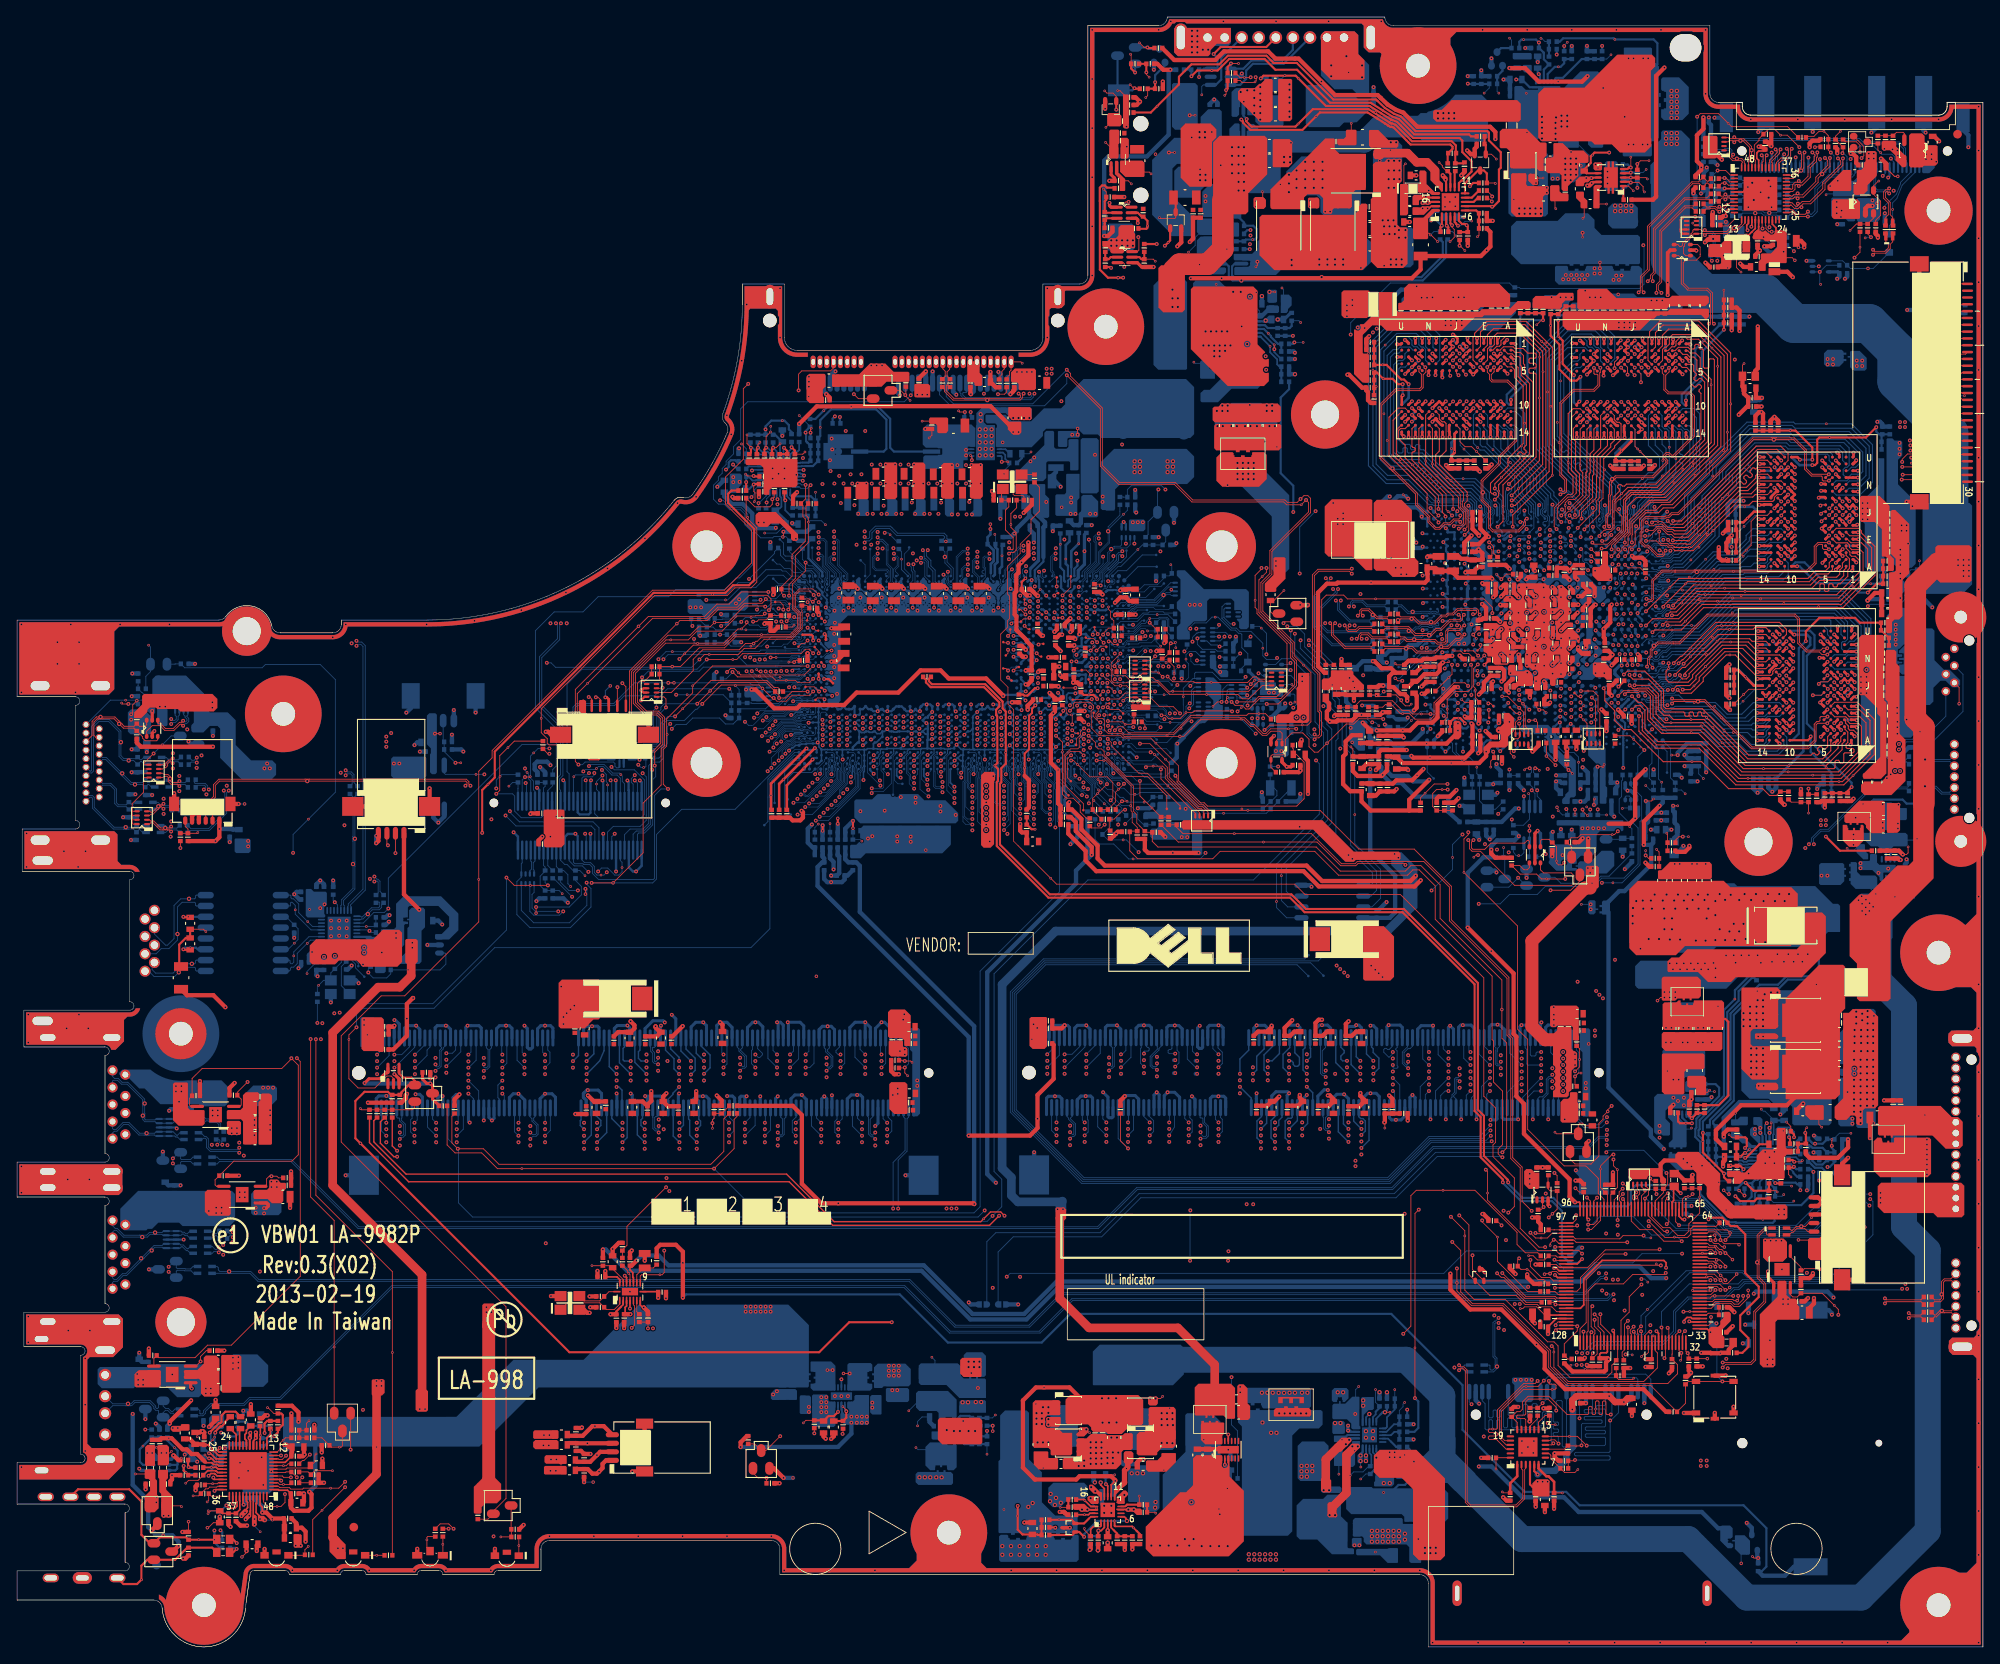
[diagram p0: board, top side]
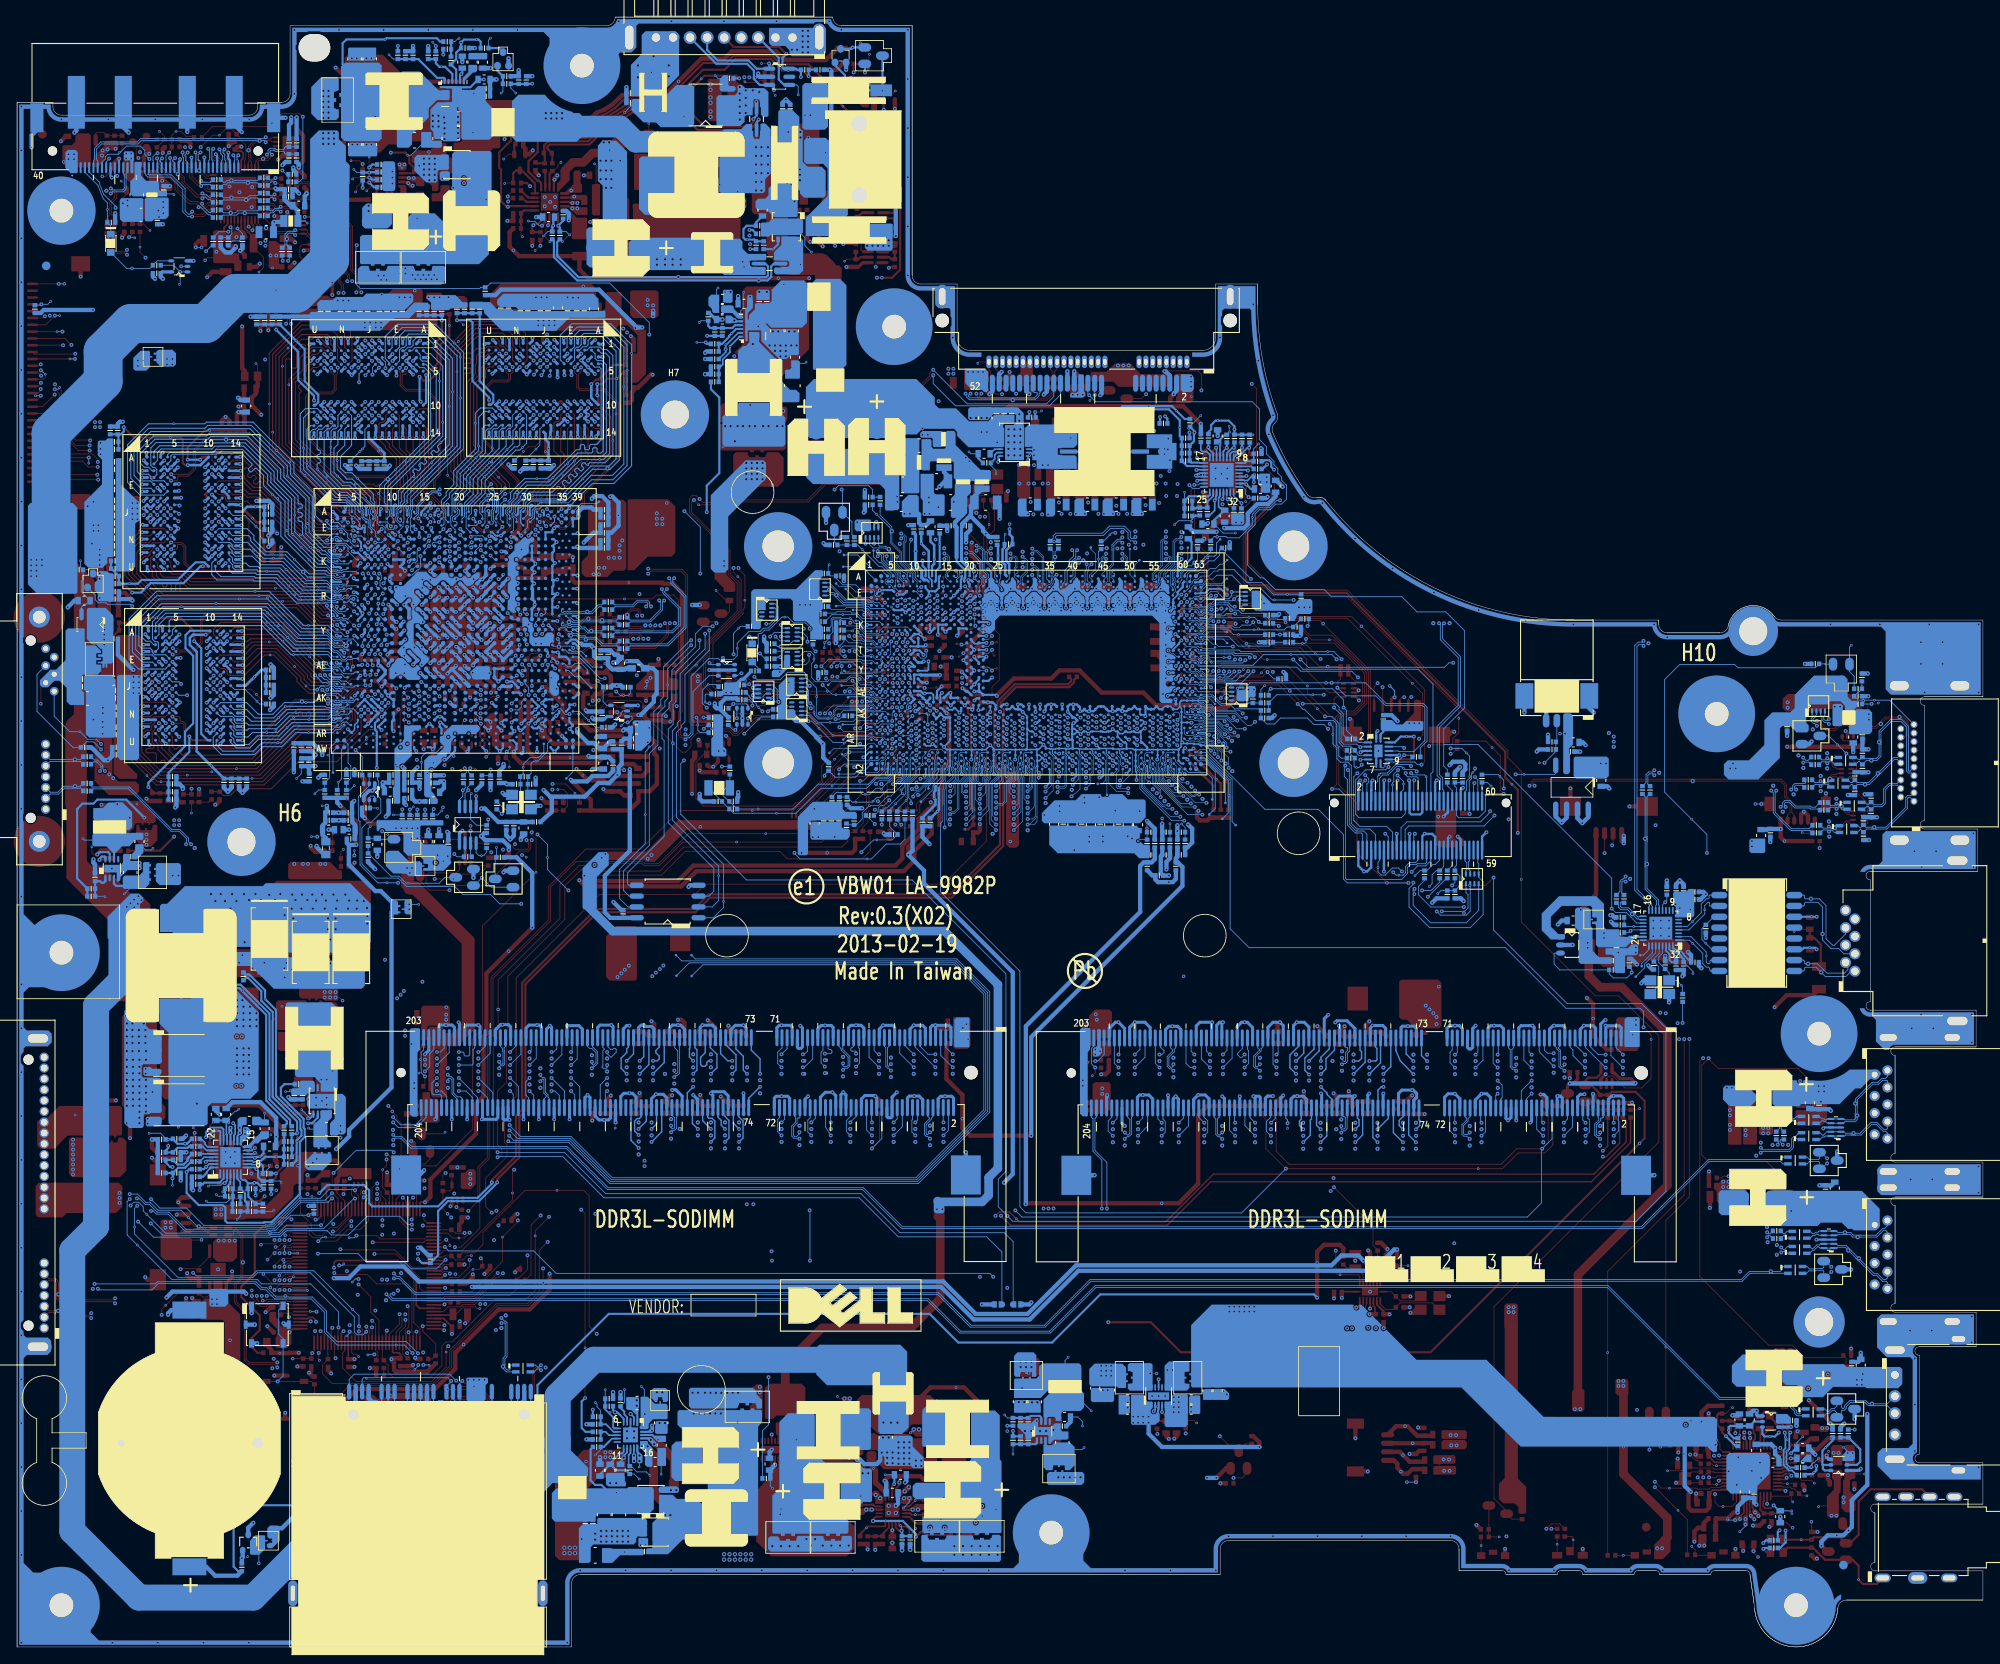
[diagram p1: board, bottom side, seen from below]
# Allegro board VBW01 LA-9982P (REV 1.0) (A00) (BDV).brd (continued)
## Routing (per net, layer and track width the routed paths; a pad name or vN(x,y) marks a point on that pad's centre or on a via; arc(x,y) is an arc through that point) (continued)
CASB0#: length 37.9
  TOP w0.102: UV7.G3 213.14,131.93 v1(213.14,131.93)
  IN3 w0.102: v1(213.14,131.93) 213.38,131.93 214.66,130.65 214.66,127.33 214.09,126.75 214.09,125.95 ; v1(188.31,121.12) 188.78,121.59 190.09,121.59 190.31,121.37 190.31,121.19 190.54,120.96 191.17,120.96 191.45,121.24 192.76,121.24 193.17,121.65 194.21,121.65 194.39,121.83
  IN3 w0.157: 214.09,125.95 211.17,123.04 202.11,123.04 200.98,121.91 194.47,121.91 194.39,121.83
  BOTTOM w0.102: UV1.W10 187.49,120.49 188.12,121.12 v1(188.31,121.12) ; v1(213.14,131.93) 213.56,131.51 UV7.G3
CASB1#: length 35
  TOP w0.102: v1(212.95,111.53) 213.37,111.11 UV9.G3
  IN3 w0.102: v1(187.7,117.47) 187.7,118.34 188.5,119.14 190.24,119.14 190.45,118.93 191.05,118.93 191.93,118.05 193.13,118.05 193.33,118.25 194.39,118.25 ; v1(212.95,111.53) 212.58,111.9 211.97,111.9 211.8,112.06 211.8,112.9 210,114.7 210,116.98 209.22,117.76 209.22,118.37 208.09,119.49 203.47,119.49
  IN3 w0.157: 194.39,118.25 202.23,118.25 203.47,119.49
  BOTTOM w0.102: v1(187.7,117.47) 187.66,117.52 187.66,117.7 UV1.AA10 ; v1(212.95,111.53) 213.37,111.11 UV9.G3
CE_EN: length 178.4
  TOP w0.102: UE1.17 189.59,36.85 v1(189.47,36.97) ; RX18.1 210.75,175.88 v1(210.71,175.84)
  IN2 w0.127: v1(216.31,51.74) 216.77,52.2 216.77,53.56 222.15,58.94 222.15,71.62 228.05,77.51 228.05,85.64 225.06,88.63 225.06,96.24 225.6,96.78 225.6,109.42 224.18,110.84 224.18,121.01 225.08,121.91 225.08,145.93 216.03,154.98 216.03,164.75 214.41,166.37 214.41,175.33 213.9,175.84 v1(210.71,175.84)
  BOTTOM w0.102: v1(216.31,51.74) 216.63,51.42 v3(216.63,49.22) 216.63,48.42 211.5,43.29 202.78,43.29 202.2,43.88 196.04,43.88 190.88,38.72 190.88,36.93 190.54,36.6 189.84,36.6 v1(189.47,36.97)
CE_EN_R: length 7.2
  TOP w0.102: v1(212.58,175.21) 212.27,175.51 RX18.2 RX20.1 212.27,177.2 v3(211.76,177.71) 211.19,177.71 210.59,177.11 209.78,177.11 RX53.2
  BOTTOM w0.102: v1(212.58,175.21) 212.95,174.83 JLVDS.18
CFD_PWRBTN#_XDP: length 5.2
  BOTTOM w0.102: v3(64.88,89.16) 64.55,89.49 64.55,90.54 64.06,91.03 RC49.2 63.2,91.5 JXDP1.41
CFG0: length 38.1
  IN3 w0.127: v1(76.55,108.23) 77.37,108.23 78.52,109.38 81.15,109.38 82.3,110.54 89.16,110.54 90.48,111.86 v1(90.48,112.52)
  BOTTOM w0.076: UC1.AC60 93.31,112.81 92.83,112.81 92.79,112.84 92,112.84 91.84,112.68 91.46,112.68 91.22,112.91 90.87,112.91 v1(90.48,112.52)
  BOTTOM w0.102: JXDP1.9 71.2,95.25 71.85,95.9 73.36,95.9 74.03,96.57 74.03,103.35 74.43,103.74 75.3,103.74 75.72,104.17 75.72,105.42 76.19,105.89 v3(76.19,106.99) 76.19,107.87 v1(76.55,108.23)
CFG1: length 48.4
  IN3 w0.127: v1(85.5,114.4) 85.37,114.27 84.41,114.27 82.7,112.56 79.12,112.56 77.78,111.22 75.41,111.22 73.15,108.96 73.15,108.16 71.86,106.87 71.86,102.9 71.11,102.14 71.11,99.78 68.17,96.85 68.17,91 v1(68.1,90.93)
  BOTTOM w0.076: UC1.AC62 92.06,113.14 91.77,112.84 91.53,112.84 91.29,113.08 90.46,113.08 90.41,113.03 88.91,113.03
  BOTTOM w0.102: JXDP1.11 70.7,92.21 70.9,92 v3(70.9,91.38) 70.9,90.89 70.51,90.5 70.06,90.5 69.23,91.32 68.5,91.32 v1(68.1,90.93) ; v1(85.5,114.4) 85.53,114.4 86.9,113.03 88.91,113.03
CFG2: length 38.3
  IN3 w0.127: v1(86.11,114.41) 85.66,113.97 84.48,113.97 82.82,112.3 79.23,112.3 77.88,110.95 75.75,110.95 75.37,110.56 75.37,109.89 74.71,109.23 74.01,109.23 73.41,108.63 73.41,108.05 72.13,106.76 72.13,102.79 71.97,102.63 71.97,100.28 70.05,98.35 v1(70.05,95.34)
  BOTTOM w0.076: UC1.AC63 91.54,113.25 90.05,113.25 90.04,113.24 89.11,113.24 89.1,113.25 88.93,113.25 88.91,113.26
  BOTTOM w0.102: v1(86.11,114.41) 86.12,114.41 86.71,113.83 v3(86.99,113.83) 87.56,113.26 88.91,113.26 ; JXDP1.15 69.7,95 v1(70.05,95.34)
CFG3: length 61.6
  IN1 w0.127: v1(56.16,100.66) 56.35,100.85 59.85,100.85 60.78,101.78 63.43,101.78 63.9,102.25 65.37,102.25 66.83,103.71 71.32,103.71 72.21,102.82 72.94,102.82 v1(73.32,102.44)
  IN3 w0.127: v1(73.32,102.44) 73.49,102.62 73.49,103.6 74.11,104.22 74.11,107.19 77.09,110.17 78.21,110.17 79.39,111.35 83.9,111.35 85.44,112.89 86.94,112.89 88.32,114.27 v1(88.32,114.37)
  BOTTOM w0.076: UC1.AA63 91.52,113.76 91.39,113.76 91.37,113.74 89.87,113.74 89.62,113.99 89.04,113.99
  BOTTOM w0.102: 89.04,113.99 89.02,113.99 88.94,113.99 88.91,113.97 88.91,113.97 88.72,113.97 v1(88.32,114.37) ; JXDP1.17 69.2,95.54 69.88,96.21 73.03,96.21 73.74,96.92 73.74,97.53 73.75,97.54 73.75,102.01 v1(73.32,102.44) ; RC56.2 56.8,102.27 v3(56.61,102.08) 56.16,101.64 v1(56.16,100.66)
CFG3_R: length 3.5
  BOTTOM w0.102: JXDP1.60 58.7,100.65 58.71,100.66 RC56.1 58.07,101.36 v3(57.65,100.93)
CFG4: length 44
  TOP w0.089: v1(93.3,113.51) 92.85,113.06 91.5,113.06 91.22,113.33 v3(90.15,113.33) 88.91,113.33
  TOP w0.102: v1(83.85,114.31) 83.87,114.31 84.45,113.73 88.51,113.73 88.91,113.33
  IN3 w0.127: v1(66.57,95.34) 66.57,95.99 70.58,100 70.58,102.35 71.34,103.11 71.34,107.09 71.49,107.24 71.49,108.17 73.24,109.92 73.39,109.92 75.26,111.78 76.41,111.78 77.45,112.83 82.36,112.83 v1(83.85,114.31)
  BOTTOM w0.089: UC1.AA60 93.6,113.81 v1(93.3,113.51)
  BOTTOM w0.102: RC138.1 83.1,113.5 83.85,114.25 v1(83.85,114.31) ; v1(66.57,95.34) 66.7,95.22 JXDP1.27
CFG5: length 44.9
  IN3 w0.127: v1(69.12,90.84) 69.76,91.48 69.76,93.21 70.96,94.41 70.96,98.53 74.01,101.58 74.01,103.41 74.64,104.03 74.64,106.92 76.38,108.66 77.43,108.66 78.41,109.65 81.04,109.65 82.18,110.79 86.57,110.79 v1(90.21,114.43)
  BOTTOM w0.076: UC1.Y62 92.06,114.63 91.77,114.34 91.46,114.34 91.19,114.07 90.5,114.07 90.21,114.37 v1(90.21,114.43)
  BOTTOM w0.102: v1(69.12,90.84) 68.78,90.5 v3(68.44,90.5) 67.95,90.5 67.66,90.8 67.66,91.51 67.21,91.96 66.51,91.96 66.2,92.27 JXDP1.29
CFG6: length 52.6
  TOP w0.089: v1(92.65,115.01) 88.91,115.01
  TOP w0.102: v1(76.29,100.59) 75.73,101.15 75.73,105.23 76.13,105.63 76.13,108.82 79.18,111.86 v3(79.18,112.69) 81.5,115.01 88.91,115.01
  BOTTOM w0.076: UC1.Y61 92.95,114.71 v1(92.65,115.01)
  BOTTOM w0.102: JXDP1.33 65.2,92.01 65.38,91.83 66.32,91.83 66.42,91.73 67.12,91.73 67.43,91.42 67.43,90.7 68.14,89.99 74.58,89.99 74.72,90.13 74.72,99.85 75.47,100.59 v1(76.29,100.59)
CFG7: length 47.7
  IN3 w0.127: v1(89.56,114.43) 89.56,114.37 86.26,111.07 79.48,111.07 78.32,109.91 77.21,109.91 74.37,107.07 74.37,104.13 73.75,103.5 73.75,101.69 70.64,98.58 70.64,94.46 68.55,92.36 68.55,90.75 68.23,90.43 67.21,90.43 66.96,90.69 v1(66.96,90.88)
  BOTTOM w0.076: UC1.Y60 93.31,114.3 92.83,114.3 92.79,114.34 92,114.34 91.84,114.18 91.53,114.18 91.26,113.91 90.02,113.91 89.56,114.37 v1(89.56,114.43)
  BOTTOM w0.102: JXDP1.35 64.7,92.18 65.31,91.58 66.25,91.58 66.95,90.88 v1(66.96,90.88)
CFG8: length 40.4
  IN3 w0.127: v1(67.03,103.29) 67.41,103.67 67.41,106.13 68.19,106.9 68.19,108.82 73.04,113.68 v1(73.24,113.68)
  BOTTOM w0.076: 89.1,114.88 89.6,114.88 89.65,114.93 91.84,114.93 UC1.V62
  BOTTOM w0.102: JXDP1.10 71.2,101.21 70.93,101.48 70.93,102.11 v3(70.76,102.28) 70.58,102.46 69.81,102.46 68.81,103.46 67.2,103.46 v1(67.03,103.29) ; v1(73.24,113.68) 73.97,114.4 79.94,114.4 80.42,114.88 89.1,114.88
CFG9: length 43.9
  IN3 w0.127: v1(66.37,102.65) 66.61,102.89 66.61,103.62 67.15,104.17 67.15,106.24 67.92,107.01 67.92,109.02 74.29,115.39 75.34,115.39 75.75,115.8 v1(75.75,115.8)
  BOTTOM w0.076: 89.3,115.11 89.31,115.09 91.77,115.09 91.94,115.26 91.94,115.44 92.18,115.68 92.7,115.68 UC1.V61
  BOTTOM w0.102: 89.3,115.11 85.55,115.11 84.31,116.34 76.29,116.34 v1(75.75,115.8) ; JXDP1.12 70.7,101.86 70.33,102.23 69.71,102.23 68.71,103.23 68.14,103.23 v3(67.9,102.99) 67.79,102.88 66.59,102.88 v1(66.37,102.65)
CFG10: length 35.9
  TOP w0.089: 88.91,113.96 92.25,113.96 v1(93.3,115.01)
  TOP w0.102: 88.91,113.96 84.82,113.96 v3(84.57,114.22) 84.06,114.72 83.62,114.72 v1(83.21,114.31)
  IN3 w0.127: v1(83.21,114.31) 81.99,113.09 77.34,113.09 76.3,112.04 75.16,112.04 73.29,110.17 73.13,110.17 70.16,107.2 70.16,103.08 69.57,102.48 v1(69.57,101.61)
  BOTTOM w0.076: v1(93.3,115.01) 93.6,115.31 UC1.V60
  BOTTOM w0.102: v1(69.57,101.61) 69.7,101.48 JXDP1.16
CFG11: length 38.1
  IN3 w0.127: v1(68.55,102.82) 68.55,103.03 69.38,103.86 69.38,107.88 70.18,108.68 70.18,109.7 72.18,111.71 73.35,111.71 76.19,114.55 81.19,114.55 81.92,115.29 84.87,115.29 84.95,115.36 86.09,115.36 v1(86.44,115.71)
  BOTTOM w0.076: UC1.U60 93.31,115.8 92.83,115.8 92.79,115.84 92,115.84 91.84,115.68 91.46,115.68 91.25,115.89 90.93,115.89 90.4,115.36 89.3,115.36
  BOTTOM w0.102: v1(68.55,102.82) 68.55,102.82 69.05,102.31 69.05,101.45 69.2,101.3 v3(69.2,101.07) JXDP1.18 ; 89.3,115.36 86.79,115.36 v1(86.44,115.71)
CFG12: length 38.2
  IN3 w0.127: v1(66.64,101.61) 66.64,101.78 65.94,102.48 65.94,103.01 66.23,103.29 66.23,103.61 66.89,104.28 66.89,106.34 67.66,107.12 67.66,109.13 74.35,115.81 v1(75.17,115.81)
  BOTTOM w0.076: UC1.T63 90.09,116.88
  BOTTOM w0.089: 90.09,116.88 88.91,116.88
  BOTTOM w0.102: JXDP1.28 66.7,101.55 v1(66.64,101.61) ; v1(75.17,115.81) 76.06,116.7 v3(76.8,116.7) 86.98,116.7 87.17,116.88 88.91,116.88
CFG13: length 38.1
  IN3 w0.127: v1(85.92,116.01) 85.53,115.62 84.84,115.62 84.76,115.55 81.81,115.55 81.08,114.81 75.34,114.81 73.41,112.88 72.99,112.88 69.75,109.65 69.75,108.62 69.11,107.99 69.11,103.99 67.65,102.53 v1(67.65,102.47)
  BOTTOM w0.076: 89.22,116.42 91.84,116.42 91.85,116.44 91.85,116.44 UC1.T62
  BOTTOM w0.089: 88.91,116.43 89.22,116.43
  BOTTOM w0.102: v1(85.92,116.01) 86.13,116.22 87.76,116.22 87.96,116.43 88.91,116.43 ; JXDP1.30 66.2,101.86 66.36,102.02 67.42,102.02 67.65,102.25 v1(67.65,102.47)
CFG14: length 40
  IN3 w0.127: v1(67.03,102.47) 67.03,102.53 68.85,104.35 68.85,108.09 69.49,108.73 69.49,109.76 72.88,113.14 73.31,113.14 75.24,115.07 80.97,115.07 81.71,115.81 84.65,115.81 84.89,116.05 v1(85.32,116.05)
  BOTTOM w0.076: UC1.T61 92.7,117.17 92.18,117.17 91.94,116.94 91.94,116.76 91.77,116.59 90.75,116.59 90.69,116.65 90.07,116.65
  BOTTOM w0.089: 88.91,116.65 90.07,116.65
  BOTTOM w0.102: JXDP1.34 65.2,101.99 65.25,102.04 ; v1(67.03,102.47) 66.81,102.25 65.46,102.25 65.25,102.04 ; 65.25,102.04 v3(65.25,102.04) ; v1(85.32,116.05) 85.74,116.46 87.62,116.46 87.81,116.65 88.91,116.65
CFG15: length 45.1
  TOP w0.089: v1(93.3,116.51) 92.83,116.98 92.39,116.98 91.87,116.46 88.91,116.46
  TOP w0.102: 88.91,116.46 85.03,116.46 84.35,115.78 84.16,115.78 84.16,115.78 83.89,115.78 v3(83.88,115.78) v1(80.83,115.78)
  BOTTOM w0.076: UC1.T60 93.6,116.81 v1(93.3,116.51)
  BOTTOM w0.102: v1(80.83,115.78) 79.68,114.63 66.2,114.63 64.46,112.89 64.46,102.62 64.7,102.37 JXDP1.36
CFG16: length 32.4
  TOP w0.102: v1(87.15,114.37) 86.9,114.37 v3(86.68,114.59)
  IN3 w0.127: v1(72.4,102.22) 72.4,102.52 72.39,102.53 72.39,106.29 75.63,109.53 75.63,110.47 75.85,110.69 77.99,110.69 79.21,111.91 83.7,111.91 85.2,113.41 86.25,113.41 87.15,114.31 v1(87.15,114.37)
  BOTTOM w0.076: 88.91,113.5 89.11,113.5 89.19,113.41 89.27,113.41 89.28,113.4 89.95,113.4 89.96,113.41 91.51,113.41 91.53,113.43 91.84,113.43 92.24,113.83 92.24,113.83 UC1.AA62
  BOTTOM w0.102: v1(87.15,114.37) 87.15,114.31 87.96,113.5 88.02,113.5 88.03,113.5 88.91,113.5 ; JXDP1.6 72.2,101.17 71.99,101.38 71.99,101.81 v1(72.4,102.22)
CFG17: length 31.7
  IN3 w0.127: v1(72.4,101.6) 72.82,102.02 72.82,102.66 73.23,103.07 73.23,103.7 73.69,104.16 73.69,107.16 76.96,110.43 78.1,110.43 79.28,111.61 83.77,111.61 85.31,113.15 86.56,113.15 87.74,114.32 v1(87.74,114.37)
  BOTTOM w0.076: UC1.AA61 92.7,114.18 92.18,114.18 92.01,114.01 92.01,113.83 91.77,113.59 91.46,113.59 91.44,113.58 89.74,113.58 89.62,113.69 v3(89.42,113.69) 88.95,113.69 88.91,113.73
  BOTTOM w0.102: 88.91,113.73 88.36,113.73 87.74,114.36 87.74,114.37 v1(87.74,114.37) ; v1(72.4,101.6) 72.7,101.29 JXDP1.4
CFG18: length 46.8
  TOP w0.089: v3(88.95,116.01) 88.91,116.01
  TOP w0.102: 88.91,116.01 v1(88.32,116.01)
  IN3 w0.127: v1(69.66,103.18) 69.9,103.41 69.9,107.3 73.03,110.42 73.18,110.42 74.73,111.98 74.73,112.35 75.89,113.51 81.78,113.51 83.03,114.76 85.09,114.76 85.16,114.84 86.51,114.84 86.76,115.09 87.56,115.09 88.32,115.85 v1(88.32,116.01)
  BOTTOM w0.076: 88.91,116.01 90.59,116.01 90.79,116.22 91.56,116.22 UC1.U63
  BOTTOM w0.102: v1(69.66,103.18) 70,102.84 72.34,102.84 73.52,101.67 73.52,97.63 73.12,97.23 68.16,97.23 67.7,97.69 JXDP1.24 ; v1(88.32,116.01) 88.91,116.01
CFG19: length 36.5
  IN3 w0.127: v1(68.61,102.18) 68.61,102.18 68.97,102.54 68.97,103.08 69.64,103.75 69.64,107.77 70.44,108.57 70.44,109.6 72.29,111.45 73.47,111.45 76.31,114.29 81.3,114.29 82.03,115.02 84.98,115.02 85.05,115.1 86.42,115.1 86.66,115.34 87.2,115.34 v1(87.65,115.78)
  BOTTOM w0.076: 89.62,115.59 90.4,115.59 90.86,116.05 91.32,116.05 91.53,115.84 91.77,115.84 92.06,116.13 UC1.U62
  BOTTOM w0.102: v1(87.65,115.78) 87.84,115.59 89.62,115.59 ; v1(68.61,102.18) 67.91,101.47 v3(67.91,101.17) 67.91,100.54 68.2,100.25 JXDP1.22
CFG_RCOMP: length 2
  TOP w0.089: v3(90.45,115.47) v1(91.07,115.47) 91.27,115.66 RC132.1
  BOTTOM w0.089: UC1.V63 91.16,115.38 v1(91.07,115.47)
CHG_B+:
  vias: v2(149.38,162.63) v2(149.38,162) v2(152.62,162.7) v2(152.62,162.06) v2(153.57,162.7) v2(153.57,162.06) v2(154.46,162.7) v2(154.46,162.06) v2(155.41,162.7) v2(155.41,162.06) v4(157.49,161.69)
CKEA0: length 35.6
  TOP w0.102: UV5.J3 v1(168.28,150.85)
  IN3 w0.102: v1(177.26,127.58) 177.8,128.13 177.8,130.47 177.52,130.75 177.52,131.72 177.73,131.92 177.73,134.85 178.06,135.18 178.06,135.39 ; 172.73,152.06 171.89,151.22 170.91,151.22 170.13,150.45 169.7,150.45 169.68,150.47 168.67,150.47 v1(168.28,150.85)
  IN3 w0.157: 178.06,135.39 178.06,148.86 175.46,151.46 174.66,151.46 174.06,152.06 172.73,152.06
  BOTTOM w0.102: UV5.J3 v1(168.28,150.85) ; UV1.K21 177.35,127.49 v1(177.26,127.58)
CKEA1: length 32.3
  TOP w0.102: UV3.J3 189.19,151.18 v1(188.79,150.79)
  IN3 w0.102: 179.75,135.39 179.75,135.25 179.74,135.24 179.74,135.18 179.45,134.9 179.39,134.9 178.98,134.48 178.98,133.59 178.84,133.45 178.84,130.07 178.72,129.95 178.51,129.95 178.21,129.65 178.21,129.13 v1(178.59,128.74) ; v1(188.79,150.79) 188.38,151.2 183.29,151.2 182.13,150.04
  IN3 w0.157: 182.13,150.04 179.75,147.66 179.75,135.39
  BOTTOM w0.102: UV1.J20 179.05,128.29 v1(178.59,128.74) ; v1(188.79,150.79) 189.19,151.18 UV3.J3
CKEB0: length 37.9
  TOP w0.102: UV7.J3 v1(213.16,133.51)
  IN3 w0.102: 213.58,126.14 213.58,127.75 213.58,127.75 213.58,128.07 213.58,128.07 213.58,128.55 213.58,128.55 213.58,130.9 212.69,131.79 212.69,132.17 212.78,132.26 212.78,133.13 v1(213.16,133.51) ; 191.23,121.8 190.75,121.8 190.74,121.8 188.17,121.8 v1(187.48,121.11)
  IN3 w0.157: 213.58,126.14 211.17,123.73 202.11,123.73 200.9,122.52 191.95,122.52 191.23,121.8
  BOTTOM w0.102: v1(187.48,121.11) 187.26,121.32 UV1.U10 ; UV7.J3 v1(213.16,133.51)
CKEB1: length 35.2
  TOP w0.102: UV9.J3 213.37,112.71 v1(212.97,113.11)
  IN3 w0.102: v1(212.97,113.11) 212.45,113.11 210.66,114.9 210.66,119.57 210.45,119.78 ; 194.39,119.72 194.06,119.72 193.61,120.17 193.08,120.17 193.06,120.19 193.06,120.19 192.89,120.36 191.72,120.36 191.5,120.15 190.48,120.15 190.48,120.15 188.97,120.15 188.75,119.93 188.75,119.71 187.73,118.69 v1(187.08,118.69)
  IN3 w0.157: 194.39,119.72 201.59,119.72 202.86,120.98 209.25,120.98 210.45,119.78
  BOTTOM w0.102: UV9.J3 213.37,112.71 v1(212.97,113.11) ; UV1.AA11 v1(187.08,118.69)
CLK_BIASREF: length 5.7
  BOTTOM w0.089: UC1.C26 115,124.18 115.11,124.29 115.12,124.29 115.3,124.46 115.3,124.47 115.33,124.51 115.33,124.68 115.27,124.74 115.27,125.13 115.16,125.24 115.16,125.89 115.18,125.9
  BOTTOM w0.305: 115.18,125.9 115.18,126.42 115.43,126.68 v3(115.43,127.94) 115.43,129.12 RC13.1
CLK_CPU_ITP: length 3.7
  BOTTOM w0.089: UC1.A35 109.47,125.61 109.47,126.37 108.74,127.1 v2(108.74,127.8) 108.74,128.39 RC139.2
CLK_CPU_ITP#: length 4.4
  BOTTOM w0.089: RC140.2 108.99,128.46 108.99,127.2 109.72,126.48 109.72,125.21 UC1.B35
CLK_PCI_LPC: length 110.1
  TOP w0.089: v1(127.46,96.42) 127.07,96.02 125.94,96.02 R2336.1
  TOP w0.102: UE1.12 187.59,33.78 R2354.2 187.42,33.54 186.91,33.03 186.91,32.21 186.31,31.61 182,31.61 180.61,32.99 180.61,35.29 180.13,35.77 179.38,35.77 174.43,40.73 170.78,40.73 169.68,41.83 v3(169.68,48.19) 169.68,48.8 v1(168.05,50.43)
  IN1 w0.084: 130.78,95.3 130.6,95.48 130.19,95.48 129.45,96.21 129.45,96.6 129.26,96.79 127.83,96.79 v1(127.46,96.42)
  IN1 w0.127: v1(168.05,50.43) 168.05,51 168.42,51.37 168.42,69.8 167.91,70.31 157.51,70.31 153.71,74.1 151.97,74.1 130.78,95.3
CLK_PCIE_LAN: length 112.3
  IN1 w0.127: v1(39.78,117.38) 39.98,117.57 41.53,117.57 42.63,118.68 59.87,118.68 60.32,119.14 66.36,119.14 79.48,132.26 91.23,132.26 91.71,132.74 95.6,132.74 97.5,130.84 97.5,128.47 99.32,126.65 103.46,126.65 104.27,127.46 104.51,127.46 104.64,127.33 104.64,127.12 v1(104.47,126.95)
  BOTTOM w0.089: UC1.B42 104.99,124.56 104.99,124.3 104.93,124.23 104.86,124.23 104.58,124.51 104.58,124.62 104.98,125.03 104.98,126.02 104.8,126.19 104.8,126.61 v1(104.47,126.95)
  BOTTOM w0.102: v1(39.78,117.38) 39.95,117.55 40.29,117.55 40.54,117.3 40.54,88.84 38.81,87.12 38.81,86.88 38.75,86.82 UL1.15
CLK_PCIE_LAN#: length 112.4
  IN1 w0.127: v1(39.78,117.96) 39.84,117.9 41.39,117.9 42.5,119.01 59.73,119.01 60.19,119.47 66.22,119.47 79.34,132.59 91.09,132.59 91.57,133.07 95.74,133.07 97.83,130.97 97.83,128.61 99.45,126.99 103.33,126.99 104.14,127.79 104.65,127.79 104.99,127.45 104.99,127 v1(105.05,126.95)
  BOTTOM w0.089: v1(105.05,126.95) 105.06,126.94 105.06,126.3 105.24,126.12 105.24,124.74 105.27,124.71 105.27,124.53 UC1.C41
  BOTTOM w0.102: UL1.16 39.15,86.82 39.08,86.88 39.08,87.01 40.81,88.73 40.81,117.41 40.4,117.82 39.93,117.82 v1(39.78,117.96)
CLK_PCIE_WLAN: length 55.2
  IN3 w0.114: JMINI.13 98.1,149.64 97.81,149.35 97.81,148.63 98.36,148.08 113.32,148.08 114.31,147.08 114.31,146.73 116.22,144.82 119.13,144.82 119.88,144.07 119.88,139.15 113.98,133.24 113.98,131.73 111.46,129.21 106.79,129.21 106.51,128.93 106.51,128.84 106.74,128.61 v1(106.74,128.6)
  BOTTOM w0.102: v1(106.74,128.6) 106.58,128.44 106.58,127.98 106.59,127.97 106.59,127.89 107.1,127.39 107.1,126.75 107.6,126.25 107.6,124.92 107.85,124.66 107.85,124.45 UC1.C37
CLK_PCIE_WLAN#: length 54.8
  IN3 w0.114: JMINI.11 97.3,149.78 97.56,149.52 97.56,148.52 98.25,147.82 113.21,147.82 114.06,146.98 114.06,146.62 116.11,144.57 119.03,144.57 119.63,143.97 119.63,139.25 113.73,133.35 113.73,131.84 111.35,129.46 106.68,129.46 106.25,129.03 106.25,128.7 v1(106.16,128.6)
  BOTTOM w0.102: UC1.B38 107.33,124.73 107.33,126.14 106.83,126.64 106.83,127.28 106.47,127.64 106.32,127.64 106.32,127.86 106.32,127.87 106.32,128.44 v1(106.16,128.6)
CLK_PEG_VGA: length 74
  IN1 w0.127: v1(167.03,118.18) 166.99,118.14 161.49,118.14 156.46,123.17 153.97,123.17 144.36,132.78 138.94,132.78 136.98,130.82 129.17,130.82 127.93,132.05 118.54,132.05 118.1,131.61 115.74,131.61 114.28,130.15 110.64,130.15 109.34,128.84 108.18,128.84 106.5,127.16 105.99,127.16 v1(105.94,127.12)
  BOTTOM w0.089: UC1.B39 106.91,124.98 106.39,125.51 106.39,127.1 106.29,127.2 106.02,127.2 v1(105.94,127.12)
  BOTTOM w0.102: UV1.AB35 166.86,118.01 v1(167.03,118.18)
CLK_PEG_VGA#: length 73.9
  IN1 w0.127: v1(105.94,127.7) 106.15,127.49 106.37,127.49 108.04,129.17 109.2,129.17 110.51,130.48 114.14,130.48 115.6,131.94 117.96,131.94 118.41,132.38 128.07,132.38 129.3,131.15 136.85,131.15 138.8,133.11 144.5,133.11 154.11,123.5 156.6,123.5 161.63,118.47 166.63,118.47 v1(166.9,118.75)
  BOTTOM w0.089: v1(105.94,127.7) 106.19,127.46 106.39,127.46 106.65,127.2 106.65,125.61 106.7,125.56 UC1.A39
  BOTTOM w0.102: v1(166.9,118.75) 166.65,118.49 UV1.AA36
CLK_SMB: length 15
  TOP w0.102: v1(141.7,182.54) 141.7,182.07 v3(141.54,181.92)
  TOP w0.254: v1(141.7,182.54) 141.88,182.72 PR18.1
  BOTTOM w0.254: PBATT.7 151.52,188.7 148.44,185.62 144.84,185.62 144.05,184.83 144.05,183.84 143.35,183.15 PD1.3 141.95,183.15 141.7,182.89 v1(141.7,182.54)
CLK_X1: length 8.3
  TOP w0.102: UG1.1 70.63,40.2 70.01,39.57 69.07,39.57 CG8.1 68.29,40.35 64.51,40.35 YG1.1
CLK_X2: length 5.1
  TOP w0.102: UG1.16 69.37,41.65 CG9.1 68.29,40.57 66.46,40.57 YG1.3
CLK_XDP: length 78.6
  IN1 w0.127: v1(63.74,120.03) 63.59,120.18 63.59,120.44 63.82,120.66 66.51,120.66 78.96,133.11 90.89,133.11 91.47,133.68 95.85,133.68 98.38,131.15 98.38,130.01 98.68,129.7 99.13,129.7 v1(99.34,129.49)
  BOTTOM w0.102: JXDP1.40 63.7,100.43 63.58,100.55 63.58,101.78 63.97,102.16 63.97,107.94 61.5,110.41 61.5,116 63.59,118.1 63.59,119.87 v1(63.74,120.03) ; RC139.1 108.71,130.04 108.71,130.16 108.55,130.31 103.09,130.31 102.26,131.14 100.7,131.14 100.19,130.64 100.19,129.98 99.89,129.68 99.52,129.68 v1(99.34,129.49)
CLK_XDP#: length 79.6
  IN1 w0.127: v1(99.34,130.14) 99.23,130.03 98.82,130.03 98.71,130.14 98.71,131.29 95.99,134.01 91.33,134.01 90.76,133.44 78.82,133.44 66.37,120.99 63.68,120.99 63.26,120.57 63.26,120.13 v1(63.16,120.03)
  BOTTOM w0.102: v1(63.16,120.03) 63.33,119.86 63.33,118.21 61.23,116.11 61.23,110.3 63.7,107.83 63.7,102.27 63.32,101.89 63.32,100.55 63.2,100.43 JXDP1.42 ; RC140.1 109.25,129.69 108.98,129.96 108.98,130.27 108.66,130.58 103.2,130.58 102.53,131.25 102.37,131.4 100.59,131.4 99.93,130.75 99.93,130.09 99.78,129.94 99.53,129.94 v1(99.34,130.14)
CLKA0: length 33.8
  TOP w0.102: UV5.J12 168.68,144.05 v1(168.28,144.45) ; v1(172.54,128.94) 172.85,128.62 172.85,128.01 RV42.2
  IN3 w0.14: v1(168.28,144.45) 168.44,144.29 168.44,144.12 168.9,143.67 168.9,142.63 168.68,142.42 168.68,142.1 168.01,141.43 165.15,141.43 164.77,141.05 164.77,140.54 164.68,140.44 163.26,140.44 162.98,140.17 162.98,139.51 163.26,139.24 164.7,139.24 164.83,139.11 164.83,138.66 164.7,138.54 163.25,138.54 162.97,138.26 162.97,137.61 163.25,137.33 164.55,137.33 164.77,137.11 164.77,134.88 165.66,134 168.9,134 171.8,131.1 171.8,129.45 172.07,129.17 172.3,129.17 172.54,128.94 v1(172.54,128.94)
  BOTTOM w0.102: UV1.H27 172.91,128.94 172.55,128.94 172.55,128.94 v1(172.54,128.94) ; UV5.J12 168.68,144.05 v1(168.28,144.45)
CLKA0#: length 34.8
  TOP w0.102: v1(169.14,144.45) 169.08,144.45 UV5.J11 ; v1(172.52,129.52) 173.05,128.99 173.05,128.24 RV43.2
  IN3 w0.14: v1(172.52,129.52) 172.42,129.42 172.18,129.42 172.05,129.55 172.05,131.2 169,134.25 165.76,134.25 165.02,134.99 165.02,137.21 164.65,137.59 163.35,137.59 163.22,137.71 163.22,138.16 163.35,138.28 164.81,138.28 165.08,138.56 165.08,139.21 164.81,139.49 163.36,139.49 163.24,139.62 163.24,140.06 163.36,140.19 164.78,140.19 165.02,140.43 165.02,140.94 165.25,141.17 168.12,141.17 168.94,141.99 168.94,142.31 169.15,142.52 169.15,143.78 168.7,144.23 168.7,144.44 168.83,144.58 168.95,144.58 169.08,144.45 v1(169.14,144.45)
  BOTTOM w0.102: v1(172.52,129.52) 172.69,129.52 UV1.G27 ; UV5.J11 169.08,144.45 v1(169.14,144.45)
CLKA1: length 31.3
  TOP w0.102: v1(189.65,144.39) 189.6,144.39 UV3.J12 ; RV44.2 185.13,127.26 v1(184.5,127.9)
  IN3 w0.14: v1(184.5,127.9) 184.67,128.08 186.04,128.08 186.48,128.52 186.48,128.86 186.77,129.16 186.77,129.16 186.92,129.3 187.52,129.3 188.04,129.83 188.04,130.08 188.43,130.46 188.43,132.75 188.74,133.07 188.74,133.64 192.81,137.71 192.81,139.54 192.98,139.71 194.57,139.71 194.85,139.99 194.85,141.02 194.57,141.3 190.27,141.3 190.02,141.54 190.02,143.35 189.21,144.17 189.21,144.38 189.34,144.51 189.46,144.51 189.59,144.39 v1(189.65,144.39)
  BOTTOM w0.102: v1(189.65,144.39) 189.6,144.39 UV3.J12 ; UV1.J14 184.11,128.29 v1(184.5,127.9)
CLKA1#: length 30.4
  TOP w0.102: v1(184.48,128.72) 185.05,128.15 RV45.2 ; v1(188.79,144.38) 188.8,144.38 UV3.J11
  IN3 w0.14: v1(188.79,144.38) 188.95,144.22 188.95,144.06 189.77,143.25 189.77,141.44 190.16,141.04 194.47,141.04 194.59,140.92 194.59,140.09 194.47,139.96 192.88,139.96 192.56,139.65 192.56,137.82 188.49,133.75 188.49,133.17 188.17,132.86 188.17,130.57 187.79,130.19 187.79,129.93 187.41,129.56 186.81,129.56 186.52,129.26 186.52,129.26 186.22,128.96 186.22,128.62 185.93,128.33 184.76,128.33 184.48,128.61 v1(184.48,128.72)
  BOTTOM w0.102: UV3.J11 v1(188.79,144.38) ; UV1.H14 184.23,128.72 v1(184.48,128.72)
CLKB0: length 35.5
  TOP w0.102: RV46.2 187.3,126.51 v1(187.7,126.91) ; UV7.J12 206.36,133.11 v1(206.76,133.51)
  IN3 w0.102: 193.99,130.84 193.1,130.84 191.38,129.12 190.88,129.12 190.46,128.7 190.46,128.26 190.31,128.12 190.03,128.12 189.44,127.52 189.01,127.52 189,127.51 188.15,127.51 187.98,127.33 187.98,127.14 187.75,126.91 v1(187.7,126.91)
  IN3 w0.14: 193.99,130.84 194,130.84 194.67,131.51 194.67,135.18 194.94,135.46 195.91,135.46 196.19,135.18 196.19,134.28 196.33,134.14 196.75,134.14 196.89,134.28 196.89,135.18 197.16,135.46 197.82,135.46 198.1,135.18 198.1,134.28 198.23,134.14 198.65,134.14 198.79,134.28 198.79,135.16 199.07,135.43 200.05,135.43 200.32,135.16 200.32,134.34 200.45,134.22 200.89,134.22 201.02,134.34 201.02,134.99 201.3,135.27 203.27,135.27 203.55,134.99 203.55,133.94 204.13,133.36 204.54,133.36 205.01,132.9 205.98,132.9 206.43,133.34 206.6,133.34 v1(206.76,133.51)
  BOTTOM w0.102: v1(206.76,133.51) 206.36,133.11 UV7.J12 ; v1(187.7,126.91) 188.06,126.55 UV1.L9
CLKB0#: length 37.7
  TOP w0.102: UV7.J11 206.76,132.71 v1(206.76,132.65) ; RV47.2 190.24,126.52 188.81,126.52 v1(188.45,126.88)
  IN3 w0.102: v1(188.45,126.88) 188.37,126.88 188.19,127.06 188.19,127.24 188.24,127.29 189.09,127.29 189.1,127.31 189.53,127.31 190.12,127.9 190.4,127.9 190.67,128.17 190.67,128.61 190.97,128.9 191.47,128.9 193.2,130.63 193.88,130.63 193.92,130.59 193.96,130.59
  IN3 w0.14: v1(206.76,132.65) 206.76,132.71 206.84,132.79 206.84,132.97 206.71,133.09 206.54,133.09 206.09,132.64 204.9,132.64 204.44,133.11 204.02,133.11 203.29,133.84 203.29,134.88 203.17,135.01 201.4,135.01 201.27,134.88 201.27,134.24 201,133.96 200.34,133.96 200.07,134.24 200.07,135.05 199.94,135.18 199.17,135.18 199.05,135.05 199.05,134.18 198.76,133.89 198.13,133.89 197.84,134.18 197.84,135.08 197.71,135.2 197.27,135.2 197.14,135.08 197.14,134.18 196.85,133.89 196.22,133.89 195.94,134.18 195.94,135.08 195.81,135.2 195.05,135.2 194.92,135.08 194.92,131.4 194.11,130.59 193.96,130.59
  BOTTOM w0.102: v1(206.76,132.65) 206.76,132.71 UV7.J11 ; UV1.L8 188.84,126.49 v1(188.45,126.88)
CLKB1: length 33.1
  TOP w0.102: v1(188.71,115.1) 188.71,115.44 RV48.2 ; UV9.J12 206.57,112.31 v1(206.57,112.26)
  IN3 w0.102: v1(188.71,115.1) 188.87,114.95 188.87,114.7 189.13,114.44 190.3,114.44 192.31,112.43 192.31,110.21 192.99,109.52 194.34,109.52 194.36,109.5 194.39,109.5
  IN3 w0.14: v1(206.57,112.26) 206.57,112.31 206.67,112.41 206.67,112.58 206.54,112.71 206.36,112.71 205.68,112.02 204.12,112.02 203.42,111.33 203.42,110.06 203.17,109.81 202.53,109.81 202.4,109.68 202.4,109.24 202.53,109.11 203.16,109.11 203.42,108.85 203.42,106.86 203.14,106.59 202.17,106.59 201.9,106.86 201.9,107.41 201.73,107.58 196.7,107.58 194.77,109.5 194.39,109.5
  BOTTOM w0.102: v1(206.57,112.26) 206.57,112.31 UV9.J12 ; v1(188.71,115.1) 188.86,115.25 UV1.AD8
CLKB1#: length 32.2
  TOP w0.102: v1(189.33,115.12) 189.25,115.2 RV49.2 ; UV9.J11 v1(206.57,113.11)
  IN3 w0.102: 194.39,109.76 194.37,109.76 194.36,109.74 193.08,109.74 192.52,110.3 192.52,112.52 190.39,114.65 189.22,114.65 189.08,114.79 189.08,114.89 189.3,115.12 v1(189.33,115.12)
  IN3 w0.14: v1(206.57,113.11) 206.43,112.98 206.27,112.98 205.57,112.28 204.01,112.28 203.17,111.43 203.17,110.16 203.07,110.06 202.43,110.06 202.15,109.79 202.15,109.13 202.43,108.85 203.05,108.85 203.17,108.74 203.17,106.97 203.04,106.84 202.28,106.84 202.15,106.97 202.15,107.52 201.83,107.83 196.8,107.83 194.88,109.76 194.39,109.76
  BOTTOM w0.102: UV9.J11 v1(206.57,113.11) ; v1(189.33,115.12) 189.33,115.32 189.66,115.65 UV1.AD7
CLKOUT_LPC0: length 12.5
  TOP w0.102: R2336.2 125.34,97.15 124.6,97.89 124.6,98.7 123.79,99.52 122.98,99.52 122.52,99.97 v3(122.52,104.96) 122.52,106.08 v1(121.76,106.83)
  BOTTOM w0.076: UC1.AN15 122.09,107.16 v1(121.76,106.83)
CLKRUN#: length 2.7
  TOP w0.089: RC36.2 128.86,114.75 v1(128.62,114.99) 128.62,115.19 v3(129.07,115.64)
  BOTTOM w0.089: UC1.V5 127.87,115.41 128.29,114.99 v1(128.62,114.99)
CMSRC: length 29.5
  TOP w0.102: v3(167.95,164.77) 168.44,165.27 168.44,166.2 168.18,166.46 v1(168.18,166.7)
  TOP w0.254: v1(168.18,166.7) 167.99,166.89 PU701.3
  IN3 w0.254: v1(168.18,166.7) 168.18,166.47 166.3,164.6 146.27,164.6 144.75,166.13 v1(144.55,166.13)
  BOTTOM w0.254: PR721.1 143.81,165.75 144.19,166.13 v1(144.55,166.13)
CODEC_IRQ: length 5.8
  BOTTOM w0.076: UC1.L4 128.62,118.76 129.06,118.76 129.18,118.63 130.92,118.63 131.68,119.39 132.22,119.39 v3(132.49,119.12) 133.42,119.12 RC88.1
COMP_CPU: length 4.8
  BOTTOM w0.203: PR531.2 90.9,134.25 90.24,134.91 90.24,135.03 90.22,135.05 PU501.26
  BOTTOM w0.254: PR531.2 PC514.2 92.17,133.58 92.26,133.49 PR532.2 PC513.1
CPPE#: length 5.9
  BOTTOM w0.089: UC1.J1 131.33,120.59 131.96,121.22 132.57,121.22 132.72,121.37 134.32,121.37 134.47,121.22 135.63,121.22 RC108.2
CPU_DETECT#: length 241.2
  TOP w0.102: UE1.127 182.75,37.71 v1(182.86,37.6) 182.86,37.06 181.33,35.53 181.33,34.17 RE11.1 181.74,33.77 CE33.1
  IN1 w0.127: v1(174.5,47.7) 174.49,47.69 174.49,40.33 176.22,38.59 181.87,38.59 v1(182.86,37.6)
  IN3 w0.127: v1(174.5,47.7) 174.3,47.9 141.42,47.9 140.96,47.45 115.56,47.45 114.67,48.33 69.33,48.33 60.9,56.77 60.9,72.4 58.77,74.53 58.77,92.27 54.34,96.7 54.34,105.7 63.27,114.63 63.27,115.77 68.27,120.76 74.72,120.76 76.71,122.76 v1(80.78,122.76)
  BOTTOM w0.076: UC1.D61 92.73,123.98 92.73,124.22 92.44,124.51 91.85,124.51 91.79,124.58 91.49,124.58 90.86,125.2 90.24,125.2 89.92,125.53
  BOTTOM w0.102: 89.92,125.53 89.79,125.66 88.02,125.66 86.59,124.23 84.75,124.23 83.28,122.76 v3(83.03,122.76) v1(80.78,122.76)
CPU_DPB_AUX: length 7.3
  IN3 w0.127: v1(129.53,128.48) 129.68,128.33 130.02,128.33 130.33,128.64 130.33,128.98 v1(129.95,129.36)
  BOTTOM w0.076: 127.87,126.5 127.86,126.5 127.84,126.49 127.79,126.49 127.23,125.93 127.23,125.01 UC1.B5
  BOTTOM w0.089: RP51.3 v1(129.95,129.36)
  BOTTOM w0.102: v1(129.53,128.48) 129.36,128.31 129.1,128.31 128.87,128.08 128.87,127.46 127.91,126.5 127.87,126.5
CPU_DPB_AUX#: length 8
  IN3 w0.127: v1(130.95,129.36) 130.58,128.99 130.58,128.53 130.13,128.08 129.72,128.08 v1(129.53,127.89)
  BOTTOM w0.076: UC1.C5 127.43,124.44 127.43,125.04 127.39,125.08 127.39,125.82 127.86,126.28 127.87,126.28
  BOTTOM w0.102: 127.87,126.28 128,126.28 129.09,127.37 129.09,127.99 129.19,128.09 129.34,128.09 v1(129.53,127.89) ; RP51.1 v1(130.95,129.36)
CPU_DPB_CTRLCLK: length 141.5
  TOP w0.102: v1(19.46,108) 19.28,108.19 19.12,108.19 18.39,107.46 17.3,107.46 16.74,108.02 15.84,108.02 15.19,107.37 QX4.1
  IN1 w0.127: v1(19.46,108) 19.61,108.15 23.15,108.15 30.05,115.05 40.22,115.05 43.06,117.89 60.26,117.89 60.68,118.31 67.4,118.31 74.68,125.59 82.25,125.59 86.64,129.98 90.06,129.98 92.04,131.96 95.27,131.96 96.66,130.57 96.66,126.71 97.53,125.84 106.11,125.84 108.09,127.82 109.64,127.82 111.1,129.28 114.61,129.28 116.13,130.8 119.65,130.8 120.06,131.21 124.62,131.21 125.11,130.73 126.09,130.73 126.41,131.04 127.27,131.04 127.57,130.74 127.57,130.52 127.41,130.36 126.97,130.36 v1(126.77,130.55)
  BOTTOM w0.076: v1(126.77,130.55) 126.6,130.38 126.39,130.38 126.2,130.19 126.2,129.61 126.35,129.46 126.35,127.26 125.66,126.56 125.49,126.39 125.48,126.39 125.12,126.03 125.12,125.35 124.68,124.92 UC1.B9
  BOTTOM w0.102: v1(19.46,108) 19.71,108.25 19.87,108.25 20.12,108.51 20.12,108.88 19.9,109.09 19.9,109.17 20.02,109.28 RP52.1
CPU_DPB_CTRLCLK_R: length 10.6
  TOP w0.102: JHDMI.15 8.79,106.86 8.79,108.53 9.3,109.04 v2(9.78,109.04) 11.46,109.04 11.91,108.59 11.94,108.59 12.33,108.2 12.33,108.17 12.56,107.94 13.7,107.94 RX16.1 14.35,107.94 15.01,107.94 15.19,108.12 QX4.6
CPU_DPB_CTRLDAT: length 140.3
  TOP w0.102: QX4.4 16.49,108.34 16.59,108.24 16.83,108.24 17.39,107.68 18.3,107.68 19.03,108.41 19.28,108.41 v1(19.46,108.59)
  IN1 w0.127: v1(19.46,108.59) 19.63,108.42 23.03,108.42 29.94,115.33 40.11,115.33 42.95,118.16 60.14,118.16 60.56,118.58 67.29,118.58 74.57,125.86 82.14,125.86 86.53,130.25 89.95,130.25 91.92,132.23 95.38,132.23 96.93,130.68 96.93,126.82 97.64,126.11 106,126.11 107.98,128.09 109.53,128.09 110.99,129.55 114.5,129.55 116.02,131.07 119.53,131.07 119.94,131.49 124.74,131.49 125.22,131 125.98,131 126.29,131.32 127.38,131.32 127.84,130.86 127.84,130.41 127.52,130.09 126.9,130.09 v1(126.77,129.97)
  BOTTOM w0.076: v1(126.77,129.97) 126.58,130.17 126.46,130.17 126.39,130.11 126.39,129.69 126.54,129.54 126.54,127.18 125.79,126.43 125.56,126.2 125.56,126.2 125.28,125.92 125.28,125.25 124.93,124.89 UC1.C9
  BOTTOM w0.102: RP52.2 19.52,109.3 19.69,109.13 19.69,109 19.9,108.79 19.9,108.6 19.78,108.47 19.58,108.47 v1(19.46,108.59)
CPU_DPB_CTRLDAT_R: length 11.5
  TOP w0.102: JHDMI.16 9.24,106.65 9.01,106.88 9.01,108.44 9.39,108.82 9.5,108.82 9.51,108.81 10.05,108.81 10.06,108.82 11.37,108.82 v2(11.97,108.23) 12.47,107.73 13.7,107.73 RX17.1 14.67,106.75 14.71,106.75 14.71,106.56 15.02,106.25 16.36,106.25 16.49,106.37 QX4.3
CPU_DPC_AUX: length 7.3
  BOTTOM w0.076: 128.62,129.04 128.55,129.04 v2(128.24,128.73) 127.79,128.28 127.79,127.25 126.67,126.12 126.67,126.09 126.54,125.96 126.38,125.96 126.2,125.78 126.2,125.31 126.29,125.21 126.43,125.21 126.53,125.31 UC1.A6
  BOTTOM w0.089: 128.62,129.04 128.63,129.06 129.3,129.06 129.45,129.21 RP51.4
CPU_DPC_AUX#: length 7.9
  BOTTOM w0.076: UC1.B6 126.25,125.01 126.5,125.01 126.79,125.3 126.86,125.37 126.86,126.05 127.98,127.17 127.98,128.2 128.37,128.59 128.62,128.84
  BOTTOM w0.089: RP51.2 130.45,129.23 130.08,128.85 129.38,128.85 128.63,128.85 128.62,128.84
CPU_DPC_CTRLCLK: length 120.6
  IN1 w0.084: v1(124.42,123.27) 124.01,123.68 123.95,123.68 123.91,123.72 117.16,123.72 115.74,122.3 96.76,122.3 96.49,122.03 96.49,118.63 95.84,117.99 95.11,117.99 94.09,116.97 92.31,116.97 91.87,116.53 89.03,116.53 89.01,116.5 88.95,116.5 88.93,116.48 88.91,116.48
  IN1 w0.127: v1(43.27,106.15) 43.45,106.32 46.27,106.32 51.39,111.44 64.75,111.44 65.14,111.83 70.76,111.83 73.43,114.5 81.25,114.5 83.23,116.48 88.91,116.48
  IN3 w0.127: v1(43.27,106.15) 43.11,106.31 27.59,106.31 24.89,109.01 19.16,109.01 18.55,108.41 18.25,108.41 v1(18.06,108.21)
  BOTTOM w0.089: v1(124.42,123.27) 124.54,123.27 125.05,123.78 UC1.D9
  BOTTOM w0.102: v1(18.06,108.21) 18.25,108.4 18.56,108.4 18.88,108.71 18.88,109.11 19.02,109.26 RP52.3
CPU_DPC_CTRLDAT: length 120.1
  IN1 w0.084: 88.91,116.75 91.77,116.75 92.22,117.2 94,117.2 95.01,118.21 95.75,118.21 96.26,118.72 96.26,122.13 96.66,122.53 115.65,122.53 117.07,123.95 124.01,123.95 124.05,123.91 v1(124.43,124.28)
  IN1 w0.127: v1(43.27,106.73) 43.41,106.59 46.16,106.59 51.28,111.71 64.64,111.71 65.03,112.1 70.65,112.1 73.32,114.77 81.14,114.77 83.12,116.75 88.91,116.75
  IN3 w0.127: v1(43.27,106.73) 43.1,106.56 27.69,106.56 24.99,109.27 19.05,109.27 18.44,108.66 18.2,108.66 v1(18.06,108.8)
  BOTTOM w0.089: UC1.D11 124.76,123.78 124.82,123.84 124.82,124.05 124.59,124.28 v1(124.43,124.28)
  BOTTOM w0.102: RP52.4 18.52,109.26 18.66,109.11 18.66,108.8 18.47,108.61 18.25,108.61 v1(18.06,108.8)
CPU_EDP_AUX#_C: length 3.2
  TOP w0.102: CX44.2 199.51,172.24 v1(200.1,172.24) 200.3,172.24 200.75,171.78 UX4.3
  BOTTOM w0.102: v1(200.1,172.24) 200.33,172.01 200.78,172.01 RX37.1
CPU_EDP_AUX_C: length 3.2
  TOP w0.102: UX4.4 200.58,171.38 200.32,171.64 v1(200.13,171.64) 199.8,171.64 CX43.2
  BOTTOM w0.102: v1(200.13,171.64) 200.28,171.79 200.59,171.79 RX39.1
CPU_EDP_HPD#: length 13.1
  BOTTOM w0.076: UC1.D6 127.08,123.78 127.38,124.07 127.63,124.07 127.8,124.24 127.8,124.34 128.08,124.62 128.53,124.62 128.67,124.76 128.67,125.08 128.54,125.2 128.22,125.2 128.05,125.37 128.05,125.7 129.02,126.66 129.35,126.66
  BOTTOM w0.102: QC3.1 134.62,129.58 RC78.2 RC89.1 RC105.2 131.89,129.21 v3(131.36,128.67) 129.35,126.66
CPU_EDP_N0_C: length 3.2
  TOP w0.102: CX46.2 199.83,169.89 200.05,169.89 v1(200.22,169.72) 200.38,169.89 200.71,169.89 200.82,169.78 UX4.8
  BOTTOM w0.102: v1(200.22,169.72) 200.47,169.97 200.63,169.97 RX43.1
CPU_EDP_N1_C: length 6.1
  TOP w0.102: CX39.2 197.95,168.6 198.4,168.6 198.48,168.68 198.96,168.68 199.16,168.48 199.3,168.48 v1(199.51,168.27) 199.76,168.53 199.98,168.53 200.49,169.03 200.7,169.03 200.76,168.98 UX4.10
  BOTTOM w0.102: RX47.1 200.66,168.16 200.37,168.16 200.09,168.44 199.67,168.44 v1(199.51,168.27)
CPU_EDP_P0_C: length 3.1
  TOP w0.102: CX42.2 199.71,170.1 200.02,170.1 200.21,170.3 v1(200.22,170.31) 200.42,170.1 200.7,170.1 200.78,170.18 UX4.7
  BOTTOM w0.102: RX41.1 200.74,170.19 200.33,170.19 v1(200.22,170.31)
CPU_EDP_P1_C: length 6.1
  TOP w0.102: CX38.2 198.03,168.82 198.31,168.82 198.39,168.9 199.05,168.9 199.25,168.69 199.34,168.69 v1(199.51,168.86) 199.62,168.74 199.89,168.74 200.4,169.25 200.68,169.25 200.81,169.38 UX4.9
  BOTTOM w0.102: RX45.1 200.7,168.37 200.46,168.37 200.18,168.65 199.71,168.65 v1(199.51,168.86)
CPU_PWR_DEBUG#: length 71.9
  TOP w0.102: v1(88.12,121.56) 88.36,121.8 88.36,122.86 87.91,123.3 85.8,123.3 84.41,121.91 82.11,121.91 80.8,120.6 74.48,120.6 v3(66.87,112.99) 65.66,111.78 65.66,106.91 v1(66.09,106.48)
  IN3 w0.127: v1(66.09,106.48) 66.09,106.16 64.51,104.58 64.51,102.84 65.22,102.12 65.22,100.45 65.9,99.77 65.9,96.41 65.01,95.52 65.01,91.35 64.68,91.02 64.68,88.32 v1(65.05,87.95)
  BOTTOM w0.076: UC1.H59 93.96,121.71 92.9,121.71 92.78,121.84 92,121.84 91.84,121.67 90.88,121.67 90.53,122.02 90.18,122.02 90.01,122.19 88.91,122.19
  BOTTOM w0.102: v1(88.12,121.56) 87.25,121.56 86.87,121.18 84.32,121.18 R255.2 83.66,120.52 82.69,120.52 82.63,120.46 81.91,120.46 R253.1 ; v1(65.05,87.95) 62.88,90.12 RC50.1
  BOTTOM w0.109: 88.91,122.19 88.57,122.19 88.17,121.79 88.17,121.61 v1(88.12,121.56)
CPU_PWR_DEBUG#_R: length 2.6
  BOTTOM w0.102: RC50.2 62.2,91.61 JXDP1.45
CPUSB#: length 7.6
  BOTTOM w0.089: UC1.K3 129.32,120.22 131.26,120.22 132.09,121.04 v3(133.62,121.04) 134.89,121.04 RC111.2
CS1: length 3.7
  TOP w0.102: PR105.1 125.09,13.71 v3(125.09,13.89)
  TOP w0.203: PR105.1 125.82,13.79 126.14,14.11 126.93,14.11 127.03,14.21 PU100.1
CS2: length 3.9
  TOP w0.203: 131.22,13.6 v3(130.86,13.96) 130.68,14.14 128.71,14.14 128.63,14.21 PU100.5
  TOP w0.254: 131.22,13.6 131.6,13.22 PR108.1
CS_1.35V: length 5
  BOTTOM w0.102: v3(156.24,20.11) 156.66,20.53 157.75,20.53 158.41,21.19 PR205.2
  BOTTOM w0.203: PR205.2 158.72,21.32 158.72,22.51 158.51,22.72 PU200.13
CSA0#_0: length 32.3
  TOP w0.102: UV5.L12 v1(167.48,144.45)
  IN3 w0.102: v1(167.48,144.45) 167.89,144.86 168.49,144.86 168.62,144.98 168.62,145.25 168.75,145.38 169.04,145.38 169.17,145.25 169.17,144.96 169.27,144.86 170.08,144.86 170.68,144.26 170.68,141.58 170.45,141.35 ; v1(175.83,127.87) 175.3,128.41 174.75,128.41 174.13,129.03 173.31,129.03 173.11,129.23 173.11,130.37 172.63,130.84 172.63,131.82 171.03,133.42 171.03,134.19 170.46,134.76 169.83,134.76 169.42,135.17 169.42,135.39
  IN3 w0.157: 170.45,141.35 170.27,141.17 170.05,141.17 168.74,139.86 166.53,139.86 166.36,139.69 166.36,136.92 166.59,136.69 169.29,136.69 169.42,136.56 169.42,135.39
  BOTTOM w0.102: UV5.L12 v1(167.48,144.45) ; UV1.K24 175.46,127.5 v1(175.83,127.87)
CSA1#_0: length 29.9
  TOP w0.102: UV3.L12 v1(187.99,144.38)
  IN3 w0.102: 188.62,141.29 188.62,141.49 188.78,141.64 188.78,142.65 187.99,143.43 v1(187.99,144.38) ; 186.66,135.21 185.45,133.99 185.45,133.22 185.13,132.91 185.13,131.11 184.91,130.88 184.66,130.88 183.94,130.16 183.94,129.15 183.72,128.94 183.72,128.47 183.15,127.9 v1(183.13,127.9)
  IN3 w0.157: 188.62,141.29 188.62,140.54 189.4,139.77 190.4,139.77 190.53,139.65 190.53,139.09 190.4,138.96 190.08,138.96 189.96,138.84 189.96,137.13 189.6,136.77 189.38,136.77 189.02,137.13 188.84,137.13 188.58,136.86 188.58,136.68 188.93,136.33 188.93,136.11 188.71,135.88 188.49,135.88 187.89,136.48 187.71,136.48 187.44,136.22 187.44,135.89 187.88,135.45 187.88,135.23 187.61,134.96 187.29,134.96 186.97,135.28 186.73,135.28 186.66,135.21
  BOTTOM w0.102: v1(183.13,127.9) 183.11,127.88 183.11,126.54 183.37,126.28 183.48,126.28 184.07,125.69 UV1.M13 ; UV3.L12 v1(187.99,144.38)
CSB0#_0: length 34.8
  TOP w0.102: UV7.L12 v1(206.76,134.31)
  IN3 w0.102: 194.39,128.8 194.24,128.95 192.33,128.95 191.88,128.5 191.88,128.13 191.24,127.5 191.12,127.5 190.07,126.44 189.65,126.44 189.51,126.3 188.39,126.3 v1(187.94,125.85) ; v1(206.76,134.31) 207.17,133.9 207.17,131.71 206.57,131.11 203.66,131.11
  IN3 w0.157: 203.66,131.11 203.64,131.14 201.64,131.14 201.28,131.5 200.67,131.5 200.52,131.66 200.52,132.47 200.39,132.6 200.01,132.6 199.89,132.47 199.89,131.66 199.73,131.5 199.41,131.5 199.26,131.66 199.26,132.47 199.13,132.6 198.75,132.6 198.63,132.47 198.63,131.66 198.47,131.5 197.92,131.5 197.8,131.63 197.8,132.45 197.67,132.58 196.32,132.58 196.19,132.45 196.19,130.46 194.53,128.8 194.39,128.8
  BOTTOM w0.102: UV7.L12 v1(206.76,134.31) ; v1(187.94,125.85) 187.71,125.62 187.71,125.14 187.86,124.99 187.86,124.47 187.48,124.09 UV1.P10
CSB1#_0: length 31.4
  TOP w0.102: UV9.L12 v1(206.57,113.91)
  IN3 w0.102: v1(206.57,113.91) 205.62,113.91 204.83,113.13 203.83,113.13 203.62,113.34 203.47,113.34 ; v1(187.83,116.41) 188.5,115.74 191.38,115.74 192.14,114.98 192.14,114.31 193.44,113.01 194.39,113.01
  IN3 w0.157: 194.39,113.01 195.79,113.01 196.34,112.46 196.34,110.24 197.41,109.17 198.48,109.17 198.58,109.27 198.58,109.65 198.68,109.75 199.11,109.75 199.21,109.65 199.21,109.28 199.31,109.18 199.76,109.18 199.86,109.28 199.86,110.1 199.97,110.2 200.46,110.2 200.56,110.3 200.56,110.73 200.46,110.83 199.97,110.83 199.86,110.93 199.86,112.04 199.99,112.17 202.01,112.17 203.17,113.34 203.47,113.34
  BOTTOM w0.102: UV1.AD10 187.83,116.26 v1(187.83,116.41) ; UV9.L12 v1(206.57,113.91)
CSCL: length 13.3
  TOP w0.102: QX6.4 194.64,164.43 194.88,164.19 195.03,164.19 195.19,164.35 195.19,164.58 196.18,165.57 196.18,165.69 196.41,165.92 196.41,166.1 196.5,166.19 RP57.2 197.3,166.19 197.55,165.94 197.63,165.94 v1(197.81,166.12) 197.97,165.96 200.37,165.96 200.78,166.37 v2(201.22,166.37) 201.62,166.37 202.12,166.87 UX4.13
  BOTTOM w0.102: RX6.2 199.32,164.06 199.01,164.37 199.01,165.62 198.64,165.99 197.94,165.99 v1(197.81,166.12)
CSDA: length 13.6
  TOP w0.102: QX6.1 195.55,163.13 195.31,163.37 195.31,164.14 195.42,164.25 195.42,164.49 196.41,165.47 196.41,165.59 196.51,165.69 RP57.1 197.3,165.69 197.32,165.72 197.63,165.72 v1(197.81,165.54) 198,165.73 200.47,165.73 200.87,166.14 201.71,166.14 202.52,166.95 UX4.14
  BOTTOM w0.102: RX31.2 198.78,164.38 v2(198.78,165.09) 198.78,165.52 198.54,165.76 198.03,165.76 v1(197.81,165.54)
CSIN: length 30.2
  BOTTOM w0.254: 152.89,160.6 v2(152.9,160.61) ; 152.89,160.6 164.59,160.6 167.1,163.11 167.1,164.72 PR704.2 ; 152.89,160.6 142.61,160.6 142.4,160.81 142.4,161.87 142.71,162.19 PR702.3
CSIP: length 31.4
  BOTTOM w0.254: 143.49,160.22 142.45,160.22 142.01,160.66 142.01,161.87 141.7,162.19 PR702.2 ; 143.49,160.22 164.75,160.22 167.48,162.95 167.48,164.84 PR717.2 ; 143.49,160.22 v2(143.49,160.21)
CSN1_CPU: length 23.2
  BOTTOM w0.203: PU501.18 91.92,138.42 91.95,138.46 92.4,138.46
  BOTTOM w0.254: PL502.3 101.57,140.16 101.88,140.47 101.88,143.9 100.68,145.11 95.41,145.11 94.13,143.83 v3(94.13,142.98) 94.13,141.98 PR515.2 PR517.2 PC511.1 PC510.1 93.28,138.46 92.4,138.46
CSP1_CPU: length 13.6
  IN1 w0.254: v1(95.85,144.28) 95.72,144.16 93.69,144.16 92.51,142.98 92.51,142.48 v1(92.41,142.38)
  BOTTOM w0.102: PR518.1 92.93,143.12 v3(91.67,144.38)
  BOTTOM w0.203: 92.06,138.86 91.81,138.86 91.76,138.82 PU501.17
  BOTTOM w0.254: PH501.1 95.58,144.02 v1(95.85,144.28) ; PR518.1 92.41,142.55 v1(92.41,142.38) 92.47,142.31 92.47,141.36 92.62,141.21 92.62,141.21 PR517.1 PC511.2 PC510.2 92.77,138.86 92.06,138.86
DAT_SMB: length 12.4
  TOP w0.102: v1(142.27,185.66) v3(143.15,185.66)
  TOP w0.254: v1(142.27,185.66) 142.27,185.65 141.88,185.25 PR20.1
  BOTTOM w0.254: PBATT.6 149.52,187.24 148.28,186 144.68,186 143.73,185.05 PD1.1 142.24,185.61 142.27,185.65 v1(142.27,185.66)
DBC_EN: length 173.9
  TOP w0.102: v1(192.73,37.46) 192.79,37.4 UE1.25 ; v1(215.99,175.27) 215.99,176.05 215.57,176.48 214.28,176.48 RX19.1
  IN2 w0.127: v1(217.19,52.51) 217.2,52.51 217.61,52.92 217.61,53.44 222.66,58.49 222.66,71.4 228.56,77.3 228.56,85.85 225.56,88.84 225.56,96.03 226.11,96.57 226.11,109.63 224.69,111.05 224.69,120.8 225.59,121.7 225.59,146.14 216.54,155.2 216.54,166.4 215.36,167.58 215.36,174.34 215.99,174.98 v1(215.99,175.27)
  BOTTOM w0.102: v1(217.19,52.51) 217.21,52.51 217.5,52.22 217.5,48.32 v3(216.31,47.12) 212.25,43.06 202.21,43.06 201.71,42.56 195.99,42.56 192.73,39.3 v1(192.73,37.46)
DBC_EN_R: length 5.2
  TOP w0.102: v1(213.94,175.14) 214.01,175.22 RX19.2 213.12,176.72 RX23.1 213.12,177.13 v3(213.71,177.71)
  BOTTOM w0.102: JLVDS.21 214.45,174.31 214.48,174.33 214.48,174.73 214.19,175.01 214.13,175.01 214,175.14 v1(213.94,175.14)
DC_TEST_A3_B3: length 0.7
  BOTTOM w0.089: UC1.A3 129.14,125.03 UC1.B3
DC_TEST_A4: length 6.1
  BOTTOM w0.102: UC1.A4 129.01,126.19 130.02,126.19 131.87,128.03 T168.1
DC_TEST_A60: length 6.8
  BOTTOM w0.102: 90.71,127.9 90.04,127.9 89.82,128.12 89.82,129.44 T169.1
  BOTTOM w0.109: 90.71,127.9 92.37,126.24 93.09,126.24 93.55,125.77 UC1.A60
DC_TEST_A61_B61: length 0.7
  BOTTOM w0.076: UC1.A61 92.89,124.97 UC1.B61
DC_TEST_A62: length 4.4
  BOTTOM w0.089: UC1.A62 91.84,125.97 91.05,125.97 90.58,126.44 89.92,126.44 89.4,126.96 89.06,126.96
  BOTTOM w0.102: T170.1 89.06,126.96
DC_TEST_AV1: length 3.9
  BOTTOM w0.076: UC1.AV1 130.34,104.24 130.69,103.9 132.93,103.9 T171.1
DC_TEST_AW1: length 4.3
  BOTTOM w0.089: UC1.AW1 131.02,102.77 131.85,102.77 132.27,102.35 T172.1
DC_TEST_AW63: length 7.4
  BOTTOM w0.102: UC1.AW63 90.87,103.5 89.97,102.6 89.97,98.31 T173.1
DC_TEST_AY2_AW2: length 0.7
  BOTTOM w0.076: UC1.AW2 129.62,103.05 UC1.AY2
DC_TEST_AY3_AW3: length 0.7
  BOTTOM w0.076: UC1.AW3 129.01,103.54 UC1.AY3
DC_TEST_AY60: length 6.1
  BOTTOM w0.102: T166.1 90.33,101.86 90.99,102.53 93.12,102.53 UC1.AY60
DC_TEST_AY61_AW61: length 0.7
  BOTTOM w0.076: UC1.AW61 92.87,103.5 UC1.AY61
DC_TEST_AY62_AW62: length 0.7
  BOTTOM w0.076: UC1.AY62 92.22,103.5 UC1.AW62
DC_TEST_B62_B63: length 0.7
  BOTTOM w0.254: UC1.B62 91.78,124.84 UC1.B63
DC_TEST_C1_C2: length 0.7
  BOTTOM w0.076: UC1.C2 130.16,124.3 UC1.C1
DDBIA0_0: length 12.2
  TOP w0.102: 167.81,135.39 168.3,134.89 v3(168.3,134.59) v1(168.3,133.42)
  TOP w0.127: 167.81,135.39 164.29,138.9 164.29,142.85 UV5.P13
  BOTTOM w0.102: UV1.A34 167.97,133.09 v1(168.3,133.42)
DDBIA0_1: length 34.8
  BOTTOM w0.127: UV4.D2 164.47,152.05 164.08,152.45 163.69,152.45 163.48,152.66 163.48,153.17 163.02,153.63 161.88,153.63 160.62,152.37 160.62,152.36 160.2,151.94 v3(160.2,144.58) 160.2,139.31 161.04,138.46 163.13,138.46 166.55,135.04 170.3,135.04 171.07,134.28 171.07,133.54 171.38,133.22 171.38,131.81 UV1.E30
DDBIA0_2: length 29.8
  TOP w0.127: UV5.D2 172.96,152.05 173.41,152.5 173.73,152.5 173.91,152.68 173.91,153.12 174.45,153.66 176.48,153.66 178.42,151.72 v3(178.42,146.44) 178.42,139.09 175.1,135.77 v1(174.72,135.77)
  BOTTOM w0.102: UV1.E26 174.26,131.86 174.57,132.16 174.57,132.47 174.55,132.48 174.55,132.98 174.58,133.01 174.58,133.21 174.46,133.32 174.46,133.7 174.45,133.71 174.45,133.74
  BOTTOM w0.127: v1(174.72,135.77) 174.45,135.5 174.45,133.74
DDBIA0_3: length 14.1
  BOTTOM w0.102: 177.58,135.23 178.78,134.04 178.78,133.52 178.55,133.3 178.55,132.82 179.06,132.32 UV1.C20
  BOTTOM w0.127: 177.58,135.23 177.32,135.49 v3(177.32,136.44) 177.32,137.11 173.9,140.53 173.9,142.53 173.54,142.89 173.26,142.89 172.9,143.25 UV4.P13
DDBIA1_0: length 12.1
  TOP w0.102: 184.26,135.39 184.26,134.96 182.58,133.29 v1(182.58,132.72)
  TOP w0.127: 184.26,135.39 v3(184.26,135.68) 184.26,137.55 184.37,137.66 184.37,139.9 184.8,140.33 184.8,142.79 UV3.P13
  BOTTOM w0.102: UV1.C16 182.58,132.61 v1(182.58,132.72)
DDBIA1_1: length 29.7
  BOTTOM w0.102: UV1.C12 185.35,132.17 185.35,131.99 185.45,131.89 185.55,131.89 185.81,132.15 185.81,132.4 185.75,132.45 185.75,132.92 185.77,132.94 185.77,133.31 185.51,133.58 185.51,134.13 185.32,134.31 185.32,135.39
  BOTTOM w0.127: UV6.D2 184.99,151.99 184.59,152.38 184.21,152.38 183.99,152.6 183.99,153.11 183.53,153.57 182.39,153.57 181.13,152.3 181.13,152.3 179.75,150.92 v3(179.75,145.47) 179.75,140.96 185.32,135.39 185.32,135.39
DDBIA1_2: length 39.2
  TOP w0.102: v1(186.86,127.88) 187.28,128.3 187.28,129.27 188.24,130.24
  TOP w0.127: UV3.D2 193.47,151.99 193.93,152.44 194.24,152.44 194.42,152.62 194.42,153.06 194.96,153.59 195.5,153.59 195.77,153.33 197.07,153.33 199.31,151.09 v3(199.31,150.16) 199.31,140.88 193.21,134.78 189.79,134.78 188.73,133.72 188.73,130.72 188.24,130.24
  BOTTOM w0.102: v1(186.86,127.88) 186.45,128.29 UV1.J11
DDBIA1_3: length 16.2
  BOTTOM w0.102: 189.92,133.77 189.92,133.74 189.94,133.73 189.94,133.48 189.75,133.3 189.75,132.81 189.77,132.8 189.77,132.46 189.53,132.23 189.32,132.23 189.16,132.07 189.16,131.78 189.17,131.76 189.17,131.28 188.86,130.97 UV1.F8
  BOTTOM w0.127: 189.92,133.77 189.92,134.12 191.57,135.77 192.38,135.77 194.41,137.8 v3(194.41,139.3) 194.41,142.46 194.05,142.82 193.77,142.82 193.41,143.18 UV6.P13
DDBIB0_0: length 20.3
  TOP w0.102: 194.39,130.11 194.23,130.11 193.89,130.44 193.43,130.44 192.7,131.17 192.3,131.17 192.26,131.14 192.26,131.14 191.38,130.26 v1(190.8,130.26)
  TOP w0.127: 194.39,130.11 v3(195.14,130.11) 195.84,130.11 201.69,135.96 202.69,135.96 203.77,137.04 203.77,137.33 203.94,137.5 205.17,137.5 UV7.P13
  BOTTOM w0.102: UV1.G7 190.03,130.26 v1(190.8,130.26)
DDBIB0_1: length 35.2
  BOTTOM w0.102: 194.39,127.72 194.13,127.72 193.74,127.33 193.22,127.33 193.17,127.29 UV1.K1
  BOTTOM w0.127: 194.39,127.72 194.83,127.72 197.86,130.75 v3(197.86,132.71) 197.86,134.8 199.89,136.83 199.89,137.93 203.51,141.55 207.55,141.55 207.88,141.22 214.09,141.22 214.72,140.58 214.72,138.55 214.48,138.3 214.27,138.3 214.02,138.06 214.02,137.44 UV8.D2
DDBIB0_2: length 15.1
  BOTTOM w0.102: UV1.P1 192.94,124.17 193.96,124.17 194.08,124.29 194.39,124.29
  BOTTOM w0.127: 194.39,124.29 196.83,124.29 v3(198.87,126.33) 199.42,126.88 201.83,126.88 202.84,127.89 204.84,127.89 205.2,128.25 205.2,128.53 205.56,128.9 UV8.P13
DDBIB0_3: length 30.8
  TOP w0.127: v1(193.96,120.96) 194.6,120.96 197.02,123.38 v3(197.87,123.38) 213.26,123.38 215.97,126.09 215.97,127.35 215.44,127.88 214.99,127.88 214.81,128.06 214.81,128.38 214.36,128.83 UV7.D2
  BOTTOM w0.102: v1(193.96,120.96) 193.31,120.31 192.68,120.31 192.58,120.41 192.32,120.41 192.23,120.32 191.89,120.32 UV1.W4
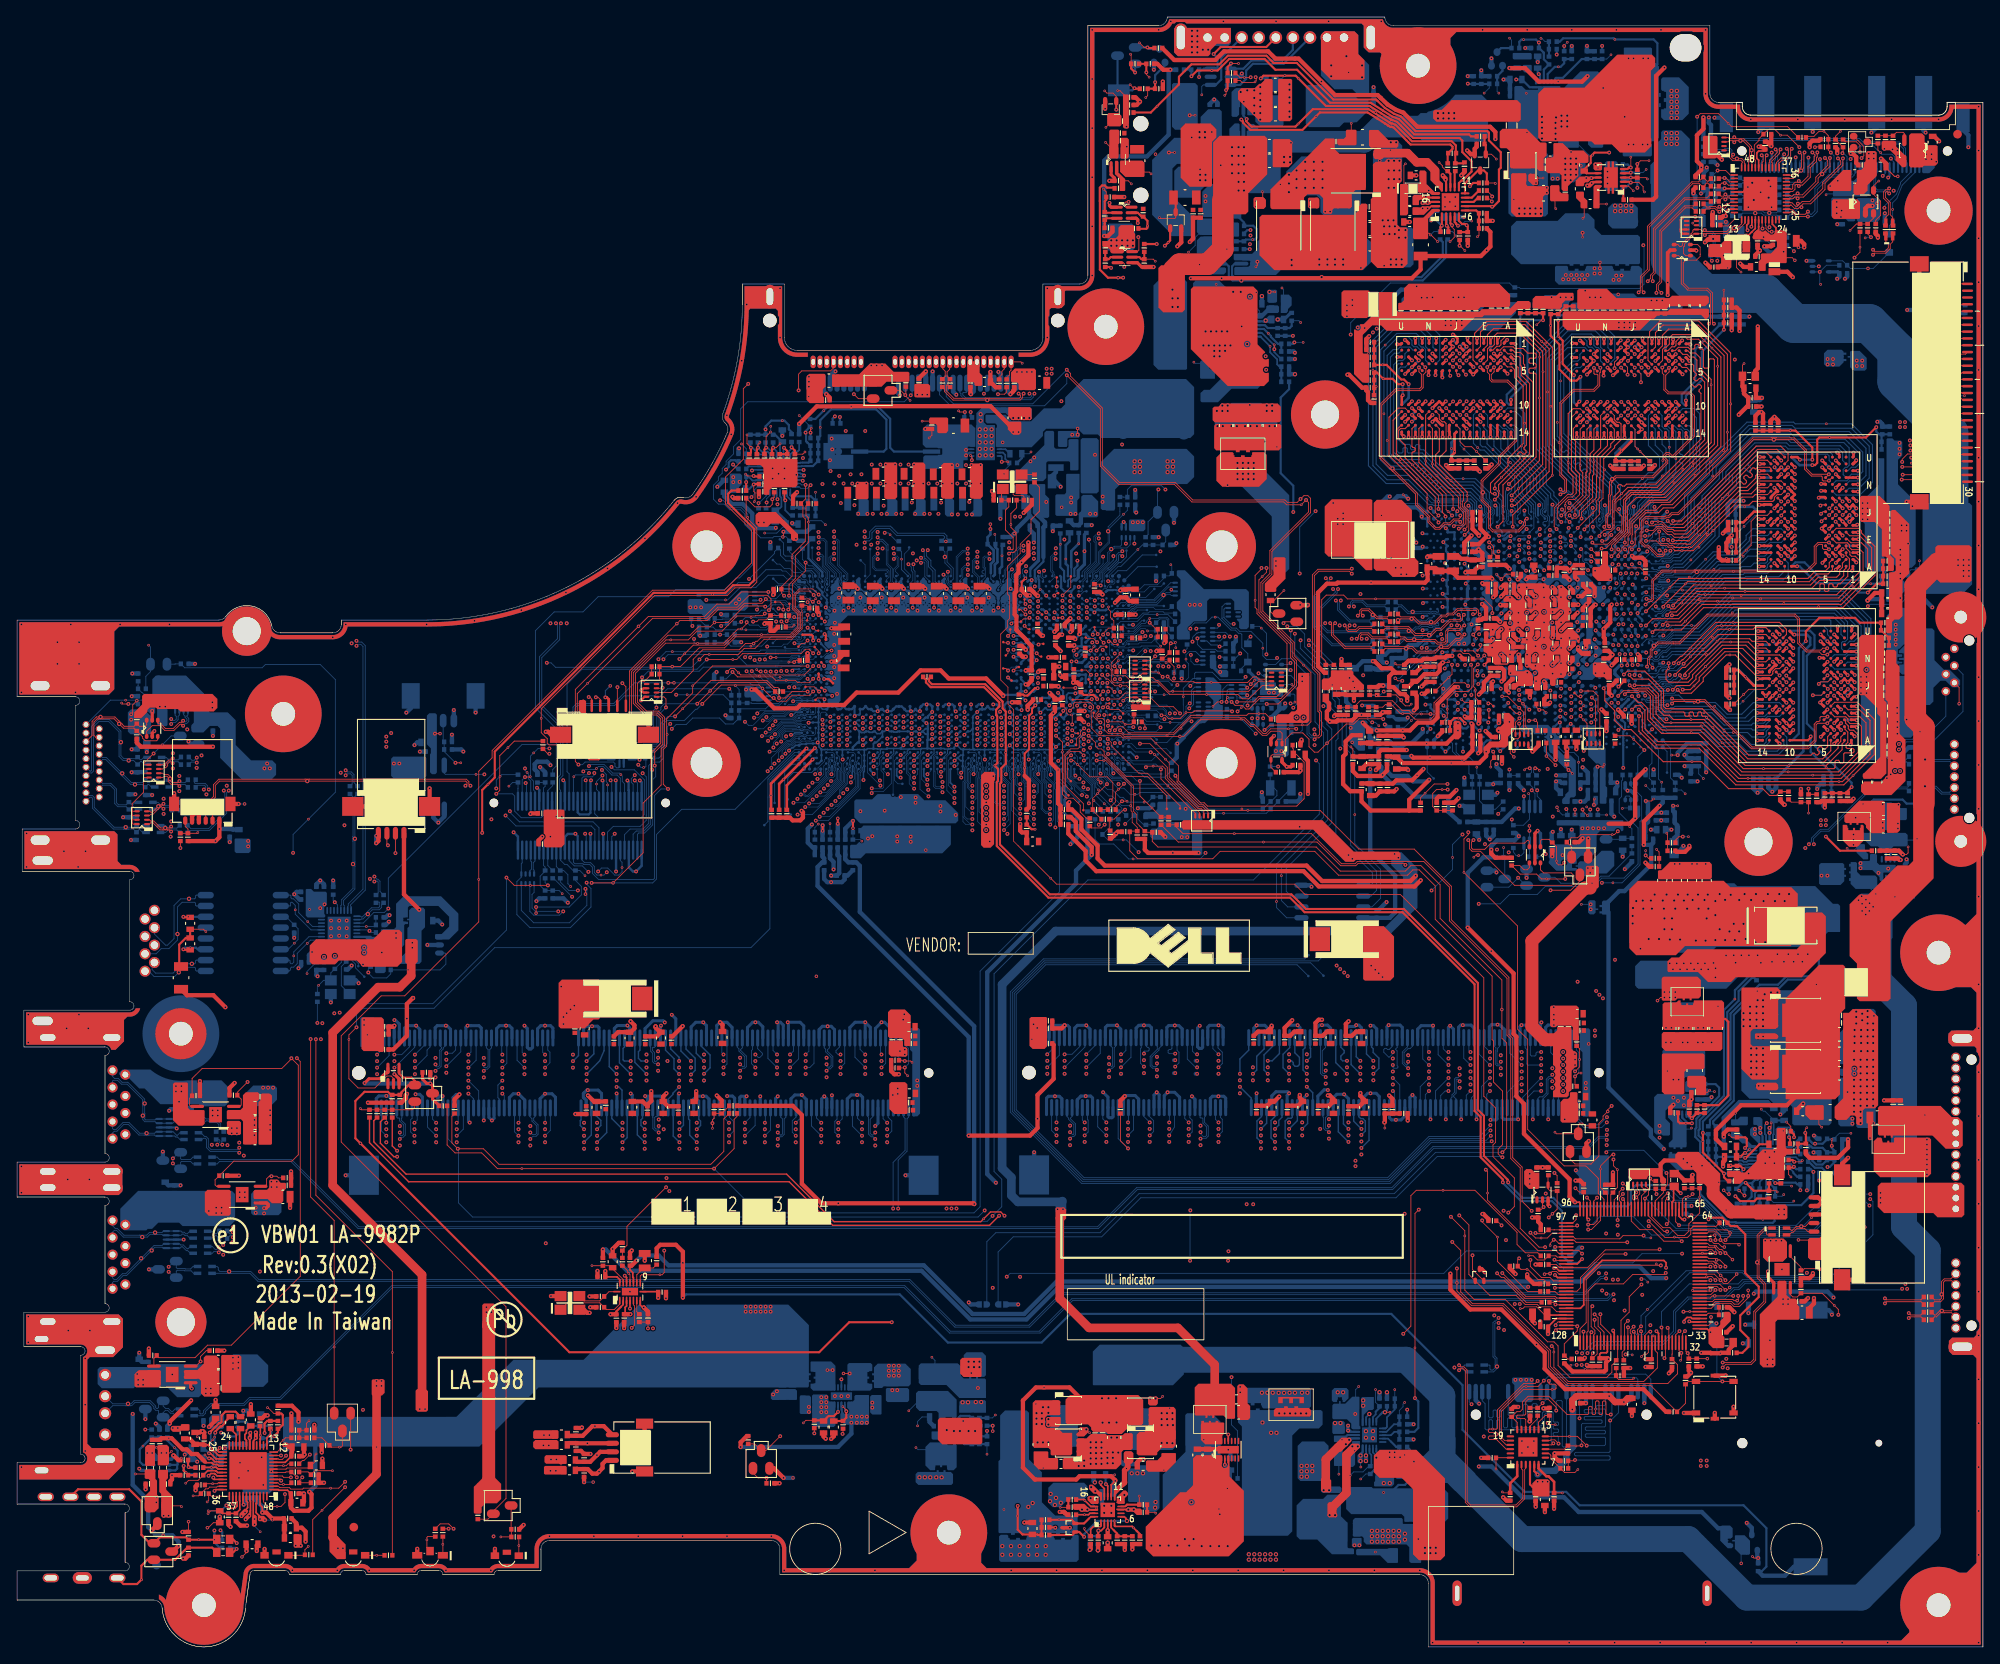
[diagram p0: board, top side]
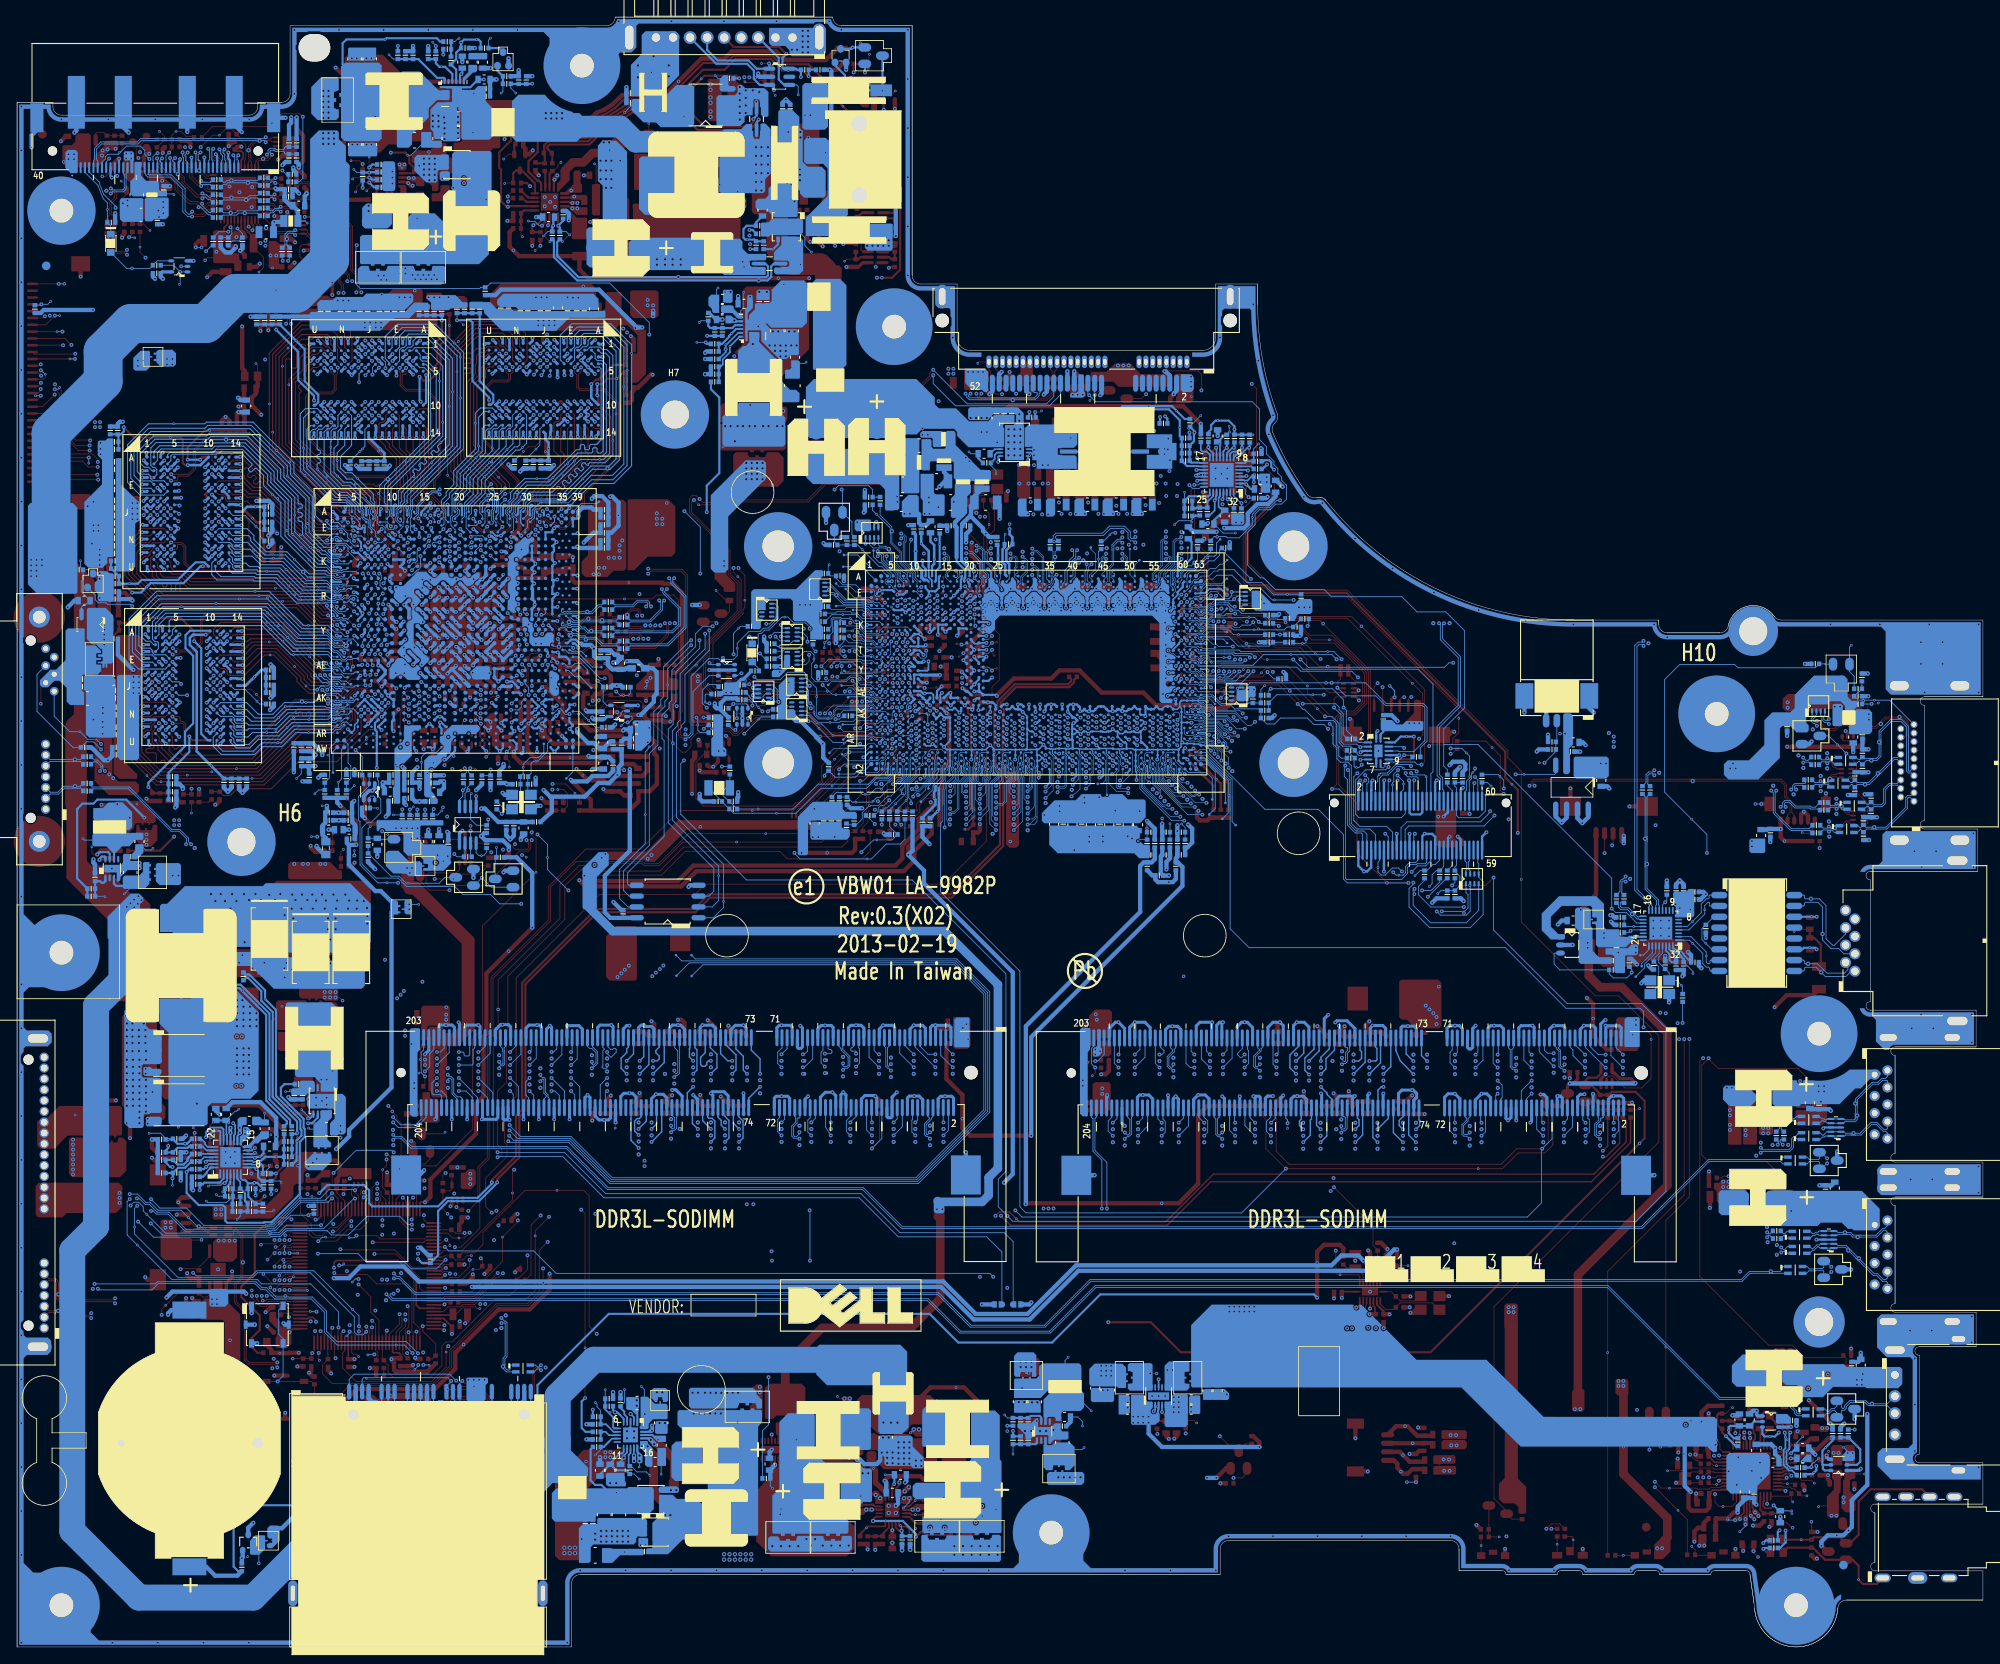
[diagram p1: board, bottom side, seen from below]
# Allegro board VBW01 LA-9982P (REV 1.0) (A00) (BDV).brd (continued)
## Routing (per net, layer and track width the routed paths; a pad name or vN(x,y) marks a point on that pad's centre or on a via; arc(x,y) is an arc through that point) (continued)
DDBIB1_0: length 29.5
  BOTTOM w0.102: UV1.AC4 191.76,116.99 192.09,116.99 192.34,117.23 192.59,117.23 192.66,117.17 193.21,117.17 193.9,117.87 194.39,117.87
  BOTTOM w0.127: 194.39,117.87 197.64,117.87 v3(201.02,121.25) 201.36,121.58 213.14,121.58 214.53,120.19 214.53,118.15 214.25,117.87 213.96,117.87 213.83,117.74 213.83,117.05 UV10.D2
DDBIB1_1: length 16.5
  TOP w0.127: UV9.P13 204.97,117.11 203.62,117.11 202.89,117.83 v3(200.84,117.83) 199.68,117.83 195.96,114.12 195.96,113.82 195.65,113.5 195.16,113.5 194.89,113.78 v1(194.89,113.94)
  BOTTOM w0.102: 194.39,113.45 194.15,113.45 193.91,113.21 192.73,113.21 192.41,112.89 UV1.AH3
  BOTTOM w0.127: 194.39,113.45 v1(194.89,113.94)
DDBIB1_2: length 39.2
  TOP w0.102: v1(188.43,111.71) 188.64,111.91 190.03,111.91 190.12,112 190.9,112 191.42,111.48
  TOP w0.127: 191.42,111.48 191.42,108.9 192.82,107.5 197.25,107.5 202.15,102.6 v3(207.57,102.6) 213.46,102.6 215.78,104.91 215.78,106.95 215.25,107.48 214.8,107.48 214.62,107.66 214.62,107.99 214.3,108.3 214.3,108.58 UV9.D2
  BOTTOM w0.102: v1(188.43,111.71) 188.51,111.71 188.86,112.05 UV1.AJ8
DDBIB1_3: length 15
  BOTTOM w0.102: UV1.AM3 192.43,109.69 192.74,109.39 193.6,109.39 193.84,109.14 194.39,109.14
  BOTTOM w0.127: UV10.P13 205.37,108.57 204.97,108.16 204.97,107.73 204.74,107.5 203.42,107.5 203.27,107.66 199.97,107.66 198.48,109.14 v3(196.1,109.14) 194.39,109.14
DDI1_LANE_N0: length 96.9
  IN1 w0.127: v1(95.76,127.54) 95.58,127.71 95.26,127.71 93.57,126.02 87.57,126.02 85.6,124.05 85.25,124.05 83.61,122.41 81.7,122.41 80.32,121.04 74.83,121.04 68.91,115.12 63.3,115.12 62.88,114.7 44.28,114.7 41.52,111.94 40.2,111.94 27.84,99.57 24.67,99.57 24.38,99.86 24.38,100.25 v1(24.23,100.4)
  BOTTOM w0.076: v1(95.76,127.54) 95.59,127.71 95.41,127.71 95.34,127.64 95.34,127.18 95.47,127.04 96.23,126.29 96.59,125.92 96.59,125.49 96.65,125.37 96.65,125.15 96.63,125.07 96.62,125.05 96.59,125 96.59,124.86 96.62,124.76 96.83,124.55 97.01,124.55 97.18,124.38 UC1.C54
  BOTTOM w0.102: CX18.2 20.38,95.94 22.44,95.94 24.35,97.85 24.35,100.28 v1(24.23,100.4)
DDI1_LANE_N1: length 94.2
  IN1 w0.127: v1(23.71,98.5) 23.47,98.74 23.47,100.6 27.7,104.83 31.13,104.83 39.01,112.72 41.19,112.72 44.01,115.53 61.34,115.53 61.71,115.9 68.55,115.9 75.86,123.21 83.18,123.21 86.78,126.81 91.49,126.81 92.54,127.85 93.73,127.85 93.93,127.65 v1(93.93,127.54)
  BOTTOM w0.076: UC1.B58 94.88,124.64 94.88,124.73 95,124.85 95,124.97 94.97,125 94.87,125 94.83,125.04 94.83,125.19 94.87,125.23 94.96,125.23 95,125.27 95,126.03 94.36,126.66 94.36,127.79 94.28,127.87 94.16,127.87 94.11,127.82
  BOTTOM w0.089: 94.11,127.82 93.93,127.64 v1(93.93,127.54)
  BOTTOM w0.102: CX16.2 19.64,98.46 20.13,98.46 20.26,98.59 21.96,98.59 22.61,99.24 23.23,99.24 23.49,98.98 23.49,98.72 v1(23.71,98.5)
DDI1_LANE_N2: length 96.9
  IN1 w0.127: v1(95.76,130.14) 95.58,129.97 95.1,129.97 94.88,130.19 94.88,130.95 94.4,131.42 93.3,131.42 92.58,130.7 92.58,130.15 92.07,129.63 91.67,129.63 91.03,128.98 86.36,128.98 82.44,125.05 74.97,125.05 67.67,117.76 60.94,117.76 60.56,117.38 43.26,117.38 40.43,114.55 30.26,114.55 24.22,108.5 24.22,105.48 22.84,104.1 21.23,104.1 v1(21.06,104.27)
  BOTTOM w0.076: UC1.B55 97.15,124.91 97.37,125.13 97.37,125.83 96.34,126.85 96.34,129.54 96.34,129.7 96.16,129.89 96.01,129.89 v1(95.76,130.14)
  BOTTOM w0.102: CX14.2 20.5,103.96 20.75,103.96 v1(21.06,104.27)
DDI1_LANE_N3: length 95.4
  IN1 w0.127: v1(93.96,129.49) 93.78,129.66 93.42,129.66 93.29,129.53 93.29,128.99 92.92,128.61 92.15,128.61 91.29,127.75 86.62,127.75 82.87,124 75.5,124 68.18,116.68 61.35,116.68 60.99,116.32 43.69,116.32 40.87,113.5 30.7,113.5 25.55,108.35 25.55,104.36 22.27,101.07 22.27,100.74 v1(22.48,100.53)
  BOTTOM w0.076: UC1.A57 95.5,125.56 95.62,125.44 95.72,125.44 95.81,125.53 95.81,125.81 94.73,126.89 94.73,129.53 94.48,129.78 94.05,129.78 93.96,129.69 v1(93.96,129.49)
  BOTTOM w0.102: v1(22.48,100.53) 22.29,100.72 22.29,101 22.05,101.24 20.87,101.24 20.79,101.32 20.79,101.53 CX12.2
DDI1_LANE_P0: length 96.7
  IN1 w0.127: v1(95.76,128.19) 95.55,127.99 95.15,127.99 93.46,126.29 87.46,126.29 85.49,124.32 85.13,124.32 83.49,122.69 81.58,122.69 80.21,121.31 74.72,121.31 68.8,115.39 63.19,115.39 62.76,114.97 44.16,114.97 41.4,112.21 40.09,112.21 27.72,99.85 24.78,99.85 24.65,99.97 24.65,100.25 v1(24.81,100.4)
  BOTTOM w0.076: v1(95.76,128.19) 95.47,127.9 95.33,127.9 95.15,127.72 95.15,127.1 95.24,127 95.34,126.91 96.43,125.82 96.43,125.45 96.49,125.29 96.49,125.18 96.44,125.06 96.43,125.03 96.43,124.84 96.47,124.69 96.57,124.54 UC1.C55
  BOTTOM w0.102: CX19.2 20.25,95.72 22.53,95.72 24.57,97.76 24.57,100.16 v1(24.81,100.4)
DDI1_LANE_P1: length 94.5
  IN1 w0.127: v1(93.93,128.19) 93.86,128.12 92.42,128.12 91.38,127.08 86.67,127.08 83.07,123.48 75.74,123.48 68.43,116.17 61.6,116.17 61.23,115.8 43.89,115.8 41.08,112.99 38.9,112.99 31.02,105.1 27.58,105.1 23.19,100.71 23.19,98.57 v1(23.12,98.5)
  BOTTOM w0.076: UC1.C58 94.94,124.17 95.24,124.47 95.24,124.72 95.19,124.77 95.19,126.11 94.55,126.74 94.55,127.87 94.36,128.06 94.06,128.06
  BOTTOM w0.089: 94.06,128.06 v1(93.93,128.19)
  BOTTOM w0.102: CX17.2 19.22,98.25 20.22,98.25 20.35,98.37 22.05,98.37 22.7,99.02 23.14,99.02 23.27,98.89 23.27,98.65 v1(23.12,98.5)
DDI1_LANE_P2: length 96.4
  IN1 w0.127: v1(21.06,103.69) 21.21,103.83 22.95,103.83 24.49,105.37 24.49,108.39 30.37,114.27 40.55,114.27 43.38,117.1 60.67,117.1 61.05,117.49 67.78,117.49 75.08,124.78 82.55,124.78 86.48,128.71 91.14,128.71 91.79,129.36 92.18,129.36 92.85,130.03 92.85,130.59 93.41,131.15 94.29,131.15 94.6,130.84 94.6,130.08 94.98,129.7 95.55,129.7 v1(95.76,129.49)
  BOTTOM w0.076: v1(95.76,129.49) 95.96,129.7 96.08,129.7 96.15,129.62 96.15,126.78 97.18,125.75 97.18,125.2 97.1,125.13 97.08,125.13 96.88,125.32 UC1.A55
  BOTTOM w0.102: CX15.2 20.41,103.74 21,103.74 v1(21.06,103.69)
DDI1_LANE_P3: length 95.6
  IN1 w0.127: v1(21.89,100.53) 21.99,100.63 21.99,101.18 25.28,104.47 25.28,108.46 30.58,113.77 40.76,113.77 43.58,116.59 60.88,116.59 61.24,116.95 68.07,116.95 75.39,124.27 82.75,124.27 86.5,128.02 91.18,128.02 92.04,128.88 92.8,128.88 93.02,129.1 93.02,129.64 93.31,129.93 93.75,129.93 v1(93.96,130.13)
  BOTTOM w0.076: v1(93.96,130.13) 94.12,129.97 94.56,129.97 94.92,129.61 94.92,126.97 96,125.89 96,125.46 95.5,124.96 UC1.B57
  BOTTOM w0.102: v1(21.89,100.53) 22.08,100.72 22.08,100.91 21.96,101.03 21.17,101.03 CX13.2
DDR3_DRAMRST#: length 146.3
  TOP w0.102: CD34.1 129.31,59.34 v1(130.2,58.45) ; RD5.1 83.46,62.55 82.83,61.92 82.83,58.11 81.31,56.59 56.47,56.59 54.65,58.41 v1(51.65,58.41) 50.96,59.11 50.96,62.23 CD3.1
  IN1 w0.127: v1(113.4,51.18) 114.38,52.16 124.84,52.16 130.2,57.52 v1(130.2,58.45)
  BOTTOM w0.102: v1(130.2,58.45) 129.05,59.61 JDIMM2.30 ; v1(113.4,51.18) 112.63,50.41 53.39,50.41 51.74,52.06 51.74,58.41 v1(51.65,58.41) 50.5,59.57 JDIMM1.30
DDR3_DRAMRST#_CPU: length 135.2
  TOP w0.102: RD3.2 50.4,58.86 51.34,57.92 54.46,57.92 56.3,56.08 v3(59.16,56.08) v1(81.69,56.08) 84.04,58.43 84.04,61.86 84.37,62.19 RD5.2
  BOTTOM w0.076: 121.96,96.77 121.9,96.83 121.9,100.54 121.77,100.67 121.77,101.25 121.55,101.47 121.55,102.62 121.37,102.81 121.37,103.05 121.44,103.13 121.44,103.39 121.36,103.46 121.36,103.98 UC1.AV15
  BOTTOM w0.102: 121.96,96.77 122.16,96.57 122.16,88.53 112.87,79.23 112.87,51.61 112.15,50.89 86.88,50.89 v1(81.69,56.08)
DDR_A_BS0: length 76.9
  IN1 w0.084: 109.12,96.53 108.87,96.53 108.04,95.7 108.03,95.7
  IN1 w0.089: v1(109.86,99.54) 109.48,99.16 109.48,97.99 109.38,97.89 109.38,96.79 109.12,96.53
  IN1 w0.183: v1(77.59,68.7) 77.59,69.22 78.39,70.02 79.2,70.02 80.15,70.98 94.72,70.98 94.81,71.07 94.81,72.19 94.94,72.32 95.41,72.32 95.54,72.19 95.54,71.1 95.67,70.98 96.14,70.98 96.27,71.1 96.27,73.69 96.4,73.82 96.88,73.82 97,73.69 97,71.1 97.13,70.98 97.61,70.98 97.73,71.1 97.73,74.53 97.86,74.66 98.34,74.66 98.47,74.53 98.47,72.92 98.59,72.79 99.96,72.79 100.09,72.92 100.09,74.51 100.23,74.66 100.72,74.66 107.42,81.36 107.42,95.09 108.03,95.7
  BOTTOM w0.076: UC1.AU35 109.24,104.74 109.24,104.67 108.97,104.41 108.97,100.42 v1(109.86,99.54)
  BOTTOM w0.165: JDIMM1.109 76.6,70.12 77.59,69.13 v1(77.59,68.7)
DDR_A_BS1: length 76.3
  IN1 w0.084: v1(109.87,100.29) 110.26,100.29 110.41,100.13 110.41,97 108.75,95.34
  IN1 w0.183: v1(77.59,65.65) 78.51,66.58 78.51,68.87 78.79,69.15 79.56,69.15 80.4,69.99 93.27,69.99 93.45,69.81 93.45,66.91 93.58,66.78 94.06,66.78 94.18,66.91 94.18,69.97 94.31,70.1 96.88,70.1 97,69.97 97,68.73 97.13,68.6 98.83,68.6 98.96,68.73 98.96,69.93 102.28,73.25 102.28,74.7 108.34,80.77 108.34,95.07 108.61,95.34 108.75,95.34
  BOTTOM w0.076: UC1.AV35 109.14,103.94 109.14,101.02 v1(109.87,100.29)
  BOTTOM w0.165: JDIMM1.108 76.3,64.22 76.86,64.78 76.86,64.93 v1(77.59,65.65)
DDR_A_BS2: length 73
  IN1 w0.084: v1(105.13,101.93) 104.64,101.44 104.64,99.25 101.89,96.5 101.89,96.5 101.29,95.9 100.3,95.9 98.84,94.44 98.84,93.66
  IN1 w0.183: v1(66.75,68.68) 66.7,68.65 66.4,68.65 66.28,68.78 66.28,69.96 66.4,70.08 67.25,70.08 67.37,70.21 67.37,70.69 67.25,70.82 66.4,70.82 66.28,70.94 66.28,71.42 66.4,71.55 67.65,71.55 67.78,71.67 67.78,72.15 67.65,72.28 66.4,72.28 66.28,72.41 66.28,73.14 66.4,73.26 67.57,73.26 67.78,73.48 67.78,74.4 71.12,77.74 71.12,77.99 70.58,78.53 70.58,78.71 70.92,79.05 71.1,79.05 71.64,78.51 71.9,78.51 72.15,78.77 72.15,79.03 71.61,79.57 71.61,79.75 71.95,80.09 72.13,80.09 72.67,79.55 72.93,79.55 73.56,80.17 89.86,80.17 98.84,89.15 98.84,93.66
  BOTTOM w0.076: v1(105.13,101.93) 105.53,102.33 105.53,102.41 105.53,102.76 105.53,102.76 UC1.AY41
  BOTTOM w0.165: JDIMM1.79 67.6,69.53 v1(66.75,68.68)
DDR_A_CAS#: length 75.4
  IN1 w0.084: v1(109.86,104.58) 110.26,104.18 110.26,101.8 111.19,100.87 111.19,95.8 110.65,95.25 110.65,94.57
  IN1 w0.183: v1(78.98,67.11) 79.35,66.73 79.35,66.67 79.42,66.6 79.42,65.92 79.15,65.64 79.15,64.47 80.13,63.48 98.93,63.48 102.24,66.79 102.24,69.87 104.98,72.61 104.98,74.21 110.65,79.89 110.65,94.57
  BOTTOM w0.076: v1(109.86,104.58) 110,104.58 UC1.AU34
  BOTTOM w0.165: JDIMM1.115 78.4,70.1 79.47,69.04 79.47,67.6 v1(78.98,67.11)
DDR_A_D0: length 73.5
  IN3 w0.127: v1(82.79,69.46) 82.15,69.46 82.02,69.59 82.02,70.32 81.9,70.44 78.06,70.44 77.93,70.57 77.93,70.86 78.06,70.98 80.82,70.98 80.94,71.11 80.94,71.4 80.82,71.52 78.06,71.52 77.93,71.65 77.93,71.94 78.06,72.07 79.73,72.07 79.86,72.19 79.86,72.48 79.73,72.61 78.56,72.61 78.43,72.73 78.43,73.02 78.56,73.15 79.18,73.15 79.31,73.27 79.31,73.56 79.18,73.69 78.56,73.69 78.43,73.82 78.43,74.44 73.72,79.15 73.72,93.11 74.45,93.85 74.45,99.35 76.52,101.42 76.52,105.45 79.09,108.02 84.86,108.02 v1(85.31,108.47)
  BOTTOM w0.076: UC1.AH63 91.39,110.28 91.26,110.15 90.57,110.15 89.87,109.46 87.64,109.46 86.24,108.05 86.08,108.05
  BOTTOM w0.102: JDIMM1.129 82.6,69.65 v1(82.79,69.46) ; 86.08,108.05 85.72,108.05 v1(85.31,108.47)
DDR_A_D1: length 73.8
  IN3 w0.127: v1(82.79,67.94) 81.51,67.94 81.38,67.81 81.38,67.48 81.51,67.35 82.24,67.35 82.37,67.22 82.37,66.94 82.24,66.81 81.51,66.81 81.38,66.68 81.38,65.61 81.25,65.48 80.17,65.48 79.91,65.73 79.91,69.82 79.66,70.08 77.7,70.08 77.57,70.21 77.57,74.79 73.35,79 73.35,93.26 74.09,94 74.09,99.5 76.16,101.57 76.16,105.6 78.94,108.38 83.59,108.38 84.19,108.98 86.35,108.98 v1(86.37,108.95)
  BOTTOM w0.076: UC1.AH62 92.1,110.48 91.9,110.48 91.72,110.58 91.45,110.58 91.19,110.32 90.5,110.32 89.83,109.65 87.6,109.65 86.9,108.95 v1(86.37,108.95)
  BOTTOM w0.102: JDIMM1.131 83.2,68.34 v1(82.79,67.94)
DDR_A_D2: length 71.9
  IN3 w0.084: v1(88.58,108.06) 89.2,107.44 89.2,106.86 87.34,104.99 87.34,104.93 87.12,104.72
  IN3 w0.127: 87.12,104.72 87.01,104.61 86.82,104.61 86.08,105.35 85.91,105.35 85.7,105.14 85.7,104.97 86.44,104.23 86.44,104.04 86.25,103.84 86.06,103.84 85.32,104.59 85.14,104.59 84.93,104.38 84.93,104.2 85.68,103.46 85.68,103.27 85.48,103.08 85.29,103.08 84.9,103.47 84.72,103.47 84.51,103.27 84.51,103.09 84.91,102.7 84.91,102.51 81.95,99.55 80.04,99.55 79.02,98.52 79.02,98.34 79.4,97.96 80.56,96.8 80.56,96.62 80.36,96.41 80.18,96.41 78.63,97.96 78.45,97.96 78.25,97.76 78.25,97.58 79.27,96.56 79.27,96.38 79.07,96.17 78.89,96.17 77.87,97.2 77.69,97.2 77.44,96.95 77.44,96.77 77.99,96.21 77.99,95.97 77.05,95.03 77.05,79.69 83.17,73.57 83.17,72.88 86.11,69.95 86.11,68.05 86.22,67.94 v1(86.53,67.94)
  BOTTOM w0.076: UC1.AK63 91.52,108.8 91.25,108.8 91.01,108.56 89.56,108.56 89.07,108.06 v1(88.58,108.06)
  BOTTOM w0.102: v1(86.53,67.94) 86.08,68.39 86.08,69.93 86.2,70.05 JDIMM1.141
DDR_A_D3: length 72.6
  IN3 w0.127: v1(85.3,61.46) 86.31,61.46 86.43,61.59 86.43,63.76 86.31,63.89 85.16,63.89 85.04,64.02 85.04,64.87 85.16,64.99 86.64,64.99 86.77,65.12 86.77,65.41 86.64,65.54 85.16,65.54 85.04,65.66 85.04,65.95 85.16,66.08 86.64,66.08 86.77,66.2 86.77,66.49 86.64,66.62 85.88,66.62 85.74,66.75 85.74,69.8 82.81,72.73 82.81,73.42 76.69,79.54 76.69,96.71 79.89,99.91 81.8,99.91 84.15,102.26 84.15,104.12 84.72,104.68 84.72,104.87 84.26,105.34 84.26,105.52 84.46,105.72 84.64,105.72 85.1,105.26 85.29,105.26 85.75,105.71 86.97,105.71 87.53,106.27 87.53,106.44 87.74,106.64 v1(87.74,107.22)
  BOTTOM w0.076: UC1.AK62 92.06,108.93 91.77,108.64 91.32,108.64 91.08,108.39 89.63,108.39 88.89,107.65 88.71,107.65 88.28,107.22 v1(87.74,107.22)
  BOTTOM w0.102: JDIMM1.140 85.9,62.06 v1(85.3,61.46)
DDR_A_D4: length 74.4
  IN3 w0.127: v1(83.44,59.94) 83.44,60.1 78.36,65.18 78.36,68.81 77.21,69.96 77.21,74.64 72.99,78.85 72.99,93.41 73.73,94.15 73.73,99.66 75.79,101.72 75.79,105.75 78.79,108.74 83.44,108.74 84.05,109.35 86.64,109.35 v1(86.76,109.46)
  BOTTOM w0.076: v1(86.76,109.46) 87.11,109.81 89.76,109.81 90.44,110.49 91.13,110.49 91.38,110.74 91.76,110.74 91.8,110.72 91.9,110.67 92.57,110.67 UC1.AH61
  BOTTOM w0.102: JDIMM1.132 83.5,62.08 83.98,61.61 83.98,60.47 v1(83.44,59.94)
DDR_A_D5: length 74.8
  IN3 w0.127: v1(86.5,107.65) 79.24,107.65 76.88,105.3 76.88,100.32 76.35,99.79 75.54,99.79 74.82,99.06 74.82,93.7 74.08,92.96 74.08,79.31 79.95,73.43 79.95,72.94 83.4,69.49 83.4,67.2 83.58,67.02 84.02,67.02 84.15,66.89 84.15,66.62 84.02,66.48 83.58,66.48 83.45,66.35 83.45,66.07 83.58,65.94 84.02,65.94 84.15,65.81 84.15,65.53 84.02,65.4 83.58,65.4 83.45,65.26 83.45,64.99 83.58,64.86 84.02,64.86 84.15,64.72 84.15,64.45 84.02,64.32 83.58,64.32 83.45,64.18 83.45,63.91 83.58,63.78 83.9,63.78 84.03,63.65 84.03,63.36 83.9,63.24 83.58,63.24 83.45,63.1 83.45,61.46 v1(83.44,61.46)
  BOTTOM w0.076: UC1.AH60 93.6,109.52 93.4,109.32 93.15,109.32 93.14,109.33 92.76,109.33 92.75,109.32 92.56,109.32 92.54,109.32 92.4,109.39 92.2,109.39 92.04,109.32 91.91,109.32 91.8,109.36 91.75,109.39 91.46,109.39 91.21,109.14 91.12,109.14 90.89,108.91 88.72,108.91 87.47,107.65 87.12,107.65
  BOTTOM w0.102: 87.12,107.65 v1(86.5,107.65) ; v1(83.44,61.46) 82.9,62 JDIMM1.130
DDR_A_D6: length 73.2
  IN3 w0.084: v1(88.88,108.54) 88.88,108.82 89,108.95 89.8,108.95 89.93,108.82 89.93,107.34 87.71,105.12 87.71,104.79 87.12,104.2
  IN3 w0.127: 87.12,104.2 85.36,102.44 85.36,102.11 85.84,101.63 85.84,101.38 85.57,101.11 85.38,101.11 84.8,101.69 84.61,101.69 84.42,101.5 84.42,101.31 85,100.72 85,100.54 84.8,100.34 84.62,100.34 84.03,100.92 83.84,100.92 83.65,100.73 83.65,100.54 84.24,99.95 84.24,99.78 84.03,99.57 83.85,99.57 83.27,100.16 83.08,100.16 82.88,99.97 82.88,99.78 83.47,99.19 83.47,99.01 83.27,98.81 83.09,98.81 82.5,99.39 82.31,99.39 82.12,99.2 82.12,99.01 82.7,98.43 82.7,98.24 82.51,98.05 82.32,98.05 81.18,99.19 81,99.19 80.79,98.98 80.79,98.8 81.93,97.66 81.93,97.47 81.74,97.28 81.55,97.28 80.5,98.33 80.32,98.33 80.11,98.13 80.11,97.95 81.17,96.9 81.17,96.71 80.27,95.81 78.35,95.81 77.42,94.87 77.42,79.84 83.54,73.72 83.54,73.03 86.53,70.04 v1(86.53,69.46)
  BOTTOM w0.076: UC1.AK61 92.61,109.04 92.47,109.17 92.37,109.22 92.23,109.22 92.21,109.22 92.13,109.18 92.08,109.15 91.87,109.15 91.71,109.22 91.53,109.22 91.27,108.97 91.19,108.97 90.94,108.72 89.06,108.72 v1(88.88,108.54)
  BOTTOM w0.102: v1(86.53,69.46) 86.87,69.12 87.05,69.12 87.35,69.42 87.35,69.6 86.8,70.15 JDIMM1.143
DDR_A_D7: length 74.2
  IN3 w0.084: 86.58,106.08 v1(87.3,106.8)
  IN3 w0.127: v1(85.3,59.94) 85.01,59.94 84.88,60.06 84.88,61.76 85.01,61.89 85.94,61.89 86.07,62.02 86.07,62.33 85.97,62.43 84.86,62.43 84.74,62.56 84.74,62.87 84.83,62.97 85.94,62.97 86.07,63.1 86.07,63.41 85.97,63.51 84.8,63.51 84.67,63.64 84.67,66.13 85.38,66.84 85.38,69.65 81.82,73.21 81.82,73.71 76.33,79.2 76.33,96.86 79.74,100.28 81.65,100.28 83.79,102.41 83.79,105.92 83.95,106.08 86.58,106.08
  BOTTOM w0.076: UC1.AK60 93.36,109.04 93.07,108.75 92.83,108.75 92.81,108.77 92.55,108.77 92.42,108.64 92,108.64 91.84,108.47 91.39,108.47 91.15,108.23 89.71,108.23 88.91,107.42 88.72,107.42 88.1,106.8 v1(87.3,106.8)
  BOTTOM w0.102: v1(85.3,59.94) 86.5,61.13 JDIMM1.142
DDR_A_D8: length 89
  IN1 w0.084: 87.57,105.46 87.72,105.61 88.51,105.61 88.64,105.48 v1(88.64,105.46)
  IN1 w0.127: v1(42.19,67.92) 41.78,68.34 41.78,74.88 41.9,75.01 42.34,75.01 42.47,75.13 42.47,75.39 42.34,75.52 41.94,75.52 41.81,75.64 41.81,75.9 41.94,76.02 42.34,76.02 42.47,76.15 42.47,76.4 42.34,76.53 42,76.53 41.88,76.66 41.88,76.91 42,77.04 42.34,77.04 42.47,77.17 42.47,77.42 42.34,77.55 42.01,77.55 41.89,77.67 41.89,77.93 42.01,78.06 42.57,78.06 42.7,78.18 42.7,82.58 44.51,84.39 44.69,84.39 45.15,83.93 45.33,83.93 45.51,84.11 45.51,84.29 45.05,84.75 45.05,84.93 45.23,85.11 45.41,85.11 45.87,84.65 46.05,84.65 46.23,84.83 46.23,85.01 45.77,85.47 45.77,85.65 45.95,85.83 46.13,85.83 46.59,85.36 46.77,85.36 61.04,99.63 61.4,99.63 61.95,100.19 74.22,100.19 75.67,101.64 76.41,101.64 76.53,101.76 76.53,102.08 76.41,102.21 76.09,102.21 75.96,102.33 75.96,103.32 79.48,106.84 82.47,106.84 83.86,105.46 87.57,105.46
  BOTTOM w0.076: v1(88.64,105.46) 88.64,106.05 89.37,106.77 89.37,107.08 90,107.72 91.34,107.72 91.47,107.85 UC1.AM63
  BOTTOM w0.102: v1(42.19,67.92) 43.6,69.33 JDIMM1.7
DDR_A_D9: length 90
  IN1 w0.084: 86.96,106.43 87.68,106.43 87.87,106.62 v1(88.43,106.62)
  IN1 w0.127: 86.96,106.43 84.14,106.43 83.05,107.52 79.19,107.52 75.28,103.6 75.28,103.07 73.1,100.9 61.69,100.9 61.11,100.32 60.75,100.32 48.17,87.73 46.88,87.73 42.02,82.87 42.02,79.03 41.09,78.1 41.09,67.94 41.34,67.69 41.34,67.22 41.34,64.78 42.68,63.45 42.68,60.53 v1(43.27,59.94)
  BOTTOM w0.076: UC1.AM62 92.06,107.85 91.77,108.14 91.53,108.14 91.27,107.89 89.93,107.89 89.2,107.15 89.2,106.84 88.98,106.62 v1(88.43,106.62)
  BOTTOM w0.102: v1(43.27,59.94) 42.7,60.51 JDIMM1.4
DDR_A_D10: length 88.2
  IN1 w0.084: v1(89.26,103.94) 89.25,103.94 87.99,103.94 87.12,103.07
  IN1 w0.127: 87.12,103.07 81.73,97.68 80.93,97.68 80.8,97.81 80.8,98.37 80.67,98.5 80.42,98.5 80.29,98.37 80.29,97.81 80.16,97.68 79.91,97.68 79.78,97.81 79.78,98.31 79.66,98.44 79.4,98.44 79.27,98.31 79.27,97.81 79.15,97.68 78.89,97.68 78.77,97.81 78.77,98.31 78.64,98.44 78.39,98.44 78.26,98.31 78.26,97.81 78.13,97.68 77.88,97.68 77.75,97.81 77.75,98.37 77.62,98.5 77.37,98.5 77.24,98.37 77.24,97.81 77.12,97.68 76.86,97.68 76.73,97.81 76.73,98.01 76.61,98.13 76.35,98.13 76.23,98.01 76.23,97.81 76.1,97.68 75.85,97.68 75.72,97.81 75.72,98.01 75.59,98.13 75.34,98.13 75.21,98.01 75.21,97.81 75.08,97.68 74.83,97.68 74.7,97.81 74.7,98.06 74.58,98.18 62.7,98.18 52.53,88 52.05,88 48.38,84.33 48.38,84.15 48.88,83.65 48.88,83.47 48.7,83.29 48.52,83.29 48.02,83.79 47.84,83.79 47.65,83.61 47.65,83.39 47.78,83.26 47.78,83.08 47.33,82.62 47.33,81.92 45.85,80.45 45.85,78.47 44.33,76.95 44.33,74.05 44.21,73.92 43.89,73.92 43.77,73.8 43.77,72.55 43.89,72.42 44.24,72.42 44.34,72.32 44.34,72.04 44.21,71.92 43.89,71.92 43.77,71.79 43.77,71.53 43.89,71.41 44.21,71.41 44.34,71.28 44.34,71.03 44.21,70.9 43.89,70.9 43.77,70.77 43.77,70.52 43.89,70.39 44.21,70.39 44.34,70.26 44.34,70.01 44.21,69.88 43.89,69.88 43.77,69.76 43.77,67.69 43.89,67.56 44.09,67.56 44.22,67.69 v1(44.22,67.92)
  BOTTOM w0.076: v1(89.26,103.94) 89.26,104.87 90.37,105.97 90.73,105.97 91.26,106.5 UC1.AP63
  BOTTOM w0.102: JDIMM1.17 46.6,70.3 v1(44.22,67.92)
DDR_A_D11: length 89.4
  IN1 w0.084: v1(89.66,104.33) 90.01,103.98 90.01,103.41 88.6,102 87.12,102
  IN1 w0.127: v1(46.57,61.46) 46.57,62.06 46.45,62.19 46.19,62.19 46.07,62.06 46.07,61.16 45.94,61.03 45.69,61.03 45.56,61.16 45.56,62.06 45.43,62.19 44.99,62.19 44.86,62.32 44.86,62.57 44.99,62.7 46.52,62.7 46.65,62.83 46.65,63.08 46.52,63.21 44.99,63.21 44.86,63.33 44.86,63.59 44.99,63.71 46.13,63.71 46.26,63.84 46.26,64.1 46.13,64.22 45.15,64.22 45.03,64.35 45.03,75.01 45.02,75.02 45.02,76.66 46.54,78.18 46.54,80.16 54.31,87.94 56.59,90.22 56.59,90.97 61.05,95.43 61.84,95.43 62.59,96.17 63.32,96.17 64.61,97.46 73.35,97.46 73.84,96.98 82.04,96.98 87.06,102 87.12,102
  BOTTOM w0.076: v1(89.66,104.33) 89.66,105.03 90.44,105.81 90.8,105.81 91.2,106.21 91.77,106.21 92.06,106.5 UC1.AP62
  BOTTOM w0.102: JDIMM1.18 46.9,61.79 v1(46.57,61.46)
DDR_A_D12: length 90.2
  IN1 w0.084: 86.96,105.87 88.45,105.87 89.18,106.6 89.18,106.82 88.99,107.02 v1(88.83,107.02)
  IN1 w0.127: v1(43.27,61.46) 43.27,63.79 42.85,64.21 42.85,64.93 42.73,65.05 42.27,65.05 42.14,65.18 42.14,65.43 42.27,65.56 43.02,65.56 43.15,65.69 43.15,65.94 43.02,66.07 41.81,66.07 41.68,66.2 41.68,67.83 41.43,68.08 41.43,77.96 42.36,78.88 42.36,82.72 47.02,87.39 48.31,87.39 60.89,99.97 61.25,99.97 61.82,100.54 73.47,100.54 75.62,102.69 75.62,103.46 79.34,107.18 82.62,107.18 83.93,105.87 86.96,105.87
  BOTTOM w0.076: v1(88.83,107.02) 88.83,107.02 89.87,108.05 91.2,108.05 91.46,108.31 91.84,108.31 92,108.14 92.42,108.14 92.82,107.75 UC1.AM61
  BOTTOM w0.102: JDIMM1.6 43.3,61.49 v1(43.27,61.46)
DDR_A_D13: length 91.3
  IN1 w0.084: v1(88.2,104.97) 87.53,104.97
  IN1 w0.127: v1(42.19,69.44) 42.25,69.5 42.25,74.43 42.81,74.99 42.81,77.58 43.04,77.81 43.04,78.46 43.22,78.64 43.87,78.64 44,78.76 44,79.02 43.87,79.14 43.17,79.14 43.04,79.27 43.04,79.53 43.17,79.65 44.2,79.65 44.33,79.78 44.33,80.03 44.2,80.16 43.21,80.16 43.08,80.29 43.08,80.54 43.21,80.67 44.2,80.67 44.33,80.8 44.33,81.05 44.2,81.18 43.21,81.18 43.08,81.3 43.08,81.56 43.21,81.68 44.75,81.68 44.88,81.81 44.88,82.07 44.75,82.19 43.31,82.19 43.19,82.32 43.19,82.57 43.31,82.7 44.59,82.7 51.82,89.93 52,89.93 52.07,89.87 52.25,89.87 52.43,90.05 52.43,90.23 52.36,90.29 52.36,90.47 52.54,90.65 52.72,90.65 52.78,90.59 52.96,90.59 53.14,90.77 53.14,90.95 53.08,91.01 53.08,91.19 53.26,91.37 53.44,91.37 53.5,91.31 53.68,91.31 53.86,91.49 53.86,91.67 53.8,91.73 53.8,91.91 53.98,92.09 54.16,92.09 54.22,92.03 54.4,92.03 54.58,92.21 54.58,92.39 54.52,92.45 54.52,92.63 54.7,92.81 54.88,92.81 54.94,92.75 55.12,92.75 55.3,92.93 55.3,93.11 55.24,93.17 55.24,93.35 55.42,93.53 55.6,93.53 55.66,93.47 55.84,93.47 56.02,93.64 56.02,93.82 55.96,93.89 55.96,94.07 56.14,94.25 56.32,94.25 56.38,94.18 56.56,94.18 56.74,94.36 56.74,94.54 56.68,94.6 56.68,94.78 56.86,94.96 57.04,94.96 57.1,94.9 57.28,94.9 57.46,95.08 57.46,95.26 57.4,95.32 57.4,95.5 58.16,96.27 58.34,96.27 58.4,96.21 58.58,96.21 58.76,96.39 58.76,96.57 58.7,96.63 58.7,96.81 58.88,96.99 59.06,96.99 59.12,96.93 59.3,96.93 59.48,97.11 59.48,97.29 59.42,97.35 59.42,97.53 60.26,98.36 60.44,98.36 60.5,98.3 60.68,98.3 60.86,98.48 60.86,98.66 60.8,98.72 60.8,98.9 61.18,99.29 61.66,99.29 62.21,99.83 74.4,99.83 75.58,101.01 76.5,101.01 77.43,100.09 81.98,100.09 84.33,102.43 86.86,104.97 87.53,104.97
  BOTTOM w0.076: v1(88.2,104.97) 88.89,104.97 90.23,106.3 90.59,106.3 91.25,106.96 91.75,106.96 91.91,106.88 92.04,106.88 92.2,106.96 92.4,106.96 92.45,106.93 92.54,106.89 92.56,106.88 93.4,106.88 93.6,107.09 UC1.AM60
  BOTTOM w0.102: JDIMM1.5 43,70.26 v1(42.19,69.44)
DDR_A_D14: length 89.5
  IN1 w0.084: 87.12,102.57 87.62,103.07 v1(88.4,103.07)
  IN1 w0.127: v1(44.22,69.44) 44.22,69.35 44.35,69.23 44.56,69.23 44.68,69.35 44.68,74.87 44.68,74.88 44.68,76.8 46.2,78.32 46.2,80.31 47.67,81.78 47.67,82.48 48.07,82.88 48.77,82.88 49.45,83.56 49.45,83.74 48.95,84.24 48.95,84.42 49.14,84.62 49.32,84.62 49.82,84.11 50,84.11 50.42,84.53 50.42,84.71 49.94,85.19 49.94,85.41 50.11,85.58 50.29,85.58 50.81,85.05 50.94,85.05 51.15,85.26 51.15,85.44 50.65,85.94 50.65,86.12 50.83,86.3 51.01,86.3 51.51,85.8 51.69,85.8 51.87,85.98 51.87,86.16 51.37,86.66 51.37,86.84 51.55,87.02 51.73,87.02 52.23,86.52 52.41,86.52 52.59,86.7 52.59,86.88 52.17,87.3 52.17,87.48 52.35,87.66 52.53,87.66 52.95,87.24 53.13,87.24 53.31,87.42 53.31,87.6 53.05,87.86 53.05,88.04 53.23,88.22 53.41,88.22 53.67,87.96 53.85,87.96 54.03,88.14 54.03,88.32 53.77,88.58 53.77,88.76 53.95,88.94 54.13,88.94 54.39,88.68 54.57,88.68 54.75,88.86 54.75,89.04 54.49,89.3 54.49,89.48 54.67,89.66 54.85,89.66 55.11,89.4 55.29,89.4 55.47,89.58 55.47,89.76 55.21,90.02 55.21,90.2 55.39,90.38 55.57,90.38 55.83,90.12 56.01,90.12 56.24,90.35 56.24,90.5 55.97,90.76 55.97,90.96 61.21,96.2 61.39,96.2 61.64,95.96 61.82,95.96 62,96.14 62,96.32 61.75,96.56 61.75,96.74 61.93,96.92 62.11,96.92 62.52,96.52 62.7,96.52 62.88,96.7 62.88,96.88 62.47,97.28 62.47,97.46 62.83,97.82 73.48,97.82 73.97,97.34 81.89,97.34 87.12,102.57
  BOTTOM w0.076: UC1.AP61 92.71,106.5 92.47,106.74 92.37,106.79 92.23,106.79 92.21,106.78 92.13,106.74 92.08,106.72 91.87,106.72 91.71,106.79 91.31,106.79 90.66,106.14 90.3,106.14 88.4,104.24 v1(88.4,103.07)
  BOTTOM w0.102: JDIMM1.15 46,70.37 45.08,69.44 v1(44.22,69.44)
DDR_A_D15: length 89.9
  IN1 w0.084: 87.12,101.57 87.22,101.66 88.5,101.66 90.29,103.45 90.29,104.5 v1(90.05,104.73)
  IN1 w0.127: 87.12,101.57 82.18,96.63 73.71,96.63 73.23,97.11 64.74,97.11 63.46,95.83 62.74,95.83 61.98,95.08 61.98,94.83 61.68,94.54 60.65,94.54 56.94,90.83 56.94,90.07 46.88,80.01 46.88,78.04 45.36,76.52 45.36,75.76 45.37,75.75 45.37,68.48 45.49,68.35 45.81,68.35 45.94,68.22 45.94,67.97 45.81,67.84 45.49,67.84 45.37,67.71 45.37,67.46 45.49,67.33 46.08,67.33 46.21,67.21 46.21,66.95 46.08,66.83 45.49,66.83 45.37,66.7 45.37,66.44 45.49,66.32 46.51,66.32 46.64,66.19 46.64,65.94 46.51,65.81 45.49,65.81 45.37,65.68 45.37,65.43 45.49,65.3 46.07,65.3 46.19,65.17 46.19,64.64 46.99,63.84 46.99,60.36 v1(46.57,59.94)
  BOTTOM w0.076: UC1.AP60 93.38,106.28 93.14,106.28 93.07,106.21 92.83,106.21 92.82,106.22 92.43,106.22 92.42,106.21 92,106.21 91.84,106.04 91.27,106.04 90.87,105.64 90.5,105.64 90.05,105.19 v1(90.05,104.73)
  BOTTOM w0.102: v1(46.57,59.94) 46.13,60.38 46.13,61.82 46.3,61.99 JDIMM1.16
DDR_A_D16: length 63.5
  IN3 w0.084: 89.04,99.65 89.04,99.81 90.15,100.93 90.31,100.93 92.86,103.49 92.86,104.28 93.17,104.58 94.14,104.58 94.81,105.26 94.81,106.28 94.72,106.37 v1(94.42,106.37)
  IN3 w0.127: 89.04,99.65 89.04,99.45 82.92,93.33 82.92,87.57 82.78,87.44 82.13,87.44 82.01,87.31 82.01,87.03 82.13,86.9 82.83,86.9 82.93,86.8 82.93,86.45 82.83,86.36 82.14,86.36 82.01,86.23 82.01,85.94 82.14,85.82 82.83,85.82 82.93,85.72 82.93,85.37 82.83,85.28 82.14,85.28 82.01,85.15 82.01,84.86 82.14,84.73 82.83,84.73 82.93,84.64 82.93,84.29 82.83,84.19 82.14,84.19 82.01,84.07 82.01,83.78 82.14,83.65 82.83,83.65 82.93,83.56 82.93,83.21 82.83,83.11 82.13,83.11 82.01,82.98 82.01,82.7 82.13,82.57 82.83,82.57 82.93,82.48 82.93,82.12 82.83,82.03 82.13,82.03 82,81.9 82,81.62 82.13,81.49 82.8,81.49 82.93,81.36 82.93,81.07 82.8,80.95 82.13,80.95 82,80.82 82,80.53 82.13,80.41 82.78,80.41 82.92,80.27 82.92,79.47 88.49,73.91 88.49,73.22 91.02,70.7 91.02,68.08 90.87,67.94 v1(90.59,67.94)
  BOTTOM w0.076: v1(94.42,106.37) 94.74,106.69 UC1.AP58
  BOTTOM w0.102: JDIMM1.159 91.6,68.94 v1(90.59,67.94)
DDR_A_D17: length 63.1
  IN3 w0.084: 88.67,99.65 88.67,99.72 89.02,100.07 89.02,100.16 88.67,100.52 88.67,100.69 88.84,100.86 89.02,100.86 89.26,100.62 89.44,100.62 89.59,100.78 89.59,100.96 88.99,101.56 88.99,101.74 90.24,102.98 90.42,102.98 91.08,102.32 91.26,102.32 91.43,102.49 91.43,102.67 90.75,103.34 90.75,103.52 90.92,103.69 91.1,103.69 91.8,102.99 91.98,102.99 92.15,103.15 92.15,103.33 91.46,104.02 91.46,104.2 91.63,104.36 91.81,104.36 92.35,103.83 92.52,103.83 92.69,104 92.69,104.18 92.42,104.45 92.42,104.66 92.71,104.95 93.09,104.95 93.25,104.79 93.58,104.79 94.06,105.26 94.44,105.26 94.57,105.39 94.57,105.59 94.44,105.72 v1(94.42,105.72)
  IN3 w0.127: v1(90.59,69.46) 90.59,70.57 88.12,73.04 88.12,73.75 82.56,79.32 82.56,79.89 82.45,80.01 81.87,80.01 81.65,80.23 81.65,87.68 81.78,87.8 82.43,87.8 82.56,87.93 82.56,88.22 82.43,88.34 81.78,88.34 81.65,88.47 81.65,88.76 81.78,88.88 82.43,88.88 82.56,89.01 82.56,89.3 82.43,89.43 81.78,89.43 81.65,89.55 81.65,89.84 81.78,89.97 82.43,89.97 82.56,90.09 82.56,90.38 82.43,90.51 81.78,90.51 81.65,90.63 81.65,90.92 81.78,91.05 82.43,91.05 82.56,91.18 82.56,91.46 82.43,91.59 81.78,91.59 81.65,91.72 81.65,92.12 81.78,92.24 82.43,92.24 82.56,92.37 82.56,93.48 88.67,99.6 88.67,99.65
  BOTTOM w0.076: v1(94.42,105.72) 94.74,106.04 UC1.AR58
  BOTTOM w0.102: v1(90.59,69.46) 91,69.87 JDIMM1.157
DDR_A_D18: length 65.4
  IN3 w0.084: v1(95.31,107.8) 94.94,108.16 94.94,108.73 94.58,109.09 94.25,109.09 93.66,108.5 93.66,108.48 91.3,106.12 90.56,106.12 87.12,102.69
  IN3 w0.127: v1(87.64,61.46) 88.07,61.88 88.07,66.1 88.2,66.24 88.74,66.24 88.87,66.37 88.87,66.65 88.74,66.78 88.2,66.78 88.07,66.91 88.07,69.93 84.54,73.45 84.54,74.13 78.42,80.25 78.42,94.46 78.77,94.8 80.69,94.8 82.98,97.1 86.94,101.06 86.94,102.5 87.12,102.69
  BOTTOM w0.076: v1(95.31,107.8) 95.51,107.99 UC1.AM57
  BOTTOM w0.102: JDIMM1.146 87.7,61.52 v1(87.64,61.46)
DDR_A_D19: length 67.4
  IN3 w0.084: v1(95.31,109.07) 95.12,109.26 94.18,109.26 93.49,108.57 93.49,108.55 91.23,106.3 90.22,106.3 87.12,103.2
  IN3 w0.127: 87.12,103.2 86.58,102.65 86.58,101.21 83.12,97.75 80.54,95.17 78.62,95.17 78.06,94.61 78.06,80.1 84.18,73.98 84.18,73.3 87.52,69.96 87.52,62.44 87.07,61.99 87.07,60.51 v1(87.64,59.94)
  BOTTOM w0.076: v1(95.31,109.07) 95.53,109.3 UC1.AK57
  BOTTOM w0.102: JDIMM1.148 88.3,60.59 v1(87.64,59.94)
DDR_A_D20: length 65.6
  IN3 w0.084: v1(94.41,108.15) 94.19,108.15 94.05,108 94.05,107.56 93.92,107.43 93.21,107.43 91.73,105.95 91.73,105.58 87.55,101.4 87.55,100.64
  IN3 w0.127: 87.55,100.64 80.14,93.23 80.14,89.64 80.01,89.51 79.72,89.51 79.59,89.38 79.59,89.1 79.72,88.97 80.01,88.97 80.14,88.84 80.14,88.5 80,88.36 79.28,88.36 79.15,88.23 79.15,87.96 79.28,87.82 80.01,87.82 80.14,87.69 80.14,87.41 80.01,87.28 79.28,87.28 79.15,87.14 79.15,86.87 79.28,86.74 80,86.74 80.14,86.6 80.14,86.33 80,86.2 79.28,86.2 79.15,86.06 79.15,85.79 79.28,85.66 80,85.66 80.14,85.52 80.14,85.25 80,85.12 79.28,85.12 79.15,84.98 79.15,84.71 79.28,84.57 80,84.57 80.14,84.44 80.14,84.17 80,84.03 79.28,84.03 79.15,83.9 79.15,83.63 79.28,83.49 80,83.49 80.14,83.36 80.14,83.09 80,82.95 79.28,82.95 79.15,82.82 79.15,82.55 79.28,82.41 80,82.41 80.14,82.28 80.14,82 80,81.87 79.28,81.87 79.15,81.73 79.15,81.46 79.28,81.33 80.01,81.33 80.14,81.2 80.14,80.91 80.01,80.79 79.34,80.79 79.21,80.66 79.21,80.48 79.45,80.25 80,80.25 80.14,80.11 80.14,79.57 86.11,73.6 86.11,72.92 89.07,69.95 v1(89.07,69.46)
  BOTTOM w0.089: v1(94.41,108.15) 94.87,108.6 UC1.AL58
  BOTTOM w0.102: JDIMM1.149 88.6,69.93 v1(89.07,69.46)
DDR_A_D21: length 66.7
  IN3 w0.084: v1(94.39,108.7) 94.23,108.7 91.55,106.03 91.55,105.65 87.34,101.43 87.34,100.94
  IN3 w0.127: 87.34,100.94 83.13,96.74 80.84,94.44 78.92,94.44 78.79,94.31 78.79,94.03 78.92,93.9 79.64,93.9 79.77,93.77 79.77,93.49 79.64,93.36 78.92,93.36 78.79,93.22 78.79,92.95 78.92,92.82 79.64,92.82 79.77,92.68 79.77,92.17 79.65,92.04 78.91,92.04 78.79,91.91 78.79,91.62 78.91,91.49 79.65,91.49 79.77,91.36 79.77,91.07 79.65,90.95 78.91,90.95 78.79,90.82 78.79,90.53 78.91,90.41 79.65,90.41 79.77,90.28 79.77,89.99 79.65,89.87 78.91,89.87 78.79,89.74 78.79,89.45 78.91,89.32 79.1,89.32 79.23,89.19 79.23,88.92 79.1,88.78 78.91,88.78 78.79,88.66 78.79,80.41 85.74,73.45 85.74,72.77 88.43,70.08 88.43,67.71 88.56,67.58 88.94,67.58 89.07,67.71 v1(89.07,67.94)
  BOTTOM w0.076: UC1.AK58 94.87,109.47 94.74,109.6 94.31,109.6 94.18,109.47 94.18,108.91 94.39,108.7 v1(94.39,108.7)
  BOTTOM w0.102: JDIMM1.147 88,69.01 v1(89.07,67.94)
DDR_A_D22: length 63.8
  IN3 w0.084: 89.91,99.65 91.23,100.97 95.37,105.11 v1(95.37,105.72)
  IN3 w0.127: 89.91,99.65 89.76,99.5 89.76,99.15 84.23,93.62 84.23,93 84.1,92.87 83.77,92.87 83.65,92.75 83.65,92.41 83.78,92.28 84.14,92.28 84.26,92.15 84.26,91.86 84.14,91.74 83.78,91.74 83.65,91.6 83.65,91.33 83.78,91.19 84.13,91.19 84.26,91.07 84.26,90.78 84.13,90.65 83.78,90.65 83.65,90.52 83.65,79.78 89.85,73.57 89.85,72.88 91.78,70.96 91.78,66.78 91.91,66.64 92.45,66.64 92.58,66.52 92.58,66.23 92.45,66.1 92.29,66.1 92.17,65.97 92.17,65.69 92.29,65.56 92.45,65.56 92.58,65.43 92.58,64.57 93.61,63.53 93.61,60.55 92.99,59.94 v1(91.26,59.94)
  BOTTOM w0.076: v1(95.37,105.72) 95.7,106.04 UC1.AR57
  BOTTOM w0.102: v1(91.26,59.94) 90.86,60.34 90.86,61.69 91.3,62.14 JDIMM1.158
DDR_A_D23: length 65.5
  IN3 w0.084: 89.4,99.66 89.9,100.15 89.97,100.15 90.46,100.65 93.42,103.6 93.44,103.6 94.99,105.14 94.99,106.63 v1(95.37,107.02)
  IN3 w0.127: 89.4,99.66 89.4,99.3 83.28,93.18 83.28,79.62 89.49,73.42 89.49,72.73 91.42,70.81 91.42,64.1 91.55,63.96 92.67,63.96 92.79,63.83 92.79,63.55 92.67,63.42 91.22,63.42 91.1,63.29 91.1,63.01 91.22,62.88 93.12,62.88 93.24,62.75 93.24,61.03 93.12,60.91 92.79,60.91 92.66,61.03 92.66,62.05 92.54,62.18 91.39,62.18 91.26,62.05 v1(91.26,61.46)
  BOTTOM w0.076: UC1.AN57 95.7,107.34 v1(95.37,107.02)
  BOTTOM w0.102: v1(91.26,61.46) 91.9,62.1 JDIMM1.160
DDR_A_D24: length 83.7
  IN1 w0.084: 87.12,99.66 88.1,100.63 88.51,100.63 92.51,104.64 95.08,104.64 95.93,105.49 95.93,105.98 v1(96.32,106.37)
  IN1 w0.127: 87.12,99.66 82.74,95.28 70.7,95.28 70.22,95.76 65.26,95.76 61.87,92.37 61.11,92.37 49.7,80.96 49.7,79.8 48.2,78.3 48.2,77.16 47.39,76.35 47.39,65.54 47.52,65.41 47.91,65.41 48.03,65.29 48.03,65.03 47.91,64.91 47.34,64.91 47.21,64.78 47.21,64.53 47.34,64.4 49,64.4 49.13,64.27 49.13,61.47 v1(49.11,61.46)
  BOTTOM w0.076: UC1.AP55 96.65,106.69 v1(96.32,106.37)
  BOTTOM w0.102: v1(49.11,61.46) 48.7,61.87 JDIMM1.24
DDR_A_D25: length 83.6
  IN1 w0.084: 87.62,99.65 88.24,100.28 88.25,100.28 88.26,100.29 88.43,100.29 92.58,104.44 95.13,104.44 96.32,105.64 v1(96.32,105.72)
  IN1 w0.127: 87.62,99.65 82.89,94.92 65.4,94.92 62.5,92.03 61.25,92.03 50.04,80.82 50.04,79.66 48.55,78.16 48.55,77.02 47.73,76.21 47.73,66.15 49.53,64.35 49.53,60.36 v1(49.11,59.94)
  BOTTOM w0.076: UC1.AR55 96.65,106.04 v1(96.32,105.72)
  BOTTOM w0.102: v1(49.11,59.94) 48.1,60.95 JDIMM1.22
DDR_A_D26: length 86.7
  IN1 w0.084: v1(97.28,107.67) 97.3,107.67 97.84,107.14 97.84,104.6 96.64,103.4 94.77,103.4 94.22,102.85 93.53,102.85 93.17,102.49 93.17,101.97 90.17,98.98
  IN1 w0.127: v1(51.53,59.94) 51.07,60.39 51.07,63.66 50.94,63.78 50.42,63.78 50.3,63.91 50.3,64.17 50.42,64.29 50.94,64.29 51.07,64.42 51.07,64.67 50.94,64.8 50.42,64.8 50.3,64.93 50.3,65.18 50.42,65.31 50.94,65.31 51.07,65.44 51.07,73.14 52.25,74.31 52.25,78.65 60.06,86.47 60.06,87.72 60.55,88.21 61.8,88.21 66.29,92.69 83.89,92.69 90.17,98.98
  BOTTOM w0.076: UC1.AM54 97.6,107.99 v1(97.28,107.67)
  BOTTOM w0.102: v1(51.53,59.94) 52.3,60.71 JDIMM1.36
DDR_A_D27: length 87.4
  IN1 w0.084: 90.17,98.45 91.04,98.45 91.82,99.23 91.82,99.38 93.85,101.4 93.96,101.4 94.88,102.32 94.88,102.65 95.46,103.22 96.71,103.22 98.01,104.52 98.01,107.21 97.76,107.46 97.76,108.44 v1(97.23,108.97)
  IN1 w0.127: 90.17,98.45 90.15,98.45 84.03,92.34 66.42,92.34 61.95,87.86 60.69,87.86 60.41,87.58 60.41,86.33 52.59,78.51 52.59,74.17 51.41,72.99 51.41,66.17 51.54,66.04 52.29,66.04 52.42,65.92 52.42,65.66 52.29,65.53 51.54,65.53 51.41,65.41 51.41,64.29 51.54,64.17 52.35,64.17 52.48,64.04 52.48,63.79 52.35,63.66 51.54,63.66 51.41,63.53 51.41,63.28 51.54,63.15 52.35,63.15 52.48,63.02 52.48,62.77 52.35,62.64 51.54,62.64 51.41,62.52 51.41,61.57 v1(51.53,61.46)
  BOTTOM w0.076: UC1.AK54 97.55,109.3 v1(97.23,108.97)
  BOTTOM w0.102: JDIMM1.34 51.7,61.59 51.57,61.46 v1(51.53,61.46)
DDR_A_D28: length 86.6
  IN1 w0.084: v1(96.32,108.32) 95.95,108.32 95.76,108.13 95.76,105.56 95.01,104.81 92.18,104.81 88.32,100.95 87.91,100.95 87.12,100.16
  IN1 w0.127: 87.12,100.16 82.59,95.64 70.83,95.64 70.35,96.12 65.13,96.12 61.72,92.71 60.96,92.71 49.05,80.8 49.05,80.47 49.35,80.16 49.35,79.98 49.19,79.82 49.01,79.82 48.8,80.03 48.62,80.03 48.44,79.85 48.44,79.67 48.63,79.48 48.63,79.22 47.86,78.45 47.86,77.31 47.05,76.49 47.05,75.42 46.92,75.29 46.47,75.29 46.35,75.17 46.35,74.91 46.47,74.79 46.92,74.79 47.05,74.66 47.05,74.4 46.92,74.28 46.47,74.28 46.35,74.15 46.35,73.9 46.47,73.77 46.92,73.77 47.05,73.64 47.05,73.39 46.92,73.26 46.47,73.26 46.35,73.13 46.35,72.55 46.47,72.42 46.92,72.42 47.05,72.3 47.05,72.04 46.92,71.92 46.47,71.92 46.35,71.79 46.35,71.53 46.47,71.41 46.92,71.41 47.05,71.28 47.05,71.03 46.92,70.9 46.47,70.9 46.35,70.77 46.35,70.52 46.47,70.39 46.92,70.39 47.05,70.26 47.05,67.69 46.92,67.56 46.75,67.56 46.63,67.69 v1(46.63,67.92)
  BOTTOM w0.076: UC1.AL55 96.65,108.64 v1(96.32,108.32)
  BOTTOM w0.102: v1(46.63,67.92) 48.05,69.34 48.05,69.99 48.4,70.34 JDIMM1.23
DDR_A_D29: length 86.8
  IN1 w0.084: v1(96.27,108.97) 96.74,108.97 96.87,109.1 96.87,109.39 96.74,109.52 95.03,109.52 94.91,109.39 94.91,105.3 94.59,104.98 92.11,104.98 88.42,101.29 87.75,101.29 87.12,100.67
  IN1 w0.127: 87.12,100.67 82.45,95.99 73.25,95.99 73.09,96.15 73.09,96.35 72.96,96.47 72.71,96.47 72.58,96.35 72.58,96.15 72.45,96.02 72.2,96.02 72.07,96.15 72.07,96.35 71.95,96.47 71.69,96.47 71.57,96.35 71.57,96.15 71.44,96.02 71.18,96.02 71.06,96.15 71.06,96.35 70.93,96.47 65,96.47 62.41,93.89 62.23,93.89 62.15,93.97 61.97,93.97 61.79,93.79 61.79,93.61 61.88,93.53 61.88,93.35 61.69,93.17 61.46,93.17 60.87,93.76 60.77,93.76 60.51,93.51 60.51,93.4 60.75,93.16 60.75,92.98 60.57,92.8 60.39,92.8 60.15,93.04 60.05,93.04 59.79,92.79 59.79,92.68 60.03,92.44 60.03,92.26 59.85,92.08 59.67,92.08 59.43,92.32 59.33,92.32 59.08,92.07 59.08,91.96 59.34,91.7 59.34,91.57 59.1,91.34 58.98,91.34 58.75,91.56 58.57,91.56 58.39,91.39 58.39,91.21 58.62,90.98 58.62,90.85 58.39,90.62 58.26,90.62 58.03,90.85 57.86,90.85 57.69,90.68 57.69,90.49 57.88,90.29 57.88,90.11 47.52,79.75 47.52,77.78 46,76.26 46,75.83 46,75.83 46,69.21 46.13,69.08 46.5,69.08 46.63,69.21 v1(46.63,69.44)
  BOTTOM w0.076: UC1.AK55 96.6,109.3 v1(96.27,108.97)
  BOTTOM w0.102: JDIMM1.21 47.8,70.62 v1(46.63,69.44)
DDR_A_D30: length 84.7
  IN1 w0.084: v1(97.28,105.72) 97.28,105.51 95.54,103.77 94.47,103.77 93.94,103.25 92.6,103.25 92.42,103.07 92.42,102.82 91.72,102.12 91.72,101.55 89.95,99.77
  IN1 w0.127: 89.95,99.77 83.58,93.4 66.03,93.4 62.94,90.32 61.69,90.32 54.07,82.69 54.07,82.52 54.51,82.08 54.51,81.89 54.28,81.65 54.1,81.65 53.65,82.1 53.47,82.1 53.29,81.92 53.29,81.74 53.74,81.29 53.74,81.11 53.56,80.93 53.38,80.93 52.93,81.38 52.75,81.38 52.58,81.2 52.58,81.02 53.02,80.57 53.02,80.39 52.84,80.21 52.66,80.21 52.22,80.66 52.04,80.66 51.86,80.48 51.86,80.3 52.3,79.86 52.3,79.68 51.56,78.93 51.56,75.64 51.43,75.51 49.38,75.51 49.25,75.39 49.25,75.13 49.38,75.01 51.43,75.01 51.56,74.88 51.56,74.61 51.43,74.49 49.38,74.49 49.25,74.36 49.25,74.09 49.38,73.96 50.37,73.96 50.49,73.84 50.49,73.53 50.37,73.4 49.38,73.4 49.25,73.28 49.25,72.98 49.38,72.86 49.61,72.86 50.31,72.16 v1(50.31,69.61)
  BOTTOM w0.076: UC1.AR54 97.6,106.04 v1(97.28,105.72)
  BOTTOM w0.102: v1(50.31,69.61) 51.02,69.61 51.4,69.99 JDIMM1.33
DDR_A_D31: length 86
  IN1 w0.084: 90.17,99.48 92.87,102.18 92.87,102.43 93.51,103.07 94.01,103.07 94.54,103.6 95.7,103.6 97.66,105.57 97.66,106.91 97.55,107.02 v1(97.28,107.02)
  IN1 w0.127: 90.17,99.48 83.74,93.05 66.16,93.05 63.08,89.97 61.83,89.97 61.34,89.48 61.34,89.3 61.56,89.09 61.56,88.91 61.38,88.73 61.2,88.73 60.98,88.95 60.8,88.95 59.16,87.3 59.16,87.15 59.62,86.69 59.62,86.51 59.43,86.32 59.25,86.32 58.79,86.78 58.64,86.78 58.61,86.75 58.43,86.56 58.43,86.41 58.89,85.95 58.89,85.77 58.7,85.59 58.52,85.59 58.06,86.04 57.91,86.04 57.69,85.83 57.69,85.68 58.15,85.22 58.15,85.04 57.96,84.85 57.78,84.85 57.32,85.31 57.17,85.31 56.97,85.11 56.95,85.09 56.95,84.94 57.41,84.48 57.41,84.3 57.22,84.11 57.04,84.11 56.58,84.57 56.44,84.57 56.34,84.48 56.22,84.35 56.22,84.2 56.68,83.74 56.68,83.56 56.49,83.38 56.31,83.38 55.86,83.83 55.69,83.83 55.44,83.57 55.44,83.41 55.89,82.96 55.89,82.78 55.69,82.58 55.51,82.58 55.06,83.03 54.9,83.03 54.68,82.81 54.68,82.65 55.12,82.2 55.12,82.01 52.42,79.31 51.9,78.79 51.9,74.46 50.73,73.28 50.73,68.01 50.6,67.89 50.43,67.89 50.31,68.01 v1(50.31,68.09)
  BOTTOM w0.076: v1(97.28,107.02) 97.6,107.34 UC1.AN54
  BOTTOM w0.102: v1(50.31,68.09) 52,69.78 JDIMM1.35
DDR_A_D32: length 54.8
  IN3 w0.084: v1(93.22,101.33) 93.16,101.27 92.63,101.27 90.62,99.26 90.62,98.31 90.43,98.11 90.43,97.87 90.17,97.62
  IN3 w0.127: 90.17,97.62 86.31,93.76 86.31,93.08 86.17,92.95 85.94,92.95 85.82,92.82 85.82,92.53 85.94,92.41 86.17,92.41 86.31,92.27 86.31,92 86.17,91.86 85.77,91.86 85.63,91.73 85.63,91.46 85.77,91.32 86.17,91.32 86.31,91.19 86.31,90.92 86.17,90.78 85.77,90.78 85.63,90.65 85.63,90.38 85.77,90.24 86.17,90.24 86.31,90.11 86.31,79.15 91.51,73.95 91.51,73.16 93.22,71.46 93.22,66.84 93.35,66.71 93.69,66.71 93.82,66.58 93.82,66.29 93.69,66.17 93.35,66.17 93.22,66.03 93.22,65.76 93.35,65.62 93.69,65.62 93.82,65.5 93.82,64.23 94.25,63.8 v1(94.25,61.46)
  BOTTOM w0.076: UC1.AY58 94.72,102.82 94.72,102.13 93.92,101.33 v1(93.22,101.33)
  BOTTOM w0.102: v1(94.25,61.46) 93.7,62.01 JDIMM1.166
DDR_A_D33: length 55.8
  IN3 w0.084: v1(93.81,101.77) 93.62,101.97 93.09,101.97 90.45,99.33 90.45,98.41 90.17,98.13
  IN3 w0.127: 90.17,98.13 85.27,93.23 85.27,89.88 85.4,89.74 85.82,89.74 85.94,89.62 85.94,89.33 85.82,89.2 85.4,89.2 85.27,89.07 85.27,88.8 85.4,88.66 85.82,88.66 85.94,88.53 85.94,88.25 85.82,88.12 85.4,88.12 85.27,87.99 85.27,87.71 85.4,87.58 85.82,87.58 85.94,87.45 85.94,87.17 85.82,87.04 85.4,87.04 85.27,86.9 85.27,86.63 85.4,86.5 85.82,86.5 85.94,86.37 85.94,86.08 85.82,85.96 85.4,85.96 85.27,85.82 85.27,85.55 85.4,85.42 85.82,85.42 85.94,85.29 85.94,85 85.82,84.87 85.4,84.87 85.27,84.74 85.27,84.47 85.4,84.33 85.82,84.33 85.94,84.21 85.94,83.92 85.82,83.79 85.4,83.79 85.27,83.66 85.27,83.3 85.4,83.17 85.82,83.17 85.94,83.05 85.94,82.76 85.82,82.63 85.4,82.63 85.27,82.5 85.27,82.22 85.4,82.09 85.82,82.09 85.94,81.96 85.94,79 91.15,73.79 91.15,73.01 92.85,71.31 92.85,67.96 92.73,67.83 92.53,67.83 v1(92.42,67.94)
  BOTTOM w0.076: v1(93.81,101.77) 93.84,101.74 93.99,101.74 94.55,102.3 94.55,103.29 UC1.AW58
  BOTTOM w0.102: JDIMM1.165 93.4,68.43 92.91,67.94 v1(92.42,67.94)
DDR_A_D34: length 55.7
  IN3 w0.084: 90.17,93.94 91.41,95.18 91.41,96.42 94.74,99.75 94.74,99.87 94.6,100.01 94.6,100.13 94.82,100.36 94.94,100.36 95,100.3 95.18,100.3 95.38,100.51 95.38,100.69 v1(95,101.07)
  IN3 w0.127: 90.17,93.94 88.91,92.68 88.91,81.42 92,78.32 92.19,78.32 92.97,79.1 93.16,79.1 93.36,78.91 93.36,78.72 92.58,77.94 92.58,77.75 92.77,77.56 92.96,77.56 93.74,78.34 93.93,78.34 94.12,78.14 94.12,77.95 93.34,77.17 93.34,76.98 93.54,76.79 93.73,76.79 94.5,77.57 94.69,77.57 94.89,77.38 94.89,77.19 94.11,76.41 94.11,76.22 94.3,76.03 94.49,76.03 95.27,76.8 95.46,76.8 95.65,76.61 95.65,76.42 94.87,75.64 94.87,75.45 95.16,75.17 95.35,75.17 96.04,75.85 96.22,75.85 96.42,75.64 96.42,75.47 95.72,74.77 95.72,74.6 96.42,73.91 96.42,70.27 96.55,70.14 96.74,70.14 96.87,70.01 96.87,69.59 96.74,69.46 v1(96.51,69.46)
  BOTTOM w0.076: UC1.AY56 96.19,102.75 96.17,102.73 96.17,101.75 95.34,100.91 95.16,100.91 v1(95,101.07)
  BOTTOM w0.102: JDIMM1.175 96.4,70.35 95.98,69.92 95.98,69.71 96.22,69.46 v1(96.51,69.46)
DDR_A_D35: length 56.5
  IN3 w0.084: 90.17,94.46 91.23,95.52 91.23,96.49 94.14,99.39 v1(94.14,100.2)
  IN3 w0.127: 90.17,94.46 88.54,92.83 88.54,81.05 95.89,73.7 95.89,69.46 96.08,69.26 96.08,66.88 96.21,66.75 96.75,66.75 96.88,66.63 96.88,66.34 96.75,66.22 96.28,66.22 96.16,66.09 96.16,65.8 96.28,65.68 96.75,65.68 96.88,65.55 96.88,60.06 96.75,59.94 v1(96.25,59.94)
  BOTTOM w0.076: UC1.AW56 96.19,103.35 96.48,103.05 96.48,102.81 96.34,102.66 96.34,101.68 94.86,100.2 v1(94.14,100.2)
  BOTTOM w0.102: JDIMM1.174 96.1,61.89 95.84,61.63 95.84,60.34 v1(96.25,59.94)
DDR_A_D36: length 56.2
  IN3 w0.127: v1(93.54,102.34) 93.38,102.5 93.2,102.5 90.17,99.47 90.17,98.65 84.91,93.38 84.91,90.21 84.77,90.08 84.42,90.08 84.29,89.94 84.29,89.67 84.42,89.54 84.77,89.54 84.91,89.4 84.91,89.13 84.77,89 84.42,89 84.29,88.86 84.29,88.59 84.42,88.46 84.77,88.46 84.91,88.32 84.91,88.05 84.77,87.91 84.42,87.91 84.29,87.78 84.29,87.51 84.42,87.37 84.77,87.37 84.91,87.24 84.91,86.97 84.77,86.83 84.42,86.83 84.29,86.7 84.29,86.43 84.42,86.29 84.77,86.29 84.91,86.16 84.91,85.89 84.77,85.75 84.42,85.75 84.29,85.62 84.29,85.34 84.42,85.21 84.77,85.21 84.91,85.08 84.91,84.8 84.77,84.67 84.42,84.67 84.29,84.53 84.29,84.26 84.42,84.13 84.77,84.13 84.91,83.99 84.91,83.72 84.77,83.59 84.42,83.59 84.29,83.45 84.29,83.18 84.42,83.05 84.77,83.05 84.91,82.91 84.91,82.4 84.8,82.29 84.42,82.29 84.29,82.17 84.29,81.85 84.42,81.73 85.45,81.73 85.58,81.6 85.58,81.31 85.45,81.19 84.42,81.19 84.29,81.06 84.29,80.78 84.42,80.66 85.45,80.66 85.58,80.53 85.58,80.24 85.45,80.11 84.78,80.11 84.65,79.98 84.65,79.68 84.78,79.55 85.49,79.55 85.58,79.46 85.58,78.85 90.79,73.64 90.79,72.86 92.42,71.23 v1(92.42,69.46)
  BOTTOM w0.076: v1(93.54,102.34) 93.86,102.66 93.86,103.07 94.62,103.83 94.62,104.01 UC1.AV58
  BOTTOM w0.102: v1(92.42,69.46) 92.8,69.84 JDIMM1.163
DDR_A_D37: length 58
  IN3 w0.084: v1(91,98.98) 91,98.37 90.62,98 90.62,97.56 90.17,97.11
  IN3 w0.127: 90.17,97.11 86.67,93.61 86.67,79.3 91.88,74.1 91.88,73.31 93.58,71.61 93.58,67.66 94.18,67.05 94.18,64.38 94.67,63.89 94.67,60.36 v1(94.25,59.94)
  BOTTOM w0.076: v1(91,98.98) 92.31,98.98 95.25,101.93 95.65,101.93 95.84,102.12 95.84,102.64 95.73,102.74 95.73,103.04 95.81,103.19 95.81,103.32 95.73,103.48 95.73,103.69 95.76,103.74 95.8,103.83 95.81,103.84 95.81,104.03 95.79,104.04 95.79,104.42 95.84,104.47 95.84,104.65 95.6,104.88 UC1.AU58
  BOTTOM w0.102: v1(94.25,59.94) 93.1,61.08 JDIMM1.164
DDR_A_D38: length 57.2
  IN3 w0.084: 90.4,93.66 91.68,94.94 91.68,96.45 95.71,100.47 95.71,101.22 v1(95.4,101.53)
  IN3 w0.127: v1(96.51,67.94) 96.68,67.77 97.12,67.77 97.23,67.87 97.23,70.74 96.78,71.19 96.78,76 93.05,79.73 92.86,79.73 92.08,78.94 91.9,78.94 91.7,79.15 91.7,79.33 92.48,80.11 92.48,80.3 92.29,80.49 92.1,80.49 91.41,79.8 91.23,79.8 91.03,80.01 91.03,80.19 91.71,80.87 91.71,81.06 91.52,81.26 91.33,81.26 90.61,80.54 90.42,80.54 90.23,80.73 90.23,80.92 90.95,81.64 90.95,81.83 90.76,82.02 90.57,82.02 89.84,81.3 89.65,81.3 89.46,81.49 89.46,81.68 90.18,82.41 90.18,82.6 89.93,82.85 89.78,82.85 89.64,82.71 89.4,82.71 89.27,82.84 89.27,83.13 89.36,83.22 89.36,83.45 89.27,83.54 89.27,92.53 90.4,93.66
  BOTTOM w0.076: UC1.AV56 96.08,103.89 95.95,103.75 95.92,103.7 95.9,103.65 95.9,103.52 95.91,103.5 95.95,103.41 95.97,103.36 95.97,103.13 95.95,103.1 95.9,103 95.9,102.81 96.01,102.71 96.01,101.81 95.72,101.53 v1(95.4,101.53)
  BOTTOM w0.102: JDIMM1.177 97,68.43 v1(96.51,67.94)
DDR_A_D39: length 58.2
  IN3 w0.084: 90.17,94.97 90.93,95.73 90.93,96.43 93.71,99.21 v1(93.71,99.77)
  IN3 w0.127: v1(96.25,61.46) 95.57,61.46 95.44,61.59 95.44,62.15 95.57,62.27 96.38,62.27 96.51,62.41 96.51,62.68 96.38,62.81 95.56,62.81 95.43,62.94 95.43,63.23 95.56,63.36 96.38,63.36 96.51,63.49 96.51,63.76 96.38,63.9 95.86,63.9 95.72,64.03 95.72,64.3 95.86,64.44 96.38,64.44 96.51,64.57 96.51,64.84 96.38,64.98 95.86,64.98 95.72,65.11 95.72,69.11 95.53,69.31 95.53,73.55 88.18,80.9 88.18,92.98 90.17,94.97
  BOTTOM w0.076: UC1.AU56 96.08,104.65 96.38,104.35 96.38,104.11 96.37,104.11 96.37,103.82 96.65,103.54 96.65,102.74 96.5,102.6 96.5,101.61 94.66,99.77 v1(93.71,99.77)
  BOTTOM w0.102: v1(96.25,61.46) 96.7,61.91 JDIMM1.176
DDR_A_D40: length 71.3
  IN1 w0.084: 90.17,97.58 90.18,97.59 v1(91.48,97.59)
  IN1 w0.127: v1(52.9,66.4) 52.13,67.16 52.13,72.82 53.23,73.91 53.23,78.25 61.05,86.07 66.68,91.7 84.3,91.7 84.67,92.07 90.17,97.58
  BOTTOM w0.076: UC1.AY54 97.14,102.81 97.14,102.54 97,102.39 97,101.39 96.72,101.12
  BOTTOM w0.089: 96.72,101.12 93.19,97.59 v1(91.48,97.59)
  BOTTOM w0.102: v1(52.9,66.4) 54.1,65.19 JDIMM1.42
DDR_A_D41: length 71.6
  IN1 w0.084: v1(92.37,98.48) 92.37,97.92 91.52,97.08 90.18,97.08 90.17,97.07
  IN1 w0.127: 90.17,97.07 83.91,90.82 78.13,90.82 78,90.94 78,91.22 77.88,91.35 77.62,91.35 77.5,91.22 77.5,90.94 77.37,90.82 77.11,90.82 76.99,90.94 76.99,91.22 76.86,91.35 66.81,91.35 61.39,85.93 53.57,78.1 53.57,72.92 52.48,71.83 52.48,68.34 v1(52.9,67.92)
  BOTTOM w0.076: UC1.AW54 97.27,103.35 96.98,103.05 96.98,102.61 96.83,102.46 96.83,101.47 93.84,98.48 v1(92.37,98.48)
  BOTTOM w0.102: v1(52.9,67.92) 52.93,67.92 53.8,68.79 JDIMM1.41
DDR_A_D42: length 71.3
  IN1 w0.084: 90.52,93.66 92.61,95.75 92.61,96.52 94.35,98.26 v1(94.99,98.26)
  IN1 w0.127: 90.52,93.66 85.04,88.18 68.47,88.18 64.26,83.96 63.04,83.96 62.73,83.66 57.13,78.06 57.13,77.89 57.59,77.44 57.59,77.31 57.34,77.07 57.22,77.07 56.77,77.52 56.59,77.52 56.38,77.31 56.38,77.13 56.8,76.72 56.8,76.52 56.12,75.84 56.12,69.77 56.11,69.76 56.11,69.13 56.12,69.12 56.12,69.01 56.11,69 56.11,68.37 56.12,68.36 56.12,66.81 56.53,66.4 v1(56.87,66.4)
  BOTTOM w0.076: v1(94.99,98.26) 95.66,98.26 95.96,98.56 96.19,98.56 98.47,100.84 98.47,102.31 98.49,102.33 98.49,102.81 UC1.AY52
  BOTTOM w0.102: JDIMM1.50 56.5,64.25 56.35,64.4 56.35,65.88 v1(56.87,66.4)
DDR_A_D43: length 72.4
  IN1 w0.084: v1(94.07,97.34) 94.07,96.78 94.01,96.72 94.01,96.14 91.53,93.66
  IN1 w0.127: v1(56.87,69.44) 57.15,69.44 57.27,69.57 57.27,70.05 57.15,70.18 56.93,70.18 56.8,70.31 56.8,70.64 56.93,70.77 57.15,70.77 57.27,70.9 57.27,71.15 57.15,71.28 56.93,71.28 56.8,71.41 56.8,71.66 56.93,71.79 57.15,71.79 57.27,71.91 57.27,72.17 57.15,72.3 56.93,72.3 56.8,72.42 56.8,73.27 56.93,73.4 57.15,73.4 57.27,73.53 57.27,73.78 57.15,73.91 56.93,73.91 56.8,74.03 56.8,74.29 56.93,74.42 57.15,74.42 57.27,74.54 57.27,76.03 61.23,79.98 61.23,80.16 60.81,80.58 60.81,80.76 60.99,80.94 61.17,80.94 61.59,80.52 61.77,80.52 61.95,80.7 61.95,80.88 61.53,81.3 61.53,81.48 61.71,81.66 61.89,81.66 62.31,81.24 62.49,81.24 62.67,81.42 62.67,81.6 62.24,82.02 62.24,82.2 62.42,82.38 62.6,82.38 63.03,81.96 63.2,81.96 63.38,82.14 63.38,82.32 62.96,82.74 62.96,82.92 63.14,83.1 63.32,83.1 63.74,82.68 63.92,82.68 64.51,83.26 64.52,83.26 68.73,87.47 85.33,87.47 91.53,93.66
  BOTTOM w0.076: v1(94.07,97.34) 95.21,97.34 98.64,100.77 98.64,102.24 98.66,102.26 98.66,102.55 98.91,102.81 98.91,103 98.87,103.1 98.86,103.1 98.84,103.16 98.84,103.36 UC1.AW52
  BOTTOM w0.102: v1(56.87,69.44) 56.8,69.52 JDIMM1.51
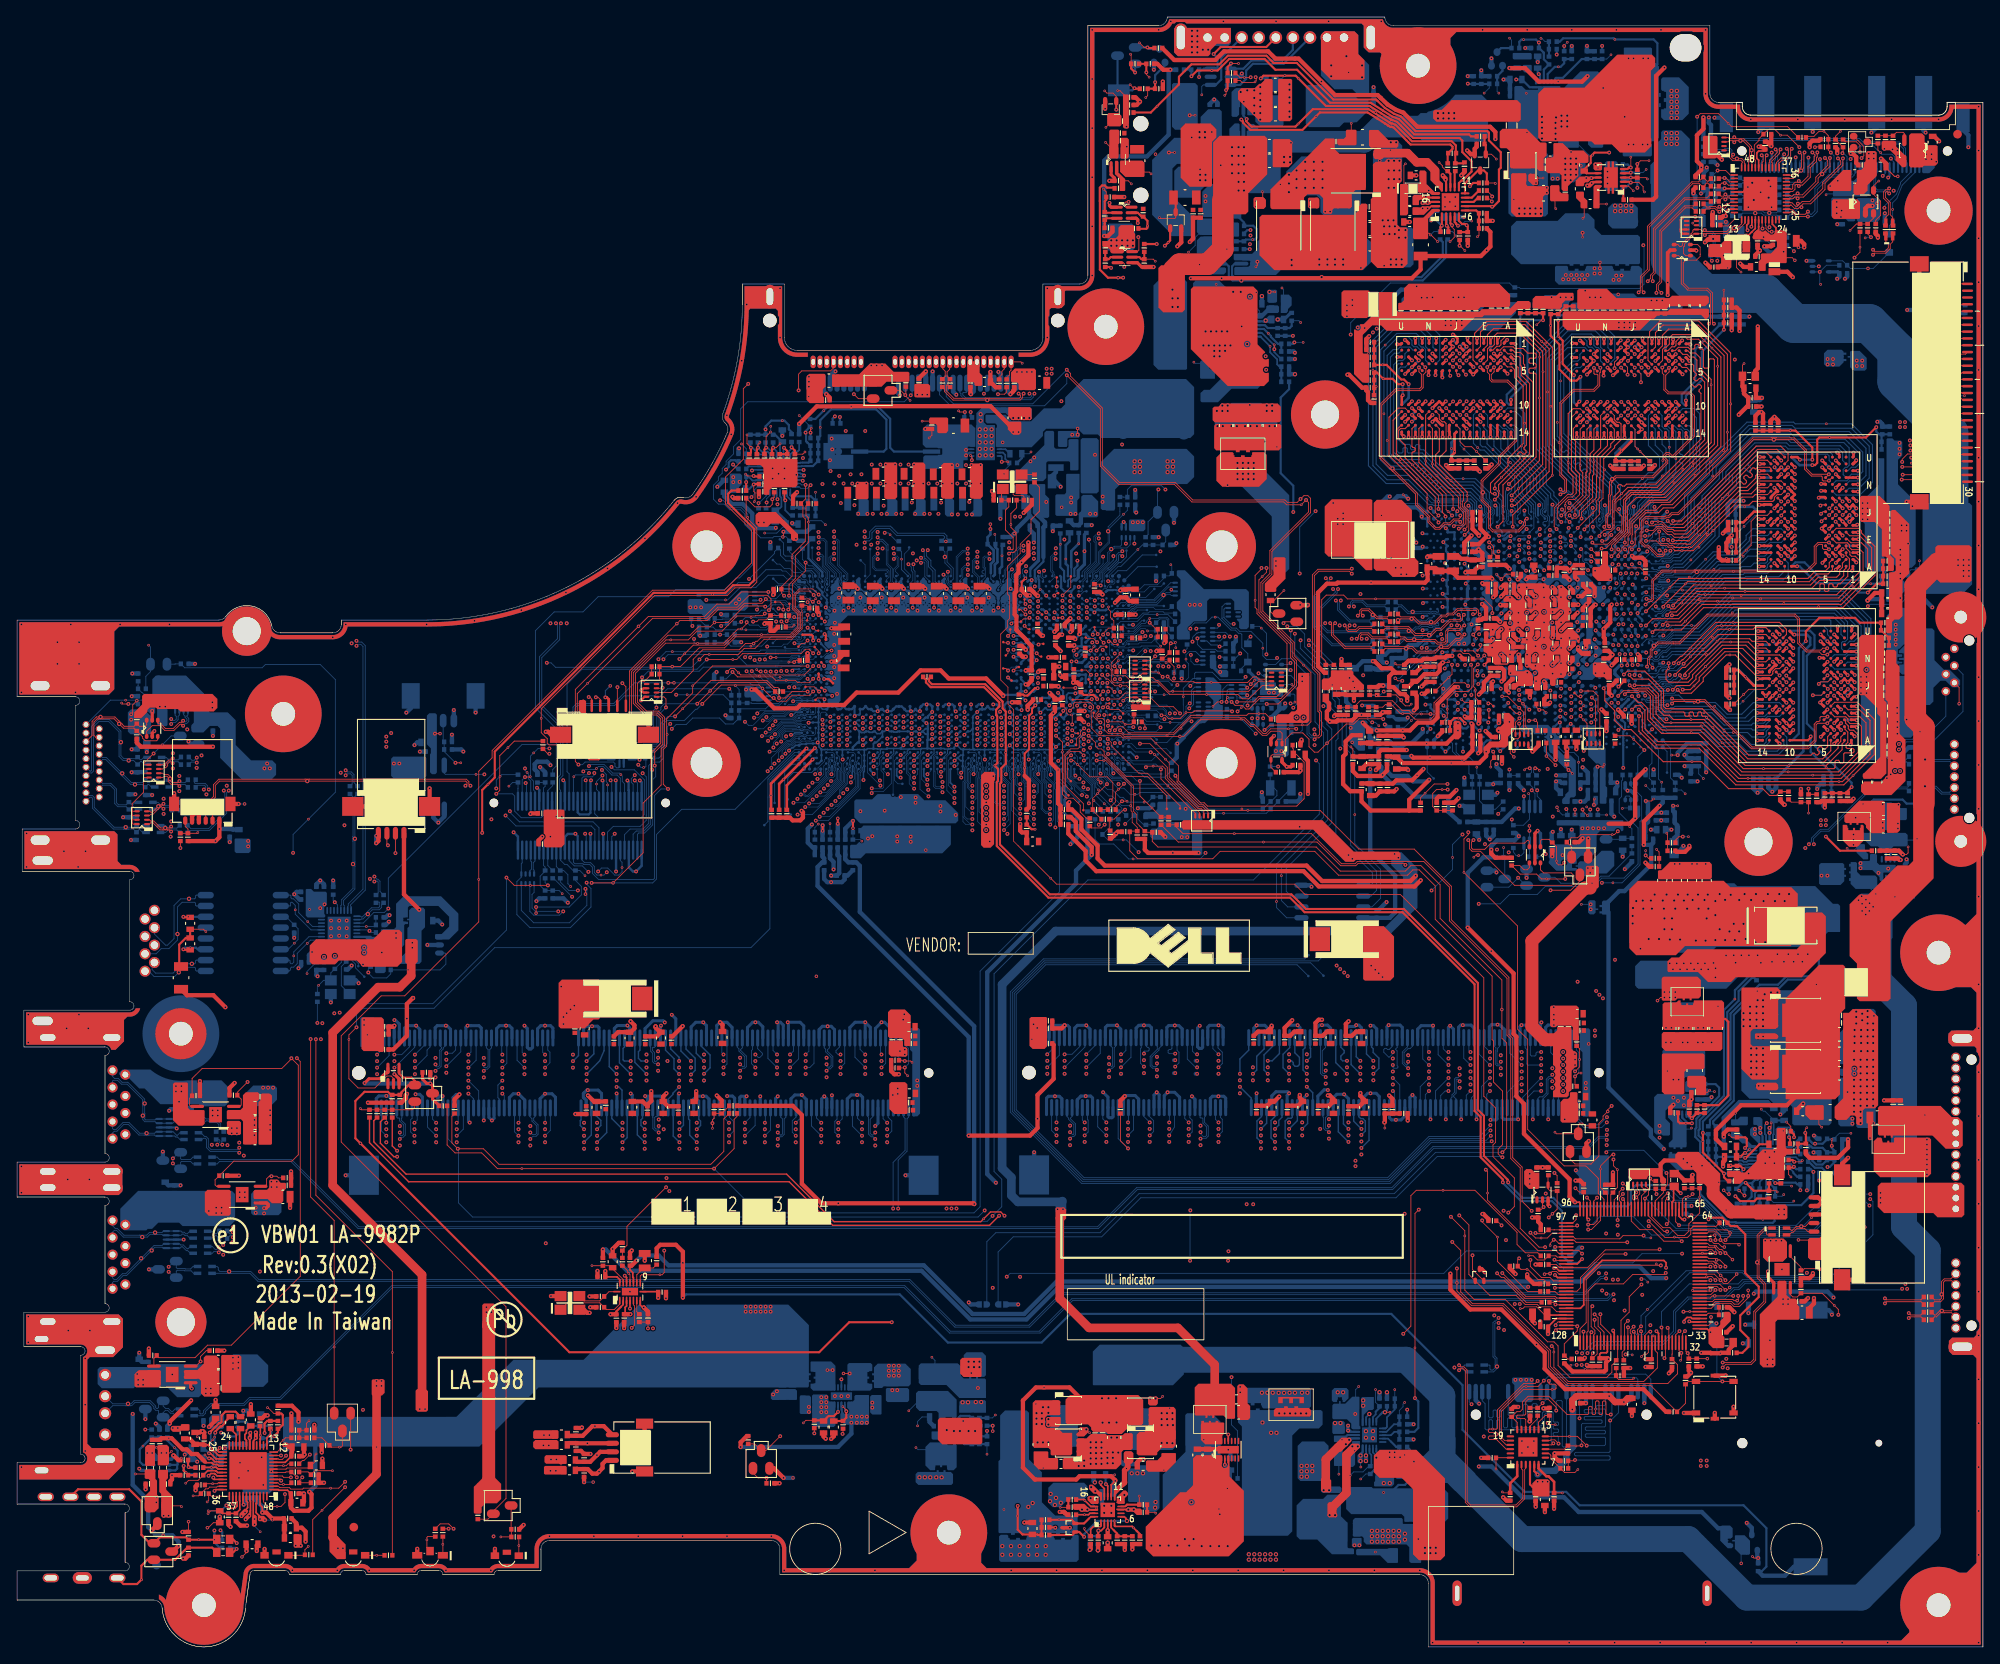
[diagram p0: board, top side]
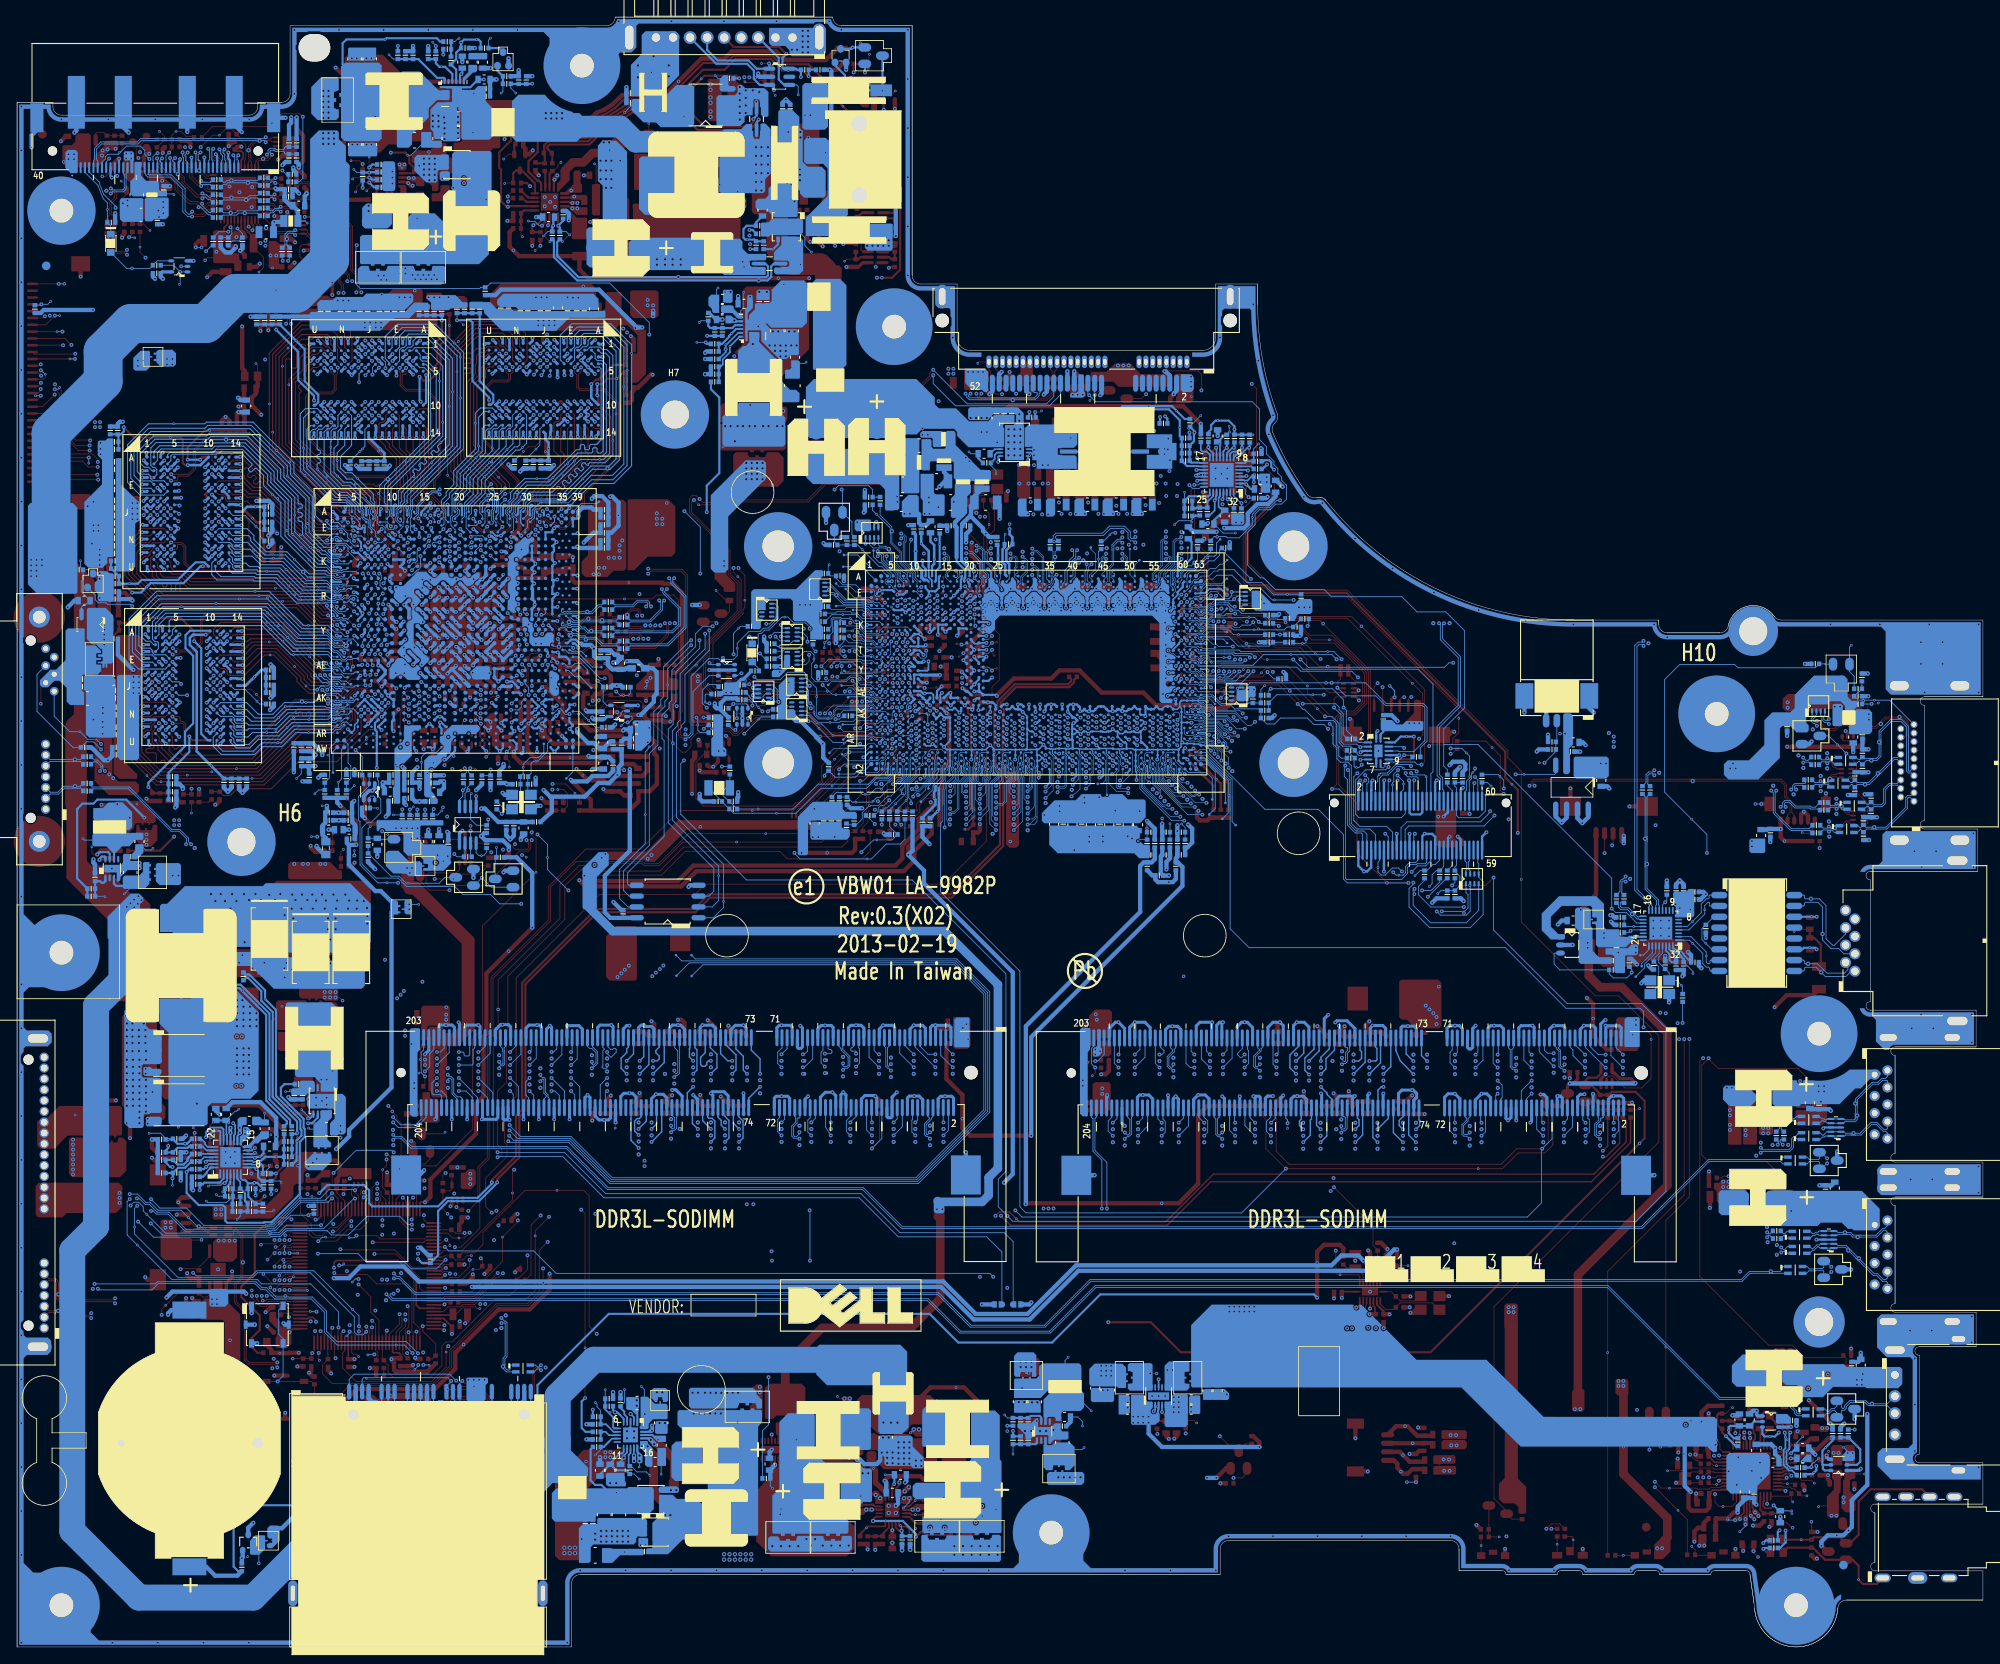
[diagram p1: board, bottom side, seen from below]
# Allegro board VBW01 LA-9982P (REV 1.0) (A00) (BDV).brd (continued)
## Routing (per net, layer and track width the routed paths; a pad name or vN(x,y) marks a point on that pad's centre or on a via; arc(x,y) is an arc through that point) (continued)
DDR_A_D44: length 72.8
  IN1 w0.084: v1(92.83,98.9) 92.83,98.14 91.47,96.78 90.39,96.78 90.17,96.57
  IN1 w0.127: 90.17,96.57 84.01,90.41 76.65,90.41 76.52,90.54 76.52,90.88 76.39,91 76.14,91 76.01,90.88 76.01,90.54 75.88,90.41 75.63,90.41 75.5,90.54 75.5,90.88 75.38,91 75.12,91 74.99,90.88 74.99,90.54 74.87,90.41 74.61,90.41 74.49,90.54 74.49,90.88 74.36,91 74.11,91 73.98,90.88 73.98,90.54 73.85,90.41 73.6,90.41 73.47,90.54 73.47,90.88 73.34,91 73.09,91 72.96,90.88 72.96,90.54 72.84,90.41 66.36,90.41 61.74,85.79 53.91,77.96 53.91,71.89 53.81,71.79 52.99,71.79 52.86,71.67 52.86,71.4 52.99,71.27 53.81,71.27 53.91,71.18 53.91,70.85 53.81,70.75 53.02,70.75 52.9,70.63 v1(52.9,69.44)
  BOTTOM w0.076: UC1.AV54 97.38,104.1 96.81,103.54 96.81,102.67 96.67,102.53 96.67,101.54 94.03,98.9 v1(92.83,98.9)
  BOTTOM w0.102: v1(52.9,69.44) 53.2,69.75 JDIMM1.39
DDR_A_D45: length 73.1
  IN1 w0.084: 90.17,96.07 90.58,96.47 91.46,96.47 96.35,101.36 v1(97.72,101.36)
  IN1 w0.127: v1(52.9,64.87) 53.37,65.35 53.37,69.63 54.25,70.51 54.25,70.53 54.25,70.54 54.25,77.82 62.08,85.64 66.49,90.06 67.71,90.06 67.71,90.06 68.97,90.06 84.16,90.06 90.17,96.07
  BOTTOM w0.076: UC1.AU54 98.03,104.88 98.24,104.68 98.24,103.84 98.23,103.83 98.19,103.74 98.16,103.69 98.16,103.48 98.24,103.32 98.24,103.19 98.19,103.09 98.16,103.04 98.16,102.52 98.14,102.5 98.14,101.78 v1(97.72,101.36)
  BOTTOM w0.102: v1(52.9,64.87) 53.5,64.27 JDIMM1.40
DDR_A_D46: length 72.7
  IN1 w0.084: v1(95.45,98.72) 94.55,98.72 92.43,96.61 92.43,96.08 90.17,93.81
  IN1 w0.127: 90.17,93.81 84.89,88.53 68.34,88.53 64.12,84.31 62.9,84.31 55.78,77.19 55.78,69.91 55.77,69.9 55.77,68.22 55.78,68.22 55.78,66.04 55.9,65.91 56.21,65.91 56.34,65.79 56.34,65.52 56.21,65.39 55.59,65.39 55.46,65.27 55.46,65 55.59,64.87 v1(56.87,64.87)
  BOTTOM w0.076: v1(95.45,98.72) 96.12,98.72 98.31,100.91 98.31,102.37 98.33,102.39 98.33,103 98.38,103.1 98.4,103.16 98.4,103.36 98.38,103.41 98.38,103.41 98.34,103.5 98.33,103.52 98.33,103.65 98.35,103.7 98.38,103.75 98.52,103.89 UC1.AV52
  BOTTOM w0.102: JDIMM1.52 57.1,64.65 v1(56.87,64.87)
DDR_A_D47: length 73.8
  IN1 w0.084: v1(93.61,96.88) 93.61,96.25 91.02,93.66
  IN1 w0.127: 91.02,93.66 85.19,87.82 68.6,87.82 64.4,83.62 63.18,83.62 60.1,80.54 60.1,80.34 60.26,80.17 60.26,79.99 60.02,79.75 59.84,79.75 59.67,79.93 59.49,79.93 59.31,79.75 59.31,79.57 59.73,79.15 59.73,78.97 59.55,78.79 59.37,78.79 58.95,79.21 58.77,79.21 58.59,79.03 58.59,78.85 59.01,78.43 59.01,78.25 58.83,78.07 58.65,78.07 58.23,78.49 58.05,78.49 57.87,78.31 57.87,78.13 58.29,77.71 58.29,77.53 56.46,75.7 56.46,69.62 56.46,69.62 56.46,69.27 56.46,69.26 56.46,68.86 56.46,68.86 56.46,68.51 56.46,68.5 56.46,68.33 v1(56.87,67.92)
  BOTTOM w0.076: UC1.AU52 99.01,104.5 99.01,103.19 99.05,103.09 99.08,103.03 99.08,102.74 98.83,102.49 98.83,102.19 98.8,102.17 98.8,100.63
  BOTTOM w0.089: 98.8,100.63 95.06,96.88 v1(93.61,96.88)
  BOTTOM w0.102: JDIMM1.53 57.4,68.45 v1(56.87,67.92)
DDR_A_D48: length 85.7
  IN1 w0.084: 96.3,93.66 96.3,93.89 102.77,100.37 102.77,104.37 103.37,104.97 106.14,104.97 106.47,105.3 106.47,107.75 105.76,108.47 v1(105.76,108.97)
  IN1 w0.127: 96.3,93.66 96.3,92.36 87.11,83.18 71.34,83.18 64.92,76.76 64.92,75.4 63.57,74.05 63.57,72.46 63.18,72.07 63.18,66.62 63.31,66.49 63.85,66.49 63.97,66.36 63.97,66.11 63.85,65.98 63.31,65.98 63.18,65.85 63.18,65.6 63.31,65.47 63.85,65.47 63.97,65.35 63.97,65.09 63.85,64.96 63.31,64.96 63.18,64.84 63.18,64.21 63.06,64.08 62.45,64.08 62.32,64.21 62.32,67.48 v1(61.88,67.92)
  BOTTOM w0.076: UC1.AK40 106.08,109.3 v1(105.76,108.97)
  BOTTOM w0.102: JDIMM1.69 62.2,69.98 62.45,69.73 62.45,68.49 v1(61.88,67.92)
DDR_A_D49: length 85.4
  IN1 w0.084: 95.94,93.66 95.94,93.83 96.1,93.99 96.15,93.99 102.6,100.44 102.6,104.44 103.3,105.14 106.07,105.14 106.3,105.37 106.3,107.68 105.83,108.15 105.71,108.15 v1(104.84,109.02)
  IN1 w0.127: v1(61.88,69.44) 62.3,69.03 62.3,68.53 62.42,68.4 62.7,68.4 62.83,68.53 62.83,69.77 62.7,69.9 62.39,69.9 62.26,70.02 62.26,70.28 62.39,70.4 62.7,70.4 62.83,70.53 62.83,70.78 62.7,70.91 61.93,70.91 61.8,71.04 61.8,71.29 61.93,71.42 62.7,71.42 62.83,71.55 62.83,71.8 62.7,71.93 61.97,71.93 61.84,72.05 61.84,72.31 61.97,72.44 63.06,72.44 63.19,72.56 63.19,72.82 63.06,72.94 62.36,72.94 62.23,73.07 62.23,73.32 62.36,73.45 63.1,73.45 63.22,73.58 63.22,73.83 63.1,73.96 62.2,73.96 62.07,74.09 62.07,74.43 62.2,74.56 62.45,74.56 62.58,74.69 62.58,74.87 62.74,75.04 62.92,75.04 63.44,74.52 63.55,74.52 63.78,74.75 63.78,74.92 63.29,75.41 63.29,75.59 63.47,75.77 63.65,75.77 64.14,75.28 64.32,75.28 64.55,75.52 64.55,75.7 64.04,76.21 64.04,76.38 71.18,83.52 86.95,83.52 95.94,92.51 95.94,93.66
  BOTTOM w0.076: UC1.AK42 105.12,109.3 v1(104.84,109.02)
  BOTTOM w0.102: JDIMM1.67 61.6,69.72 v1(61.88,69.44)
DDR_A_D50: length 82.9
  IN1 w0.084: v1(103.89,107.8) 103.64,107.55 103.39,107.55 103.14,107.3 102.7,107.3 102.3,106.9 101.64,106.9 101.5,106.76 101.07,106.76 100.64,106.33 100.64,105.37 99.93,104.65 99.93,101.43 99.22,100.72 99.22,100.14 95.72,96.64 95.72,95.82 93.65,93.74 93.65,93.66
  IN1 w0.127: 93.65,93.66 93.65,93.37 86.01,85.73 70.23,85.73 69.86,85.36 69.86,85.36 65.9,81.4 65.76,81.4 65.46,81.7 65.31,81.7 65.09,81.47 65.09,81.33 65.39,81.03 65.39,80.89 65.02,80.52 64.87,80.52 64.59,80.81 64.42,80.81 64.22,80.6 64.22,80.44 64.51,80.15 64.51,80.01 64.28,79.78 64.14,79.78 63.85,80.07 63.71,80.07 63.48,79.85 63.48,79.7 63.77,79.41 63.77,79.27 63.54,79.04 63.4,79.04 63.11,79.33 62.93,79.33 62.74,79.14 62.74,78.97 63.03,78.68 63.03,78.53 62.81,78.31 62.66,78.31 62.38,78.6 62.2,78.6 62.01,78.41 62.01,78.23 62.3,77.94 62.3,77.8 62.07,77.57 61.93,77.57 61.64,77.86 61.46,77.86 61.34,77.74 61.27,77.67 61.27,77.49 61.56,77.2 61.56,77.06 61.34,76.84 61.19,76.84 60.9,77.12 60.72,77.12 60.54,76.93 60.54,76.76 60.82,76.47 60.82,76.32 60.6,76.1 60.46,76.1 60.17,76.39 60,76.39 59.8,76.18 59.8,76.02 60.09,75.73 60.09,75.59 59.59,75.09 59.59,74.62 59.46,74.5 59.08,74.5 58.96,74.37 58.96,74.02 59.08,73.89 59.47,73.89 59.59,73.77 59.59,73.5 59.47,73.37 59.06,73.37 58.94,73.25 58.94,72.55 59.06,72.43 59.47,72.43 59.59,72.3 59.59,72.08 59.47,71.96 59.06,71.96 58.94,71.83 58.94,71.58 59.06,71.45 59.47,71.45 59.59,71.32 59.59,71.07 59.47,70.94 59.06,70.94 58.94,70.81 58.94,70.56 59.06,70.43 59.47,70.43 59.59,70.31 59.59,70.05 59.47,69.92 59.06,69.92 58.94,69.8 58.94,69.38 59.06,69.26 59.34,69.26 59.46,69.38 v1(59.46,69.44)
  BOTTOM w0.076: UC1.AM43 104.18,107.8 v1(103.89,107.8)
  BOTTOM w0.102: JDIMM1.59 59.2,69.71 v1(59.46,69.44)
DDR_A_D51: length 82.4
  IN1 w0.084: 93.3,93.66 93.3,93.86 95.47,96.02 95.47,96.63 98.96,100.13 98.96,100.85 99.65,101.53 99.65,104.62 100.46,105.44 100.46,106.77 100.63,106.94 101.43,106.94 101.57,107.07 102.23,107.07 102.53,107.37 102.53,107.64 102.62,107.73 v1(102.94,107.73)
  IN1 w0.127: 93.3,93.66 93.3,93.53 85.85,86.08 70.09,86.08 69.72,85.71 69.58,85.71 69.3,85.99 69.12,85.99 68.93,85.8 68.93,85.62 69.21,85.34 69.21,85.2 68.99,84.97 68.84,84.97 68.56,85.25 68.38,85.25 68.19,85.06 68.19,84.88 68.47,84.6 68.47,84.46 68.25,84.23 68.11,84.23 67.81,84.53 67.66,84.53 67.44,84.31 67.44,84.16 67.74,83.87 67.74,83.72 67.51,83.5 67.37,83.5 67.07,83.8 66.93,83.8 66.7,83.57 66.7,83.43 67,83.13 67,82.99 66.78,82.76 66.63,82.76 66.34,83.06 66.19,83.06 65.97,82.83 65.97,82.69 66.28,82.38 66.28,82.26 66.03,82.01 65.91,82.01 65.6,82.32 65.46,82.32 63.48,80.34 63.46,80.34 59.34,76.22 59.34,75.99 59.58,75.75 59.58,75.57 59.4,75.38 59.22,75.38 58.96,75.64 58.78,75.64 58.6,75.45 58.6,75.27 58.92,74.94 58.92,74.82 58.6,74.49 58.6,69.07 58.71,68.96 58.89,68.96 59.01,68.84 59.01,68.55 58.89,68.44 58.71,68.44 58.6,68.32 58.6,67.38 58.72,67.26 58.94,67.26 59.07,67.38 59.07,67.79 59.2,67.92 v1(59.46,67.92)
  BOTTOM w0.076: UC1.AM45 103.14,107.73 v1(102.94,107.73)
  BOTTOM w0.102: v1(59.46,67.92) 58.6,68.79 JDIMM1.57
DDR_A_D52: length 83.1
  IN1 w0.084: 92.93,93.66 92.93,93.86 95.15,96.09 95.15,96.59 98.66,100.11 98.66,104.06 99.69,105.09 99.69,106.53 100.27,107.11 101.36,107.11 101.49,107.25 102.14,107.25 102.36,107.46 102.36,108.44 v1(102.95,109.03)
  IN1 w0.127: v1(58.77,59.94) 59.4,60.57 59.4,65.29 58.25,66.44 58.25,75.62 59.23,76.6 59.23,76.6 63.28,80.65 63.3,80.65 64.05,81.4 69.07,86.42 85.69,86.42 92.93,93.66
  BOTTOM w0.076: UC1.AK45 103.22,109.3 v1(102.95,109.03)
  BOTTOM w0.102: v1(58.77,59.94) 58.3,60.4 JDIMM1.56
DDR_A_D53: length 84.3
  IN1 w0.084: v1(103.89,109.1) 103.59,109.4 102.56,109.4 102.5,109.34 101.88,109.34 101.56,109.03 101.56,107.68 101.17,107.28 100.19,107.28 99.52,106.61 99.52,105.2 98.39,104.07 98.39,100.07 94.83,96.52 94.83,96.07 92.42,93.66
  IN1 w0.127: v1(58.77,61.46) 58.77,62.09 58.64,62.22 58.07,62.22 57.94,62.35 57.94,62.6 58.07,62.73 58.64,62.73 58.77,62.86 58.77,63.11 58.64,63.24 58.07,63.24 57.94,63.36 57.94,63.62 58.07,63.75 58.64,63.75 58.77,63.87 58.77,64.27 58.64,64.4 58.04,64.4 57.91,64.53 57.91,75.76 58.89,76.75 63.14,80.99 63.16,80.99 63.78,81.61 68.92,86.76 85.53,86.76 85.6,86.83 92.42,93.66
  BOTTOM w0.076: UC1.AK43 104.18,109.1 v1(103.89,109.1)
  BOTTOM w0.102: v1(58.77,61.46) 58.9,61.59 JDIMM1.58
DDR_A_D54: length 84.3
  IN1 w0.084: 95.59,93.66 95.59,93.85 95.91,94.18 96.1,94.18 102.43,100.51 102.43,104.51 103.23,105.32 106,105.32 106.13,105.44 106.13,107.3 v1(105.76,107.67)
  IN1 w0.127: v1(61.88,61.46) 61.88,61.22 62,61.1 62.32,61.1 62.43,61.22 62.43,61.69 62.56,61.82 62.83,61.82 62.96,61.69 62.96,60.78 63.08,60.65 63.41,60.65 63.54,60.78 63.54,62.99 63.4,63.13 61.58,63.13 61.46,63.25 61.46,74.3 71.02,83.86 86.79,83.86 95.59,92.66 95.59,93.66
  BOTTOM w0.076: v1(105.76,107.67) 106.08,107.99 UC1.AM40
  BOTTOM w0.102: v1(61.88,61.46) 61.9,61.48 JDIMM1.68
DDR_A_D55: length 84
  IN1 w0.084: v1(104.84,107.72) 104.84,107.6 104.15,106.92 103.89,106.92 103.46,106.48 103.46,105.79 102.71,105.04 101.91,105.04 101.57,104.69 101.57,99.89 96.2,94.53 95.56,94.53 95.23,94.2 95.23,93.66
  IN1 w0.127: 95.23,93.66 95.23,92.81 87.04,84.62 86.63,84.21 70.86,84.21 61.12,74.46 61.12,63.11 61.45,62.77 63.07,62.77 63.2,62.65 63.2,62.38 63.07,62.25 61.62,62.25 61.46,62.09 61.46,60.05 61.57,59.94 v1(61.88,59.94)
  BOTTOM w0.076: UC1.AM42 105.12,107.99 v1(104.84,107.72)
  BOTTOM w0.102: v1(61.88,59.94) 62.5,60.56 JDIMM1.70
DDR_A_D56: length 66.8
  IN3 w0.084: 95.3,93.66 95.3,94.52 96.93,96.15 96.93,97.16 98.79,99.02 98.79,104.58 101.58,107.37 101.58,107.86 v1(101.98,108.27)
  IN3 w0.127: 95.3,93.66 95.3,92.73 94.62,92.05 94.62,91.2 94.45,91.02 94.45,89.64 93.82,89.01 93.82,86.26 104.44,75.64 104.44,70.98 104.31,70.85 102.22,70.85 102.1,70.72 102.1,69.35 102.22,69.23 103.33,69.23 103.46,69.1 103.46,68.73 103.33,68.6 102.22,68.6 102.1,68.48 102.1,68.17 102.22,68.04 103.03,68.04 103.15,67.92 103.15,67.55 103.03,67.43 102.07,67.43 101.94,67.3 101.94,66.71 101.81,66.59 101.04,66.59 100.93,66.47 100.93,66.16 101.04,66.04 101.83,66.04 101.96,65.92 101.96,65.63 101.83,65.5 101.26,65.5 101.13,65.38 101.13,65.09 101.26,64.96 101.85,64.96 101.98,64.84 v1(101.98,61.46)
  BOTTOM w0.076: UC1.AM46 102.26,107.99 v1(101.98,108.27)
  BOTTOM w0.102: v1(101.98,61.46) 101.5,61.94 JDIMM1.192
DDR_A_D57: length 66.8
  IN3 w0.084: v1(101.98,108.92) 102.36,108.55 102.36,107.46 102.08,107.19 101.65,107.19 98.97,104.51 98.97,102.4 99.57,101.8 99.57,101.39 99.14,100.96 99.14,99.13 97.24,97.23 97.24,96.15 95.66,94.56 95.66,93.66
  IN3 w0.127: v1(101.98,59.94) 102.52,59.94 102.64,60.06 102.64,63.51 102.77,63.64 104.11,63.64 104.23,63.76 104.23,66.04 104.11,66.17 102.61,66.17 102.48,66.29 102.48,66.58 102.61,66.71 103.98,66.71 104.8,67.53 104.8,75.79 94.98,85.61 94.98,90.61 95.15,90.78 95.15,92.07 95.66,92.58 95.66,93.66
  BOTTOM w0.076: v1(101.98,108.92) 102.36,109.3 UC1.AK46
  BOTTOM w0.102: v1(101.98,59.94) 102.52,60.48 102.52,61.67 102.1,62.09 JDIMM1.194
DDR_A_D58: length 64.3
  IN3 w0.084: v1(100.03,107.73) 99.72,107.73 99.28,107.3 98.43,107.3 97.84,106.71 97.84,103.98 97.12,103.26 97.12,101.36 97.66,100.82 97.66,100.18 93.06,95.58 93.06,93.86 92.85,93.66
  IN3 w0.127: v1(99.41,69.46) 98.98,69.88 98.98,73.42 99.19,73.62 99.19,77.73 97.42,79.49 97.23,79.49 96.8,79.06 96.62,79.06 96.42,79.26 96.42,79.44 96.85,79.87 96.85,80.06 96.66,80.26 96.47,80.26 95.81,79.6 95.62,79.6 95.43,79.8 95.43,79.99 96.08,80.64 96.08,80.83 95.72,81.2 95.53,81.2 94.87,80.54 94.69,80.54 94.49,80.74 94.49,80.92 95.15,81.58 95.15,81.77 94.95,81.96 94.76,81.96 94.14,81.34 93.96,81.34 93.76,81.54 93.76,81.72 94.38,82.34 94.38,82.53 94.19,82.73 94,82.73 93.34,82.07 93.16,82.07 92.96,82.27 92.96,82.45 93.62,83.11 93.62,83.3 93.42,83.49 93.23,83.49 92.57,82.83 92.4,82.83 92.19,83.04 92.19,83.22 92.85,83.87 92.85,84.06 92.66,84.26 92.47,84.26 91.81,83.6 91.63,83.6 91.43,83.8 91.43,83.98 92.09,84.65 92.09,84.82 91.83,85.08 91.65,85.08 91.42,84.85 91.24,84.85 91,85.09 91,85.27 91.28,85.55 91.28,85.63 91,85.91 91,91.81 92.85,93.66
  BOTTOM w0.076: UC1.AM49 100.29,107.99 v1(100.03,107.73)
  BOTTOM w0.102: JDIMM1.183 98.8,70.07 v1(99.41,69.46)
DDR_A_D59: length 63.2
  IN3 w0.084: v1(100.08,109) 99.4,109.68 96.42,109.68 95.88,109.13 95.88,100.4 91.97,96.49 91.97,94.32 91.31,93.66
  IN3 w0.127: 91.31,93.66 89.91,92.26 89.91,83.77 97.43,76.26 97.43,71.45 97.87,71.01 97.87,66.5 98.01,66.37 98.66,66.37 98.8,66.23 98.8,65.96 98.66,65.83 97.95,65.83 97.82,65.7 97.82,63.83 97.95,63.7 98.67,63.7 98.8,63.57 98.8,61.69 v1(99.03,61.46)
  BOTTOM w0.076: UC1.AK49 100.38,109.3 v1(100.08,109)
  BOTTOM w0.102: JDIMM1.182 98.5,61.99 v1(99.03,61.46)
DDR_A_D60: length 65.9
  IN3 w0.084: 94.57,93.66 94.57,94.74 95.72,95.9 95.72,96.76 98.45,99.49 98.45,106.58 98.64,106.78 99.66,106.78 99.84,106.96 100.32,106.96 v1(101.03,107.67)
  IN3 w0.127: 94.57,93.66 94.57,93.23 93.76,92.42 93.76,91.37 93.1,90.7 93.1,89.51 92.96,89.38 92.64,89.38 92.52,89.26 92.52,88.96 92.64,88.84 92.96,88.84 93.1,88.7 93.1,88.43 92.96,88.3 92.64,88.3 92.52,88.18 92.52,87.87 92.64,87.75 92.96,87.75 93.1,87.62 93.1,87.35 92.96,87.21 92.64,87.21 92.52,87.09 92.52,86.79 92.64,86.67 92.96,86.67 93.1,86.54 93.1,85.97 100.7,78.36 100.7,77.83 100.83,77.7 101.35,77.7 101.48,77.58 101.48,77.29 101.35,77.16 100.83,77.16 100.7,77.04 100.7,76.74 100.83,76.62 102.43,76.62 102.56,76.49 102.56,76.21 102.43,76.08 100.83,76.08 100.7,75.96 100.7,75.65 100.83,75.52 102.9,75.52 103.03,75.4 103.03,75.11 102.9,74.98 100.83,74.98 100.7,74.86 100.7,74.56 100.83,74.44 102.9,74.44 103.03,74.31 103.03,74.03 102.9,73.9 100.83,73.9 100.7,73.78 100.7,72.94 100.83,72.82 101.55,72.82 101.68,72.69 101.68,72.4 101.55,72.28 100.83,72.28 100.7,72.15 100.7,70.31 100.93,70.09 100.95,70.09 101.31,69.73 v1(101.31,69.46)
  BOTTOM w0.076: UC1.AM48 101.36,107.99 v1(101.03,107.67)
  BOTTOM w0.102: v1(101.31,69.46) 101.2,69.57 JDIMM1.191
DDR_A_D61: length 65.5
  IN3 w0.084: v1(101.03,108.97) 101.38,108.97 101.53,108.82 101.53,108.06 101.4,107.93 101.4,107.48 100.71,106.79 99.92,106.79 99.68,106.56 99.68,105.72 98.62,104.66 98.62,99.1 96.68,97.15 96.68,96.28 94.93,94.53 94.93,93.66
  IN3 w0.127: v1(101.31,67.94) 101.61,67.94 101.73,68.06 101.73,70.37 101.61,70.5 101.19,70.5 101.06,70.62 101.06,71.09 101.19,71.21 103.95,71.21 104.08,71.34 104.08,71.79 103.95,71.91 102.16,71.91 102.04,72.04 102.04,72.33 102.16,72.45 103.95,72.45 104.08,72.58 104.08,72.87 103.95,73 101.89,73 101.76,73.12 101.76,73.41 101.89,73.54 103.27,73.54 103.39,73.66 103.39,74.81 103.53,74.95 103.78,74.95 103.9,75.07 103.9,75.36 103.78,75.49 103.53,75.49 103.39,75.62 103.39,76.17 93.46,86.11 93.46,90.55 94.13,91.22 94.13,92.28 94.93,93.09 94.93,93.66
  BOTTOM w0.076: v1(101.03,108.97) 101.36,109.3 UC1.AK48
  BOTTOM w0.102: v1(101.31,67.94) 101.8,68.43 JDIMM1.193
DDR_A_D62: length 63.5
  IN3 w0.084: 92.34,93.66 92.7,94.02 92.7,96.53 96.55,100.38 96.55,103.31 97.67,104.43 97.67,108.66 97.77,108.76 98.48,108.76 98.58,108.66 98.58,107.77 98.68,107.67 v1(99.13,107.67)
  IN3 w0.127: v1(99.41,67.94) 99.41,67.71 99.28,67.58 98.75,67.58 98.62,67.71 98.62,71.49 98.49,71.62 98.29,71.62 98.15,71.75 98.15,72.03 98.29,72.16 98.49,72.16 98.62,72.3 98.62,72.57 98.49,72.7 98.29,72.7 98.15,72.84 98.15,73.11 98.29,73.24 98.49,73.24 98.62,73.37 98.62,73.66 98.49,73.78 98.29,73.78 98.15,73.92 98.15,74.19 98.29,74.32 98.7,74.32 98.82,74.45 98.82,74.74 98.7,74.87 98.29,74.87 98.15,75 98.15,75.27 98.29,75.41 98.7,75.41 98.82,75.53 98.82,75.89 98.7,76.02 98.35,76.02 98.23,76.15 98.23,76.49 98.35,76.62 98.55,76.62 98.68,76.74 98.68,76.92 98.82,77.07 98.82,77.24 98.62,77.45 98.44,77.45 97.95,76.96 97.76,76.96 97.57,77.15 97.57,77.34 98.22,78 98.22,78.18 98.02,78.38 97.84,78.38 97.18,77.72 96.99,77.72 96.8,77.91 96.8,78.1 97.01,78.31 97.01,78.49 96.8,78.7 96.62,78.7 96.42,78.49 96.23,78.49 90.64,84.08 90.64,91.96 92.34,93.66
  BOTTOM w0.076: v1(99.13,107.67) 99.46,107.67 99.52,107.73 UC1.AM51
  BOTTOM w0.102: JDIMM1.181 98.2,69.14 v1(99.41,67.94)
DDR_A_D63: length 62.8
  IN3 w0.084: v1(99.13,108.97) 98.59,109.5 97.23,109.5 96.85,109.12 96.85,104.7 96.37,104.21 96.37,100.65 92.33,96.61 92.33,94.17 91.83,93.66
  IN3 w0.127: 91.83,93.66 90.28,92.11 90.28,83.92 97.79,76.41 97.79,71.6 98.26,71.13 98.26,67.56 99.23,66.58 99.23,62.25 99.45,62.04 99.45,60.36 v1(99.03,59.94)
  BOTTOM w0.076: v1(99.13,108.97) 99.45,109.3 UC1.AK51
  BOTTOM w0.102: v1(99.03,59.94) 97.9,61.06 JDIMM1.180
DDR_A_DQS0: length 73.4
  IN3 w0.084: v1(87.4,108.62) 87.58,108.62 87.8,108.4 87.78,108.37 87.78,108.09 86.64,106.94 86.12,106.94 86.1,106.97 86.08,106.97
  IN3 w0.127: 86.08,106.97 79.53,106.97 77.52,104.95 77.52,99.29 75.45,97.23 75.45,93.1 75.32,92.98 75.12,92.98 74.85,92.71 74.85,92.12 75.12,91.85 75.32,91.85 75.45,91.73 75.45,91.37 75.32,91.24 74.99,91.24 74.72,90.97 74.72,90.39 74.99,90.12 75.32,90.12 75.45,89.99 75.45,89.63 75.32,89.5 74.99,89.5 74.72,89.23 74.72,88.65 74.99,88.38 75.32,88.38 75.45,88.25 75.45,87.89 75.32,87.77 74.99,87.77 74.72,87.49 74.72,86.92 74.99,86.64 75.32,86.64 75.45,86.52 75.45,86.15 75.32,86.03 74.99,86.03 74.72,85.75 74.72,85.18 74.99,84.9 75.32,84.9 75.45,84.78 75.45,84.42 75.32,84.29 74.99,84.29 74.72,84.02 74.72,83.44 74.99,83.17 75.32,83.17 75.45,83.04 75.45,82.68 75.32,82.55 74.99,82.55 74.72,82.28 74.72,81.7 74.99,81.43 75.32,81.43 75.45,81.3 75.45,80.94 75.32,80.82 74.99,80.82 74.72,80.54 74.72,79.97 74.99,79.69 75.32,79.69 75.45,79.57 75.45,78.83 80.92,73.36 80.92,72.87 84.07,69.72 84.07,68.03 84.35,67.75 84.54,67.75 v1(84.74,67.56)
  BOTTOM w0.076: v1(87.4,108.62) 87.7,108.62 87.79,108.53 88.11,108.53 88.66,109.07 89.99,109.07 90.61,109.69 91.06,109.69 91.19,109.82 91.75,109.82 91.8,109.85 91.91,109.9 92.04,109.9 92.06,109.89 92.14,109.85 92.2,109.83 92.4,109.83 92.56,109.9 92.69,109.9 92.8,109.85 92.8,109.68 92.73,109.61 UC1.AJ62
  BOTTOM w0.102: v1(84.74,67.56) 85.04,67.86 85.29,67.86 85.47,68.04 85.47,69.28 84.8,69.95 84.8,70.05 85,70.25 JDIMM1.137
DDR_A_DQS1: length 89.5
  IN1 w0.084: v1(89.55,106.15) 89.8,106.15 89.86,106.09 89.86,105.89 88.46,104.49 87.54,104.49 87.39,104.33 87.13,104.33
  IN1 w0.127: 87.13,104.33 82.25,99.45 77.16,99.45 76.53,100.09 75.56,100.09 75.04,99.57 74.66,99.19 62.47,99.19 52.31,89.03 51.83,89.03 45.51,82.72 45.51,81.36 44.97,80.82 44.97,78.83 43.45,77.31 43.45,74.73 42.88,74.16 42.88,67.32 43.97,66.23 43.97,60.21 44.47,59.71 44.71,59.71 v1(44.86,59.56)
  BOTTOM w0.076: UC1.AN61 93.05,107.4 92.86,107.4 92.7,107.56 92.23,107.56 92.08,107.63 91.87,107.63 91.73,107.57 91.71,107.56 91.44,107.56 91.44,107.56 90.92,107.56 90.86,107.51 90.02,107.51 89.53,107.02 89.53,106.17 v1(89.55,106.15)
  BOTTOM w0.102: JDIMM1.12 45.1,62.03 45.03,61.96 45.03,61.76 45.5,61.29 45.5,60.01 45.24,59.76 45.06,59.76 v1(44.86,59.56)
DDR_A_DQS2: length 64.7
  IN3 w0.084: 88.05,100.81 88.05,101.24 92.1,105.29 92.1,105.75 93.44,107.09 94.26,107.09 v1(94.42,106.93)
  IN3 w0.127: 88.05,100.81 88.09,100.76 88.09,99.92 81.01,92.84 81.01,79.94 87.19,73.76 87.19,73.07 89.95,70.31 89.95,66.83 90.02,66.76 90.29,66.76 90.55,66.49 90.55,65.83 90.29,65.57 89.86,65.57 89.74,65.45 89.74,65.04 89.86,64.92 90.19,64.92 90.46,64.65 90.46,60.13 89.88,59.56 v1(89.15,59.56)
  BOTTOM w0.089: UC1.AN58 94.84,107.34 v1(94.42,106.93)
  BOTTOM w0.102: v1(89.15,59.56) 89.42,59.82 89.65,59.82 89.9,60.08 89.9,61.91 90.1,62.11 JDIMM1.154
DDR_A_DQS3: length 84.8
  IN1 w0.084: 88.7,99.83 88.77,99.9 88.8,99.9 88.85,99.95 88.85,99.98 90.14,101.27 90.14,101.75 92.04,103.66 93.48,103.66 94.05,104.23 95.38,104.23 96.7,105.55 96.7,107.07 96.59,107.18 96.49,107.18 v1(96.32,107.02)
  IN1 w0.127: v1(49.04,67.54) 48.87,67.7 48.64,67.7 48.37,67.97 48.37,69.46 48.64,69.73 49.29,69.73 49.42,69.86 49.42,70.11 49.29,70.24 48.64,70.24 48.37,70.51 48.37,71.09 48.64,71.36 49.29,71.36 49.42,71.49 49.42,71.79 49.34,71.87 48.64,71.87 48.37,72.15 48.37,75.95 48.82,76.4 50.55,76.4 50.68,76.53 50.68,76.91 50.55,77.04 49.45,77.04 49.18,77.31 49.18,77.9 49.45,78.17 50.47,78.17 50.68,78.38 50.68,80.55 61.51,91.39 62.76,91.39 65.66,94.29 83.16,94.29 88.7,99.83
  BOTTOM w0.076: v1(96.32,107.02) 96.65,107.34 UC1.AN55
  BOTTOM w0.102: v1(49.04,67.54) 49.32,67.82 49.45,67.82 49.69,68.07 49.69,69.86 49.95,70.11 49.95,70.25 50.2,70.5 JDIMM1.29
DDR_A_DQS4: length 56.4
  IN3 w0.084: 90.17,96.21 90.22,96.21 90.8,96.79 90.8,97.68 91.61,98.49 91.61,98.61 91.53,98.69 91.53,98.95 91.81,99.23 92.07,99.23 92.15,99.15 92.27,99.15 92.53,99.41 92.53,99.51 92.09,99.95 v1(91.86,99.95)
  IN3 w0.127: v1(94.87,67.56) 94.73,67.7 94.43,67.7 94.21,67.92 94.21,69.81 94.5,70.1 94.5,71.69 94.02,72.17 94.02,72.72 94.49,73.19 94.49,73.29 94.04,73.75 93.92,73.75 93.33,73.15 92.96,73.15 92.51,73.6 92.51,74 93,74.49 93,74.82 92.63,75.2 92.45,75.2 92.25,75 91.87,75 91.43,75.44 91.43,75.82 91.64,76.02 91.64,76.19 91.35,76.47 91.18,76.47 90.98,76.27 90.6,76.27 90.16,76.71 90.16,77.09 90.36,77.29 90.36,77.46 90.08,77.74 89.91,77.74 89.71,77.54 89.33,77.54 88.89,77.98 88.89,78.36 89.09,78.56 89.09,78.74 88.81,79.01 88.64,79.01 88.43,78.81 88.06,78.81 87.61,79.26 87.61,79.63 87.82,79.83 87.82,80.01 87.3,80.52 87.3,93.34 90.17,96.21
  BOTTOM w0.076: v1(91.86,99.95) 92.12,99.95 92.38,99.68 92.74,99.68 94.95,101.89 95.05,101.99 95.05,102.5 95.3,102.74 95.3,103.03 95.27,103.09 95.22,103.19 95.22,103.32 95.23,103.34 95.27,103.43 95.3,103.48 95.3,103.69 95.22,103.84 95.22,103.97 95.27,104.08 95.49,104.08 95.52,104.05 UC1.AW57
  BOTTOM w0.102: JDIMM1.171 95.2,70.24 94.97,70.01 94.97,69.85 95.6,69.22 95.6,68.08 95.31,67.78 95.1,67.78 v1(94.87,67.56)
DDR_A_DQS5: length 71.9
  IN1 w0.084: v1(96.83,100.1) 96.83,100.12 96.34,100.61 95.84,100.61 95.37,100.14 95.37,99.67 94.9,99.2 94.43,99.2 90.85,95.62 90.7,95.62 90.21,95.12
  IN1 w0.127: 90.21,95.12 90.13,95.12 84.8,89.79 84.42,89.42 67.98,89.42 63.84,85.29 62.62,85.29 54.89,77.56 54.89,70.24 54.01,69.36 54.01,68.02 54.33,67.69 54.55,67.69 v1(54.7,67.54)
  BOTTOM w0.076: UC1.AW53 97.77,103.91 97.73,103.87 97.73,103.48 97.7,103.43 97.66,103.34 97.65,103.32 97.65,103.19 97.68,103.14 97.71,103.08 97.71,103.08 97.73,103.03 97.73,102.72 97.47,102.46 97.47,102.34 97.33,102.19 97.33,101.2 96.55,100.43 96.55,100.14 96.59,100.1 v1(96.83,100.1)
  BOTTOM w0.102: v1(54.7,67.54) 54.91,67.74 55.13,67.74 55.4,68.01 55.4,70.04 55.6,70.24 JDIMM1.47
DDR_A_DQS6: length 84.1
  IN1 w0.084: 94.6,93.66 94.6,93.87 97.56,96.83 97.56,97.72 99.03,99.19 100.01,99.19 100.72,99.89 100.72,101.85 101.17,102.3 101.17,104.81 101.63,105.26 102.31,105.26 102.53,105.48 102.53,106.62 102.77,106.86 103.48,106.86 103.78,107.16 104.08,107.16 104.45,107.54 104.45,108.18 104.64,108.37 v1(104.84,108.37)
  IN1 w0.127: v1(60.15,59.56) 60.34,59.74 60.34,59.74 60.59,59.74 60.82,59.98 60.82,62.13 60.55,62.4 60.36,62.4 60.29,62.47 60.29,63.79 60.48,63.98 60.48,74.73 70.6,84.85 86.37,84.85 94.53,93.01 94.53,93.02 94.6,93.08 94.6,93.66
  BOTTOM w0.076: UC1.AL42 105.12,108.64 v1(104.84,108.37)
  BOTTOM w0.102: v1(60.15,59.56) 60.48,59.88 60.84,59.88 61.06,60.1 61.06,61.22 60.54,61.73 60.54,62.01 60.7,62.17 JDIMM1.64
DDR_A_DQS7: length 64.4
  IN3 w0.084: 93.69,94.05 93.69,94.62 95.1,96.03 95.1,96.85 98.1,99.85 98.1,106.72 98.5,107.12 99.37,107.12 99.59,107.34 100.2,107.34 100.42,107.57 100.42,108.22 100.29,108.35 v1(100.08,108.35)
  IN3 w0.127: 93.69,94.05 93.69,93.59 91.65,91.54 91.65,86.18 99.83,78 99.83,69.95 100.05,69.73 100.05,64.32 100.3,64.07 100.94,64.07 101.07,63.94 101.07,63.5 100.94,63.38 100.14,63.38 99.88,63.11 99.88,62.52 100.14,62.25 100.89,62.25 101.02,62.12 101.02,60.15 100.84,59.97 100.67,59.97 100.58,60.06 v1(100.58,60.32)
  BOTTOM w0.076: v1(100.08,108.35) 100.38,108.64 UC1.AL49
  BOTTOM w0.102: v1(100.58,60.32) 100.28,60.02 100.18,60.02 99.99,60.22 99.99,61.87 100.3,62.18 JDIMM1.188
DDR_A_DQS#0: length 73.6
  IN3 w0.084: v1(87.82,109.03) 87.79,109 87.79,108.69 88.08,108.4 87.98,108.29 87.98,108 86.72,106.75 86.2,106.75 86.18,106.72 86.08,106.72
  IN3 w0.127: 86.08,106.72 79.63,106.72 77.76,104.85 77.76,99.19 75.69,97.13 75.69,93 75.43,92.74 75.22,92.74 75.09,92.61 75.09,92.22 75.22,92.09 75.43,92.09 75.69,91.83 75.69,91.27 75.43,91 75.09,91 74.96,90.87 74.96,90.49 75.09,90.36 75.43,90.36 75.69,90.09 75.69,89.53 75.43,89.26 75.09,89.26 74.96,89.13 74.96,88.75 75.09,88.62 75.43,88.62 75.69,88.35 75.69,87.79 75.43,87.52 75.09,87.52 74.96,87.39 74.96,87.02 75.09,86.88 75.43,86.88 75.69,86.62 75.69,86.05 75.43,85.79 75.09,85.79 74.96,85.65 74.96,85.28 75.09,85.14 75.43,85.14 75.69,84.88 75.69,84.32 75.43,84.05 75.09,84.05 74.96,83.92 74.96,83.54 75.09,83.41 75.43,83.41 75.69,83.14 75.69,82.58 75.43,82.31 75.09,82.31 74.96,82.18 74.96,81.8 75.09,81.67 75.43,81.67 75.69,81.4 75.69,80.84 75.43,80.58 75.09,80.58 74.96,80.44 74.96,80.07 75.09,79.93 75.43,79.93 75.69,79.67 75.69,78.93 81.16,73.46 81.16,73.26 81.16,72.97 84.31,69.82 84.31,68.13 84.45,67.99 84.69,67.99 84.74,68.04 v1(84.74,68.32)
  BOTTOM w0.076: v1(87.82,109.03) 87.72,108.94 87.72,108.83 87.86,108.69 88.04,108.69 88.59,109.24 89.93,109.24 90.54,109.85 90.99,109.85 91.13,109.99 91.71,109.99 91.8,110.03 91.87,110.06 92.08,110.06 92.23,109.99 92.37,109.99 92.47,110.04 92.52,110.06 92.75,110.06 92.78,110.04 92.89,109.99 92.97,109.91 92.97,109.56 93.02,109.51 93.17,109.51 UC1.AJ61
  BOTTOM w0.102: JDIMM1.135 84.4,70.33 84.61,70.12 84.61,69.87 85.27,69.2 85.27,68.12 85.2,68.06 85,68.06 v1(84.74,68.32)
DDR_A_DQS#1: length 89.7
  IN1 w0.084: 87.25,104.1 87.28,104.12 87.47,104.12 87.63,104.28 88.55,104.28 90.07,105.8 90.07,106.22 89.79,106.5 89.79,106.63 89.94,106.77 v1(90.13,106.77)
  IN1 w0.127: v1(44.86,60.32) 44.86,60.08 44.74,59.96 44.58,59.96 44.22,60.31 44.22,66.33 43.13,67.42 43.13,74.06 43.7,74.62 43.7,77.21 45.22,78.73 45.22,80.71 45.76,81.26 45.76,82.62 51.93,88.78 52.41,88.78 62.57,98.94 74.77,98.94 75.29,99.46 75.66,99.84 76.42,99.84 77.06,99.2 82.35,99.2 87.25,104.1
  BOTTOM w0.076: v1(90.13,106.77) 90.13,106.54 89.98,106.4 89.87,106.4 89.7,106.57 89.7,106.95 90.09,107.34 90.93,107.34 90.98,107.39 91.75,107.39 91.8,107.42 91.89,107.46 91.91,107.47 92.04,107.47 92.06,107.46 92.14,107.42 92.2,107.4 92.61,107.4 92.67,107.33 92.67,107.23 UC1.AN62
  BOTTOM w0.102: v1(44.86,60.32) 44.81,60.27 44.81,60.08 44.94,59.95 45.16,59.95 45.3,60.1 45.3,61.21 44.83,61.68 44.83,61.96 44.78,62.01 44.61,62.01 44.5,62.12 JDIMM1.10
DDR_A_DQS#2: length 64.9
  IN3 w0.084: 87.85,100.66 87.85,101.29 91.93,105.37 91.93,105.82 93.37,107.26 94.22,107.26 94.42,107.45 v1(94.42,107.58)
  IN3 w0.127: 87.85,100.66 87.85,100.02 80.77,92.94 80.77,79.84 86.95,73.66 86.95,72.97 89.71,70.21 89.71,66.73 89.92,66.52 90.19,66.52 90.31,66.39 90.31,65.93 90.19,65.81 89.76,65.81 89.5,65.55 89.5,64.94 89.76,64.68 90.09,64.68 90.22,64.55 90.22,60.23 89.78,59.8 89.51,59.8 89.15,60.15 v1(89.15,60.32)
  BOTTOM w0.076: UC1.AM58 94.87,107.76 94.69,107.58 v1(94.42,107.58)
  BOTTOM w0.102: JDIMM1.152 89.5,62.11 89.7,61.91 89.7,60.16 89.56,60.02 89.45,60.02 v1(89.15,60.32)
DDR_A_DQS#3: length 85
  IN1 w0.084: v1(96.32,107.67) 96.32,107.43 96.37,107.39 96.68,107.39 96.91,107.16 96.91,105.46 95.47,104.02 94.14,104.02 93.57,103.45 92.13,103.45 90.34,101.66 90.34,101.18 89.05,99.89 89.05,99.86 88.88,99.69 88.88,99.66 88.87,99.65
  IN1 w0.127: v1(49.04,68.3) 49.04,68.3 49.04,68.08 48.92,67.96 48.74,67.96 48.62,68.08 48.62,69.36 48.75,69.48 49.4,69.48 49.67,69.76 49.67,70.22 49.4,70.49 48.75,70.49 48.62,70.62 48.62,70.99 48.75,71.11 49.4,71.11 49.67,71.39 49.67,71.9 49.44,72.13 48.75,72.13 48.62,72.25 48.62,75.84 48.93,76.15 50.65,76.15 50.93,76.42 50.93,77.01 50.65,77.29 49.56,77.29 49.43,77.41 49.43,77.79 49.56,77.92 50.57,77.92 50.93,78.28 50.93,80.45 61.62,91.14 62.87,91.14 65.77,94.04 83.26,94.04 88.87,99.65
  BOTTOM w0.076: UC1.AM55 96.72,107.71 96.63,107.62 96.37,107.62 v1(96.32,107.67)
  BOTTOM w0.102: JDIMM1.27 49.6,70.45 49.75,70.31 49.75,70.19 49.5,69.94 49.5,68.15 49.37,68.02 49.18,68.02 49.04,68.16 v1(49.04,68.3)
DDR_A_DQS#4: length 56.5
  IN3 w0.084: 90.17,95.87 90.2,95.9 90.2,95.94 90.97,96.71 90.97,97.61 91.78,98.42 91.78,98.68 91.7,98.76 91.7,98.88 91.88,99.05 92,99.05 92.08,98.98 92.34,98.98 92.7,99.33 92.7,99.58 92.22,100.06 92.22,100.3 v1(92.32,100.41)
  IN3 w0.127: 90.17,95.87 87.55,93.24 87.55,80.62 88.06,80.11 88.06,79.73 87.86,79.53 87.86,79.36 88.16,79.05 88.33,79.05 88.54,79.25 88.91,79.25 89.33,78.84 89.33,78.46 89.13,78.26 89.13,78.08 89.43,77.78 89.61,77.78 89.81,77.98 90.18,77.98 90.6,77.56 90.6,77.19 90.4,76.99 90.4,76.81 90.7,76.51 90.88,76.51 91.08,76.72 91.45,76.72 91.88,76.29 91.88,75.92 91.68,75.72 91.68,75.54 91.97,75.24 92.15,75.24 92.35,75.44 92.73,75.44 93.24,74.92 93.24,74.39 92.75,73.9 92.75,73.7 93.06,73.39 93.23,73.39 93.82,73.99 94.14,73.99 94.73,73.39 94.73,73.09 94.26,72.62 94.26,72.27 94.74,71.79 94.74,70 94.45,69.71 94.45,68.02 94.53,67.94 94.69,67.94 94.87,68.12 v1(94.87,68.32)
  BOTTOM w0.076: v1(92.32,100.41) 92.2,100.29 92.2,100.1 92.45,99.85 92.67,99.85 94.89,102.06 94.89,102.57 95.13,102.81 95.13,103 95.08,103.1 95.08,103.1 95.06,103.16 95.06,103.36 95.13,103.52 95.13,103.65 95.08,103.75 95.06,103.81 95.06,104.01 95.14,104.18 95.2,104.24 95.58,104.24 95.63,104.29 95.63,104.45 UC1.AV57
  BOTTOM w0.102: JDIMM1.169 94.6,70.25 94.77,70.08 94.77,69.77 95.41,69.14 95.41,68.16 95.23,67.98 95.02,67.98 94.87,68.13 v1(94.87,68.32)
DDR_A_DQS#5: length 72.2
  IN1 w0.084: 90.23,94.87 90.31,94.87 90.46,95.02 90.46,95.08 90.79,95.41 90.94,95.41 94.52,98.99 94.98,98.99 95.58,99.58 95.58,100.05 95.93,100.4 96.25,100.4 96.46,100.2 96.46,99.73 v1(96.37,99.64)
  IN1 w0.127: 90.23,94.87 85.05,89.69 84.53,89.17 68.08,89.17 63.95,85.04 62.73,85.04 55.14,77.45 55.14,70.13 54.26,69.25 54.26,68.12 54.44,67.94 54.59,67.94 54.7,68.06 v1(54.7,68.3)
  BOTTOM w0.076: UC1.AV53 97.67,104.28 97.67,104.11 97.56,104.01 97.56,103.52 97.49,103.36 97.49,103.16 97.51,103.1 97.53,103.08 97.56,103 97.56,102.79 97.31,102.53 97.31,102.41 97.16,102.26 97.16,101.27 96.39,100.5 96.39,99.66 v1(96.37,99.64)
  BOTTOM w0.102: JDIMM1.45 55,70.25 55.21,70.04 55.21,68.1 55.05,67.94 54.77,67.94 54.7,68.01 v1(54.7,68.3)
DDR_A_DQS#6: length 84.2
  IN1 w0.084: 94.35,93.66 94.35,93.67 94.37,93.69 94.37,93.76 94.39,93.78 94.39,93.9 97.39,96.9 97.39,97.79 98.96,99.36 99.94,99.36 100.54,99.96 100.54,101.92 101,102.38 101,104.88 101.56,105.44 102.24,105.44 102.36,105.56 102.36,106.69 102.7,107.03 103.41,107.03 103.7,107.33 104.01,107.33 104.28,107.61 104.28,108.66 104.2,108.74 104,108.74 103.89,108.63 v1(103.89,108.45)
  IN1 w0.127: v1(60.15,60.32) 60.15,60.08 60.23,59.99 60.49,59.99 60.57,60.08 60.57,62.02 60.45,62.15 60.26,62.15 60.04,62.37 60.04,63.89 60.23,64.08 60.23,74.83 70.5,85.1 86.27,85.1 94.28,93.11 94.28,93.12 94.35,93.18 94.35,93.66
  BOTTOM w0.076: UC1.AL43 104.18,108.45 v1(103.89,108.45)
  BOTTOM w0.102: v1(60.15,60.32) 60.39,60.08 60.76,60.08 60.86,60.18 60.86,61.13 60.35,61.65 60.35,61.93 60.1,62.18 JDIMM1.62
DDR_A_DQS#7: length 64.9
  IN3 w0.084: 93.94,94.12 93.87,94.19 93.87,94.55 95.28,95.96 95.28,96.78 98.27,99.77 98.27,106.65 98.57,106.95 99.44,106.95 99.66,107.17 100.27,107.17 100.59,107.49 100.59,108.17 100.74,108.32 v1(101.03,108.32)
  IN3 w0.127: v1(100.58,59.56) 100.75,59.73 100.94,59.73 101.26,60.05 101.26,62.22 100.99,62.49 100.24,62.49 100.12,62.62 100.12,63.01 100.24,63.13 101.04,63.13 101.31,63.4 101.31,64.04 101.04,64.31 100.4,64.31 100.29,64.42 100.29,69.83 100.07,70.05 100.07,78.1 91.89,86.28 91.89,91.44 93.94,93.49 93.94,94.12
  BOTTOM w0.076: v1(101.03,108.32) 101.36,108.64 UC1.AL48
  BOTTOM w0.102: v1(100.58,59.56) 100.31,59.82 100.1,59.82 99.79,60.13 99.79,62.11 99.7,62.19 JDIMM1.186
DDR_A_MA0: length 72.6
  IN1 w0.084: 103.99,93.76 103.99,93.81 104.3,94.12
  IN1 w0.089: 104.3,94.12 104.3,95.12 107.39,98.22 107.39,98.82 107.73,99.16 107.73,102.27 107.66,102.33 107.66,104.21 108.19,104.74 v1(108.27,104.74)
  IN1 w0.183: v1(73.56,60.7) 73.1,61.16 73.1,62.92 73.28,63.1 73.95,63.1 74.13,63.29 74.13,63.65 73.95,63.84 73.28,63.84 73.1,64.02 73.1,65.69 72.84,65.95 72.84,69.79 73.92,70.87 74.23,70.87 77.92,74.56 92.21,74.56 103.99,86.34 103.99,93.76
  BOTTOM w0.076: UC1.AU36 108.59,104.74 v1(108.27,104.74)
  BOTTOM w0.165: JDIMM1.98 73.3,61.98 73.12,61.8 73.12,61.14 v1(73.56,60.7)
DDR_A_MA1: length 74.2
  IN1 w0.084: 104.91,93.66 104.91,93.72 105.29,94.09 105.29,95.56
  IN1 w0.089: 105.29,95.56 107.8,98.07 107.8,98.73 108.08,99.01 108.08,101.85 v1(108.29,102.05)
  IN1 w0.183: 104.91,93.66 104.91,84.84 104.3,84.22 104.3,83.93 104.91,83.31 104.91,82.4 104.35,81.84 104.09,81.84 102.5,83.43 102.32,83.43 101.98,83.09 101.98,82.91 103.61,81.28 103.61,81.1 103.27,80.76 103.09,80.76 101.46,82.4 101.28,82.4 100.95,82.06 100.95,81.88 102.58,80.25 102.58,80.07 102.24,79.73 102.06,79.73 100.43,81.36 100.25,81.36 92.57,73.69 78.28,73.69 74.68,70.09 74.68,69.61 v1(73.77,68.7)
  BOTTOM w0.076: UC1.AY37 107.85,102.44 108.25,102.05 v1(108.29,102.05)
  BOTTOM w0.165: v1(73.77,68.7) 73.14,68.7 72.82,69.01 72.82,69.8 73,69.97 JDIMM1.97
DDR_A_MA2: length 75.8
  IN1 w0.084: 103.53,93.66 103.53,93.83 104.07,94.37
  IN1 w0.089: 104.07,94.37 104.07,95.15 107.13,98.2 107.13,98.81 107.55,99.23 107.55,102.19 107.48,102.26 107.48,105.46 v1(107.25,105.69)
  IN1 w0.183: 103.53,93.66 103.53,86.49 92.03,75 77.62,75 77.24,74.63 76.04,74.63 74.28,72.86 74.28,71.84 72.38,69.94 72.38,65.75 72.61,65.52 72.61,60.12 v1(73.56,59.17)
  BOTTOM w0.076: v1(107.25,105.69) 107.6,106.04 UC1.AR38
  BOTTOM w0.165: JDIMM1.96 72.7,62.2 72.7,62.2 72.7,60.04 v1(73.56,59.17)
DDR_A_MA3: length 75.8
  IN1 w0.084: 104.45,93.66 104.45,93.93 104.51,93.99 104.87,93.99 105.11,94.24 105.11,95.64 107.6,98.12
  IN1 w0.089: v1(108.21,106.52) 108.3,106.52 108.42,106.65 108.42,106.86 108.53,106.97 108.66,106.97 108.78,106.84 108.78,106.32 108.59,106.12 108.59,105.5 108.75,105.33 108.75,104.54 108.55,104.34 108.11,104.34 107.89,104.13 107.89,102.45 107.91,102.44 107.91,99.09 107.6,98.78 107.6,98.12
  IN1 w0.183: 104.45,93.66 104.45,86.18 104.1,85.83 104.1,85.57 104.48,85.2 104.48,85.02 104.14,84.68 103.96,84.68 103.58,85.06 103.33,85.06 103.07,84.8 103.07,84.54 104.48,83.13 104.48,82.95 104.14,82.61 103.96,82.61 102.55,84.02 102.29,84.02 92.39,74.12 78.1,74.12 74.41,70.43 74.1,70.43 73.3,69.63 73.3,67.3 73.43,67.18 v1(73.77,67.18)
  BOTTOM w0.076: v1(108.21,106.52) 108.38,106.69 UC1.AP36
  BOTTOM w0.165: v1(73.77,67.18) 72.4,68.54 JDIMM1.95
DDR_A_MA4: length 76.9
  IN1 w0.084: v1(106.71,104.58) 106.06,103.94 106.06,98.68 103.95,96.57 103.11,96.57 100.74,94.19 100.74,93.66
  IN1 w0.183: v1(70.95,59.17) 69.36,60.77 69.36,63.56 68.76,64.16 68.76,69.02 69.6,69.86 69.6,73.64 74.29,78.32 90.63,78.32 100.74,88.43 100.74,93.66
  BOTTOM w0.076: v1(106.71,104.58) 106.85,104.58 UC1.AU39
  BOTTOM w0.165: JDIMM1.92 71.5,59.72 v1(70.95,59.17)
DDR_A_MA5: length 75.4
  IN1 w0.084: 107.31,104.83 106.88,105.26 106.88,105.93 107.02,106.07 107.6,106.07 107.72,105.94 107.72,105.24 107.85,105.11 108.27,105.11 108.36,105.21 108.36,105.74 108.23,105.87 v1(108.21,105.87)
  IN1 w0.089: 103.06,93.68 103.85,94.46 103.85,95.17 106.95,98.28 106.95,98.89 107.37,99.31 107.37,102.12 107.31,102.19 107.31,104.83
  IN1 w0.183: 103.06,93.68 103.06,86.65 92.43,76.01 90.94,76.01 90.76,75.83 90.76,75.62 90.58,75.43 90.21,75.43 90.03,75.62 90.03,75.83 89.84,76.01 89.48,76.01 89.3,75.83 89.3,75.62 89.11,75.43 88.75,75.43 88.56,75.62 88.56,75.83 88.38,76.01 88.02,76.01 87.83,75.83 87.83,75.62 87.65,75.43 87.28,75.43 87.1,75.62 87.1,75.83 86.92,76.01 86.55,76.01 86.37,75.83 86.37,75.62 86.19,75.43 85.82,75.43 85.64,75.62 85.64,75.83 85.46,76.01 85.09,76.01 84.91,75.83 84.91,75.62 84.72,75.43 84.36,75.43 84.18,75.62 84.18,75.83 83.99,76.01 83.63,76.01 83.44,75.83 83.44,75.62 83.26,75.43 82.89,75.43 82.71,75.62 82.71,75.83 82.53,76.01 82.16,76.01 81.98,75.83 81.98,75.62 81.8,75.43 81.43,75.43 81.25,75.62 81.25,75.83 81.07,76.01 80.7,76.01 80.52,75.83 80.52,75.62 80.33,75.43 79.97,75.43 79.79,75.62 79.79,75.83 79.6,76.01 79.24,76.01 79.05,75.83 79.05,75.62 78.87,75.43 78.51,75.43 78.32,75.62 78.32,75.83 78.14,76.01 77.45,76.01 77.27,75.83 77.27,75.27 77.07,75.07 75.87,75.07 73.84,73.04 73.84,72.03 71.92,70.1 v1(71.92,68.7)
  BOTTOM w0.076: UC1.AR36 108.38,106.04 v1(108.21,105.87)
  BOTTOM w0.165: JDIMM1.91 71.2,70.36 71.02,70.18 71.02,68.84 71.17,68.7 v1(71.92,68.7)
DDR_A_MA6: length 76.1
  IN1 w0.084: 101.84,94.79 101.66,94.62 101.66,93.66
  IN1 w0.089: 101.84,94.79 103.04,95.99 103.91,95.99 106.42,98.5 106.42,100.83 v1(106.67,101.08)
  IN1 w0.183: 101.66,93.66 101.66,88.09 101.39,87.81 101.39,87.55 101.62,87.32 101.62,87.06 101.36,86.8 101.1,86.8 100.87,87.03 100.61,87.03 100.35,86.77 100.35,86.52 100.58,86.28 100.58,86.02 100.33,85.77 100.07,85.77 99.84,86 99.58,86 99.32,85.74 99.32,85.48 99.55,85.25 99.55,84.99 99.29,84.73 99.03,84.73 98.8,84.96 98.54,84.96 98.28,84.7 98.28,84.45 98.52,84.21 98.52,83.96 98.26,83.7 98,83.7 97.77,83.93 97.51,83.93 97.25,83.67 97.25,83.41 97.48,83.18 97.48,82.92 97.22,82.66 96.96,82.66 96.73,82.89 96.47,82.89 96.21,82.63 96.21,82.38 96.45,82.14 96.45,81.89 96.19,81.63 95.93,81.63 95.7,81.86 95.44,81.86 95.18,81.6 95.18,81.34 95.41,81.11 95.41,80.85 95.15,80.59 94.89,80.59 94.66,80.82 94.4,80.82 94.14,80.57 94.14,80.31 94.38,80.07 94.38,79.82 94.12,79.56 93.86,79.56 93.63,79.79 93.37,79.79 93.11,79.53 93.11,79.27 93.34,79.04 93.34,78.78 93.08,78.52 92.82,78.52 92.59,78.75 92.33,78.75 90.98,77.4 74.67,77.4 70.53,73.26 70.53,69.48 69.69,68.64 69.69,66.23 v1(70.27,65.65)
  BOTTOM w0.076: UC1.AV40 105.99,103.94 105.99,101.76 v1(106.67,101.08)
  BOTTOM w0.165: JDIMM1.90 70.9,65.28 70.53,65.65 v1(70.27,65.65)
DDR_A_MA7: length 74.6
  IN1 w0.084: 101.59,94.79 101.2,94.4 101.2,93.66
  IN1 w0.089: 101.59,94.79 103.04,96.25 103.92,96.25 106.24,98.57 106.24,102.83 v1(106.69,103.28)
  IN1 w0.183: v1(70.95,60.7) 70.05,60.7 69.79,60.95 69.79,61.92 69.98,62.1 70.65,62.1 70.83,62.28 70.83,62.65 70.65,62.83 69.98,62.83 69.79,63.01 69.79,63.75 69.23,64.31 69.23,68.83 70.07,69.67 70.07,73.45 74.48,77.86 90.82,77.86 101.2,88.24 101.2,93.66
  BOTTOM w0.076: v1(106.69,103.28) 106.71,103.28 107.01,103.58 UC1.AW39
  BOTTOM w0.165: v1(70.95,60.7) 69.7,61.95 JDIMM1.86
DDR_A_MA8: length 75.2
  IN1 w0.084: 102.6,93.66 102.6,95.06 103.18,95.63 104.06,95.63
  IN1 w0.089: v1(106.7,102.33) 107.2,101.83 107.2,99.38 106.77,98.96 106.77,98.35 104.06,95.63
  IN1 w0.183: 102.6,93.66 102.6,86.81 92.27,76.47 76.96,76.47 76.83,76.35 76.83,75.63 76.7,75.5 76.17,75.5 76.04,75.63 76.04,76.37 75.91,76.5 75.34,76.5 75.21,76.37 75.21,75.39 75.08,75.26 74.85,75.26 74.41,75.69 74.23,75.69 73.9,75.35 73.9,75.17 74.54,74.53 74.54,74.36 74.2,74.02 74.02,74.02 73.38,74.66 73.2,74.66 72.86,74.32 72.86,74.14 73.5,73.5 73.5,73.32 73.17,72.98 72.99,72.98 72.67,73.3 72.49,73.3 72.15,72.96 72.15,72.78 72.98,71.96 72.98,71.78 72.64,71.44 72.46,71.44 71.79,72.1 71.55,72.1 71.43,71.98 71.43,71.43 71.91,70.95 71.91,70.71 71.45,70.25 71.45,67.73 71.92,67.26 v1(71.92,67.18)
  BOTTOM w0.076: v1(106.7,102.33) 107.1,102.73 UC1.AY39
  BOTTOM w0.165: JDIMM1.89 70.6,68.49 v1(71.92,67.18)
DDR_A_MA9: length 77.3
  IN1 w0.084: 103.35,95.81 103.11,95.81 102.14,94.84 102.14,93.66
  IN1 w0.089: 103.35,95.81 103.98,95.81 106.6,98.43 106.6,99.5 v1(106.82,99.73)
  IN1 w0.183: 102.14,93.66 102.14,86.96 92.11,76.94 74.86,76.94 70.99,73.07 70.99,67.53 71.47,67.06 71.47,63.35 71.34,63.22 70.84,63.22 70.71,63.35 70.71,66.73 v1(70.27,67.18)
  BOTTOM w0.076: v1(106.82,99.73) 105.82,100.55 105.82,104.41 106.09,104.67 106.09,104.74 UC1.AU40
  BOTTOM w0.165: v1(70.27,67.18) 69.4,68.04 JDIMM1.85
DDR_A_MA10: length 76.4
  IN1 w0.084: 108.18,95.34 108.47,95.63
  IN1 w0.089: 108.47,95.63 109.56,96.71 109.56,97.76 109.72,97.92 110.13,97.92 110.24,98.03 110.24,99.72 110.05,99.91 109.61,99.91 109.48,100.04 109.48,101.43 109.25,101.66 109.25,102.81 108.93,103.13 108.93,105.41 108.78,105.56 108.78,106.06 109.09,106.37 v1(109.16,106.37)
  IN1 w0.183: 108.18,95.34 107.88,95.04 107.88,81.2 100.52,73.85 100.52,72.48 100.4,72.36 99.85,72.36 99.72,72.23 99.72,71.31 99.6,71.18 99.09,71.18 98.96,71.31 98.96,72.23 98.83,72.36 98.3,72.36 98.17,72.23 98.17,69.16 98.04,69.04 97.57,69.04 97.44,69.16 97.44,70.41 97.31,70.54 80.33,70.54 79.38,69.58 78.61,69.58 78.05,69.03 78.05,67.64 v1(77.59,67.18)
  BOTTOM w0.076: v1(109.16,106.37) 109.48,106.69 UC1.AP35
  BOTTOM w0.165: JDIMM1.107 76,69.96 76.99,68.97 76.99,67.77 v1(77.59,67.18)
DDR_A_MA11: length 75.9
  IN1 w0.084: 100.28,93.66 100.28,93.97 103.17,96.87 103.98,96.87 105.88,98.77 105.88,102.82 105.42,103.28 v1(105.12,103.28)
  IN1 w0.183: 100.28,93.66 100.28,88.62 90.44,78.79 74.1,78.79 69.14,73.83 69.14,70.05 68.3,69.21 68.3,64 68.92,63.38 68.92,60.12 v1(67.97,59.17)
  BOTTOM w0.076: v1(105.12,103.28) 105.13,103.28 105.43,103.58 UC1.AW41
  BOTTOM w0.165: v1(67.97,59.17) 69.1,60.3 JDIMM1.84
DDR_A_MA12: length 74.6
  IN1 w0.084: v1(105.13,104.58) 104.32,104.58 104.21,104.47 104.21,99.21 101.13,96.13 100.02,96.13 98.38,94.49 98.38,93.66
  IN1 w0.183: v1(66.75,67.16) 66.08,66.49 65.9,66.49 65.58,66.82 65.58,67.45 65.71,67.57 66.18,67.57 66.3,67.7 66.3,68.15 66.18,68.28 65.97,68.28 65.84,68.41 65.84,73.38 66.16,73.7 67.12,73.7 67.34,73.92 67.34,74.58 70.41,77.64 70.41,77.82 69.87,78.37 69.87,78.62 71.88,80.64 89.67,80.64 98.38,89.34 98.38,93.66
  BOTTOM w0.076: UC1.AU41 105.28,104.58 v1(105.13,104.58)
  BOTTOM w0.165: v1(66.75,67.16) 68.29,68.72 68.8,69.92 JDIMM1.83
DDR_A_MA13: length 75.1
  IN1 w0.084: 109.89,95.9 110.65,96.66 110.65,100.65 109.44,101.85 109.44,102.88 109.16,103.16 v1(109.16,105.72)
  IN1 w0.183: v1(80.51,68.7) 82.2,68.7 82.32,68.57 82.32,66.62 82.6,66.35 90.8,66.35 91.14,66.69 91.14,69.43 91.27,69.55 91.74,69.55 91.87,69.43 91.87,66.54 92.06,66.35 99.22,66.35 100.17,67.3 100.17,70.53 102.71,73.07 102.71,74.52 108.8,80.61 108.8,94.82 109.89,95.9
  BOTTOM w0.089: v1(109.16,105.72) 109.48,106.04 UC1.AR35
  BOTTOM w0.165: JDIMM1.119 79.6,69.61 v1(80.51,68.7)
DDR_A_MA14: length 74.7
  IN1 w0.084: 99.81,93.66 99.81,93.76 103.13,97.08 103.94,97.08 105.71,98.85 105.71,100.71 v1(105.13,101.28)
  IN1 w0.183: v1(67.97,60.7) 68.35,60.7 68.48,60.83 68.48,61.78 68.35,61.91 67.97,61.91 67.84,62.03 67.84,62.53 67.97,62.65 68.3,62.65 68.48,62.84 68.48,63.2 68.3,63.39 67.97,63.39 67.84,63.51 67.84,69.4 68.68,70.25 68.68,74.02 73.9,79.25 90.25,79.25 99.81,88.82 99.81,93.66
  BOTTOM w0.076: UC1.AV42 104.41,103.94 104.41,102.58 104.73,102.27 104.73,101.69 v1(105.13,101.28)
  BOTTOM w0.165: JDIMM1.80 67.9,62.25 68.41,61.74 68.41,61.14 v1(67.97,60.7)
DDR_A_MA15: length 76.9
  IN1 w0.084: v1(105.13,100.63) 104.85,100.35 104.85,99.15 99.89,94.18 99.53,94.18 99.35,94 99.35,93.66
  IN1 w0.183: 99.35,93.66 99.35,89.01 90.06,79.71 73.71,79.71 68.22,74.22 68.22,70.44 67.38,69.6 67.38,59.26 67.29,59.17 v1(66.45,59.17)
  BOTTOM w0.076: UC1.AU42 104.51,104.74 104.51,104.67 104.25,104.41 104.25,102.44 104.56,102.13 104.56,101.2 v1(105.13,100.63)
  BOTTOM w0.165: v1(66.45,59.17) 67.3,60.02 JDIMM1.78
DDR_A_RAS#: length 75.3
  IN1 w0.084: 111.01,101.94 111.37,101.59 111.37,95.66 111.11,95.4 111.11,94.57
  IN1 w0.089: 111.01,101.94 v1(110.66,101.94)
  IN1 w0.183: 111.11,94.57 111.11,79.73 105.41,74.03 105.41,72.43 102.68,69.69 102.68,66.61 98.67,62.6 78.13,62.6 76.94,61.4 76.94,59.87 v1(77.63,59.17)
  BOTTOM w0.076: v1(110.66,101.94) 110.25,102.34 UC1.AY34
  BOTTOM w0.165: v1(77.63,59.17) 76.9,59.9 JDIMM1.110
DDR_A_WE#: length 75.1
  IN1 w0.084: v1(109.86,103.28) 109.79,103.21 109.79,102 111.02,100.77 111.02,95.94 110.19,95.11 110.19,94.57
  IN1 w0.183: v1(78.98,68.7) 79.59,68.08 79.59,67.13 79.86,66.86 79.86,66.37 80.93,65.31 80.93,64.15 81.13,63.94 83.76,63.94 83.94,64.12 83.94,64.72 84.12,64.91 84.49,64.91 84.67,64.72 84.67,64.12 84.86,63.94 87.49,63.94 87.67,64.12 87.67,64.72 87.85,64.91 88.22,64.91 88.4,64.72 88.4,64.12 88.58,63.94 98.77,63.94 101.8,66.97 101.8,70.06 104.54,72.79 104.54,74.39 110.19,80.04 110.19,94.57
  BOTTOM w0.089: v1(109.86,103.28) 110.15,103.28 110.25,103.38 UC1.AW34
  BOTTOM w0.165: JDIMM1.113 77.8,69.88 v1(78.98,68.7)
DDR_B_BS0: length 95.8
  IN3 w0.084: v1(109.16,108.32) 108.87,108.32 108.78,108.23 108.78,105.04 109.09,104.72 109.09,99.68 108.61,99.2 108.61,97.5 108.22,97.1 108.22,96.4
  IN3 w0.208: 108.22,96.4 108.22,90.11 119.52,78.8 128.36,78.8 128.56,78.59 128.56,76.98 128.76,76.78 129.22,76.78 129.42,76.98 129.42,78.59 129.63,78.8 130.08,78.8 130.29,78.59 130.29,76.98 130.49,76.78 130.95,76.78 131.15,76.98 131.15,78.59 131.35,78.8 131.81,78.8 132.01,78.59 132.01,76.98 132.22,76.78 132.68,76.78 132.88,76.98 132.88,78.59 133.08,78.8 133.54,78.8 133.74,78.59 133.74,76.98 133.95,76.78 151.16,76.78 151.29,76.66 151.29,76.18 151.44,76.03 151.84,76.03 152.05,76.24 152.05,76.58 152.25,76.78 152.65,76.78 152.86,76.58 152.86,76.12 153.06,75.92 153.52,75.92 154.4,75.04 154.4,74.75 154.22,74.57 154.22,74.26 155.04,73.44 155.3,73.44 155.87,72.88 v1(155.87,68.72)
  BOTTOM w0.076: v1(109.16,108.32) 109.48,108.64 UC1.AL35
  BOTTOM w0.165: JDIMM2.109 155.15,70.31 155.54,69.92 155.54,69.67 155.15,69.28 155.15,68.92 155.35,68.72 v1(155.87,68.72)
DDR_B_BS1: length 97.9
  IN3 w0.084: 107.28,94.57 107.28,96.59 107.28,96.59 107.28,98.97 107.83,99.52 107.83,107.45 v1(108.21,107.82)
  IN3 w0.208: v1(156.04,59.21) 155.65,59.21 155.45,59.42 155.45,61.91 155.65,62.11 156.48,62.11 156.68,62.32 156.68,62.77 156.48,62.98 154.57,62.98 154.44,63.11 154.44,63.71 154.57,63.84 154.96,63.84 155.16,64.04 155.16,64.5 154.96,64.71 154.29,64.71 154.08,64.91 154.08,65.53 154.29,65.73 154.72,65.73 154.94,65.95 154.94,71.37 153.4,72.91 153.4,73.75 153.05,74.1 152.06,74.1 150.31,75.85 124.41,75.85 124.17,76.08 124.17,77.65 123.96,77.87 119.14,77.87 107.28,89.72 107.28,94.57
  BOTTOM w0.076: v1(108.21,107.82) 108.38,107.99 UC1.AM36
  BOTTOM w0.165: v1(156.04,59.21) 154.85,60.4 JDIMM2.108
DDR_B_BS2: length 92.6
  IN3 w0.084: 98.95,93.66 98.95,95.23 100.72,97 100.72,101.79 100.94,102.01 100.94,104.03 v1(100.41,104.56)
  IN3 w0.208: v1(144.84,67.2) 145.38,66.66 145.38,65.67 144.81,65.1 144.81,63.64 144.55,63.37 119.23,63.37 110.26,72.34 110.26,72.67 111.37,73.77 111.37,74.06 110.95,74.48 110.66,74.48 109.54,73.36 109.25,73.36 108.93,73.68 108.93,73.97 110.05,75.09 110.05,75.38 109.73,75.7 109.44,75.7 108.7,74.96 108.41,74.96 108.09,75.28 108.09,75.57 108.82,76.3 108.82,76.61 98.95,86.48 98.95,93.66
  BOTTOM w0.076: v1(100.41,104.56) 100.53,104.56 UC1.AU49
  BOTTOM w0.165: v1(144.84,67.2) 145.28,67.64 145.28,69.25 146.15,70.11 JDIMM2.79
DDR_B_CAS#: length 96.2
  IN3 w0.084: v1(110.01,107.71) 110.01,107.62 110.48,107.15 110.48,103.96 110.25,103.73 110.25,102.23 109.88,101.86 109.88,101.55 110.01,101.42 110.39,101.42 110.52,101.29 110.52,98.69 110.39,98.56 109.76,98.56 109.63,98.43 109.63,96.34
  IN3 w0.208: v1(157.43,68.72) 158.01,68.15 158.27,68.15 158.49,68.36 158.49,68.92 158.62,69.05 158.62,72.2 158.15,72.66 158.15,73.28 153.24,78.19 142.26,78.19 142.06,78.39 142.06,80 141.86,80.21 141.4,80.21 141.2,80 141.2,78.39 140.99,78.19 140.54,78.19 140.33,78.39 140.33,80 140.13,80.21 139.67,80.21 139.47,80 139.47,78.39 139.27,78.19 138.81,78.19 138.61,78.39 138.61,80 138.4,80.21 137.95,80.21 137.74,80 137.74,78.39 137.54,78.19 137.08,78.19 136.88,78.39 136.88,80 136.68,80.21 120.11,80.21 109.63,90.69 109.63,96.34
  BOTTOM w0.076: v1(110.01,107.71) 110.08,107.71 110.37,107.99 UC1.AM33
  BOTTOM w0.165: v1(157.43,68.72) 156.95,69.2 JDIMM2.115
DDR_B_D0: length 80.9
  IN3 w0.084: 112.95,94.57 112.95,95.11 112.69,95.37 112.69,97.6 112.56,97.72 v1(111.96,97.72)
  IN3 w0.127: v1(161.24,66.71) 161.89,66.71 162.03,66.84 162.03,69.48 162.45,69.9 162.45,73.77 154.7,81.52 151.53,81.52 150.42,82.62 149.6,82.62 148.69,83.53 121.86,83.53 116.81,88.59 116.44,88.59 112.95,92.07 112.95,94.57
  BOTTOM w0.076: v1(111.96,97.72) 111.19,98.49 111.19,101.3 111.38,101.48 111.38,102.81 UC1.AY31
  BOTTOM w0.102: JDIMM2.132 162.05,65.9 v1(161.24,66.71)
DDR_B_D1: length 82
  IN3 w0.084: v1(111.96,97.07) 111.96,97.25 112.08,97.37 112.39,97.37 112.52,97.25 112.52,95.14 112.59,95.07 112.59,94.57
  IN3 w0.127: 112.59,94.57 112.59,91.92 116.28,88.22 116.66,88.22 121.71,83.17 148.54,83.17 149.45,82.26 150.27,82.26 151.38,81.16 154.56,81.16 161.61,74.11 161.61,73.48 161.73,73.35 161.96,73.35 162.09,73.23 162.09,72.92 161.96,72.79 161.73,72.79 161.61,72.66 161.61,72.4 161.73,72.28 161.96,72.28 162.09,72.15 162.09,70.05 161.66,69.63 161.66,68.34 161.56,68.23 v1(161.24,68.23)
  BOTTOM w0.076: v1(111.96,97.07) 111.37,97.07 111.02,97.42 111.02,101.37 111.21,101.55 111.21,103 111.3,103.18 111.5,103.38 UC1.AW31
  BOTTOM w0.102: JDIMM2.131 161.75,70.29 161.57,70.11 161.57,70.05 161.74,69.88 161.74,68.17 161.83,68.08 161.83,67.96 161.73,67.85 161.37,67.85 161.24,67.98 v1(161.24,68.23)
DDR_B_D2: length 81.4
  IN3 w0.084: 115.19,93.94 115.19,94.17 114,95.37 114,96.66 v1(113.58,97.07)
  IN3 w0.127: 115.19,93.94 115.19,93.03 117.4,90.83 117.74,90.83 122.79,85.77 149.62,85.77 150.53,84.86 151.35,84.86 152.45,83.76 155.93,83.76 164.69,75 164.69,67.77 164.26,67.34 164.26,66.83 164.39,66.71 v1(165.47,66.71)
  BOTTOM w0.076: v1(113.58,97.07) 112.74,97.92 112.74,101.81 112.85,101.92 UC1.AY29
  BOTTOM w0.102: v1(165.47,66.71) 164.45,65.68 JDIMM2.140
DDR_B_D3: length 82.1
  IN3 w0.084: v1(113.58,97.72) 113.88,98.02 114.21,98.02 114.33,97.9 114.33,97.46 114.22,97.36 114.04,97.36 113.95,97.26 113.95,97.13 114.08,97 114.21,97 114.33,96.88 114.33,95.28 115.55,94.05 115.55,93.94
  IN3 w0.127: v1(165.47,68.23) 165.18,68.23 165.05,68.36 165.05,70.04 165.19,70.17 165.31,70.17 165.43,70.3 165.43,70.56 165.31,70.69 165.19,70.69 165.05,70.82 165.05,71.07 165.19,71.2 165.31,71.2 165.43,71.33 165.43,71.59 165.31,71.72 165.19,71.72 165.05,71.85 165.05,73.43 165.19,73.56 165.31,73.56 165.43,73.69 165.43,73.95 165.31,74.08 165.19,74.08 165.05,74.21 165.05,75.15 156.08,84.12 152.6,84.12 151.5,85.22 150.68,85.22 149.77,86.14 122.94,86.14 117.89,91.19 117.55,91.19 115.55,93.18 115.55,93.94
  BOTTOM w0.076: UC1.AW29 112.85,103.35 113.15,103.05 113.15,102.81 113.02,102.68 113.02,101.83 112.91,101.72 112.91,98.4 v1(113.58,97.72)
  BOTTOM w0.102: v1(165.47,68.23) 165.45,68.23 164.75,68.93 JDIMM2.141
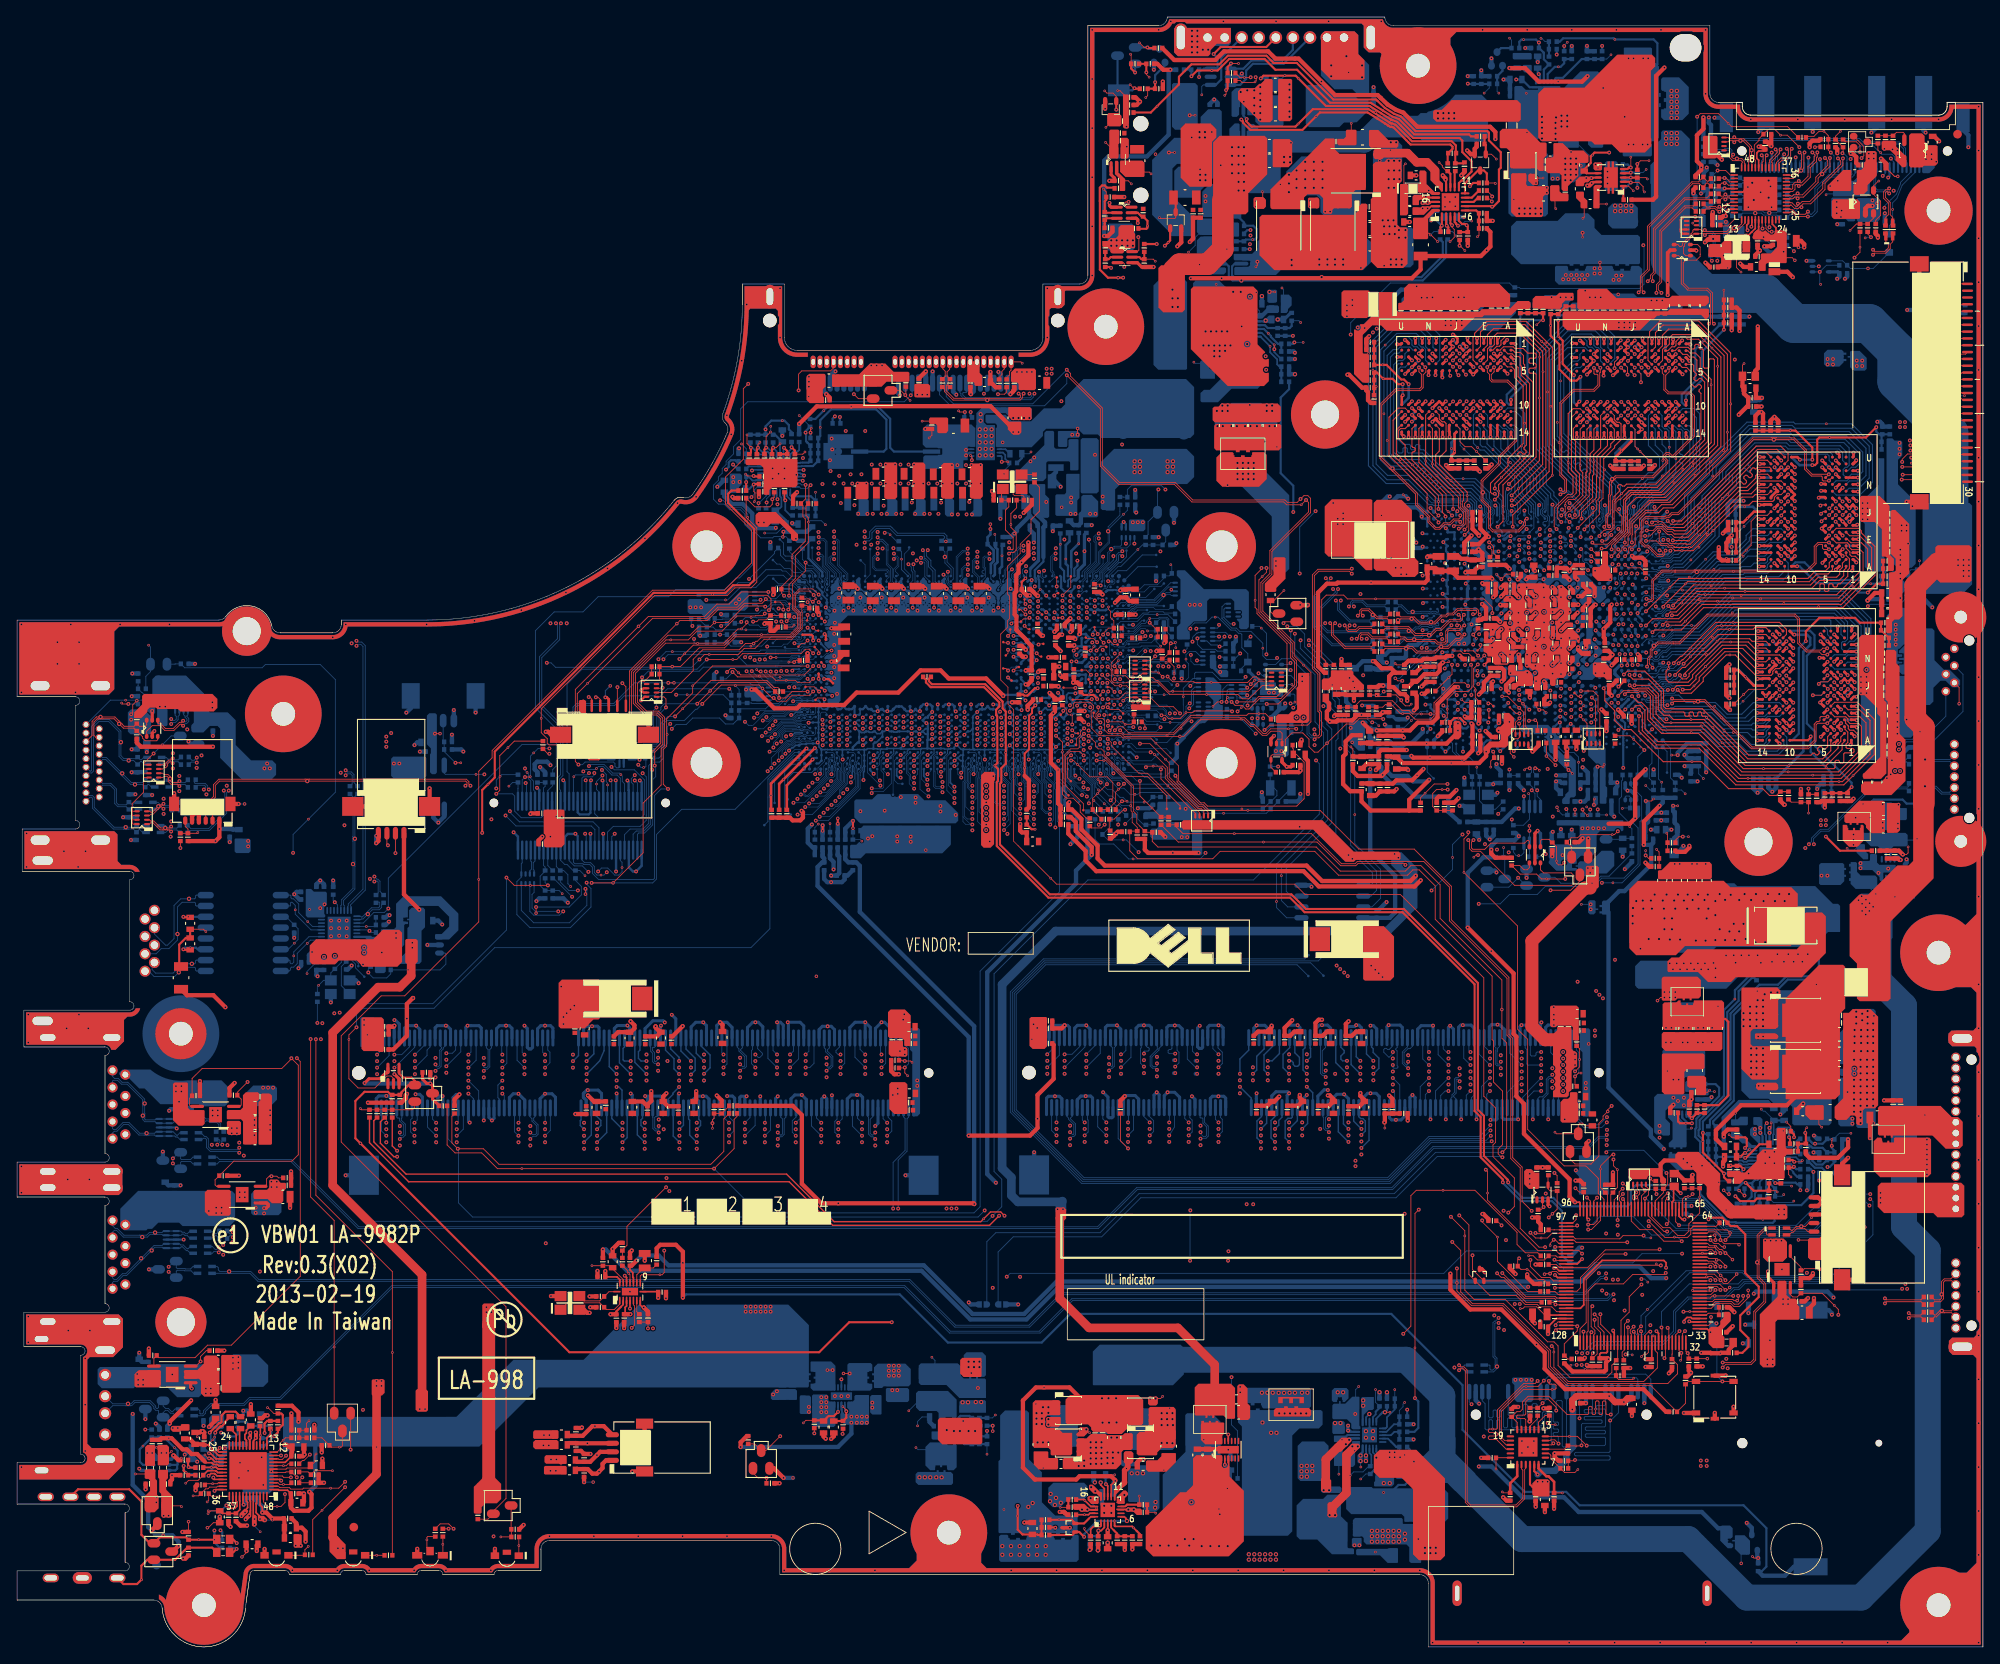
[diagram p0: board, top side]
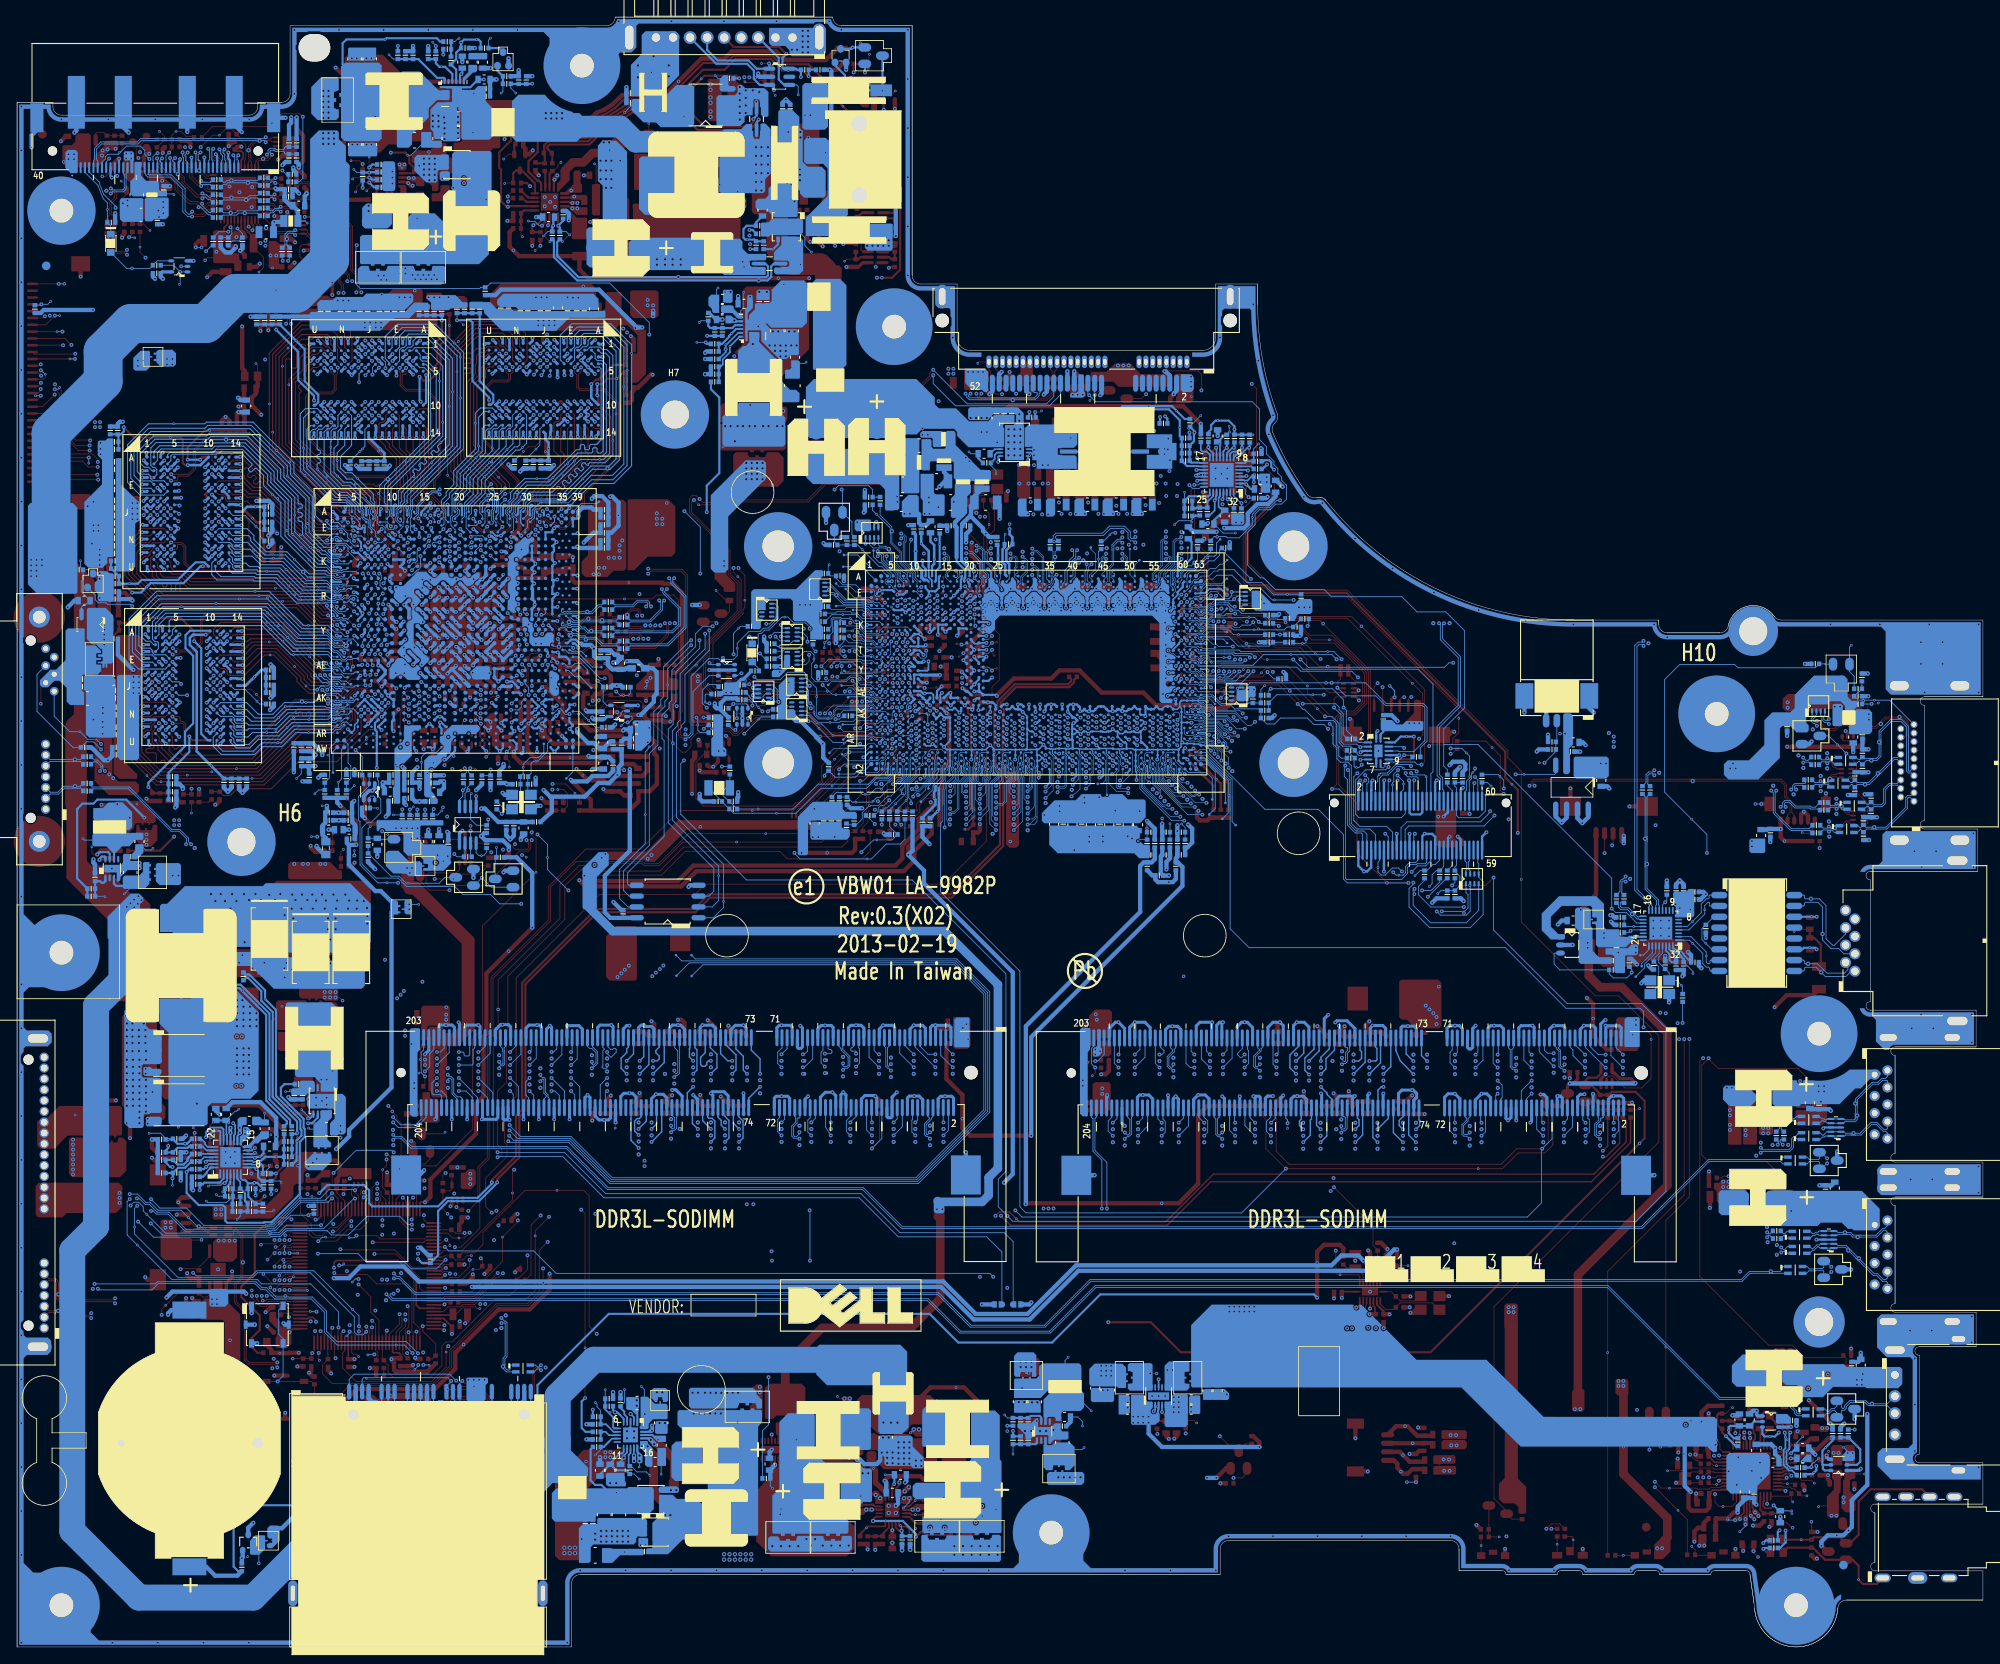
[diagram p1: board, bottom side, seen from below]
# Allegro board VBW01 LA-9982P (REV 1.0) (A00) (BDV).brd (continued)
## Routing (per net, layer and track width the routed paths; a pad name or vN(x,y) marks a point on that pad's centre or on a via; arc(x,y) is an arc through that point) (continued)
DDR_B_D4: length 84.4
  IN3 w0.084: 112.23,95.33 112.35,95.45 112.35,96.6 112.23,96.72 112.07,96.72 111.96,96.6 v1(111.96,96.42)
  IN3 w0.127: v1(161.24,69.75) 161.24,70.1 161.32,70.18 161.6,70.18 161.72,70.31 161.72,70.62 161.6,70.75 161.34,70.75 161.22,70.88 161.22,71.2 161.34,71.33 161.6,71.33 161.72,71.45 161.72,71.72 161.6,71.84 161.37,71.84 161.24,71.97 161.24,73.96 154.41,80.79 151.22,80.79 151.07,80.95 150.88,80.95 150.72,80.79 150.54,80.79 150.33,81 150.33,81.17 150.49,81.33 150.49,81.52 150.12,81.9 149.92,81.9 149.76,81.74 149.47,81.74 148.39,82.81 121.19,82.81 121.06,82.93 121.06,83.31 120.8,83.58 120.42,83.58 120.23,83.76 120.23,84.14 120.03,84.34 119.66,84.34 119.47,84.52 119.47,84.9 119.33,85.04 118.96,85.04 118.77,85.22 118.77,85.6 118.64,85.74 118.26,85.74 118.14,85.86 118.14,86.23 118,86.37 117.62,86.37 117.44,86.55 117.44,86.93 117.24,87.13 116.86,87.13 116.68,87.32 116.68,87.69 116.51,87.86 116.13,87.86 112.23,91.77 112.23,95.33
  BOTTOM w0.076: 111.77,96.42 110.86,97.33 ; 111.77,96.42 111.2,96.42 110.86,96.76 110.86,97.33 ; 111.77,96.42 v1(111.96,96.42) ; 110.86,97.33 110.86,101.43 111.04,101.62 111.04,103.04 111.07,103.08 111.12,103.19 111.12,103.85 UC1.AV31
  BOTTOM w0.102: v1(161.24,69.75) 161.24,69.57 160.84,69.17 160.74,69.17 160.18,69.73 160.18,70.05 160.3,70.18 160.49,70.18 160.62,70.05 160.81,70.05 161.15,70.39 JDIMM2.129
DDR_B_D5: length 83.4
  IN3 w0.084: 113.32,94.21 113.32,95.02 112.86,95.47 112.86,98.12 v1(111.96,99.02)
  IN3 w0.127: 113.32,94.21 113.32,92.22 116.59,88.95 116.96,88.95 122.02,83.9 148.84,83.9 149.75,82.99 150.57,82.99 151.68,81.88 154.84,81.88 162.81,73.91 162.81,69.75 162.39,69.33 162.39,65.48 162.09,65.18 v1(161.24,65.18)
  BOTTOM w0.076: UC1.AU31 112.27,104.88 112.47,104.68 112.47,104.44 112.45,104.42 112.45,104.04 112.47,104.03 112.47,103.84 112.46,103.83 112.42,103.74 112.42,103.74 112.4,103.69 112.4,103.48 112.47,103.32 112.47,103.19 112.42,103.09 112.4,103.03 112.4,102.6 112.5,102.49 112.5,102.09 112.38,101.97 112.38,99.45 v1(111.96,99.02)
  BOTTOM w0.102: JDIMM2.130 161.45,64.97 v1(161.24,65.18)
DDR_B_D6: length 82.9
  IN3 w0.084: v1(113.58,95.77) 113.58,95.54 114.84,94.28 114.84,93.94
  IN3 w0.127: 114.84,93.94 114.84,92.88 117.25,90.47 117.59,90.47 122.64,85.42 149.47,85.42 150.38,84.51 151.2,84.51 152.31,83.4 155.49,83.4 155.5,83.39 155.78,83.39 164.33,74.85 164.33,74.57 164.33,74.56 164.33,67.99 163.9,67.55 163.9,65.31 164.02,65.18 v1(165.47,65.18)
  BOTTOM w0.076: UC1.AV29 112.66,104.15 112.66,103.81 112.61,103.75 112.56,103.65 112.56,103.52 112.57,103.5 112.61,103.41 112.64,103.36 112.64,103.16 112.56,103 112.56,102.67 112.66,102.56 112.66,101.97 112.56,101.87 112.56,96.79 v1(113.58,95.77)
  BOTTOM w0.102: v1(165.47,65.18) 165.05,64.76 JDIMM2.142
DDR_B_D7: length 83.2
  IN3 w0.084: 115.92,93.94 115.92,94.09 115.76,94.24 115.61,94.24 115.58,94.28 114.5,95.35 114.5,100.46 114.38,100.59 114.2,100.59 114.07,100.46 114.07,98.5 113.95,98.37 v1(113.58,98.37)
  IN3 w0.127: 115.92,93.94 115.92,93.33 117.7,91.55 118.04,91.55 123.09,86.5 149.92,86.5 150.83,85.59 151.65,85.59 152.76,84.48 156.23,84.48 165.42,75.3 165.42,74.62 165.54,74.5 165.67,74.5 165.8,74.37 165.8,73.35 165.67,73.23 165.54,73.23 165.42,73.1 165.42,72.12 165.54,71.99 165.67,71.99 165.8,71.87 165.8,69.88 165.67,69.75 v1(165.47,69.75)
  BOTTOM w0.076: v1(113.58,98.37) 113.07,98.88 113.07,101.63 113.18,101.74 113.18,102.62 113.31,102.74 113.31,103.12 113.15,103.29 113.15,103.7 113.02,103.83 113.02,104.09 113.04,104.11 113.04,104.35 112.75,104.65 UC1.AU29
  BOTTOM w0.102: JDIMM2.143 165.35,69.86 165.47,69.73 v1(165.47,69.75)
DDR_B_D8: length 55.4
  IN1 w0.084: 113.43,94.1 113.43,95.37 113.19,95.61 113.19,99.28 v1(113.58,99.67)
  IN1 w0.127: v1(120.74,69.48) 120.31,69.06 120.13,69.06 119.74,69.45 119.74,69.63 120.88,70.78 120.88,70.96 120.7,71.15 120.52,71.15 119.37,70 119.19,70 119,70.19 119,70.37 119.88,71.24 119.88,71.42 119.69,71.61 119.51,71.61 118.63,70.74 118.45,70.74 118.26,70.93 118.26,71.11 118.91,71.75 118.91,71.93 118.72,72.12 118.54,72.12 117.89,71.47 117.71,71.47 117.53,71.66 117.53,71.84 118.16,72.48 118.16,72.66 117.97,72.85 117.79,72.85 117.16,72.21 116.98,72.21 116.79,72.4 116.79,72.58 117.98,73.77 117.98,73.95 117.79,74.14 117.61,74.14 116.42,72.95 116.24,72.95 116.05,73.14 116.05,73.31 116.56,73.82 116.56,74 116.37,74.19 116.19,74.19 115.94,73.94 115.75,73.94 113.43,76.26 113.43,94.1
  BOTTOM w0.076: UC1.AY27 113.81,102.81 113.81,102.54 113.69,102.42 113.69,101.8 114.14,101.35 114.14,100.23 v1(113.58,99.67)
  BOTTOM w0.102: v1(120.74,69.48) 121.55,70.3 JDIMM2.5
DDR_B_D9: length 56.3
  IN1 w0.084: v1(113.58,100.32) 112.99,99.73 112.99,95.18 113.07,95.1 113.07,94.46
  IN1 w0.127: 113.07,94.46 113.07,75.63 120.25,68.46 120.25,66.9 120.37,66.77 121.2,66.77 121.33,66.65 121.33,66.39 121.2,66.27 120.37,66.27 120.25,66.14 120.25,65.89 120.37,65.76 121.63,65.76 121.76,65.63 121.76,65.38 121.63,65.25 120.37,65.25 120.25,65.12 120.25,64.87 120.37,64.74 121.1,64.74 121.23,64.62 121.23,64.36 121.1,64.23 120.37,64.23 120.25,64.11 120.25,63.85 120.37,63.73 120.94,63.73 121.06,63.6 121.06,63.35 120.94,63.22 120.37,63.22 120.25,63.09 120.25,62.84 120.37,62.71 121.25,62.71 121.82,62.14 v1(121.82,61.5)
  BOTTOM w0.076: UC1.AW27 113.93,103.35 113.64,103.05 113.64,102.61 113.53,102.49 113.53,101.73 113.98,101.28 113.98,100.72 v1(113.58,100.32)
  BOTTOM w0.102: JDIMM2.6 121.85,61.53 v1(121.82,61.5)
DDR_B_D10: length 55.8
  IN1 w0.084: v1(115.67,97.07) 115.34,97.07 115.22,97.2 115.22,97.68 115.09,97.81 114.75,97.81 114.62,97.68 114.62,94.46 114.75,94.34 115.2,94.34 115.33,94.21 115.33,93.94
  IN1 w0.127: 115.33,93.94 115.33,79.35 118.38,76.29 118.61,76.29 119.36,77.04 119.52,77.04 119.73,76.83 119.73,76.67 118.9,75.84 118.9,75.66 119.09,75.48 119.27,75.48 120.1,76.3 120.26,76.3 120.46,76.1 120.46,75.94 119.64,75.11 119.64,74.93 119.82,74.74 120,74.74 120.83,75.57 120.99,75.57 121.2,75.36 121.2,75.2 120.37,74.37 120.37,74.19 120.56,74 120.74,74 121.57,74.83 121.73,74.83 121.94,74.62 121.94,74.46 121.11,73.63 121.11,73.45 121.3,73.27 121.48,73.27 122.31,74.09 122.47,74.09 122.67,73.89 122.67,73.73 121.84,72.89 121.84,72.73 122.77,71.8 v1(122.77,69.48)
  BOTTOM w0.076: v1(115.67,97.07) 116.06,97.47 116.06,101.14 115.6,101.6 115.58,101.6 115.16,102.03 115.16,102.81 UC1.AY25
  BOTTOM w0.102: JDIMM2.15 124.55,70.4 123.63,69.48 v1(122.77,69.48)
DDR_B_D11: length 56.4
  IN1 w0.084: 115.68,93.94 115.68,94.44 115.55,94.56 114.96,94.56 114.84,94.69 114.84,95.06 114.92,95.14 115.2,95.14 115.28,95.22 115.28,95.39 115.2,95.47 114.92,95.47 114.84,95.56 114.84,95.73 114.92,95.81 115.2,95.81 115.28,95.89 115.28,96.06 115.2,96.15 114.92,96.15 114.84,96.23 114.84,96.6 114.96,96.72 115.54,96.72 115.67,96.6 v1(115.67,96.42)
  IN1 w0.127: 115.68,93.94 115.68,81.43 116.06,81.05 116.06,80.84 115.68,80.47 115.68,79.51 116.04,79.15 116.33,79.15 117.03,79.85 117.19,79.85 117.4,79.65 117.4,79.49 116.69,78.78 116.69,78.6 116.88,78.41 117.06,78.41 117.77,79.12 117.93,79.12 118.14,78.91 118.14,78.75 117.41,78.02 117.41,77.84 117.6,77.65 117.78,77.65 118.51,78.38 118.67,78.38 118.87,78.17 118.87,78.01 118.15,77.29 118.15,77.11 118.34,76.92 118.52,76.92 119.24,77.64 119.45,77.64 123.39,73.7 123.39,68.58 v1(122.77,67.96)
  BOTTOM w0.076: v1(115.67,96.42) 116.23,96.98 116.23,101.21 115.67,101.77 115.65,101.77 115.32,102.09 115.32,102.55 115.58,102.81 115.58,103 115.53,103.1 115.53,103.1 115.5,103.16 115.5,103.36 UC1.AW25
  BOTTOM w0.102: JDIMM2.17 125.15,70.34 v1(122.77,67.96)
DDR_B_D12: length 56.6
  IN1 w0.084: 112.72,94.57 112.72,95.87 112.67,95.92 112.67,100.06 v1(113.58,100.97)
  IN1 w0.127: 112.72,94.57 112.72,75.48 119.89,68.31 119.89,62.42 120.02,62.3 121.12,62.3 121.25,62.17 121.25,61.91 121.12,61.79 120.02,61.79 119.89,61.66 119.89,61.41 120.02,61.28 121.12,61.28 121.25,61.15 121.25,60.9 121.12,60.77 120.74,60.77 120.62,60.64 120.62,60.39 120.74,60.26 121.53,60.26 v1(121.82,59.98)
  BOTTOM w0.076: v1(113.58,100.97) 113.58,101.4 113.35,101.64 113.35,102.55 113.48,102.67 113.48,103.13 113.64,103.3 113.64,103.7 114.04,104.1 UC1.AV27
  BOTTOM w0.102: JDIMM2.4 121.25,60.55 v1(121.82,59.98)
DDR_B_D13: length 57.2
  IN1 w0.084: v1(115.67,100.32) 116.04,99.95 116.04,95.89 116.54,95.39 116.54,94.03 116.45,93.94
  IN1 w0.127: v1(125.12,61.5) 125.12,63.07 125,63.2 123.88,63.2 123.76,63.33 123.76,63.83 123.88,63.96 124.74,63.96 124.87,64.09 124.87,64.37 124.74,64.49 123.88,64.49 123.76,64.62 123.76,64.9 123.88,65.03 124.93,65.03 125.06,65.15 125.06,65.43 124.93,65.56 123.88,65.56 123.76,65.69 123.76,65.97 123.88,66.09 124.62,66.09 124.74,66.22 124.74,66.5 124.62,66.63 123.88,66.63 123.76,66.75 123.76,67.55 124.1,67.89 124.1,74 116.45,81.65 116.45,93.94
  BOTTOM w0.076: v1(115.67,100.32) 115.24,100.75 115.24,101.08 114.83,101.49 114.83,103.03 114.9,103.19 114.9,103.32 114.83,103.48 114.83,103.69 114.85,103.74 114.85,103.74 114.89,103.83 114.9,103.84 114.9,104.68 114.7,104.88 UC1.AU27
  BOTTOM w0.102: JDIMM2.16 124.85,61.77 v1(125.12,61.5)
DDR_B_D14: length 56.7
  IN1 w0.084: 113.79,93.94 113.79,95.42 113.98,95.61 113.98,99.29 v1(115.67,100.97)
  IN1 w0.127: 113.79,93.94 113.79,78.62 114,78.41 114,78.23 113.79,78.02 113.79,77.72 114,77.51 114.18,77.51 114.4,77.73 114.58,77.73 114.76,77.54 114.76,77.36 113.9,76.5 113.9,76.32 114.09,76.13 114.27,76.13 115.15,77.01 115.33,77.01 115.51,76.82 115.51,76.64 114.62,75.74 114.62,75.56 114.8,75.37 114.98,75.37 115.9,76.29 116.08,76.29 116.27,76.1 116.27,75.92 115.35,75 115.35,74.82 115.54,74.63 115.72,74.63 116.66,75.57 116.84,75.57 117,75.41 117,75.23 116.54,74.77 116.54,74.59 116.74,74.4 116.92,74.4 117.38,74.85 117.56,74.85 118.6,73.81 118.6,73.61 118.43,73.44 118.43,72.91 119.38,71.96 119.66,71.96 119.96,72.26 120.15,72.26 121.23,71.18 121.23,68.08 121.1,67.96 v1(120.74,67.96)
  BOTTOM w0.076: v1(115.67,100.97) 114.99,101.65 114.99,103 115.04,103.1 115.07,103.16 115.07,103.36 115.04,103.41 115,103.5 114.99,103.52 114.99,103.65 115.04,103.75 115.28,104 UC1.AV25
  BOTTOM w0.102: v1(120.74,67.96) 122.15,69.37 JDIMM2.7
DDR_B_D15: length 58.2
  IN1 w0.084: v1(115.67,95.77) 115.61,95.71 115.61,94.93 116.1,94.44 116.1,93.94
  IN1 w0.127: v1(125.12,59.98) 124.7,60.4 124.23,60.4 124.11,60.53 124.11,60.91 124.23,61.03 124.58,61.03 124.71,61.16 124.71,61.56 124.58,61.69 123.92,61.69 123.79,61.81 123.79,62.09 123.92,62.22 124.58,62.22 124.71,62.35 124.71,62.73 124.58,62.86 123.53,62.86 123.4,62.98 123.4,67.7 123.74,68.04 123.74,73.85 117.13,80.47 116.91,80.47 116.44,80 116.26,80 116.07,80.19 116.07,80.37 116.54,80.84 116.54,81.06 116.1,81.5 116.1,93.94
  BOTTOM w0.076: v1(115.67,95.77) 116.39,96.5 116.39,101.27 115.73,101.93 115.72,101.93 115.49,102.16 115.49,102.49 115.6,102.6 115.74,102.74 115.74,103.03 115.69,103.14 115.67,103.19 115.67,104.5 UC1.AU25
  BOTTOM w0.102: JDIMM2.18 125.45,61.85 125.53,61.77 125.53,60.38 v1(125.12,59.98)
DDR_B_D16: length 89.4
  IN3 w0.084: 116.92,93.94 116.92,94 116.33,94.59 115.78,94.59 115.53,94.84 114.89,95.49 114.89,100.57 112.15,103.31 112.15,105.29 111.99,105.44 111.99,107.12 v1(112.54,107.67)
  IN3 w0.127: 116.92,93.94 116.92,93.75 117.55,93.12 118.11,92.56 118.46,92.56 123.51,87.5 150.34,87.5 151.25,86.59 152.07,86.59 153.17,85.49 156.75,85.49 166.8,75.44 166.8,66.18 166.93,66.05 167.21,66.05 167.34,66.18 167.34,66.58 167.46,66.71 v1(167.76,66.71)
  BOTTOM w0.076: UC1.AM29 112.86,107.99 v1(112.54,107.67)
  BOTTOM w0.102: v1(167.76,66.71) 166.25,65.2 JDIMM2.146
DDR_B_D17: length 90.9
  IN3 w0.084: 116.3,94.24 116.12,94.42 115.68,94.42 115.41,94.69 114.7,95.4 114.7,100.52 111.97,103.24 111.97,105.2 111.82,105.35 111.82,108.25 v1(112.54,108.97)
  IN3 w0.127: 116.3,94.24 116.56,93.98 116.56,93.6 117.96,92.19 118.31,92.19 123.36,87.14 150.19,87.14 151.1,86.23 151.92,86.23 153.02,85.13 156.6,85.13 166.44,75.29 166.44,64.72 166.57,64.59 167.63,64.59 167.76,64.72 v1(167.76,65.18)
  BOTTOM w0.076: v1(112.54,108.97) 112.86,109.3 UC1.AK29
  BOTTOM w0.102: v1(167.76,65.18) 167.37,65.18 166.85,64.66 JDIMM2.148
DDR_B_D18: length 89.6
  IN3 w0.084: v1(113.48,108.32) 113.95,107.85 113.95,107.23 114.04,107.14 114.04,105.34 116.79,102.6 116.79,96.2 117.91,95.08 118.09,95.08 118.43,94.75 119.79,94.75 120.55,93.98 121.29,93.98 121.66,93.61
  IN3 w0.127: v1(170.34,66.71) 170.78,67.14 170.78,75.95 157.17,89.56 155.48,89.56 154.57,90.47 126.45,90.47 125.93,90.98 124.29,90.98 121.66,93.61
  BOTTOM w0.076: v1(113.48,108.32) 113.8,108.64 UC1.AL28
  BOTTOM w0.102: JDIMM2.160 170.45,64.39 170.78,64.72 170.78,66.26 v1(170.34,66.71)
DDR_B_D19: length 90.3
  IN3 w0.084: 122.29,93.61 121.75,94.16 120.63,94.16 119.86,94.92 118.5,94.92 118.17,95.25 117.98,95.25 116.96,96.27 116.96,102.81 114.82,104.95 114.82,108.45 v1(114.31,108.96)
  IN3 w0.127: 122.29,93.61 124.56,91.35 126.08,91.35 126.6,90.83 154.72,90.83 155.63,89.92 157.32,89.92 171.14,76.1 171.14,66.99 170.87,66.72 170.87,65.71 v1(170.34,65.18)
  BOTTOM w0.076: v1(114.31,108.96) 113.98,109.3 UC1.AK28
  BOTTOM w0.102: v1(170.34,65.18) 169.85,64.69 JDIMM2.158
DDR_B_D20: length 87.1
  IN3 w0.084: v1(112.54,105.72) 112.54,103.41 115.27,100.68 115.27,95.61 115.8,95.07 115.94,94.94 116.69,94.94 117.52,94.1 117.67,94.1 117.83,93.94
  IN3 w0.127: v1(167.76,69.75) 167.76,69.75 168.03,69.48 168.27,69.48 168.4,69.61 168.4,70.14 168.27,70.27 167.65,70.27 167.52,70.4 167.52,70.66 167.65,70.79 168.27,70.79 168.4,70.91 168.4,71.17 168.27,71.3 167.65,71.3 167.52,71.43 167.52,71.69 167.65,71.82 168.19,71.82 168.32,71.94 168.32,72.21 168.19,72.33 167.65,72.33 167.52,72.46 167.52,75.74 157.05,86.21 156.28,86.21 156.14,86.34 156.14,87.12 156.01,87.25 155.75,87.25 155.63,87.12 155.63,86.34 155.5,86.22 155.24,86.22 155.11,86.34 155.11,87.19 154.99,87.31 151.55,87.31 150.64,88.22 123.81,88.22 118.75,93.28 118.49,93.28 117.83,93.94
  BOTTOM w0.089: v1(112.54,105.72) 112.79,105.72 112.92,105.85 UC1.AR29
  BOTTOM w0.102: JDIMM2.149 167.15,70.13 167.52,69.75 v1(167.76,69.75)
DDR_B_D21: length 88.8
  IN3 w0.084: 117,94.25 116.5,94.76 115.87,94.76 115.08,95.55 115.08,100.63 112.35,103.35 112.35,105.33 112.17,105.51 112.17,106.94 112.24,107.02 v1(112.54,107.02)
  IN3 w0.127: 117,94.25 118.34,92.92 118.61,92.92 123.66,87.87 150.49,87.87 151.4,86.96 152.55,86.96 152.68,86.82 152.68,86.49 152.81,86.36 153.07,86.36 153.2,86.49 153.2,86.82 153.33,86.96 153.58,86.96 153.72,86.82 153.72,85.98 153.84,85.85 154.1,85.85 154.23,85.98 154.23,86.83 154.36,86.96 154.62,86.96 154.75,86.83 154.75,85.98 154.87,85.85 156.9,85.85 167.17,75.59 167.17,68.36 167.29,68.23 v1(167.76,68.23)
  BOTTOM w0.076: UC1.AN29 112.86,107.34 v1(112.54,107.02)
  BOTTOM w0.102: JDIMM2.147 166.55,69.44 v1(167.76,68.23)
DDR_B_D22: length 87.3
  IN3 w0.084: v1(113.48,105.72) 113.48,105.26 116.39,102.34 116.39,96.11 117.77,94.73 117.95,94.73 118.28,94.4 119.65,94.4 120.44,93.61 120.64,93.61
  IN3 w0.127: v1(170.34,68.23) 170.19,68.08 169.77,68.08 169.65,68.21 169.65,68.6 169.92,68.87 169.92,73.22 169.79,73.35 169.32,73.35 169.19,73.47 169.19,73.73 169.32,73.86 169.79,73.86 169.92,73.99 169.92,74.25 169.79,74.38 169.17,74.38 169.04,74.5 169.04,76.66 156.86,88.83 152.25,88.83 152.13,88.95 152.13,89.61 151.99,89.74 124.51,89.74 121.69,92.56 120.64,93.61
  BOTTOM w0.089: v1(113.48,105.72) 113.48,105.86 113.66,106.04 UC1.AR28
  BOTTOM w0.102: v1(170.34,68.23) 169.55,69.02 JDIMM2.157
DDR_B_D23: length 88
  IN3 w0.084: v1(113.48,106.37) 113.76,106.37 113.87,106.26 113.87,105.2 116.56,102.51 116.56,96.18 117.84,94.91 118.02,94.91 118.35,94.57 119.72,94.57 120.48,93.81 120.95,93.81 121.15,93.61
  IN3 w0.127: 121.15,93.61 124.14,90.62 125.21,90.62 125.34,90.49 125.34,90.23 125.47,90.11 152.36,90.11 152.49,89.98 152.49,89.32 152.61,89.19 152.87,89.19 153,89.32 153,89.98 153.13,90.11 153.39,90.11 153.52,89.98 153.52,89.32 153.64,89.19 153.9,89.19 154.03,89.32 154.03,89.98 154.16,90.11 154.42,90.11 154.55,89.98 154.55,89.32 154.67,89.19 157.01,89.19 169.4,76.81 169.4,75.9 169.53,75.77 170.29,75.77 170.41,75.64 170.41,75.38 170.29,75.26 169.53,75.26 169.4,75.13 169.4,74.86 169.52,74.74 170.21,74.74 170.34,74.61 v1(170.34,69.75)
  BOTTOM w0.076: UC1.AP28 113.65,106.69 113.48,106.52 v1(113.48,106.37)
  BOTTOM w0.102: JDIMM2.159 170.15,69.94 v1(170.34,69.75)
DDR_B_D24: length 56.6
  IN1 w0.084: 117.8,93.94 117.8,94.86 116.56,96.1 116.56,101.1 115.92,101.74 115.66,101.74 115.34,102.06 115.34,102.58 114.04,103.88 114.04,106.92 114.15,107.02 v1(114.43,107.02)
  IN1 w0.127: 117.8,93.94 117.8,84.48 118.5,83.78 118.5,81.5 126.17,73.83 126.17,62.82 126.29,62.69 127.03,62.69 127.16,62.56 127.16,62.28 127.03,62.16 126.29,62.16 126.17,62.03 126.17,61.63 126.29,61.5 v1(127.66,61.5)
  BOTTOM w0.076: UC1.AN26 114.76,107.34 v1(114.43,107.02)
  BOTTOM w0.102: JDIMM2.24 127.25,61.91 v1(127.66,61.5)
DDR_B_D25: length 56.2
  IN1 w0.084: 118.15,93.94 118.15,94.76 116.73,96.19 116.73,101.17 116.26,101.64 116.26,102.48 115.92,102.82 115.47,102.82 114.27,104.02 114.27,105.55 v1(114.43,105.72)
  IN1 w0.127: v1(127.66,59.98) 128.16,60.47 128.16,63.46 126.52,65.1 126.52,73.98 118.85,81.65 118.85,83.91 118.15,84.61 118.15,93.94
  BOTTOM w0.089: UC1.AR26 114.76,106.04 v1(114.43,105.72)
  BOTTOM w0.102: JDIMM2.22 126.65,60.99 v1(127.66,59.98)
DDR_B_D26: length 55.1
  IN1 w0.084: v1(115.38,105.72) 115.38,105.66 117,104.04 117,103.92 116.69,103.61 116.69,103.44 116.81,103.32 116.98,103.32 117.28,103.62 117.4,103.62 117.62,103.39 117.62,103.28 117.36,103.01 117.36,102.9 117.94,102.31 117.94,96.04 119.68,94.3 119.68,93.61
  IN1 w0.127: v1(129.38,69.48) 129.38,69.25 129.25,69.12 128.68,69.12 128.55,69.25 128.55,69.48 128.43,69.61 128.17,69.61 128.04,69.73 128.04,70.04 128.17,70.17 129.37,70.17 129.51,70.31 129.51,70.58 129.39,70.7 128.17,70.7 128.04,70.82 128.04,71.1 128.17,71.23 129.37,71.23 129.51,71.37 129.51,71.65 129.39,71.76 128.17,71.76 128.04,71.89 128.04,72.17 128.17,72.3 129.37,72.3 129.51,72.44 129.51,73.17 129.38,73.3 128.23,73.3 128.1,73.43 128.1,74.58 120.38,82.31 120.38,90.27 119.68,90.97 119.68,93.61
  BOTTOM w0.076: UC1.AR25 115.71,106.04 v1(115.38,105.72)
  BOTTOM w0.102: JDIMM2.33 129.95,69.93 129.51,69.48 v1(129.38,69.48)
DDR_B_D27: length 55.8
  IN1 w0.084: 120.04,93.61 120.04,94.23 118.12,96.15 118.12,102.39 117.68,102.82 117.68,103.09 117.82,103.23 117.82,103.46 115.77,105.51 115.77,106.24 115.64,106.37 v1(115.38,106.37)
  IN1 w0.127: 120.04,93.61 120.04,91.1 120.74,90.4 120.74,83.39 120.95,83.18 120.95,83.09 120.72,82.86 120.72,82.68 121,82.4 121.18,82.4 121.46,82.68 121.64,82.68 121.84,82.48 121.84,82.3 121.45,81.92 121.45,81.77 121.68,81.54 121.83,81.54 122.21,81.92 122.39,81.92 122.59,81.73 122.59,81.55 122.21,81.16 122.21,81.01 122.44,80.79 122.58,80.79 122.99,81.19 123.17,81.19 123.37,81 123.37,80.82 122.96,80.41 122.96,80.23 123.16,80.03 123.34,80.03 123.68,80.37 123.86,80.37 124.06,80.18 124.06,80 123.72,79.65 123.72,79.47 128.67,74.52 128.67,74.34 128.45,74.11 128.45,73.94 128.64,73.74 128.82,73.74 129.05,73.96 129.23,73.96 129.86,73.33 129.86,67.89 129.73,67.77 129.51,67.77 129.38,67.89 v1(129.38,67.96)
  BOTTOM w0.076: v1(115.38,106.37) 115.71,106.69 UC1.AP25
  BOTTOM w0.102: v1(129.38,67.96) 130.55,69.13 JDIMM2.35
DDR_B_D28: length 58.1
  IN1 w0.084: 117.09,93.94 117.09,94.82 116.83,95.07 116.83,95.34 116.21,95.96 116.21,100.96 115.78,101.39 115.52,101.39 114.99,101.92 114.99,102.34 114.86,102.47 113.04,102.47 112.91,102.6 112.91,108.86 113.04,108.99 113.85,108.99 113.93,109.07 113.93,109.39 113.85,109.48 113.02,109.48 112.9,109.6 112.9,110.01 113.02,110.13 115.21,110.13 115.33,110.01 115.33,109.79 115.21,109.66 v1(115.2,109.66)
  IN1 w0.127: 117.09,93.94 117.09,81.91 124.73,74.26 124.73,74.06 124.86,73.93 125.04,73.93 125.16,73.8 125.16,73.53 125.04,73.4 124.87,73.4 124.74,73.27 124.74,72.59 124.87,72.46 125.34,72.46 125.47,72.34 125.47,72.06 125.34,71.93 124.87,71.93 124.74,71.8 124.74,71.56 124.87,71.44 125.34,71.44 125.47,71.31 125.47,71.03 125.34,70.9 124.87,70.9 124.74,70.77 124.74,69.35 124.87,69.23 125.18,69.23 125.31,69.35 v1(125.31,69.48)
  BOTTOM w0.076: UC1.AK26 114.84,109.3 v1(115.2,109.66)
  BOTTOM w0.102: v1(125.31,69.48) 126.35,70.52 JDIMM2.21
DDR_B_D29: length 58
  IN1 w0.084: 117.44,93.94 117.44,94.97 116.38,96.03 116.38,101.03 115.85,101.56 115.59,101.56 115.16,102 115.16,102.52 115.03,102.64 114.58,102.64 114.46,102.77 114.46,103.01 114.33,103.13 113.76,103.13 113.63,103.01 113.63,102.77 113.55,102.69 113.25,102.69 113.12,102.82 113.12,103.47 113.25,103.6 113.79,103.6 113.87,103.68 113.87,104.67 113.79,104.75 113.21,104.75 113.08,104.88 113.08,105.12 113.21,105.24 113.79,105.24 113.87,105.33 113.87,107.82 114,107.95 114.27,107.95 114.39,107.82 v1(114.39,107.63)
  IN1 w0.127: v1(125.31,67.96) 125.31,67.76 125.43,67.64 125.6,67.64 125.75,67.78 125.75,69.77 125.6,69.92 125.25,69.92 125.12,70.05 125.12,70.43 125.25,70.56 125.65,70.56 125.81,70.72 125.81,73.7 118.15,81.36 118.15,81.61 118.03,81.74 117.76,81.74 117.58,81.92 117.58,82.21 117.71,82.34 117.92,82.34 118.05,82.46 118.05,82.73 117.92,82.86 117.63,82.86 117.5,82.98 117.5,83.21 117.63,83.34 117.93,83.34 118.06,83.47 118.06,83.73 117.93,83.86 117.57,83.86 117.44,83.99 117.44,93.94
  BOTTOM w0.076: v1(114.39,107.63) 114.76,107.99 UC1.AM26
  BOTTOM w0.102: v1(125.31,67.96) 126.95,69.6 JDIMM2.23
DDR_B_D30: length 58.2
  IN1 w0.084: 120.75,93.61 120.75,94.08 118.47,96.37 118.47,103.37 118.02,103.82 118.02,104.36 116.73,105.64 116.73,107.37 115.94,108.16 115.94,108.36 v1(115.33,108.97)
  IN1 w0.127: v1(130.2,61.5) 131.41,61.5 131.54,61.63 131.54,61.88 131.41,62.01 130.74,62.01 130.62,62.13 130.62,73.58 124.76,79.44 124.76,80.58 121.45,83.89 121.45,90.66 120.75,91.36 120.75,93.61
  BOTTOM w0.076: UC1.AK25 115.66,109.3 v1(115.33,108.97)
  BOTTOM w0.102: JDIMM2.34 130.25,61.54 v1(130.2,61.5)
DDR_B_D31: length 58.9
  IN1 w0.084: v1(115.42,108.32) 115.94,107.79 115.94,105.59 118.29,103.24 118.29,96.27 120.39,94.16 120.39,93.61
  IN1 w0.127: 120.39,93.61 120.39,91.23 121.09,90.53 121.09,83.76 124.4,80.45 124.4,79.29 130.24,73.45 130.24,63.94 129.79,63.49 129.79,60.39 v1(130.2,59.98)
  BOTTOM w0.076: UC1.AL25 115.74,108.64 v1(115.42,108.32)
  BOTTOM w0.102: v1(130.2,59.98) 130.85,60.62 JDIMM2.36
DDR_B_D32: length 85.6
  IN3 w0.084: 126.16,94.64 125.95,94.85 120.91,94.85 120.08,95.67 118.82,95.67 118.33,96.17 118.33,99.05 117.95,99.43 v1(117.57,99.43)
  IN3 w0.127: 126.16,94.64 128.23,92.56 131.96,92.56 132.09,92.69 132.09,92.86 132.22,92.98 137.67,92.98 137.79,92.86 137.79,92.69 137.92,92.56 155.44,92.56 156.35,91.65 158.32,91.65 173.29,76.68 173.29,73.42 173.16,73.29 173,73.29 172.87,73.16 172.87,72.65 173,72.53 173.13,72.53 173.25,72.4 173.25,65.81 v1(172.63,65.18)
  BOTTOM w0.076: UC1.AY23 116.64,102.68 116.65,102.66 116.65,101.95 116.89,101.71 116.89,100.12 v1(117.57,99.43)
  BOTTOM w0.102: JDIMM2.166 172.25,64.81 v1(172.63,65.18)
DDR_B_D33: length 86.5
  IN3 w0.084: 125.84,94.45 125.61,94.68 120.84,94.68 120.08,95.44 118.71,95.44 118.16,95.99 118.16,97.36 117.82,97.7 v1(117.57,97.7)
  IN3 w0.127: 125.84,94.45 126.29,94 126.29,93.81 126.04,93.56 126.04,93.38 126.22,93.19 126.4,93.19 126.65,93.44 126.84,93.44 127.02,93.27 127.02,93.08 126.74,92.8 126.74,92.63 126.93,92.44 127.11,92.44 127.38,92.71 127.57,92.71 128.08,92.2 132.45,92.2 132.58,92.34 132.58,92.49 132.72,92.62 132.96,92.62 133.1,92.49 133.1,92.34 133.23,92.2 133.48,92.2 133.61,92.34 133.61,92.49 133.75,92.62 133.99,92.62 134.13,92.49 134.13,92.34 134.26,92.2 134.51,92.2 134.64,92.34 134.64,92.49 134.78,92.62 135.03,92.62 135.16,92.49 135.16,92.34 135.29,92.2 135.54,92.2 135.68,92.34 135.68,92.49 135.81,92.62 136.06,92.62 136.19,92.49 136.19,92.34 136.33,92.2 136.57,92.2 136.71,92.34 136.71,92.49 136.84,92.62 137.09,92.62 137.22,92.49 137.22,92.34 137.36,92.2 155.29,92.2 156.2,91.29 158.17,91.29 172.51,76.95 172.51,75.46 172.64,75.33 172.79,75.33 172.93,75.19 172.93,74.95 172.79,74.81 172.64,74.81 172.51,74.68 172.51,74.43 172.64,74.3 172.79,74.3 172.93,74.16 172.93,73.91 172.79,73.78 172.64,73.78 172.51,73.65 172.51,72.3 172.64,72.17 172.76,72.17 172.89,72.04 172.89,71.78 172.76,71.65 172.64,71.65 172.51,71.52 172.51,71.27 172.64,71.14 172.76,71.14 172.89,71.01 172.89,70.75 172.76,70.62 172.64,70.62 172.51,70.49 172.51,69.87 v1(172.63,69.75)
  BOTTOM w0.076: UC1.AW23 116.64,103.38 116.44,103.18 116.34,103 116.34,102.73 116.48,102.6 116.48,101.88 116.72,101.64 116.72,98.55 v1(117.57,97.7)
  BOTTOM w0.102: v1(172.63,69.75) 171.95,70.43 JDIMM2.165
DDR_B_D34: length 86.2
  IN3 w0.084: 130.88,95.4 130.22,95.4 129.82,95.01 127.85,95.01 127.32,95.54 121.2,95.54 119.67,97.07 v1(119.17,97.07)
  IN3 w0.127: 130.88,95.4 139.39,95.4 140.26,94.52 157.13,94.52 158.12,93.53 159.1,93.53 175.17,77.46 175.17,70.48 175.55,70.1 175.55,67.49 v1(176.34,66.71)
  BOTTOM w0.076: UC1.AY21 118.11,102.81 118.11,101.62 118.4,101.33 118.4,97.84 v1(119.17,97.07)
  BOTTOM w0.102: v1(176.34,66.71) 174.65,65.02 JDIMM2.174
DDR_B_D35: length 86.7
  IN3 w0.084: 131.24,95.76 130.46,95.76 130.41,95.81 127,95.81 126.96,95.76 122.12,95.76 122.08,95.71 121.27,95.71 120.49,96.5 120.49,97.61 120.38,97.72 v1(119.17,97.72)
  IN3 w0.127: v1(176.34,68.23) 176.04,68.23 175.91,68.36 175.91,70.25 175.53,70.63 175.53,73.57 175.66,73.7 175.77,73.7 175.89,73.83 175.89,74.09 175.77,74.22 175.66,74.22 175.53,74.35 175.53,74.6 175.66,74.73 175.77,74.73 175.89,74.86 175.89,75.12 175.77,75.25 175.66,75.25 175.53,75.38 175.53,75.63 175.66,75.76 175.77,75.76 175.89,75.89 175.89,76.15 175.77,76.28 175.66,76.28 175.53,76.41 175.53,77.68 158.32,94.89 140.41,94.89 139.54,95.76 131.24,95.76
  BOTTOM w0.076: v1(119.17,97.72) 118.57,98.32 118.57,101.39 118.28,101.69 118.28,103.05 117.99,103.35 UC1.AW21
  BOTTOM w0.102: JDIMM2.175 174.95,69.62 v1(176.34,68.23)
DDR_B_D36: length 87.5
  IN3 w0.084: 124.3,94.42 124.22,94.5 120.77,94.5 120.01,95.27 118.64,95.27 117.98,95.92 117.98,96.66 v1(117.57,97.07)
  IN3 w0.127: 124.3,94.42 124.43,94.29 124.43,92.9 124.56,92.77 124.82,92.77 124.95,92.9 124.95,93.99 125.07,94.12 125.33,94.12 125.46,93.99 125.46,92.48 125.59,92.35 126.5,92.35 127.02,91.84 155.14,91.84 156.05,90.93 158.02,90.93 172.15,76.8 172.15,68.34 172.25,68.23 v1(172.63,68.23)
  BOTTOM w0.076: UC1.AV23 116.25,103.85 116.25,103.19 116.2,103.08 116.18,103.04 116.18,102.66 116.32,102.53 116.32,101.81 116.56,101.57 116.56,98.09 v1(117.57,97.07)
  BOTTOM w0.102: v1(172.63,68.23) 171.35,69.5 JDIMM2.163
DDR_B_D37: length 88.4
  IN3 w0.084: v1(117.57,98.87) 117.14,98.44 117.14,96.34 118.03,95.45 118.21,95.45 118.57,95.09 119.93,95.09 120.7,94.33 122.48,94.33 122.88,93.94
  IN3 w0.127: v1(172.63,66.71) 172.63,66.56 172.37,66.31 171.91,66.31 171.78,66.43 171.78,76.65 157.87,90.56 155.9,90.56 154.99,91.47 126.87,91.47 126.35,91.99 124.82,91.99 123.96,92.85 123.96,93.37 123.79,93.55 123.27,93.55 122.88,93.94
  BOTTOM w0.076: UC1.AU23 117.4,104.88 117.6,104.68 117.6,104.44 117.59,104.42 117.59,104.04 117.6,104.03 117.6,103.84 117.6,103.83 117.55,103.74 117.55,103.74 117.53,103.69 117.53,103.48 117.6,103.32 117.6,103.19 117.55,103.09 117.53,103.03 117.53,102.74 117.76,102.51 117.76,101.5 118.07,101.2 118.07,99.37 v1(117.57,98.87)
  BOTTOM w0.102: v1(172.63,66.71) 171.65,65.73 JDIMM2.164
DDR_B_D38: length 87.4
  IN3 w0.084: 129.99,94.5 127.97,94.5 127.1,95.37 121.13,95.37 120.07,96.42 v1(119.17,96.42)
  IN3 w0.127: 129.99,94.5 139.78,94.5 140.11,94.17 156.98,94.17 157.98,93.17 158.95,93.17 174.81,77.31 174.81,70.34 175.19,69.95 175.19,66.32 v1(176.34,65.18)
  BOTTOM w0.076: v1(119.17,96.42) 118.72,96.87 118.72,96.89 118.24,97.37 118.24,100.9 118.23,100.91 118.23,101.26 117.94,101.56 117.94,102.57 117.69,102.81 117.69,103 117.74,103.1 117.77,103.16 117.77,103.36 117.74,103.41 117.7,103.5 117.69,103.52 117.69,103.65 117.72,103.7 117.74,103.75 117.88,103.89 UC1.AV21
  BOTTOM w0.102: JDIMM2.176 175.25,64.36 176.07,65.18 v1(176.34,65.18)
DDR_B_D39: length 87.9
  IN3 w0.084: v1(119.17,98.37) 119.47,98.67 121.31,98.67 121.69,98.29 121.69,97.17 121.88,96.98 130.1,96.98 130.95,96.13 131.57,96.13
  IN3 w0.127: v1(176.34,69.75) 176.34,70.5 175.89,70.94 175.89,73.08 176.26,73.45 176.26,77.47 158.47,95.25 143.59,95.25 143.46,95.38 143.46,95.77 143.34,95.9 143.07,95.9 142.95,95.77 142.95,95.38 142.82,95.25 142.56,95.25 142.43,95.38 142.43,95.99 142.3,96.13 142.05,96.13 141.92,95.99 141.92,95.38 141.79,95.25 141.53,95.25 141.4,95.38 141.4,95.99 141.27,96.13 141.02,96.13 140.88,95.99 140.88,95.44 140.76,95.32 140.5,95.32 140.37,95.44 140.37,95.99 140.23,96.13 131.57,96.13
  BOTTOM w0.076: v1(119.17,98.37) 118.74,98.81 118.74,101.46 118.44,101.76 118.44,103.12 118.28,103.29 118.28,103.7 118.15,103.83 118.15,104.09 118.17,104.11 118.17,104.35 117.88,104.65 UC1.AU21
  BOTTOM w0.102: v1(176.34,69.75) 176.21,69.75 175.55,70.41 JDIMM2.177
DDR_B_D40: length 53.7
  IN1 w0.084: 121.41,93.61 121.41,94.02 119.54,95.88 119.54,99.58 119.45,99.67 v1(119.17,99.67)
  IN1 w0.127: 121.41,93.61 121.41,91.6 122.08,90.93 122.08,84.15 125.39,80.84 125.39,80.36 125.59,80.16 125.77,80.16 125.98,80.38 126.18,80.38 126.34,80.21 126.34,80.01 125.8,79.47 125.8,79.29 126,79.09 126.18,79.09 126.72,79.63 126.9,79.63 127.1,79.43 127.1,79.25 126.56,78.72 126.56,78.54 126.76,78.34 126.94,78.34 127.47,78.88 127.65,78.88 127.85,78.68 127.85,78.5 127.31,77.96 127.31,77.78 127.51,77.58 127.69,77.58 128.23,78.12 128.41,78.12 128.6,77.92 128.6,77.74 128.07,77.21 128.07,77.03 128.26,76.83 128.44,76.83 128.98,77.37 129.16,77.37 129.36,77.17 129.36,76.99 128.82,76.45 128.82,76.27 131.3,73.8 131.3,67.8 131.42,67.68 131.94,67.68 132.07,67.8 v1(132.07,68.04)
  BOTTOM w0.076: v1(119.17,99.67) 119.73,100.23 119.73,101.17 118.94,101.96 118.94,102.81 UC1.AY19
  BOTTOM w0.102: JDIMM2.39 131.75,70.24 131.66,70.16 131.66,68.45 v1(132.07,68.04)
DDR_B_D41: length 54.5
  IN1 w0.084: v1(119.17,100.32) 119.17,100.5 119.3,100.62 119.78,100.62 119.91,100.5 119.91,99.87 119.72,99.68 119.72,95.95 120.92,94.75 121.03,94.75 121.18,94.9 121.3,94.9 121.52,94.67 121.52,94.55 121.38,94.41 121.38,94.29 121.76,93.91 121.76,93.61
  IN1 w0.127: v1(132.07,69.56) 132.07,69.33 131.95,69.2 131.77,69.2 131.65,69.33 131.65,70.78 131.78,70.9 132.03,70.9 132.16,71.03 132.16,71.28 132.03,71.41 131.78,71.41 131.65,71.54 131.65,71.79 131.78,71.92 132.03,71.92 132.16,72.05 132.16,72.3 132.03,72.43 131.77,72.43 131.64,72.55 131.64,73.17 131.77,73.3 132.02,73.3 132.15,73.42 132.15,73.67 132.02,73.8 131.79,73.8 131.66,73.92 131.66,74.23 131.79,74.36 131.99,74.36 132.12,74.48 132.12,74.94 131.97,75.08 131.8,75.08 131.24,74.52 131.06,74.52 130.86,74.72 130.86,74.9 131.43,75.47 131.43,75.65 131.23,75.84 131.05,75.84 130.48,75.28 130.3,75.28 130.11,75.47 130.11,75.65 130.67,76.22 130.67,76.4 130.47,76.6 130.3,76.6 129.73,76.03 129.55,76.03 129.35,76.23 129.35,76.41 129.91,76.97 129.91,77.15 126.11,80.94 125.77,80.94 125.54,81.18 125.54,81.51 125.33,81.72 125,81.72 124.79,81.93 124.79,82.29 124.6,82.47 124.24,82.47 124.03,82.69 124.03,83.04 123.84,83.23 123.49,83.23 123.28,83.44 123.28,83.79 123.09,83.98 122.74,83.98 122.44,84.28 122.44,91.07 121.76,91.75 121.76,93.61
  BOTTOM w0.076: v1(119.17,100.32) 119.17,100.3 119.3,100.17 119.44,100.17 119.57,100.3 119.57,101.1 118.77,101.89 118.77,103.05 119.07,103.35 UC1.AW19
  BOTTOM w0.102: v1(132.07,69.56) 132,69.64 132,69.73 132.12,69.86 132.55,69.86 132.68,69.99 132.68,70.19 132.56,70.31 132.48,70.31 132.35,70.43 JDIMM2.41
DDR_B_D42: length 53.2
  IN1 w0.084: v1(121.04,100.96) 121.32,100.96 121.62,100.67 121.62,97.69 125.06,94.24 125.06,93.61
  IN1 w0.127: 125.06,93.61 125.06,93.12 125.74,92.44 125.74,91.22 125.89,91.07 126.56,91.07 126.99,90.64 126.99,84.74 136.49,75.24 136.49,68.01 136.69,67.8 136.69,65.17 136.57,65.05 136.28,65.05 136.15,65.17 136.15,66.03 136.03,66.16 135.74,66.16 135.61,66.28 135.61,66.56 135.74,66.69 136.03,66.69 136.15,66.82 136.15,67.62 v1(135.73,68.04)
  BOTTOM w0.076: v1(121.04,100.96) 121.04,101.13 120.4,101.76 120.4,102.6 120.42,102.61 UC1.AY17
  BOTTOM w0.102: JDIMM2.53 135.95,69.96 136.17,69.73 136.17,68.48 v1(135.73,68.04)
DDR_B_D43: length 54.4
  IN1 w0.084: 124.35,93.61 124.35,94.01 121.9,96.46 121.12,96.46 v1(121.09,96.42)
  IN1 w0.127: v1(135.03,59.98) 135.58,60.52 135.58,63.9 135.53,63.95 135.53,65.15 135.27,65.42 135.27,73.72 134.74,74.25 134.74,75.99 126.28,84.45 126.28,86.93 125.72,87.49 125.72,88.72 125.03,89.41 125.03,92.15 124.35,92.82 124.35,93.61
  BOTTOM w0.076: UC1.AW17 120.68,103.07 120.71,103 120.71,102.81 120.58,102.68 120.58,101.97 121.44,101.11 121.44,96.97 121.11,96.42 v1(121.09,96.42)
  BOTTOM w0.102: JDIMM2.52 135.65,60.96 135.04,59.98 v1(135.03,59.98)
DDR_B_D44: length 55.1
  IN1 w0.084: v1(119.17,100.97) 119.79,100.97 120.08,100.68 120.08,99.8 119.89,99.6 119.89,96.03 120.81,95.11 121.34,95.11 122.12,94.33 122.12,93.61
  IN1 w0.127: 122.12,93.61 122.12,91.9 122.79,91.22 122.79,84.77 132.5,75.06 132.5,66.85 132.19,66.53 132.19,60.53 v1(132.74,59.98)
  BOTTOM w0.076: UC1.AV19 119.17,104.1 118.77,103.7 118.77,103.3 118.61,103.13 118.61,101.82 119.17,101.26 v1(119.17,100.97)
  BOTTOM w0.102: v1(132.74,59.98) 133.2,60.43 133.2,61.71 132.65,62.26 JDIMM2.42
DDR_B_D45: length 55.6
  IN1 w0.084: v1(121.05,99.72) 120.25,99.72 120.1,99.58 120.1,96.06 120.84,95.32 121.68,95.32 122.47,94.53 122.47,93.61
  IN1 w0.127: v1(132.74,61.5) 133.12,61.5 133.25,61.63 133.25,62.18 133.12,62.31 132.79,62.31 132.67,62.42 132.67,62.76 132.79,62.88 133.12,62.88 133.25,63.01 133.25,63.28 133.12,63.41 132.79,63.41 132.67,63.53 132.67,63.87 132.79,63.98 133.03,63.98 133.16,64.11 133.16,64.41 132.85,64.72 132.85,75.22 123.15,84.91 123.15,91.37 122.47,92.04 122.47,93.61
  BOTTOM w0.076: v1(121.05,99.72) 120.81,99.72 120.47,100.06 120.47,101.23 120.07,101.63 120.07,102.59 119.96,102.7 119.96,103.03 120.03,103.19 120.03,103.32 119.96,103.48 119.96,103.69 119.98,103.74 119.98,103.74 120.03,103.83 120.03,103.84 120.03,104.68 119.83,104.88 UC1.AU19
  BOTTOM w0.102: JDIMM2.40 132.05,62.21 132.74,61.52 v1(132.74,61.5)
DDR_B_D46: length 54.3
  IN1 w0.084: 124.7,93.61 124.7,94.22 122.78,96.14 122.66,96.14 122.62,96.1 122.5,96.1 122.28,96.33 122.28,96.45 122.3,96.48 122.3,96.66 122.14,96.83 121.96,96.83 121.83,96.7 121.65,96.7 121.48,96.86 121.48,97.04 121.62,97.18 121.62,97.3 121.43,97.5 121.43,100.4 121.3,100.53 121.16,100.53 121.03,100.4 v1(121.03,100.35)
  IN1 w0.127: v1(135.73,69.56) 136.03,69.56 136.15,69.68 136.15,70.67 136.02,70.8 135.74,70.8 135.61,70.93 135.61,71.2 135.74,71.33 136.02,71.33 136.15,71.46 136.15,71.74 136.02,71.86 135.74,71.86 135.61,71.99 135.61,72.27 135.74,72.4 136.01,72.4 136.13,72.53 136.13,73.2 136.01,73.33 135.79,73.33 135.66,73.46 135.66,73.71 135.79,73.84 136.01,73.84 136.13,73.97 136.13,74.22 136.01,74.35 135.21,74.35 135.08,74.47 135.08,74.73 135.21,74.85 135.73,74.85 135.86,74.98 135.86,75.24 135.73,75.36 135.21,75.36 135.08,75.49 135.08,76.15 126.63,84.59 126.63,87.4 126.51,87.53 126.2,87.53 126.08,87.66 126.08,87.91 126.2,88.04 126.51,88.04 126.63,88.17 126.63,88.42 126.51,88.55 126.2,88.55 126.08,88.67 126.08,88.93 126.2,89.06 126.51,89.06 126.63,89.18 126.63,89.44 126.51,89.56 125.5,89.56 125.37,89.69 125.37,89.94 125.5,90.07 126.51,90.07 126.63,90.2 126.63,90.45 126.51,90.58 125.51,90.58 125.38,90.71 125.38,92.29 124.7,92.97 124.7,93.61
  BOTTOM w0.076: UC1.AV17 120.42,104 120.18,103.75 120.13,103.65 120.13,103.52 120.13,103.5 120.17,103.41 120.17,103.41 120.2,103.36 120.2,103.16 120.13,103 120.13,102.77 120.24,102.65 120.24,101.7 120.63,101.3 120.63,100.75 v1(121.03,100.35)
  BOTTOM w0.102: v1(135.73,69.56) 135.03,69.56 134.9,69.69 134.9,69.92 135.03,70.05 135.22,70.05 135.35,70.18 JDIMM2.51
DDR_B_D47: length 55.3
  IN1 w0.084: v1(121.69,96.09) 122.03,96.09 123.99,94.12 123.99,93.61
  IN1 w0.127: 123.99,93.61 123.99,92.68 124.67,92 124.67,89.28 125.38,88.58 125.38,87.35 125.92,86.8 125.92,84.3 134.39,75.83 134.39,74.11 134.9,73.6 134.9,67.6 134.77,67.48 134.51,67.48 134.38,67.35 134.38,67.09 134.51,66.97 134.77,66.97 134.9,66.84 134.9,66.59 134.77,66.46 134.2,66.46 134.08,66.33 134.08,66.08 134.2,65.95 134.77,65.95 134.9,65.82 134.9,65.61 134.9,65.61 134.9,65.57 134.78,65.44 134.14,65.44 134.01,65.32 134.01,64.74 134.14,64.61 135.06,64.61 135.19,64.48 135.19,61.66 v1(135.03,61.5)
  BOTTOM w0.076: v1(121.69,96.09) 121.69,100.52 121.61,100.61 121.61,101.18 120.78,102.01 120.78,102.65 120.87,102.74 120.87,103.03 120.8,103.19 120.8,103.75 120.71,103.84 120.71,104.59 UC1.AU17
  BOTTOM w0.102: JDIMM2.50 135.05,61.52 v1(135.03,61.5)
DDR_B_D48: length 92.9
  IN3 w0.084: v1(118.13,105.72) 118.13,105.57 118.71,105 119.43,105 124.22,100.21 124.22,99.31 125.16,98.38 126.08,98.38 127.34,99.64 130.33,99.64 130.4,99.57 131.57,99.57
  IN3 w0.127: v1(181.2,68.23) 180.26,68.23 180.13,68.36 180.13,69.46 180.27,69.59 180.65,69.59 180.78,69.72 180.78,69.98 180.65,70.11 180.27,70.11 180.13,70.25 180.13,72.39 180.26,72.52 180.71,72.52 180.84,72.65 180.84,74.46 180.71,74.59 180.26,74.59 180.13,74.72 180.13,78.92 160.56,98.49 145.33,98.49 144.44,99.38 137.89,99.38 137.7,99.57 131.57,99.57
  BOTTOM w0.076: UC1.AR21 118.46,106.04 v1(118.13,105.72)
  BOTTOM w0.102: v1(181.2,68.23) 179.75,69.68 JDIMM2.191
DDR_B_D49: length 93.7
  IN3 w0.084: 131.57,97.85 131.45,97.85 131.35,97.75 123.45,97.75 122.43,98.77 122.43,101.11 121.69,101.85 119.55,101.85 118.78,102.63 118.78,102.74 119.2,103.16 119.2,103.28 118.99,103.49 118.87,103.49 118.45,103.07 118.33,103.07 117.18,104.22 v1(117.18,105.72)
  IN3 w0.127: v1(178.62,69.75) 178.61,69.76 178.61,71.62 178.49,71.75 178.19,71.75 178.06,71.88 178.06,72.14 178.19,72.26 178.49,72.26 178.61,72.39 178.61,72.65 178.49,72.78 178.19,72.78 178.06,72.91 178.06,73.49 178.19,73.62 178.49,73.62 178.61,73.75 178.61,74.01 178.49,74.13 178.19,74.13 178.06,74.26 178.06,74.52 178.19,74.65 178.49,74.65 178.61,74.78 178.61,75.04 178.49,75.17 178.19,75.17 178.06,75.29 178.06,75.55 178.19,75.68 178.49,75.68 178.61,75.81 178.61,76.07 178.49,76.2 178.19,76.2 178.06,76.32 178.06,76.58 178.19,76.71 178.49,76.71 178.61,76.84 178.61,77.1 178.49,77.23 178.19,77.23 178.06,77.35 178.06,77.62 178.19,77.74 178.34,77.74 178.47,77.87 178.47,78.13 178.34,78.26 178.19,78.26 178.06,78.39 178.06,78.54 159.63,96.98 144.7,96.98 143.82,97.85 131.57,97.85
  BOTTOM w0.076: UC1.AR22 117.51,106.04 v1(117.18,105.72)
  BOTTOM w0.102: v1(178.62,69.75) 178.15,69.75 178.02,69.63 178.02,69.42 177.89,69.29 177.48,69.29 177.35,69.42 JDIMM2.183
DDR_B_D50: length 95.8
  IN3 w0.084: v1(118.13,108.32) 118.35,108.53 118.58,108.53 118.69,108.42 118.69,105.5 118.85,105.35 119.58,105.35 122.99,101.93 123.28,101.93 123.9,102.55 124.31,102.55 126.56,100.3 131.57,100.3
  IN3 w0.127: v1(181.2,66.71) 181.52,66.71 181.62,66.81 181.62,78.31 181.5,78.43 180.99,78.43 180.86,78.56 180.86,79.22 160.86,99.22 145.63,99.22 144.76,100.09 138.19,100.09 137.98,100.3 131.57,100.3
  BOTTOM w0.076: v1(118.13,108.32) 118.46,108.64 UC1.AL21
  BOTTOM w0.102: v1(181.2,66.71) 181.77,66.14 181.77,64.91 181.63,64.78 180.81,64.78 180.65,64.61 JDIMM2.194
DDR_B_D51: length 96.1
  IN3 w0.084: v1(117.18,107.67) 116.46,107.67 115.95,107.16 115.95,104.97 119.41,101.51 121.54,101.51 122.08,100.97 122.08,98.63 123.39,97.32 130.24,97.32 130.43,97.13 131.57,97.13
  IN3 w0.127: v1(178.62,66.71) 178.15,66.71 178.02,66.58 178.02,66.27 177.88,66.13 177.48,66.13 177.34,66.27 177.34,78.24 159.33,96.26 144.4,96.26 143.52,97.13 131.57,97.13
  BOTTOM w0.076: v1(117.18,107.67) 117.51,107.99 UC1.AM22
  BOTTOM w0.102: JDIMM2.180 176.45,64.43 177.07,65.05 177.07,65.15 v1(178.62,66.71)
DDR_B_D52: length 95.3
  IN3 w0.084: 131.57,97.49 123.46,97.49 122.25,98.7 122.25,101.04 121.61,101.68 119.48,101.68 116.79,104.37 116.79,106.94 116.87,107.02 v1(117.18,107.02)
  IN3 w0.127: v1(178.62,68.23) 178.26,67.87 177.83,67.87 177.71,68 177.71,68.59 177.84,68.72 178.07,68.72 178.2,68.85 178.2,69.11 178.07,69.24 177.84,69.24 177.71,69.37 177.71,69.72 177.83,69.84 178.13,69.84 178.26,69.97 178.26,70.23 178.13,70.36 177.83,70.36 177.71,70.49 177.71,70.75 177.83,70.87 178.13,70.87 178.26,71 178.26,71.26 178.13,71.39 177.83,71.39 177.71,71.52 177.71,78.39 159.48,96.62 144.55,96.62 143.67,97.49 131.57,97.49
  BOTTOM w0.076: UC1.AN22 117.51,107.34 v1(117.18,107.02)
  BOTTOM w0.102: JDIMM2.181 176.75,70.24 176.95,70.05 176.95,68.36 177.07,68.23 v1(178.62,68.23)
DDR_B_D53: length 94
  IN3 w0.084: 131.57,99.94 127.27,99.94 125.89,98.55 125.23,98.55 124.4,99.38 124.4,100.28 119.51,105.17 118.78,105.17 118.51,105.44 118.51,106 v1(118.13,106.37)
  IN3 w0.127: v1(181.2,69.75) 181.2,70.48 181.07,70.61 180.62,70.61 180.5,70.74 180.5,71 180.62,71.12 181.07,71.12 181.2,71.25 181.2,71.51 181.07,71.64 180.62,71.64 180.5,71.77 180.5,72.03 180.62,72.16 181.13,72.16 181.26,72.28 181.26,74.83 181.13,74.95 180.62,74.95 180.5,75.08 180.5,75.34 180.62,75.47 181.13,75.47 181.26,75.6 181.26,75.86 181.13,75.98 180.62,75.98 180.5,76.11 180.5,76.37 180.62,76.5 181.13,76.5 181.26,76.63 181.26,76.89 181.13,77.02 180.62,77.02 180.5,77.14 180.5,77.4 180.62,77.53 180.94,77.53 181.07,77.66 181.07,77.92 180.94,78.05 180.62,78.05 180.5,78.17 180.5,79.07 160.71,98.86 145.48,98.86 144.6,99.73 138.04,99.73 137.84,99.94 131.57,99.94
  BOTTOM w0.076: v1(118.13,106.37) 118.46,106.69 UC1.AP21
  BOTTOM w0.102: v1(181.2,69.75) 180.79,69.75 180.35,70.2 JDIMM2.193
DDR_B_D54: length 96.6
  IN3 w0.084: 131.57,100.66 126.45,100.66 124.39,102.72 122.45,102.72 119.53,105.63 119.53,109.29 119.41,109.42 118.23,109.42 118.11,109.29 v1(118.11,108.97)
  IN3 w0.127: v1(181.2,65.18) 181.79,65.18 181.99,65.38 181.99,78.61 161.01,99.58 145.78,99.58 144.92,100.44 138.34,100.44 138.12,100.66 131.57,100.66
  BOTTOM w0.076: v1(118.11,108.97) 118.43,109.3 UC1.AK21
  BOTTOM w0.102: JDIMM2.192 180.05,64.59 180.64,65.18 v1(181.2,65.18)
DDR_B_D55: length 96.8
  IN3 w0.084: 131.57,96.77 130.55,96.77 130.17,97.15 123.31,97.15 121.91,98.55 121.91,100.9 121.47,101.34 119.34,101.34 118.92,101.75 115.78,104.9 115.78,107.23 116.79,108.24 116.79,108.85 116.91,108.97 v1(117.18,108.97)
  IN3 w0.127: v1(178.62,65.18) 178.47,65.03 177.11,65.03 176.98,65.16 176.98,78.09 159.18,95.89 144.25,95.89 143.37,96.77 131.57,96.77
  BOTTOM w0.076: v1(117.18,108.97) 117.51,109.3 UC1.AK22
  BOTTOM w0.102: v1(178.62,65.18) 177.79,65.18 177.05,64.45 JDIMM2.182
DDR_B_D56: length 64.2
  IN1 w0.084: v1(119.09,107.02) 118.68,106.61 118.68,104.75 120.41,103.01 120.41,101.95 120.68,101.68 121.33,101.68 122.14,100.88 122.14,98.32 125.99,94.46 126.58,94.46 127.08,93.96 127.08,93.94
  IN1 w0.127: 127.08,93.94 127.11,93.92 127.11,92.39 128.36,91.13 128.36,85.27 131.07,82.56 131.25,82.56 131.65,82.96 131.83,82.96 132.03,82.77 132.03,82.59 131.63,82.19 131.63,82.01 131.83,81.81 132,81.81 132.41,82.21 132.59,82.21 132.78,82.01 132.78,81.83 132.38,81.43 132.38,81.25 132.58,81.05 132.76,81.05 133.16,81.46 133.34,81.46 133.54,81.26 133.54,81.08 133.14,80.68 133.14,80.5 133.33,80.3 133.51,80.3 133.92,80.7 134.09,80.7 134.29,80.5 134.29,80.32 133.89,79.92 133.89,79.74 134.09,79.55 134.27,79.55 134.67,79.95 134.85,79.95 135.05,79.75 135.05,79.57 134.65,79.17 134.65,78.99 134.84,78.79 135.02,78.79 135.42,79.19 135.6,79.19 135.8,78.99 135.8,78.81 135.4,78.41 135.4,78.23 135.6,78.04 135.78,78.04 136.18,78.44 136.36,78.44 136.56,78.24 136.56,78.06 136.15,77.66 136.15,77.48 136.35,77.28 136.53,77.28 136.93,77.68 137.11,77.68 137.31,77.49 137.31,77.31 136.91,76.9 136.91,76.73 137.11,76.53 137.29,76.53 137.47,76.71 137.64,76.71 137.84,76.51 137.84,76.33 137.66,76.15 137.66,75.97 137.84,75.8 137.84,68.57 138.3,68.1 v1(138.3,67.96)
  BOTTOM w0.076: UC1.AN20 119.41,107.34 v1(119.09,107.02)
  BOTTOM w0.102: JDIMM2.57 137.15,68.93 138.12,67.96 v1(138.3,67.96)
DDR_B_D57: length 62.8
  IN1 w0.084: 127.45,93.94 127.45,94.13 126.91,94.68 126.26,94.68 122.31,98.63 122.31,100.95 121.41,101.85 120.92,101.85 120.59,102.18 120.59,103.08 119.09,104.58 v1(119.09,105.72)
  IN1 w0.127: v1(138.3,69.48) 138.19,69.59 138.19,70.45 138.32,70.58 138.4,70.58 138.46,70.64 138.46,70.99 138.33,71.11 138.31,71.11 138.18,71.24 138.18,71.52 138.31,71.65 138.33,71.65 138.46,71.77 138.46,72.05 138.33,72.18 138.32,72.18 138.19,72.31 138.19,77.09 131.78,83.5 131.6,83.5 131.2,83.1 131.02,83.1 130.82,83.3 130.82,83.48 131.22,83.88 131.22,84.06 131.03,84.26 130.85,84.26 130.44,83.85 130.27,83.85 130.07,84.05 130.07,84.23 130.47,84.63 130.47,84.81 130.27,85.01 130.09,85.01 129.69,84.61 129.51,84.61 129.31,84.81 128.71,85.41 128.71,85.9 128.83,86.03 130.08,86.03 130.2,86.15 130.2,86.43 130.08,86.56 128.83,86.56 128.71,86.69 128.71,86.97 128.83,87.09 130.14,87.09 130.27,87.22 130.27,87.5 130.14,87.63 128.83,87.63 128.71,87.75 128.71,88.03 128.83,88.16 130.14,88.16 130.27,88.29 130.27,88.57 130.14,88.69 128.83,88.69 128.71,88.82 128.71,89.1 128.83,89.23 130.01,89.23 130.14,89.35 130.14,89.63 130.01,89.76 128.83,89.76 128.71,89.89 128.71,91.28 127.45,92.53 127.45,93.94
  BOTTOM w0.076: v1(119.09,105.72) 119.41,106.04 UC1.AR20
  BOTTOM w0.102: JDIMM2.59 137.75,69.85 138.12,69.48 v1(138.3,69.48)
DDR_B_D58: length 65.3
  IN1 w0.084: v1(120,108.93) 120.76,108.18 120.76,104.42 124.43,100.75 124.43,98.19 126.82,95.8 127.85,95.8 128.63,95.02 129.4,95.02 129.95,94.47
  IN1 w0.127: 129.95,94.47 130.04,94.38 130.04,93.6 132.82,90.82 132.82,86.15 141.31,77.66 141.31,77.1 141.45,76.95 142.86,76.95 143.28,76.53 143.28,72.41 143.16,72.28 141.74,72.28 141.61,72.16 141.61,71.89 141.74,71.76 143.16,71.76 143.28,71.64 143.28,71.37 143.16,71.24 141.75,71.24 141.62,71.11 141.62,70.85 141.75,70.72 142.9,70.72 143.03,70.59 143.03,70.33 142.9,70.2 141.77,70.2 141.63,70.06 141.63,67.77 141.5,67.64 140.94,67.64 140.81,67.77 v1(140.81,67.96)
  BOTTOM w0.076: v1(120,108.93) 120.36,109.3 UC1.AK18
  BOTTOM w0.102: JDIMM2.69 140.75,70.24 141.25,69.73 141.25,68.4 v1(140.81,67.96)
DDR_B_D59: length 65
  IN1 w0.084: v1(120.01,108.32) 120.58,107.75 120.58,104.35 124.11,100.82 124.11,98.26 126.74,95.62 127.78,95.62 128.6,94.8 129.24,94.8 129.68,94.36 129.68,94.2
  IN1 w0.127: 129.68,94.2 129.68,93.46 132.48,90.66 132.48,86 140.79,77.69 140.79,76.74 140.91,76.61 142.59,76.61 142.71,76.48 142.71,76.2 142.59,76.08 140.91,76.08 140.79,75.95 140.79,75.67 140.91,75.54 142.59,75.54 142.71,75.41 142.71,75.14 142.59,75.01 140.91,75.01 140.79,74.88 140.79,74.6 140.91,74.47 142.59,74.47 142.71,74.35 142.71,74.07 142.59,73.94 141.19,73.94 141.07,73.81 141.07,73.34 141.19,73.21 142.4,73.21 142.52,73.09 142.52,72.77 142.4,72.64 141.35,72.64 141.22,72.51 141.22,71.91 141.09,71.78 140.81,71.78 140.69,71.65 140.69,71.37 140.81,71.25 141.09,71.25 141.22,71.12 141.22,69.9 v1(140.81,69.48)
  BOTTOM w0.076: v1(120.01,108.32) 120.34,108.64 UC1.AL18
  BOTTOM w0.102: JDIMM2.67 140.15,70.14 v1(140.81,69.48)
DDR_B_D60: length 65.6
  IN1 w0.084: 125.68,93.94 125.52,94.11 125.52,94.13 121.79,97.86 121.79,100.74 121.19,101.34 120.54,101.34 120.07,101.8 120.07,102.82 119.69,103.19 118.89,103.19 118.19,103.9 118.19,105.14 117.68,105.65 117.68,109.07 117.95,109.34 118.9,109.34 119.09,109.16 v1(119.09,108.97)
  IN1 w0.127: 125.68,93.94 126.42,93.2 126.42,92.1 127.62,90.9 127.62,85 137.13,75.5 137.13,68.27 137.33,68.07 137.33,64.76 137.28,64.71 137.28,64.59 137.15,64.46 136.81,64.46 136.68,64.33 136.68,59.74 136.81,59.61 137.19,59.61 137.32,59.74 v1(137.32,59.98)
  BOTTOM w0.076: UC1.AK20 119.41,109.3 v1(119.09,108.97)
  BOTTOM w0.102: JDIMM2.58 137.45,62.04 137.72,61.77 137.72,60.38 v1(137.32,59.98)
DDR_B_D61: length 64.6
  IN1 w0.084: v1(119.09,107.67) 118.63,107.67 118.51,107.54 118.51,104.67 119.12,104.06 119.12,103.95 118.88,103.71 118.88,103.53 119.05,103.37 119.23,103.37 119.46,103.6 119.58,103.6 120.24,102.94 120.24,101.87 120.61,101.51 121.26,101.51 121.96,100.81 121.96,98.15 126.17,93.94
  IN1 w0.127: 126.17,93.94 126.76,93.34 126.76,92.25 127.98,91.03 127.98,85.15 137.48,75.65 137.48,68.42 137.72,68.18 137.72,66.88 137.87,66.72 138.33,66.72 138.46,66.6 138.46,66.31 138.33,66.19 137.8,66.19 137.67,66.06 137.67,65.79 137.8,65.67 138.33,65.67 138.46,65.54 138.46,65.27 138.33,65.15 138.2,65.15 138.08,65.02 138.08,64.75 138.2,64.63 138.33,64.63 138.46,64.5 138.46,64.02 138.33,63.89 137.15,63.89 137.02,63.76 137.02,63.5 137.15,63.37 138.27,63.37 138.4,63.24 138.4,62.97 138.27,62.85 137.15,62.85 137.02,62.72 137.02,61.63 137.15,61.5 v1(137.32,61.5)
  BOTTOM w0.076: v1(119.09,107.67) 119.41,107.99 UC1.AM20
  BOTTOM w0.102: v1(137.32,61.5) 136.85,61.97 JDIMM2.56
DDR_B_D62: length 61.3
  IN1 w0.084: v1(120.04,105.72) 120.04,104.4 123.73,100.71 123.73,98.15 126.6,95.28 127.63,95.28 128.46,94.46 128.76,94.46 128.97,94.24 128.97,93.94
  IN1 w0.127: 128.97,93.94 128.97,93.16 131.79,90.34 131.79,85.72 139.99,77.52 139.99,61.7 139.86,61.57 139.54,61.57 139.41,61.45 139.41,61.17 139.54,61.04 139.9,61.04 140.03,60.91 140.03,60.63 139.9,60.51 139.67,60.51 139.54,60.38 139.54,60.1 139.67,59.97 140.43,59.97 140.43,59.98 v1(140.81,59.98)
  BOTTOM w0.076: UC1.AR18 120.36,106.04 v1(120.04,105.72)
  BOTTOM w0.102: v1(140.81,59.98) 141.25,60.42 141.25,61.86 141.05,62.06 JDIMM2.70
DDR_B_D63: length 62.7
  IN1 w0.084: v1(120.04,106.37) 120.41,106 120.41,104.27 123.9,100.79 123.9,98.22 126.67,95.45 127.71,95.45 128.53,94.63 128.93,94.63 129.33,94.23 129.33,93.94
  IN1 w0.127: 129.33,93.94 129.33,93.31 132.13,90.5 132.13,85.86 140.34,77.65 140.34,70.86 140.46,70.74 140.72,70.74 140.85,70.61 140.85,70.35 140.72,70.22 140.55,70.22 140.39,70.06 140.39,66.86 140.6,66.65 141.19,66.65 141.32,66.52 141.32,66.26 141.21,66.15 140.55,66.15 140.43,66.04 140.43,65.61 140.56,65.48 141.08,65.48 141.23,65.33 141.23,64.27 141.1,64.15 140.46,64.15 140.33,64.02 140.33,63.74 140.46,63.61 141.17,63.61 141.23,63.56 141.23,63.21 141.1,63.08 140.46,63.08 140.33,62.95 140.33,62.67 140.46,62.55 141.1,62.55 141.23,62.42 141.23,62.11 141.1,61.99 140.87,61.99 140.74,61.86 140.74,61.56 v1(140.81,61.5)
  BOTTOM w0.076: v1(120.04,106.37) 120.36,106.69 UC1.AP18
  BOTTOM w0.102: JDIMM2.68 140.45,61.86 v1(140.81,61.5)
DDR_B_DQS0: length 81.9
  IN3 w0.084: v1(111.96,100.32) 112.11,100.48 112.22,100.48 113.04,99.67 113.04,95.55 113.96,94.63 113.96,94.37
  IN3 w0.127: v1(163.03,68.61) 163.03,68.46 163.16,68.34 163.35,68.34 163.46,68.44 163.46,74.17 155.1,82.52 151.94,82.52 150.84,83.63 150.02,83.63 149.11,84.54 122.28,84.54 117.23,89.59 116.88,89.59 113.96,92.52 113.96,94.37
  BOTTOM w0.076: UC1.AV30 112.18,104.4 112.1,104.32 111.95,104.32 111.86,104.23 111.79,104.16 111.79,104.15 111.72,104.01 111.72,103.81 111.75,103.75 111.79,103.65 111.79,103.52 111.72,103.36 111.72,103.16 111.75,103.1 111.75,103.1 111.79,103 111.79,102.81 111.55,102.57 111.55,101.43 111.37,101.24 111.37,100.76 111.66,100.47 111.81,100.47 v1(111.96,100.32)
  BOTTOM w0.102: v1(163.03,68.61) 163.03,68.37 162.89,68.23 162.82,68.23 162.55,68.5 162.55,69.67 163.03,70.15 163.26,70.15 163.55,70.44 JDIMM2.137
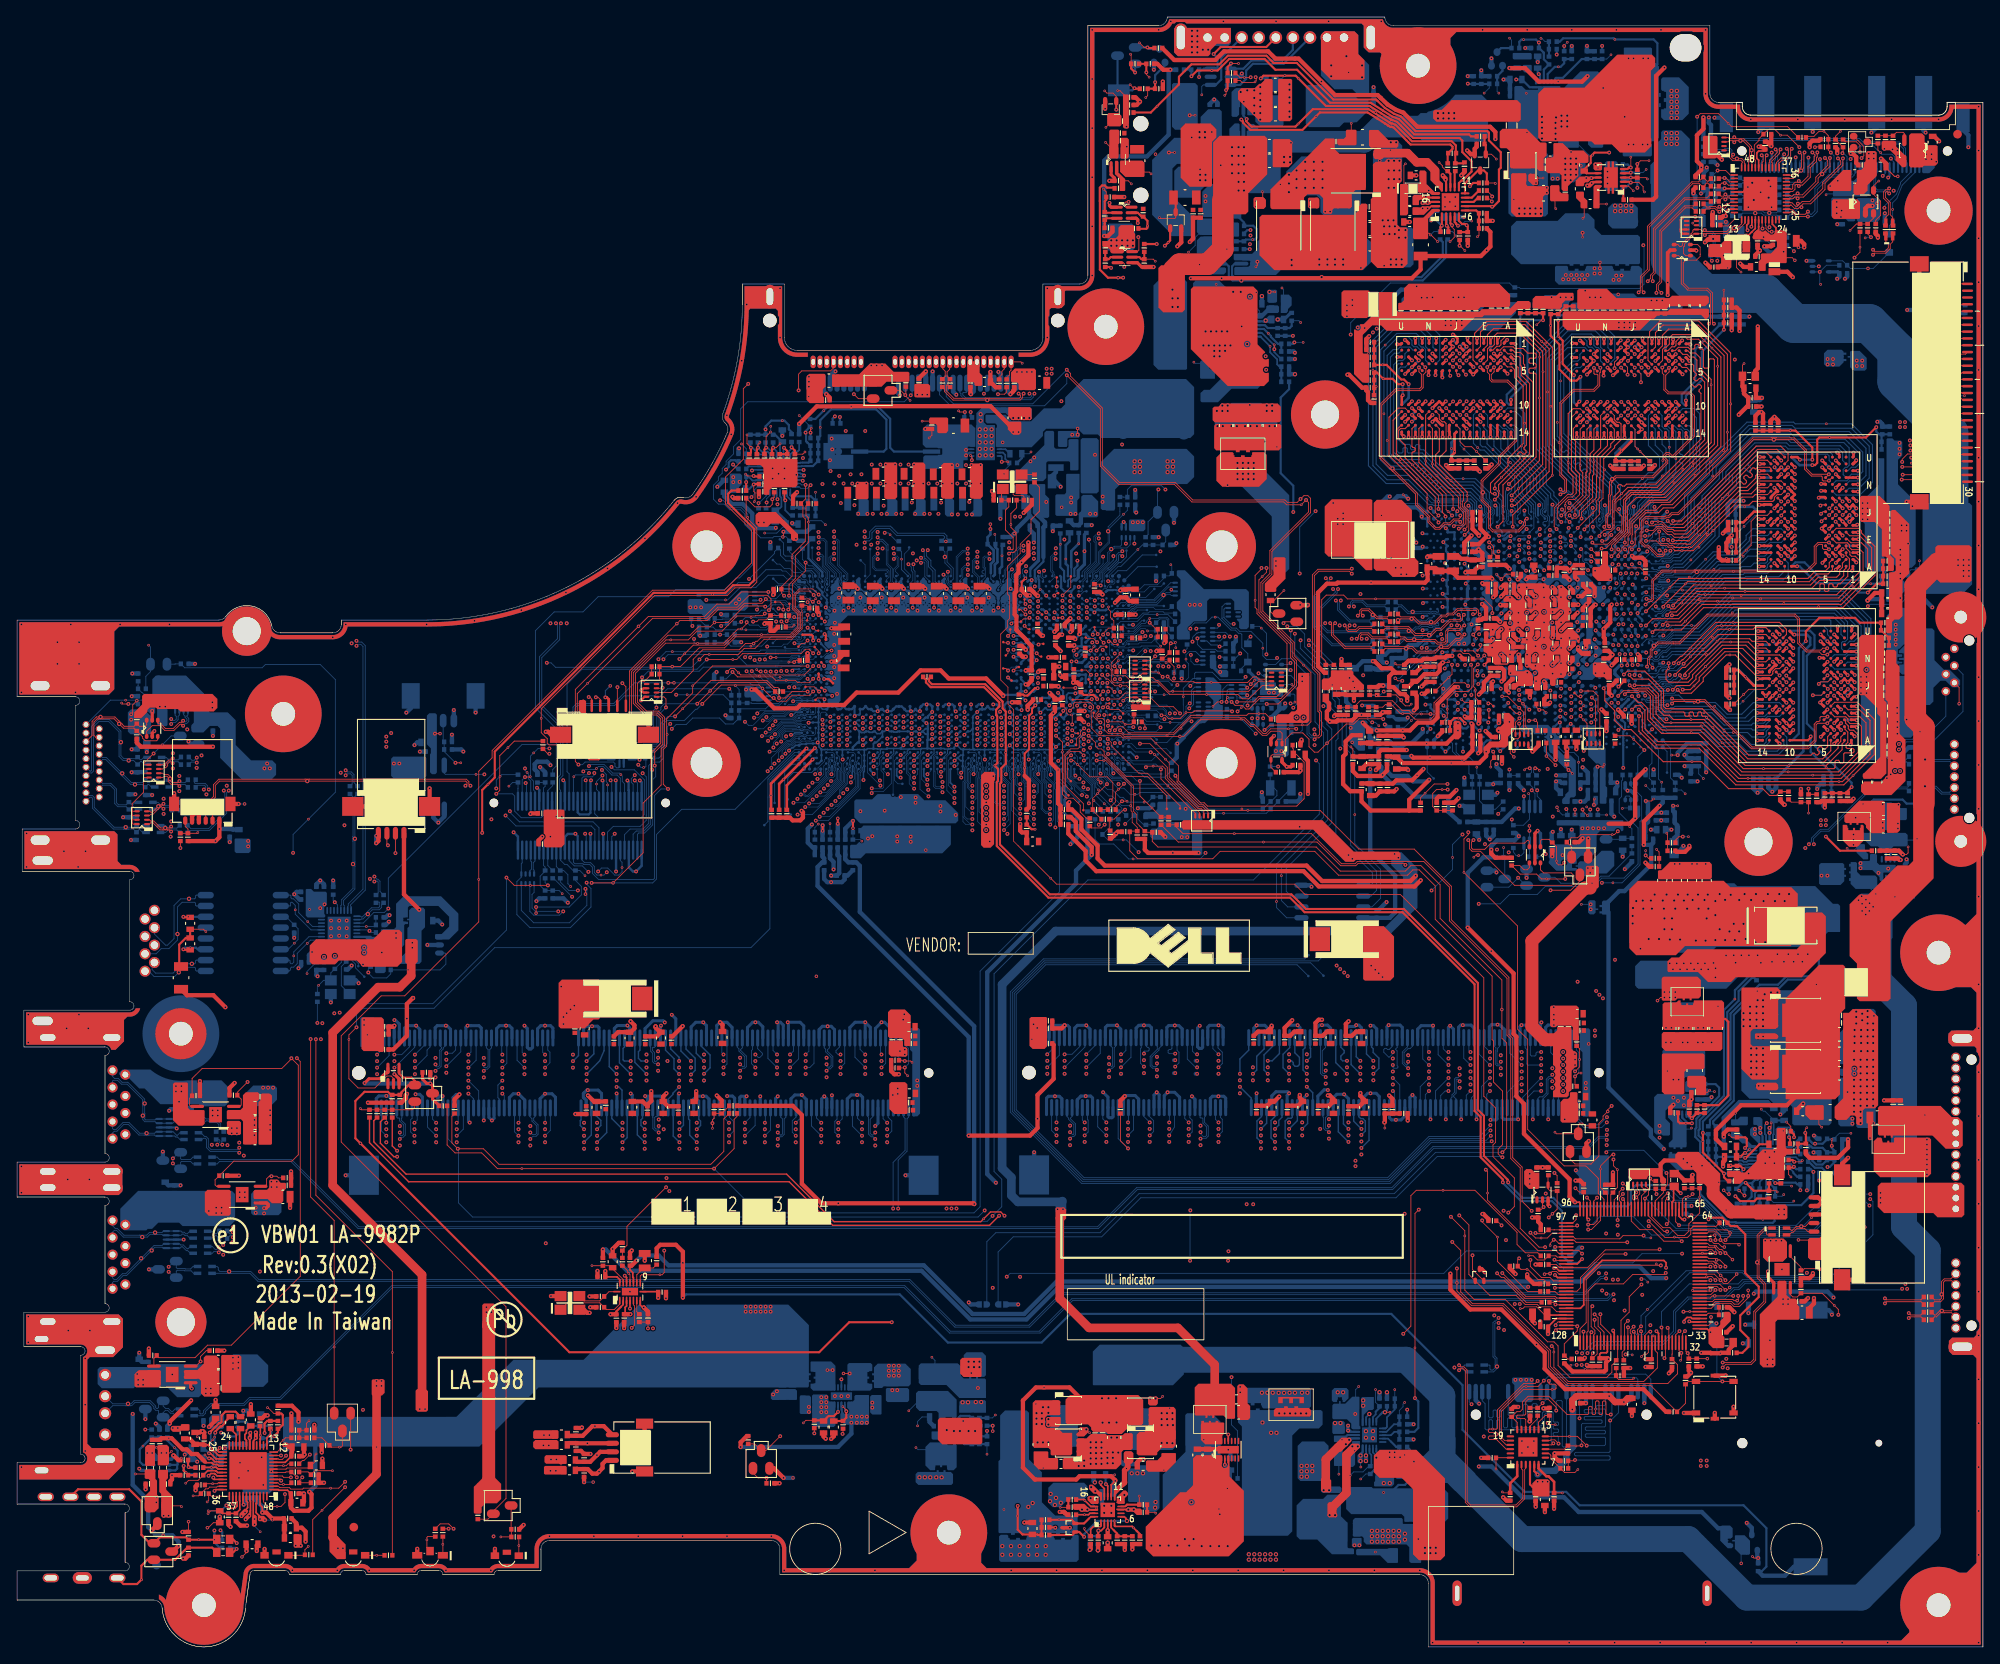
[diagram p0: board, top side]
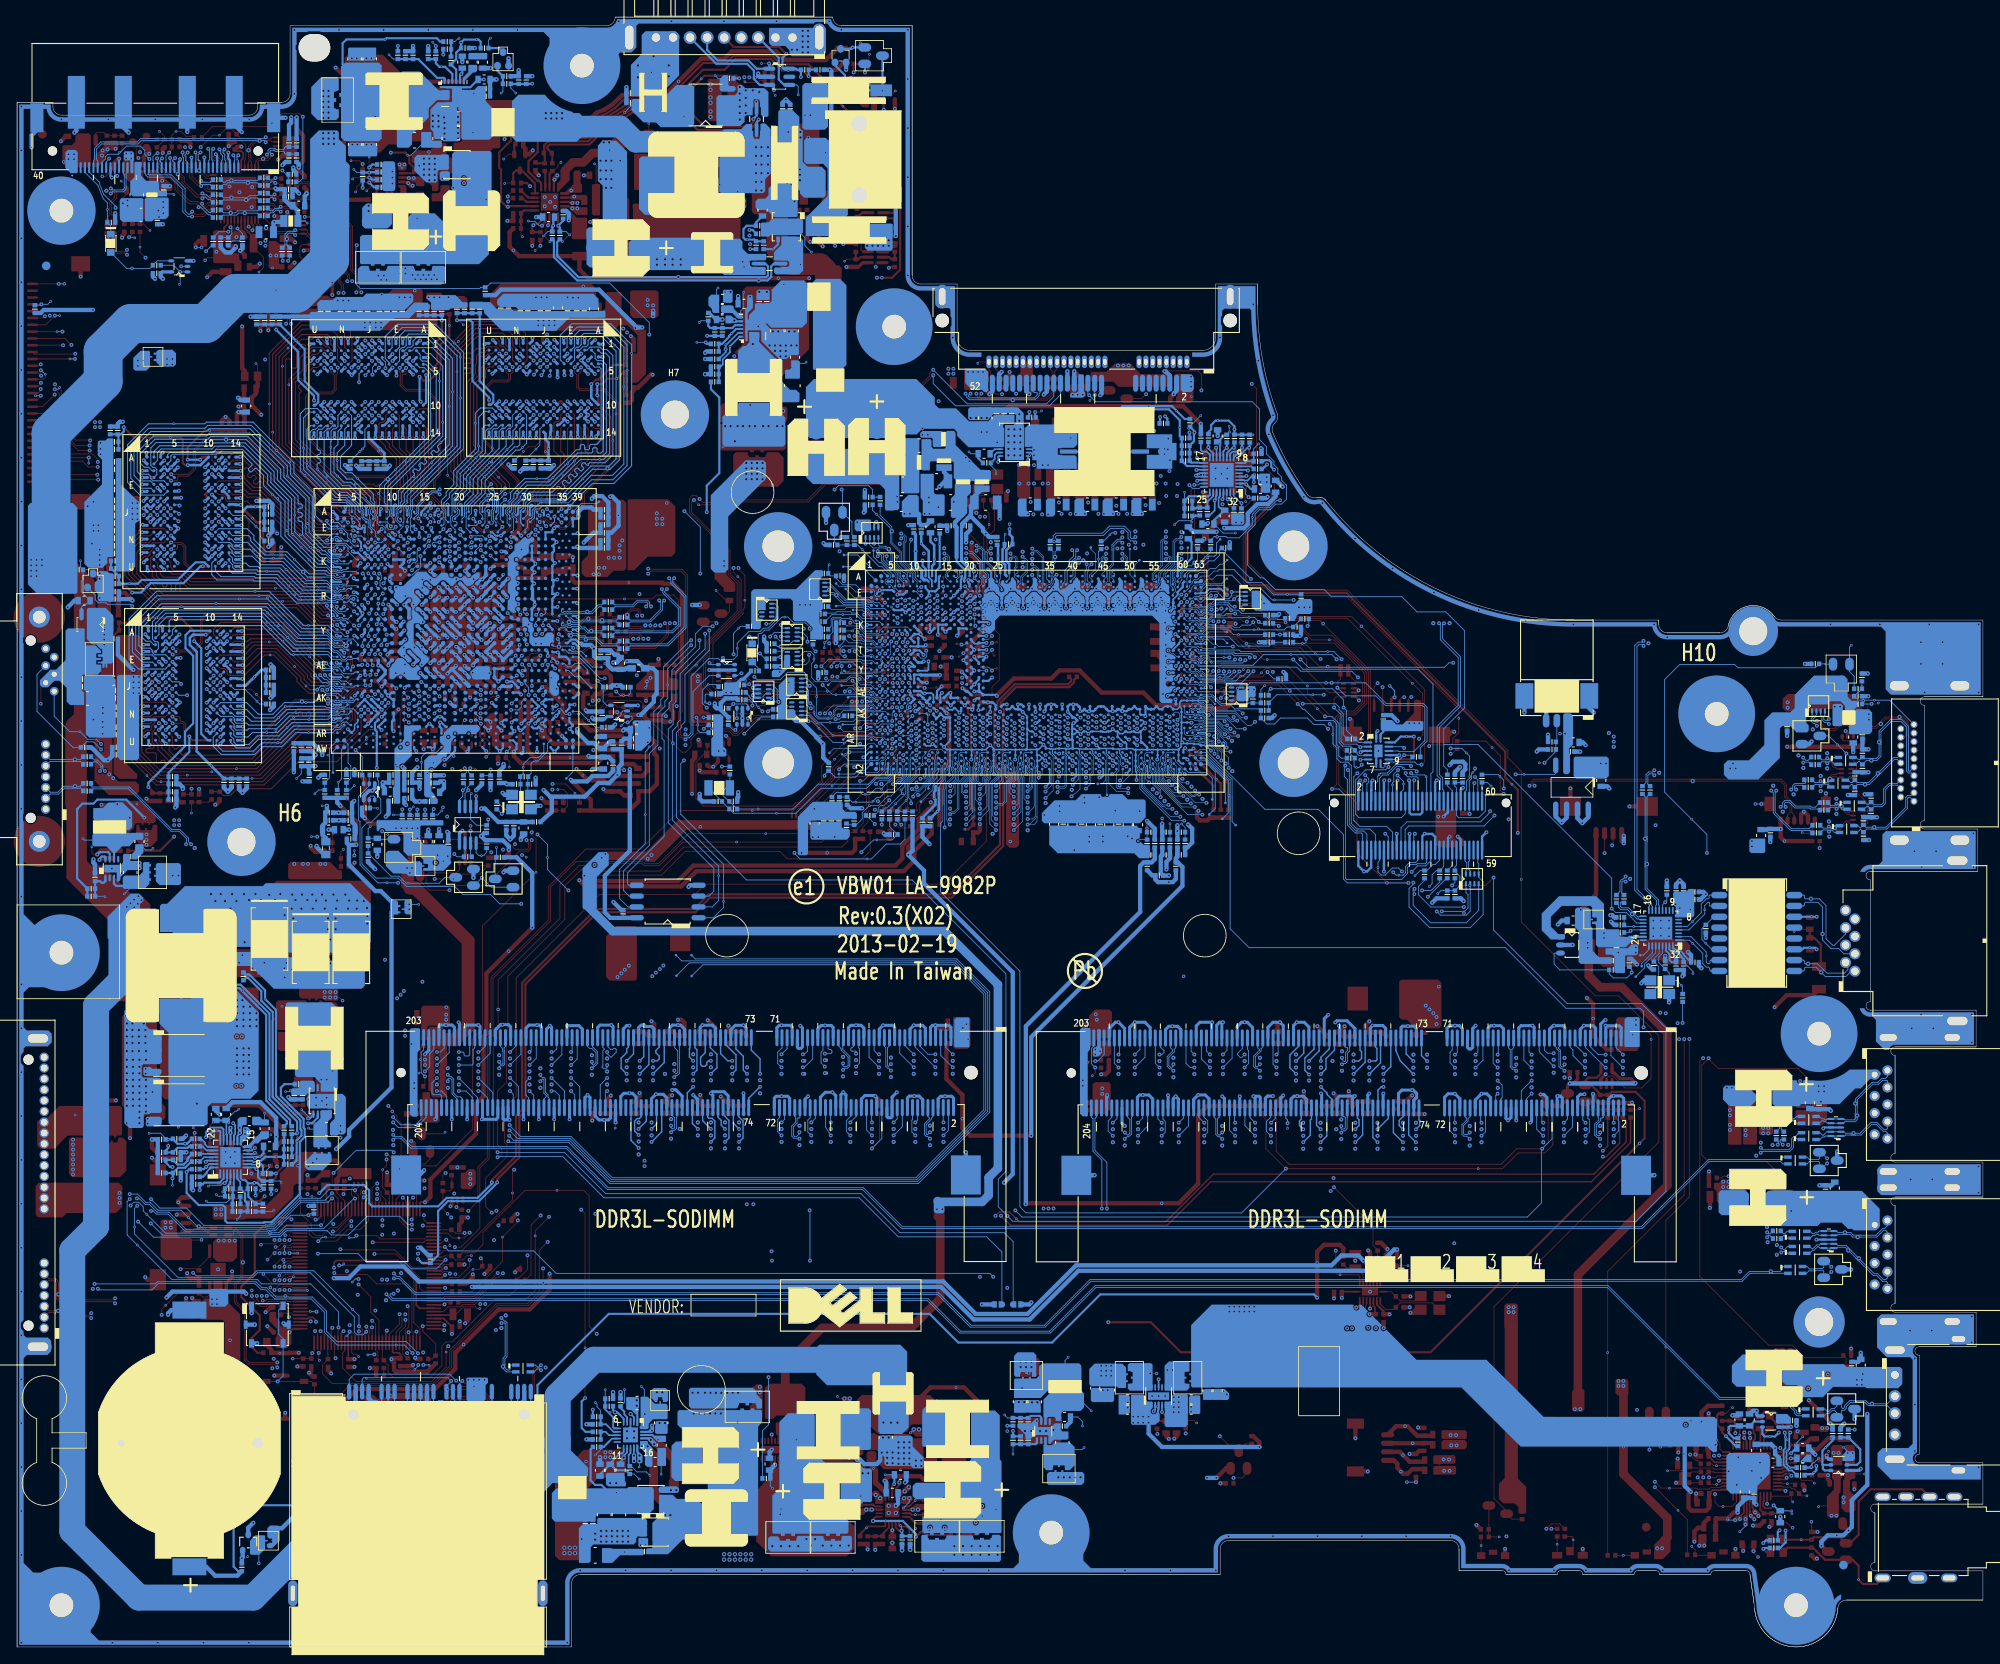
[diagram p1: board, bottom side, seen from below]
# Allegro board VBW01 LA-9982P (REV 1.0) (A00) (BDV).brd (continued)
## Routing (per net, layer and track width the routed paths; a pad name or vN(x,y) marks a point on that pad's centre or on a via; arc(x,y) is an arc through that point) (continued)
DDR_B_DQS1: length 56.2
  IN1 w0.084: v1(115.67,99.02) 115.52,98.88 115.28,98.88 114.23,97.82 114.23,94.32 114.36,94.18 114.36,94.02 114.42,93.96
  IN1 w0.127: v1(123.41,59.59) 123.3,59.7 122.9,59.7 122.51,60.09 122.51,62.72 122.29,62.94 121.97,62.94 121.7,63.22 121.7,63.81 121.97,64.08 122.33,64.08 122.46,64.21 122.46,66.39 121.86,66.99 121.86,71.45 114.44,78.87 114.44,93.94 114.42,93.96
  BOTTOM w0.076: UC1.AW26 114.43,103.91 114.39,103.87 114.39,103.48 114.37,103.43 114.33,103.34 114.32,103.32 114.32,103.19 114.34,103.14 114.39,103.03 114.39,102.63 114.1,102.34 114.02,102.26 114.02,101.93 114.64,101.32 114.64,99.18 114.95,98.86 115.51,98.86 v1(115.67,99.02)
  BOTTOM w0.102: JDIMM2.12 123.65,62.2 123.45,62.01 123.45,61.93 124.05,61.33 124.05,60.05 123.86,59.86 123.67,59.86 v1(123.41,59.59)
DDR_B_DQS2: length 89
  IN3 w0.084: v1(113.48,107.67) 113.28,107.47 113.09,107.47 112.93,107.31 112.93,105.13 115.18,102.87 115.18,101.99 116.04,101.13 116.04,95.97 117.22,94.79 117.62,94.39 117.81,94.39 118.14,94.06 118.87,94.06 119.32,93.61
  IN3 w0.127: 119.32,93.61 124.07,88.86 150.9,88.86 151.81,87.95 156.21,87.95 168.16,76 168.16,73.26 169.03,72.39 169.03,69.28 168.39,68.64 168.39,66.83 168.65,66.57 168.82,66.57 v1(169.07,66.33)
  BOTTOM w0.076: UC1.AM28 113.8,107.99 v1(113.48,107.67)
  BOTTOM w0.102: v1(169.07,66.33) 168.83,66.57 168.72,66.57 168.66,66.5 168.66,64.94 168.38,64.65 168.38,64.52 168.65,64.24 JDIMM2.154
DDR_B_DQS3: length 57.1
  IN1 w0.084: 118.8,93.94 118.8,94.44 116.91,96.32 116.91,101.23 116.43,101.72 116.43,102.23 116.79,102.59 116.79,102.79 116.69,102.89 116.56,102.89 116.49,102.82 116.16,102.82 115.77,103.21 115.77,103.56 116.24,104.03 116.24,104.21 116.07,104.38 115.89,104.38 115.22,103.71 114.92,103.71 114.52,104.11 114.52,104.47 115.07,105.02 115.07,105.14 114.81,105.41 114.81,107.37 115,107.57 115.21,107.57 v1(115.37,107.73)
  IN1 w0.127: 118.8,93.94 118.8,90.36 119.07,90.08 119.32,90.08 119.47,89.93 119.47,89.52 119.4,89.45 119.06,89.45 118.79,89.17 118.79,88.58 119.06,88.31 119.37,88.31 119.49,88.18 119.49,87.8 119.37,87.68 119.06,87.68 118.79,87.4 118.79,86.81 119.06,86.54 119.37,86.54 119.49,86.41 119.49,86.03 119.37,85.9 119.06,85.9 118.79,85.63 118.79,85.04 119.06,84.76 119.37,84.76 119.49,84.64 119.49,81.95 127.16,74.28 127.16,68.02 127.42,67.75 127.81,67.75 v1(127.98,67.58)
  BOTTOM w0.076: UC1.AM25 115.63,107.99 v1(115.37,107.73)
  BOTTOM w0.102: JDIMM2.29 128.75,70.42 128.59,70.25 128.59,68.05 128.39,67.86 128.26,67.86 v1(127.98,67.58)
DDR_B_DQS4: length 86.7
  IN3 w0.084: v1(117.57,100.58) 117.57,100.7 117.68,100.81 117.99,100.81 118.59,100.21 118.59,96.23 118.94,95.88 120.13,95.88 120.98,95.02 126.72,95.02 127.61,94.14 127.64,94.1 127.64,94.07 127.77,93.94
  IN3 w0.127: v1(173.9,68.61) 173.9,68.44 174.03,68.3 174.22,68.3 174.32,68.39 174.32,69.59 173.93,69.97 173.93,76.95 158.59,92.3 157.61,92.3 156.62,93.29 139.73,93.29 139.39,93.63 128.08,93.63 127.77,93.94
  BOTTOM w0.076: UC1.AV22 117.31,104.4 117.23,104.32 117.08,104.32 116.99,104.23 116.92,104.16 116.92,104.15 116.85,104.01 116.85,103.81 116.88,103.75 116.93,103.65 116.93,103.52 116.85,103.36 116.85,103.16 116.88,103.1 116.88,103.1 116.93,103 116.93,102.81 116.81,102.7 116.81,102.08 117.05,101.84 117.05,101.1 v1(117.57,100.58)
  BOTTOM w0.102: v1(173.9,68.61) 173.9,68.47 173.76,68.34 173.53,68.34 173.45,68.42 173.45,69.79 173.52,69.86 173.52,70.19 173.75,70.42 JDIMM2.171
DDR_B_DQS5: length 54.4
  IN1 w0.084: v1(121.05,98.3) 121.05,98.13 120.91,97.99 120.53,97.99 120.31,97.77 120.31,96.14 120.95,95.5 122.01,95.5 122.8,94.7 122.8,93.92 123.11,93.62 123.11,93.61
  IN1 w0.127: 123.11,93.61 123.11,92.31 123.78,91.63 123.78,88.61 124.06,88.34 124.36,88.34 124.49,88.21 124.49,87.83 124.36,87.7 124.06,87.7 123.78,87.43 123.78,86.82 124.04,86.56 124.91,86.56 125.04,86.44 125.04,86.06 124.91,85.93 124.19,85.93 123.92,85.65 123.92,85.06 124.19,84.79 124.89,84.79 125.04,84.64 125.04,83.93 133.51,75.46 133.51,73.63 133.78,73.36 133.89,73.36 134.01,73.23 134.01,72.85 133.89,72.72 133.76,72.72 133.48,72.45 133.48,71.86 133.76,71.59 133.89,71.59 134.01,71.46 134.01,71.08 133.89,70.95 133.76,70.95 133.48,70.68 133.48,70.09 133.76,69.81 133.89,69.81 134.01,69.69 134.01,68.24 133.9,68.12 133.72,68.12 133.6,68.25 v1(133.6,68.42)
  BOTTOM w0.076: v1(121.05,98.3) 121.05,98.17 120.78,97.89 120.62,97.89 120.18,98.33 120.18,101.26 119.28,102.16 119.28,102.48 119.52,102.72 119.52,103.03 119.5,103.08 119.5,103.08 119.45,103.19 119.45,103.32 119.46,103.34 119.5,103.43 119.52,103.48 119.52,103.88 119.6,103.96 119.69,103.96 UC1.AW18
  BOTTOM w0.102: v1(133.6,68.42) 133.63,68.38 133.63,68.17 133.52,68.06 133.15,68.06 133,68.21 133,69.16 133.83,69.99 133.83,70.18 134.15,70.5 JDIMM2.47
DDR_B_DQS6: length 94.7
  IN3 w0.084: v1(118.13,107.67) 117.95,107.48 117.82,107.48 117.58,107.25 117.58,105.5 118.43,104.65 119.29,104.65 122.72,101.22 122.72,98.85 123.54,98.03 129.16,98.03 129.86,98.73 131.47,98.73 131.51,98.69 131.57,98.69
  IN3 w0.127: v1(179.93,66.33) 179.78,66.48 179.54,66.48 179.25,66.77 179.25,78.25 159.89,97.61 144.96,97.61 144.08,98.49 137.54,98.49 137.34,98.69 131.57,98.69
  BOTTOM w0.076: UC1.AM21 118.52,107.77 118.42,107.67 v1(118.13,107.67)
  BOTTOM w0.102: JDIMM2.188 178.85,64.28 179.42,64.85 179.42,66.49 179.6,66.66 179.82,66.66 179.93,66.55 v1(179.93,66.33)
DDR_B_DQS7: length 63.4
  IN1 w0.084: v1(120.04,107.67) 119.85,107.49 119.69,107.49 119.48,107.27 119.48,104.47 121.57,102.38 121.57,102.11 122.65,101.04 122.65,98.63 126.39,94.88 127.34,94.88 128.11,94.12 128.11,93.97 128.09,93.95 128.09,93.94
  IN1 w0.127: 128.09,93.94 128.09,92.79 130.9,89.97 130.9,85.35 139.1,77.16 139.1,62.38 138.83,62.11 138.33,62.11 137.95,61.73 137.95,60.14 138.33,59.76 138.53,59.76 v1(138.7,59.59)
  BOTTOM w0.076: v1(120.04,107.67) 120.1,107.67 UC1.AM18
  BOTTOM w0.102: JDIMM2.64 139.25,62.19 139.18,62.12 139.18,61.5 139.61,61.07 139.61,59.9 139.35,59.64 138.74,59.64 v1(138.7,59.59)
DDR_B_DQS#0: length 82.1
  IN3 w0.084: 114.2,94.37 114.2,94.63 113.21,95.62 113.21,99.74 112.3,100.65 112.17,100.65 111.96,100.87 v1(111.96,100.97)
  IN3 w0.127: v1(163.03,67.85) 163.28,68.1 163.45,68.1 163.7,68.34 163.7,74.27 155.2,82.77 152.04,82.77 150.94,83.87 150.12,83.87 149.21,84.78 122.38,84.78 117.33,89.83 116.98,89.83 114.2,92.62 114.2,94.37
  BOTTOM w0.076: UC1.AW30 112.18,104.09 112.11,104.16 112.02,104.16 111.94,104.08 111.89,103.97 111.89,103.84 111.96,103.69 111.96,103.48 111.94,103.43 111.89,103.34 111.89,103.32 111.89,103.19 111.91,103.14 111.94,103.08 111.94,103.08 111.96,103.03 111.96,102.74 111.72,102.5 111.72,101.36 111.53,101.17 111.53,100.83 111.71,100.66 111.8,100.66 111.96,100.81 v1(111.96,100.97)
  BOTTOM w0.102: v1(163.03,67.85) 162.85,68.03 162.74,68.03 162.35,68.42 162.35,69.76 162.95,70.36 JDIMM2.135
DDR_B_DQS#1: length 56.5
  IN1 w0.084: 114.59,94.14 114.57,94.16 114.57,94.27 114.43,94.41 114.43,97.74 115.36,98.67 115.56,98.67 115.67,98.56 v1(115.67,98.37)
  IN1 w0.127: 114.59,94.14 114.69,94.04 114.69,78.97 122.11,71.55 122.11,67.09 122.71,66.5 122.71,64.1 122.43,63.83 122.08,63.83 121.95,63.7 121.95,63.32 122.08,63.19 122.39,63.19 122.76,62.82 122.76,60.2 123.01,59.95 123.19,59.95 123.41,60.17 v1(123.41,60.36)
  BOTTOM w0.076: UC1.AV26 114.38,104.33 114.38,104.16 114.23,104 114.23,103.52 114.15,103.36 114.15,103.16 114.23,103 114.23,102.7 113.98,102.46 113.86,102.33 113.86,101.87 114.47,101.25 114.47,99.11 114.89,98.7 115.46,98.7 115.67,98.5 v1(115.67,98.37)
  BOTTOM w0.102: v1(123.41,60.36) 123.71,60.06 123.78,60.06 123.85,60.14 123.85,61.25 123.26,61.85 123.26,61.99 123.05,62.19 JDIMM2.10
DDR_B_DQS#2: length 89.1
  IN3 w0.084: v1(113.48,107.02) 113.48,107.18 113.36,107.3 113.16,107.3 113.1,107.24 113.1,105.2 115.36,102.94 115.36,102.06 116.21,101.2 116.21,96.04 117.69,94.56 117.88,94.56 118.21,94.23 118.98,94.23 119.41,93.8 119.47,93.8
  IN3 w0.127: 119.47,93.8 124.17,89.1 151,89.1 151.91,88.19 156.31,88.19 168.4,76.1 168.4,73.36 169.27,72.49 169.27,69.18 168.63,68.54 168.63,66.93 168.75,66.81 168.97,66.81 169.07,66.91 v1(169.07,67.09)
  BOTTOM w0.076: v1(113.48,107.02) 113.81,107.02 113.87,107.08 UC1.AN28
  BOTTOM w0.102: v1(169.07,67.09) 169.07,66.93 168.9,66.76 168.64,66.76 168.46,66.59 168.46,65.02 168.18,64.74 168.18,64.46 168.05,64.34 JDIMM2.152
DDR_B_DQS#3: length 57.2
  IN1 w0.084: v1(115.37,106.95) 115.45,106.95 115.61,107.11 115.61,107.31 115.56,107.36 115.09,107.36 114.99,107.26 114.99,105.52 115.28,105.23 115.28,104.93 114.73,104.38 114.73,104.2 115.01,103.91 115.14,103.91 115.81,104.58 116.16,104.58 116.45,104.29 116.45,103.94 115.98,103.47 115.98,103.29 116.25,103.03 116.4,103.03 116.47,103.1 116.78,103.1 117,102.88 117,102.5 116.64,102.14 116.64,101.8 117.12,101.32 117.12,96.4 119,94.52 119,94.06 119.03,94.03 119.03,93.97 119.05,93.95 119.05,93.61
  IN1 w0.127: v1(127.98,68.34) 127.98,68.09 127.89,68.01 127.52,68.01 127.41,68.12 127.41,74.38 119.74,82.05 119.74,84.75 119.47,85.02 119.17,85.02 119.04,85.14 119.04,85.52 119.17,85.65 119.47,85.65 119.74,85.92 119.74,86.51 119.47,86.79 119.17,86.79 119.04,86.92 119.04,87.3 119.17,87.42 119.47,87.42 119.74,87.7 119.74,88.29 119.47,88.56 119.17,88.56 119.04,88.69 119.04,89.07 119.17,89.2 119.5,89.2 119.72,89.42 119.72,90.03 119.42,90.33 119.17,90.33 119.05,90.46 119.05,93.61
  BOTTOM w0.076: v1(115.37,106.95) 115.61,106.95 115.77,107.12 UC1.AN25
  BOTTOM w0.102: v1(127.98,68.34) 128.26,68.06 128.31,68.06 128.39,68.14 128.39,70.25 128.15,70.49 JDIMM2.27
DDR_B_DQS#4: length 86.8
  IN3 w0.084: 127.94,94.11 127.88,94.11 126.79,95.19 121.05,95.19 120.2,96.05 119.02,96.05 118.76,96.3 118.76,100.28 118.06,100.98 117.76,100.98 v1(117.57,101.16)
  IN3 w0.127: v1(173.9,67.85) 173.9,67.91 174.04,68.06 174.32,68.06 174.56,68.29 174.56,69.69 174.18,70.07 174.18,77.05 158.69,92.54 157.71,92.54 156.72,93.53 139.83,93.53 139.49,93.87 128.18,93.87 127.94,94.11
  BOTTOM w0.076: v1(117.57,101.16) 117.28,101.16 117.22,101.23 117.22,101.91 116.98,102.15 116.98,102.63 117.09,102.74 117.09,103.03 117.07,103.09 117.02,103.19 117.02,103.32 117.03,103.34 117.07,103.43 117.09,103.48 117.09,103.69 117.02,103.84 117.02,103.97 117.07,104.08 117.15,104.16 117.24,104.16 117.31,104.09 UC1.AW22
  BOTTOM w0.102: v1(173.9,67.85) 173.9,68.01 173.76,68.14 173.44,68.14 173.25,68.33 173.25,69.87 173.32,69.94 173.32,70.24 173.15,70.41 JDIMM2.169
DDR_B_DQS#5: length 54.8
  IN1 w0.084: v1(121.05,97.65) 120.92,97.78 120.61,97.78 120.51,97.68 120.51,96.23 121.03,95.71 122.09,95.71 123.01,94.79 123.01,94.01 123.18,93.84 123.2,93.84 123.34,93.71 123.34,93.65 123.36,93.62 123.36,93.61
  IN1 w0.127: v1(133.6,67.66) 133.6,67.66 133.81,67.87 134,67.87 134.27,68.13 134.27,69.79 133.99,70.07 133.86,70.07 133.73,70.19 133.73,70.57 133.86,70.7 133.99,70.7 134.27,70.97 134.27,71.56 133.99,71.84 133.86,71.84 133.73,71.97 133.73,72.35 133.86,72.47 133.99,72.47 134.27,72.75 134.27,73.34 133.99,73.61 133.88,73.61 133.76,73.74 133.76,75.57 125.29,84.04 125.29,84.75 124.99,85.04 124.3,85.04 124.17,85.17 124.17,85.55 124.3,85.68 125.01,85.68 125.29,85.95 125.29,86.54 125.01,86.82 124.15,86.82 124.04,86.93 124.04,87.32 124.16,87.45 124.47,87.45 124.74,87.72 124.74,88.31 124.47,88.59 124.16,88.59 124.04,88.71 124.04,91.74 123.36,92.41 123.36,93.61
  BOTTOM w0.076: UC1.AV18 119.52,104.33 119.52,104.16 119.36,104 119.36,103.52 119.28,103.36 119.28,103.16 119.36,103 119.36,102.8 119.12,102.56 119.12,102.09 120.02,101.19 120.02,98.26 120.55,97.73 120.97,97.73 v1(121.05,97.65)
  BOTTOM w0.102: v1(133.6,67.66) 133.39,67.86 133.07,67.86 132.8,68.13 132.8,69.24 133.63,70.08 133.63,70.43 133.55,70.51 JDIMM2.45
DDR_B_DQS#6: length 94.9
  IN3 w0.084: 131.55,98.93 131.53,98.9 129.79,98.9 129.09,98.2 123.61,98.2 122.89,98.92 122.89,101.29 119.36,104.83 118.5,104.83 117.76,105.57 117.76,107.18 117.89,107.31 118.02,107.31 118.13,107.2 v1(118.13,107.02)
  IN3 w0.127: 131.55,98.93 137.44,98.93 137.64,98.73 144.18,98.73 145.06,97.85 159.99,97.85 179.49,78.35 179.49,66.87 179.64,66.72 179.77,66.72 179.93,66.88 v1(179.93,67.09)
  BOTTOM w0.076: v1(118.13,107.02) 118.46,107.34 UC1.AN21
  BOTTOM w0.102: v1(179.93,67.09) 179.7,66.86 179.51,66.86 179.22,66.57 179.22,64.93 178.79,64.5 178.43,64.5 178.25,64.31 JDIMM2.186
DDR_B_DQS#7: length 63.6
  IN1 w0.084: 128.34,93.94 128.34,94.18 127.42,95.09 126.48,95.09 122.86,98.71 122.86,101.12 121.78,102.2 121.78,102.41 119.67,104.52 119.67,107.22 119.73,107.28 119.97,107.28 120.04,107.2 v1(120.04,107.02)
  IN1 w0.127: 128.34,93.94 128.34,92.9 131.16,90.08 131.16,85.46 139.35,77.26 139.35,62.28 138.93,61.86 138.44,61.86 138.2,61.63 138.2,60.25 138.44,60.02 138.6,60.02 138.7,60.11 v1(138.7,60.36)
  BOTTOM w0.089: v1(120.04,107.02) 120.49,107.02 120.55,107.08 120.55,107.26 120.47,107.34 UC1.AN18
  BOTTOM w0.102: JDIMM2.62 138.65,62.1 138.73,62.02 138.88,62.02 138.98,61.92 138.98,61.42 139.41,60.98 139.41,59.98 139.27,59.84 139.03,59.84 138.7,60.17 v1(138.7,60.36)
DDR_B_MA0: length 80.9
  IN3 w0.084: v1(105.76,106.37) 106.1,106.02 106.1,105.37 105.88,105.15 105.88,99.04 105.18,98.34 105.18,94.21 104.78,93.8 104.78,93.66
  IN3 w0.208: v1(151.16,65.67) 151.62,66.14 151.62,69.68 150.96,70.34 150.96,70.89 148.5,73.35 120.1,73.35 104.78,88.67 104.78,93.66
  BOTTOM w0.076: v1(105.76,106.37) 106.08,106.69 UC1.AP40
  BOTTOM w0.165: v1(151.16,65.67) 151.85,64.98 JDIMM2.98
DDR_B_MA1: length 81.2
  IN3 w0.084: v1(105.73,105.72) 105.53,105.52 105.53,100.46 104.89,99.82 104.89,96.35 104.01,95.47 104.01,94.31 104.31,94.01 104.31,93.66
  IN3 w0.208: v1(151.16,68.72) 150.69,68.72 150.49,68.92 150.49,70.69 148.31,72.88 147.72,72.88 147.22,72.38 146.84,72.38 146.38,72.85 145.89,72.85 145.43,72.38 145.12,72.38 144.62,72.88 141.46,72.88 140.88,72.3 140.13,72.3 139.91,72.51 139.91,72.66 139.7,72.88 139.26,72.88 139.05,72.66 139.05,72.5 138.84,72.3 137.65,72.3 137.44,72.5 137.44,72.66 137.23,72.88 136.79,72.88 136.58,72.66 136.58,72.51 136.36,72.3 135.5,72.3 134.92,72.88 132.72,72.88 132.14,72.3 128.84,72.3 128.26,72.88 125.96,72.88 125.38,72.3 120.5,72.3 104.31,88.49 104.31,93.66
  BOTTOM w0.076: v1(105.73,105.72) 106.06,106.04 UC1.AR40
  BOTTOM w0.165: JDIMM2.97 151.55,70.22 151.6,70.17 151.6,69.16 v1(151.16,68.72)
DDR_B_MA2: length 85.9
  IN3 w0.084: v1(104.84,106.42) 104.28,105.86 104.28,96.6 103.66,95.98 103.66,94.24 103.37,93.95 103.37,93.66
  IN3 w0.208: v1(150.62,60.74) 149.55,61.8 149.55,69.67 147.86,71.36 119.46,71.36 118.08,72.74 118.08,73.39 103.37,88.1 103.37,93.66
  BOTTOM w0.076: v1(104.84,106.42) 105.12,106.69 UC1.AP42
  BOTTOM w0.165: v1(150.62,60.74) 151.25,61.37 JDIMM2.96
DDR_B_MA3: length 82.7
  IN3 w0.084: v1(104.84,105.77) 104.65,105.58 104.65,96.62 103.84,95.81 103.84,93.66
  IN3 w0.208: v1(151.16,67.2) 150.22,67.2 150.02,67.4 150.02,70.5 148.61,71.91 144.33,71.91 143.84,72.41 141.65,72.41 141.07,71.83 135.3,71.83 134.72,72.41 132.92,72.41 132.34,71.83 128.64,71.83 128.06,72.41 126.15,72.41 125.58,71.83 119.65,71.83 118.55,72.93 118.55,73.58 103.84,88.29 103.84,93.66
  BOTTOM w0.076: v1(104.84,105.77) 105.12,106.04 UC1.AR42
  BOTTOM w0.165: v1(151.16,67.2) 150.72,67.64 150.72,70.02 150.95,70.25 JDIMM2.95
DDR_B_MA4: length 90.1
  IN3 w0.084: v1(102.94,105.79) 102.51,105.37 102.51,103.18 102.09,102.75 101.95,102.75 101.68,102.49 101.68,102.17 102.28,101.58 102.28,96.17 101.96,95.85 101.96,93.66
  IN3 w0.208: v1(149.08,60.74) 148.43,61.39 148.43,65.36 147.68,66.11 147.68,68.96 146.69,69.95 140.62,69.95 140.15,69.49 140.15,68.19 138.68,66.71 135.14,66.71 134.86,66.43 132.89,66.43 132.61,66.71 129.16,66.71 128.81,67.07 128.81,68.93 128.17,69.57 125.88,69.57 125.5,69.95 118.87,69.95 116.67,72.15 116.67,72.8 101.96,87.51 101.96,93.66
  BOTTOM w0.076: v1(102.94,105.79) 103.18,106.04 UC1.AR45
  BOTTOM w0.165: v1(149.08,60.74) 150.05,61.71 JDIMM2.92
DDR_B_MA5: length 86.8
  IN3 w0.084: v1(102.94,106.45) 103.4,106.45 103.47,106.37 103.47,105.36 103.95,104.88 103.95,99.2 103.87,99.12 103.19,99.12 103.13,99.05 103.13,95.62 102.71,95.2 102.71,94.18 102.9,93.99 102.9,93.66
  IN3 w0.208: 102.9,93.66 102.9,87.9 117.61,73.19 117.61,72.54 119.26,70.89 126.27,70.89 126.65,70.51 127.14,70.51 127.52,70.89 128,70.89 128.38,70.51 128.86,70.51 129.24,70.89 130.17,70.89 130.3,70.76 130.3,68.8 130.43,68.67 131.02,68.67 131.15,68.8 131.15,70.76 131.27,70.89 132.15,70.89 132.53,70.51 133.01,70.51 133.39,70.89 133.87,70.89 134.26,70.51 134.74,70.51 135.12,70.89 135.59,70.89 135.96,70.51 136.64,70.51 137.02,70.89 147.67,70.89 148.62,69.94 148.62,68.78 148.75,68.65 149.01,68.65 v1(149.08,68.72)
  BOTTOM w0.076: v1(102.94,106.45) 103.18,106.69 UC1.AP45
  BOTTOM w0.165: JDIMM2.91 149.75,69.67 150.29,69.13 150.29,68.29 150.09,68.08 149.77,68.08 149.57,68.29 149.57,68.52 149.37,68.72 v1(149.08,68.72)
DDR_B_MA6: length 93
  IN3 w0.084: 101.49,93.66 101.49,95.96 102.06,96.53 102.06,101.55 101.51,102.1 101.51,102.82 v1(101.97,103.28)
  IN3 w0.208: v1(149.08,59.21) 147.96,60.34 147.96,62.52 147.21,63.27 147.21,68.76 146.49,69.48 141.63,69.48 141.32,69.16 141.32,67.05 141,66.73 139.71,66.73 139.22,66.24 135.33,66.24 135.06,65.96 132.69,65.96 132.41,66.24 124.74,66.24 124.53,66.46 124.53,67.07 124.4,67.19 123.58,67.19 123.45,67.07 123.45,66.46 123.23,66.24 121.04,66.24 120.27,67.01 120.27,69.27 120.07,69.48 118.68,69.48 116.2,71.96 116.2,72.61 101.49,87.32 101.49,93.66
  BOTTOM w0.076: v1(101.97,103.28) 101.98,103.28 102.28,103.58 UC1.AW46
  BOTTOM w0.165: v1(149.08,59.21) 148.62,59.68 148.62,61.66 148.95,61.99 149.32,61.99 149.45,62.12 JDIMM2.90
DDR_B_MA7: length 91.2
  IN3 w0.084: v1(100.16,100.11) 100.16,97.48 98.01,95.33 98.01,93.66
  IN3 w0.208: v1(147.43,60.74) 147.17,60.74 146.97,60.94 146.97,62.23 146.76,62.43 144.57,62.43 144.37,62.23 144.37,60.72 144.24,60.59 143.63,60.59 143.51,60.72 143.51,62.23 143.3,62.43 142.85,62.43 142.64,62.23 142.64,60.72 142.52,60.59 141.91,60.59 141.78,60.72 141.78,62.23 141.58,62.43 118.84,62.43 107.15,74.13 107.15,76.95 98.01,86.09 98.01,93.66
  BOTTOM w0.076: UC1.AY46 102.45,102.86 102.45,101.23 101.5,100.28 100.33,100.28 v1(100.16,100.11)
  BOTTOM w0.165: v1(147.43,60.74) 147.87,61.18 147.87,61.73 148.25,62.11 JDIMM2.86
DDR_B_MA8: length 89.9
  IN3 w0.084: 102.43,93.66 102.19,93.9 102.19,95.43 102.47,95.71 102.47,101.91 v1(102.05,102.33)
  IN3 w0.208: v1(149.08,67.2) 148.42,67.2 148.15,67.47 148.15,69.15 146.88,70.42 139.74,70.42 139.62,70.29 139.62,69.16 139.49,69.04 138.89,69.04 138.76,69.16 138.76,70.24 138.63,70.37 137.15,70.37 137.03,70.24 137.03,68.4 136.9,68.27 136.32,68.27 136.19,68.4 136.19,69.92 136.07,70.05 135.18,70.05 135.05,69.92 135.05,68.4 134.93,68.27 134.19,68.27 134.06,68.4 134.06,69.91 133.93,70.04 131.81,70.04 131.61,69.83 131.61,68.34 131.48,68.21 129.97,68.21 129.84,68.34 129.84,69.91 129.71,70.04 126.08,70.04 125.7,70.42 119.07,70.42 117.14,72.35 117.14,73 102.43,87.71 102.43,93.66
  BOTTOM w0.076: UC1.AY47 101.55,102.75 101.97,102.33 v1(102.05,102.33)
  BOTTOM w0.165: v1(149.08,67.2) 148.37,67.91 148.37,69.49 149.15,70.26 JDIMM2.89
DDR_B_MA9: length 92.4
  IN3 w0.084: 101.02,93.66 101.02,95.83 101.23,96.04 101.23,99.51 101.74,100.01 101.74,101.63 101.34,102.03 101.34,103.94 v1(101.98,104.58)
  IN3 w0.208: v1(146.58,68.72) 146.27,68.72 146.15,68.59 146.15,68.11 146.02,67.98 145.41,67.98 145.28,68.11 145.28,68.88 145.15,69.01 143.64,69.01 143.51,68.88 143.51,68.05 143.39,67.92 142.78,67.92 142.65,68.05 142.65,68.88 142.52,69.01 141.91,69.01 141.79,68.88 141.79,66.85 141.2,66.26 140.01,66.26 139.51,65.77 135.53,65.77 135.25,65.49 132.5,65.49 132.22,65.77 120.84,65.77 119.8,66.81 119.8,68.8 119.6,69.01 118.18,69.01 117.39,68.22 117.1,68.22 116.78,68.54 116.78,68.83 117.57,69.62 117.57,69.92 117.26,70.23 116.96,70.23 116.17,69.44 115.88,69.44 115.56,69.76 115.56,70.05 116.35,70.84 116.35,71.15 116.04,71.45 115.73,71.45 114.94,70.66 114.66,70.66 114.33,70.99 114.33,71.27 115.41,72.35 115.41,72.73 101.02,87.12 101.02,93.66
  BOTTOM w0.076: UC1.AU46 102.13,104.58 v1(101.98,104.58)
  BOTTOM w0.165: v1(146.58,68.72) 147.1,68.72 147.95,69.57 JDIMM2.85
DDR_B_MA10: length 96.7
  IN3 w0.084: v1(108.18,109.12) 108.49,109.12 108.59,109.02 108.59,104.96 108.85,104.69 108.85,99.88 107.53,98.56 107.53,97.1 107.75,96.89 107.75,96.47
  IN3 w0.208: v1(155.87,67.2) 155.52,67.2 155.4,67.32 155.4,71.57 155.17,71.8 155.17,72.1 155.4,72.32 155.4,72.69 155.11,72.97 154.82,72.97 154.57,72.72 154.25,72.72 153.95,73.02 153.95,73.35 154.08,73.48 154.08,73.74 153.44,74.37 153.44,74.56 153.66,74.78 153.66,75.11 153.32,75.45 152.99,75.45 152.32,74.78 152.04,74.78 150.51,76.31 128.29,76.31 128.09,76.52 128.09,78.12 127.89,78.33 127.43,78.33 127.23,78.12 127.23,76.52 127.02,76.31 126.57,76.31 126.36,76.52 126.36,78.12 126.16,78.33 125.7,78.33 125.5,78.12 125.5,76.52 125.3,76.31 124.84,76.31 124.64,76.52 124.64,78.12 124.43,78.33 119.33,78.33 107.75,89.91 107.75,96.47
  BOTTOM w0.076: UC1.AK36 108.35,109.3 v1(108.18,109.12)
  BOTTOM w0.165: JDIMM2.107 154.55,68.51 v1(155.87,67.2)
DDR_B_MA11: length 93.1
  IN3 w0.084: 97.54,93.66 97.54,95.22 99.79,97.47 99.79,100.29 v1(100.17,100.67)
  IN3 w0.208: v1(147.43,59.21) 146.7,59.21 146.5,59.42 146.5,61.76 146.29,61.96 145.04,61.96 144.84,61.76 144.84,60.16 144.64,59.95 141.51,59.95 141.31,60.16 141.31,61.76 141.11,61.96 118.65,61.96 106.68,73.93 106.68,76.76 97.54,85.9 97.54,93.66
  BOTTOM w0.076: v1(100.17,100.67) 100.22,100.62 101.4,100.62 101.58,100.8 101.58,102.43 101.26,102.74 101.26,103.94 UC1.AV47
  BOTTOM w0.165: JDIMM2.84 147.65,62.41 146.97,61.73 146.97,59.68 v1(147.43,59.21)
DDR_B_MA12: length 88.6
  IN3 w0.084: 98.48,93.66 98.48,95.15 100.54,97.21 100.54,101.86 100.77,102.08 100.77,102.85 v1(100.39,103.23)
  IN3 w0.208: 98.48,93.66 98.48,86.28 107.62,77.15 107.62,74.32 119.04,62.9 145.72,62.9 146.02,63.19 146.02,66.63 v1(146.58,67.2)
  BOTTOM w0.076: UC1.AU47 101.5,104.6 101.1,104.19 101.1,103.46 100.89,103.26 100.42,103.26 v1(100.39,103.23)
  BOTTOM w0.165: v1(146.58,67.2) 146.14,67.64 146.14,69.42 147.35,70.62 JDIMM2.83
DDR_B_MA13: length 96.5
  IN3 w0.084: 110.11,96.04 110.22,96.15 110.71,96.15 110.84,96.28 110.84,96.48 110.71,96.61 110.26,96.61 110.14,96.74 110.14,96.98 110.26,97.1 110.71,97.1 110.84,97.23 110.84,101.42 111.09,101.67 111.09,102.64 110.65,103.07 110.65,107.22 110.48,107.4 110.48,108.94 110.39,109.03 v1(110.09,109.03)
  IN3 w0.208: v1(158.96,68.72) 159.09,68.85 159.09,73.06 153.49,78.66 147.92,78.66 147.71,78.86 147.71,80.47 147.51,80.68 147.05,80.68 146.85,80.47 146.85,78.86 146.65,78.66 146.19,78.66 145.98,78.86 145.98,80.47 145.78,80.68 145.32,80.68 145.12,80.47 145.12,78.86 144.92,78.66 144.46,78.66 144.26,78.86 144.26,80.47 144.05,80.68 143.6,80.68 143.39,80.47 143.39,78.86 143.19,78.66 142.73,78.66 142.53,78.86 142.53,80.47 142.33,80.68 120.3,80.68 110.1,90.88 110.1,96.02 110.11,96.04
  BOTTOM w0.076: v1(110.09,109.03) 110.35,109.3 UC1.AK33
  BOTTOM w0.165: v1(158.96,68.72) 158.15,69.53 JDIMM2.119
DDR_B_MA14: length 93.1
  IN3 w0.084: 97.07,93.66 97.07,95 99.58,97.5 99.58,100.8 100.15,101.36 100.15,102.1 99.85,102.4 99.85,104.52 100.46,105.13 101.42,105.13 101.98,105.7 v1(101.98,105.85)
  IN3 w0.208: v1(145.78,60.74) 145.31,60.27 145.31,59.96 144.77,59.42 144.77,58.68 144.64,58.56 140.37,58.56 140.24,58.68 140.24,60.01 140.04,60.21 139.37,60.21 139.16,60.01 139.16,58.19 138.96,57.99 121.96,57.99 106.21,73.74 106.21,76.56 97.07,85.7 97.07,93.66
  BOTTOM w0.076: UC1.AR46 102.28,105.85 v1(101.98,105.85)
  BOTTOM w0.165: JDIMM2.80 146.45,61.41 v1(145.78,60.74)
DDR_B_MA15: length 93.7
  IN3 w0.084: 96.6,93.66 96.6,94.86 99.41,97.67 99.41,100.87 99.97,101.43 99.97,102.03 99.67,102.33 99.67,104.6 100.4,105.33 101.3,105.33 101.5,105.53 101.5,106.5 101.63,106.63 101.86,106.63 v1(101.98,106.5)
  IN3 w0.208: v1(145.78,59.21) 145.78,59.23 145.65,59.36 145.36,59.36 145.23,59.23 145.23,57.54 145.1,57.41 121.87,57.41 105.74,73.54 105.74,76.37 96.6,85.51 96.6,93.66
  BOTTOM w0.076: v1(101.98,106.5) 102.28,106.5 UC1.AP46
  BOTTOM w0.165: JDIMM2.78 145.85,62.2 145.32,61.67 145.32,59.68 v1(145.78,59.21)
DDR_B_RAS#: length 97.3
  IN3 w0.084: v1(109.16,107.64) 109.54,107.26 109.54,105.46 109.28,105.2 109.28,99.55 108.87,99.13 108.87,96.98 108.69,96.8 108.69,96.34
  IN3 w0.208: v1(156.04,60.74) 156.04,60.6 156.24,60.39 156.63,60.39 156.84,60.6 156.84,61.63 157.15,61.95 157.15,62.42 157.36,62.63 158.36,62.63 158.56,62.83 158.56,63.38 158.36,63.58 155.86,63.58 155.73,63.71 155.73,64.27 155.86,64.4 156.81,64.4 156.94,64.53 156.94,65.23 156.81,65.35 156.46,65.35 156.33,65.48 156.33,72.94 156.56,73.16 156.56,73.54 156.01,74.09 155.7,74.09 155.52,73.91 155.23,73.91 154.91,74.24 154.91,74.52 155.09,74.7 155.09,75.01 152.85,77.25 134.42,77.25 134.21,77.45 134.21,79.06 134.01,79.27 119.72,79.27 108.69,90.3 108.69,96.34
  BOTTOM w0.089: v1(109.16,107.64) 109.51,107.99 UC1.AM35
  BOTTOM w0.165: JDIMM2.110 155.45,61.32 v1(156.04,60.74)
DDR_B_WE#: length 95.8
  IN3 w0.084: 109.16,96.18 109.16,99.12 109.48,99.45 109.48,101.85 110.01,102.37 110.01,102.6 109.48,103.12 109.48,105.1 109.73,105.35 109.73,107.35 109.64,107.44 109.64,108.83 109.5,108.97 v1(109.13,108.97)
  IN3 w0.208: v1(157.43,67.2) 157.24,67.01 157,67.01 156.8,67.2 156.8,69.11 157.01,69.31 157.94,69.31 158.15,69.52 158.15,69.97 157.94,70.18 157.01,70.18 156.8,70.38 156.8,70.84 157.01,71.04 157.94,71.04 158.15,71.24 158.15,71.7 157.94,71.9 157.52,71.9 157.32,72.11 157.32,72.42 157.68,72.78 157.68,73.08 153.04,77.72 136.61,77.72 136.41,77.92 136.41,79.53 136.21,79.74 135.75,79.74 135.55,79.53 135.55,77.92 135.34,77.72 134.88,77.72 134.68,77.92 134.68,79.53 134.48,79.74 119.91,79.74 109.16,90.49 109.16,96.18
  BOTTOM w0.076: v1(109.13,108.97) 109.46,109.3 UC1.AK35
  BOTTOM w0.165: v1(157.43,67.2) 156.35,68.28 JDIMM2.113
DDR_CKE0_DIMMA: length 74.6
  IN1 w0.084: v1(103.56,104.58) 103.98,104.16 103.98,99.38 100.9,96.3 99.95,96.3 97.69,94.04 97.69,93.66
  IN1 w0.183: v1(65.15,68.68) 64.56,69.27 64.56,71.21 65.15,71.8 65.15,73.67 65.87,74.39 66.18,74.39 67.16,75.37 67.16,75.63 66.62,76.16 66.62,76.35 66.95,76.68 67.21,76.68 67.75,76.14 67.93,76.14 68.27,76.48 68.27,76.66 67.73,77.2 67.73,77.46 67.99,77.72 68.25,77.72 68.79,77.18 68.97,77.18 69.3,77.51 69.3,77.69 68.76,78.24 68.76,78.49 71.6,81.33 87.31,81.33 93.3,87.31 93.55,87.31 94.37,86.49 94.55,86.49 94.89,86.83 94.89,87.01 94.07,87.82 94.07,88.08 94.33,88.34 94.59,88.34 95.37,87.56 95.62,87.56 97.69,89.62 97.69,93.66
  BOTTOM w0.076: v1(103.56,104.58) 103.7,104.58 UC1.AU43
  BOTTOM w0.165: JDIMM1.73 65.8,69.33 v1(65.15,68.68)
DDR_CKE1_DIMMA: length 74.3
  IN1 w0.084: v1(103.54,103.28) 103.15,102.89 103.15,99.76 102.91,99.51 102.91,98.62 100.82,96.53 99.86,96.53 98.64,95.31 98.44,95.31 97.22,94.09 97.22,93.66
  IN1 w0.183: 97.22,93.66 97.22,89.81 96.38,88.97 94.21,88.97 87.02,81.79 71.4,81.79 65.84,76.22 65.84,75.01 64.61,73.78 64.61,72.2 64.1,71.69 64.1,67.79 64.89,67 64.89,63.99 66,62.88 66,61.15 v1(66.45,60.7)
  BOTTOM w0.076: UC1.AW43 103.86,103.58 103.56,103.28 v1(103.54,103.28)
  BOTTOM w0.165: v1(66.45,60.7) 66.01,61.14 66.01,61.71 66.1,61.8 JDIMM1.74
DDR_CKE2_DIMMB: length 83.2
  IN3 w0.084: v1(101.12,101.59) 101.57,101.15 101.57,100.09 101.06,99.58 101.06,96.47 100.8,96.21 100.8,94.37 100.3,93.86 100.3,93.66
  IN3 w0.208: v1(143.32,67.2) 142.64,67.2 142.51,67.07 142.51,64.69 142.38,64.57 141.44,64.57 141.32,64.69 141.32,65.41 141.19,65.54 140.43,65.54 139.93,65.05 135.83,65.05 135.35,64.57 132.4,64.57 131.92,65.05 131.55,65.05 131.07,64.57 130.63,64.57 130.15,65.05 129.65,65.05 129.16,64.57 128.89,64.57 128.41,65.05 127.98,65.05 127.5,64.57 127.05,64.57 126.57,65.05 120.44,65.05 119.96,64.57 119.72,64.57 119.27,65.02 119.27,65.2 119.29,65.2 119.74,65.66 119.74,65.85 119.31,66.28 119.13,66.28 118.66,65.81 118.48,65.81 113.38,70.92 113.38,71.34 114.45,72.41 114.45,72.67 100.3,86.82 100.3,93.66
  BOTTOM w0.076: UC1.AY49 100.8,101.91 v1(101.12,101.59)
  BOTTOM w0.165: JDIMM2.73 144.35,69.97 143.32,68.94 v1(143.32,67.2)
DDR_CKE3_DIMMB: length 85.3
  IN3 w0.084: v1(101.18,100.99) 100.89,100.69 100.89,96.81 99.28,95.2 99.28,94.06 99.67,93.66
  IN3 w0.208: 99.67,93.66 99.67,86.78 112.45,74.01 112.45,73.83 111.28,72.66 111.28,72.35 111.58,72.05 111.89,72.05 113.06,73.22 113.24,73.22 113.67,72.78 113.67,72.6 112.5,71.43 112.5,71.13 119.53,64.1 143.96,64.1 144.09,64.22 144.09,65.76 143.92,65.92 143.57,65.92 v1(143.32,65.67)
  BOTTOM w0.076: v1(101.18,100.99) 99.69,102.49 99.69,104.69 UC1.AU50
  BOTTOM w0.165: JDIMM2.74 144.65,64.34 v1(143.32,65.67)
DDR_CS0_DIMMA#: length 76.1
  IN1 w0.084: 111.8,94.57 111.8,95.38 111.79,95.39 ; 110.88,106.43 v1(110.1,106.43)
  IN1 w0.089: 110.88,106.43 111.58,105.73 111.58,95.6 111.79,95.39
  IN1 w0.183: v1(77.63,60.7) 78.84,61.91 98.95,61.91 104.74,67.69 104.74,70.78 106.1,72.14 106.1,73.75 111.8,79.44 111.8,94.57
  BOTTOM w0.089: v1(110.1,106.43) 110.11,106.43 110.37,106.69 UC1.AP33
  BOTTOM w0.165: v1(77.63,60.7) 78.1,61.17 JDIMM1.114
DDR_CS1_DIMMA#: length 77.1
  IN1 w0.084: 109.5,94.57 109.5,95.19 110.83,96.52 110.83,100.72 109.61,101.93 109.61,102.12
  IN1 w0.089: v1(111.06,105.72) 110.6,105.25 109.74,105.25 109.33,104.85 109.33,103.24 109.61,102.95 109.61,102.12
  IN1 w0.183: 109.5,94.57 109.5,80.33 103.4,74.24 103.4,72.78 100.86,70.24 100.86,67.01 99.51,65.66 97.37,65.66 97.19,65.47 97.19,64.84 97.01,64.65 96.64,64.65 96.46,64.84 96.46,65.47 96.27,65.66 94.26,65.66 94.08,65.47 94.08,64.76 93.95,64.63 93.47,64.63 93.35,64.76 93.35,65.47 93.16,65.66 91.34,65.66 91.15,65.47 91.15,64.76 91.03,64.63 90.55,64.63 90.42,64.76 90.42,65.47 90.24,65.66 82.31,65.66 81.63,66.34 81.63,67.07 81.51,67.19 v1(80.51,67.19)
  BOTTOM w0.076: UC1.AR32 111.39,106.04 v1(111.06,105.72)
  BOTTOM w0.165: v1(80.51,67.19) 81.22,67.91 81.22,69.41 80.2,70.43 JDIMM1.121
DDR_CS2_DIMMB#: length 90.5
  IN3 w0.084: v1(111.03,107.7) 111.04,107.7 111.63,107.11 111.63,101.38 111.29,101.03 111.29,96.04
  IN3 w0.208: v1(157.56,60.74) 160.28,63.46 160.28,73.56 153.98,79.86 150.02,79.86 148,81.87 120.8,81.87 111.29,91.38 111.29,96.04
  BOTTOM w0.089: UC1.AM32 111.32,107.99 v1(111.03,107.7)
  BOTTOM w0.165: v1(157.56,60.74) 156.65,61.65 JDIMM2.114
DDR_CS3_DIMMB#: length 90.3
  IN3 w0.084: v1(111.04,108.97) 110.85,109.16 110.77,109.16 110.65,109.05 110.65,107.47 110.8,107.33 111.17,107.33 111.44,107.05 111.44,105.39 110.84,104.79 110.84,103.36 111.44,102.75 111.44,101.46 111.03,101.04 111.03,96.02 110.77,95.77 110.52,95.77 110.4,95.65 110.4,95.19
  IN3 w0.208: v1(158.96,67.2) 159.27,66.88 159.68,66.88 159.81,67.01 159.81,67.43 159.42,67.82 159.42,68.16 159.81,68.55 159.81,73.36 153.79,79.39 148.75,79.39 148.44,79.7 148.44,80.77 147.81,81.4 120.6,81.4 110.82,91.18 110.82,94.77 110.4,95.19
  BOTTOM w0.076: v1(111.04,108.97) 111.36,109.3 UC1.AK32
  BOTTOM w0.165: JDIMM2.121 158.75,70.33 158.94,70.15 158.94,69.7 159.6,69.03 159.6,67.85 v1(158.96,67.2)
DDR_PG_CTRL: length 91.1
  TOP w0.102: U2303.2 44.12,66.67 43.84,66.94 43.34,66.94 41.94,65.54 39.97,65.54 38.89,66.62 v3(38.89,71.23) 38.89,71.77 v1(39.78,72.65)
  BOTTOM w0.076: 91.12,104.56 92.15,104.56 92.16,104.57 92.44,104.57 92.5,104.51 UC1.AV61
  BOTTOM w0.089: 88.55,101.99 88.23,101.67 88.23,99.65
  BOTTOM w0.102: 91.12,104.56 88.55,101.99 ; 88.23,99.65 88.23,84.21 86.01,81.99 55.97,81.99 48.86,74.88 40.16,74.88 39.78,74.5 v1(39.78,72.65)
DDR_XDP_SMBCLK_R1: length 2.9
  BOTTOM w0.102: JXDP1.53 60.2,92.15 60.29,92.06 60.29,91.2 60.1,91 RP46.7
DDR_XDP_SMBDAT_R1: length 2.9
  BOTTOM w0.102: JXDP1.51 60.7,92.15 60.49,91.94 60.49,91.17 60.6,91.07 RP46.8
DDR_XDP_WLAN_TP_SMBCLK: length 442.5
  TOP w0.102: JTP.5 70.35,112.52 v1(70.36,112.53) ; v1(146.46,110.56) 147.8,110.56 149.95,112.71 149.95,115.62 149.45,116.12 149.45,117.68 145.77,121.36 145.77,124.8 146.83,125.86 146.83,128.55 151.36,133.07 151.36,134.19 v1(151.07,134.48) v3(150.51,133.92) 148.77,133.92 148.44,134.25 137.69,134.25 135.63,136.31 129.1,136.31 126.97,138.44 126.97,145.17 v1(123.03,149.11)
  IN2 w0.127: v1(146.46,110.56) 146.65,110.37 146.65,107.03 145.25,105.63 145.25,74.45 144.05,73.25 144.05,62.98 144.62,62.41 144.62,52.16 v1(144.87,51.9)
  IN3 w0.127: v1(186.33,62.12) 185.87,61.65 185.87,61.36 186.14,61.08 186.76,61.08 187.79,60.05 187.79,57.21 187.24,56.66 184.58,56.66 183.38,55.47 181.77,55.47 180.7,54.4 179.09,54.4 177.34,52.65 176.83,52.65 176.37,52.2 171.43,52.2 171.18,51.94 163.21,51.94 163,51.74 145.04,51.74 v1(144.87,51.9) 144.45,52.33 117.32,52.33 116.61,53.04 105.58,53.04 103.94,51.4 v1(103.27,51.4) 103.27,51.5 102.94,51.83 73.71,51.83 69.34,56.19 69.34,73.15 64.59,77.91 64.59,85.67 v1(64.01,86.24) 64.01,86.33 63.31,87.04 63.31,91.65 63.9,92.24 63.9,95.86 64.87,96.83 64.87,98.19 63.44,99.62 63.44,108.57 67.4,112.53 v1(70.36,112.53) ; v1(151.07,134.48) 151.69,134.48 158.63,141.41 158.63,152.17 160.39,153.94 160.39,158.02 161.61,159.24 188.8,159.24 190.92,161.36 198.66,161.36 199.14,161.85 199.14,162.39 v1(199.27,162.52)
  BOTTOM w0.102: R2332.2 146.97,110.06 v1(146.46,110.56) 144.87,110.56 144.74,110.43 QC1.1 ; RP46.2 60.1,86.25 60.54,85.8 63.57,85.8 v1(64.01,86.24) ; JDIMM1.202 104.5,62.13 104.3,61.93 104.3,58.12 103.27,57.08 v1(103.27,51.4) ; v1(186.33,62.12) 185.44,61.22 183.67,61.22 183.05,61.85 JDIMM2.202 ; JMINI.30 108.1,146.83 109.4,145.53 120.42,145.53 123.03,148.13 v1(123.03,149.11) ; v1(199.27,162.52) 199.33,162.58 RX6.1
DDR_XDP_WLAN_TP_SMBDAT: length 446.6
  TOP w0.102: v1(70.94,113) 71.35,112.59 JTP.6 ; v1(146.21,107.52) 146.78,108.09 151.25,108.09 151.64,108.48 151.64,114.25 v3(150.79,115.11) 149.68,116.21 149.68,117.77 146,121.45 146,124.71 147.06,125.77 147.06,128.45 151.59,132.98 151.59,134.68 151.29,134.99 150.82,134.99 v1(150.42,134.59) 150.03,134.2 148.87,134.2 148.59,134.48 137.79,134.48 135.73,136.54 129.19,136.54 127.19,138.54 127.19,145.27 123.47,148.99 123.47,149.3 v1(123.03,149.74)
  IN2 w0.127: v1(144.11,51.91) 144.36,52.16 144.36,62.3 143.79,62.88 143.79,73.35 145,74.56 145,105.74 146.21,106.94 v1(146.21,107.52)
  IN3 w0.127: v1(70.94,113) 66.62,113 63.19,109.57 63.19,99.51 64.61,98.09 64.61,96.94 63.64,95.97 63.64,92.35 63.05,91.76 63.05,86.62 v1(63.43,86.24) 63.43,86.15 64.32,85.25 64.32,77.8 69.08,73.04 69.08,56.09 73.77,51.4 v1(102.67,51.4) 102.67,51.35 103.06,50.96 103.93,50.96 105.59,52.63 116.66,52.63 117.3,51.99 139.59,51.99 140.1,51.48 143.69,51.48 v1(144.11,51.91) 144.54,51.48 163.11,51.48 163.31,51.69 171.29,51.69 171.54,51.94 176.48,51.94 176.94,52.4 177.45,52.4 179.19,54.14 180.81,54.14 181.87,55.21 183.49,55.21 184.68,56.4 187.35,56.4 188.05,57.1 188.05,60.36 186.91,61.51 v1(186.32,61.51) ; v1(150.42,134.59) 150.8,134.97 151.83,134.97 158.37,141.52 158.37,152.28 160.14,154.04 160.14,158.13 161.51,159.5 188.7,159.5 190.82,161.62 198.55,161.62 198.89,161.95 198.89,162.25 198.63,162.51 v1(198.63,162.52)
  BOTTOM w0.102: RP46.1 60.6,88.47 60.35,88.22 60.35,86.63 60.74,86.24 v1(63.43,86.24) ; JDIMM1.200 103.9,62.15 104.07,61.97 104.07,58.22 102.67,56.82 v1(102.67,51.4) ; R2331.2 146.47,107.52 v1(146.21,107.52) 146.04,107.68 QC1.4 ; v1(186.32,61.51) 185.72,60.91 183.62,60.91 182.45,62.08 JDIMM2.200 ; RX31.1 198.45,162.7 v1(198.63,162.52) ; JMINI.32 108.9,146.6 109.74,145.76 119.04,145.76 v1(123.03,149.74)
DGPU_HOLD_RST#: length 41.4
  TOP w0.089: RC77.2 128.68,118.43 v1(128.68,117.93)
  IN1 w0.084: v1(128.68,117.93) 128.68,117.93 128.68,117.99 129.44,118.76 131.07,118.76 131.9,119.59 135.04,119.59 136.29,120.84 137.3,120.84
  IN1 w0.127: 137.3,120.84 143.49,120.84 148.69,115.64 148.69,113.72 149.57,112.85 150.13,112.85 152.67,110.31 v1(153.1,110.31)
  IN3 w0.127: v1(153.1,110.31) 155.29,110.31 156.75,108.85 158.38,108.85 v1(158.82,108.41)
  BOTTOM w0.089: v1(128.68,117.93) 128.61,118 128.33,118.28 UC1.N4
  BOTTOM w0.102: UV13.1 158.38,109.09 158.31,109.02 158.31,108.75 158.65,108.41 v1(158.82,108.41) 159.2,108.41 v3(159.6,108)
DGPU_PRSNT#: length 13.4
  TOP w0.089: v3(135.76,117.78) 135.66,117.68 v1(135.22,117.68) 135.08,117.54 RC100.2 134.37,115.89 RC99.1
  IN3 w0.084: v1(135.22,117.68) 134.74,118.16 130.56,118.16 129.95,117.55 128.11,117.55 127.92,117.36 126.44,117.36 v1(126.02,117.78)
  BOTTOM w0.089: v1(126.02,117.78) 126.34,117.45 UC1.R7
DGPU_PWROK: length 169.5
  TOP w0.102: v1(190.33,37.59) 189.92,37.19 189.92,36.78 189.99,36.71 UE1.18
  IN1 w0.127: v1(209.77,43.86) 208.99,44.64 v1(208.99,53.55) ; v1(190.33,37.59) 192.17,39.43 192.17,44.27 191.83,44.6 191.83,47.32 192.16,47.65 192.16,50.3 191.72,50.74 191.72,54.01 190.99,54.74 190.99,56.53 190.12,57.4 190.12,64.44 189.04,65.52 189.04,75.55 182.59,82 178.57,82 174.23,86.35 167.53,86.35 165.32,88.56 165.32,91.24 154.21,102.35 154.21,104.18 153.14,105.25 153.14,108.05 149.6,111.58 149.04,111.58 147.39,113.24 147.39,113.79 143.59,117.59 143.59,118.59 143.27,118.91 140.66,118.91 138.47,116.72 v1(136.81,116.72)
  IN3 w0.084: v1(126.52,115.9) 126.63,115.9 127.09,116.36 127.47,116.36 127.55,116.43 128.07,116.43 128.48,116.03 130.52,116.03 132,117.5 133.62,117.5 134.17,116.95 136.58,116.95 v1(136.81,116.72)
  BOTTOM w0.089: UC1.U6 126.99,116.37 v1(126.52,115.9) ; RC73.2 137.13,117.04 v1(136.81,116.72)
  BOTTOM w0.102: v1(190.33,37.59) 190.33,38.82 v3(191.08,39.57) 195.61,44.1 202.29,44.1 202.88,43.52 209.43,43.52 v1(209.77,43.86)
  BOTTOM w0.203: 206.66,54.44 206.19,54.91 PU800.2
  BOTTOM w0.254: 206.66,54.44 208.44,54.44 208.64,54.24 PR808.2 v1(208.99,53.55)
DH_1.35V: length 4.7
  TOP w1.016: 154.78,23.39 153.38,21.99 153.38,19.31
  vias: v2(153.13,18.37) v2(153.77,18.37) v2(155.74,23.77) v2(156.12,24.28) v3(155.28,24.3)
DH_CHG: length 15.7
  TOP w0.102: v3(145.95,170.62) 145.99,170.58 145.99,169.95
  IN1 w1.016: 152.56,169.24 152.94,169.62 163.8,169.62 ; 146.84,169.24 150.46,169.24
  vias: v1(145.22,169.5) v1(145.22,168.87) v1(151.54,169.56) v1(151.54,168.92) v1(164.74,169.3) v1(165.32,169.3)
DISPOFF#: length 8.9
  BOTTOM w0.102: DX1.1 219.42,166.62 RX9.1 v3(219.82,168.54) 219.82,169.32 220.31,169.82 220.94,171.39 222.45,172.9 JLVDS.37
DL_1.35V: length 8
  IN3 w1.016: 157.52,20.03 157.52,13.35 157.06,12.9
  BOTTOM w0.102: v2(157.45,21.8) 157.45,21.14 v3(157.49,21.1)
  vias: v1(156.73,11.92) v1(157.32,11.92) v2(157.45,22.44)
DL_CHG: length 5.4
  TOP w1.016: 166.14,173.18 165.26,174.06 164.05,174.06 162.97,175.14 161.57,175.14
  vias: v3(160.96,175.49)
DPB_HPD: length 202.3
  IN2 w0.089: 120.67,93.61 123.91,96.85 124.68,96.85 128.24,100.4 129.83,100.4 130.11,100.68 130.11,102.15 129.74,102.52 129.74,111.34 129.87,111.47 129.87,113.79 130.41,114.33 132.73,114.33 133.19,114.79 133.19,115.19 131.6,116.79 131.6,117.67 130.08,119.19 130.08,125.04 v1(127.28,127.84)
  IN2 w0.127: v1(32.35,93.1) 33.94,91.51 38.26,91.51 42.57,87.2 42.57,76.15 43.65,75.07 47.67,75.07 58.15,85.55 112.6,85.55 120.67,93.61
  BOTTOM w0.076: UC1.C8 125.87,124.49 125.87,125.04 126.03,125.2 126.03,125.92 126.27,126.16 126.43,126.16 127.28,127.01 v1(127.28,127.84)
  BOTTOM w0.102: v1(32.35,93.1) 32.35,95.26 v3(34.15,97.06) 37.3,100.21 37.3,113.42 35.53,115.2 29.11,115.2 28.72,114.81 19.65,114.81 RX14.1 18.55,115.26 18.51,115.22 QX5.3
DPC_HPD: length 10.2
  BOTTOM w0.076: UC1.A8 125.74,125.86 126.91,127.04 126.91,128.31 128.04,129.44 128.04,130.53 128.06,130.55 128.06,131.2
  BOTTOM w0.102: RC84.2 130.13,133.26 v3(129.68,132.81) 128.06,131.2
DPLL_PVSS: length 3.8
  TOP w0.254: v1(169.68,108.28) 169.68,108.37 169.14,108.91 v3(168.91,108.91) 168.44,108.91 RV247.2 167.94,108.39 RV248.2
  BOTTOM w0.254: UV1.AN32 169.27,108.69 v1(169.68,108.28)
DQA0_0: length 15.5
  TOP w0.102: v1(166.59,132.66) 166.21,133.04 166.21,134.83 165.65,135.39 ; UV5.U11 161.88,144.45
  TOP w0.127: 161.88,144.45 161.62,144.18 161.28,143.84 161.28,139.76 v3(164.09,136.95) 165.65,135.39
  BOTTOM w0.102: v1(166.59,132.66) 166.22,132.29 UV1.C37
DQA0_1: length 18.3
  TOP w0.102: 165.11,135.39 165.26,135.24 v3(165.26,134.68) 165.26,133.3 166.59,131.96 v1(166.59,131.84) ; UV5.T11 162.68,145.25
  TOP w0.127: 162.68,145.25 161.86,145.25 160.79,144.18 160.79,139.7 165.11,135.39
  BOTTOM w0.127: v1(166.59,131.84) 166.97,132.22 166.97,132.3 UV1.C35
DQA0_2: length 12.7
  TOP w0.102: 166.19,135.39 166.59,134.99 v3(166.59,134.31) v1(166.59,133.42)
  TOP w0.127: 166.19,135.39 161.66,139.92 161.66,142.68 162.22,143.25 UV5.U13
  BOTTOM w0.102: UV1.A35 166.92,133.09 v1(166.59,133.42)
DQA0_3: length 15
  TOP w0.127: v1(167.41,132.54) 167.41,132.66 167.03,133.04 167.03,135.08 v3(163.52,138.6) 162.68,139.43 162.68,140.92 161.89,141.72 161.89,142.59 162.14,142.85 162.68,142.85 UV5.T13
  BOTTOM w0.127: v1(167.41,132.54) 167.41,131.94 UV1.E34
DQA0_4: length 18
  TOP w0.102: UV5.M11 166.28,144.85 166.68,144.45 ; v1(169.66,130.4) 170.14,130.87 170.14,133.23 169.64,133.73 169.64,134.06 169.95,134.38 v3(169.95,134.99) 169.95,135.39
  TOP w0.127: 169.95,135.39 169.95,135.39 166.72,138.63 166.72,139.48 167.48,140.24 167.48,143.45 167.28,143.65 167.01,143.65 166.68,143.97 166.68,144.45
  BOTTOM w0.102: v1(169.66,130.4) 169.26,130 UV1.G32
DQA0_5: length 17
  TOP w0.102: UV5.N11 165.08,144.45 ; 168.34,135.39 168.94,134.79 168.94,133.57 169.53,132.98 169.53,131.74 169.3,131.52 168.5,131.52 v1(168.39,131.41)
  TOP w0.127: 168.34,135.39 v3(166.42,137.31) 165.08,138.65 165.08,144.45
  BOTTOM w0.102: UV1.D33 168.66,131.68 v1(168.39,131.41)
DQA0_6: length 14.8
  TOP w0.102: 166.68,142.85 166.28,143.25 UV5.M13 ; v1(169.64,131.01) 169.93,131.31 169.93,133.15 169.38,133.7 169.38,134.31 169.52,134.45 169.52,135.29 169.42,135.39
  TOP w0.127: 166.68,142.85 166.68,140.21 166.27,139.79 166.27,138.54 v3(168.06,136.75) 169.42,135.39
  BOTTOM w0.102: UV1.F32 169.32,130.69 v1(169.64,131.01)
DQA0_7: length 15
  TOP w0.102: 168.88,135.39 169.14,135.13 169.14,133.65 169.73,133.06 169.73,131.66 169.19,131.12 v1(168.97,131.12) ; 165.88,142.85 165.48,143.25 UV5.N13
  TOP w0.127: 165.88,142.85 v3(165.88,138.71) 165.88,138.39 168.88,135.39
  BOTTOM w0.102: UV1.E32 169.35,131.49 v1(168.97,131.12)
DQA0_8: length 42.8
  BOTTOM w0.102: 168.79,133.82 169.19,133.42 169.57,133.42 169.77,133.22 169.77,132.96 169.75,132.95 169.75,132.4 UV1.D31
  BOTTOM w0.127: 168.79,133.82 166.02,133.82 165.9,133.93 165.45,133.93 162.97,136.41 160.46,136.41 158.38,138.49 v3(158.38,151.67) 158.38,152.69 160.83,155.14 165.4,155.14 166.74,153.81 166.74,150.9 UV4.F4
DQA0_9: length 40.5
  BOTTOM w0.102: UV1.F30 170.86,130.99 170.59,131.27 170.59,132.04 170.34,132.29 170.18,132.29 169.95,132.52 169.95,132.86 169.97,132.88 169.97,133.3 169.12,134.15 165.77,134.15 164.53,135.39
  BOTTOM w0.127: UV4.F2 165.94,152.4 165.94,153.57 164.75,154.76 161,154.76 158.91,152.66 v3(158.91,149.69) 158.91,138.5 160.56,136.85 163.06,136.85 164.53,135.39
DQA0_10: length 37.6
  BOTTOM w0.102: UV1.C30 170.59,132.76 170.59,133.91
  BOTTOM w0.127: UV4.E2 165.08,152.46 165.08,153.76 164.45,154.38 161.26,154.38 159.29,152.41 v3(159.29,147.78) 159.29,138.69 160.62,137.36 163.1,137.36 166.09,134.36 170.14,134.36 170.59,133.91
DQA0_11: length 36.5
  BOTTOM w0.127: UV1.A30 170.84,133.32 170.84,134.13 170.37,134.59 166.46,134.59 162.97,138.08 160.88,138.08 159.81,139.15 159.81,152.11 v3(160.34,152.64) 161.7,154 163.99,154 164.29,153.7 164.29,152.68 164.56,152.41 164.8,152.41 165.07,152.14 165.07,150.87 UV4.E4
DQA0_12: length 30.3
  BOTTOM w0.102: UV1.F28 172.22,130.93 172.22,132.33 172.37,132.48 172.37,132.9 172.18,133.09 172.18,133.89 171.42,134.66
  BOTTOM w0.127: 171.42,134.66 171.42,134.87 170.45,135.84 167.77,135.84 164.38,139.22 v3(162.13,139.22) 161.65,139.22 160.96,139.91 160.96,151.22 161.42,151.69 161.93,151.69 UV4.A2
DQA0_13: length 27.5
  BOTTOM w0.102: UV1.C28 172.66,132.66 172.97,132.96 172.97,133.22 172.66,133.53 172.66,134.23 172.18,134.71
  BOTTOM w0.127: UV4.A4 161.9,150.45 161.72,150.27 161.72,140.23 161.96,139.99 162.3,139.99 162.43,140.11 162.43,140.49 162.55,140.62 162.81,140.62 162.93,140.49 162.93,140.11 163.06,139.99 164.69,139.99 v3(167.59,137.1) 168.08,136.6 170.77,136.6 172.18,135.19 172.18,134.71
DQA0_14: length 27.9
  BOTTOM w0.127: UV4.B2 162.65,151.62 162.65,151.08 162.4,150.82 161.83,150.82 161.34,150.33 161.34,140.07 161.8,139.61 164.54,139.61 v3(165.1,139.04) 167.92,136.22 170.61,136.22 171.8,135.03 171.8,134.77 172.44,134.12 172.44,133.31 UV1.A28
DQA0_15: length 28.4
  BOTTOM w0.102: 172.56,134.69 172.56,134.63 172.86,134.33 172.86,133.61 173.17,133.3 173.17,132.88 172.97,132.68 172.97,131.8 UV1.E28
  BOTTOM w0.127: 172.56,134.69 172.56,135.35 170.93,136.98 v3(169.48,136.98) 168.24,136.98 164.85,140.37 164.52,140.37 164.4,140.49 164.4,140.85 164.27,140.98 164.02,140.98 163.89,140.85 163.89,140.49 163.76,140.37 163.44,140.37 163.32,140.49 163.32,140.87 163.19,141 162.46,141 161.95,141.5 161.95,149.86 162.14,150.06 162.7,150.06 UV4.B4
DQA0_16: length 24
  TOP w0.127: UV5.B2 174.72,151.61 175.22,151.61 175.53,151.3 176,151.3 176.17,151.13 176.17,150.3 176.3,150.17 176.3,149.09 177.27,148.13 177.27,139.91 173.64,136.27 v3(173.64,135.53) 173.64,134.97 v1(173.19,134.52)
  BOTTOM w0.102: v1(173.19,134.52) 173.75,133.96 173.75,132.83 173.77,132.82 173.77,132.56 173.76,132.56 173.76,132.19 UV1.D27
DQA0_17: length 24.9
  TOP w0.127: v1(173.51,131.33) 174.15,131.97 v3(174.15,133.75) 174.15,136.24 177.65,139.75 177.65,148.28 176.69,149.25 176.69,150.32 176.55,150.46 176.55,151.42 176.2,151.77 175.57,151.77 175.29,152.05 UV5.A2
  BOTTOM w0.102: UV1.F26 174.06,130.78 v1(173.51,131.33)
DQA0_18: length 21.8
  TOP w0.127: UV5.B4 174.66,150.08 175.18,150.08 175.5,149.76 175.5,148.82 176.51,147.81 176.51,141.09 174.76,139.33 v3(174.76,138.95) 174.76,138.5 172.69,136.43 172.69,135.39 172.88,135.2 v1(173.19,135.2)
  BOTTOM w0.102: v1(173.19,135.2) 173.96,134.44 173.96,132.9 174.26,132.59 UV1.C26
DQA0_19: length 21.5
  TOP w0.127: v1(173.19,135.84) 173.19,136.37 v3(173.98,137.15) 176.14,139.31 176.14,139.49 175.89,139.75 175.89,139.93 176.07,140.11 176.25,140.11 176.5,139.85 176.68,139.85 176.86,140.03 176.86,140.21 176.61,140.46 176.61,140.64 176.89,140.93 176.89,147.97 175.92,148.94 175.92,150.01 175.48,150.45 UV5.A4
  BOTTOM w0.127: v1(173.19,135.84) 173.19,135.79 174.19,134.79 174.19,133.16 UV1.A26
DQA0_20: length 38.5
  TOP w0.127: UV5.F4 170.64,150.9 170.64,153.52 170.82,153.71 170.82,154.02 172.22,155.42 176.87,155.42 179.94,152.36 v3(179.94,137.38) 175.29,132.73 v1(175.29,131.35)
  BOTTOM w0.102: v1(175.29,131.35) 175.66,130.98 UV1.F24
DQA0_21: length 32.4
  TOP w0.102: v1(175.16,135.01) 175.54,135.39
  TOP w0.127: 175.54,135.39 v3(175.95,135.8) 178.8,138.65 178.8,151.88 176.64,154.04 173.47,154.04 173.14,153.71 173.14,152.71 172.88,152.45 172.59,152.45 172.34,152.2 172.34,150.9 UV5.E4
  BOTTOM w0.102: v1(175.16,135.01) 175.16,135.08 176.17,134.07 176.17,132.94 175.86,132.64 UV1.C24
DQA0_22: length 31.3
  TOP w0.127: v1(175.17,134.43) 175.35,134.43 v3(177.84,136.92) 179.18,138.27 179.18,152.04 176.64,154.57 173.05,154.57 172.32,153.85 172.32,152.62 171.89,152.18 UV5.E2
  BOTTOM w0.127: UV1.A24 175.86,134.02 175.45,134.43 v1(175.17,134.43)
DQA0_23: length 34.9
  TOP w0.127: UV5.F2 171.51,152.48 171.51,154.17 172.38,155.04 176.71,155.04 v3(178.69,153.07) 179.56,152.2 179.56,137.82 175.58,133.84 v1(175.19,133.84)
  BOTTOM w0.102: v1(175.19,133.84) 175.57,133.46 175.57,133.23 175.56,133.22 175.56,131.8 UV1.E24
DQA0_24: length 15.8
  BOTTOM w0.102: 176.82,133.99 177.13,133.68 177.13,132.92 177.46,132.58 UV1.C22 ; UV4.M11 171.08,144.85 170.69,144.45
  BOTTOM w0.127: 170.69,144.45 170.69,141.12 v3(171.18,140.63) 171.47,140.33 171.94,140.33 175.54,136.73 175.54,135.27 176.82,133.99
DQA0_25: length 13
  BOTTOM w0.127: UV1.A22 177.46,133.79 175.96,135.29 175.96,136.85 v3(175.62,137.19) 172.1,140.71 171.73,140.71 171.48,140.96 171.48,142.85 UV4.M13
DQA0_26: length 15.2
  BOTTOM w0.102: UV1.F22 177.77,131.2 177.77,132.47 177.75,132.48 177.75,132.9 177.77,132.91 177.77,132.96 177.77,132.96 177.77,133.42 177.71,133.48 177.71,133.93 177.7,133.93
  BOTTOM w0.127: UV4.N13 171.89,142.99 172.28,142.59 172.28,141.07 v3(172.98,140.37) 176.4,136.95 176.4,135.23 177.7,133.93
DQA0_27: length 15.7
  BOTTOM w0.102: 177.97,134.11 177.97,132.88 177.97,132.88 177.97,132.83 177.96,132.82 177.96,132.56 178.26,132.26 UV1.D21 ; UV4.N11 172.35,144.38 172.35,143.12 172.62,142.85 172.83,142.85 173.09,142.6 173.09,141.35
  BOTTOM w0.127: 173.09,141.35 173.09,140.8 v3(175.02,138.88) 176.94,136.95 176.94,135.14 177.97,134.11
DQA0_28: length 12.5
  BOTTOM w0.102: 179.2,134.7 178.66,135.24
  BOTTOM w0.127: UV1.A20 179.2,133.22 179.2,134.7 ; 178.66,135.24 178.08,135.81 178.08,137.43 v3(177.38,138.13) 175.5,140 175.5,142.54 175.23,142.82 174.91,142.82 174.48,143.25 UV4.T13
DQA0_29: length 14.9
  BOTTOM w0.102: 179.42,133.91 179.42,132.71 179.6,132.53 179.6,132.05 179.56,132.01 179.56,131.51 179.06,131.01 UV1.F20
  BOTTOM w0.127: UV4.U13 175.5,143.25 175.89,142.86 175.89,140.16 v3(176.6,139.45) 178.46,137.58 178.46,135.97 179.42,135.01 179.42,133.91
DQA0_30: length 15.7
  BOTTOM w0.102: 180.38,133.96 180.38,133.53 180.15,133.3 180.15,132.88 180.19,132.84 180.19,132.54 180.15,132.5 180.15,132.17 179.87,131.89 UV1.D19
  BOTTOM w0.127: UV4.U11 175.64,144.85 176.3,144.18 v3(176.3,140.81) 176.3,140.28 178.84,137.74 178.84,136.13 179.73,135.24 179.73,134.76 180.38,134.11 180.38,133.96
DQA0_31: length 18
  BOTTOM w0.102: 180.66,133.71 180.66,133.52 180.36,133.22 180.36,132.96 180.4,132.92 180.4,132.46 180.36,132.42 180.36,131.64 180.51,131.49 UV1.E18
  BOTTOM w0.127: UV4.T11 174.7,145.26 176.08,145.26 176.69,144.66 v3(176.69,143.49) 176.69,140.44 179.23,137.9 179.23,136.28 180.11,135.39 180.11,134.98 180.66,134.43 180.66,133.71
DQA1_0: length 15.3
  TOP w0.102: v1(180.98,131.9) 180.56,132.32 180.56,133.61 181.77,134.82 182.27,134.82 182.73,135.28 182.73,135.39 ; UV3.U11 182.39,144.38
  TOP w0.127: 182.39,144.38 182.17,144.16 182.17,137.93 182.73,137.36 v3(182.73,136.36) 182.73,135.39
  BOTTOM w0.102: v1(180.98,131.9) 180.66,132.22 UV1.C18
DQA1_1: length 12.9
  TOP w0.102: v1(180.98,132.66) 181.45,133.13 v3(181.45,133.84) 181.45,134.15 181.82,134.53 182.55,134.53 183.11,135.09 183.11,135.39
  TOP w0.127: 183.11,135.39 183.11,137.52 182.65,137.98 182.65,141.36 182.4,141.62 182.4,142.85 182.73,143.18 UV3.U13
  BOTTOM w0.102: v1(180.98,132.66) 180.66,132.98 UV1.A18
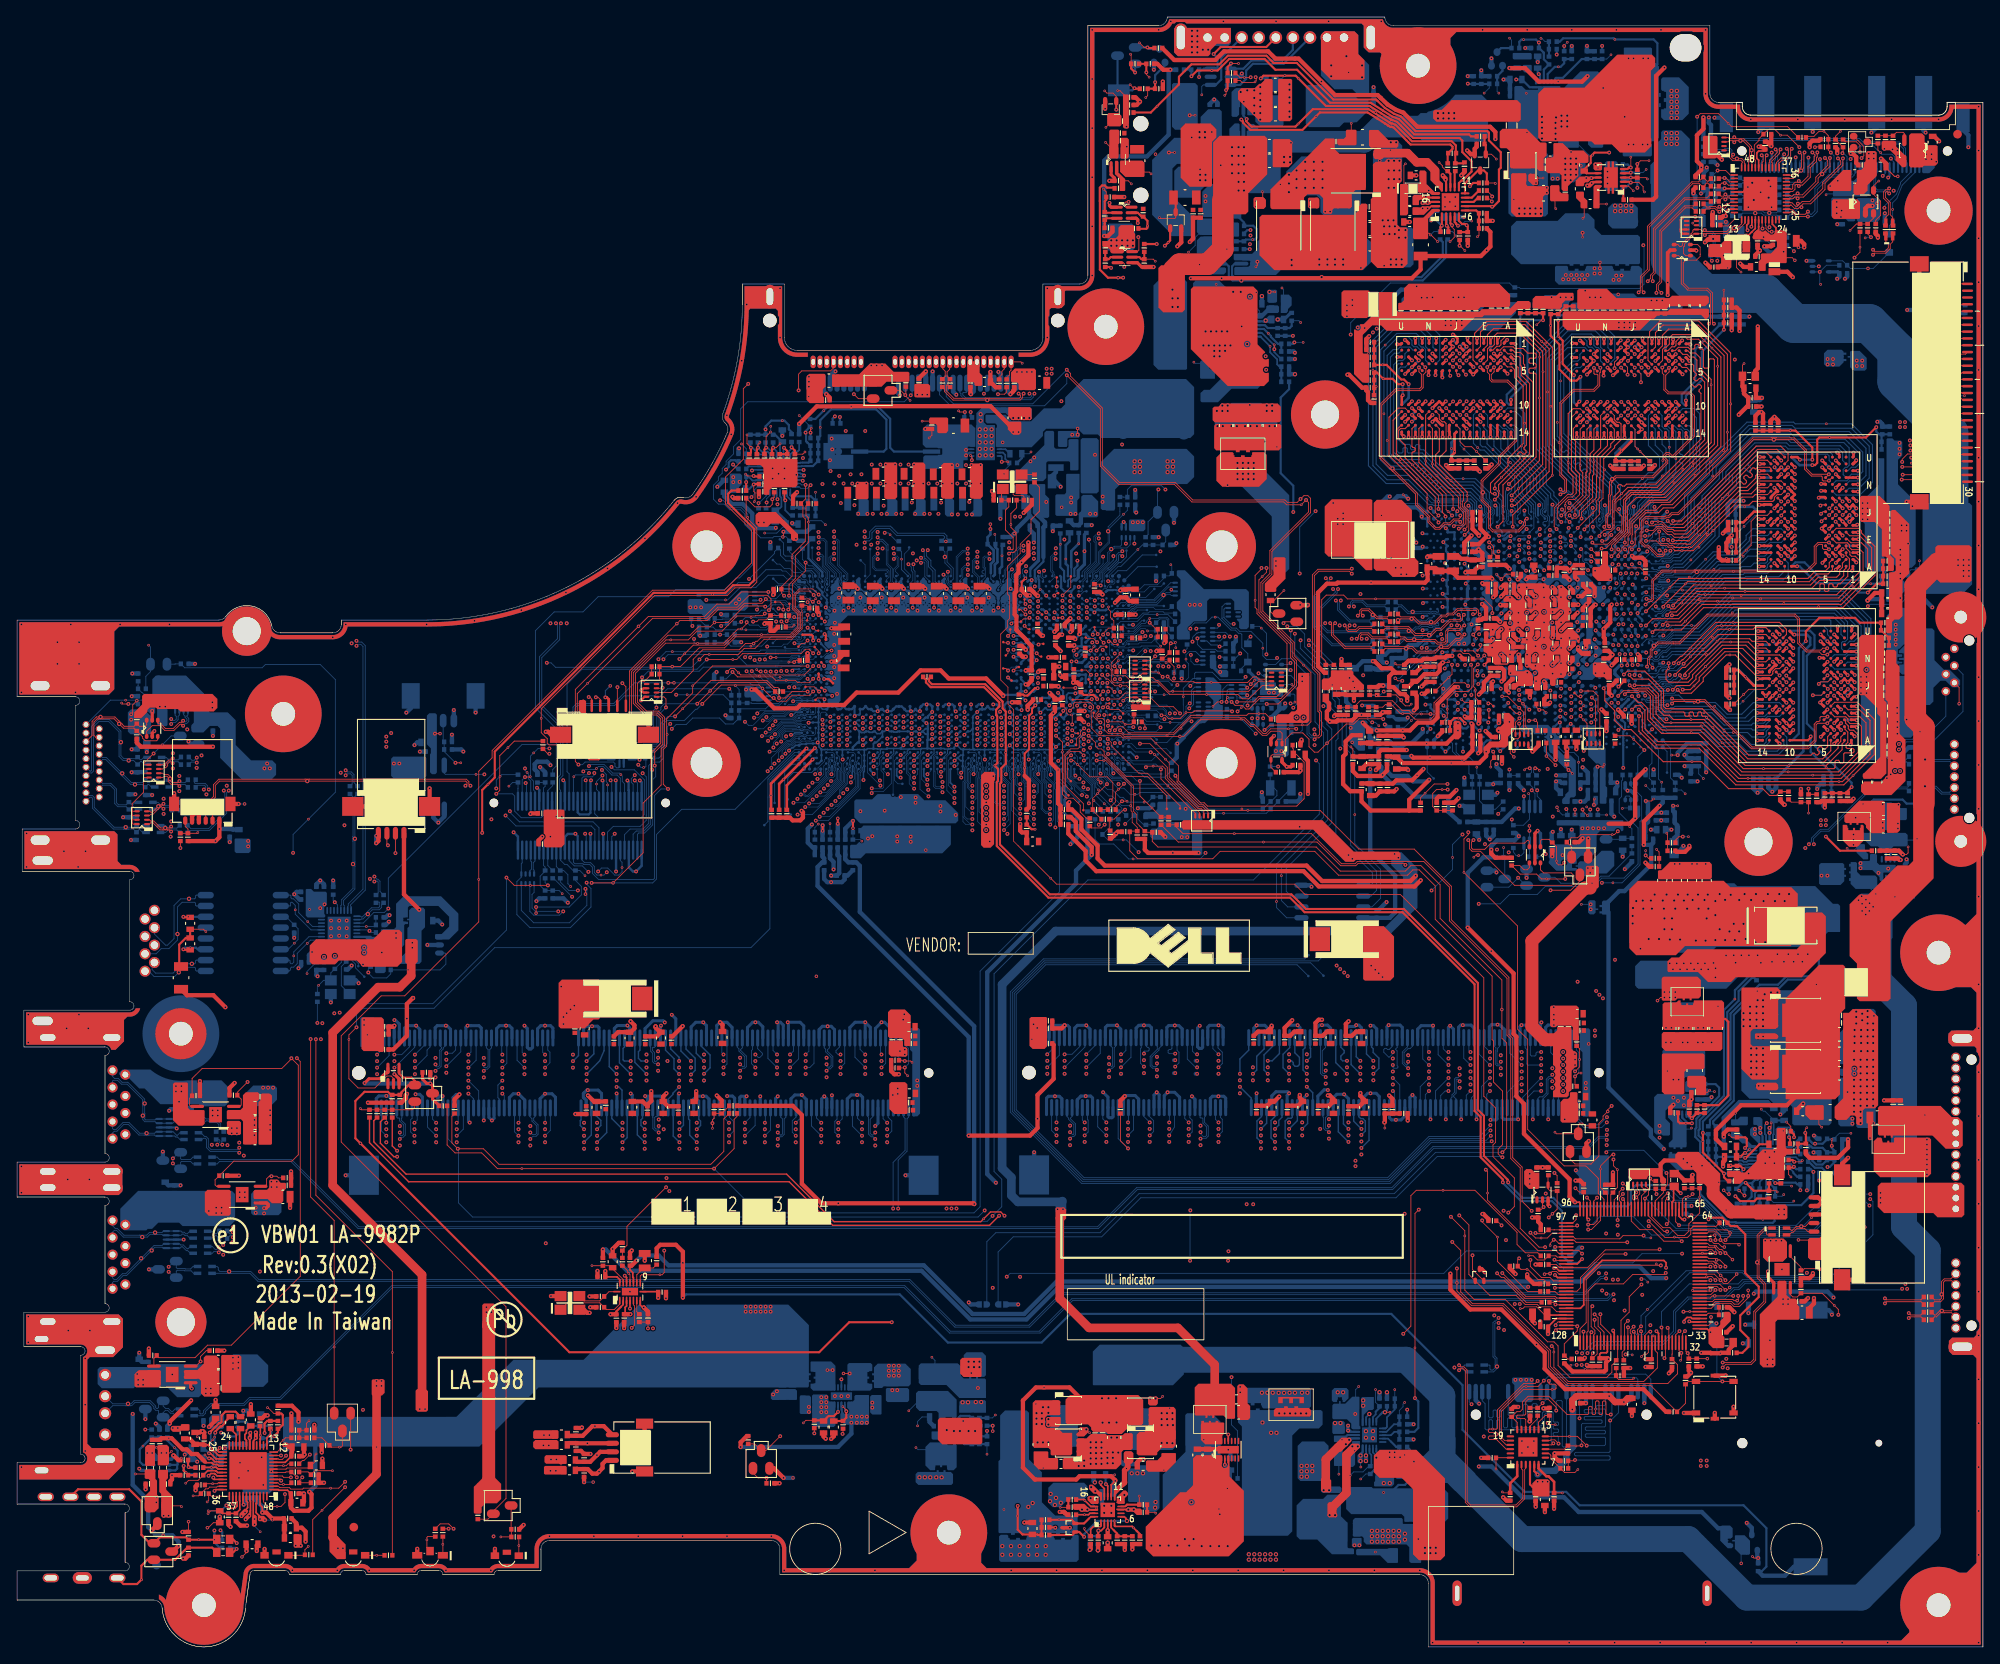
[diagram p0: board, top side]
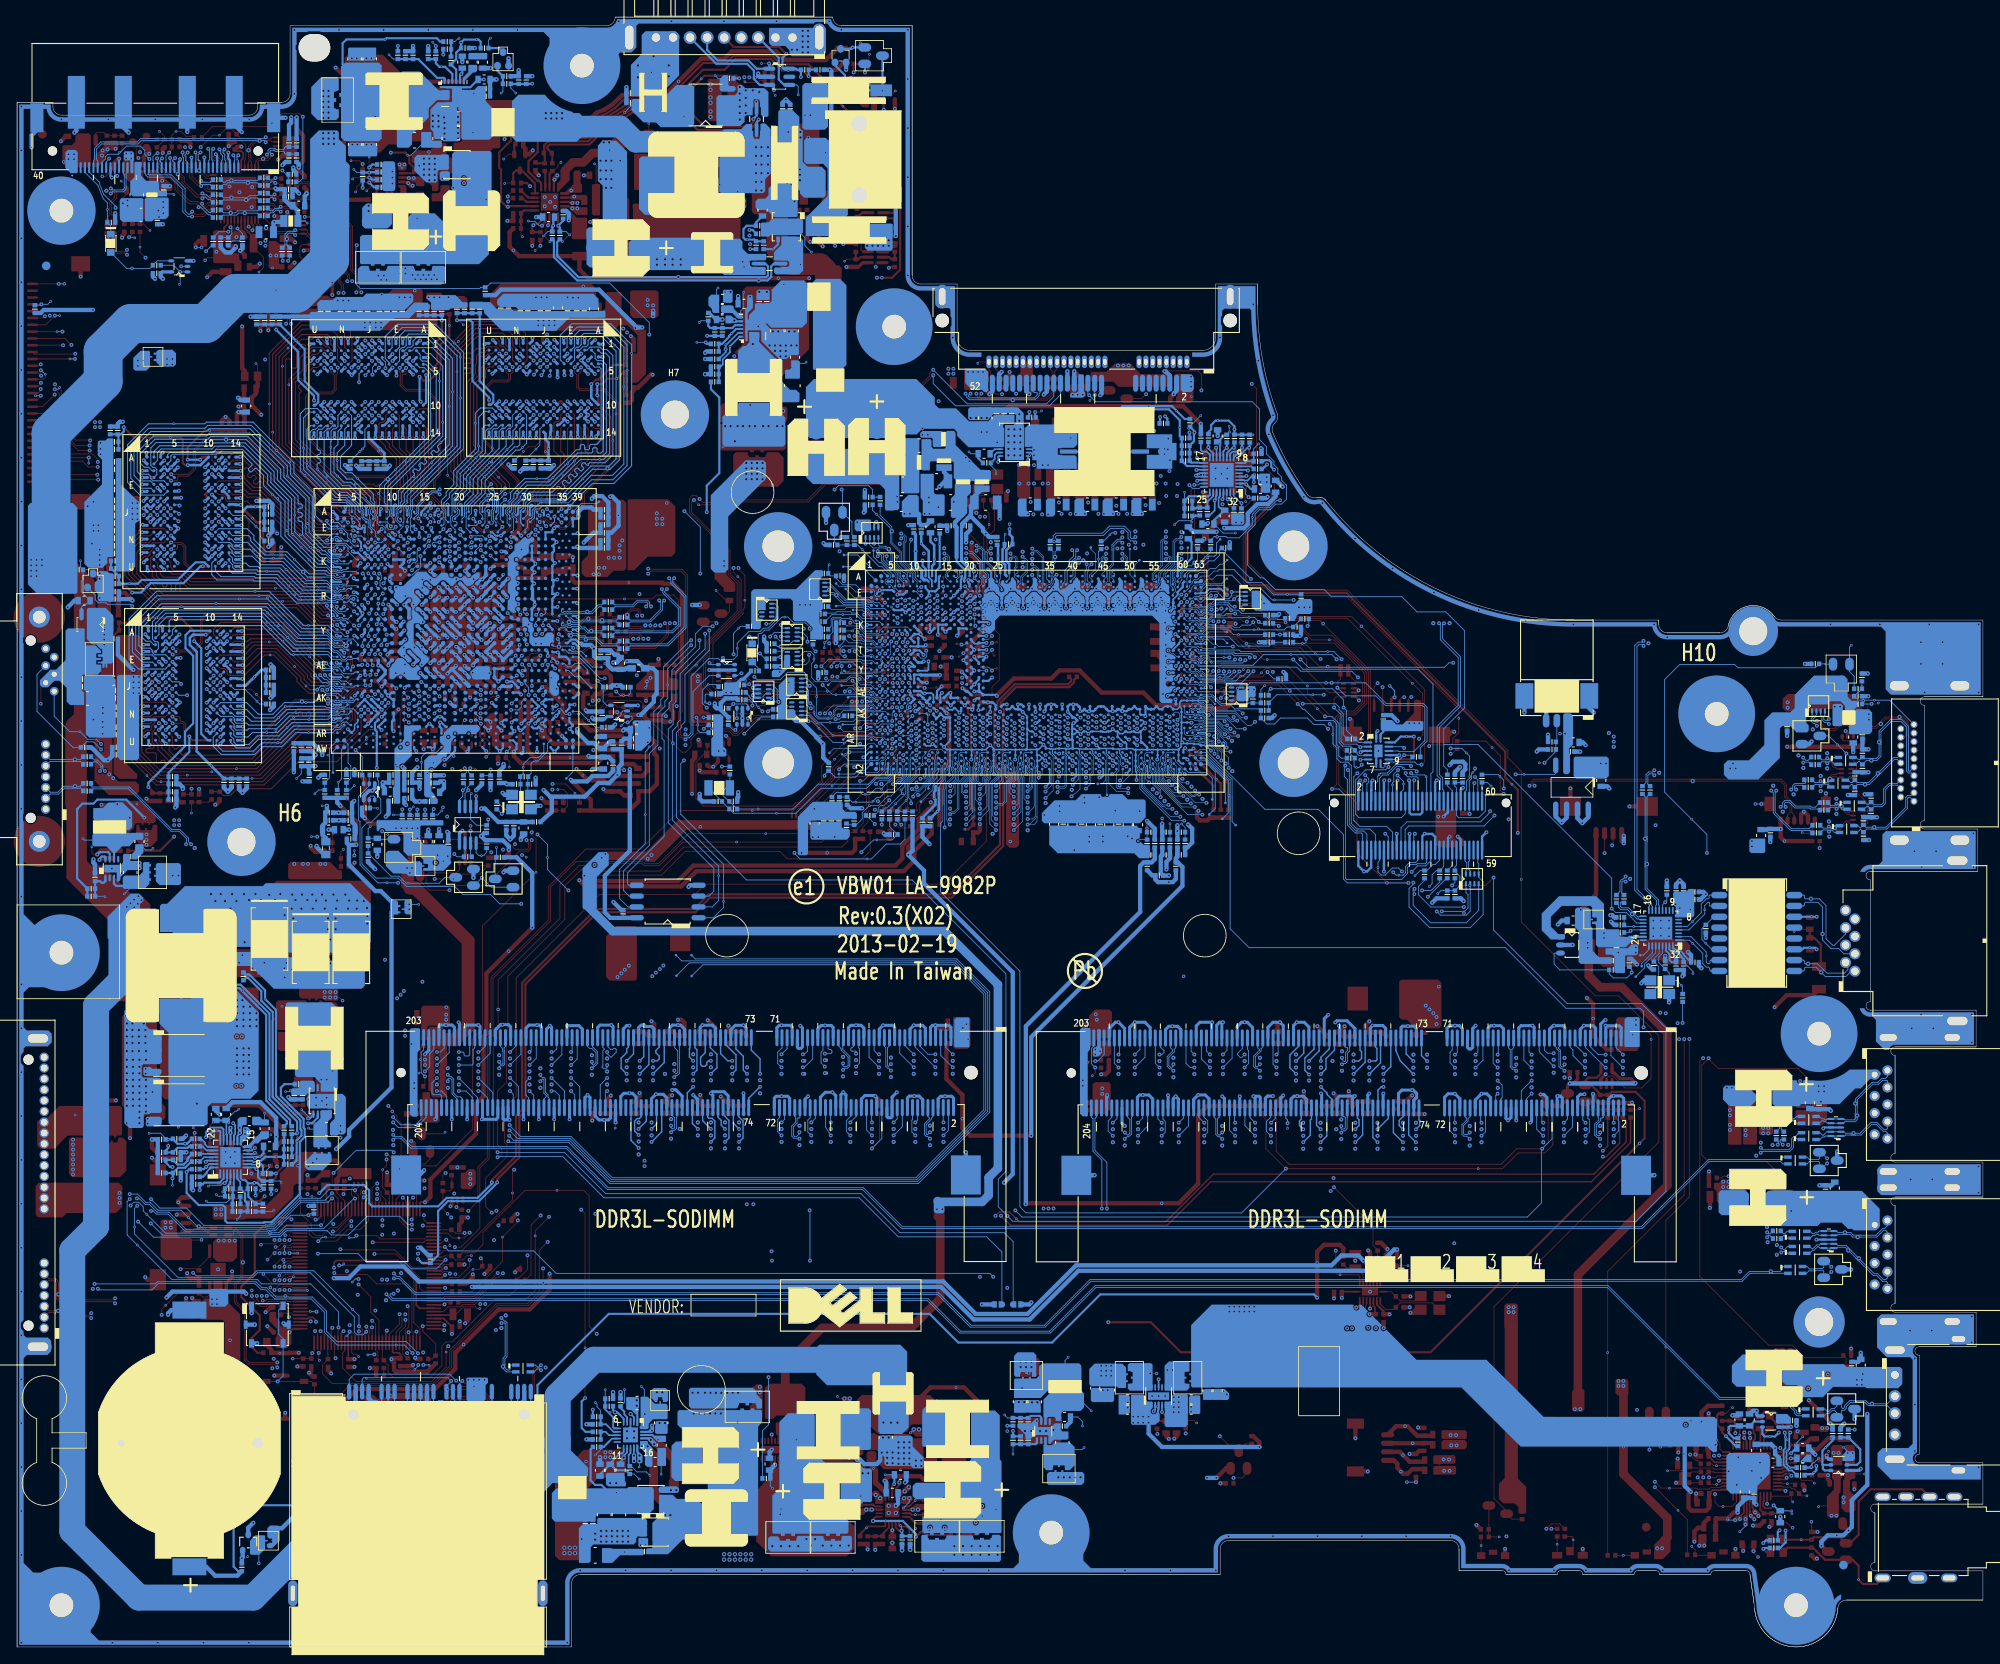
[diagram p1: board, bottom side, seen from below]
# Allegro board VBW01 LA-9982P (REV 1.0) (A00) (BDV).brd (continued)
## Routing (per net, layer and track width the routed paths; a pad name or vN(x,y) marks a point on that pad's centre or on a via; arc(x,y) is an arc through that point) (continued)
DQA1_2: length 17.9
  TOP w0.102: UV3.T11 183.59,144.78 183.19,145.18 ; v1(180.43,131.07) 180.15,131.34 180.15,133.56 181.73,135.14 182.21,135.14 182.35,135.28 182.35,135.39
  TOP w0.127: 182.35,135.39 182.35,137.21 181.79,137.77 v3(181.79,138.88) 181.79,144.61 182.37,145.18 183.19,145.18
  BOTTOM w0.102: UV1.F18 180.81,130.69 v1(180.43,131.07)
DQA1_3: length 15.7
  TOP w0.102: 184.64,135.39 184.64,134.77 183.1,133.23 183.1,132.7 182.74,132.34 182.28,132.34 181.96,132.65 v1(181.96,132.67) ; UV3.N11 185.59,144.38
  TOP w0.127: 184.64,135.39 184.64,137.31 184.78,137.46 v3(184.78,138.94) 184.78,139.77 185.59,140.59 185.59,144.38
  BOTTOM w0.102: UV1.D17 181.46,132.17 v1(181.96,132.67)
DQA1_4: length 11.3
  TOP w0.102: v1(181.89,133.55) 182.04,133.55 183.5,135 183.5,135.39
  TOP w0.127: 183.5,135.39 183.5,137.68 183.19,137.98 v3(183.19,138.54) 183.19,142.78 UV3.T13
  BOTTOM w0.102: v1(181.89,133.55) 182.26,133.17 UV1.A16
DQA1_5: length 14.7
  TOP w0.102: v1(182.91,131.2) v3(184.68,132.97) 185.13,133.42 185.13,134.39 185.5,134.75 185.5,135.39 ; UV3.M13 187.19,142.78
  TOP w0.127: 187.19,142.78 187.19,141.46 186.78,141.04 186.78,140.69 185.54,139.46 185.54,137.14 185.5,137.09 185.5,135.39
  BOTTOM w0.102: v1(182.91,131.2) 182.91,131.06 182.54,130.69 UV1.F16
DQA1_6: length 12.8
  TOP w0.102: v1(183.36,132.31) 183.36,133.02 v3(184.7,134.36) 185.11,134.78 185.11,135.39 ; UV3.N13 186.39,142.78
  TOP w0.127: 186.39,142.78 186.39,140.85 185.16,139.62 185.16,137.3 185.11,137.25 185.11,135.39
  BOTTOM w0.102: UV1.D15 183.06,132.01 v1(183.36,132.31)
DQA1_7: length 16.7
  TOP w0.102: UV3.M11 187.19,144.38 ; v1(183.69,131.03) v3(184.07,131.41) 185.45,132.79 185.45,134.25 185.88,134.68 185.88,135.39
  TOP w0.127: 187.19,144.38 187.19,143.91 187.52,143.58 187.79,143.58 187.99,143.39 187.99,141.55 187.23,140.79 187.23,140.6 185.96,139.33 185.96,137.01 185.88,136.93 185.88,135.39
  BOTTOM w0.102: UV1.E14 183.86,131.2 v1(183.69,131.03)
DQA1_8: length 38.4
  BOTTOM w0.102: UV1.F14 184.28,130.9 184.28,132.36 184.15,132.48 184.15,132.9 184.17,132.91 184.17,133.22 184.07,133.32 184.07,134.49 183.17,135.39
  BOTTOM w0.127: 183.17,135.39 178.08,140.47 178.08,151.81 v3(179.15,152.88) 181.35,155.08 185.83,155.08 187.25,153.66 187.25,151.05 186.8,150.6 UV6.F4
DQA1_9: length 33.7
  BOTTOM w0.102: 183.71,135.39 184.27,134.82 184.27,133.4 184.37,133.3 184.37,132.83 184.36,132.82 184.36,132.56 184.66,132.26 UV1.D13
  BOTTOM w0.127: UV6.F2 186.45,152.33 186.45,153.51 185.26,154.7 181.51,154.7 178.46,151.65 v3(178.46,151.24) 178.46,140.63 183.48,135.61 183.48,135.61 183.71,135.39
DQA1_10: length 33.6
  BOTTOM w0.102: 184.25,135.39 184.69,134.95 184.69,134.12 185.07,133.74 185.07,131.9 185.16,131.81 185.16,131.36 185.66,130.86 UV1.F12
  BOTTOM w0.127: 184.25,135.39 178.84,140.79 v3(178.84,149.51) 178.84,151.39 181.77,154.32 184.96,154.32 185.59,153.69 185.59,152.39 UV6.E2
DQA1_11: length 31.1
  BOTTOM w0.102: UV1.A12 185.3,133.25 185.3,133.89 185,134.19 185,135.17 184.79,135.39
  BOTTOM w0.127: 184.79,135.39 179.37,140.8 v3(179.37,147.15) 179.37,151.1 182.21,153.93 184.5,153.93 184.8,153.64 184.8,152.62 185.07,152.35 185.31,152.35 185.58,152.08 185.58,150.8 UV6.E4
DQA1_12: length 24
  BOTTOM w0.102: UV1.D11 186.26,132.26 186.57,132.56 186.57,132.87 186.55,132.88 186.55,133.3 186.58,133.33 186.58,134.31 186.56,134.33 186.56,135.39
  BOTTOM w0.127: UV6.A2 182.44,151.63 181.93,151.63 180.52,150.21 v3(180.52,143.58) 180.52,141.95 186.56,135.9 186.56,135.39
DQA1_13: length 24
  BOTTOM w0.102: 187.9,135.39 187.9,133.93 188.15,133.68 188.15,132.88 188.26,132.78 188.26,132.6 188.15,132.5 188.15,132.02 188.18,131.99 188.18,131.73 187.97,131.52 187.54,131.52 187.26,131.24 UV1.F10
  BOTTOM w0.127: 187.9,135.39 187.9,136.18 v3(186.06,138.02) 181.96,142.12 181.96,149.3 182.65,150 183.21,150 UV6.B4
DQA1_14: length 20.7
  BOTTOM w0.102: 187.34,135.39 187.34,134.18 187.16,134 187.16,133.19 UV1.A10
  BOTTOM w0.127: UV6.A4 182.5,150.38 181.28,149.16 181.28,142.26 v3(184.37,139.17) 187.34,136.2 187.34,135.39
DQA1_15: length 23.9
  BOTTOM w0.102: UV1.C10 186.77,132.58 186.77,132.95 186.76,132.96 186.76,133.22 186.96,133.42 186.96,134.39 186.96,134.39 186.96,135.37 186.94,135.39
  BOTTOM w0.127: UV6.B2 183.16,151.55 183.16,151.01 182.91,150.76 182.34,150.76 180.9,149.32 v3(180.9,148.44) 180.9,142.11 186.94,136.06 186.94,135.39
DQA1_16: length 31.1
  TOP w0.102: v1(185.45,130.25) 185.45,130.38 186.02,130.95 186.18,130.95 186.23,131 186.75,131 186.97,131.23 186.97,134.38 187.16,134.57
  TOP w0.127: 187.16,134.57 187.16,134.88 187.79,135.51 187.79,135.75 187.6,135.94 187.6,136.12 187.78,136.3 187.96,136.3 188.15,136.11 188.39,136.11 188.62,136.34 v3(190.76,136.34) 192.07,136.34 197.35,141.62 197.35,146.98 197.13,147.19 197.13,147.37 197.4,147.65 197.4,147.83 197.22,148.01 197.04,148.01 196.77,147.73 196.59,147.73 196.12,148.21 196.12,149.59 195.69,150.01 195.17,150.01 UV3.B4
  BOTTOM w0.102: v1(185.45,130.25) 185.45,130.25 185.44,130.25 185.42,130.25 UV1.G13
DQA1_17: length 34.7
  TOP w0.102: 188.36,135 187.93,134.57 187.76,134.57 187.38,134.19 187.38,133.26 188.08,132.56 188.08,130.95 186.42,129.3 184.81,129.3 v1(184.62,129.49)
  TOP w0.127: 188.36,135 188.94,135.58 192.38,135.58 v3(194.08,137.27) 198.16,141.36 198.16,148.46 196.88,149.75 196.88,150.87 196.51,151.24 196.04,151.24 195.73,151.55 195.23,151.55 UV3.B2
  BOTTOM w0.102: UV1.H13 185.02,129.09 v1(184.62,129.49)
DQA1_18: length 33.4
  TOP w0.102: 188.34,134.54 188.28,134.48 188.28,130.87 186.2,128.79 v1(185.7,128.79)
  TOP w0.127: UV3.A2 195.8,151.99 196.08,151.71 196.71,151.71 197.26,151.16 197.26,149.9 198.55,148.62 v3(198.55,147.98) 198.55,141.2 192.69,135.35 189.14,135.35 188.34,134.54
  BOTTOM w0.102: UV1.J13 185.2,128.29 v1(185.7,128.79)
DQA1_19: length 31.2
  TOP w0.102: v1(185.77,129.68) 186.21,129.68 186.46,129.93 186.46,130.53 186.73,130.8 186.83,130.8 187.18,131.14 187.18,131.52 187.18,131.52 187.18,134.29 187.24,134.35 187.25,134.35 187.38,134.48 187.38,134.56 187.53,134.71
  TOP w0.127: 187.53,134.71 v3(188.04,135.22) 188.78,135.96 192.23,135.96 197.78,141.51 197.78,148.3 197.35,148.74 197.17,148.74 196.89,148.46 196.71,148.46 196.53,148.64 196.53,148.82 196.81,149.1 196.81,149.28 196.5,149.59 196.5,150.26 196.37,150.38 UV3.A4
  BOTTOM w0.102: UV1.H11 185.77,129.59 v1(185.77,129.68)
DQA1_20: length 40
  TOP w0.102: 191.1,134.25 188.94,132.09 188.94,130.63 188.43,130.12 v1(188.43,129.49)
  TOP w0.127: 191.1,134.25 191.29,134.44 193.41,134.44 199.69,140.72 199.69,151.25 v3(198.64,152.29) 197.06,153.87 194.02,153.87 193.65,153.5 193.65,152.76 193.27,152.39 193.1,152.39 192.85,152.13 192.85,150.84 UV3.E4
  BOTTOM w0.102: v1(188.43,129.49) 187.67,129.49 UV1.G10
DQA1_21: length 41.2
  TOP w0.102: 190.97,133.27 190.89,133.27 189.35,131.73 189.35,130.46 189.26,130.37 v1(189.26,129.49)
  TOP w0.127: UV3.F2 192.02,152.41 192.02,154.11 192.89,154.98 197.03,154.98 200.45,151.56 v3(200.45,142.43) 200.45,140.39 193.99,133.93 192.73,133.93 192.07,133.27 190.97,133.27
  BOTTOM w0.102: v1(189.26,129.49) 189.26,129.49 189.26,129.5 188.87,129.89 UV1.G8
DQA1_22: length 46.9
  TOP w0.102: v1(188.46,127.89) 188.88,128.31 188.88,128.84 189.11,129.07 189.42,129.07 189.64,129.29 189.64,130.76 190.15,131.27 190.15,132.22 190.47,132.54
  TOP w0.127: 190.47,132.54 190.91,132.98 192.37,132.98 192.94,133.55 194.15,133.55 200.83,140.23 v3(200.83,145.74) 200.83,151.72 197.08,155.47 192.59,155.47 191.33,154.21 191.33,153.64 191.15,153.46 191.15,150.83 UV3.F4
  BOTTOM w0.102: UV1.K9 v1(188.46,127.89)
DQA1_23: length 41.5
  TOP w0.102: v1(187.66,127.9) 187.66,128.14 188.08,128.56 188.08,128.85 188.34,129.11 188.65,129.11 188.81,129.27 188.81,130.21 189.14,130.54 189.14,131.91 191.16,133.93
  TOP w0.127: UV3.E2 192.4,152.11 192.84,152.55 192.84,153.79 193.56,154.51 196.96,154.51 200.07,151.4 200.07,140.57 v3(198.45,138.94) 193.72,134.21 191.44,134.21 191.16,133.93
  BOTTOM w0.102: v1(187.66,127.9) 187.26,127.5 UV1.K10
DQA1_24: length 18.5
  BOTTOM w0.102: UV1.G9 188.37,130.2 188.37,130.76 188.97,131.36 188.97,131.62 188.94,131.64 188.94,132.14 189.07,132.27 189.07,132.71 189.2,132.84 189.2,133.35 189.08,133.47 189.08,133.87 190.15,134.95 190.21,134.95 190.46,135.2 ; 192.79,144.37 192.79,144.39 192.4,144.78 UV6.N11
  BOTTOM w0.127: 192.79,144.37 192.79,143.1 193.07,142.82 193.34,142.82 193.6,142.57 193.6,141.32 193.64,141.28 v3(193.64,140.66) 193.64,137.57 192.22,136.15 191.41,136.15 190.46,135.2
DQA1_25: length 12.7
  BOTTOM w0.102: 188.98,134.55 188.98,134.38 188.67,134.07 188.67,133.1 UV1.A8 ; 188.98,134.79 189.57,135.39
  BOTTOM w0.127: UV6.M13 191.99,142.79 191.99,140.9 192.88,140.02 v3(192.88,139.11) 192.88,138.08 191.93,137.13 191.93,137.11 191.75,136.93 191.12,136.93 189.57,135.39 ; 188.98,134.55 188.98,134.79
DQA1_26: length 13.7
  BOTTOM w0.102: 190.11,135.39 189.47,134.74 189.47,134.55 188.87,133.96 188.87,133.39 188.99,133.27 188.99,132.92 188.66,132.59 UV1.C8
  BOTTOM w0.127: UV6.N13 192.4,142.92 192.79,142.52 192.79,141.01 193.26,140.54 193.26,137.73 v3(192.82,137.29) 192.08,136.55 191.27,136.55 190.11,135.39
DQA1_27: length 16.4
  BOTTOM w0.102: UV6.M11 191.59,144.78 191.2,144.39 ; UV1.E8 188.62,131.53 188.62,131.84 188.36,132.1 188.36,132.42 188.46,132.52 188.46,132.86 188.36,132.96 188.36,133.22 188.47,133.33 188.47,134.23 188.65,134.41 188.65,134.58
  BOTTOM w0.127: 188.65,134.58 188.65,135.15 v3(190.49,136.99) 191.18,137.68 191.94,137.68 192.5,138.24 192.5,139.56 191.2,140.86 191.2,144.39
DQA1_28: length 13.9
  BOTTOM w0.127: UV1.A6 190.43,133.25 190.43,133.76 191.67,135.01 192.69,135.01 194.18,136.5 v3(194.18,136.5) 196.05,138.36 196.05,142.44 195.74,142.75 195.42,142.75 194.99,143.18 UV6.T13
DQA1_29: length 14.7
  BOTTOM w0.102: UV1.C6 190.78,132.81 190.78,133.39
  BOTTOM w0.127: UV6.U13 196.01,143.18 196.43,142.76 v3(196.43,138.87) 196.43,138.21 194.39,136.16 193,134.78 191.85,134.78 190.78,133.71 190.78,133.39
DQA1_30: length 19.9
  BOTTOM w0.102: 193.79,134.48 193.49,134.19 191.89,134.19 191.48,133.78 191.48,132.85 191.23,132.6 191,132.6 190.26,131.86 UV1.E6
  BOTTOM w0.127: 193.79,134.48 v3(196.66,137.36) 197.2,137.89 197.2,144.6 196.59,145.2 195.21,145.2 UV6.T11
DQA1_31: length 15.7
  BOTTOM w0.127: UV1.A5 191.16,133.77 191.9,134.5 193.27,134.5 196.82,138.05 v3(196.82,140.56) 196.82,144.12 196.15,144.78 UV6.U11
DQB0_0: length 19.3
  TOP w0.102: v1(190.97,131.84) 191.35,131.46 191.81,131.46 191.99,131.63 192.82,131.63 193.44,131.01 194.09,131.01
  TOP w0.127: UV7.T13 205.13,139.14 203.79,139.14 v3(196.36,131.71) 195.52,130.87 194.23,130.87 194.09,131.01
  BOTTOM w0.102: UV1.C5 191.16,132.03 v1(190.97,131.84)
DQB0_1: length 18.8
  TOP w0.102: 194.39,131.25 193.49,131.25 192.79,131.94 v3(192.32,131.94) 191.72,131.94 v1(191.61,131.84)
  TOP w0.127: UV7.U13 205.04,140.03 204.14,140.03 195.36,131.25 194.39,131.25
  BOTTOM w0.102: UV1.C3 v1(191.61,131.84)
DQB0_2: length 19.5
  TOP w0.102: 194.39,131.63 193.85,131.63 v1(193.45,132.03) ; UV7.U11 206.76,139.91
  TOP w0.127: 194.39,131.63 195.2,131.63 v3(197.12,133.54) 203.98,140.41 206.26,140.41 206.49,140.17 206.76,139.91
  BOTTOM w0.127: v1(193.45,132.03) 193.26,131.83 192.75,131.83 192.31,131.39 UV1.E3
DQB0_3: length 20.5
  TOP w0.102: v1(194.08,132.03) 194.1,132.01 194.39,132.01 ; UV7.T11 207.16,138.71 207.56,139.11
  TOP w0.127: 207.56,139.11 207.56,139.94 206.7,140.79 203.82,140.79 195.05,132.01 v3(194.78,132.01) 194.39,132.01
  BOTTOM w0.127: v1(194.08,132.03) 194.08,131.84 193.64,131.39 UV1.E1
DQB0_4: length 17.8
  TOP w0.102: 194.39,129.73 194.07,129.73 v1(194.06,129.74) ; UV7.N11 206.76,136.71
  TOP w0.127: 206.76,136.71 203.97,136.71 202.85,135.58 201.85,135.58 v3(198.4,132.13) 195.94,129.68 195.79,129.68 195.74,129.73 194.39,129.73
  BOTTOM w0.102: UV1.F1 193.46,130.49 194.04,129.91 194.04,129.74 v1(194.06,129.74)
DQB0_5: length 17.8
  TOP w0.102: v1(192.46,130.79) 192.46,129.65 192.75,129.36 193.42,129.36 193.62,129.16 194.04,129.16 194.23,128.96 ; UV7.M13 205.16,135.11
  TOP w0.127: 194.23,128.96 194.28,128.92 v3(196,128.92) 196.26,128.92 202.17,134.82 203.42,134.82 203.71,135.11 205.16,135.11
  BOTTOM w0.102: UV1.F3 192.15,130.49 v1(192.46,130.79)
DQB0_6: length 20.7
  TOP w0.102: UV7.M11 206.76,135.11 ; v1(190.91,129.68) 192.15,129.68 192.67,129.16 193.33,129.16 193.54,128.95 193.89,128.95 194.26,128.58 194.26,128.58
  TOP w0.127: 206.76,135.11 206.28,135.11 205.96,134.78 205.96,134.51 205.76,134.31 203.42,134.31 202.98,133.88 201.76,133.88 v3(198.78,130.9) 196.42,128.53 194.3,128.53 194.26,128.58
  BOTTOM w0.102: v1(190.91,129.68) 190.91,129.83 191.18,130.1 191.18,130.41 UV1.F5
DQB0_7: length 17.4
  TOP w0.102: 194.39,129.34 194.23,129.34 194.22,129.36 193.83,129.36 193.5,129.69 v1(193.5,129.8) ; UV7.N13 205.16,135.91
  TOP w0.127: 205.16,135.91 203.93,135.91 203.23,135.2 202.01,135.2 v3(197.2,130.4) 196.1,129.3 195.63,129.3 195.58,129.34 194.39,129.34
  BOTTOM w0.102: UV1.G4 192.03,129.69 192.34,130 192.59,130 192.78,130.19 193.12,130.19 v1(193.5,129.8)
DQB0_8: length 43
  BOTTOM w0.102: 194.39,129.48 194.23,129.32 193.88,129.32 193.83,129.37 193.1,129.37 193.07,129.4 192.65,129.4 192.63,129.37 192.3,129.37 192.27,129.4 191.85,129.4 191.34,128.89 UV1.H5
  BOTTOM w0.127: UV8.F2 214.71,135.86 215.88,135.86 217.07,137.04 217.07,140.79 214.98,142.89 208.38,142.89 208.05,143.22 202.94,143.22 v3(199.99,140.27) 198.35,138.63 198.35,137.46 195.8,134.91 195.8,130.89 194.39,129.48
DQB0_9: length 46.6
  BOTTOM w0.102: 194.39,131.6 193.87,131.09 192.74,131.09 192.65,131.17 192.28,131.17 191.67,130.57 191.67,130.13 191.36,129.82 191.36,129.55 190.9,129.09 UV1.H6
  BOTTOM w0.127: UV8.F4 213.21,135.05 215.97,135.05 217.45,136.54 217.45,140.96 215,143.41 v3(212.06,143.41) 208.4,143.41 208.21,143.6 202.74,143.6 197.96,138.82 197.96,137.62 195.42,135.08 195.42,132.64 194.39,131.6
DQB0_10: length 41.4
  BOTTOM w0.102: 194.39,128.52 194.32,128.52 193.6,127.8 192.6,127.8 192.59,127.79 191.97,127.79 UV1.J4
  BOTTOM w0.127: 194.39,128.52 194.54,128.52 196.56,130.54 v3(196.56,131.28) 196.56,134.58 199.13,137.14 199.13,138.31 203.13,142.31 207.86,142.31 208.2,141.98 214.42,141.98 216.31,140.09 216.31,137.81 216.01,137.51 214.99,137.51 214.72,137.23 214.72,136.99 214.46,136.73 213.18,136.73 UV8.E4
DQB0_11: length 43
  BOTTOM w0.102: UV1.K6 190.63,127.49 191.61,128.47 191.61,128.87 191.94,129.2 192.19,129.2 192.21,129.17 192.71,129.17 192.74,129.2 192.99,129.2 193.25,128.93 194.39,128.93
  BOTTOM w0.127: 194.39,128.93 194.42,128.93 196.18,130.7 196.18,134.75 v3(198.73,137.3) 198.73,138.47 203.1,142.84 207.89,142.84 208.23,142.5 214.72,142.5 216.69,140.54 216.69,137.34 216.07,136.71 214.77,136.71 UV8.E2
DQB0_12: length 33.2
  BOTTOM w0.102: 194.39,127.34 194.04,127.34 193.82,127.13 193.3,127.13 193.26,127.09 193.09,127.09 192.99,126.99 191.57,126.99 UV1.K5
  BOTTOM w0.127: 194.39,127.34 194.98,127.34 v3(198.08,130.44) 198.24,130.6 198.24,134.64 200.27,136.67 200.27,137.78 203.67,141.17 207.39,141.17 207.72,140.83 213.68,140.83 214.36,140.15 UV8.A2
DQB0_13: length 33.3
  BOTTOM w0.102: UV1.L4 191.84,126.31 192.21,126.31 192.34,126.19 192.62,126.19 192.65,126.21 192.81,126.21 192.88,126.28 193.53,126.28 194.21,126.96 194.39,126.96
  BOTTOM w0.127: UV8.B2 213.95,139.11 213.95,140.02 213.52,140.45 207.57,140.45 207.23,140.79 203.82,140.79 200.65,137.62 200.65,136.51 198.62,134.48 198.62,130.44 v3(197.12,128.94) 195.14,126.96 194.39,126.96
DQB0_14: length 31.9
  BOTTOM w0.102: UV1.M6 190.65,126.08 192.16,126.08 192.25,125.98 192.71,125.98 192.73,126.01 192.89,126.01 192.96,126.08 193.61,126.08 194.12,126.58 194.39,126.58
  BOTTOM w0.127: 194.39,126.58 195.3,126.58 v3(196.17,127.45) 199,130.28 199,134.32 201.03,136.35 201.03,137.46 203.98,140.41 207.07,140.41 207.41,140.07 212.49,140.07 212.76,139.8 UV8.A4
DQB0_15: length 30.9
  BOTTOM w0.102: 194.16,126.2 193.84,125.87 193.05,125.87 UV1.M1
  BOTTOM w0.127: UV8.B4 212.37,139.09 212.37,139.65 212.18,139.84 207.1,139.84 207.01,139.93 204.08,139.93 202.88,138.72 202.88,138.54 203.27,138.15 203.27,137.97 203.09,137.79 202.91,137.79 202.52,138.18 202.34,138.18 201.51,137.36 201.51,136.15 v3(200.49,135.13) 199.48,134.12 199.48,130.22 195.46,126.2 194.16,126.2
DQB0_16: length 18.1
  BOTTOM w0.102: UV8.M11 207.16,130.71 206.76,131.11 ; 194.39,125.82 194.23,125.82 194.06,125.65 193.27,125.65 193,125.39 192.69,125.39 192.59,125.48 192.11,125.48 192.06,125.53 UV1.M3
  BOTTOM w0.127: 194.39,125.82 196.19,125.82 v3(197.91,127.53) 198.78,128.41 201.2,128.41 202.64,129.85 202.64,130.32 203.43,131.11 206.76,131.11
DQB0_17: length 17.1
  BOTTOM w0.102: 194.39,125.44 193.35,125.44 193.09,125.17 192.59,125.17 192.53,125.23 191.67,125.23 191.26,125.63 UV1.M5
  BOTTOM w0.127: 194.39,125.44 v3(195.97,125.44) 196.35,125.44 198.94,128.03 201.36,128.03 203.03,129.69 203.03,130.06 203.27,130.31 205.16,130.31 UV8.M13
DQB0_18: length 16.4
  BOTTOM w0.102: 194.39,125.06 194.12,125.06 193.67,124.6 192.62,124.6 192.55,124.54 192.34,124.54 192.27,124.62 191.77,124.62 191.66,124.72 UV1.N4
  BOTTOM w0.127: UV8.N13 205.3,129.91 204.9,129.51 203.38,129.51 201.52,127.65 v3(200.34,127.65) 199.1,127.65 196.51,125.06 194.39,125.06
DQB0_19: length 19.3
  BOTTOM w0.102: 194.39,124.68 194.03,124.68 193.75,124.4 192.73,124.4 192.61,124.27 192.32,124.27 192.18,124.41 190.59,124.41 UV1.P6 ; 206.75,129.51 206.76,129.51 207.16,129.9 UV8.N11
  BOTTOM w0.127: 206.75,129.51 205.47,129.51 205.2,129.23 205.2,128.96 204.94,128.7 203.12,128.7 v3(202.3,127.88) 201.68,127.26 199.26,127.26 196.67,124.68 194.39,124.68
DQB0_20: length 16.6
  BOTTOM w0.102: UV1.P5 191.63,124.09 191.94,123.79 192.45,123.79 192.65,123.58 193.1,123.58 193.21,123.7 194.21,123.7 194.38,123.53 194.39,123.53
  BOTTOM w0.127: UV8.T13 205.56,127.31 205.13,126.88 205.13,126.56 204.85,126.29 202.32,126.29 202.15,126.12 v3(201.14,126.12) 199.73,126.12 197.14,123.53 194.39,123.53
DQB0_21: length 15.9
  BOTTOM w0.102: 194.39,123.15 194.03,123.15 193.78,122.9 193.18,122.9 193.07,123 192.65,123 192.6,123 192.59,122.99 192.34,122.99 192.03,123.29 UV1.R4
  BOTTOM w0.127: UV8.U13 205.56,126.29 205.17,125.91 202.47,125.91 202.31,125.74 199.89,125.74 v3(198.54,124.4) 197.3,123.15 194.39,123.15
DQB0_22: length 19.4
  BOTTOM w0.102: UV1.T6 190.46,123.01 190.72,123.26 191.26,123.26 191.54,122.99 192.05,122.99 192.26,122.78 192.72,122.78 192.74,122.8 192.99,122.8 193.09,122.69 193.95,122.69 194.02,122.77 194.39,122.77
  BOTTOM w0.127: UV8.U11 207.16,126.15 206.5,125.49 202.59,125.49 202.47,125.36 200.05,125.36 197.46,122.77 v3(197.16,122.77) 194.39,122.77
DQB0_23: length 18.1
  BOTTOM w0.102: 194.39,122.39 194.38,122.39 194.28,122.49 UV1.T1
  BOTTOM w0.127: UV8.T11 207.58,127.09 207.58,125.71 206.98,125.11 202.75,125.11 202.62,124.98 200.21,124.98 197.62,122.39 v3(195.09,122.39) 194.39,122.39
DQB0_24: length 23.9
  TOP w0.127: UV7.A4 212.76,126.31 212.26,125.8 210.94,125.8 210.04,124.9 195.78,124.9 v3(195.52,124.64) 192.94,122.05 v1(192.94,121.95)
  BOTTOM w0.102: v1(192.94,121.95) 192.94,121.67 192.64,121.38 191.98,121.38 UV1.U4
DQB0_25: length 25.3
  TOP w0.127: UV7.B4 212.39,127.13 212.39,126.61 211.96,126.19 210.79,126.19 209.88,125.28 194.77,125.28 v3(193.71,124.22) v1(190.91,121.42)
  BOTTOM w0.102: UV1.V6 190.58,121.09 v1(190.91,121.42)
DQB0_26: length 25
  TOP w0.127: UV7.B2 213.93,127.07 213.93,126.57 213.61,126.26 213.61,125.79 213.25,125.42 211.1,125.42 210.2,124.52 196.48,124.52 v3(194.77,122.8) 194.08,122.12 v1(194.08,122.11)
  BOTTOM w0.102: UV1.V1 192.86,121.02 193.39,121.55 193.72,121.55 194.08,121.92 v1(194.08,122.11)
DQB0_27: length 25.5
  TOP w0.127: v1(193.53,122.05) 193.87,121.72 194.28,121.72 196.71,124.14 v3(200.13,124.14) 210.36,124.14 211.26,125.04 213.53,125.04 214.08,125.6 214.08,126.22 214.36,126.5 UV7.A2
  BOTTOM w0.102: v1(193.53,122.05) 193.53,121.98 192.73,121.17 192.35,121.17 UV1.V3
DQB0_28: length 35.5
  TOP w0.127: UV7.E4 213.21,129.45 214.51,129.45 214.76,129.2 214.76,128.91 215.02,128.65 216.02,128.65 216.35,128.32 216.35,125.85 213.49,122.99 v3(201.08,122.99) 197.18,122.99 194.75,120.56 191.7,120.56 v1(190.91,119.76)
  BOTTOM w0.102: UV1.Y6 190.46,119.32 v1(190.91,119.76)
DQB0_29: length 34
  TOP w0.102: v1(193.45,119.79) 193.46,119.8 194.39,119.8
  TOP w0.127: UV7.F2 214.79,130.28 215.96,130.28 217.35,128.88 217.35,125.78 213.81,122.23 197.5,122.23 v3(195.54,120.28) 195.06,119.8 194.39,119.8
  BOTTOM w0.102: UV1.Y1 192.95,119.29 v1(193.45,119.79)
DQB0_30: length 33.4
  TOP w0.127: v1(192.88,119.84) 193.22,120.18 194.91,120.18 197.34,122.61 v3(199.29,122.61) 213.65,122.61 216.88,125.85 216.88,128.74 216.16,129.47 214.93,129.47 214.49,129.91 UV7.E2
  BOTTOM w0.102: v1(192.88,119.84) 192.33,119.29 UV1.Y3
DQB0_31: length 38.9
  TOP w0.127: UV7.F4 213.21,131.16 215.83,131.16 216.14,130.85 216.14,130.63 217.74,129.04 217.74,125.62 213.97,121.85 197.65,121.85 195.03,119.23 v3(193.94,119.23) 191.93,119.23 v1(191.67,118.97)
  BOTTOM w0.102: UV1.Y5 191.35,119.29 v1(191.67,118.97)
DQB1_0: length 39.3
  BOTTOM w0.102: UV1.AA4 191.98,118.49 192.47,118.99 193.19,118.99 193.97,119.77 194.39,119.77
  BOTTOM w0.127: 194.39,119.77 v3(196.26,119.77) 196.85,119.77 198.93,121.85 198.93,121.85 200.86,123.78 214.05,123.78 217.26,120.56 217.26,115.76 216.16,114.66 213.02,114.66 UV10.F4
DQB1_1: length 37.2
  BOTTOM w0.102: 194.39,119.39 194.28,119.39 193.09,118.2 192.61,118.2 192.59,118.17 191,118.17 190.46,117.63 UV1.AB6
  BOTTOM w0.127: 194.39,119.39 197.01,119.39 199.09,121.47 199.09,121.47 200.87,123.25 v3(202.06,123.25) 214.02,123.25 216.88,120.39 216.88,116.65 215.69,115.46 214.52,115.46 UV10.F2
DQB1_2: length 32.9
  BOTTOM w0.102: 194.39,118.63 194.09,118.63 193.15,117.69 UV1.AB1
  BOTTOM w0.127: UV10.E4 212.99,116.33 214.27,116.33 214.53,116.6 214.53,116.84 214.8,117.11 215.82,117.11 216.12,117.41 216.12,119.7 213.47,122.34 v3(207.06,122.34) 201.04,122.34 199.17,120.47 197.32,118.63 194.39,118.63
DQB1_3: length 33.7
  BOTTOM w0.102: 194.39,119.01 194.18,119.01 193.17,118 192.69,118 192.67,117.97 192.34,117.97 UV1.AB3
  BOTTOM w0.127: UV10.E2 214.58,116.32 215.88,116.32 216.5,116.94 216.5,120.14 213.77,122.87 v3(204.33,122.87) 201.03,122.87 199.24,121.09 199.24,121.09 197.17,119.01 194.39,119.01
DQB1_4: length 24.9
  BOTTOM w0.102: UV1.AD6 191.03,115.89 191.14,115.79 191.63,115.79 191.83,115.58 192.34,115.58 192.54,115.78 193.42,115.78 193.97,116.34 194.39,116.34
  BOTTOM w0.127: UV10.B4 212.18,118.7 212.18,119.25 211.67,119.76 201.69,119.76 198.27,116.34 v3(198.01,116.34) 194.39,116.34
DQB1_5: length 22.8
  BOTTOM w0.102: UV1.AD1 193.32,116.09 193.96,116.72 194.39,116.72
  BOTTOM w0.127: UV10.A4 212.57,120.31 212.44,120.44 201.83,120.44 v3(200.69,119.29) 198.11,116.72 194.39,116.72
DQB1_6: length 25.6
  BOTTOM w0.102: UV1.AD3 192.14,116.09 192.85,116.8 193.2,116.8 193.88,117.49 194.39,117.49
  BOTTOM w0.127: 194.39,117.49 197.8,117.49 v3(198.69,118.37) 201.51,121.2 212.98,121.2 214.15,120.03 214.15,119.13 UV10.A2
DQB1_7: length 26.9
  BOTTOM w0.102: 194.39,117.1 193.79,117.1 193.28,116.59 192.93,116.59 192.5,116.16 192.5,116.03 192.26,115.79 191.91,115.79 191.61,116.09 UV1.AD5
  BOTTOM w0.127: UV10.B2 213.76,118.72 213.76,119.88 212.82,120.82 201.67,120.82 197.96,117.1 v3(196.09,117.1) 194.39,117.1
DQB1_8: length 16.5
  TOP w0.127: UV9.U11 206.33,119.75 v3(199.76,119.75) 199.24,119.75 195.24,115.75 195.15,115.75 v1(194.73,115.33)
  BOTTOM w0.102: UV1.AF1 192.96,114.59 193.31,114.59 193.43,114.72 194.12,114.72 194.39,114.98
  BOTTOM w0.127: 194.39,114.98 v1(194.73,115.33)
DQB1_9: length 20.5
  TOP w0.127: v1(193.56,115.34) v3(193.56,114.72) 193.26,114.41 193.26,113.45 193.59,113.12 195.85,113.12 196.37,113.64 196.37,113.98 199.84,117.45 202.62,117.45 203.76,116.31 206.57,116.31 UV9.N11
  BOTTOM w0.102: v1(193.56,115.34) 193.45,115.34 193.12,115.01 192.61,115.01 192.59,114.99 192.34,114.99 192.33,114.99 192.06,114.72 UV1.AF3
DQB1_10: length 21.1
  TOP w0.127: UV9.T11 207.37,118.71 207.37,119.32 206.56,120.13 v3(201.12,120.13) 199.08,120.13 195.11,116.15 194.96,116.15 194.16,115.35 v1(194.16,115.34)
  BOTTOM w0.102: UV1.AF6 190.78,114.29 190.96,114.11 192.14,114.11 192.42,114.39 192.42,114.51 192.71,114.81 193.23,114.81 193.35,114.92 193.74,114.92 v1(194.16,115.34)
DQB1_11: length 16.3
  TOP w0.127: v1(195.32,115.28) 195.32,115.29 v3(196.11,116.08) 199.36,119.33 203.47,119.33 203.66,119.52 204.96,119.52 UV9.U13
  BOTTOM w0.102: UV1.AG4 192.02,113.69 192.38,114.06 193.07,114.06 193.48,114.46 194.39,114.46
  BOTTOM w0.127: 194.39,114.46 194.5,114.46 v1(195.32,115.28)
DQB1_12: length 16.7
  TOP w0.127: UV9.T13 204.97,118.71 199.36,118.71 v3(197.59,116.93) 195.5,114.85 195.18,114.85 194.31,113.98 v1(194.31,113.96)
  BOTTOM w0.102: UV1.AH5 191.47,112.89 191.81,113.23 192.41,113.23 192.59,113.41 193.77,113.41 v1(194.31,113.96)
DQB1_13: length 18.4
  TOP w0.127: UV9.M13 204.96,114.71 203.76,114.71 201.78,116.69 200.15,116.69 197.15,113.68 197.15,113.28 v3(196.54,112.67) 196.1,112.24 v1(195.22,112.24)
  BOTTOM w0.102: 194.39,112.67 193.96,112.67 193.83,112.8 193.23,112.8 193.01,112.58 192.69,112.58 192.67,112.6 192.25,112.6 192.2,112.55 190.91,112.55 190.77,112.69 UV1.AH6
  BOTTOM w0.127: v1(195.22,112.24) 194.78,112.67 194.39,112.67
DQB1_14: length 17.1
  TOP w0.127: UV9.N13 204.96,115.51 203.8,115.51 202.24,117.07 199.99,117.07 v3(197.88,114.95) 196.76,113.84 196.76,113.46 196.03,112.72 194.54,112.72 v1(194.05,112.23)
  BOTTOM w0.102: v1(194.05,112.23) 193.68,112.6 193.31,112.6 193.09,112.38 192.6,112.38 192.59,112.4 192.34,112.4 192.27,112.33 192,112.33 191.76,112.09 UV1.AJ4
DQB1_15: length 19.2
  TOP w0.127: UV9.M11 206.57,114.71 206.09,114.71 205.77,114.39 205.77,114.11 205.57,113.92 203.76,113.92 201.37,116.31 v3(200.75,116.31) 200.31,116.31 197.62,113.61 197.62,113.22 196.22,111.82 195.01,111.82 v1(194.62,112.22)
  BOTTOM w0.102: 194.39,111.99 194.21,111.81 192.78,111.81 192.26,111.29 UV1.AK3
  BOTTOM w0.127: 194.39,111.99 v1(194.62,112.22)
DQB1_16: length 32.6
  TOP w0.127: UV9.A4 212.57,105.08 211.61,104.12 202.85,104.12 v3(198,108.97) 197.86,109.12 197.56,109.12 197.43,109.24 197.43,109.5 197.31,109.63 197.11,109.63 196.98,109.5 196.98,109.24 196.85,109.12 196.6,109.12 196.47,109.24 196.47,109.49 196.34,109.62 196.09,109.62 195.96,109.49 195.96,109.24 195.84,109.12 195.58,109.12 195.46,109.24 195.46,109.49 195.33,109.62 193.13,109.62 192.69,110.06 192.69,112 191.21,113.47 189.37,113.47 188.99,113.86 v1(188.99,113.97)
  BOTTOM w0.102: v1(188.99,113.97) 188.86,114.1 UV1.AF8
DQB1_17: length 33
  TOP w0.127: UV9.B4 212.2,106.74 212.2,105.56 211.91,105.28 211.73,105.28 211.46,105.55 211.23,105.55 211.01,105.33 211.01,105.15 211.21,104.95 211.21,104.77 211.03,104.59 210.85,104.59 210.65,104.79 210.47,104.79 210.24,104.56 202.96,104.56 v3(200.06,107.46) 197.51,110.01 193.23,110.01 192.97,110.27 192.97,112.22 190.77,114.41 188.72,114.41 v1(188.32,114.01)
  BOTTOM w0.102: UV1.AF9 188.06,114.27 v1(188.32,114.01)
DQB1_18: length 32.7
  TOP w0.127: UV9.A2 214.17,106.16 213.89,105.89 213.89,105.2 212.05,103.36 202.52,103.36 197.53,108.36 v3(193.83,108.36) 193.13,108.36 192.09,109.4 192.09,111.52 191.19,112.42 189.94,112.42 189.87,112.34 189.41,112.34 v1(189,112.75)
  BOTTOM w0.102: v1(189,112.75) 188.86,112.89 UV1.AG8
DQB1_19: length 32
  TOP w0.127: v1(189.56,112.75) 191.34,112.75 192.36,111.73 192.36,109.89 193.01,109.24 193.63,109.24 194.14,108.74 v3(196.18,108.74) 197.7,108.74 202.7,103.74 211.77,103.74 213.42,105.39 213.42,105.86 213.73,106.18 213.73,106.67 UV9.B2
  BOTTOM w0.102: UV1.AG7 189.66,112.85 v1(189.56,112.75)
DQB1_20: length 41.5
  TOP w0.127: v1(189.27,111.47) 189.98,110.76 190.39,110.76 191.11,110.03 191.11,108.74 192.74,107.11 197.07,107.11 201.96,102.22 v3(210.46,102.22) 213.62,102.22 216.16,104.76 216.16,107.93 215.83,108.26 214.83,108.26 214.57,108.51 214.57,108.8 214.32,109.06 213.02,109.06 UV9.E4
  BOTTOM w0.102: UV1.AK9 188.36,111.09 188.74,111.47 v1(189.27,111.47)
DQB1_21: length 41.3
  TOP w0.127: v1(190.07,109.89) 190.48,109.48 190.48,107.44 192.15,105.76 197.29,105.76 201.59,101.46 v3(213.53,101.46) 213.94,101.46 217.16,104.68 217.16,108.65 215.93,109.88 214.6,109.88 UV9.F2
  BOTTOM w0.102: v1(190.07,109.89) 189.67,110.29 UV1.AL7
DQB1_22: length 40.8
  TOP w0.127: v1(189.27,109.89) 189.74,110.36 190.25,110.36 190.78,109.83 190.78,107.68 192.32,106.15 197.45,106.15 201.76,101.84 v3(202.86,101.84) 213.78,101.84 216.69,104.75 216.69,108.35 215.97,109.07 214.73,109.07 214.29,109.51 UV9.E2
  BOTTOM w0.102: UV1.AM8 v1(189.27,109.89)
DQB1_23: length 44.2
  TOP w0.127: UV9.F4 213.02,110.76 215.64,110.76 215.83,110.58 215.85,110.58 217.66,108.77 217.66,104.64 v3(215.18,102.16) 214.1,101.07 201.44,101.07 197.13,105.38 192.07,105.38 190.08,107.37 v1(190.08,109.14)
  BOTTOM w0.102: UV1.AM7 189.73,109.49 v1(190.08,109.14)
DQB1_24: length 15.9
  BOTTOM w0.102: UV1.AK1 193.17,111.59 194.39,111.59
  BOTTOM w0.127: UV10.M11 206.56,110.72 203.48,110.72 202.12,109.36 200.42,109.36 199.05,110.73 v3(196.56,110.73) 195.62,110.73 194.76,111.59 194.39,111.59
DQB1_25: length 15.2
  BOTTOM w0.102: 194.39,110.29 194.3,110.29 194.15,110.14 193.79,110.14 193.67,110.02 193.28,110.02 193.1,110.2 192.65,110.2 192.61,110.16 192.31,110.16 192.27,110.2 191.94,110.2 191.66,110.47 UV1.AL4
  BOTTOM w0.127: UV10.M13 204.96,109.9 203.5,109.9 202.51,108.92 200.32,108.92 v3(198.96,110.29) 194.39,110.29
DQB1_26: length 16.2
  BOTTOM w0.102: UV1.AM6 190.97,110 192.19,110 192.23,109.96 192.7,109.96 192.74,110 193.02,110 193.2,109.82 193.82,109.82 193.91,109.9 194.39,109.9
  BOTTOM w0.127: UV10.N13 205.22,109.51 204.82,109.1 203.51,109.1 202.94,108.53 200.17,108.53 v3(199.76,108.95) 198.8,109.9 194.39,109.9
DQB1_27: length 15.6
  BOTTOM w0.102: 194.39,109.52 193.79,109.52 193.7,109.61 192.94,109.61 UV1.AM1
  BOTTOM w0.127: UV10.N11 206.56,109.1 205.17,109.1 204.93,108.86 204.93,108.53 204.7,108.3 203.47,108.3 203.25,108.09 200.07,108.09 198.64,109.52 v3(197.7,109.52) 194.39,109.52
DQB1_28: length 15.9
  BOTTOM w0.102: UV1.AN4 192.03,108.89 192.35,108.57 192.87,108.57 193.06,108.37 194.39,108.37
  BOTTOM w0.127: 194.39,108.37 198.17,108.37 v3(198.75,107.79) 199.73,106.82 202.24,106.82 203.24,105.82 204.71,105.82 204.99,106.09 204.99,106.44 205.37,106.81 UV10.T13
DQB1_29: length 18.9
  BOTTOM w0.102: 194.39,107.21 193.39,107.21 193.04,107.56 192.56,107.56 192.06,108.05 UV1.AP3
  BOTTOM w0.127: UV10.T11 207.41,106.67 207.41,105.6 206.45,104.65 202.53,104.65 201.62,105.56 199.37,105.56 197.72,107.21 v3(196.22,107.21) 194.39,107.21
DQB1_30: length 14.1
  BOTTOM w0.102: 194.39,107.99 192.96,107.99 UV1.AP1
  BOTTOM w0.127: 194.39,107.99 v3(197.37,107.99) 198.02,107.99 199.58,106.43 202.09,106.43 203.11,105.41 204.7,105.41 205.37,106.08 UV10.U13
DQB1_31: length 18.3
  BOTTOM w0.102: UV1.AP5 191.41,108.09 191.76,108.44 192.17,108.44 192.42,108.19 192.42,108.04 192.68,107.78 193.2,107.78 193.38,107.6 194.39,107.6
  BOTTOM w0.127: 194.39,107.6 197.87,107.6 199.46,106.01 v3(199.84,106.01) 201.71,106.01 202.7,105.03 206.29,105.03 207.06,105.8 207.06,106.21 UV10.U11
DRAM_RST#: length 107.4
  TOP w0.102: UV5.J2 168.68,152.05 169.07,151.67 v1(169.07,151.65) ; UV7.J2 214.36,133.11 213.98,132.73 v1(213.96,132.73) ; v1(213.77,112.31) 214.17,112.71 UV9.J2 ; v1(189.59,151.58) 189.2,151.98 UV3.J2
  TOP w0.127: v1(209.96,100.63) RV143.1 RV138.2
  IN3 w0.102: 182.13,151.98 189.2,151.98 v1(189.59,151.58) 189.98,151.97 196.35,151.97 ; 214.32,140.17 214.34,140.16 214.34,133.11 v1(213.96,132.73) 214.02,132.73 214.44,132.3 215.38,132.3 215.39,132.29 215.6,132.29 ; 214.21,110.95 214.21,111.33 214.19,111.35 214.19,111.89 v1(213.77,112.31) 214.15,112.69 214.15,119.52 ; 169.49,153.26 169.49,152.13 169.07,151.71 v1(169.07,151.65)
  IN3 w0.157: v1(209.96,100.63) 214.21,104.89 214.21,110.95 ; 182.13,151.98 179.34,151.98 176.39,154.93 170.56,154.93 169.49,153.86 169.49,153.26 ; 214.15,119.52 214.15,123.68 216.31,125.84 216.31,131.58 215.6,132.29 ; 196.35,151.97 198.43,151.97 202.76,147.65 202.76,142.93 204.13,141.55 212.94,141.55 214.32,140.17
  BOTTOM w0.102: v1(213.96,132.73) 213.98,132.73 214.36,133.11 UV7.J2 ; UV5.J2 168.68,152.03 v1(169.07,151.65) ; v1(213.77,112.31) 214.17,112.71 UV9.J2 ; v1(189.59,151.58) 189.2,151.98 UV3.J2
DRAM_RST#_R: length 29.1
  TOP w0.127: v1(185.95,112.4) 186.08,112.28 186.08,110.94 187.24,109.79 187.24,108.62 188.29,107.56 189.16,107.56 192.93,103.8 v3(196.29,103.8) 197.42,103.8 200.59,100.63 204.59,100.63 205.39,99.83 206.21,99.83 RV145.2 RV144.2
  BOTTOM w0.102: UV1.AH11 186.24,112.69 v1(185.95,112.4)
DROOP_CPU: length 6.4
  BOTTOM w0.102: v3(93.58,135.39) PC513.2
  BOTTOM w0.203: PU501.25 90.62,135.04 90.77,134.88 90.96,134.88
  BOTTOM w0.254: PR529.2 PR532.1 PC513.2 93.04,134.91 91.11,134.91 91.09,134.88 90.96,134.88
DSWODVREN: length 11.1
  BOTTOM w0.076: UC1.AW7 126.45,103.29 126.45,102.03 126.71,101.76 126.81,101.76 126.81,101.76 127.12,101.76 127.37,101.51 127.37,100.95 127.81,100.51 128.36,100.51
  BOTTOM w0.102: R2337.1 R2338.1 132.52,99.05 v3(132.08,99.05) 130.18,99.05 129.63,99.61 129.26,99.61 128.36,100.51
EC_ENVDD: length 149.5
  TOP w0.102: v1(193.48,52.59) 193.41,52.59 193.19,52.36 UE1.71 ; v1(215.34,162.89) 215.99,163.54 v3(215.99,164.13) RX8.2
  IN2 w0.127: v1(215.34,162.89) 215.78,162.46 215.78,154.88 224.83,145.83 224.83,123.6 223.93,122.71 223.93,110.74 225.35,109.32 225.35,96.89 224.8,96.34 224.8,84.96 221.9,82.05 221.9,59.04 216.35,53.5 v1(216.35,52.6)
  BOTTOM w0.102: v1(216.35,52.6) 216.1,52.6 215.37,51.86 214.87,51.86 213.98,50.97 212.6,50.97 210.59,48.97 201.17,48.97 201.11,49.03 200.25,49.03 197.13,52.14 193.93,52.14 v1(193.48,52.59)
EC_LID_OUT#: length 123.8
  TOP w0.102: v1(190.63,48.23) 188.23,48.23 187.85,47.85 182.64,47.85 182.38,48.11 UE1.101
  IN1 w0.084: v1(127.22,113.03) 126.86,112.67 125.6,112.67 125.27,112.34 125.27,111.66 124.61,110.99 124.61,110.22 124.56,110.18 124.56,109.48 124.57,109.48 124.57,109.4 125.19,108.79 127.53,108.79 127.69,108.94 127.69,108.94 128.1,109.35 129.59,109.35 129.74,109.19 132.78,109.19 133.76,108.21 135.12,108.21 135.69,107.64 137.76,107.64 137.92,107.8
  IN1 w0.127: v1(190.63,48.23) 190.26,48.59 190.26,49.87 187.76,52.38 187.76,54.5 188.31,55.05 188.31,63.7 187.15,64.86 187.15,73.09 179.76,80.48 177.94,80.48 174.26,84.16 172.21,84.16 171.57,84.81 166.91,84.81 160.21,91.51 160.21,93.98 152.68,101.51 152.68,101.66 147.9,106.45 147.9,106.96 146.67,108.19 144.47,108.19 144.07,108.6 138.72,108.6 137.92,107.8
  BOTTOM w0.089: v1(127.22,113.03) 126.99,112.8 UC1.AD6
  BOTTOM w0.102: v1(190.63,48.23) 190.89,47.97 v3(191.48,47.97)
EC_MUTE#: length 188.7
  TOP w0.102: v1(31.4,17.92) 31.4,16.94 30.94,16.48 v3(30.47,16.48) 29.41,16.48 28.88,17.01 UA1.47 ; UE1.83 188.39,52.34 v1(188.2,52.53)
  IN1 w0.127: v1(188.2,52.53) 190.52,50.21 190.52,49.1 191.07,48.55 191.07,41.89 v1(190.47,41.29)
  IN3 w0.127: v1(190.47,41.29) 189.31,40.13 186.27,40.13 185.81,40.59 183.48,40.59 182.15,39.26 177.68,39.26 177.4,39.55 93.54,39.55 90.62,36.62 59.76,36.62 40.03,16.9 32.41,16.9 v1(31.4,17.92)
EC_ON: length 97.6
  TOP w0.102: v4(179.02,43.7) 179.09,43.77 v1(179.67,43.77) 179.92,44.03 180.4,44.03 180.72,43.71 UE1.112
  TOP w0.254: v1(121.68,13.98) 121.65,14.02 PR102.1
  IN1 w0.127: v1(121.68,13.98) 121.68,15.45 116.79,20.34 116.79,42.63 v1(117.55,43.39)
  IN3 w0.127: v1(179.67,43.77) 179.16,43.27 117.68,43.27 v1(117.55,43.39)
EC_RSMRST#: length 87.8
  TOP w0.089: v1(129.86,98.16) 129.68,98.16 128.57,97.05 RC41.1 128,95.82 RE2.2
  TOP w0.102: v1(177.37,48.57) 177.37,48.55 177.97,47.95 v3(178.61,47.95) 179.35,47.95 179.91,48.51 UE1.100
  IN1 w0.084: 130.5,97.49 130.5,97.52 v1(129.86,98.16)
  IN1 w0.127: 130.5,97.49 130.69,97.29 132.02,97.29 133.23,96.09 133.46,96.09 134.14,95.4 134.14,94.81 134.73,94.22 135.56,94.22 135.92,93.86 139.27,93.86 155.35,77.79 157.37,77.79 159.75,75.4 169.38,75.4 173.42,71.36 173.42,64.41 174.44,63.39 174.44,60.48 176.76,58.15 176.76,49.18 v1(177.37,48.57)
EC_RST#: length 3.3
  TOP w0.102: CE11.1 RE8.1 199.28,39.13 198.2,39.13 197.98,38.91 UE1.37
EC_RX: length 168.5
  TOP w0.102: v3(117.81,150.51) 117.65,150.67 JMINI.51 116.5,149.71 116.3,149.52 116.3,149.11 115.98,148.79 RM13.1 ; v1(195.48,37.03) 195.19,36.74 UE1.31
  IN2 w0.089: 137.76,127.21 137.92,127.05
  IN2 w0.127: 137.76,127.21 137.38,127.6 137.38,138.46 127.18,148.66 116.87,148.66 116.5,149.03 JMINI.51 ; v1(195.48,37.03) 194.91,36.46 189.23,36.46 187.97,37.71 187.97,40.99 188.29,41.31 188.29,44.56 186.91,45.94 186.91,54.43 187.8,55.32 187.8,61.91 186.38,63.33 186.38,65.57 187.03,66.21 187.03,74.16 184.07,77.11 184.07,78.35 182.91,79.51 182.49,79.51 162.1,99.9 162.1,100.76 161.63,101.23 158.21,101.23 153.42,106.02 153.42,108.58 153.29,108.71 153.29,109.59 153.77,110.08 153.77,110.47 151.83,112.42 151.83,114.65 148.74,117.74 144.68,117.74 144.02,118.4 144.02,120.96 137.92,127.05
EC_SCI#: length 125.4
  TOP w0.102: v1(191.42,36.97) 191.23,36.97 190.79,36.53 UE1.20
  IN1 w0.127: v1(191.42,36.97) 191.96,37.51 191.96,37.93 194.36,40.33 194.36,50.2 194.57,50.4 194.57,53.91 194.31,54.17 194.31,55.37 191.65,58.03 191.65,65.07 190.66,66.06 190.66,76.15 183.27,83.53 179.2,83.53 174.17,88.56 169.79,88.56 155.48,102.88 155.48,104.94 v1(155.08,105.33)
  IN3 w0.084: 137.82,107.19 130.28,107.19 129.46,108.01 v1(127.86,108.01)
  IN3 w0.127: v1(155.08,105.33) 155.08,105.45 152.38,108.14 149.74,108.14 149.33,107.73 147.41,107.73 146.31,106.63 144.79,106.63 143.71,107.71 138.98,107.71 138.47,107.19 137.82,107.19
  BOTTOM w0.089: v1(127.86,108.01) 128.06,108.21 129.12,108.21 129.49,107.85 UC1.AM2
  BOTTOM w0.102: v3(191.75,36.47) 191.42,36.79 v1(191.42,36.97)
EC_SMB_CK1: length 234.6
  TOP w0.102: PR714.1 172.88,170.13 v1(172.88,170.06) ; PR18.2 143.36,183.65 143.59,183.42 145.01,183.42 v3(145.09,183.5) 145.23,183.63 145.23,183.99 v1(145.16,184.05) ; UE1.77 190.79,52.56 v1(190.79,52.57) 190.79,52.59 191.2,52.99 191.2,53.72 190.9,54.02 RP36.4
  IN1 w0.127: v1(145.16,184.05) 145.16,184.43 145.58,184.85 151.15,184.85 156.67,179.33 162.1,179.33 164.91,176.53 169.89,176.53 173.63,172.79 173.63,170.07 173.44,169.89 173.06,169.89 v1(172.88,170.06)
  IN2 w0.127: v1(172.88,170.06) 172.75,170.06 172.37,169.68 172.37,168.67 174.49,166.55 192.02,166.55 198.95,159.61 209.01,159.61 223.05,145.57 223.05,124.98 222.28,124.21 222.28,124.06 222.28,110.41 223.95,108.74 223.95,97.47 223.41,96.92 223.41,85.54 220.5,82.63 220.5,59.79 213.8,53.09 213.8,50.58 v1(214.72,49.66)
  BOTTOM w0.102: v1(190.79,52.57) 190.93,52.57 194.46,49.04 198.92,49.04 199.62,48.34 200.78,48.34 200.86,48.27 213.33,48.27 214.72,49.67 v1(214.72,49.66)
EC_SMB_CK2: length 225.6
  TOP w0.102: v1(152.07,107) 152.25,106.82 152.48,106.82 152.64,106.98 152.64,109.52 152.45,109.71 152.45,114.06 151.81,114.7 151.81,125.7 152.46,126.35 156.36,126.35 v1(156.43,126.42) ; UE1.79 189.99,52.5 v1(189.77,52.72) 190.17,53.12 190.17,53.47 189.9,53.74 RP36.2 ; QV15.6 178.54,91.12 178.91,90.75 182.15,90.75 182.46,90.43 182.46,89.55 182.21,89.29 175.51,89.29 171.51,93.29 170.53,93.29 170.23,93.58 170.23,94.45 v1(170.08,94.6) ; v1(198.87,155.14) 198.7,155.32 198.7,158.75 198.14,159.31 195.91,159.31 195.28,159.93 195.28,162.29 195.58,162.6 196.82,162.6 197.26,163.04 197.26,163.28 197.26,164.13 196.97,164.43 QX6.3
  IN1 w0.127: v1(198.87,155.14) 198.7,155.32 198.7,155.84 198.31,156.23 166.36,156.23 165.52,155.4 162.42,155.4 161.06,154.04 161.06,136.07 157.75,132.75 157.75,127.18 156.81,126.24 156.61,126.24 v1(156.43,126.42) ; v1(189.77,52.72) 189.6,52.88 189.36,52.88 189.04,53.19 189.04,56.68 188.81,56.91 188.81,63.94 187.66,65.1 187.66,74.86 186.17,76.35 185.94,76.35 185.86,76.27 v1(185.86,76.05)
  IN3 w0.127: v1(185.86,76.05) 185.86,76.31 186.21,76.65 186.21,77.4 174.12,89.49 174.12,94.12 172.79,95.45 170.63,95.45 170.26,95.08 170.26,94.78 v1(170.08,94.6) 170.27,94.42 170.27,94.23 170.16,94.12 169.71,94.12 164.03,99.8 164.03,100.62 159.91,104.74 155.08,104.74 153.05,106.77 152.3,106.77 v1(152.07,107)
  BOTTOM w0.102: QH1.6 147.5,115.18 148.19,115.87 149.32,115.87 151.41,113.78 151.41,107.14 151.73,106.82 151.89,106.82 v1(152.07,107)
EC_SMB_DA1: length 231
  TOP w0.102: PR715.1 172.45,169.87 v1(172.84,169.48) ; UE1.78 190.39,52.89 190.79,53.3 v1(190.79,53.55) 190.4,53.94 RP36.3 ; PR20.2 143.33,184 v3(143.83,184) 144.54,184 v1(144.58,184.04)
  IN1 w0.127: v1(172.84,169.48) 173,169.63 173.55,169.63 173.88,169.96 173.88,172.89 169.99,176.78 165.01,176.78 162.21,179.59 156.77,179.59 151.26,185.1 145.47,185.1 144.58,184.21 v1(144.58,184.04)
  IN2 w0.127: v1(214.7,52.5) 214.7,53.27 221.01,59.58 221.01,82.42 223.91,85.33 223.91,96.71 224.46,97.26 224.46,108.95 222.79,110.62 222.79,123.85 223.69,124.75 223.69,145.65 209.22,160.12 199.16,160.12 192.23,167.05 175.5,167.05 173.08,169.48 v1(172.84,169.48)
  BOTTOM w0.102: v1(190.79,53.55) 190.88,53.64 193.83,53.64 194.86,52.6 197.32,52.6 200.44,49.49 201.3,49.49 201.36,49.43 208.52,49.43 210.55,51.46 213.65,51.46 v1(214.7,52.5)
EC_SMB_DA2: length 205.6
  TOP w0.102: RP36.1 189.4,53.67 v1(189.77,53.3) 189.36,52.89 189.36,52.53 189.59,52.3 UE1.80 ; QV15.3 177.24,94.45 177.14,94.55 177,94.55 176.69,94.24 172.73,94.24 172.01,93.52 170.62,93.52 170.46,93.68 170.46,94.37 v1(170.69,94.6) ; v1(156.43,125.84) 156.14,126.12 152.56,126.12 152.04,125.61 152.04,114.8 152.68,114.15 152.68,109.81 152.87,109.62 152.87,106.89 152.57,106.59 152.25,106.59 v1(152.07,106.41) ; v1(198.29,155.14) 198.47,155.32 198.47,158.66 198.05,159.08 195.81,159.08 195.05,159.84 195.05,162.8 194.72,163.13 QX6.6
  IN1 w0.127: v1(198.29,155.14) 198.44,155.29 198.44,155.74 198.2,155.98 166.46,155.98 165.62,155.14 162.53,155.14 161.32,153.93 161.32,135.96 158,132.65 158,127.07 156.91,125.98 156.58,125.98 v1(156.43,125.84) ; v1(185.45,76.46) 185.7,76.46 185.84,76.6 186.28,76.6 187.91,74.97 187.91,65.2 189.07,64.05 189.07,57.01 189.3,56.79 189.3,53.3 189.46,53.13 189.6,53.13 v1(189.77,53.3)
  IN3 w0.127: v1(152.07,106.41) 152.17,106.51 152.95,106.51 154.97,104.48 159.81,104.48 163.78,100.51 163.78,99.69 169.61,93.86 170.26,93.86 170.52,94.12 170.52,94.43 v1(170.69,94.6) 170.69,94.63 170.51,94.82 170.51,94.98 170.73,95.2 172.69,95.2 173.87,94.02 173.87,89.38 185.95,77.3 185.95,76.76 185.66,76.46 v1(185.45,76.46)
  BOTTOM w0.102: QH1.3 149.3,113.88 151.18,112 151.18,107.04 151.64,106.59 151.89,106.59 v1(152.07,106.41)
EC_SMI#: length 122.6
  TOP w0.102: UE1.15 188.79,37.46 v1(188.8,37.48)
  IN1 w0.127: v1(188.8,37.48) 188.8,37.48 189.11,37.78 189.11,37.79 191.32,40.01 191.32,48.65 190.77,49.2 190.77,50.89 190.22,51.43 190.22,56.22 189.32,57.12 189.32,64.16 188.26,65.22 188.26,75.11 182.13,81.24 178.25,81.24 174.57,84.92 172.53,84.92 171.88,85.57 167.23,85.57 161.03,91.77 161.03,94.24 153.44,101.82 153.44,103.86 152.55,104.76 151.74,104.76 151.12,105.38 151.12,107.3 150.16,108.27 149.74,108.27 147.02,110.98 144.81,110.98 v1(144.21,110.38)
  IN2 w0.089: 137.92,114.39 136.92,115.39 135.41,115.39 v1(134.97,114.95)
  IN2 w0.127: v1(144.21,110.38) 141.74,112.85 139.46,112.85 137.92,114.39
  BOTTOM w0.089: v1(134.97,114.95) 134.97,115.11 v3(134.66,115.42) 134.52,115.56 131.58,115.56 131.36,115.34 UC1.V1
  BOTTOM w0.102: RC107.1 144.57,111.06 144.21,110.69 v1(144.21,110.38)
EC_SPI_CLK_R: length 144
  TOP w0.102: v1(180.32,37.72) 180.32,37.83 180.59,38.11 UE1.126
  IN1 w0.127: v1(180.32,37.72) 179.98,37.37 177.08,37.37 173.04,41.42 173.04,56.58 172.05,57.57 172.05,59.93 v1(172.69,60.56)
  BOTTOM w0.102: T185.1 151.6,80.21 120.46,80.21 116.87,76.62 116.87,62.89 124.97,54.79 160.73,54.79 165.56,59.62 171.75,59.62 v1(172.69,60.56)
EC_SPI_CS0#: length 142.6
  TOP w0.102: UE1.128 180.52,37.31 v1(180.34,37.13)
  IN1 w0.127: v1(172.67,61.19) 171.68,60.2 171.68,57.58 172.79,56.48 172.79,41.31 176.98,37.12 180.33,37.12 v1(180.34,37.13)
  BOTTOM w0.102: T186.1 150.02,79.98 120.56,79.98 117.1,76.52 117.1,62.98 125.07,55.01 160.63,55.01 165.47,59.85 171.39,59.85 172.67,61.14 v1(172.67,61.19)
EC_SPI_MISO_1: length 140.2
  TOP w0.102: v1(173.46,43.81) 173.94,43.33 174.26,43.33 176.71,40.88 180.15,40.88 180.52,40.51 UE1.120
  IN1 w0.127: v1(173.46,43.81) 173.29,43.98 173.29,56.69 172.39,57.59 172.39,59.6 v1(172.72,59.93)
  BOTTOM w0.102: v1(172.72,59.93) 172.19,59.4 165.66,59.4 160.82,54.56 124.88,54.56 116.64,62.79 116.64,76.71 120.37,80.44 152.5,80.44 T184.1
EC_SPI_MOSI_1: length 137.6
  TOP w0.102: UE1.119 180.45,40.91 180.25,41.11 176.81,41.11 174.08,43.84 v1(174.07,43.84)
  IN1 w0.127: v1(174.07,43.84) 173.56,44.35 173.56,56.78 172.65,57.69 172.65,59.12 v1(172.82,59.29)
  BOTTOM w0.102: T183.1 150.92,80.67 120.27,80.67 116.41,76.81 116.41,62.7 124.78,54.33 160.92,54.33 165.75,59.17 172.7,59.17 v1(172.82,59.29)
EC_TX: length 167.7
  TOP w0.102: UE1.30 194.79,34.73 v1(195.05,34.47) 195.05,33.7 v3(194.96,33.61) ; RM11.2 115.09,148.85 115.42,149.18 115.42,149.56 115.7,149.84 JMINI.49
  IN2 w0.089: 137.4,127.21 137.92,126.7
  IN2 w0.127: 137.92,126.7 143.77,120.85 143.77,118.29 144.58,117.49 148.64,117.49 151.58,114.54 151.58,112.31 152.68,111.21 152.68,110.14 153.04,109.78 153.04,108.6 153.16,108.48 153.16,105.91 158.13,100.95 160.7,100.95 182.52,79.13 182.78,79.13 183.81,78.1 183.81,77.01 186.77,74.05 186.77,66.32 186.12,65.67 186.12,63.23 187.54,61.81 187.54,55.42 186.66,54.54 186.66,45.84 188.04,44.45 188.04,41.42 187.72,41.1 187.72,37.61 190.14,35.19 194.33,35.19 v1(195.05,34.47) ; JMINI.49 115.7,150.15 116.25,149.6 116.25,148.93 116.76,148.41 127.07,148.41 137.13,138.36 137.13,127.49 137.4,127.21
ECAGND: length 169.5
  TOP w0.203: UE1.69 193.99,52.18 194.15,52.34 194.15,53.93 LE2.2
  TOP w0.254: CE7.2 202.21,34.49 202.91,35.19 202.91,36.21 201.96,37.16 201.96,38.87 204.12,41.03 204.12,42.25 202.54,43.83 202.54,48.37 201.57,49.35 200.83,49.35 CE9.1 199.85,50.33 198.43,50.33 v1(198.24,50.14) ; v1(194.99,53.21) 194.86,53.34 194.78,53.34 194.21,53.91 LE2.2 ; PH1.2 106.86,113.5 106.86,113.23 107.22,112.88 113.47,112.88 115.5,110.84 115.5,110.04 115.87,109.67 v3(115.87,104.86) 115.87,103.55 115.36,103.04 115.36,101.38 115.19,101.22 115.19,94.08 121.03,88.24 149.35,88.24 151.06,86.52 162.54,86.52 171.2,77.86 171.2,62.99 171.91,62.28 171.91,57.57 174.7,54.78 174.7,54.54 v1(174.77,54.48)
  IN3 w0.254: v1(198.24,50.14) 198.24,50.53 196.24,52.53 195.67,52.53 v1(194.99,53.21)
  BOTTOM w0.254: v1(194.99,53.21) 194.98,53.21 194.03,54.16 189.75,54.16 189.13,53.54 189.13,52.02 188.78,51.66 181.04,51.66 180.05,52.65 176.42,52.65 174.7,54.37 174.7,54.42 v1(174.77,54.48)
EDCA0_0: length 13.7
  TOP w0.102: v1(168.18,132.66) v3(167.71,133.12) 167.48,133.36 167.48,135.17 167.27,135.39
  TOP w0.127: 167.27,135.39 163.48,139.17 163.48,140 163.6,140.12 163.73,140.12 163.86,140.25 163.86,140.5 163.73,140.63 163.6,140.63 163.48,140.76 163.48,142.84 UV5.R13
  BOTTOM w0.102: v1(168.18,132.66) 167.86,132.35 UV1.C34
EDCA0_1: length 35.6
  BOTTOM w0.102: UV1.D29 171.86,132.26 172.17,132.56 172.17,132.82 171.98,133.01 171.98,133.77 171.64,134.11
  BOTTOM w0.127: 171.64,134.11 170.35,135.4 167.66,135.4 167,136.06 166.88,136.06 166.58,135.77 166.4,135.77 166.21,135.96 166.21,136.14 166.48,136.4 166.48,136.58 166.3,136.76 166.12,136.76 165.83,136.48 165.65,136.48 165.47,136.66 165.47,136.84 165.76,137.12 165.76,137.3 165.58,137.48 165.4,137.48 165.11,137.19 164.94,137.19 164.76,137.37 164.76,137.55 165.04,137.84 165.04,138.02 164.86,138.2 164.68,138.2 164.4,137.91 164.22,137.91 164.04,138.09 164.04,138.27 164.25,138.48 164.25,138.66 164.07,138.84 163.89,138.84 163.68,138.63 163.5,138.63 163.29,138.84 161.49,138.84 160.58,139.76 v3(160.58,141.46) 160.58,151.41 161.28,152.12 161.8,152.12 162.09,152.41 163.24,152.41 163.6,152.05 UV4.C2
EDCA0_2: length 30.2
  TOP w0.127: UV5.C2 173.81,152.05 174.2,152.44 175.33,152.44 175.53,152.24 176.52,152.24 177.07,151.69 177.91,151.69 178.03,151.57 178.03,151.23 177.91,151.11 177.32,151.11 177.19,150.98 177.19,150.63 177.32,150.51 177.91,150.51 178.03,150.38 178.03,150.06 177.91,149.93 v3(177.89,149.93) 177.32,149.93 177.19,149.81 177.19,149.47 177.32,149.35 177.91,149.35 178.03,149.22 178.03,139.54 v1(174.84,136.35)
  BOTTOM w0.102: 174.68,133.74 174.68,133.64 174.66,133.63 174.66,133.41 174.78,133.29 174.78,132.92 174.76,132.9 174.76,132.54 174.77,132.53 174.77,132.08 174.59,131.9 174.59,131.76 174.72,131.64 174.97,131.64 175.06,131.73 UV1.D25
  BOTTOM w0.127: v1(174.84,136.35) 175.16,136.03 175.16,135.58 174.68,135.1 174.68,133.74
EDCA0_3: length 15.3
  BOTTOM w0.102: UV1.E20 178.97,131.49 178.84,131.62 178.84,131.83 178.97,131.96 179.24,131.96 179.37,132.08 179.37,132.45 179.22,132.6 179.07,132.6 178.76,132.91 178.76,133.22 178.98,133.44 178.98,134.37 178.17,135.19
  BOTTOM w0.127: UV4.R13 173.72,143.25 174.13,142.84 174.51,142.84 174.72,142.63 v3(174.72,140.57) 174.72,140.25 177.7,137.27 177.7,135.65 178.17,135.19
EDCA1_0: length 13.4
  TOP w0.102: 183.88,135.39 183.88,135 182.05,133.16 181.82,133.16 181.45,132.79 181.45,132.41 v1(181.96,131.9)
  TOP w0.127: UV3.R13 183.99,142.78 183.99,137.82 183.88,137.71 v3(183.88,137.23) 183.88,135.39
  BOTTOM w0.102: UV1.E16 182.26,131.59 v1(181.96,131.9)
EDCA1_1: length 29.8
  BOTTOM w0.102: UV1.E12 185.46,131.51 186.01,132.06 186.01,132.48 185.96,132.53 185.96,132.84 185.97,132.85 185.97,133.4 185.71,133.66 185.71,135.39
  BOTTOM w0.127: 185.71,135.39 185.71,135.54 183.84,137.41 183.84,137.59 184,137.75 184,137.93 183.82,138.1 183.64,138.1 183.48,137.95 183.3,137.95 183.12,138.13 183.12,138.31 183.28,138.46 183.28,138.64 183.1,138.82 182.92,138.82 182.76,138.67 182.58,138.67 182.4,138.85 182.4,139.03 182.56,139.18 182.56,139.36 182.38,139.54 182.2,139.54 182.04,139.39 181.86,139.39 181.69,139.57 181.69,139.75 181.87,139.93 181.87,140.05 181.63,140.29 181.51,140.29 181.31,140.09 181.16,140.09 180.95,140.3 180.95,140.45 181.12,140.62 181.12,140.8 v3(180.72,141.2) 180.13,141.79 180.13,150.76 181.72,152.35 183.75,152.35 184.12,151.99 UV6.C2
EDCA1_2: length 39
  TOP w0.102: v1(186.88,128.69) 186.88,129.18 188.5,130.79 188.5,130.88
  TOP w0.127: UV3.C2 194.32,151.99 194.71,152.38 195.84,152.38 196.04,152.18 196.5,152.18 196.62,152.31 196.62,152.6 196.75,152.73 197.01,152.73 197.13,152.6 197.13,152.31 197.26,152.18 197.51,152.18 197.64,152.05 197.64,150.06 197.77,149.93 198.15,149.93 198.28,150.06 198.28,150.9 198.4,151.03 198.8,151.03 198.93,150.9 198.93,141.04 v3(196.38,138.49) 193,135.12 189.24,135.12 188.5,134.38 188.5,130.88
  BOTTOM w0.102: UV1.J10 187.26,128.31 v1(186.88,128.69)
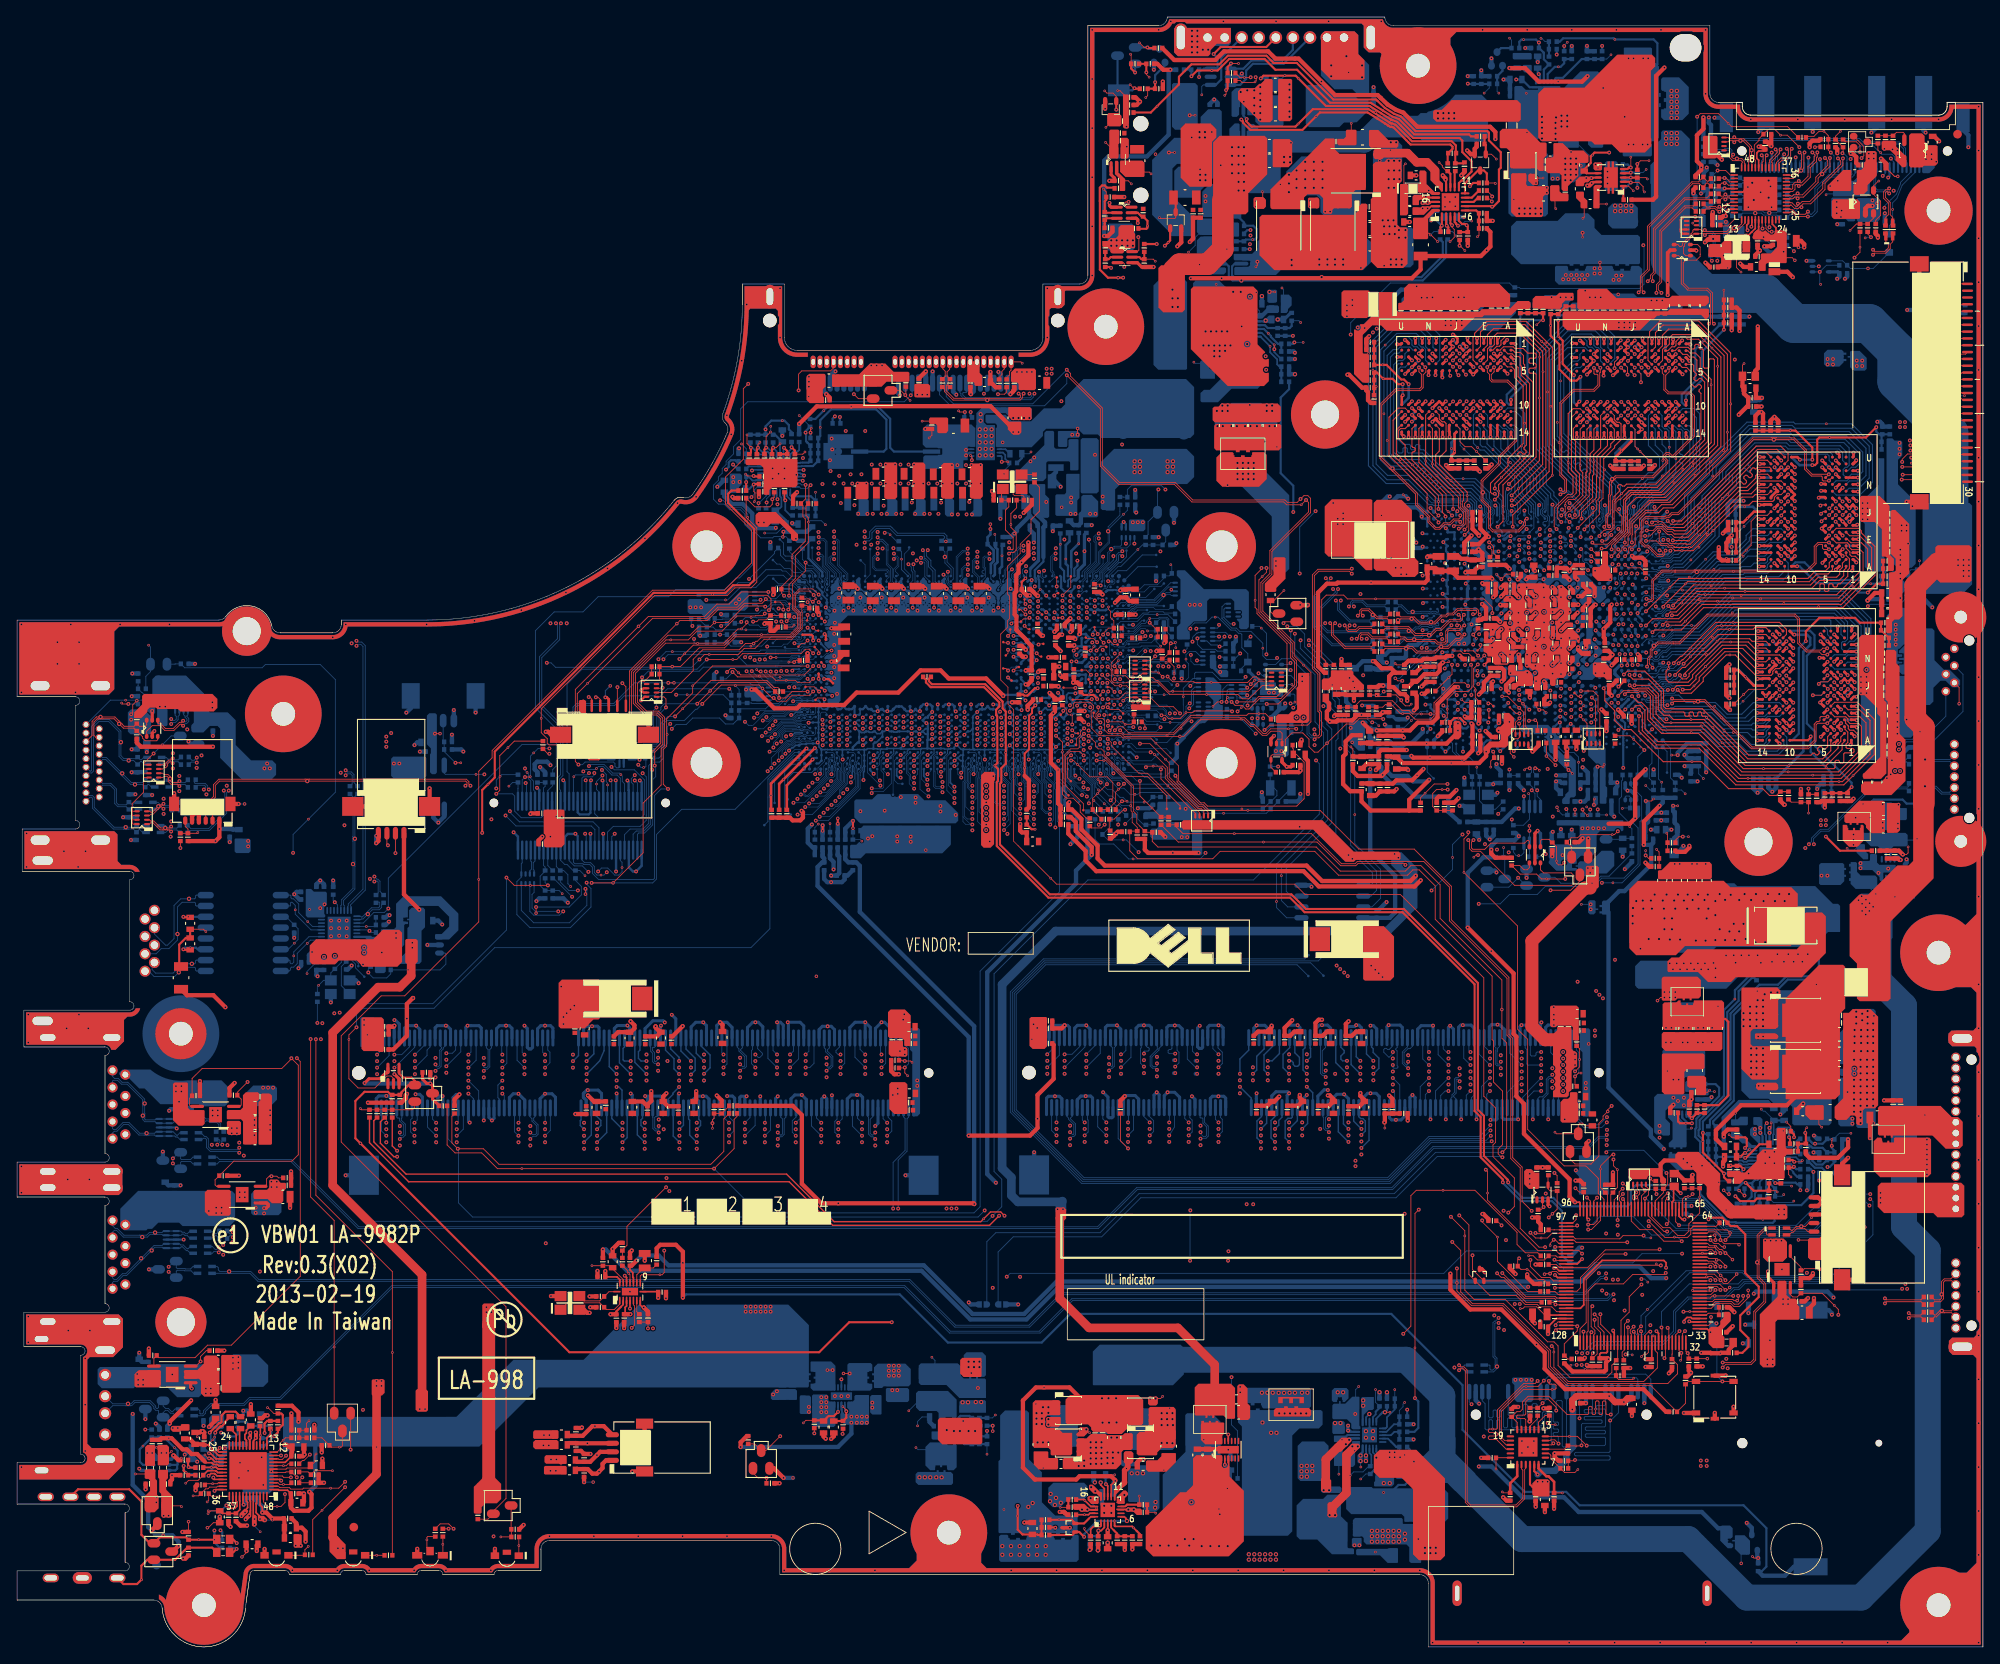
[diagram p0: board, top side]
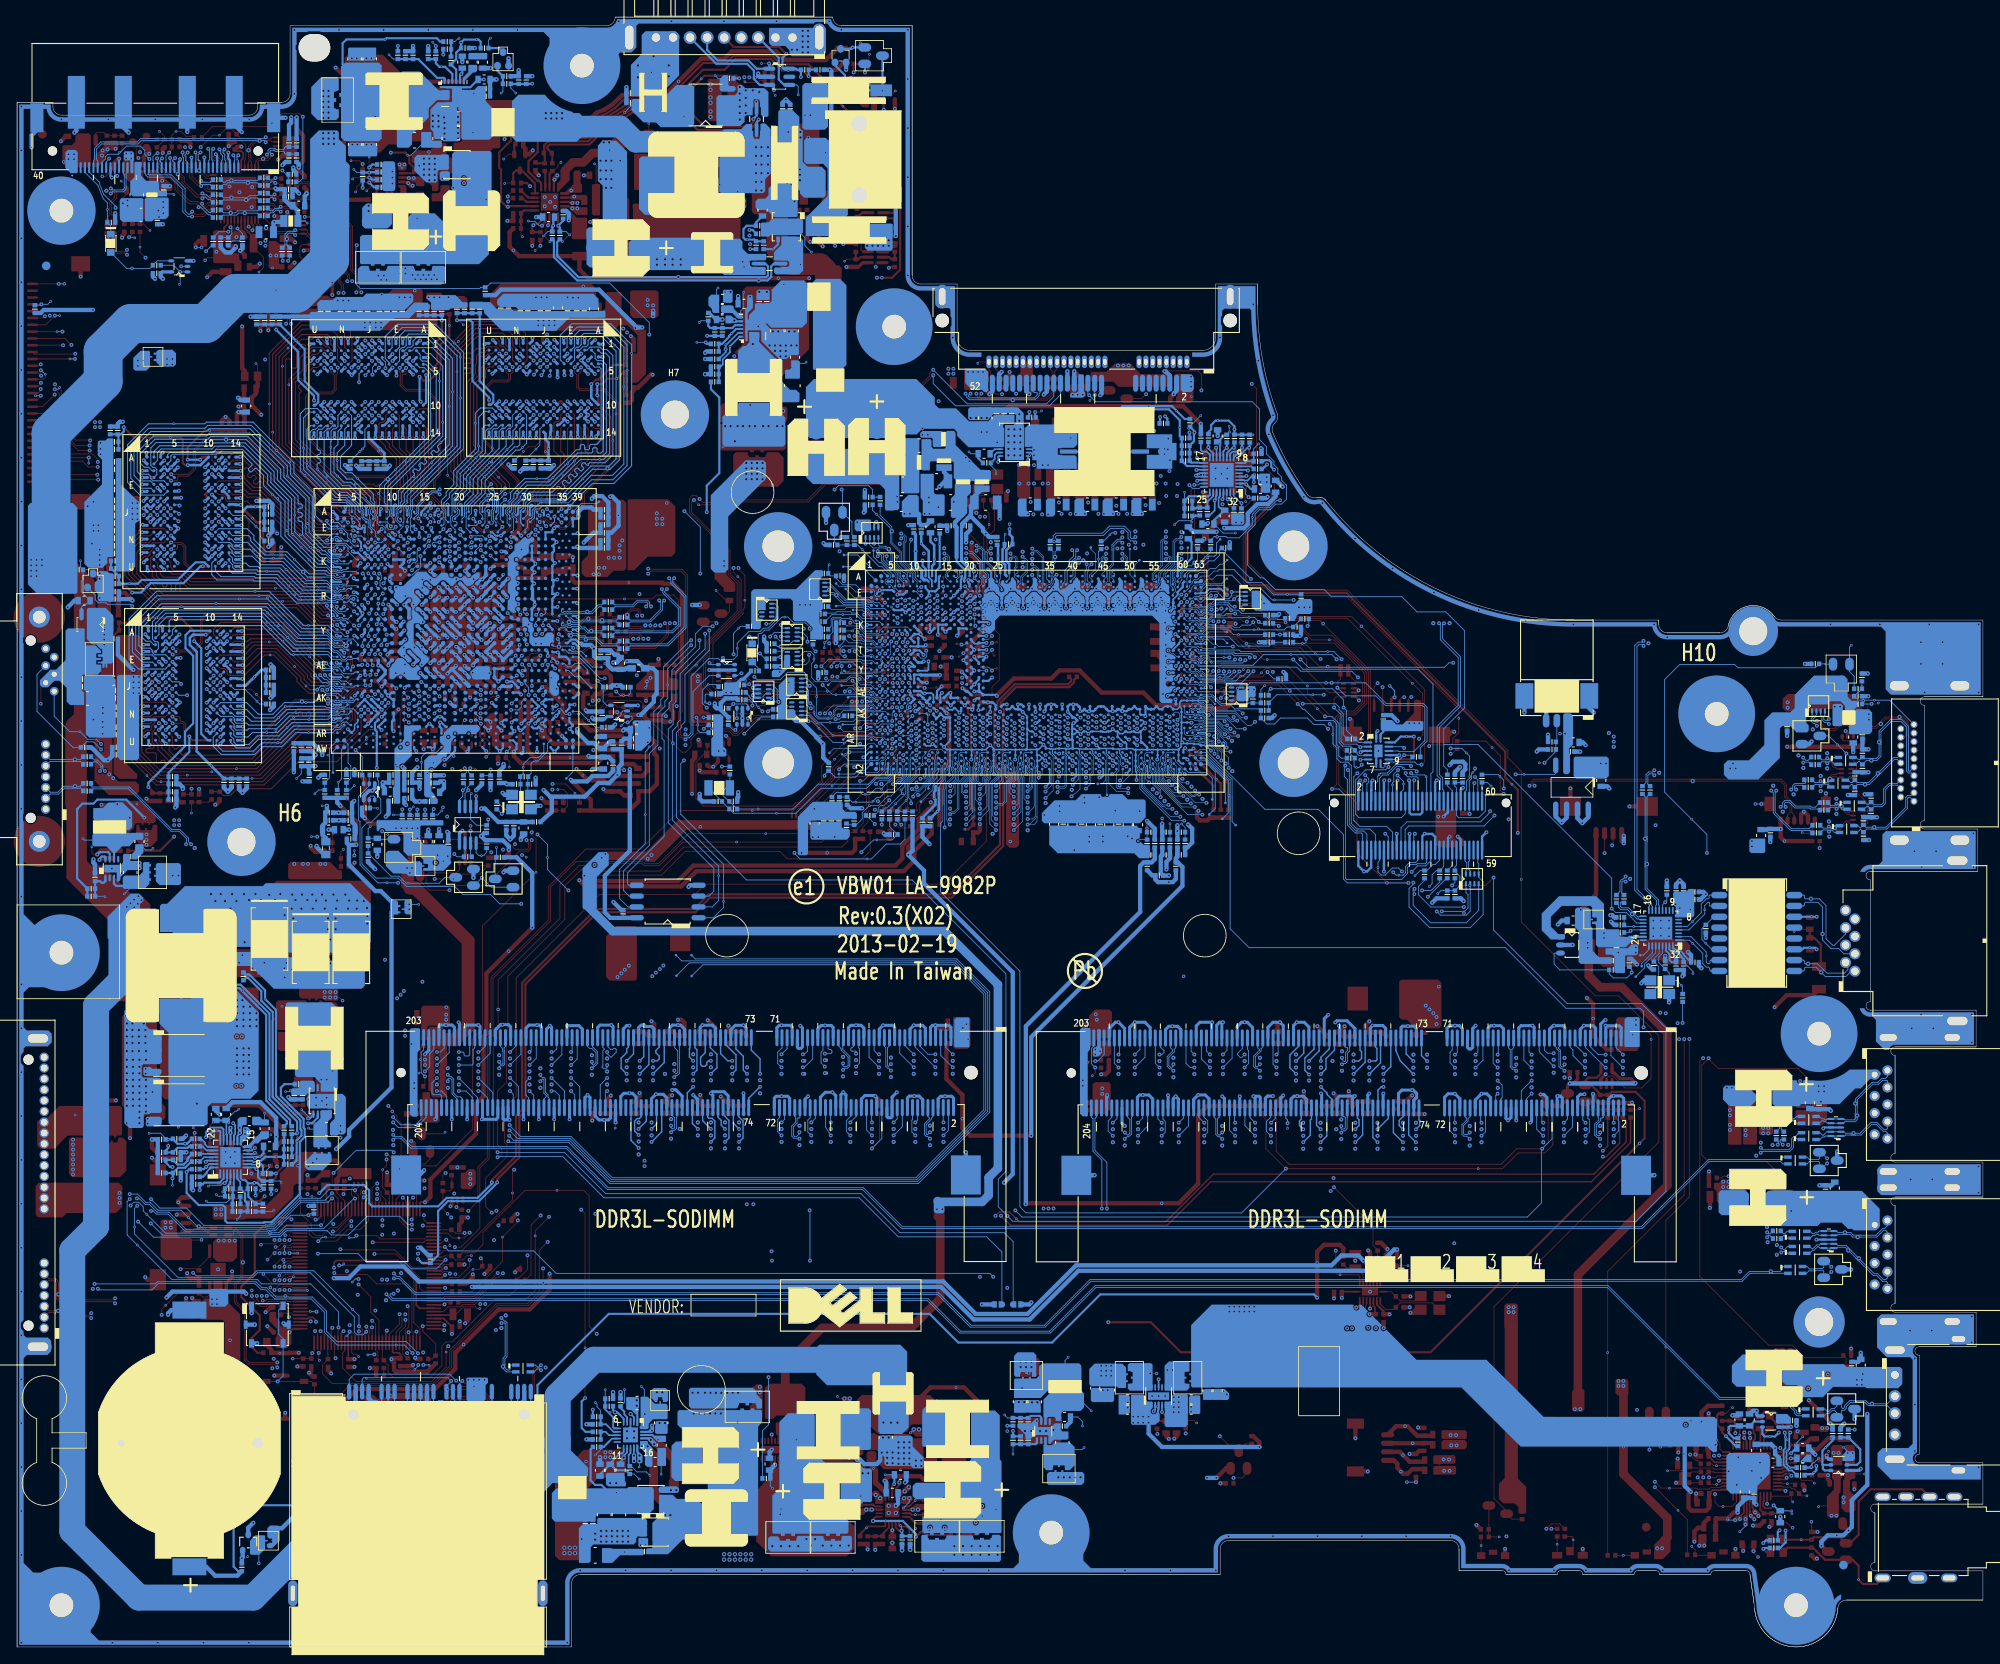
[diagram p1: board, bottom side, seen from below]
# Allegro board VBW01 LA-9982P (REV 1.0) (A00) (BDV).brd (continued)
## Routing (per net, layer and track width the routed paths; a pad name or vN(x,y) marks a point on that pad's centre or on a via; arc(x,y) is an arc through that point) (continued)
EDCA1_3: length 16
  BOTTOM w0.102: 190.15,133.77 190.15,133.74 190.14,133.73 190.14,133.4 189.96,133.22 189.96,132.89 189.97,132.88 189.97,132.38 189.48,131.89 UV1.D7
  BOTTOM w0.127: 190.15,133.77 190.15,133.81 191.73,135.39 192.54,135.39 v3(195.23,138.08) 195.23,138.68 195.1,138.8 194.97,138.8 194.85,138.93 194.85,139.18 194.97,139.31 195.1,139.31 195.23,139.44 195.23,139.69 195.1,139.82 194.97,139.82 194.85,139.95 194.85,140.2 194.97,140.33 195.1,140.33 195.23,140.45 195.23,142.57 195.02,142.78 194.64,142.78 194.23,143.18 UV6.R13
EDCB0_0: length 21.4
  TOP w0.102: v1(191.01,130.91) 191.74,130.91 192.18,131.34 192.18,131.34 192.22,131.38 192.78,131.38 193.4,130.76 193.96,130.76 194.21,130.5 194.21,130.49 194.39,130.49
  TOP w0.127: UV7.R13 205.56,138.14 205.39,138.31 203.99,138.31 203.8,138.12 203.69,138.12 203.58,138.24 203.43,138.24 203.1,137.91 203.1,137.73 203.37,137.47 203.37,137.29 203.19,137.11 203.01,137.11 202.74,137.37 202.56,137.37 202.38,137.19 202.38,137.01 202.69,136.7 202.69,136.52 202.51,136.35 202.33,136.35 202.02,136.65 201.84,136.65 v3(199.86,134.67) 195.68,130.49 194.39,130.49
  BOTTOM w0.102: UV1.F6 190.46,130.69 190.59,130.69 190.81,130.91 v1(191.01,130.91)
EDCB0_1: length 38.4
  BOTTOM w0.102: 194.39,128.1 194.2,128.1 193.7,127.6 192.74,127.6 192.43,127.29 UV1.K3
  BOTTOM w0.127: 194.39,128.1 194.67,128.1 v3(195.11,128.54) 196.94,130.38 196.94,131.84 197.07,131.97 197.35,131.97 197.48,132.1 197.48,132.35 197.35,132.48 197.11,132.48 196.98,132.61 196.98,132.86 197.11,132.99 197.35,132.99 197.48,133.11 197.48,133.37 197.35,133.5 197.11,133.5 196.98,133.62 196.98,133.88 197.11,134 197.35,134 197.48,134.13 197.48,134.95 199.51,136.99 199.51,138.09 203.35,141.93 207.7,141.93 208.04,141.6 214.25,141.6 214.67,141.17 214.68,141.17 215.94,139.91 215.94,138.77 215.48,138.31 214.98,138.31 214.57,137.91 UV8.C2
EDCB0_2: length 15.9
  BOTTOM w0.102: UV1.P3 192.16,123.99 192.53,123.99 192.74,123.79 193.01,123.79 193.14,123.91 194.39,123.91
  BOTTOM w0.127: UV8.R13 205.56,128.07 205.15,127.66 205.15,127.28 204.94,127.07 203.58,127.07 203.18,126.67 202.16,126.67 201.99,126.5 199.57,126.5 196.98,123.91 v3(195.17,123.91) 194.39,123.91
EDCB0_3: length 31
  TOP w0.127: v1(193.39,120.98) 193.76,121.35 194.46,121.35 196.86,123.76 v3(202.51,123.76) 211.16,123.76 211.29,123.88 211.29,124.53 211.42,124.66 211.69,124.66 211.82,124.53 211.82,123.88 211.94,123.76 212.2,123.76 212.32,123.88 212.32,124.53 212.45,124.66 212.71,124.66 212.83,124.53 212.83,124.41 212.96,124.28 213.21,124.28 213.34,124.41 213.34,124.53 213.47,124.66 213.69,124.66 214.55,125.53 214.55,126.26 214.75,126.46 214.75,127.59 214.36,127.98 UV7.C2
  BOTTOM w0.102: v1(193.39,120.98) 192.96,120.55 192.74,120.55 192.62,120.68 192.3,120.68 192.15,120.52 191.63,120.52 UV1.V5
EDCB1_0: length 31.8
  BOTTOM w0.102: 194.39,118.25 194,118.25 193.12,117.37 192.74,117.37 192.68,117.44 192.25,117.44 192.01,117.19 191.72,117.19 191.54,117.37 191.54,117.51 191.73,117.7 191.73,117.84 191.61,117.97 191.29,117.97 191.23,117.91 191.23,117.73 UV1.AB5
  BOTTOM w0.127: UV10.C2 214.38,117.51 214.79,117.92 215.29,117.92 215.75,118.37 215.75,119.51 214.49,120.78 214.48,120.78 213.3,121.96 v3(211.14,121.96) 201.2,121.96 198.26,119.03 197.48,118.25 194.39,118.25
EDCB1_1: length 15.1
  TOP w0.127: UV9.R13 204.97,117.91 203.36,117.91 203.05,118.21 199.52,118.21 v3(199.24,117.93) 195.47,114.16 v1(195.47,113.93)
  BOTTOM w0.102: 194.39,113.05 194.12,113.05 194.07,113 192.98,113 UV1.AH1
  BOTTOM w0.127: v1(195.47,113.93) 194.59,113.05 194.39,113.05
EDCB1_2: length 40
  TOP w0.102: v1(187.65,111.5) 188.26,112.11 189.95,112.11 190.03,112.2 191.04,112.2 191.74,111.5
  TOP w0.127: UV9.C2 214.24,107.84 214.24,107.58 214.56,107.26 214.56,106.06 214.36,105.86 214.36,105.47 214.49,105.34 215.16,105.34 215.29,105.21 215.29,104.96 215.16,104.83 214.21,104.83 214.09,104.71 214.09,103.76 213.96,103.63 213.71,103.63 213.58,103.76 213.58,103.83 213.45,103.96 213.19,103.96 213.07,103.83 213.07,103.11 212.94,102.98 v3(204.68,102.98) 202.32,102.98 197.4,107.9 192.97,107.9 191.74,109.13 191.74,111.5
  BOTTOM w0.102: v1(187.65,111.5) 187.65,111.68 UV1.AJ9
EDCB1_3: length 16.2
  BOTTOM w0.102: UV1.AM5 191.59,109.36 192.43,109.36 192.6,109.18 193.49,109.18 193.91,108.76 194.39,108.76
  BOTTOM w0.127: UV10.R13 205.37,107.74 205.01,107.38 205.01,106.93 204.77,106.69 203.33,106.69 202.81,107.21 v3(201.15,107.21) 199.87,107.21 198.32,108.76 194.39,108.76
EDID_CLK: length 28.6
  TOP w0.102: RP56.3 200.54,176.47 200.67,176.61 201.07,176.61 v1(201.26,176.43) 201.25,176.43 201.42,176.6 v2(201.98,176.6) 202.28,176.6 203.05,175.83 203.05,174.85 202.99,174.79 202.99,174.13 202.92,174.05 UX4.46
  BOTTOM w0.102: JLVDS.34 220.95,174.25 221.09,174.38 221.09,175.64 220.5,176.22 216.25,176.22 215.84,176.63 201.46,176.63 v1(201.26,176.43)
EDID_DATA: length 29.3
  TOP w0.102: RP56.4 200.54,176.97 200.67,176.84 201.08,176.84 v1(201.26,177.01) 201.25,177.01 201.42,176.83 202.37,176.83 203.28,175.92 v2(203.28,175.49) 203.28,174.75 203.22,174.69 203.22,174.13 203.32,174.03 UX4.45
  BOTTOM w0.102: JLVDS.35 221.45,174.25 221.31,174.38 221.31,175.73 220.6,176.45 216.34,176.45 215.93,176.86 201.41,176.86 v1(201.26,177.01)
EDP_AUX: length 4.9
  BOTTOM w0.102: RX40.1 206.21,171.47 205.89,171.47 205.7,171.67 v2(203.36,171.67) 202.24,171.67 RX39.2
EDP_AUX#: length 4.9
  BOTTOM w0.102: RX37.2 202.24,171.94 v2(205.29,171.94) 205.81,171.94 206,171.74 206.23,171.74 RX38.1
EDP_BIA_PWM: length 144.7
  TOP w0.102: v1(205.38,166.46) 205.32,166.52 UX4.21
  IN1 w0.127: v1(134.59,135.7) 133.24,137.05 129.33,137.05 128.33,138.05 119.45,138.05 118.19,136.79 114.75,136.79 112.78,134.82 109.61,134.82 109.21,134.42 109.21,134.21 108.68,133.68 105.25,133.68 102.99,131.42 102.49,131.42 v1(101.69,130.63)
  IN3 w0.127: v1(134.59,135.7) 135.15,135.14 148.16,135.14 149.25,134.05 151.68,134.05 158.92,141.29 158.92,152.11 160.65,153.83 160.65,157.76 161.81,158.92 188.92,158.92 190.94,160.94 203.25,160.94 205.43,163.12 205.43,165.51 205.22,165.72 205.22,166.3 v1(205.38,166.46)
  BOTTOM w0.102: v1(134.59,135.7) 134.13,136.15 130.58,136.15 130.13,135.7 RC75.2 129.66,134.81 129.63,134.83 RC81.2 ; RC72.2 103.08,129.64 v3(102.32,130.4) 102.09,130.63 v1(101.69,130.63) ; v1(205.38,166.46) 205.24,166.31 205.24,165.66 RX49.1 RX36.1
EDP_BKLCTL: length 10.6
  BOTTOM w0.076: UC1.B8 125.45,124.98 125.45,125.8 126.75,127.11 126.75,128.38 127.87,129.51 v2(127.87,130.81) 127.87,131.34
  BOTTOM w0.089: 129.25,133.14 129.25,132.71 127.87,131.34
  BOTTOM w0.102: RC81.1 129.25,133.14
EDP_COMP: length 2.9
  TOP w0.089: v1(119.65,123.24) 119.65,123.73 v3(119.91,123.99)
  TOP w0.508: v1(119.65,123.24) 119.57,123.24 119.04,123.76 119.04,123.76 118.77,124.03 RC71.2
  BOTTOM w0.254: v1(119.65,123.24) 119.27,123.61 UC1.D20
EDP_CPU_AUX: length 137.6
  TOP w0.102: CX43.1 198.15,171.64 198.01,171.64 197.83,171.46 197.83,171.31 RX25.1 197.17,171.56 196.37,171.56 191.29,166.48 191.29,161.43 190.47,160.6 190.47,159 v1(190.64,158.82)
  IN1 w0.127: v1(190.64,158.82) 190.47,158.65 190.47,158.25 189.74,157.53 165.53,157.53 164.92,156.92 157.19,156.92 154.93,154.66 154.93,152.66 158.34,149.25 158.34,140.25 153.36,135.27 149.52,135.27 148.66,134.41 138.03,134.41 136.81,133.18 132.2,133.18 131.96,133.42 129.3,133.42 127.39,135.33 120.73,135.33 119.68,134.28 116.65,134.28 113.52,131.16 110.14,131.16 108.8,129.82 105.58,129.82 103.48,127.72 102.92,127.72 102.77,127.57 102.77,127.57 v1(102.76,127.57)
  BOTTOM w0.076: v1(102.76,127.57) 102.91,127.71 103.07,127.71 103.15,127.63 103.15,126.79 102.73,126.37 102.73,125.44 103.03,125.15 UC1.B45
EDP_CPU_AUX#: length 137.5
  TOP w0.102: CX44.1 198.21,171.85 198.07,171.85 197.63,172.3 RX30.2 197.06,171.78 196.28,171.78 191.08,166.57 191.08,161.52 190.25,160.69 190.25,159.02 v1(190.05,158.82)
  IN1 w0.127: v1(190.05,158.82) 190.19,158.68 190.19,158.37 189.63,157.8 165.42,157.8 164.81,157.19 157.08,157.19 154.66,154.77 154.66,152.55 158.07,149.14 158.07,140.36 153.24,135.54 149.41,135.54 148.55,134.68 137.92,134.68 136.69,133.45 132.31,133.45 132.07,133.7 129.41,133.7 127.51,135.6 120.62,135.6 119.57,134.55 116.54,134.55 113.41,131.43 110.02,131.43 108.68,130.09 105.47,130.09 103.37,128 102.96,128 v1(102.77,128.19)
  BOTTOM w0.076: v1(102.77,128.19) 102.77,128.05 102.92,127.9 103.15,127.9 103.34,127.71 103.34,126.71 102.92,126.29 102.92,126.12 103.27,125.78 103.27,125.65 103.18,125.56 UC1.A45
EDP_CPU_HPD: length 102.1
  TOP w0.102: v1(199.3,173.11) 200.24,173.11 200.78,172.58 UX4.1
  IN3 w0.127: v1(133.76,135.71) 134.2,136.15 134.9,136.15 135.5,135.56 150.32,135.56 158.11,143.34 158.11,152.46 159.86,154.22 159.86,158.25 161.36,159.75 188.5,159.75 195.35,166.61 195.35,170.57 196.69,171.91 198.72,171.91 199.3,172.49 v1(199.3,173.11)
  BOTTOM w0.102: v1(133.76,135.71) 133.66,135.61 QC3.2 132.55,131.93 132.55,130.41 RC105.1 ; v1(199.3,173.11) 198.86,172.67 RX35.1 RX52.1
EDP_CPU_LANE_N0: length 141.3
  TOP w0.102: CX46.1 198.33,169.68 195.48,169.68 191.99,166.19 191.99,161.07 191.67,160.75 191.67,160.16 v1(191.7,160.13)
  IN1 w0.084: 101.49,129.92 101.03,129.92
  IN1 w0.127: v1(191.7,160.13) 191.6,160.23 191.6,160.55 191.26,160.89 189.1,160.89 188.02,159.81 155.98,159.81 153,156.84 153,150.76 156.42,147.34 156.42,141.27 152.35,137.21 148.69,137.21 147.76,136.27 137.09,136.27 136.1,135.28 133.57,135.28 132.31,136.54 129.12,136.54 128.12,137.54 119.66,137.54 118.4,136.28 115.68,136.28 113.2,133.81 109.57,133.81 107.62,131.85 104.67,131.85 103.13,130.32 102.1,130.32 101.71,129.92 101.49,129.92 ; 101.03,129.92 v1(100.86,130.09)
  BOTTOM w0.076: UC1.C45 102.76,124.53 102.76,124.77 102.57,124.95 102.57,126.47 102.06,126.98 102.06,128.59
  BOTTOM w0.102: 102.06,128.59 102.07,128.61 102.07,129.23 101.44,129.87 101.09,129.87 v1(100.86,130.09)
EDP_CPU_LANE_N1: length 139.3
  TOP w0.102: CX39.1 196.32,168.73 195.52,168.73 192.75,165.96 192.75,160.04 192.35,159.64 192.35,159.13 v1(192.72,158.76)
  IN1 w0.127: v1(192.72,158.76) 192.58,158.9 192.58,159.29 192.27,159.6 189.08,159.6 188.51,159.03 156.41,159.03 153.88,156.5 153.88,152.17 157.24,148.81 157.24,140.93 152.68,136.37 149.12,136.37 148.22,135.47 137.48,135.47 136.31,134.31 132.93,134.31 132.73,134.51 129.82,134.51 127.58,136.74 120.41,136.74 119.09,135.42 115.96,135.42 112.78,132.24 109.43,132.24 108.08,130.88 104.88,130.88 103.53,129.54 102.44,129.54 101.93,129.03 101.93,128.58 101.37,128.02 101.03,128.02 v1(100.86,128.19)
  BOTTOM w0.076: UC1.A47 101.74,125.72 101.74,125.83 101.8,125.89 101.93,125.89 102,125.96 102,126.07 101.89,126.19 100.61,126.19 100.23,126.57 100.23,127.72 100.52,128.01 100.68,128.01 v1(100.86,128.19)
EDP_CPU_LANE_P0: length 141.2
  TOP w0.102: v1(191.12,160.13) 191.46,160.47 191.46,160.84 191.77,161.16 191.77,166.28 195.39,169.9 198.04,169.9 CX42.1
  IN1 w0.127: v1(191.12,160.13) 191.33,160.34 191.33,160.43 191.15,160.61 189.21,160.61 188.14,159.54 156.09,159.54 153.27,156.73 153.27,150.87 156.69,147.45 156.69,141.16 152.47,136.94 148.81,136.94 147.87,136 137.2,136 136.21,135.01 133.46,135.01 132.2,136.27 129.01,136.27 128,137.27 119.78,137.27 118.51,136.01 115.79,136.01 113.31,133.53 109.68,133.53 107.73,131.58 104.78,131.58 103.24,130.05 102.21,130.05 101.82,129.65 101.06,129.65 v1(100.86,129.46)
  BOTTOM w0.076: 101.86,128.68 101.86,128.51 101.87,128.5 101.87,126.9 102.38,126.39 102.38,124.98 102.12,124.72 102.12,124.52 102.19,124.46 102.34,124.46 UC1.B46
  BOTTOM w0.102: v1(100.86,129.46) 101.06,129.65 101.35,129.65 101.86,129.14 101.86,128.68
EDP_CPU_LANE_P1: length 139.4
  TOP w0.102: CX38.1 196.5,168.96 195.44,168.96 192.54,166.05 192.54,160.13 192.14,159.73 v1(192.14,158.76)
  IN1 w0.127: v1(192.14,158.76) 192.31,158.93 192.31,159.18 192.16,159.33 189.2,159.33 188.62,158.76 156.52,158.76 154.15,156.39 154.15,152.28 157.51,148.92 157.51,140.82 152.79,136.1 149.24,136.1 148.33,135.2 137.59,135.2 136.43,134.03 132.82,134.03 132.62,134.24 129.71,134.24 127.47,136.47 120.53,136.47 119.2,135.15 116.08,135.15 112.89,131.96 109.55,131.96 108.19,130.61 104.99,130.61 103.64,129.26 102.55,129.26 102.2,128.92 102.2,128.47 101.48,127.75 101.06,127.75 v1(100.86,127.55)
  BOTTOM w0.076: UC1.B47 101.9,125.15 102.19,125.44 102.19,126.15 101.97,126.38 100.69,126.38 100.42,126.64 100.42,127.65 100.6,127.82 100.8,127.82 100.86,127.75 v1(100.86,127.55)
EDP_DISP_UTIL: length 3.6
  BOTTOM w0.102: RC72.1 103.66,128.41 v3(103.66,127.54) 103.66,126.31 UC1.A43
EDP_HPD_PANEL: length 21.3
  TOP w0.102: RX53.1 208.74,177.01 207.5,178.26 200.93,178.26 v3(200.54,178.65) 199.41,179.78 197.27,179.78 v1(196.9,179.41)
  BOTTOM w0.102: RX52.2 197.32,171.78 196.9,172.2 v1(196.9,179.41)
EDP_N0: length 4.9
  BOTTOM w0.102: RX44.1 206.25,169.66 v2(203.55,169.66) 203.26,169.66 203.02,169.89 202.24,169.89 RX43.2
EDP_N1: length 4.9
  BOTTOM w0.102: RX48.1 206.25,167.88 204.68,167.88 204.45,168.11 v2(203.71,168.11) 202.24,168.11 RX47.2
EDP_P0: length 5
  BOTTOM w0.102: RX42.1 206.19,169.92 v2(205.29,169.92) 203.37,169.92 203.13,170.16 202.24,170.16 RX41.2
EDP_P1: length 5
  BOTTOM w0.102: RX46.1 206.19,168.15 v2(205.36,168.15) 204.79,168.15 204.56,168.38 202.24,168.38 RX45.2
EN_0.675VSP: length 5.1
  BOTTOM w0.102: PR202.2 162,27.73 162.43,28.16 162.43,28.48 v3(162.62,28.67)
  BOTTOM w0.203: PC203.1 161.38,26.11 160.49,25.23 PU200.7
  BOTTOM w0.254: PC203.1 PR202.2
EN_1.35V: length 3
  BOTTOM w0.203: PU200.8 161.03,24.83 161.42,25.22 PR201.2
  BOTTOM w0.254: PC202.1 PR201.2
EN_+1.2VSP: length 3.9
  TOP w0.102: PR1103.2 190.91,172.27 v3(191.07,172.11)
  TOP w0.254: PU1100.3 v1(189.13,172.29) 189.14,172.27 PR1103.2
  BOTTOM w0.254: PC1104.1 188.78,172.03 188.93,172.18 189.03,172.18 v1(189.13,172.29)
EN_DFAN1: length 193.2
  TOP w0.102: v1(193.34,49.58) 193.59,49.83 UE1.70
  IN3 w0.127: v1(54.77,102.31) 54.77,98.63 56.1,97.29 56.1,95.68 59.3,92.49 59.3,74.74 61.44,72.6 61.44,57.1 69.51,49.03 114.7,49.03 115.77,47.95 140.75,47.95 141.21,48.41 175.85,48.41 176.46,49.03 181.76,49.03 183.26,50.53 188.01,50.53 189.63,48.91 192.7,48.91 193.34,49.56 v1(193.34,49.58)
  BOTTOM w0.102: UE3.4 50.07,102.44 50.19,102.31 v3(53.79,102.31) v1(54.77,102.31)
EN_INVPWR: length 166.5
  TOP w0.102: UE1.68 194.39,49.85 v1(194.78,49.45) ; QX1.2 216.44,175.93 216.44,174.83 v1(216.18,174.57)
  IN2 w0.127: v1(217.1,51.75) 217.86,52.52 217.86,53.34 222.91,58.39 222.91,71.3 228.81,77.2 228.81,85.95 225.82,88.95 225.82,95.92 228.81,98.91 228.81,107.29 224.95,111.16 224.95,120.7 225.85,121.6 225.85,146.25 216.79,155.3 216.79,166.51 215.61,167.69 215.61,174 v1(216.18,174.57)
  BOTTOM w0.102: v1(217.1,51.75) 216.71,52.14 216.14,52.14 215.61,51.61 215.61,51.13 v3(215.19,50.7) 213,48.51 200.98,48.51 200.92,48.57 199.72,48.57 198.84,49.45 v1(194.78,49.45)
EN_PCIE: length 1
  BOTTOM w0.102: PR1304.1 v3(198.93,65.11)
ENVDD_PCH: length 237.4
  TOP w0.089: v1(127.01,124.45) 126.85,124.61 RC87.2
  TOP w0.102: UE1.19 190.39,36.95 v1(190.33,37.01)
  IN1 w0.127: v1(128.49,127.9) 128.49,128.23 129.18,128.92 136.24,128.92 139.59,132.27 143.91,132.27 v1(150.32,125.86) 152.61,123.57 152.61,119.63 157.2,115.03 157.2,113.28 161.15,109.33 161.15,104.07 164.18,101.05 164.18,100.49 v1(169.4,95.26) ; v1(165.78,88.69) 167.87,86.6 174.33,86.6 178.68,82.26 182.7,82.26 189.3,75.66 189.3,65.62 190.37,64.55 190.37,57.51 191.86,56.02 191.86,54.99 192.56,54.29 192.56,50.7 192.41,50.56 192.41,47.54 192.08,47.21 192.08,44.71 192.42,44.37 192.42,39.33 190.85,37.75 190.85,37.4 190.46,37.01 v1(190.33,37.01)
  IN3 w0.127: v1(208.25,163.65) 208.19,163.65 205.23,160.68 191.04,160.68 189.03,158.66 161.91,158.66 160.9,157.65 160.9,153.59 159.28,151.97 159.28,141.19 152.19,134.09 v1(152.19,133.17)
  BOTTOM w0.089: v1(128.49,127.9) 128.49,127.43 127.03,125.97 127.03,125.3 126.91,125.18 126.5,124.77 UC1.C6 126.92,124.36 v1(127.01,124.45)
  BOTTOM w0.102: v1(152.19,133.17) 150.32,131.31 v1(150.32,125.86) ; v1(169.4,95.26) 168.24,94.1 v3(168.24,92.56) 168.24,91.16 v1(165.78,88.69) ; v1(208.25,163.65) 207.56,164.34 RX51.1
ENVDD_R: length 3.9
  TOP w0.102: UX1.3 217.58,167.53 RX7.1 RX8.1 215.58,166.84 v3(214.82,166.08)
F-IMAX: length 4.3
  TOP w0.102: v3(87.06,141.23) 86.83,141.01 v1(86.83,140.6)
  TOP w0.254: v1(86.83,140.6) 86.71,140.47 PR505.2
  BOTTOM w0.203: PU501.10 88.22,139.88 87.95,140.14 87.29,140.14 v1(86.83,140.6)
  BOTTOM w0.254: PR504.1 v1(86.83,140.6)
FAN_SPEED1: length 210.2
  TOP w0.102: v1(51.38,103.66) v3(52,103.66) ; v1(168.2,47.48) 169.19,46.49 169.19,41.63 170.58,40.24 174.23,40.24 179.29,35.19 179.32,35.16 179.7,34.78 179.7,32.9 181.7,30.9 193.47,30.9 194.59,32.01 194.59,33.11 CE29.1 193.96,34.34 193.99,34.36 UE1.28
  IN3 w0.127: v1(168.2,47.48) 141.36,47.48 141.07,47.19 115.45,47.19 114.82,47.83 69.47,47.83 60.64,56.66 60.64,72.29 58.51,74.42 58.51,92.16 51.38,99.29 v1(51.38,103.66)
  BOTTOM w0.102: v1(51.38,103.66) 50.05,104.99 RE50.2 CE24.1 49.94,106.23 JFAN.2
FB_1.5VSP: length 4.3
  BOTTOM w0.102: v3(113.68,22.6) PC404.2
  BOTTOM w0.254: PU400.1 110.87,23.93 111.02,23.78 PR402.1 PR403.2 PC404.2
FB_1.8VSP: length 4.7
  BOTTOM w0.102: PC604.2 220.15,88.02 v3(220.08,87.95)
  BOTTOM w0.254: PU600.1 220.04,89.81 220.25,89.61 220.5,89.61 220.68,89.79 PR602.1 221.25,89.77 PR603.2 PC604.2
FB_1.35V: length 5.3
  BOTTOM w0.102: v3(161.47,30.17) PR204.1
  BOTTOM w0.203: PU200.6 160.39,25.63 160.55,25.79 160.55,26.93 161.47,27.85 PR207.1
  BOTTOM w0.254: PR204.1 PR207.1
FB_3V: length 3.6
  TOP w0.203: PU100.4 128.23,13.99 128.54,13.68
  TOP w0.254: 128.54,13.68 128.93,13.28 PR109.2 PC102.2 PR107.2
FB_5V: length 4.3
  TOP w0.203: PU100.2 127.43,14.01 127.05,13.63 v2(126.74,13.63)
  TOP w0.254: PR104.1 126.71,13.6 v2(126.74,13.63)
  BOTTOM w0.102: v3(126.87,14.24) 126.74,14.1 v2(126.74,13.63)
  BOTTOM w0.254: v2(126.74,13.63) 126.74,13.62 126.67,13.55 PC108.1 PR106.1
FB_+1.2VSP: length 3.9
  TOP w0.254: v1(189.13,172.87) 189.13,172.79 PU1100.4
  BOTTOM w0.102: v3(190.93,173.23) 190.57,172.87 PR1107.1
  BOTTOM w0.254: PR1108.1 189.08,172.92 v1(189.13,172.87) PR1107.1
FB_PCIE: length 4.7
  TOP w0.254: PR1301.1 195.99,62.29 v1(196.29,61.99) 196.88,62.57 PR1302.2 PC1306.2
  BOTTOM w0.102: v1(196.29,61.99) 196.29,62.25 v3(197.04,63)
  BOTTOM w0.254: v1(196.29,61.99) 196.07,61.99 195.66,62.4 PU1300.6
GATEA20: length 135.2
  TOP w0.089: v1(132.23,118.53) 132.02,118.31 RC11.1
  TOP w0.102: UE1.1 183.18,35.69 183.18,37.3 183.9,38.02 183.9,43.06 185.6,44.75 192.63,44.75 v1(192.65,44.74)
  IN1 w0.084: v1(132.23,118.53) 132.78,119.07 135.33,119.07 136.85,120.59 137.53,120.59
  IN1 w0.127: 137.53,120.59 143.27,120.59 145.52,118.34 145.52,116.56 147.89,114.18 147.89,113.45 149.25,112.09 149.81,112.09 153.64,108.26 153.64,105.46 154.71,104.39 154.71,102.56 169.48,87.8 173.85,87.8 178.89,82.77 182.91,82.77 189.81,75.87 189.81,65.83 190.88,64.76 190.88,57.72 192.37,56.23 192.37,55.2 193.07,54.51 193.07,50.49 192.92,50.35 192.92,45.01 v1(192.65,44.74)
  BOTTOM w0.076: UC1.P2 130.08,118.05 131.11,118.05 131.59,118.53 v1(132.23,118.53)
  BOTTOM w0.102: v3(192.11,44.91) 192.29,44.74 v1(192.65,44.74)
GCLK_VRTC: length 3.8
  TOP w0.102: UG1.10 72.63,43.64 73.43,44.44 CG5.1 74.57,44.44 RG1.2
GENLK_CLK: length 2.5
  TOP w0.102: T80.1 170.68,116.79 v1(171.24,116.23)
  BOTTOM w0.102: v1(171.24,116.23) 171.66,115.81 UV1.AD29
GENLK_VSYNC: length 1.5
  TOP w0.102: v1(171.51,117.48) 171.51,117.18 T81.1
  BOTTOM w0.102: v1(171.51,117.48) 171.66,117.33 171.66,116.89 UV1.AC29
GFX_FB-1: length 0.9
  BOTTOM w0.254: PR821.2 204.23,52.82 PC806.1
GFX_FB-2: length 2.2
  BOTTOM w0.102: PC817.1 200.48,51.05 v3(200.3,51.22)
  BOTTOM w0.254: PR818.2 202.44,51.05 PC817.1
GPIO21_BBEN: length 1.7
  TOP w0.102: v1(183.24,111.45) 182.94,111.45 T78.1
  BOTTOM w0.102: UV1.AJ14 183.42,111.45 v1(183.24,111.45)
GPIO24_TRSTB: length 2.9
  TOP w0.102: v1(176.08,108.88) 175.62,108.42 RP47.8
  BOTTOM w0.102: UV1.AM23 176.66,109.46 v1(176.08,108.88)
GPIO25_TDI: length 5.7
  TOP w0.102: v4(175.43,104.35) 175,104.79 175,106.08 175.4,106.48 175.9,106.48 176.12,106.7 RP47.7 176.12,108.18 v1(176.04,108.26)
  BOTTOM w0.102: UV1.AN23 176.47,108.69 v1(176.04,108.26)
GPIO26_TCK: length 5.1
  TOP w0.102: RP47.5 177.12,107.6 176.76,107.96 176.76,110.32 v4(176.49,110.58) v1(176.04,111.03)
  BOTTOM w0.102: v1(176.04,111.03) 176.1,111.09 UV1.AK23
GPIO27_TMS: length 6.6
  TOP w0.102: v4(174.04,111.45) 174.7,111.45 v1(176.05,110.1) 176.55,109.6 176.55,107.77 176.62,107.71 RP47.6
  BOTTOM w0.102: v1(176.05,110.1) 175.65,110.1 UV1.AL24
GPIO28_TDO: length 2
  TOP w0.102: T79.1 175.67,109.46 v1(176.08,109.46)
  BOTTOM w0.102: v1(176.08,109.46) 176.05,109.49 UV1.AM24
GPU_B+: length 13.5
  TOP w0.508: 208.56,64.65 207.42,63.51 202.03,63.51 199.1,60.58 199.1,59.57 199.99,58.68 PR823.2
  vias: v3(210.87,77.67)
GPU_GPIO0: length 17.5
  IN3 w0.102: v1(179.7,112.14) 179.74,112.14 180.11,111.76 180.11,110.27 179.93,110.09 179.93,105.02 180.46,104.5
  IN3 w0.127: v1(181.57,98.24) 181.57,100.61 180.81,101.37 180.81,104.14 180.46,104.5
  BOTTOM w0.102: UV1.AH20 179.46,112.37 v1(179.7,112.14) ; v3(180.62,98.05) 181.12,97.55 RV75.2 181.7,98.11 v1(181.57,98.24)
GPU_GPIO1: length 17.3
  TOP w0.102: v1(182.59,98.19) v3(182.59,97.6)
  IN3 w0.102: v1(180.96,112.36) 180.43,111.83 180.43,110.06 180.18,109.8 180.18,105.48 181.19,104.47 181.19,103.69
  IN3 w0.127: 181.19,103.69 181.19,101.67 182.15,100.72 182.15,98.63 v1(182.59,98.19)
  BOTTOM w0.102: UV1.AH18 180.63,112.69 v1(180.96,112.36) ; v1(182.59,98.19) RV76.2
GPU_GPIO2: length 3.2
  TOP w0.102: v1(183.24,109.17) 183.24,109.05 v3(183.59,108.7) 184,108.29 RP60.8
  BOTTOM w0.102: UV1.AN16 182.76,108.69 v1(183.24,109.17)
GPU_GPIO6: length 109
  IN1 w0.102: v1(180.87,111.45) 178.52,111.45 177.7,110.63 175.54,110.63 175.1,111.07 173.62,111.07 171.27,113.42 169.83,113.42 169.26,113.99 169.26,115.89 169.44,116.08 169.44,116.6 168.59,117.45 168.59,118.46 167.67,119.39 167.67,120.24 166.61,121.3 164.11,121.3
  IN1 w0.127: v1(158.91,154.13) 160.54,152.49 160.54,136.44 157.17,133.07 157.17,128.45 155.73,127.02 155.73,125.51 156.26,124.98 158.64,124.98 162.33,121.3 164.11,121.3
  IN2 w0.127: v1(158.91,154.13) 158.91,155.85 162.51,159.46 168.56,159.46 171.48,162.38 171.48,181.84 v1(170.03,183.29)
  BOTTOM w0.102: v1(180.87,111.45) 181.32,111.89 UV1.AJ17 ; PR1212.1 172.55,182.79 v3(171.95,182.19)
  BOTTOM w0.254: v1(170.03,183.29) 170.06,183.26 PR1213.2 PR1214.1 172.53,183.26 PR1212.1
GPU_GPIO8: length 5.2
  TOP w0.102: RP60.6 185,107.35 184.99,107.36 v3(184.99,108.72) 184.99,110.89 v1(184.57,111.32)
  BOTTOM w0.102: v1(184.57,111.32) 185.06,111.81 UV1.AJ13
GPU_GPIO9: length 7.4
  TOP w0.102: v1(183.29,112.08) v3(184.11,112.08) 184.72,112.08 185.28,111.52 185.28,109.74 185.5,109.52 RP60.5
  BOTTOM w0.102: UV1.AH15 183.29,112.52 v1(183.29,112.08)
GPU_GPIO11: length 15.9
  TOP w0.102: v3(184.05,97.46) 183.48,98.03 v1(183.48,98.19)
  IN3 w0.102: 182.59,103.69 182.59,104.46 182.14,104.91 182.14,106.31 181.49,106.97 181.49,110.04 182.14,110.69 v1(182.15,110.69)
  IN3 w0.127: v1(183.48,98.19) 182.59,99.08 182.59,103.69
  BOTTOM w0.102: v1(182.15,110.69) 182.55,111.09 UV1.AK16 ; v1(183.48,98.19) RV81.2
GPU_GPIO12: length 15
  IN3 w0.102: 182.91,103.69 182.91,104.33 183.16,104.59 183.16,105.58 181.69,107.05 181.69,109.4 v1(182.14,109.86)
  IN3 w0.127: 182.91,103.69 182.91,101.53 183.67,100.77 183.67,98.89 v1(184.37,98.19)
  BOTTOM w0.102: RV82.2 v1(184.37,98.19) 184.27,98.19 v3(183.96,98.49) ; v1(182.14,109.86) 182.58,110.29 UV1.AL16
GPU_GPIO13: length 14.5
  IN3 w0.102: v1(182.15,109.03) 182.48,108.7 182.48,106.75 184.56,104.67 184.56,103.69
  IN3 w0.127: 184.56,103.69 184.56,99.6 185.26,98.91 v1(185.26,98.2)
  BOTTOM w0.102: UV1.AM16 182.61,109.49 v1(182.15,109.03) ; v3(186.3,97.55) RV83.2 v1(185.26,98.2)
GPU_RST#: length 15.7
  TOP w0.102: v1(162.35,113.27) 161.82,113.27 v4(161.52,113.57)
  IN3 w0.102: 164.11,115.27 165.68,115.27 166.63,116.22 167.26,116.22 168.08,117.03 170.16,117.03 v1(170.66,117.53)
  IN3 w0.127: v1(162.35,113.27) 162.35,113.67 163.94,115.27 164.11,115.27
  BOTTOM w0.102: UV13.4 161.27,110.39 161.72,110.84 RV66.1 161.72,112.65 v1(162.35,113.27) ; v1(170.66,117.53) 170.86,117.74 UV1.AA30
GPU_THERMAL_D+: length 29.5
  TOP w0.102: v1(171.17,113.89) v4(171.17,114.46)
  IN3 w0.102: v1(171.17,113.89) 171.17,113.76 172.89,112.04 172.89,111.14 173.23,110.81 173.23,107.22 174.16,106.29 175.02,106.29 176.07,105.24 176.07,104.71 175.87,104.5 175.87,103.69
  IN3 w0.127: 175.87,103.69 175.87,102.49 175.52,102.14 175.52,98.05 177.76,95.81 177.76,95.39 179.16,93.99 v1(179.16,92.97)
  BOTTOM w0.102: UV14.2 177.9,92.78 CV89.1 178.84,92.65 v1(179.16,92.97)
  BOTTOM w0.254: UV1.AF29 171.66,114.43 171.17,113.93 v1(171.17,113.89)
GPU_THERMAL_D-: length 25.6
  TOP w0.102: v1(177.25,95.69) v4(177.25,96.26)
  IN3 w0.102: 175.62,103.69 175.62,104.56 175.82,104.77 175.82,105.2 174.93,106.09 174.07,106.09 173.03,107.13 173.03,110.72 172.69,111.06 172.69,111.46 v1(171.25,112.9)
  IN3 w0.127: 175.62,103.69 175.62,102.6 174.46,101.44 174.46,98.48 v1(177.25,95.69)
  BOTTOM w0.102: CV89.2 177.25,92.78 UV14.3 v1(177.25,95.69)
  BOTTOM w0.254: v1(171.25,112.9) 171.25,112.92 171.62,113.29 UV1.AG29
GPU_VGA_B: length 3.8
  BOTTOM w0.102: UV1.AF37 165.75,114.49 165.07,113.8 164.44,113.8 T87.1
GPU_VGA_DDCCLK: length 3.4
  TOP w0.102: v1(172.49,109.87) 172.49,108.99 T90.1
  BOTTOM w0.102: v1(172.49,109.87) 171.61,109.87 171.31,110.16 171.31,110.73 170.95,111.09 UV1.AK30
GPU_VGA_DDCDAT: length 1.5
  TOP w0.102: T91.1 172.7,110.63 v1(172.43,110.63)
  BOTTOM w0.102: v1(172.43,110.63) 171.97,111.09 UV1.AK29
GPU_VGA_G: length 3.9
  BOTTOM w0.102: UV1.AE36 166.24,115.29 165.86,114.91 165.41,114.91 165,115.33 164.29,115.33 163.56,114.6 T86.1
GPU_VGA_HSYNC: length 5.4
  BOTTOM w0.102: UV1.AC36 166.12,116.89 165.75,116.52 164.57,116.52 162.94,114.88 T88.1
GPU_VGA_R: length 4.8
  BOTTOM w0.102: UV1.AD39 164.56,116.09 162.03,113.56 T85.1
GPU_VGA_VSYNC: length 2.3
  BOTTOM w0.102: UV1.AC38 165.51,116.89 165.37,116.75 164.28,116.75 T89.1
GPU_VID1: length 83.5
  TOP w0.102: v3(209.75,60.88) 209.58,60.7 v1(209.58,60.27)
  TOP w0.254: v1(209.58,60.27) 209.64,60.21 PR828.2 209.63,59 PR810.1 PR819.2
  IN3 w0.102: v1(184.49,109.92) 185.43,108.98 185.43,107.07 185.83,106.68 185.83,104.4 186.46,103.76 186.46,103.69
  IN3 w0.127: v1(209.58,60.27) 210.4,59.45 211.04,59.45 211.23,59.26 211.23,57.76 208.31,54.84 199.75,54.84 198.78,55.8 198.78,57.79 191.33,65.25 191.33,79.05 187.35,83.02 187.35,93.4 188.28,94.33 188.28,99.53 187.86,99.95 186.97,99.95 186.46,100.46 186.46,103.69
  BOTTOM w0.102: UV1.AL13 184.86,110.29 v1(184.49,109.92)
GPU_VID2: length 83.2
  IN3 w0.102: 186.72,103.69 186.72,103.83 186.08,104.46 186.08,106.71 185.64,107.15 185.64,109.4 v1(184.47,110.57)
  IN3 w0.127: 186.72,103.69 186.72,100.59 187.1,100.21 188.01,100.21 188.53,99.69 188.53,94.22 187.6,93.29 187.6,83.13 191.58,79.15 191.58,65.36 199.04,57.9 199.04,55.91 199.85,55.09 208.2,55.09 210.13,57.02 210.13,58.41 v1(210.72,59)
  BOTTOM w0.102: UV1.AK14 183.95,111.09 v1(184.47,110.57) ; v3(214.92,60.23) 213.58,60.23 213,59.65 PR826.2
  BOTTOM w0.254: PR812.1 210.26,59.22 210.27,59.22 210.42,59.07 210.42,59.07 210.48,59 v1(210.72,59) 211.61,59 212.13,59.52 PR834.2 212.2,59.51 PR826.2
GPU_VID3: length 82.7
  TOP w0.102: v1(212.69,58.75) v3(212.69,59.5)
  IN3 w0.102: v1(184.49,109.16) 185.13,108.53 185.13,106.62 185.57,106.18 185.57,104.3 186.18,103.69
  IN3 w0.127: v1(212.69,58.75) 212.58,58.75 207.69,53.86 202.28,53.86 201.74,54.39 199.83,54.39 198.53,55.7 198.53,57.69 191.07,65.15 191.07,78.94 187.09,82.92 187.09,93.5 188.02,94.44 188.02,98.29 186.18,100.14 186.18,103.69
  BOTTOM w0.102: UV1.AM13 184.82,109.49 v1(184.49,109.16)
  BOTTOM w0.254: PR807.1 210.26,58.68 210.42,58.52 211.6,58.52 PR836.2 PR835.2 213,58.19 212.69,58.5 v1(212.69,58.75)
GPU_VID4: length 83.1
  TOP w0.102: v1(183.24,109.94) 183.24,109.99 v3(183.62,110.37)
  IN3 w0.102: 185.1,104.6 185.1,105.21 183.77,106.54 183.77,109.4 v1(183.24,109.94)
  IN3 w0.127: v1(212.18,56.27) 210.46,56.27 207.79,53.6 202.17,53.6 201.64,54.14 199.73,54.14 198.28,55.59 198.28,57.58 190.82,65.04 190.82,78.84 186.84,82.81 186.84,96.21 185.95,97.1 185.95,99.64 185.68,99.92 185.68,103.49 185.1,104.06 185.1,104.6
  BOTTOM w0.102: UV1.AM14 183.69,109.49 v1(183.24,109.94)
  BOTTOM w0.254: PR809.1 210.26,57.44 210.27,57.44 210.42,57.29 210.42,57 210.86,56.56 211.6,56.56 PR838.2 PR837.2 213,56.83 212.44,56.27 v1(212.18,56.27)
GPU_VID5: length 84.3
  IN3 w0.127: v1(212.18,54.94) 211.93,55.19 209.74,55.19 207.9,53.35 202.07,53.35 201.53,53.88 199.62,53.88 198.02,55.49 198.02,57.48 190.56,64.94 190.56,78.73 186.59,82.71 186.59,96.11 185.7,96.99 185.7,98.82 184.81,99.71 184.81,104.85 183.4,106.26 183.4,108.16 182.64,108.92 182.64,110.95 v1(182.14,111.45)
  BOTTOM w0.102: UV1.AJ16 182.59,111.89 v1(182.14,111.45) ; v1(212.18,54.94) v3(212.18,54.12)
  BOTTOM w0.254: PR840.2 211.52,56.18 210.7,56.18 209.98,56.91 PR806.1 ; PR840.2 PR839.2 ; PR840.2 212.13,54.99 v1(212.18,54.94)
H_CATERR#: length 6
  TOP w0.089: v3(91.06,119.82) 90.82,119.58 RC58.2 90.08,119.74 v1(89.58,120.24)
  BOTTOM w0.076: UC1.K61 92.7,120.17 92.18,120.17 91.94,119.93 91.94,119.76 91.77,119.59 91.42,119.59 91.16,119.84 90.73,119.84 90.69,119.88 89.96,119.88 89.73,120.11 89.71,120.11 v1(89.58,120.24)
H_CPU_SVIDALRT#: length 8.8
  BOTTOM w0.076: v3(87.25,118.69) 87.85,118.69 88.5,119.34 90.96,119.34 91.46,118.84 91.77,118.84 92.06,119.13 UC1.L62
  BOTTOM w0.089: 86.76,118.69 v3(87.25,118.69)
  BOTTOM w0.102: R254.1 86.76,118.69
H_CPU_SVIDCLK: length 10.6
  BOTTOM w0.089: UC1.N63 91.54,118.49 88.41,118.49 87.27,117.35 86.76,117.35
  BOTTOM w0.102: R248.2 C5212.1 83.66,117.35 v3(86,117.35) 86.76,117.35
H_CPU_SVIDDATA: length 12.5
  BOTTOM w0.076: 88.1,119.51 91.03,119.51 91.41,119.13 UC1.L63
  BOTTOM w0.089: 86.76,119.25 87.84,119.25 88.1,119.51
  BOTTOM w0.102: R257.1 79.92,120.5 R256.2 81.56,119.58 81.89,119.25 v3(85.42,119.25) 86.76,119.25
H_CPUPWRGD: length 80
  TOP w0.102: v1(60.83,86.75) v4(60.83,86.03)
  IN3 w0.127: v1(60.83,86.75) 59.56,88.02 59.56,92.88 56.73,95.71 56.73,107.72 69.52,120.5 79.84,120.5 84.56,125.22 v1(85.78,125.22)
  BOTTOM w0.076: 91.09,126.96 91.99,126.06 92.95,126.06 93.22,125.79 93.22,125.42 93.29,125.35 93.29,124.76 93.27,124.75 UC1.C61
  BOTTOM w0.102: v1(60.83,86.75) 60.83,86.75 64.71,86.75 66.13,88.18 66.13,89.17 65.44,89.86 RC48.1 ; v1(85.78,125.22) 88.76,128.19 88.76,128.42 RC66.1 89.25,128.85 89.49,128.61 89.49,127.98 90.13,127.33 90.71,127.33 91.09,126.96
H_PROCHOT#: length 313.7
  TOP w0.089: RC67.1 88.37,120.93 ; 87.93,120.57 87.79,120.43 86.91,120.43 86.76,120.28
  TOP w0.102: PQ3.6 131.3,163.6 131.47,163.78 131.47,165.24 v1(131.41,165.3) ; v1(129.76,161.81) 129.76,162.19 129.65,162.3 PQ3.3 ; v1(130.27,169.43) 129.95,169.43 129.82,169.3 129.82,168.92 129.93,168.81 PQ2.6 ; v1(86.26,120.22) 86.69,120.22 86.76,120.28 ; 87.93,120.57 RC60.2 88.32,120.93 88.37,120.93 ; v1(179.52,50.35) v4(179.95,50.78) 180.5,51.33 RE44.2 180.48,53.48 179.67,53.48 179.43,53.72 UE2.4 179.43,55.26 CE19.1
  IN1 w0.114: v1(129.76,161.81) 131.41,163.46 v1(131.41,165.3) 131.41,166 130.27,167.14 v1(130.27,169.43)
  IN1 w0.127: v1(129.76,161.81) 129.76,161.08 130.33,160.51 130.33,140.73 128.24,138.64 119.19,138.64 117.87,137.32 114.52,137.32 112.53,135.33 109.4,135.33 108.76,134.69 96.49,134.69 96.32,134.53 91.13,134.53 90.58,133.97 v1(89.12,133.97)
  IN3 w0.127: v1(89.12,133.97) 89.12,132.54 87.72,131.14 87.72,129.3 89.37,127.65 89.37,122.83 88.93,122.39 87.5,122.39 87.38,122.27 86.38,122.27 86.02,121.91 86.02,120.48 86.26,120.24 v1(86.26,120.22) 86.26,119.95 83.31,116.99 78.94,116.99 78.2,117.73 68.94,117.73 60.79,109.58 60.79,101.5 61.45,100.83 61.45,97.69 60.07,96.31 60.07,88.97 61.35,87.69 61.35,74 64.4,70.95 64.4,55.07 69.93,49.54 114.9,49.54 115.98,48.46 140.54,48.46 141,48.92 175.62,48.92 176.24,49.54 178.71,49.54 v1(179.52,50.35)
H_PROCHOT#_R: length 2.4
  TOP w0.089: RC67.2 90.48,120.55 v1(90.2,120.27)
  BOTTOM w0.076: UC1.K63 91.52,120.01 90.79,120.01 90.53,120.27 v1(90.2,120.27)
H_THERMTRIP#: length 16.2
  BOTTOM w0.076: 89.69,126.15 90.11,126.15 90.69,125.56 91.62,125.56 92.01,125.17 92.44,125.17 92.63,124.97 92.63,124.77 92.97,124.43 92.97,124.22 93.43,123.76 UC1.D60
  BOTTOM w0.102: 89.69,126.15 89.54,126.31 87.77,126.31 86.25,124.79 84.52,124.79 83.15,123.42 v3(81.51,123.42) R2346.2
H_VCCST_PWRGD_XDP: length 4.8
  BOTTOM w0.102: JXDP1.39 63.7,92.23 64.2,91.74 64.47,91.74 65.17,91.03 RC48.2 65.95,91.03 v3(66.56,90.42)
H_VR_READY: length 18.9
  TOP w0.254: PR540.2 v1(85.45,136.57)
  IN3 w0.127: v1(85.45,136.57) 85.45,135.91 84.93,135.39 83.34,135.39 v1(82.39,134.44)
  BOTTOM w0.102: v1(82.39,134.44) 82.74,134.44 83.61,133.56 84.88,133.56 85.63,132.81 v3(85.63,132.43) 85.63,131.57 87.16,130.04 88.56,130.04 88.71,130.19 90.09,130.19 90.52,129.77 R251.1
  BOTTOM w0.203: PU501.3 86.62,136.82 86.56,136.76 86.18,136.76 85.71,137.23 PR524.2
  BOTTOM w0.254: PR524.2 v1(85.45,136.57)
HDA_SPKR: length 181.9
  TOP w0.102: DA8.3 v3(37.16,35.17) 37.16,50 34.41,52.76 v1(34.41,71.28)
  IN2 w0.089: 121.75,93.61 124.22,96.09 125.57,96.09 126.9,97.42 129.93,97.42 130.51,98 130.51,98.49 131.03,99.01 131.03,102.88 130.27,103.64 130.27,110.95 131.79,112.47 132.36,112.47 132.85,112.96 132.85,113.49 133.8,114.44 135.6,114.44 v1(136.14,114.97)
  IN2 w0.127: 121.75,93.61 112.92,84.78 59.36,84.78 45.39,70.81 34.87,70.81 v1(34.41,71.28)
  BOTTOM w0.076: v1(136.14,114.97) 135.34,115.77 131.41,115.77 131.27,115.64 130.16,115.64 129.86,115.34 UC1.V2
  BOTTOM w0.089: v1(136.14,114.97) 135.59,114.43 RC121.2
HDD_DET#: length 187.9
  TOP w0.089: RC9.1 135.08,115.47 135.6,114.95 v3(135.6,114.16) 135.6,113.55 135.6,113.55 v1(135.6,113.55)
  IN2 w0.127: v1(135.6,113.55) 135.47,113.43 135.47,111.39 136.74,110.12 136.74,101.1 140.43,97.42 140.43,75.26 142.46,73.23 142.46,45.82 v1(141.93,45.29)
  IN3 w0.084: v1(135.6,113.55) 135.38,113.33 133.27,113.33 132.54,114.06 130.52,114.06 129.19,112.72 128.62,112.72 128.25,112.36 128.25,111.79 128.04,111.58 127.66,111.58 v1(127.22,111.14)
  IN3 w0.127: v1(141.93,45.29) 170.79,45.29 171.49,45.98 178.4,45.98 179.41,44.98 180.81,44.98 181.57,44.22 184.29,44.22 185.05,44.98 188.81,44.98 189.27,45.43 193.17,45.43 197.11,41.49 197.11,38.32 197.96,37.48 199.55,37.48 200.79,38.72 211.72,38.72 212.4,39.41 215.99,39.41 226.41,49.83 226.41,55.64 JHDD.12
  BOTTOM w0.089: UC1.AG6 126.99,110.91 v1(127.22,111.14)
HDMI_HPLUG: length 10.5
  BOTTOM w0.102: RX34.1 14.19,112.74 14.18,112.72 RX15.2 14.6,111.92 14.63,111.92 CX20.1 14.63,111.01 v3(12.73,111.01) 10.94,111.01 JHDMI.19
HOST_ALERT1_R_N: length 22.8
  TOP w0.102: v1(144.59,112.88) 144.59,112.89 v3(145.03,113.34)
  IN1 w0.084: 137.68,111.26 137.15,111.26 136.23,110.35 134.74,110.35 134.51,110.12 130.74,110.12 130,110.87 130,112.04 129.57,112.47 127.03,112.47 v1(126.65,112.09)
  IN1 w0.127: v1(144.59,112.88) 144.53,112.94 143.65,112.94 141.98,111.26 137.68,111.26
  BOTTOM w0.089: v1(126.65,112.09) 126.34,112.4 UC1.AD7
  BOTTOM w0.102: v1(144.59,112.88) 144.67,112.8 RC120.2
HPOUT-L: length 15.8
  TOP w0.203: v1(22.44,20.07) 22.71,20.33 23.13,20.33 23.21,20.26 23.24,20.26 23.45,20.05 UA1.32
  IN1 w0.254: v1(22.44,20.07) 22.44,20.08 22.19,20.33 20.65,20.33 19.52,19.21 19.52,15.89 21.77,13.65 v1(23.13,13.65)
  BOTTOM w0.254: RA55.1 23.78,11.61 23.13,12.25 v3(23.13,12.57) v1(23.13,13.65)
HPOUT-R: length 13.8
  TOP w0.203: v1(23,19.85) 23.02,19.85 23.02,19.72 23.09,19.65 UA1.33
  IN1 w0.254: v1(23.84,13.68) 23.33,14.18 21.95,14.18 20.03,16.11 20.03,19 20.86,19.82 21.97,19.82 22.23,19.56 22.66,19.56 22.68,19.58 22.73,19.58 v1(23,19.85)
  BOTTOM w0.254: v1(23.84,13.68) 24.04,13.47 RA56.1
I2C0_SCL: length 7.9
  BOTTOM w0.089: RP53.4 135.2,124.78 133.25,122.82 130.6,122.82 130.4,122.63 130.07,122.63 129.88,122.44 129.37,122.44 UC1.F3
I2C0_SDA: length 7
  BOTTOM w0.076: UC1.F2 129.77,122.09 130.14,122.46 130.54,122.46 130.73,122.65 132.41,122.65
  BOTTOM w0.089: 132.41,122.65 133.32,122.65 134.95,124.28 RP53.3
I2C1_SCL_TCH_PAD: length 6.1
  BOTTOM w0.089: UC1.F1 130.38,122.22 130.74,122.22 130.98,122.47 133.51,122.47 v2(134.37,123.33) 134.67,123.63 135.13,123.63 135.27,123.78 RP53.2
I2C1_SDA_TCH_PAD: length 8.3
  BOTTOM w0.089: UC1.G4 128.7,121.75 130.38,121.75 130.64,122.01 130.83,122.01 131.07,122.25 133.6,122.25 134.52,123.18 134.76,123.42 135.13,123.42 135.27,123.28 RP53.1
ILMT_1.05V: length 4.2
  BOTTOM w0.254: PR306.1 PR304.2 147.77,152.78 146.95,153.6 146.95,153.7 v3(146.64,154.02) 146.13,154.53 PU300.3
ILMT_VDDCI: length 4.7
  BOTTOM w0.254: PR1202.1 PR1203.2 181.32,185.68 180.9,185.27 v3(180.65,185.27) 180.23,185.27 179.39,184.43 PU1200.3
IMON_CPU: length 4.5
  BOTTOM w0.102: PR501.2 88.33,142.42 v3(88.33,143.11)
  BOTTOM w0.203: PU501.13 89.42,141.02 PC508.2
  BOTTOM w0.254: PR501.2 88.83,142.14 89.67,141.3 PC508.2
IMVP_PWRGD: length 237.1
  TOP w0.102: UE1.85 v1(187.59,50.05)
  TOP w0.254: v1(54.51,95.45) 54.51,100.47 v3(55.2,101.15) 55.99,101.94 55.99,104.98 74.6,123.59 83.02,123.59 83.91,124.48 85.78,124.48 86.39,125.09 86.39,131.07 83.34,134.12 83.34,135.2 83.72,135.58 PR540.1
  IN3 w0.127: v1(187.59,50.05) 186.46,50.05 184.89,48.47 178.91,48.47 177.72,47.28 168.72,47.28 168.5,47.07 141.49,47.07 141.36,46.94 115.35,46.94 114.88,47.4 68.9,47.4 58.26,58.05 58.26,91.7 v1(54.51,95.45)
INT-SPK-L+: length 38.8
  TOP w0.203: 26.89,16.2 27.02,16.33 27.02,16.96 26.88,17.09 UA1.42
  TOP w0.508: 62.83,24.65 LA6.1
  IN1 w0.762: 27.52,16.97 28.35,17.79 30.25,17.79 31.02,17.03 40.54,17.03 42.38,18.87 48.73,18.87 54.51,24.65 60.54,24.65
  vias: v1(26.31,15.35) v1(26.72,15.77) v1(61.75,24.84) v1(62.39,24.84)
INT-SPK-L-: length 37.2
  TOP w0.203: UA1.43 27.28,17.16 27.35,17.09 27.35,15.97 27.31,15.92
  TOP w0.508: 62.77,24.01 LA5.1
  IN1 w0.762: 29.18,16.65 29.78,16.65 30.54,15.89 41.02,15.89 42.86,17.73 49.21,17.73 54.99,23.51 60.67,23.51
  vias: v1(26.79,14.96) v1(27.21,15.38) v1(61.69,23.63) v1(62.32,23.63)
INT-SPK-R+: length 37
  TOP w0.203: UA1.45 28.08,16.88 28.01,16.81 28.01,15.75 28.32,15.44
  TOP w0.508: 63.75,21.63 LA4.1
  IN1 w0.762: 30.09,14.59 41.34,14.59 43.33,16.58 49.68,16.58 54.95,21.85 60.29,21.85
  IN1 w1.016: 30,14.68 30.09,14.59
  BOTTOM w0.102: v1(29.05,14.87) v3(29.93,14.87)
  vias: v1(28.48,15) v1(62.58,21.98) v1(63.21,21.98)
INT-SPK-R-: length 39.1
  TOP w0.203: v1(27.83,15) 27.68,15.15 UA1.44
  TOP w0.508: 63.75,21 LA3.1
  IN1 w0.762: 28.48,13.6 28.63,13.45 41.81,13.45 43.8,15.44 50.15,15.44 55.42,20.71 60.23,20.71
  BOTTOM w0.102: v1(27.83,14.36) 27.83,14.17 v3(28.5,13.5)
  vias: v1(62.51,20.65) v1(63.15,20.65)
INTRUDER#: length 11.7
  BOTTOM w0.076: UC1.AU6 127.23,104.59 127.23,104.09 127.19,104.05 127.19,102.72
  BOTTOM w0.089: 131.57,100.18 131.36,99.97 v3(131.01,99.97) 130.44,99.97 129.72,100.68 129.04,100.68 128.31,101.41 128.13,101.41 127.47,102.07 127.47,102.22 127.47,102.45 127.19,102.72
  BOTTOM w0.102: RC7.2 134.38,100.18 131.57,100.18
ISOLATEB: length 3.2
  BOTTOM w0.102: UL1.20 v3(40.93,84.47) 41.87,84.47 RL35.2 RL33.2
ISUM+: length 8.2
  BOTTOM w0.203: 201.76,57.03 202.19,57.03 202.26,56.96 202.27,56.96 202.34,56.88 202.72,56.88 202.85,57.01 PU800.10
  BOTTOM w0.254: PR829.2 199.1,59.27 PC819.1 PC820.1 PR827.1 ; PR827.1 PR816.1 ; PR827.1 199.13,57.47 v3(200.02,57.47) 201.32,57.47 201.76,57.03
ISUM-: length 4.2
  BOTTOM w0.102: PR825.1 201.54,55.51 200.84,56.21 v3(200.84,56.46)
  BOTTOM w0.203: PU800.9 202.92,56.61 202.86,56.55 202.12,56.55 202.02,56.65
  BOTTOM w0.254: 202.02,56.65 201.84,56.65 201.59,56.4 PR825.1
ISUM-1: length 32.2
  TOP w0.254: PC821.2 200.5,54.62 200.05,55.07 v1(200.05,55.51) 197.58,57.99 v3(197.58,59.28) v1(197.58,60.27)
  BOTTOM w0.254: PR825.2 v1(200.05,55.51) ; PR827.2 PC820.2 PC819.2 198.21,59.27 PR830.2 197.72,60.13 v1(197.58,60.27) 197.58,61.61 200.43,64.46 200.43,74.43 201.77,75.77 201.77,76.89 203.34,78.46 203.57,78.46 PH800.2
ISUM-2: length 26.1
  BOTTOM w0.254: PH800.1 203.62,78.84 203.18,78.84 201.33,76.99 v3(201.33,75.96) 200.05,74.69 200.05,64.62 197.2,61.76 197.2,60.72 197.07,60.59 197.07,59.95 197.64,59.38 197.64,57.03 198.09,56.59 PR816.2
JACK_PLUG#: length 28.9
  TOP w0.102: RA1.2 30.1,27.37 29.41,28.06 v3(29.35,28.06)
  TOP w0.254: RA1.2 30.97,27.37 31.14,27.19 31.14,26.05 30.69,25.59 RA4.1 30.57,25.16 v1(30.13,24.71)
  IN1 w0.254: JHP.5 15.69,21.54 19.14,21.54 19.46,21.85 20.56,21.85 20.91,22.21 21.39,22.21 22.06,21.54 23.28,21.54 25.11,23.37 28.78,23.37 v1(30.13,24.71)
  BOTTOM w0.254: v1(30.13,24.71) 28.97,23.56 RA3.1
JACK_SENSE#: length 14
  TOP w0.254: v1(29.01,25.08) 29.01,26.2 29.32,26.5 RA51.2 RA4.2
  IN3 w0.254: v1(29.01,25.08) 29.24,25.31 29.24,26.37 28.49,27.13 25.49,27.13 23.92,25.55 v1(23.92,25.13)
  BOTTOM w0.254: QA5.3 25.85,24.95 25.58,24.68 v3(24.98,24.68) 24.37,24.68 v1(23.92,25.13)
KB_CAPS_PWR: length 3.1
  TOP w0.102: v1(227.55,157.42) JKB.4
  BOTTOM w0.102: v3(226.45,157.76) 226.8,157.42 v1(227.55,157.42) 227.66,157.31 RE60.2
KB_DET#: length 31.3
  IN3 w0.084: v1(126.97,107.77) 127.41,108.21 127.41,108.66 128.95,110.2 128.95,110.63 129.23,110.9 129.51,110.9 131.35,112.74 134.31,112.74 135.22,111.83 137.82,111.83
  IN3 w0.127: 137.82,111.83 142.79,111.83 143.81,110.81 145.17,110.81 145.86,110.12 v1(149.57,110.12)
  BOTTOM w0.089: v1(126.97,107.77) 127.25,107.48 UC1.AN5
  BOTTOM w0.102: v1(149.57,110.12) 150.09,110.64 150.09,112.16 v3(149.41,112.85) 148.44,112.85 RC103.1
KB_LED_PWM: length 2.2
  TOP w0.102: v3(190.38,34.05) 190.66,34.33 190.99,34.33 191.19,34.53 UE1.21
KB_RST#: length 148.4
  TOP w0.102: UE1.2 v1(183.59,36.97)
  IN1 w0.127: v1(147.67,115.96) 148.43,115.2 148.43,113.63 149.46,112.6 150.02,112.6 154.15,108.47 154.15,105.67 155.22,104.6 155.22,102.78 169.69,88.31 174.06,88.31 179.1,83.27 183.12,83.27 190.31,76.08 190.31,66.04 191.39,64.96 191.39,57.93 192.88,56.44 192.88,55.41 194.05,54.24 194.05,54.07 194.31,53.81 194.31,50.51 194.11,50.31 194.11,40.44 191.42,37.75 v1(191.42,37.73)
  IN3 w0.084: v1(127.85,115.89) 128.35,115.39 131.2,115.39 132.05,114.55 136.87,114.55 137.82,113.6
  IN3 w0.127: v1(191.42,37.73) 190.97,37.29 190.97,37 190.3,36.33 184.22,36.33 v1(183.59,36.97) ; 137.82,113.6 138.09,113.33 141.16,113.33 142.97,115.14 143.94,115.14 144.23,115.42 146.87,115.42 147.41,115.96 v1(147.67,115.96)
  BOTTOM w0.089: v1(127.85,115.89) 128.33,115.41 UC1.V4
  BOTTOM w0.102: v1(147.67,115.96) 147.48,115.77 146.45,115.77 146,116.22 v3(146,117.1) 146,117.69 144.61,119.07 143.28,119.07 142.9,119.45 142.36,119.45 141.22,120.59 141.22,120.62 141.21,120.63 141.21,121.96 141.57,122.32 RP43.8
KSI0: length 132.1
  TOP w0.102: UE1.55 198.4,46.11 v1(198.47,46.18) ; JKB.22 225.07,143.02 223.56,141.51 221.89,141.51 v1(221.83,141.46)
  IN3 w0.127: v1(198.47,46.18) 198.47,46.19 199.4,47.13 216.3,47.13 220.59,51.41 220.59,60.93 221.23,61.57 221.23,76.1 218.76,78.56 218.76,84.27 220.1,85.61 220.1,88.17 217.38,90.89 215.88,90.89 214.79,91.99 214.79,99.62 215.99,100.83 215.99,101.66 219.65,105.32 219.65,121.61 219.77,121.73 219.77,134.42 220.78,135.42 220.78,136.16 221.63,137.02 221.63,138.81 221.31,139.13 221.31,140.93 v1(221.83,141.46)
  BOTTOM w0.102: v1(198.47,46.18) v3(197.5,46.18)
KSI1: length 130.3
  TOP w0.102: UE1.56 198.16,46.51 198.24,46.58 198.64,46.58 v1(199.05,46.18) ; v1(221.9,140.28) 223.23,140.28 224.37,141.42 JKB.24
  IN3 w0.127: v1(221.9,140.28) 221.77,140.28 221.57,140.08 221.57,139.27 221.89,138.96 221.89,136.17 220.03,134.31 220.03,121.4 220.62,120.82 220.62,116.77 219.91,116.06 219.91,105.22 216.69,101.99 216.69,100.64 215.95,99.9 215.95,96.9 215.96,96.89 215.96,94.39 215.97,94.38 215.97,92.81 217.2,91.58 217.98,91.58 220.35,89.21 220.35,85.5 219.03,84.18 219.03,78.67 221.48,76.22 221.48,61.47 220.84,60.83 220.84,51.3 216.4,46.86 199.72,46.86 199.05,46.19 v1(199.05,46.18)
  BOTTOM w0.102: v1(199.05,46.18) v3(199.05,46.99)
KSI2: length 130.3
  TOP w0.102: v1(199.63,46.18) 199,46.81 198.26,46.81 198.16,46.91 UE1.57 ; v1(222,139.45) 222.02,139.43 227.07,139.43 227.47,139.82 JKB.26
  IN3 w0.127: v1(199.63,46.18) 199.63,46.19 200.04,46.6 216.51,46.6 221.09,51.18 221.09,60.72 221.73,61.36 221.73,76.33 219.29,78.78 219.29,84.08 220.61,85.4 220.61,89.31 218.09,91.83 217.31,91.83 216.22,92.91 216.22,94.49 216.21,94.5 216.21,99.74 221.58,105.1 221.58,109.16 220.9,109.84 220.9,110.24 220.17,110.96 220.17,115.95 220.88,116.66 220.88,120.92 220.29,121.51 220.29,134.2 222.17,136.08 222.17,139.27 v1(222,139.45)
  BOTTOM w0.102: v1(222,139.45) v3(222,138.79)
KSI3: length 134.9
  TOP w0.102: JKB.23 224.85,142.22 223.5,140.88 v1(221.9,140.88) ; v4(201.04,45.41) 200.28,46.18 v1(200.22,46.18) 199.81,46.59 199.55,46.59 199.09,47.04 198.4,47.04 198.13,47.31 UE1.58
  IN3 w0.127: v1(221.9,140.88) 222.21,140.88 222.64,140.44 222.64,131.35 221.16,129.87 221.16,116.15 220.44,115.43 220.44,111.07 221.16,110.35 221.16,109.95 221.84,109.27 221.84,102.56 219.82,100.54 217.78,100.54 216.48,99.24 216.48,94.25 216.48,94.24 216.48,93.22 216.48,93.22 216.48,93.01 217.41,92.09 219.13,92.09 220.86,90.35 220.86,85.29 219.59,84.02 219.59,78.85 221.99,76.44 221.99,61.27 221.35,60.62 221.35,51.06 216.46,46.18 v1(200.22,46.18)
KSI4: length 129
  TOP w0.102: v4(200.09,46.89) 200.05,46.92 199.79,46.92 199.42,47.29 198.88,47.29 v1(198.47,47.71) UE1.59 ; JKB.27 222.73,139.02 222.07,138.36 v1(220.95,138.36)
  IN3 w0.127: v1(220.95,138.36) 218.72,136.14 218.72,122.16 218.6,122.04 218.6,105.76 213.74,100.89 213.74,91.6 215.46,89.88 216.96,89.88 219.08,87.75 219.08,86.09 217.72,84.74 217.72,84.35 217.72,84.34 217.72,78.13 220.21,75.64 220.21,62 219.57,61.36 219.57,51.88 215.87,48.17 210.33,48.17 209.66,48.84 199.54,48.84 198.47,47.77 v1(198.47,47.71)
KSI5: length 129.5
  TOP w0.102: v1(220.93,138.94) 220.93,139.25 221.56,139.87 226.17,139.87 226.91,140.62 JKB.25 ; UE1.60 198.3,48.11 198.48,48.28 v4(198.97,48.28) 199.05,48.21 v1(199.05,47.71)
  IN3 w0.127: v1(199.05,47.71) 199.05,47.77 199.86,48.58 209.57,48.58 210.23,47.91 215.98,47.91 219.82,51.76 219.82,61.25 220.46,61.89 220.46,75.75 217.98,78.24 217.98,84.63 219.34,85.99 219.34,87.86 217.06,90.13 215.57,90.13 214,91.69 214,100.78 218.87,105.65 218.87,121.94 218.99,122.06 218.99,136.03 220.89,137.94 221.12,137.94 221.37,138.18 221.37,138.53 220.96,138.94 v1(220.93,138.94)
KSI6: length 129.8
  TOP w0.102: v1(221,137.44) 226.2,137.44 226.98,138.22 JKB.28 ; v4(201.82,47.17) 201.7,47.28 200.06,47.28 v1(199.63,47.71) 199.63,48.2 199.17,48.66 198.23,48.66 198.07,48.51 UE1.61
  IN3 w0.127: v1(221,137.44) 220.77,137.44 219.25,135.92 219.25,121.95 219.13,121.83 219.13,105.54 214.26,100.68 214.26,92.44 214.27,92.43 214.27,91.78 215.67,90.38 217.17,90.38 219.59,87.96 219.59,85.82 218.24,84.47 218.24,78.35 220.72,75.87 220.72,61.78 220.08,61.15 220.08,51.64 216.09,47.65 210.12,47.65 209.45,48.32 200.17,48.32 199.63,47.79 v1(199.63,47.71)
KSI7: length 127.9
  TOP w0.102: UE1.62 200.41,48.91 v4(200.76,48.55) 200.76,48.25 v1(200.22,47.71) ; v1(220.88,136.87) 226.55,136.87 227.1,137.42 JKB.29
  IN3 w0.127: v1(200.22,47.71) 200.58,48.06 209.35,48.06 210.02,47.39 216.19,47.39 220.33,51.53 220.33,61.04 220.97,61.68 220.97,75.99 218.5,78.45 218.5,83.45 218.51,83.46 218.51,84.38 219.84,85.71 219.84,88.07 217.27,90.64 215.78,90.64 214.52,91.89 214.52,99.73 215.73,100.94 215.73,101.77 219.39,105.43 219.39,121.72 219.51,121.84 219.51,134.53 220.51,135.53 220.51,136.5 v1(220.88,136.87)
KSO0: length 137.9
  TOP w0.102: UE1.39 198.57,39.71 199.14,40.28 200.84,40.28 201.2,39.93 201.87,39.93 202.89,40.94 v1(202.89,41.16) v4(202.89,41.81) ; v1(227.62,150.38) 227.78,150.22 JKB.13
  IN3 w0.127: v1(202.89,41.16) 203.08,40.97 205.67,40.97 206.5,41.79 216.16,41.79 224.84,50.48 224.84,77.66 222.47,80.04 222.47,82.85 224.72,85.1 224.72,110.47 224.04,111.14 224.04,122.07 224.62,122.65 224.62,128.89 226.41,130.67 226.41,149.07 227.62,150.29 v1(227.62,150.38)
KSO1: length 139.7
  TOP w0.102: UE1.40 198.64,40.11 199.05,40.51 200.94,40.51 201.26,40.19 201.74,40.19 202.3,40.75 v1(202.3,41.16) ; v1(227.61,149.68) 227.1,149.17 227.1,148.85 227.33,148.62 JKB.15
  IN3 w0.127: v1(202.3,41.16) 202.3,41.14 202.73,40.71 205.79,40.71 206.61,41.53 216.27,41.53 225.11,50.37 225.11,75.65 227.93,78.48 227.93,90.39 224.98,93.34 224.98,110.57 224.3,111.25 224.3,121.06 224.89,121.65 224.89,128.78 226.67,130.57 226.67,148.72 227.61,149.67 v1(227.61,149.68)
  BOTTOM w0.102: v3(227.09,149.22) 227.55,149.68 v1(227.61,149.68)
KSO2: length 137.6
  TOP w0.102: v1(227.59,149.05) 227.96,149.42 JKB.14 ; UE1.41 198.72,40.51 198.95,40.74 201.1,40.74 201.23,40.61 v4(201.6,40.61) 201.72,40.73 v1(201.72,41.16)
  IN3 w0.127: v1(227.59,149.05) 226.93,148.39 226.93,130.46 225.15,128.68 225.15,121.54 224.56,120.95 224.56,111.36 225.24,110.68 225.24,93.45 228.2,90.5 228.2,78.37 225.37,75.54 225.37,50.26 215.56,40.45 212.12,40.45 212.1,40.44 211.91,40.44 211.21,39.74 204.14,39.74 203.43,40.45 202.41,40.45 201.72,41.14 v1(201.72,41.16)
KSO3: length 136.7
  TOP w0.102: v1(227.61,148.21) 227.61,148.1 227.89,147.82 JKB.16 ; UE1.42 198.43,40.91 198.68,41.16 v4(198.97,41.16) v1(201.13,41.16)
  IN3 w0.127: v1(227.61,148.21) 227.19,147.79 227.19,130.35 225.41,128.57 225.41,121.43 224.82,120.85 224.82,111.47 225.5,110.79 225.5,93.56 228.46,90.6 228.46,78.26 225.63,75.43 225.63,50.15 215.67,40.19 212.5,40.19 212.49,40.18 212.02,40.18 211.32,39.48 204.04,39.48 203.34,40.18 203.3,40.18 203.28,40.19 202.09,40.19 201.13,41.14 v1(201.13,41.16)
KSO4: length 137.5
  TOP w0.102: UE1.43 198.5,41.31 v1(199.05,41.86) ; JKB.20 226.08,144.62 225.45,145.25 225.45,146.94 225.96,147.46 v1(225.98,147.46)
  IN3 w0.127: v1(199.05,41.86) 199.05,41.87 199.46,42.28 200.69,42.28 200.76,42.35 215.99,42.35 224.32,50.69 224.32,77.45 221.94,79.83 221.94,83.07 224.19,85.32 224.19,110.25 223.52,110.93 223.52,122.28 224.1,122.87 224.1,129.11 225.32,130.33 225.43,130.44 225.43,146.88 225.98,147.43 v1(225.98,147.46)
  BOTTOM w0.102: v3(225.4,147.66) 225.61,147.46 v1(225.98,147.46)
KSO5: length 140.4
  TOP w0.102: v1(198.47,41.86) 198.32,41.71 UE1.44 ; v1(225.96,148.04) 225.22,147.3 225.22,145.15 226.55,143.82 JKB.21
  IN3 w0.127: v1(225.96,148.04) 225.86,147.94 225.86,147.94 225.17,147.24 225.17,130.55 224.95,130.33 224.95,130.33 223.84,129.22 223.84,122.98 223.25,122.39 223.25,110.82 223.93,110.14 223.93,85.43 221.68,83.17 221.68,79.72 224.07,77.33 224.07,60.46 223.38,59.78 223.38,50.12 215.88,42.61 200.53,42.61 200.5,42.58 199.17,42.58 198.47,41.87 v1(198.47,41.86)
  BOTTOM w0.102: v1(198.47,41.86) 196.43,41.86 v3(196.37,41.8)
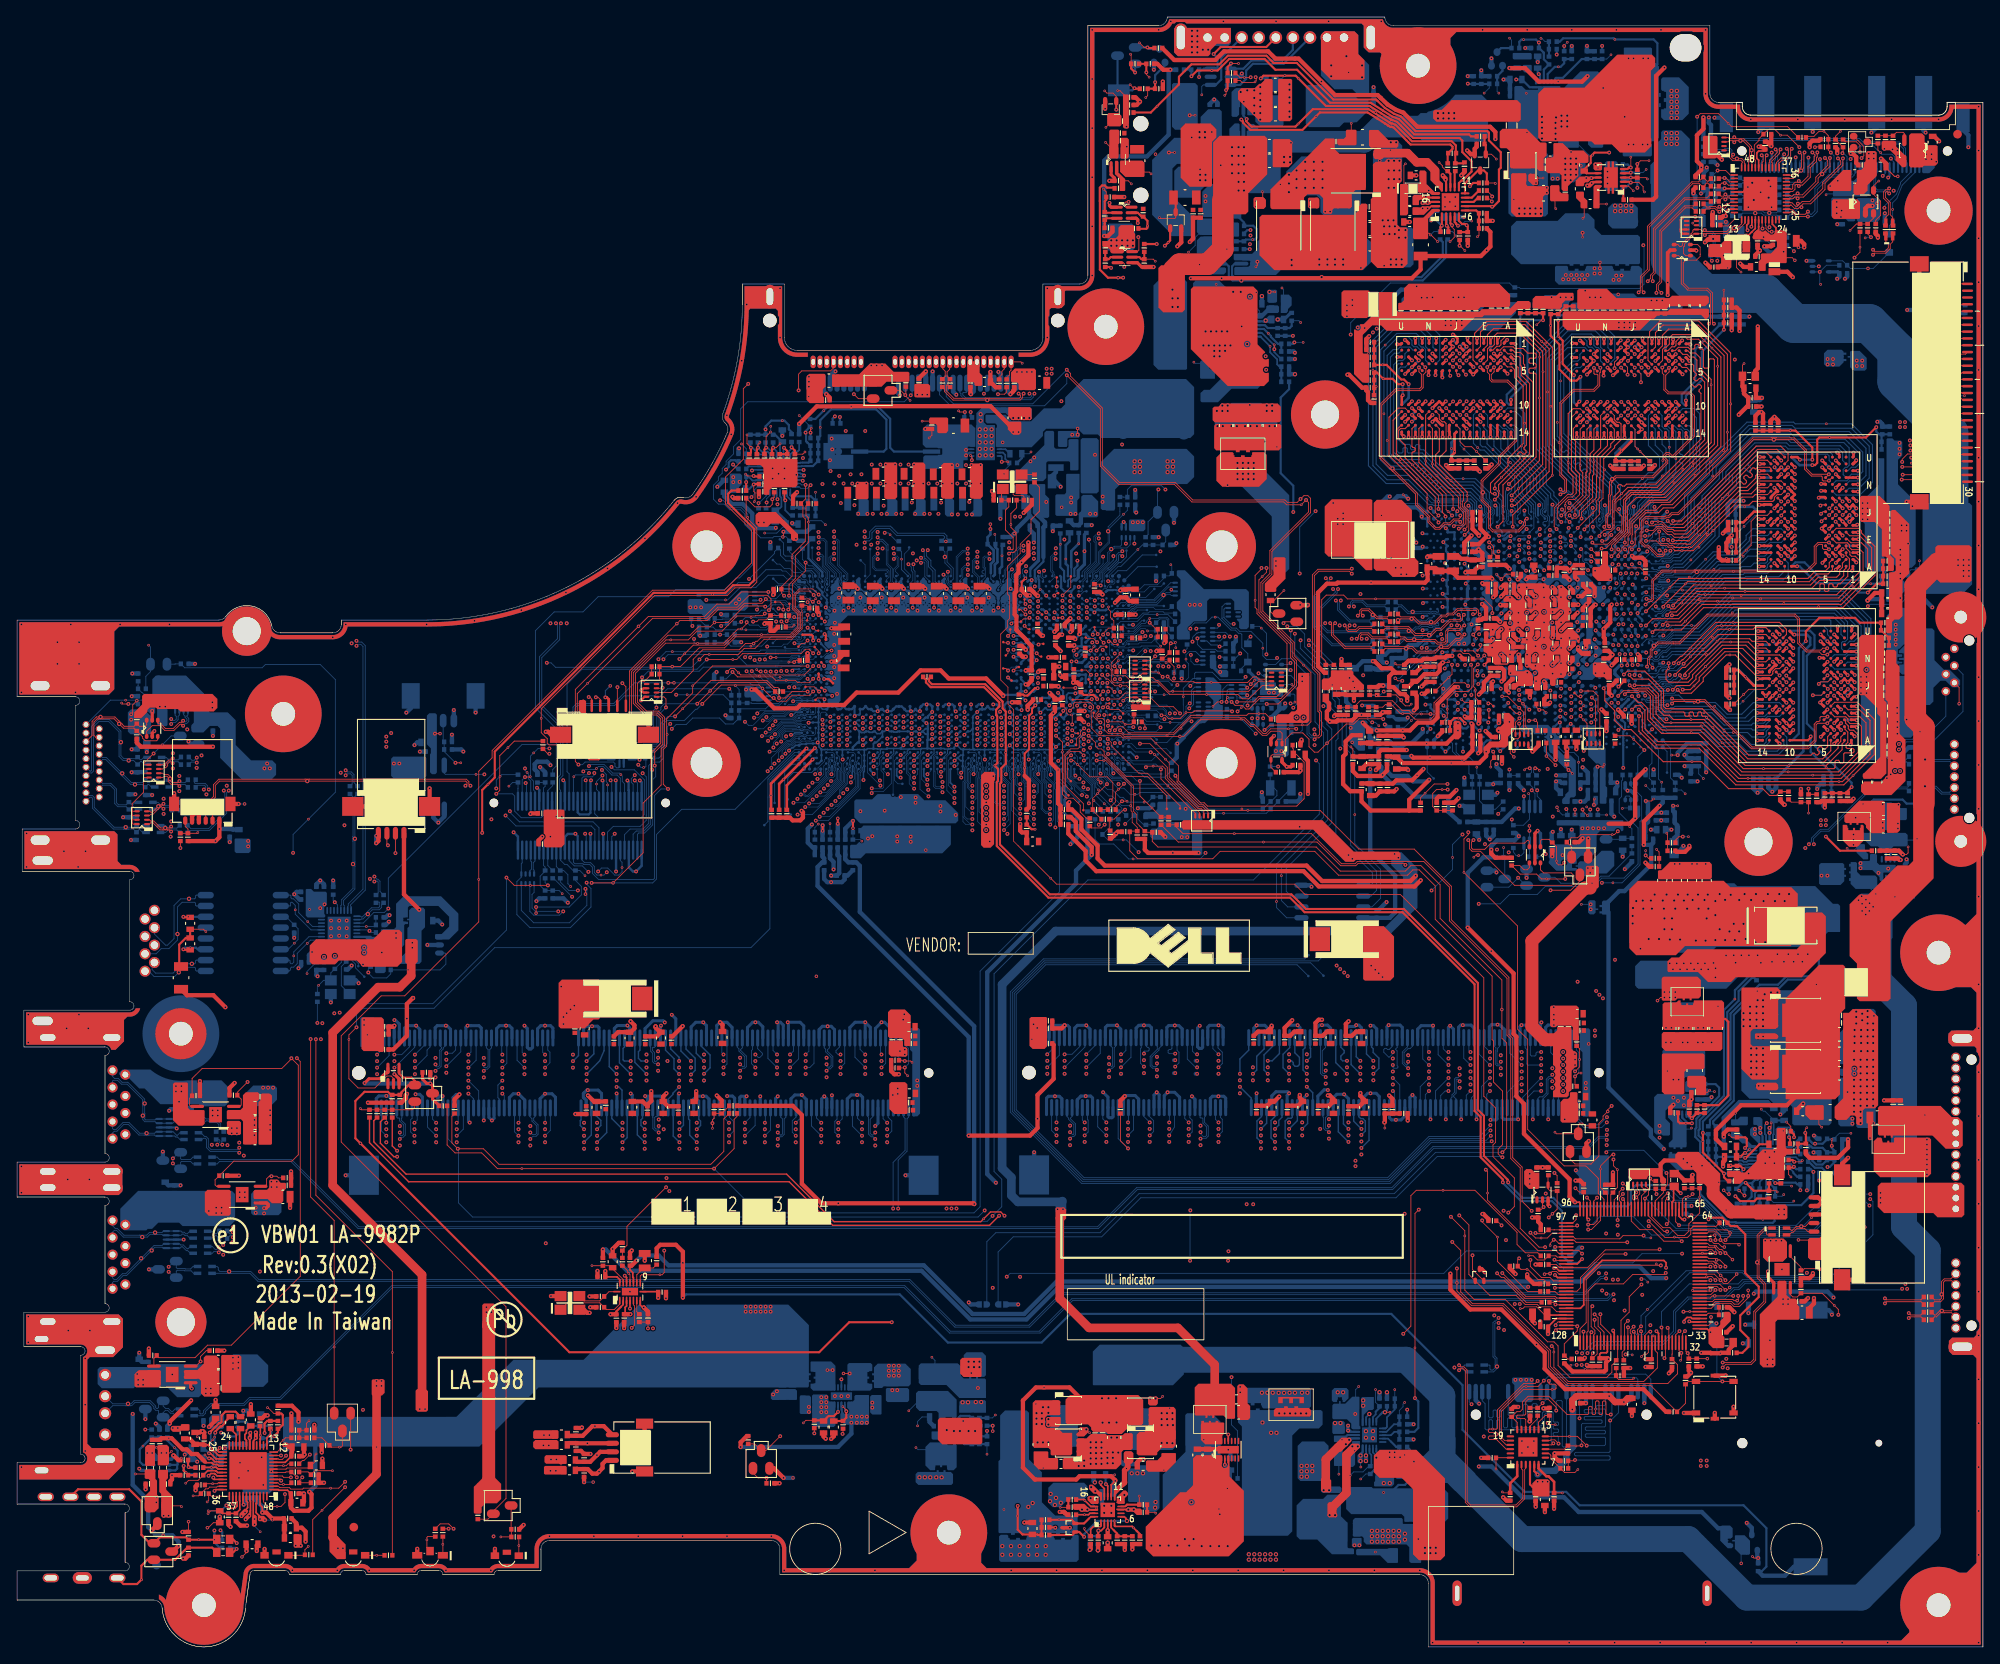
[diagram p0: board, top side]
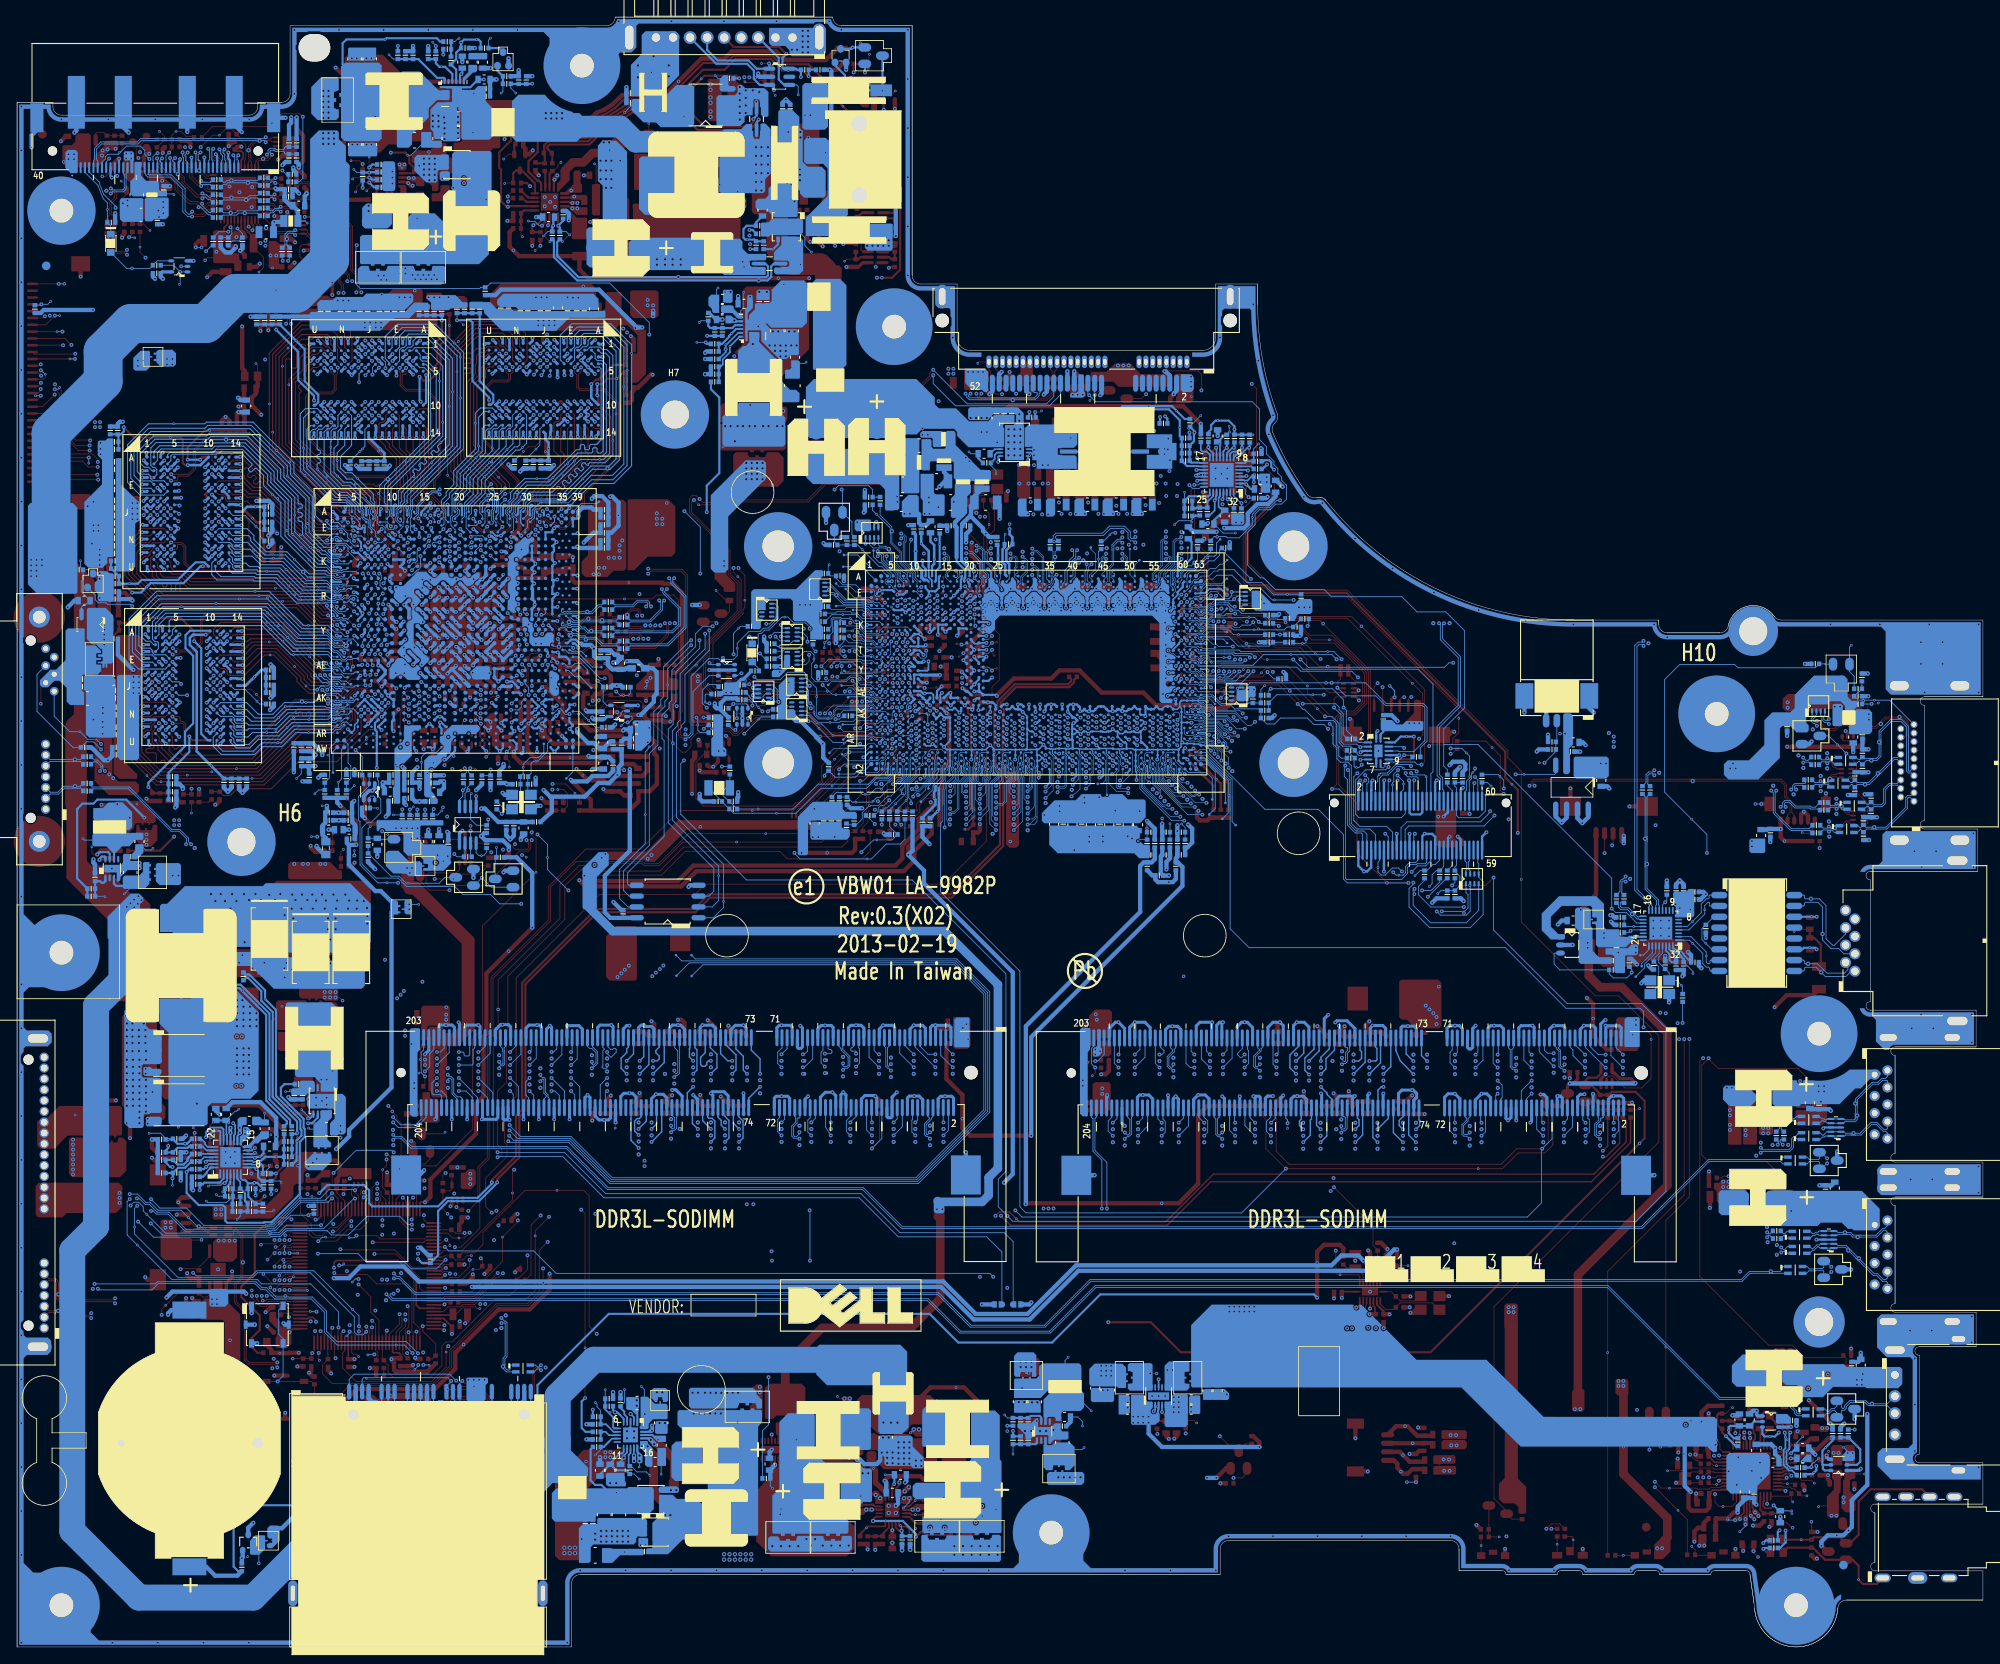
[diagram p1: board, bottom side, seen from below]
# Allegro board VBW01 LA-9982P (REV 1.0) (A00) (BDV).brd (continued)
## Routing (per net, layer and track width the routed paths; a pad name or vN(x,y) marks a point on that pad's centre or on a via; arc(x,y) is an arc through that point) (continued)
KSO6: length 136.7
  TOP w0.102: v1(227.61,146.7) 227.61,146.63 228.03,146.22 JKB.18 ; UE1.45 198.1,42.11 198.28,42.28 199.21,42.28 v1(199.63,41.86)
  IN3 w0.127: v1(227.61,146.7) 227.61,130.4 225.67,128.46 225.67,121.32 225.09,120.74 225.09,111.58 225.76,110.9 225.76,93.67 228.72,90.71 228.72,78.15 225.89,75.32 225.89,50.05 215.77,39.93 212.12,39.93 211.42,39.23 203.93,39.23 203.24,39.92 202.73,39.92 202.72,39.93 201.55,39.93 199.63,41.84 v1(199.63,41.86)
  BOTTOM w0.102: v1(227.61,146.7) v3(228.24,146.7)
KSO7: length 134.4
  TOP w0.102: UE1.46 199.57,42.51 v1(200.22,41.86) 200.42,41.86 v4(200.71,42.15) ; v1(225.98,146.83) 227.39,145.42 JKB.19
  IN3 w0.127: v1(200.22,41.86) 201.13,41.86 201.37,42.09 216.09,42.09 224.58,50.58 224.58,77.56 222.2,79.93 222.2,82.96 224.46,85.21 224.46,110.36 223.78,111.04 223.78,122.18 224.36,122.76 224.36,129 225.58,130.22 225.94,130.58 225.94,146.79 v1(225.98,146.83)
KSO8: length 140.1
  TOP w0.102: JKB.17 227.92,147.02 227.62,147.32 v1(227.62,147.49) ; UE1.47 198.37,42.91 v1(198.47,43)
  IN3 w0.127: v1(227.62,147.49) 228.18,146.93 228.18,130.6 225.93,128.35 225.93,121.21 225.35,120.63 225.35,111.69 226.03,111.01 226.03,93.78 228.98,90.82 228.98,74.59 226.18,71.79 226.18,60.27 226.15,60.24 226.15,49.94 215.88,39.67 212.31,39.67 211.61,38.97 203.83,38.97 203.13,39.67 200.06,39.67 198.04,41.68 198.04,42.58 v1(198.47,43)
  BOTTOM w0.102: v3(198.01,43.4) 198.41,43 v1(198.47,43)
KSO9: length 142.2
  TOP w0.102: v1(199.05,43) 198.61,43.44 198.28,43.44 198.14,43.31 UE1.48 ; v1(225.97,156.09) 227.05,155.02 JKB.7
  IN3 w0.127: v1(225.97,156.09) 225.97,149.75 224.15,147.93 224.15,130.64 223.05,129.54 223.05,123.3 222.47,122.72 222.47,110.49 223.15,109.82 223.15,85.75 220.9,83.5 220.9,79.39 223.3,76.98 223.3,60.78 222.62,60.09 222.62,50.46 216.61,44.45 213.01,44.45 211.95,43.4 200.84,43.4 200.54,43.7 199.73,43.7 199.05,43.01 v1(199.05,43)
  BOTTOM w0.102: v1(225.97,156.09) v3(225.4,156.09)
KSO10: length 144
  TOP w0.102: v4(201.54,43.72) 201.54,43.67 200.46,42.59 200.04,42.59 v1(199.63,43) 198.93,43.71 UE1.49 ; JKB.5 227.08,156.62 v1(226.56,156.09)
  IN3 w0.127: v1(226.56,156.09) 226.73,155.92 226.73,150.14 224.41,147.82 224.41,130.53 223.32,129.43 223.32,123.19 222.73,122.61 222.73,110.6 223.41,109.92 223.41,85.64 221.16,83.39 221.16,79.5 223.56,77.1 223.56,60.67 222.87,59.99 222.87,50.36 216.71,44.19 213.12,44.19 212.06,43.14 200.73,43.14 200.45,43.42 200.04,43.42 199.63,43.01 v1(199.63,43)
KSO11: length 141
  TOP w0.102: v1(227.14,156.03) 227.35,155.82 JKB.6 ; UE1.50 199.11,44.11 v4(199.66,43.56) v1(200.22,43)
  IN3 w0.127: v1(200.22,43) 200.5,43 200.63,42.87 215.77,42.87 223.13,50.23 223.13,59.88 223.81,60.57 223.81,77.21 221.42,79.61 221.42,83.28 223.67,85.53 223.67,110.03 222.99,110.71 222.99,122.5 223.58,123.09 223.58,129.33 224.67,130.42 224.67,147.71 227.14,150.17 v1(227.14,156.03)
KSO12: length 142.5
  TOP w0.102: v1(198.47,44.59) 198.39,44.51 UE1.51 ; JKB.12 v1(223.61,151.02)
  IN3 w0.127: v1(223.61,151.02) 223.61,149.45 222.91,148.74 222.91,131.25 221.42,129.76 221.42,116.04 220.7,115.32 220.7,111.18 221.42,110.46 221.42,110.06 222.1,109.38 222.1,102.45 219.93,100.28 217.89,100.28 216.74,99.13 216.74,93.12 217.52,92.34 219.23,92.34 221.11,90.46 221.11,85.19 219.85,83.92 219.85,78.96 222.26,76.55 222.26,61.17 221.6,60.51 221.6,50.93 216.43,45.75 199.62,45.75 198.47,44.6 v1(198.47,44.59)
  BOTTOM w0.102: v1(223.61,151.02) v3(224.2,151.02)
KSO13: length 138.8
  TOP w0.102: JKB.9 224.79,153.42 v1(224.03,152.66) ; UE1.52 198.13,44.91 198.21,44.99 198.64,44.99 v1(199.05,44.59)
  IN3 w0.127: v1(224.03,152.66) 224.03,149.34 223.32,148.63 223.32,131.29 221.68,129.66 221.68,115.94 220.96,115.21 220.96,111.29 221.68,110.56 221.68,110.17 222.36,109.49 222.36,86.08 220.11,83.82 220.11,79.07 221.07,78.1 222.52,76.66 222.52,61.07 221.86,60.41 221.86,50.81 216.39,45.35 199.8,45.35 199.05,44.6 v1(199.05,44.59)
  BOTTOM w0.102: v3(199.1,45.19) 199.1,44.64 v1(199.05,44.59)
KSO14: length 139.8
  TOP w0.102: v1(199.63,44.59) 199.23,44.99 199.02,44.99 198.8,45.22 198.17,45.22 198.09,45.31 UE1.53 ; v1(225.07,154.22) JKB.8
  IN3 w0.127: v1(199.63,44.59) 199.63,44.6 200.07,45.03 216.45,45.03 222.11,50.7 222.11,60.3 222.78,60.97 222.78,76.77 221.71,77.84 220.37,79.17 220.37,83.72 222.62,85.97 222.62,109.6 221.95,110.28 221.95,110.67 221.22,111.4 221.22,115.1 221.95,115.83 221.95,129.55 223.58,131.18 223.58,148.32 224.56,149.3 224.56,153.71 v1(225.07,154.22)
  BOTTOM w0.102: v1(225.07,154.22) v3(225.72,154.22)
KSO15: length 137.4
  TOP w0.102: JKB.10 v1(225.01,152.62) ; UE1.54 198.11,45.71 198.27,45.55 199.03,45.55 v4(199.2,45.38) 199.55,45.38 200.22,44.71 v1(200.22,44.59)
  IN3 w0.127: v1(200.22,44.59) 200.35,44.71 216.5,44.71 222.36,50.58 222.36,60.2 223.04,60.87 223.04,76.88 220.63,79.28 220.63,83.61 222.89,85.86 222.89,109.71 222.21,110.38 222.21,122.83 222.79,123.41 222.79,129.65 223.49,130.35 223.49,130.72 223.89,131.12 223.89,148.18 225.01,149.3 v1(225.01,152.62)
KSO16: length 149.9
  TOP w0.102: UE1.81 189.19,49.93 190.19,48.93 191.65,48.93 193.01,47.57 v1(195.1,47.57) ; JKB.11 228.35,151.57 223.64,151.57 v1(223.59,151.62)
  IN3 w0.127: v1(195.1,47.57) 197.44,47.57 198.97,49.1 209.76,49.1 210.43,48.44 215.76,48.44 219.32,51.99 219.32,61.46 219.96,62.1 219.96,75.52 217.46,78.02 217.46,84.83 218.83,86.2 218.83,87.64 216.85,89.62 215.36,89.62 213.48,91.5 213.48,101 218.34,105.87 218.34,122.15 218.46,122.27 218.46,137.07 221.05,139.66 221.05,141.53 222.64,143.12 222.64,150.68 v1(223.59,151.62)
  BOTTOM w0.102: v3(194.24,48.05) 194.62,48.05 v1(195.1,47.57)
LAN_CLKREQ#: length 161.8
  TOP w0.102: RP42.8 145.94,112.74 144.38,111.17 143.59,111.17 143.09,111.67 v3(139.42,111.67) 139.4,111.69 135.07,111.69 133.65,113.12 132.65,113.12 v1(132.48,113.29)
  IN2 w0.089: v1(132.48,113.29) 132.3,113.29 130.09,111.09 130.09,103.18 130.65,102.63 130.65,98.88 130.33,98.56 130.33,98.07 129.87,97.61 126.65,97.61 125.38,96.34 124.12,96.34 121.39,93.61
  IN2 w0.127: 121.39,93.61 112.82,85.04 58.36,85.04 44.58,71.26 v1(35.61,71.26)
  IN3 w0.127: v1(37.24,87.32) 33.42,83.5 33.42,73.51 35.61,71.31 v1(35.61,71.26)
  BOTTOM w0.089: UC1.AD1 130.4,112.47 131.65,112.47 v1(132.48,113.29)
  BOTTOM w0.102: UL1.12 37.55,87.01 v1(37.24,87.32) 37.05,87.5 RL37.1
LAN_X1_R: length 1.7
  TOP w0.102: RG5.1 72.63,39.3 UG1.6
LCD_CBL_DET#: length 7.3
  BOTTOM w0.076: RC106.2 134.98,121.64 133.42,121.64 133.16,121.89 131.26,121.89 130.95,121.58 130.76,121.58 130.57,121.39 130.57,121.22 130.4,121.05 129.47,121.05 UC1.J3
LCD_TEST: length 170.1
  TOP w0.102: v1(193.48,53.2) 193.4,53.2 192.79,52.58 UE1.72
  IN2 w0.127: v1(217.19,53.1) 217.19,53.6 222.41,58.81 222.41,71.51 228.3,77.41 228.3,85.74 225.31,88.74 225.31,96.13 225.86,96.68 225.86,109.53 224.44,110.95 224.44,120.91 225.34,121.81 225.34,146.04 216.28,155.09 216.28,164.85 214.67,166.47 214.67,174.22 v1(214.89,174.45)
  BOTTOM w0.102: v1(217.19,53.1) 216.28,53.1 215.27,52.09 214.77,52.09 213.88,51.2 211.18,51.2 v3(210.31,50.33) 209.18,49.2 201.27,49.2 201.21,49.26 200.34,49.26 197.23,52.37 194.31,52.37 v1(193.48,53.2) ; JLVDS.33 220.45,174.05 220.06,174.45 220.06,174.7 219.74,175.02 218.53,175.02 217.58,175.97 215.93,175.97 215.42,175.46 215.42,174.98 v1(214.89,174.45)
LDO_3V: length 6.3
  IN3 w0.254: v2(146.34,155.51) 149.07,152.78 149.53,152.78 v1(149.7,152.96)
  BOTTOM w0.102: v1(149.7,152.96) v3(150.73,152.96)
  BOTTOM w0.254: PR304.1 149.53,152.78 v1(149.7,152.96)
LDO_3V_VDDCI: length 8.4
  IN3 w0.254: v1(178.34,184.41) 179.04,185.11 179.04,187.08 179.66,187.7 v1(181.32,187.7)
  BOTTOM w0.102: v1(181.32,187.7) 181.32,187.78 v3(181.69,188.14)
  BOTTOM w0.254: PR1203.1 v1(181.32,187.7) ; PU1200.5 178.49,184.26 v1(178.34,184.41) 178.22,184.53 PC1213.1
LG_3V: length 2.8
  TOP w0.635: 129.65,19.12 129.8,19.27 129.8,20.7 v3(130.03,20.93) 130.18,21.08 130.18,21.68
LG_5V: length 7.1
  IN3 w0.762: 125.19,19.38 124.87,19.38 123.41,20.84 123.41,22.71 125.06,24.36
  BOTTOM w0.102: v2(125.31,25.5) 125.31,25.5 v3(125.7,25.12)
  vias: v2(124.68,25.5) v2(125.89,18.73) v2(126.37,18.25)
LG_+1.2VSP: length 7.5
  IN3 w0.762: 185.13,174.57 184.43,175.27 181.13,175.27 180.31,174.44 180.31,172.98
  BOTTOM w0.102: v1(185.58,173.81) 185.58,173.68 v3(185.28,173.39)
  vias: v1(179.98,172.16) v1(180.56,172.16) v1(184.99,173.81)
LID_SW#: length 185.2
  TOP w0.102: JPWR.2 v1(44.34,93.07) ; v1(176.05,45.57) 175.87,45.39 CE30.1 176.26,44.27 v3(176.97,44.27) 177.06,44.27 178.25,43.08 178.92,43.08 RE71.2 179.49,42.51 UE1.115
  IN3 w0.127: v1(176.05,45.57) 171.47,45.57 170.77,44.87 63.38,44.87 56.09,52.16 56.09,92 55.02,93.07 v1(44.34,93.07)
LINE1-L: length 2.3
  TOP w0.203: UA1.22 25.68,24.91 CA67.1
LINE1-R: length 2
  TOP w0.203: UA1.21 26.08,25.49 CA68.1
LINE1-VREFO-L: length 5
  TOP w0.102: v3(19.76,19.2) 20.09,19.53 21.21,19.53 RA165.1
  TOP w0.203: RA165.1 22.34,20.66 23.27,20.66 23.34,20.59 23.38,20.59 23.51,20.45 UA1.31
LINE1-VREFO-R: length 2.4
  TOP w0.203: RA166.1 21.85,21.06 v3(22.76,21.06) 23.34,21.06 23.48,20.92 23.51,20.92 23.58,20.85 UA1.30
LINE-IN-L: length 21.5
  TOP w0.254: RA165.2 RA83.1 19.52,20.66 v1(19.52,21.22) ; v1(25.73,11.49) 25.34,11.1 LA8.2
  IN1 w0.254: v1(25.73,11.49) 22.11,11.49 18.38,15.22 18.38,19.68 19.52,20.82 v1(19.52,21.22)
  BOTTOM w0.254: RA165.2 20.78,20.27 20,20.27 v3(19.8,20.46) 19.52,20.74 v1(19.52,21.22) ; v1(25.73,11.49) 25.62,11.61 RA55.2
LINE-IN-R: length 20.4
  TOP w0.254: RA166.2 20.17,21.03 v1(20.1,21.09) 20.04,21.15 RA84.1 ; v1(25.75,12.18) 25.3,12.62 LA9.2
  IN1 w0.254: v1(25.75,12.18) 22.14,12.18 18.76,15.56 18.76,19.52 20.1,20.87 v1(20.1,21.09)
  BOTTOM w0.102: v1(20.1,21.09) 20.1,21.39 19.91,21.58 19.8,21.58 v3(19.24,22.14)
  BOTTOM w0.254: v1(25.75,12.18) 25.43,12.49 RA56.2 ; RA166.2 20.17,21.03 v1(20.1,21.09)
LPC_LAD0: length 111.9
  TOP w0.102: v1(185.56,39.01) 185.6,38.97 185.6,37.83 186.79,36.65 UE1.10
  IN1 w0.084: v1(124.81,99.88) 125.01,100.09 125.52,100.09 125.9,99.71 129.96,99.71 130.91,98.75 131.45,98.75
  IN1 w0.127: 131.45,98.75 132.39,98.75 135.71,95.44 139.06,95.44 147.75,86.75 149.77,86.75 160.15,76.37 170.78,76.37 175.03,72.12 175.03,64.72 176.76,62.99 176.76,61.57 179.59,58.74 179.59,54.38 180.37,53.6 180.37,48.79 181.08,48.08 181.08,41.29 184.45,37.92 185.04,37.92 185.56,38.44 v1(185.56,39.01)
  BOTTOM w0.076: UC1.AU14 122.74,104.59 122.74,104.11 122.7,104.07 122.7,102.74 122.95,102.49 122.95,102.34 122.95,102.33 122.95,101.8 123.93,100.82 123.93,100.47 124.52,99.88 v1(124.81,99.88)
LPC_LAD1: length 107.3
  TOP w0.102: UE1.8 185.99,36.91 185.3,37.6 185.3,38.59 v1(184.89,39)
  IN1 w0.084: 131.57,99.44 130.72,99.44 130.05,100.1 126.53,100.1 125.27,101.36 v1(124.98,101.36)
  IN1 w0.127: v1(184.89,39) 184.82,39 181.74,42.07 181.74,48.35 181.03,49.07 181.03,56.94 180.34,57.63 180.34,59.2 178.24,61.3 178.24,63.27 177.08,64.43 177.08,71.01 171.06,77.03 160.43,77.03 150.04,87.41 148.02,87.41 139.25,96.18 136.4,96.18 133.14,99.44 131.57,99.44
  BOTTOM w0.076: v1(124.98,101.36) 124.91,101.3 124.15,101.3 123.45,102 123.45,103.29 UC1.AW12
LPC_LAD2: length 106.4
  TOP w0.102: v1(184.89,38.36) 184.89,37.58 185.59,36.88 UE1.7
  IN1 w0.084: v1(125.51,100.59) 126.21,99.9 130.02,99.9 130.82,99.1 131.57,99.1
  IN1 w0.127: 131.57,99.1 133.02,99.1 136.26,95.85 139.12,95.85 147.89,87.08 149.91,87.08 160.29,76.7 170.92,76.7 175.37,72.25 175.37,65.23 177.12,63.47 177.12,61.68 179.92,58.88 179.92,57.16 180.7,56.39 180.7,48.93 181.41,48.22 181.41,41.84 v1(184.89,38.36)
  BOTTOM w0.076: UC1.AY12 123.28,102.81 123.28,101.93 124.79,100.42 125.34,100.42 v1(125.51,100.59)
LPC_LAD3: length 107
  TOP w0.102: UE1.5 184.79,36.6 184.92,36.74 184.92,37.12 184.48,37.55 184.48,39.81 v1(184.62,39.95)
  IN1 w0.084: 131.27,99.8 130.6,99.8 130.12,100.28 126.6,100.28 125.09,101.79 v1(124.52,101.79)
  IN1 w0.127: 131.27,99.8 133.24,99.8 136.54,96.51 139.39,96.51 148.16,87.74 150.18,87.74 160.56,77.36 171.19,77.36 177.41,71.14 177.41,64.57 178.83,63.15 178.83,61.18 181.19,58.81 181.19,57.68 181.39,57.48 181.39,49.17 182.07,48.49 182.07,42.51 184.62,39.96 v1(184.62,39.95)
  BOTTOM w0.076: v1(124.52,101.79) 123.89,101.79 123.61,102.07 123.61,103.29 UC1.AW11
LPC_LFRAME#: length 107.4
  TOP w0.102: v1(184.51,36.9) 184.39,36.78 UE1.4
  IN1 w0.084: 131.57,97.98 131.56,97.98 131.48,97.9 131.48,97.84 131.41,97.77 131.12,97.77 130.49,98.41 130.49,98.76 129.72,99.53 129.14,99.53 128.49,98.88 126.2,98.88 v1(125.38,99.71)
  IN1 w0.127: v1(184.51,36.9) 184.51,37.24 180.75,41 180.75,47.94 180.04,48.66 180.04,53.2 178.25,55 178.25,56.57 177.94,56.87 177.94,59.02 176.35,60.61 176.35,62.94 174.7,64.58 174.7,70.98 169.64,76.04 160.02,76.04 149.63,86.42 147.61,86.42 139.54,94.5 136.18,94.5 132.7,97.98 131.57,97.98
  BOTTOM w0.076: v1(125.38,99.71) 125.38,99.88 125.01,100.25 124.73,100.25 123.12,101.86 123.12,102.56 122.86,102.81 122.86,103.98 UC1.AV12
LVDS_A0+: length 3.1
  TOP w0.102: v1(205.06,174.89) 204.91,174.74 204.91,174.06 204.92,174.05 UX4.41
  BOTTOM w0.102: JLVDS.2 204.95,174.25 204.9,174.3 204.9,174.73 v1(205.06,174.89)
LVDS_A0-: length 3.2
  TOP w0.102: v1(204.47,174.89) 204.64,174.73 204.64,174.19 204.52,174.07 UX4.42
  BOTTOM w0.102: v1(204.47,174.89) 204.63,174.73 204.63,174.43 204.45,174.25 JLVDS.1
LVDS_A1+: length 4.9
  TOP w0.102: UX4.39 205.72,173.99 205.65,174.05 205.65,174.2 206.54,175.09 206.54,175.44 v1(206.68,175.58)
  BOTTOM w0.102: JLVDS.5 206.45,174.25 206.33,174.36 206.33,174.89 206.52,175.08 206.52,175.42 v1(206.68,175.58)
LVDS_A1-: length 4.9
  TOP w0.102: v1(206.1,175.58) 206.28,175.4 206.28,175.2 205.39,174.31 205.39,174.08 205.32,174.01 UX4.40
  BOTTOM w0.102: JLVDS.4 205.95,174.25 206.07,174.36 206.07,175 206.26,175.19 206.26,175.42 v1(206.1,175.58)
LVDS_A2+: length 5.5
  TOP w0.102: UX4.37 206.52,173.82 206.47,173.87 206.47,173.94 206.84,174.32 207.36,174.32 207.86,174.83 207.86,175.53 v1(207.99,175.65)
  BOTTOM w0.102: JLVDS.8 207.95,174.25 207.83,174.36 207.83,175.5 v1(207.99,175.65)
LVDS_A2-: length 5.5
  TOP w0.102: UX4.38 206.12,173.86 206.2,173.94 206.2,174.05 206.73,174.58 207.25,174.58 207.6,174.94 207.6,175.46 v1(207.41,175.65)
  BOTTOM w0.102: JLVDS.7 207.45,174.25 207.57,174.36 207.57,175.5 v1(207.41,175.65)
LVDS_ACLK+: length 6.2
  TOP w0.102: UX4.35 208.18,172.18 v2(209.09,173.1) 209.4,173.41 209.4,175.14 v1(209.49,175.23)
  BOTTOM w0.102: v1(209.49,175.23) 209.45,175.19 209.45,174.07 JLVDS.11
LVDS_ACLK-: length 6.1
  TOP w0.102: UX4.36 207.8,172.58 207.93,172.45 208.06,172.45 209.13,173.52 209.13,175 v1(208.91,175.23)
  BOTTOM w0.102: v1(208.91,175.23) 208.92,175.23 209.18,174.96 209.18,174.38 209.11,174.31 209.08,174.31 209.08,174.31 209.05,174.31 208.95,174.21 JLVDS.10
LVDS_B0+: length 10.6
  TOP w0.102: v1(210.99,175.23) 210.98,175.21 210.98,174.7 210.89,174.61 210.89,174.17 210.16,173.45 210.16,172.32 209.24,171.4 208.92,171.4 v1(208.82,171.3) 208.64,171.47 208.5,171.47 208.37,171.35 208.37,170.9 208.12,170.65 207.85,170.65 207.78,170.58 UX4.31
  BOTTOM w0.102: v1(208.82,171.3) 208.65,171.47 207.76,171.47 RX40.2 ; JLVDS.14 210.95,174.07 210.89,174.14 210.89,174.61 210.99,174.72 v1(210.99,175.23)
LVDS_B0-: length 10.5
  TOP w0.102: v1(210.41,175.23) 210.42,175.23 210.71,174.94 210.71,174.81 210.62,174.72 210.62,174.28 209.9,173.56 209.9,172.43 209.13,171.66 209.01,171.66 208.82,171.85 v1(208.82,171.88) 208.68,171.74 208.39,171.74 208.11,171.46 208.11,171.01 208.01,170.91 207.88,170.91 207.81,170.98 UX4.32
  BOTTOM w0.102: RX38.2 207.76,171.73 208.68,171.73 v1(208.82,171.88) ; v1(210.41,175.23) 210.42,175.23 210.73,174.92 210.73,174.83 210.62,174.72 210.62,174.25 210.45,174.08 JLVDS.13
LVDS_B1+: length 10.8
  TOP w0.102: UX4.29 207.8,169.78 207.86,169.85 208.18,169.85 208.33,170 208.52,170 v1(208.68,169.84) 208.82,169.99 209.36,169.99 211.08,171.7 211.08,172.2 v2(211.56,172.68) 212.15,173.27 212.47,173.6 212.47,174.56 v1(212.47,174.57)
  BOTTOM w0.102: v1(212.47,174.57) 212.44,174.54 212.44,174.08 212.45,174.06 JLVDS.17 ; RX44.2 207.76,169.69 207.99,169.69 208.29,169.99 208.53,169.99 v1(208.68,169.84)
LVDS_B1-: length 10.7
  TOP w0.102: UX4.30 207.83,170.18 207.89,170.11 208.07,170.11 208.22,170.27 208.52,170.27 v1(208.68,170.43) 208.85,170.25 209.25,170.25 210.81,171.81 210.81,172.31 211.37,172.87 212.21,173.71 212.21,174.25 v1(211.88,174.57)
  BOTTOM w0.102: v1(211.88,174.57) 211.89,174.57 212.17,174.29 212.17,174.24 211.95,174.02 JLVDS.16 ; v1(208.68,170.43) 208.5,170.25 208.18,170.25 207.88,169.96 207.76,169.96 RX42.2
LVDS_B2+: length 13.6
  TOP w0.102: UX4.27 207.76,168.98 207.84,169.06 207.92,169.06 208.33,168.65 208.75,168.65 208.9,168.81 v1(209.13,168.81) 209.13,169.01 209.32,169.2 210.21,169.2 211.89,170.88 211.89,171.62 213.99,173.72 v1(213.99,174.53)
  BOTTOM w0.102: v1(213.99,174.53) 213.92,174.46 213.92,174.09 213.95,174.07 JLVDS.20 ; RX48.2 207.76,167.91 207.98,167.91 208.88,168.81 v1(209.13,168.81)
LVDS_B2-: length 13.3
  TOP w0.102: UX4.28 207.78,169.38 207.84,169.33 208.03,169.33 208.44,168.92 208.64,168.92 208.71,169 v1(208.71,169.22) 208.96,169.22 209.21,169.47 210.1,169.47 211.62,170.99 211.62,171.73 213.73,173.83 213.73,174.21 v1(213.41,174.53)
  BOTTOM w0.102: v1(213.41,174.53) 213.51,174.53 213.59,174.45 213.59,174.36 213.66,174.29 213.66,174.19 213.59,174.13 213.58,174.13 213.45,174 JLVDS.19 ; RX46.2 207.76,168.18 207.87,168.18 208.71,169.02 v1(208.71,169.22)
LVDS_BCLK+: length 12.7
  TOP w0.102: UX4.25 207.76,168.18 207.83,168.25 207.98,168.25 208.52,167.71 v1(209.88,167.71)
  BOTTOM w0.102: v1(209.88,167.71) 210.41,167.71 210.98,168.27 210.98,170.89 212.42,172.34 215.09,172.34 215.31,172.56 215.31,172.67 215.45,172.81 JLVDS.23
LVDS_BCLK-: length 12.6
  TOP w0.102: v1(209.88,168.29) 209.88,168.18 209.83,168.13 209.73,168.13 209.57,167.97 208.63,167.97 208.09,168.51 207.84,168.51 207.77,168.58 UX4.26
  BOTTOM w0.102: JLVDS.22 214.95,172.86 215.04,172.77 215.04,172.67 214.98,172.6 212.31,172.6 210.71,171 210.71,168.38 210.3,167.97 210.2,167.97 210.04,168.13 209.96,168.13 209.88,168.21 v1(209.88,168.29)
LX_1.05V: length 7.8
  TOP w0.102: v2(146.78,158.88) v3(147.41,158.88)
  IN1 w0.508: v2(146.78,158.88) 146.78,156.86 145.7,155.78 145.7,154.29 v2(144.17,152.76)
LX_1.5VSP: length 3.6
  BOTTOM w0.102: PL400.1 105.79,28.97 v3(104.51,27.69)
LX_1.8VSP: length 3.2
  BOTTOM w0.102: v3(222.68,94.76) 222.52,94.6 PL600.1
LX_3V: length 7.4
  IN1 w0.762: 134.39,22.84 134.39,19.53 131.51,16.65 131.47,16.65
  vias: v2(130.24,16.11) v2(130.88,16.11) v2(134.14,27.41) v2(134.14,26.71) v2(134.14,26.01) v2(134.14,23.92) v2(134.78,27.41) v2(134.78,26.71) v2(134.84,26.01) v2(134.78,23.92) v2(135.41,27.41) v2(135.41,26.71) v2(135.41,23.89) v2(135.47,26.01) v3(135.08,27.99)
LX_5V: length 8
  IN1 w0.762: 119.92,23.19 119.92,20.42 123.6,16.74
  vias: v2(119.47,27.41) v2(119.47,26.77) v2(119.47,26.14) v2(119.6,23.98) v2(120.11,27.41) v2(120.11,26.77) v2(120.11,26.14) v2(120.23,28.11) v2(120.23,23.98) v2(120.87,28.11) v2(120.87,27.44) v2(120.87,23.98) v2(124.81,16.11) v2(125.44,16.11) v3(119.41,28.49)
LX_CHG: length 8.8
  IN1 w1.016: 163.8,168.35 154.97,168.35
  vias: v1(153.31,168.29) v1(153.89,168.29) v1(164.74,168.67) v1(165.32,168.67) v2(149.06,172.6) v2(149.06,171.59) v2(149.06,170.57) v2(149.95,173.11) v2(149.95,172.1) v2(149.95,171.08) v2(150.97,174.13) v2(150.97,173.11) v2(150.97,172.1) v2(150.97,171.08) v2(151.98,174.13) v2(151.98,173.11) v2(151.98,172.1) v2(151.98,171.08) v2(153,174.13) v2(153,173.11) v2(153,172.1) v2(153,171.08) v3(148.06,171.48)
LX_PCIE:
  vias: v1(194.11,66.52) v1(194.75,66.52) v3(193.42,67.52)
LX_VDDCI: length 11
  TOP w0.508: v1(174.91,185.12) 176.74,185.12 178.34,183.53 v3(180.62,183.53) 183.42,183.53 v1(184.05,184.16)
  BOTTOM w0.508: PC1210.2 v1(174.91,185.12)
M_CLK_DDR0: length 77.1
  IN1 w0.084: v1(108.46,100.85) 108.46,100.74 108.83,100.37 108.83,100.3 108.92,100.21 108.92,99.87 108.47,99.42 108.47,99.21 108.9,98.78 108.9,98.31 108.79,98.21 108.79,97.43 108.62,97.25 108.31,97.25 108.14,97.42 107.83,97.42 107.61,97.2 107.61,97.06 107.83,96.84 107.83,96.52 107.48,96.17 107.15,96.17 106.95,96.36 106.77,96.36 106.37,95.96 106.37,95.82 106.23,95.68
  IN1 w0.127: 106.23,95.68 105.85,95.3 105.85,82.02 102.26,78.43 101.86,78.43 100.34,79.95 100.16,79.95 99.89,79.68 99.89,79.5 101.41,77.98 101.41,77.58 100.98,77.15 100.58,77.15 99.06,78.67 98.88,78.67 98.61,78.4 98.61,78.22 99.77,77.06 99.77,76.66 99.34,76.23 98.93,76.23 97.77,77.39 97.59,77.39 92.75,72.55 79.5,72.55 78.55,71.59 77.74,71.59 75.97,69.82 75.97,69.04 75.81,68.87 75.81,68.74 75.52,68.45 75.26,68.45 v1(75.12,68.32)
  BOTTOM w0.076: v1(108.46,100.85) 107.72,100.85 107.59,100.99 107.59,102.6 107.56,102.63 107.56,104.33 107.66,104.43 107.79,104.43 107.85,104.36 UC1.AV37
  BOTTOM w0.102: v1(75.12,68.32) 75.04,68.4 74.7,68.4 74.49,68.62 74.49,69.61 74.26,69.83 74.26,70.31 74.2,70.37 JDIMM1.101
M_CLK_DDR1: length 76.1
  IN1 w0.084: 106.84,95.2 108.99,97.36 108.99,98.12 109.13,98.26 109.13,101.22 108.82,101.53 108.82,102.67 108.75,102.74 108.41,102.74 v1(108.28,102.61)
  IN1 w0.127: v1(75.2,60.32) 75.09,60.43 74.67,60.43 74.31,60.79 74.31,62.41 74.65,62.75 76.29,62.75 76.42,62.88 76.42,63.7 76.29,63.83 75.16,63.83 74.88,64.11 74.88,65.54 75.16,65.83 76.39,65.83 76.66,66.1 76.66,69.6 78.01,70.95 78.81,70.95 79.77,71.91 93.17,71.91 96.85,75.59 100.33,75.59 106.48,81.75 106.48,94.84 106.84,95.2
  BOTTOM w0.076: UC1.AY36 108.68,102.72 108.57,102.61 v1(108.28,102.61)
  BOTTOM w0.102: v1(75.2,60.32) 75.01,60.51 74.79,60.51 74.51,60.78 74.51,62.1 74.5,62.11 JDIMM1.102
M_CLK_DDR2: length 93.2
  IN3 w0.084: 106.6,95.75 106.52,95.83 106.52,96.18 106.88,96.54 106.88,96.97 106.24,97.6 106.24,98.06 106.84,98.66 106.84,98.98 107.46,99.59 107.46,104.9 106.81,105.54 106.81,107 106.89,107.07 107.2,107.07 v1(107.25,107.02)
  IN3 w0.127: 106.6,95.75 106.6,89.44 118.86,77.18 119.54,77.18 119.83,76.9 119.83,76.21 119.95,76.09 120.36,76.09 120.48,76.21 120.48,76.9 120.76,77.18 121.38,77.18 121.66,76.9 121.66,75.29 121.78,75.17 122.19,75.17 122.31,75.29 122.31,76.9 122.6,77.18 123.21,77.18 123.49,76.9 123.49,75.34 123.67,75.17 150.03,75.17 151.65,73.55 151.65,72.85 152.07,72.42 152.92,72.42 153.2,72.14 153.2,71.7 152.99,71.49 152.99,71.28 153.15,71.12 153.98,71.12 154.25,70.85 154.25,70.13 153.98,69.85 153.6,69.85 153.48,69.73 153.48,69.23 153.6,69.11 153.98,69.11 154.25,68.83 154.25,67.9 154.05,67.7 154.05,67.21 153.84,67 153.56,67 v1(153.37,66.82)
  BOTTOM w0.076: UC1.AN38 107.32,107.02 v1(107.25,107.02)
  BOTTOM w0.102: JDIMM2.101 152.75,67.25 153,67 153.19,67 v1(153.37,66.82)
M_CLK_DDR3: length 91.8
  IN3 w0.084: v1(107.2,108.28) 106.99,108.49 106.95,108.49 106.71,108.73 106.4,108.73 106.15,108.48 106.15,108.09 106.45,107.79 106.45,105.15 106.23,104.93 106.23,98.89 105.64,98.31 105.64,93.83 105.71,93.76
  IN3 w0.127: v1(153.75,60.36) 153.91,60.52 154.32,60.52 154.59,60.78 154.59,62 152.56,64.03 152.56,70.07 151.9,70.72 151.9,71.28 150.75,72.42 150.75,73.18 149.66,74.27 148.89,74.27 120.49,74.27 105.72,89.05 105.72,89.07 105.71,89.07 105.71,93.76
  BOTTOM w0.076: v1(107.2,108.28) 107.56,108.64 UC1.AL38
  BOTTOM w0.102: JDIMM2.102 153.05,62.15 153.13,62.07 153.13,60.78 153.37,60.54 153.57,60.54 v1(153.75,60.36)
M_CLK_DDR#0: length 77.5
  IN1 w0.084: 106.17,96 106.69,96.53 107.03,96.53 107.22,96.34 107.41,96.34 107.66,96.59 107.66,96.76 107.43,96.99 107.43,97.27 107.75,97.59 108.22,97.59 108.38,97.43 108.55,97.43 108.62,97.5 108.62,98.28 108.72,98.38 108.72,98.71 108.3,99.13 108.3,99.49 108.75,99.94 108.75,100.14 108.68,100.21 v1(108.46,100.21)
  IN1 w0.127: v1(75.12,69.08) 75.12,68.83 75.23,68.72 75.41,68.72 75.54,68.86 75.54,68.99 75.7,69.15 75.7,69.93 77.63,71.86 78.43,71.86 79.39,72.82 92.64,72.82 97.48,77.66 97.89,77.66 99.05,76.5 99.23,76.5 99.49,76.77 99.49,76.95 98.34,78.1 98.34,78.51 98.77,78.94 99.17,78.94 100.69,77.42 100.87,77.42 101.14,77.69 101.14,77.87 99.62,79.39 99.62,79.79 100.05,80.22 100.46,80.22 101.97,78.71 102.15,78.71 105.58,82.13 105.58,95.41 106.17,96
  BOTTOM w0.076: v1(108.46,100.21) 108.46,100.33 108.13,100.66 107.64,100.66 107.4,100.91 107.4,104.41 107.58,104.59 107.83,104.59 107.89,104.66 107.89,104.79 UC1.AU37
  BOTTOM w0.102: JDIMM1.103 74.8,70.4 74.7,70.31 74.54,70.31 74.48,70.24 74.48,69.92 74.7,69.7 74.7,68.71 74.79,68.62 74.85,68.62 75.12,68.89 v1(75.12,69.08)
M_CLK_DDR#1: length 76.3
  IN1 w0.084: 107.03,95 107.03,95.14 109.17,97.28 109.17,98.05 109.31,98.19 109.31,101.29 108.99,101.6 108.99,102.74 108.83,102.91 108.63,102.91 v1(108.28,103.26)
  IN1 w0.127: v1(75.2,61.08) 75.2,60.87 75.03,60.7 74.78,60.7 74.58,60.91 74.58,62.3 74.76,62.48 76.41,62.48 76.69,62.77 76.69,63.81 76.41,64.1 75.28,64.1 75.15,64.23 75.15,65.43 75.28,65.56 76.5,65.56 76.93,65.99 76.93,69.49 78.12,70.68 78.92,70.68 79.88,71.64 93.28,71.64 96.96,75.32 100.44,75.32 106.75,81.63 106.75,94.73 107.03,95
  BOTTOM w0.076: UC1.AW36 108.61,103.58 v1(108.28,103.26)
  BOTTOM w0.102: JDIMM1.104 75.1,62.32 74.96,62.18 74.83,62.18 74.73,62.08 74.73,60.87 74.88,60.72 75.15,60.72 75.28,60.84 75.28,61 v1(75.2,61.08)
M_CLK_DDR#2: length 93.5
  IN3 w0.084: v1(107.25,107.67) 107.25,107.55 106.95,107.24 106.82,107.24 106.64,107.07 106.64,105.47 107.28,104.83 107.28,99.66 106.67,99.05 106.67,98.73 106.07,98.13 106.07,97.53 106.71,96.89 106.71,96.61 106.35,96.25 106.35,95.77
  IN3 w0.127: 106.35,95.77 106.35,89.33 118.75,76.93 119.44,76.93 119.57,76.8 119.57,76.11 119.84,75.84 120.46,75.84 120.73,76.11 120.73,76.8 120.87,76.93 121.27,76.93 121.41,76.8 121.41,75.18 121.67,74.91 122.3,74.91 122.57,75.18 122.57,76.8 122.7,76.93 123.1,76.93 123.24,76.8 123.24,75.24 123.56,74.91 149.92,74.91 151.39,73.45 151.39,72.74 151.97,72.16 152.82,72.16 152.95,72.04 152.95,71.8 152.73,71.59 152.73,71.18 153.04,70.87 153.87,70.87 154,70.74 154,70.23 153.87,70.1 153.5,70.1 153.23,69.83 153.23,69.12 153.5,68.85 153.87,68.85 154,68.73 154,68.01 153.8,67.8 153.8,67.32 153.74,67.26 153.5,67.26 153.37,67.39 v1(153.37,67.58)
  BOTTOM w0.076: UC1.AM38 107.64,107.82 107.5,107.67 v1(107.25,107.67)
  BOTTOM w0.102: v1(153.37,67.58) 153.37,67.37 153.22,67.22 153.09,67.22 152.97,67.34 152.97,69.89 153.35,70.27 JDIMM2.103
M_CLK_DDR#3: length 92
  IN3 w0.084: 105.46,93.66 105.46,94.05 105.47,94.06 105.47,98.38 106.06,98.97 106.06,105.01 106.27,105.23 106.27,107.72 105.98,108.02 105.98,108.55 106.33,108.91 106.78,108.91 107.03,108.66 107.15,108.66 107.25,108.76 v1(107.25,108.97)
  IN3 w0.127: 105.46,93.66 105.46,88.96 105.46,88.96 105.46,88.94 120.38,74.02 148.78,74.02 149.56,74.02 150.5,73.08 150.5,72.32 151.64,71.17 151.64,70.62 152.3,69.96 152.3,63.93 154.33,61.9 154.33,60.89 154.22,60.77 153.89,60.77 153.75,60.91 v1(153.75,61.12)
  BOTTOM w0.076: v1(107.25,108.97) 107.4,108.97 107.67,109.24 UC1.AK38
  BOTTOM w0.102: JDIMM2.104 153.65,62.35 153.34,62.05 153.34,60.87 153.46,60.76 153.63,60.76 153.75,60.88 v1(153.75,61.12)
M_ODT0: length 46.9
  TOP w0.165: v1(44.54,57.48) 44.16,57.48 42.57,59.07 42.57,61.56 R2348.2
  IN1 w0.183: v1(79.66,59.17) 79.66,59.14 77.02,56.5 45.52,56.5 v1(44.54,57.48)
  BOTTOM w0.165: v1(79.66,59.17) 78.83,60 78.83,61.76 78.7,61.89 JDIMM1.116
M_ODT1: length 44.6
  TOP w0.165: R2349.2 43.97,58.75 v1(44.54,58.18)
  IN1 w0.183: v1(79.66,60.7) 79.21,60.25 79.21,59.35 76.83,56.96 45.76,56.96 v1(44.54,58.18)
  BOTTOM w0.165: v1(79.66,60.7) 80.1,61.14 80.1,61.66 79.9,61.86 JDIMM1.120
M_ODT2: length 134.1
  TOP w0.165: v1(115.73,50.56) 115.28,51 114.09,51 v3(113.29,50.2) 112.95,49.86 95.77,49.86 90.18,55.44 45.59,55.44 41.81,59.22 41.81,61.69 R2350.2
  IN1 w0.183: v1(115.73,50.56) 116.31,49.97 119.4,49.97 119.41,49.98 151.8,49.98 154.33,52.51 154.33,55.12 154.33,55.13 154.33,56.81 v1(157.55,60.03)
  BOTTOM w0.165: JDIMM2.116 157.25,62.18 157.48,61.95 157.74,61.95 158.02,61.67 158.02,60.49 v1(157.55,60.03)
M_ODT3: length 135.4
  TOP w0.165: R2352.2 41.3,59.13 45.89,54.54 90.49,54.54 95.6,49.44 113.97,49.44 v1(115.09,50.56)
  IN1 w0.183: v1(157.55,58.5) 157.06,58.02 156.16,58.02 154.77,56.63 154.77,52.33 151.98,49.54 116.11,49.54 v1(115.09,50.56)
  BOTTOM w0.165: v1(157.55,58.5) 158.45,59.4 158.45,61.9 JDIMM2.120
MAA0_0: length 31.7
  TOP w0.102: v1(168.3,150.09) 167.94,150.45 UV5.K4
  IN3 w0.102: 177.07,135.39 177.07,133.87 177.32,133.61 177.32,132.09 176.54,131.31 176.54,130.85 v1(177.22,130.17) ; 172.05,149.58 168.81,149.58 v1(168.3,150.09)
  IN3 w0.157: 172.05,149.58 174.2,149.58 174.39,149.77 175.71,149.77 177.07,148.41 177.07,135.39
  BOTTOM w0.102: UV5.K4 167.94,150.45 v1(168.3,150.09) ; v1(177.22,130.17) 177.12,130.27 175.84,130.27 UV1.G24
MAA0_1: length 30
  TOP w0.102: UV5.K5 167.88,149.13 v1(167.97,149.04)
  IN3 w0.102: v1(167.97,149.04) 167.97,148.54 168.86,147.65 173.38,147.65 174.3,146.73 174.3,143.33 174.67,142.96 174.67,141.35 ; v1(176.05,129.17) 175.48,129.74 175.48,130.5 174.84,131.14 174.84,132.6 174.13,133.32 174.13,135.14
  IN3 w0.157: 174.13,135.14 174.13,136.98 174.28,137.14 174.79,137.14 174.91,137.26 174.91,137.64 174.79,137.77 174.28,137.77 174.13,137.93 174.13,140.8 174.67,141.35
  BOTTOM w0.102: v1(176.05,129.17) 176.66,128.56 UV1.J23 ; UV5.K5 167.88,149.13 v1(167.97,149.04)
MAA0_2: length 29.5
  TOP w0.102: UV5.K11 167.88,144.85 v1(167.48,145.25)
  IN3 w0.102: 173.87,141.49 173.87,142.47 173.47,142.87 173.47,146.42 172.81,147.08 168.43,147.08 167.86,146.51 167.86,145.62 167.49,145.25 v1(167.48,145.25) ; v1(174.97,129.68) 174.57,130.08 174.57,132.15 173.63,133.09 173.63,134.63
  IN3 w0.157: 173.63,134.63 173.63,134.63 173.63,138.34 173.47,138.5 173.37,138.5 173.25,138.62 173.25,139 173.37,139.13 173.47,139.13 173.63,139.28 173.63,139.6 173.47,139.76 172.59,139.76 172.46,139.88 172.46,140.26 172.59,140.39 173.47,140.39 173.63,140.54 173.63,141.09 173.87,141.33 173.87,141.49
  BOTTOM w0.102: v1(174.97,129.68) 175.46,129.19 UV1.H24 ; v1(167.48,145.25) 167.88,144.85 UV5.K11
MAA0_3: length 29.6
  TOP w0.102: v1(168.3,146.03) 167.92,145.65 UV5.K10
  IN3 w0.102: 172.69,135.39 172.69,133.61 174.29,132.01 174.29,129.92 174.29,129.59 174.58,129.3 175.35,129.3 v1(176.05,128.6) ; 172.87,141.35 173.07,141.55 173.07,143.65 172.69,144.03 172.69,146.25 172.37,146.57 168.81,146.57 168.3,146.06 v1(168.3,146.03)
  IN3 w0.157: 172.69,135.39 172.69,136.15 172.88,136.34 173.02,136.34 173.14,136.47 173.14,136.84 173.02,136.97 172.62,136.97 172.49,137.1 172.49,137.44 172.62,137.57 172.95,137.57 173.08,137.69 173.08,138.07 172.95,138.2 171.99,138.2 171.87,138.32 171.87,138.73 171.99,138.86 172.17,138.86 172.3,138.99 172.3,139.36 172.17,139.49 171.99,139.49 171.87,139.62 171.87,140.35 172.87,141.35
  BOTTOM w0.102: v1(176.05,128.6) 175.74,128.29 UV1.J24 ; UV5.K10 167.92,145.65 v1(168.3,146.03)
MAA0_4: length 30.1
  TOP w0.102: UV5.H11 v1(169.88,145.25)
  IN3 w0.102: v1(169.88,145.25) 170.07,145.25 171.11,144.21 171.11,143.38 171.5,142.99 171.5,141.48 171.38,141.35 ; v1(173.7,129.68) 173.31,130.07 173.31,130.58 172.94,130.95 172.94,132.34 171.86,133.42 171.86,134.06 170.84,135.08 170.34,135.08 170.03,135.39
  IN3 w0.157: 170.03,135.39 169.91,135.51 169.91,137.1 169.63,137.38 166.97,137.38 166.84,137.51 166.84,137.88 166.97,138.01 169.63,138.01 169.78,138.17 169.78,138.48 169.63,138.64 167.99,138.64 167.86,138.77 167.86,139.14 167.99,139.27 169.63,139.27 169.78,139.43 169.78,139.99 170.85,141.06 171.08,141.06 171.38,141.35
  BOTTOM w0.102: v1(173.7,129.68) 174.26,129.12 UV1.H26 ; UV5.H11 v1(169.88,145.25)
MAA0_5: length 30
  TOP w0.102: UV5.H10 v1(169.88,146.05)
  IN3 w0.102: 172.1,141.35 172.3,141.55 172.3,143.71 172.24,143.77 172.24,145.04 171.62,145.67 170.27,145.67 v1(169.88,146.05) ; v1(174.91,128.92) 174.53,128.92 174.22,129.23 174.21,129.23 174.08,129.36 174.08,129.52 174.08,129.52 174.08,129.84 174.08,129.84 174.08,131.9 172.3,133.68 172.3,135.27 172.2,135.37 172.2,135.39
  IN3 w0.157: 172.2,135.39 172.2,135.9 172.07,136.03 170.63,136.03 170.51,136.15 170.51,136.55 170.63,136.68 171.88,136.68 172.01,136.81 172.01,137.18 171.88,137.31 170.4,137.31 170.27,137.44 170.27,138.31 170.4,138.44 171.25,138.44 171.38,138.57 171.38,139.07 171.22,139.23 170.4,139.23 170.27,139.36 170.27,139.73 170.4,139.86 171.22,139.86 171.38,140.02 171.38,140.63 172.1,141.35
  BOTTOM w0.102: v1(174.91,128.92) 174.28,128.29 UV1.J26 ; UV5.H10 v1(169.88,146.05)
MAA0_6: length 30.3
  TOP w0.102: v1(169.81,149.17) 169.49,149.5 UV5.H5
  IN3 w0.102: 176.5,135.39 176.5,134.72 176.24,134.46 176.24,132.92 176.56,132.6 176.56,131.71 176.34,131.49 176.34,130.72 176.84,130.22 176.84,129.81 v1(177.13,129.52)
  IN3 w0.157: v1(169.81,149.17) 170.23,148.76 175.13,148.76 175.32,148.57 175.54,148.57 175.82,148.85 175.94,148.85 176.26,148.53 176.26,148.4 175.99,148.13 175.99,147.9 176.5,147.39 176.5,140.25 176.34,140.1 175.83,140.1 175.67,139.94 175.67,139.62 175.83,139.47 176.34,139.47 176.5,139.31 176.5,135.39
  BOTTOM w0.102: v1(177.13,129.52) 177.56,129.09 UV1.H21 ; UV5.H5 169.49,149.5 v1(169.81,149.17)
MAA0_7: length 34.2
  TOP w0.102: v1(169.08,150.85) 169.48,150.45 UV5.H4
  IN3 w0.102: v1(169.08,150.85) 169.08,150.91 169.45,151.27 169.45,151.8 169.71,152.07 170.04,152.07 170.64,152.66 175.11,152.66 175.43,152.34 ; 179.25,135.39 178.78,134.91 178.78,133.67 178.14,133.03 178.14,131.76 177.93,131.55 177.93,130.92 v1(178.46,130.39)
  IN3 w0.157: 179.25,135.39 179.25,149.07 177.88,150.43 176.59,151.73 175.91,152.41 175.84,152.41 175.78,152.34 175.43,152.34
  BOTTOM w0.102: v1(178.46,130.39) 177.97,129.89 UV1.G21 ; UV5.H4 169.48,150.45 v1(169.08,150.85)
MAA0_8: length 29.4
  TOP w0.102: UV5.J5 168.68,149.36 v1(168.94,149.11)
  IN3 w0.102: v1(168.94,149.11) 169.7,148.35 174.46,148.35 ; 175.99,135.39 175.99,134.69 175.8,134.5 175.8,131.74 176.05,131.49 176.05,130.72 176.64,130.13 176.64,129.45 v1(177.17,128.92)
  IN3 w0.157: 174.46,148.35 175.9,146.91 175.9,141.17 175.1,140.38 175.1,139.11 175.26,138.95 175.86,138.95 175.99,138.83 175.99,135.39
  BOTTOM w0.102: UV5.J5 168.68,149.36 v1(168.94,149.11) ; v1(177.17,128.92) 176.99,129.09 UV1.H23
MAA1_0: length 30.4
  TOP w0.102: v1(188.75,149.17) 188.75,150.03 UV3.K4
  IN3 w0.102: v1(188.75,149.17) 187.6,148.02 183.66,148.02 182.13,146.48 ; v1(179.68,129.05) 180.25,129.61 180.25,130.35 180.81,130.91 180.81,131.23 180.25,131.78 180.25,133.4 181.97,135.12 182.04,135.12 182.31,135.39
  IN3 w0.157: 182.13,146.48 181.81,146.17 181.81,138.2 182.31,137.71 182.31,135.39
  BOTTOM w0.102: v1(179.68,129.05) 179.73,129.09 UV1.H19 ; UV3.K4 188.75,150.03 v1(188.75,149.17)
MAA1_1: length 29.6
  TOP w0.102: UV3.K5 188.37,149.58 187.99,149.97 v1(187.99,150)
  IN3 w0.102: v1(178.59,129.49) 179.05,129.95 179.05,133.37 179.18,133.5 179.18,134.33 180.24,135.39 ; 182.13,149.35 182.52,149.74 183.04,149.74 183.68,150.39 187.59,150.39 v1(187.99,150)
  IN3 w0.157: 180.24,135.39 180.24,147.46 182.13,149.35
  BOTTOM w0.102: v1(178.59,129.49) 178.99,129.09 UV1.H20 ; UV3.K5 188.37,149.58 187.99,149.97 v1(187.99,150)
MAA1_2: length 27.8
  TOP w0.102: UV3.K11 v1(188.79,145.18)
  IN3 w0.102: 186.27,135.39 186.27,135.18 185.25,134.16 185.25,133.31 184.65,132.71 184.65,131.91 184.31,131.57 184.31,130.82 183.73,130.25 183.73,129.74 183.29,129.3 v1(183.29,128.73) ; v1(188.79,145.18) 188.77,145.16 188.04,145.16 187.61,144.73 187.61,142.34 187.98,141.98 187.98,141.41 188.1,141.29
  IN3 w0.157: 188.1,141.29 188.14,141.25 188.14,139.66 188.29,139.51 188.97,139.51 189.1,139.38 189.1,139 188.97,138.88 188.29,138.88 188.14,138.72 188.14,138.4 188.29,138.25 189.34,138.25 189.47,138.12 189.47,137.74 189.34,137.62 188.29,137.62 188.14,137.46 188.14,137.17 188.04,137.08 187.2,137.08 186.95,136.83 186.95,136.19 186.27,135.5 186.27,135.39
  BOTTOM w0.102: UV3.K11 v1(188.79,145.18) ; v1(183.29,128.73) 183.51,128.51 183.51,127.34 183.72,127.13 183.99,127.13 184.44,126.69 UV1.L13
MAA1_3: length 25.9
  TOP w0.102: UV3.K10 188.4,145.62 188.04,145.97 v1(188.01,145.97)
  IN3 w0.102: v1(188.01,145.97) 188.01,146.39 187.89,146.52 186.14,146.52 186.01,146.39 186.01,145.86 185.58,145.43 185.58,141.29 ; v1(182.11,130.29) 182.11,130.53 182.5,130.92 182.5,131.49 182.73,131.72 183.6,131.72 183.95,132.07 183.95,134.35 184.78,135.18 184.78,135.39
  IN3 w0.157: 184.78,135.39 184.78,139.71 184.91,139.84 186.27,139.84 186.4,139.96 186.4,140.34 186.27,140.47 184.91,140.47 184.78,140.59 184.78,140.97 184.91,141.1 185.45,141.1 185.58,141.22 185.58,141.29
  BOTTOM w0.102: v1(182.11,130.29) 182.51,129.89 UV1.G16 ; v1(188.01,145.97) 188.04,145.97 188.4,145.62 UV3.K10
MAA1_4: length 26.3
  TOP w0.102: v1(189.59,145.18) 189.6,145.18 UV3.H11
  IN3 w0.102: v1(182.11,129.09) 182.79,129.77 182.79,130.26 183.18,130.65 183.84,130.65 184.07,130.87 184.07,131.62 184.45,132 184.45,132.8 185.04,133.39 185.04,134.45 185.77,135.18 185.77,135.39 ; 187.45,141.29 187.18,141.56 187.18,144.63 187.91,145.36 188.23,145.36 188.47,145.6 189.18,145.6 v1(189.59,145.18)
  IN3 w0.157: 187.45,141.29 187.65,141.09 187.65,139.05 187.52,138.93 187.28,138.93 187.15,138.8 187.15,138.42 187.28,138.3 187.52,138.3 187.65,138.17 187.65,137.69 187.52,137.57 185.9,137.57 185.77,137.44 185.77,137.06 185.9,136.94 186.34,136.94 186.46,136.81 186.46,136.43 186.34,136.31 185.9,136.31 185.77,136.18 185.77,135.39
  BOTTOM w0.102: v1(189.59,145.18) 189.6,145.18 UV3.H11 ; v1(182.11,129.09) 182.66,128.54 UV1.J16
MAA1_5: length 26.7
  TOP w0.102: v1(189.59,145.98) 189.6,145.98 UV3.H10
  IN3 w0.102: 186.38,141.29 186.38,142.8 186.81,143.23 186.81,145.34 187.04,145.56 188.15,145.56 188.44,145.86 188.44,146.14 188.66,146.36 189.21,146.36 v1(189.59,145.98) ; 185.28,135.39 185.28,135.18 184.24,134.15 184.24,132.08 183.62,131.46 183.46,131.46 183.31,131.3 183.31,131.06 182.59,130.35 182.59,130.17 v1(182.11,129.69)
  IN3 w0.157: 185.28,135.39 185.28,136.06 185.27,136.06 185.27,137.93 185.4,138.05 186.08,138.05 186.21,138.18 186.21,138.56 186.08,138.68 185.4,138.68 185.27,138.81 185.27,139.22 185.4,139.35 187.03,139.35 187.16,139.48 187.16,140.78 187.03,140.92 186.53,140.92 186.38,141.07 186.38,141.29
  BOTTOM w0.102: v1(189.59,145.98) 189.6,145.98 UV3.H10 ; v1(182.11,129.69) 182.66,129.14 UV1.H16
MAA1_6: length 29.9
  TOP w0.102: UV3.H5 190.32,149.26 v1(190.32,148.28)
  IN3 w0.102: 183.79,135.39 183.79,135.18 182.96,134.35 182.96,132.56 182.69,132.29 181.81,132.29 181.57,132.05 181.57,131.66 181.47,131.56 181.47,129.56 180.9,128.99 v1(180.9,128.91) ; 183.79,141.29 183.79,141.44 183.98,141.63 183.98,143.05 184.57,143.64 184.57,144.07 184.41,144.23 184.41,146.14 184.57,146.3 184.57,146.43 185.46,147.32 189.36,147.32 v1(190.32,148.28)
  IN3 w0.157: 183.79,135.39 183.79,141.29
  BOTTOM w0.102: v1(180.9,128.91) 181.46,128.34 UV1.J17 ; UV3.H5 190.32,149.26 v1(190.32,148.28)
MAA1_7: length 29.5
  TOP w0.102: v1(190.4,150) 190.38,150 UV3.H4
  IN3 w0.102: v1(190.4,150) 189.96,149.56 189.96,148.85 188.62,147.52 184.94,147.52 183.61,146.19 183.61,145.84 183.38,145.62 183.38,144.73 183.58,144.54 183.58,143.43 183.21,143.06 183.21,141.37 183.3,141.29 ; 183.3,135.39 183.3,135.22 182.34,134.27 182.34,133.46 182.05,133.16 181.76,133.16 181.36,132.77 181.36,131.74 181.26,131.65 181.26,129.9 v1(180.89,129.52)
  IN3 w0.157: 183.3,141.29 183.3,135.39
  BOTTOM w0.102: v1(190.4,150) 190.38,150 UV3.H4 ; v1(180.89,129.52) 181.61,129.52 181.74,129.39 181.74,129.22 181.61,129.09 UV1.H17
MAA1_8: length 30.6
  TOP w0.102: v1(189.58,149.11) 189.2,149.49 UV3.J5
  IN3 w0.102: v1(179.67,128.46) 179.67,128.47 180.45,129.25 180.45,130.27 181.01,130.83 181.01,131.31 180.45,131.87 180.45,133.31 182.06,134.92 182.33,134.92 182.8,135.39 ; v1(189.58,149.11) 188.28,147.81 183.91,147.81 182.59,146.5 182.59,146.29 182.31,146.01 182.31,141.29
  IN3 w0.157: 182.31,141.29 182.31,138.41 182.8,137.91 182.8,135.39
  BOTTOM w0.102: UV3.J5 189.2,149.49 v1(189.58,149.11) ; v1(179.67,128.46) 179.89,128.68 180.14,128.68 180.26,128.55 UV1.J19
MAB0_0: length 34
  TOP w0.102: v1(212.4,133.49) 212.76,133.85 UV7.K4
  IN3 w0.102: 194.39,123.58 194.3,123.67 193.55,123.67 193.19,124.04 190.41,124.04 189.72,123.34 v1(189.38,123.34) ; 211.89,129.75 211.89,132.98 v1(212.4,133.49)
  IN3 w0.157: 194.39,123.58 200.56,123.58 201.7,124.72 210.72,124.72 212.08,126.09 212.08,127.4 211.89,127.59 211.89,129.75
  BOTTOM w0.102: v1(189.38,123.34) 188.86,123.86 UV1.P8 ; v1(212.4,133.49) 212.76,133.85 UV7.K4
MAB0_1: length 32.9
  TOP w0.102: v1(211.36,133.82) 211.44,133.91 UV7.K5
  IN3 w0.102: v1(211.36,133.82) 210.85,133.82 209.96,132.94 209.96,128.41 209.04,127.49 205.64,127.49 205.27,127.12 203.66,127.12 ; v1(187.54,123.52) 187.61,123.52 188.46,124.37 188.46,124.37 188.68,124.59 188.68,124.59 188.81,124.72 188.97,124.72 189.19,124.94 189.51,124.94 189.6,124.85 191.29,124.85 192.55,126.11 194.39,126.11
  IN3 w0.157: 194.39,126.11 200.32,126.11 201.33,127.12 203.66,127.12
  BOTTOM w0.102: UV7.K5 211.44,133.91 v1(211.36,133.82) ; UV1.T9 188.06,123 v1(187.54,123.52)
MAB0_2: length 31.6
  TOP w0.102: v1(207.56,134.31) 207.16,133.91 UV7.K11
  IN3 w0.102: v1(188.3,124.75) 188.79,125.23 190.25,125.23 190.83,125.81 190.99,125.81 191.55,126.37 194.07,126.37 194.3,126.6 194.39,126.6 ; 203.66,127.85 203.8,127.85 203.88,127.92 204.78,127.92 205.18,128.33 209.12,128.33 209.39,128.6 209.39,133.36 208.82,133.93 207.93,133.93 207.56,134.3 v1(207.56,134.31)
  IN3 w0.157: 194.39,126.6 200.13,126.6 201.38,127.85 203.66,127.85
  BOTTOM w0.102: UV7.K11 207.16,133.91 v1(207.56,134.31) ; v1(188.3,124.75) 188.3,124.33 UV1.P9
MAB0_3: length 31.4
  TOP w0.102: UV7.K10 207.96,133.87 v1(208.35,133.49)
  IN3 w0.102: v1(189.9,125.86) 190.06,125.86 191.15,126.95 191.48,126.95 192.13,127.59 194.39,127.59 ; 203.66,129.49 206.02,129.49 206.09,129.55 207.36,129.55 207.98,130.17 207.98,133.12 v1(208.35,133.49)
  IN3 w0.157: 194.39,127.59 195.75,127.59 195.87,127.72 195.87,128.75 196,128.88 196.38,128.88 196.5,128.75 196.5,127.72 196.63,127.59 197.01,127.59 197.13,127.72 197.13,128.6 197.37,128.83 198.66,128.83 199.26,129.42 200.37,129.42 200.5,129.55 200.5,129.75 200.63,129.87 201.25,129.87 201.38,129.75 201.38,128.96 201.5,128.83 201.88,128.83 202.01,128.96 202.01,129.74 202.13,129.87 202.59,129.87 202.72,129.74 202.72,128.96 202.85,128.83 203.29,128.83 203.42,128.96 203.42,129.36 203.55,129.49 203.66,129.49
  BOTTOM w0.102: UV7.K10 207.96,133.87 v1(208.35,133.49) ; UV1.N7 189.66,125.62 v1(189.9,125.86)
MAB0_4: length 31.4
  TOP w0.102: UV7.H11 v1(207.56,131.91)
  IN3 w0.102: v1(207.56,131.91) 207.56,131.72 206.52,130.68 205.69,130.68 205.3,130.29 203.79,130.29 203.66,130.41 ; 194.39,128.09 192.12,128.09 191.32,127.29 191.21,127.29 190.15,126.24 189.74,126.24 189.39,125.89 v1(189.24,125.89)
  IN3 w0.157: 194.39,128.09 194.52,128.09 195.8,129.37 196.51,129.37 196.68,129.54 196.68,131.96 196.81,132.09 197.18,132.09 197.31,131.96 197.31,129.45 197.44,129.32 197.81,129.32 197.94,129.45 197.94,130.88 198.07,131.01 198.44,131.01 198.57,130.88 198.57,130 198.7,129.88 199.07,129.88 199.2,130 199.2,130.87 199.33,131 201.09,131 201.44,130.65 203.43,130.65 203.66,130.41
  BOTTOM w0.102: UV7.H11 v1(207.56,131.91) ; v1(189.24,125.89) 188.86,125.51 UV1.N8
MAB0_5: length 31.9
  TOP w0.102: UV7.H10 v1(208.36,131.91)
  IN3 w0.102: 203.66,128.46 203.93,128.73 205.96,128.73 206.34,129.11 208.56,129.11 208.88,129.42 208.88,131.39 v1(208.36,131.91) ; 194.39,127.1 194.36,127.13 192.02,127.13 190.91,126.02 190.69,126.02 190.15,125.48 188.99,125.48 v1(188.56,125.91)
  IN3 w0.157: 194.39,127.1 197.51,127.1 197.64,127.23 197.64,128.22 197.77,128.34 198.14,128.34 198.27,128.22 198.27,127.22 198.4,127.09 198.77,127.09 198.9,127.22 198.9,128.38 199.03,128.5 199.4,128.5 199.53,128.38 199.53,127.32 199.66,127.2 200.03,127.2 200.16,127.32 200.16,128.22 200.29,128.34 203.55,128.34 203.66,128.46
  BOTTOM w0.102: UV7.H10 v1(208.36,131.91) ; v1(188.56,125.91) 188.06,125.41 UV1.N9
MAB0_6: length 32.5
  TOP w0.102: UV7.H5 211.81,132.31 v1(211.48,131.98)
  IN3 w0.102: v1(188.06,122.32) 188.94,123.2 188.94,123.49 189.23,123.77 189.86,123.77 190.33,124.24 194.23,124.24 194.39,124.08
  IN3 w0.157: v1(211.48,131.98) 211.07,131.57 211.07,126.66 209.71,125.3 201.58,125.3 200.36,124.08 194.39,124.08
  BOTTOM w0.102: v1(211.48,131.98) 211.81,132.31 UV7.H5 ; UV1.U9 v1(188.06,122.32)
MAB0_7: length 37.7
  TOP w0.102: v1(213.16,132.71) 212.76,132.31 UV7.H4
  IN3 w0.102: v1(213.16,132.71) 213.22,132.71 213.59,132.34 214.11,132.34 214.38,132.08 214.38,131.75 214.98,131.15 214.98,126.68 214.66,126.36 214.66,125.95 ; v1(189.13,121.17) 189.54,120.76 191.26,120.76 191.54,121.04 192.91,121.04 193.23,121.36 194.36,121.36 194.39,121.33
  IN3 w0.157: 194.39,121.33 201.11,121.33 202.32,122.54 211.38,122.54 212.75,123.91 214.66,125.82 214.66,125.95
  BOTTOM w0.102: UV1.U8 188.86,121.44 v1(189.13,121.17) ; v1(213.16,132.71) 212.76,132.31 UV7.H4
MAB0_8: length 31.7
  TOP w0.102: UV7.J5 211.67,133.11 v1(211.42,132.85)
  IN3 w0.102: 209.28,125.95 210.66,127.33 210.66,132.09 v1(211.42,132.85) ; 194.39,124.67 193.71,124.67 193.68,124.64 191.99,124.64 191.79,124.45 190.06,124.45 189.59,123.98 189.14,123.98 188.56,123.39 v1(188.43,123.39)
  IN3 w0.157: 194.39,124.67 200.27,124.67 201.49,125.89 209.22,125.89 209.28,125.95
  BOTTOM w0.102: v1(188.43,123.39) 188.86,122.96 UV1.T8 ; v1(211.42,132.85) 211.67,133.11 UV7.J5
MAB1_0: length 32.2
  TOP w0.102: UV9.K4 212.21,113.15 211.41,113.15 v1(211.17,112.91)
  IN3 w0.102: 194.39,117.76 193.22,117.76 193.13,117.85 190.99,117.85 190.47,118.37 190.47,118.62 190.16,118.93 188.89,118.93 v1(188.48,118.52) ; 203.47,118.61 203.56,118.69 205.25,118.69 205.61,118.33 206.73,118.33 206.92,118.52 207.8,118.52 208.02,118.3 208.37,118.3 208.84,117.83 208.84,117.59 209.71,116.72 209.71,114.37 v1(211.17,112.91)
  IN3 w0.157: 194.39,117.76 202.63,117.76 203.47,118.61
  BOTTOM w0.102: UV9.K4 212.21,113.15 211.41,113.15 v1(211.17,112.91) ; UV1.Y9 188.06,118.94 v1(188.48,118.52)
MAB1_1: length 32.9
  TOP w0.102: v1(212.18,113.92) 211.78,113.51 UV9.K5
  IN3 w0.102: v1(188.26,119.91) 188.7,120.35 191.43,120.35 191.63,120.56 192.98,120.56 193.14,120.39 193.15,120.39 193.17,120.37 193.69,120.37 193.74,120.33 193.86,120.2 194.39,120.2 ; 211.24,119.78 211.93,119.09 211.93,118.35 211.75,118.17 211.75,114.85 211.74,114.84 211.74,114.36 v1(212.18,113.92)
  IN3 w0.157: 211.24,119.78 209.54,121.47 202.65,121.47 201.38,120.2 194.39,120.2
  BOTTOM w0.102: UV9.K5 211.78,113.51 v1(212.18,113.92) ; v1(188.26,119.91) 188.06,120.11 UV1.W9
MAB1_2: length 28.2
  TOP w0.102: UV9.K11 v1(207.37,113.11)
  IN3 w0.102: v1(189.13,116.41) 189.51,116.79 190.15,116.79 190.79,116.14 191.63,116.14 192.99,114.78 194.39,114.78 ; v1(207.37,113.11) 207.37,113.37 207.74,113.73 207.74,114.18 207.61,114.31 207.23,114.31 206.81,114.73 203.74,114.73 203.71,114.75 203.47,114.75
  IN3 w0.157: 194.39,114.78 195.39,114.78 197.03,113.15 198.73,113.15 198.85,113.27 198.85,114.08 198.98,114.2 199.36,114.2 199.48,114.08 199.48,113.27 199.61,113.15 199.99,113.15 200.11,113.27 200.11,114.63 200.24,114.76 200.62,114.76 200.74,114.63 200.74,114.31 200.87,114.18 201.26,114.18 201.39,114.31 201.39,115.07 201.51,115.2 203.03,115.2 203.47,114.75
  BOTTOM w0.102: v1(189.13,116.41) 189.11,116.41 188.86,116.65 UV1.AC8 ; UV9.K11 v1(207.37,113.11)
MAB1_3: length 36.5
  TOP w0.102: v1(207.36,113.89) 207.74,113.51 UV9.K10
  IN3 w0.102: 194.39,113.5 193.45,113.5 192.42,114.53 192.42,114.99 191.47,115.94 188.9,115.94 v1(188.46,116.39) ; v1(207.36,113.89) 207.27,113.89 206.87,114.29 204.52,114.29 204.16,113.93 203.47,113.93
  IN3 w0.157: 194.39,113.5 195.99,113.5 196.83,112.66 197.29,112.66 197.45,112.5 197.45,109.99 197.58,109.87 197.95,109.87 198.08,109.99 198.08,112.5 198.24,112.66 198.55,112.66 198.71,112.5 198.71,110.37 198.84,110.25 199.21,110.25 199.34,110.37 199.34,112.5 199.5,112.66 200.59,112.66 200.75,112.82 200.75,113.57 200.87,113.7 201.25,113.7 201.38,113.57 201.38,112.88 201.5,112.75 201.9,112.75 202.02,112.88 202.02,113.77 202.31,114.06 202.31,114.58 202.44,114.71 202.81,114.71 202.94,114.58 202.94,114.09 203.1,113.93 203.47,113.93
  BOTTOM w0.102: UV1.AC9 188.46,116.5 v1(188.46,116.39) ; v1(207.36,113.89) 207.74,113.51 UV9.K10
MAB1_4: length 28.6
  TOP w0.102: v1(207.37,112.31) 206.97,111.91 UV9.H11
  IN3 w0.102: v1(189.93,117.35) 190.3,116.98 192.21,116.98 193.38,115.81 194.39,115.81 ; v1(207.37,112.31) 207.79,112.73 207.79,113.24 207.94,113.4 207.94,114.44 207.77,114.61 207.77,114.85 207.53,115.09 205.42,115.09 204.98,115.53 203.47,115.53
  IN3 w0.157: 194.39,115.81 195.76,115.81 195.99,115.58 195.99,114.88 197.23,113.63 198.24,113.63 198.37,113.76 198.37,115.56 198.49,115.68 198.87,115.68 199,115.56 199,114.82 199.12,114.69 199.5,114.69 199.63,114.82 199.63,115.56 199.75,115.68 203.32,115.68 203.47,115.53
  BOTTOM w0.102: v1(189.93,117.35) 189.93,117.82 UV1.AA7 ; v1(207.37,112.31) 206.97,111.91 UV9.H11
MAB1_5: length 29.7
  TOP w0.102: v1(208.17,112.31) 207.77,111.91 UV9.H10
  IN3 w0.102: v1(208.17,112.31) 208.55,112.69 208.55,115.67 208.33,115.89 208.05,115.89 207.65,116.29 203.75,116.29 203.63,116.17 203.47,116.17 ; 194.39,116.3 193.18,116.3 192.25,117.23 190.59,117.23 190.09,117.73 189.64,117.73 v1(189.26,117.35)
  IN3 w0.157: 203.47,116.17 198.04,116.17 197.88,116.02 197.88,114.31 197.75,114.18 197.38,114.18 197.25,114.31 197.25,116.17 197.12,116.3 194.39,116.3
  BOTTOM w0.102: UV1.AA8 188.86,118.09 189.26,117.69 v1(189.26,117.35) ; UV9.H10 207.77,111.91 v1(208.17,112.31)
MAB1_6: length 30.9
  TOP w0.102: UV9.H5 211.44,111.59 v1(210.47,111.59)
  IN3 w0.102: 194.39,117.28 193.13,117.28 192.77,117.64 190.76,117.64 190.26,118.14 189.58,118.14 189.2,118.51 v1(189.2,118.52) ; v1(210.47,111.59) 209.5,112.55 209.5,116.45 208.46,117.49 206.41,117.49 206.26,117.34 205.83,117.34 205.24,117.93 203.55,117.93 203.47,117.86
  IN3 w0.157: 203.47,117.86 202.89,117.28 194.39,117.28
  BOTTOM w0.102: UV9.H5 211.44,111.59 v1(210.47,111.59) ; v1(189.2,118.52) 189.2,118.95 UV1.Y8
MAB1_7: length 31.4
  TOP w0.102: UV9.H4 212.57,111.89 v1(212.19,111.51)
  IN3 w0.102: v1(212.19,111.51) 211.8,111.13 210.08,111.13 209.3,111.91 209.3,115.72 208.33,116.69 204.56,116.69 204.13,117.13 203.47,117.13 ; v1(188.56,117.39) 189.11,117.94 190.17,117.94 190.67,117.43 192.5,117.43 193.15,116.79 194.39,116.79
  IN3 w0.157: 194.39,116.79 203.1,116.79 203.44,117.13 203.47,117.13
  BOTTOM w0.102: UV1.AA9 188.06,117.89 v1(188.56,117.39) ; v1(212.19,111.51) 212.57,111.89 UV9.H4
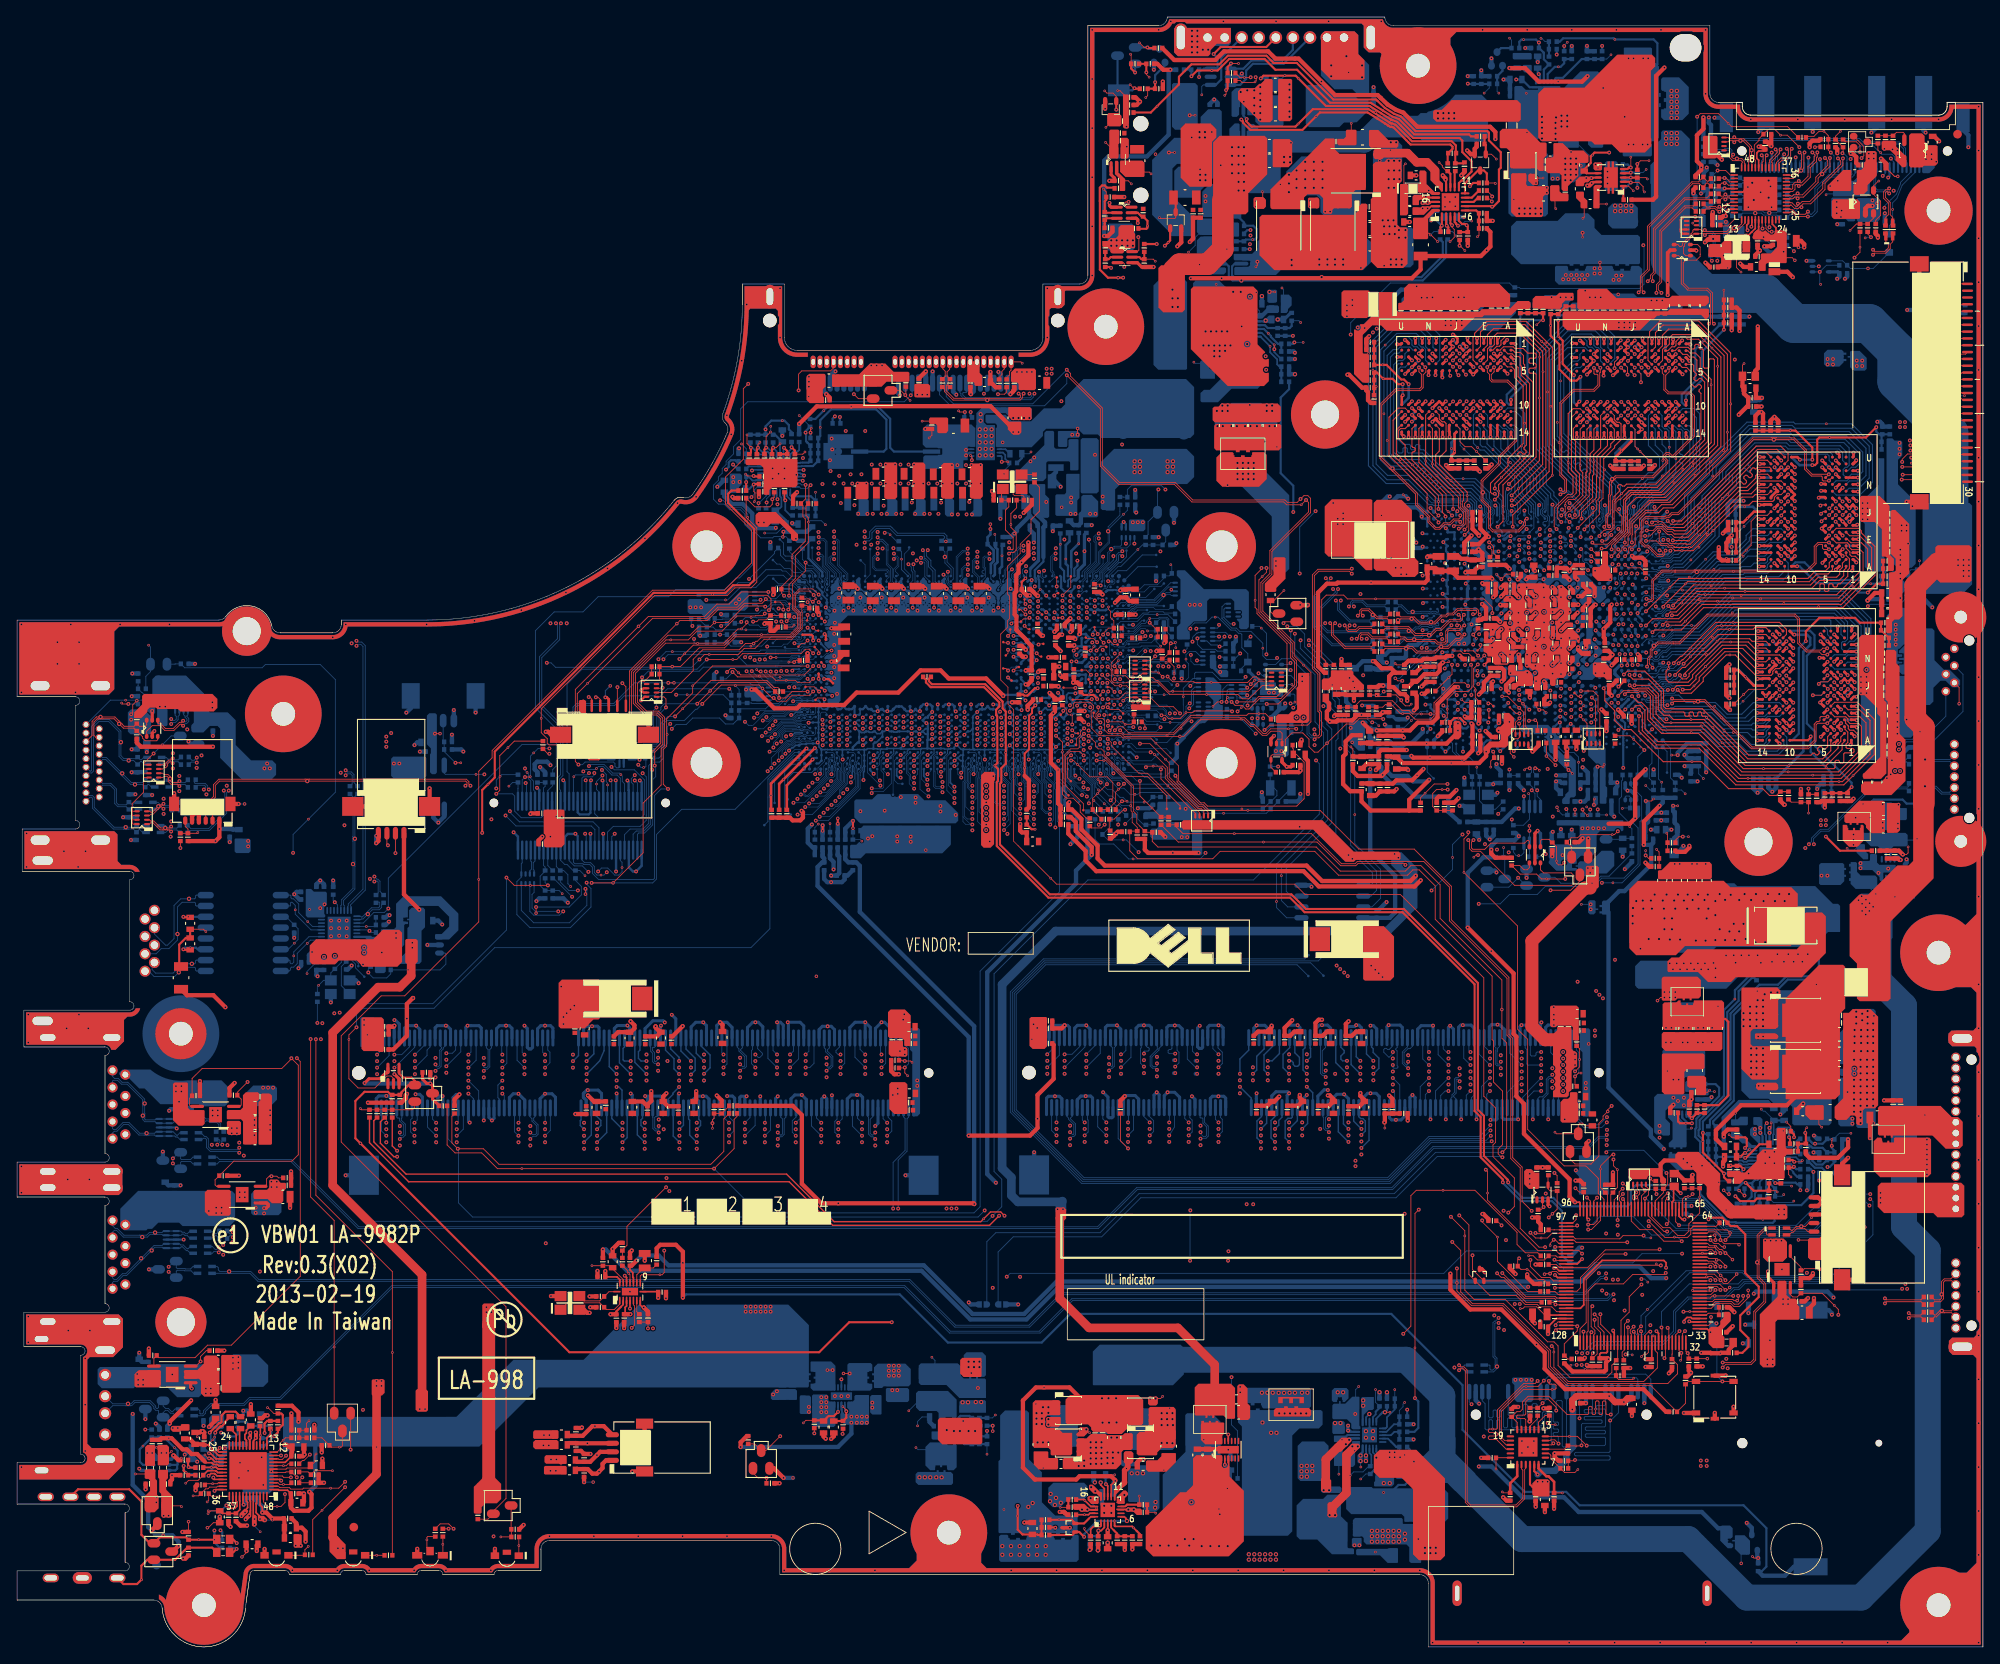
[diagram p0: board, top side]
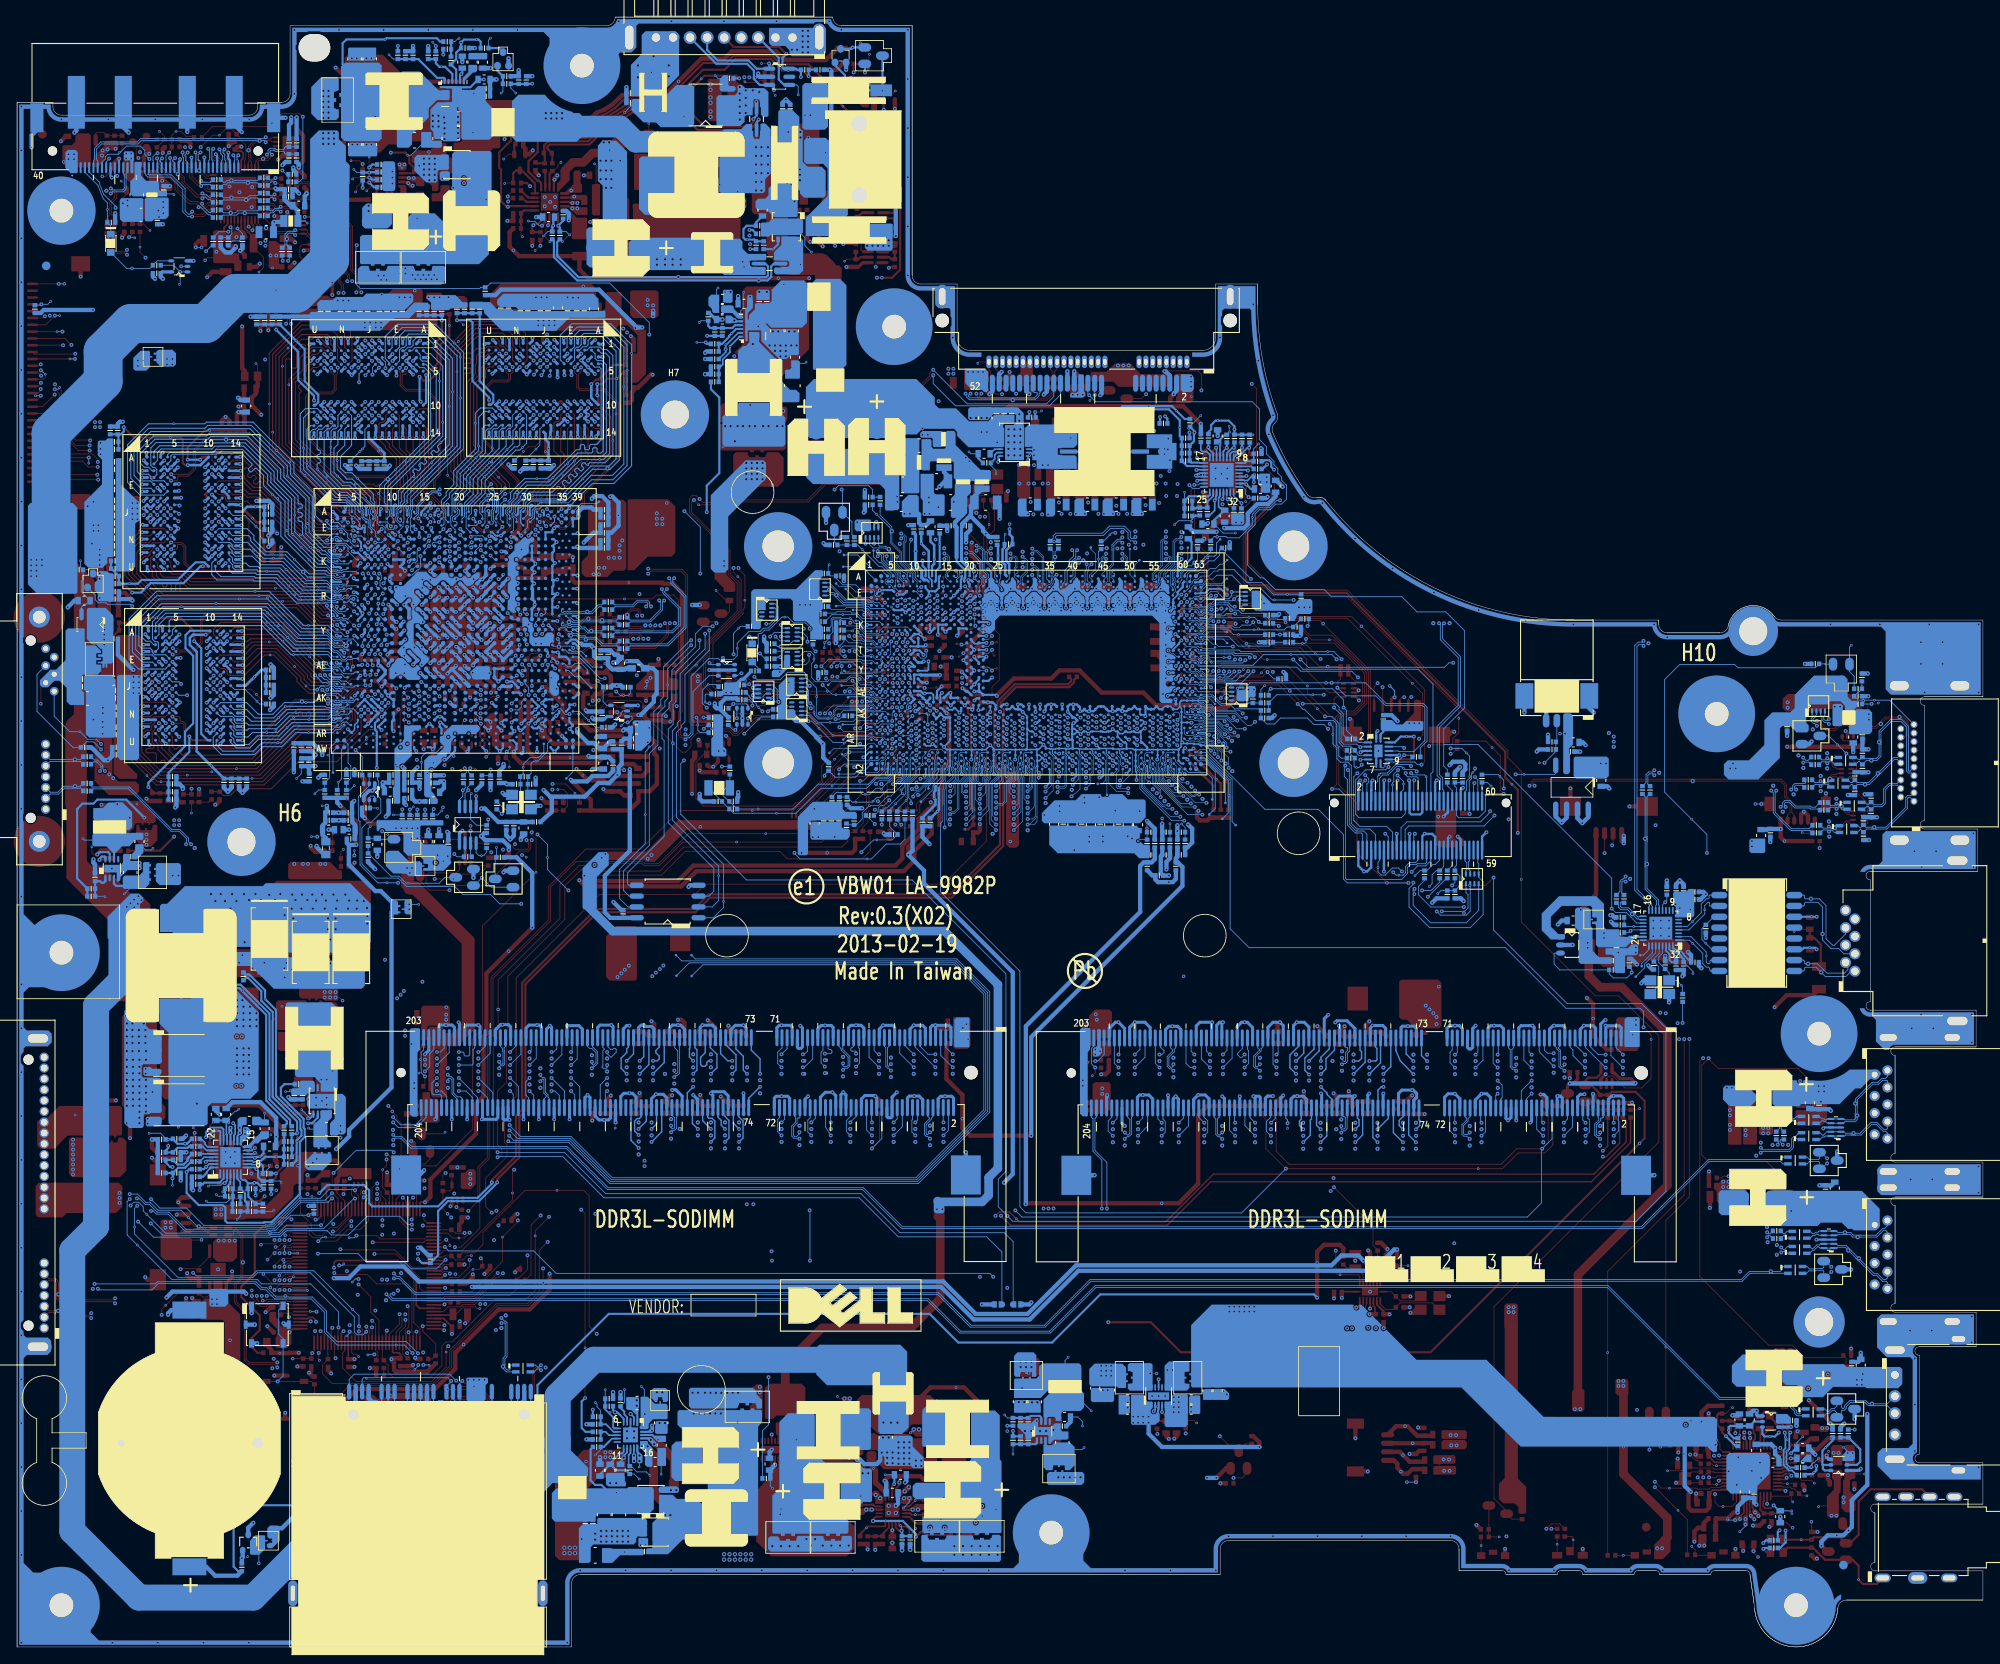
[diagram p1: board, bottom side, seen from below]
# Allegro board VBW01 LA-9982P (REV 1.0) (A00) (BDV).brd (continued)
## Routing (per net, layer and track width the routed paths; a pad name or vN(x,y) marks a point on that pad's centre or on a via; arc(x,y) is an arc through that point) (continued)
MAB1_8: length 31.7
  TOP w0.102: v1(212.22,112.33) 211.84,112.71 UV9.J5
  IN3 w0.102: v1(189.24,119.74) 189.62,119.35 190.31,119.35 190.53,119.14 191.3,119.14 191.51,119.35 191.99,119.35 192.27,119.07 193.07,119.07 193.4,118.74 194.39,118.74 ; 208.67,119.78 210.2,118.25 210.2,114.78 212.22,112.76 v1(212.22,112.33)
  IN3 w0.157: 194.39,118.74 202.02,118.74 203.27,119.99 208.46,119.99 208.67,119.78
  BOTTOM w0.102: UV1.W8 189.24,120.12 v1(189.24,119.74) ; v1(212.22,112.33) 211.84,112.71 UV9.J5
MCT0: length 3.4
  TOP w0.254: v1(19.49,85.61) 19.55,85.55 RL19.1
  BOTTOM w0.254: v1(19.49,85.61) v3(20.07,85.61) TL1.14
MCT1: length 3.6
  TOP w0.254: RL20.1 19.55,81.74 v1(19.49,81.8)
  BOTTOM w0.254: TL1.11 21.17,81.8 20.98,81.98 v3(20.3,81.98) 19.67,81.98 v1(19.49,81.8)
MDI0+: length 7.1
  BOTTOM w0.102: UL1.1 35.1,82.87 35.09,82.87 34.38,82.87 34.01,82.5 ; TL1.8 31.91,79.26 32.03,79.39 32.03,79.58 32.16,79.7 32.42,79.7 32.83,80.12 32.83,81.32 34.01,82.5 ; 34.01,82.5 v3(34.01,82.49)
MDI0-: length 7.1
  BOTTOM w0.102: TL1.7 31.89,80.53 31.99,80.43 31.99,80.21 32.1,80.11 32.25,80.11 32.43,80.29 v3(32.43,81.03) 32.43,81.49 34.21,83.28 UL1.2
MDI1+: length 7.1
  BOTTOM w0.102: UL1.4 35.19,84.07 35.18,84.07 34.46,84.07 32.6,85.92 v3(32.6,86.43) 32.6,86.94 32.23,87.31 32.12,87.31 32.06,87.25 32.06,86.93 32.01,86.88 TL1.2
MDI1-: length 7
  BOTTOM w0.102: UL1.5 34.63,84.47 v3(34.06,85.04) 33.01,86.09 33.01,87.11 32.4,87.72 32.21,87.72 32.1,87.83 32.1,88.06 32.01,88.15 TL1.1
MDO0+: length 8.1
  BOTTOM w0.102: TL1.9 21.01,79.26 20.91,79.36 20.91,79.59 20.8,79.69 19.55,79.69 v2(18.95,79.09) 18.46,78.6 16.07,78.6 15.43,79.23 JLAN.1
MDO0-: length 8.2
  BOTTOM w0.102: JLAN.2 15.83,79.98 15.83,79.41 16.23,79 18.29,79 18.66,79.38 19.38,80.1 v2(20.49,80.1) 20.8,80.1 20.91,80.2 20.91,80.43 21.01,80.53 TL1.10
MDO1+: length 12.2
  BOTTOM w0.102: TL1.15 21.01,86.88 20.91,86.98 20.91,87.21 20.8,87.31 19.35,87.31 18.8,86.76 v2(18.8,83.59) 18.8,82.88 17.8,81.87 16.89,81.87 16.29,81.27 JLAN.3
MDO1-: length 12.1
  BOTTOM w0.102: TL1.16 21.01,88.15 20.91,88.05 20.91,87.82 20.8,87.72 v2(20.16,87.72) 19.18,87.72 18.39,86.93 18.39,83.05 17.63,82.28 17.4,82.28 16.1,83.58 JLAN.6
ME_EN: length 89.1
  TOP w0.102: UE1.99 180.16,48.91 180.16,48.91 RE326.1 179.42,48.91 178.96,48.45 178.04,48.45 v1(177.96,48.54)
  IN1 w0.127: v1(139.28,93.1) 139.67,93.1 155.24,77.53 157.27,77.53 159.65,75.15 169.27,75.15 173.17,71.26 173.17,64.3 173.98,63.49 173.98,60.42 176.37,58.04 176.37,48.97 177.19,48.14 177.56,48.14 v1(177.96,48.54)
  BOTTOM w0.089: 126.8,94.22 126.34,94.68 RC8.1
  BOTTOM w0.102: 126.8,94.22 126.88,94.14 128.53,94.14 130.28,92.39 v3(130.8,92.39) 138.64,92.39 139.28,93.04 v1(139.28,93.1)
ME_SUS_PWR_ACK: length 111.5
  TOP w0.102: RC42.1 RC27.2 135.91,96.1 136.65,95.36 v3(142.66,95.36) 151.7,95.36 155.22,91.83 156.81,91.83 157.08,92.1 164.86,92.1 167.87,89.09 167.87,85.14 174.62,78.39 174.62,71.72 175.06,71.28 175.06,57.27 176.17,56.16 176.17,49.08 178.38,46.87 v1(179.09,46.87) ; UE1.34 198.25,37.71 198.53,37.98 v1(198.53,38.68)
  IN3 w0.127: v1(179.09,46.87) 179.49,46.47 180.05,46.47 182.05,44.47 184.19,44.47 184.95,45.24 187.08,45.24 188.34,46.5 189.9,46.5 190.57,45.84 193.31,45.84 197.37,41.77 197.37,39.57 198.26,38.68 v1(198.53,38.68)
ME_SUS_PWR_ACK_R: length 11.2
  TOP w0.089: v1(131.6,101.54) 131.6,101.44
  TOP w0.102: 131.6,101.44 131.6,99.78 v3(133.02,98.36) RC35.1 RC42.2
  BOTTOM w0.076: UC1.AV4 128.63,103.93 128.63,103.46 128.68,103.4 128.68,102.79 129.25,102.22 130.55,102.22 131.23,101.54 v1(131.6,101.54)
MECH#1: length 3.5
  BOTTOM w0.102: T82.1 162.46,134.05 164.3,134.05 UV1.A39
MECH#2: length 3.2
  BOTTOM w0.102: UV1.AW1 193.37,104.98 T83.1
MECH#3: length 4
  BOTTOM w0.102: UV1.AW39 165.26,102.59 T84.1
MEM_SMBCLK: length 22.5
  IN3 w0.127: v1(144.74,108.89) 144.71,108.92 144.17,108.92 144.14,108.89 139.43,108.89 138.06,110.25 137.58,110.25 v1(137.38,110.05) 137.38,108.8 v1(137.64,108.53)
  BOTTOM w0.076: UC1.AP2 129.86,106.35 130.16,106.64 130.4,106.64 130.61,106.44 132.64,106.44
  BOTTOM w0.089: 132.64,106.44 132.93,106.44 133.32,106.06 134.77,106.06 v3(136.42,107.7) 137.25,108.53 v1(137.64,108.53)
  BOTTOM w0.102: v1(137.38,110.05) 137.44,110.05 137.89,110.5 137.89,111.96 137.96,112.04 RP40.1 ; QC1.6 v1(144.74,108.89)
MEM_SMBDATA: length 22.5
  IN3 w0.127: v1(137.44,110.63) 137.6,110.48 138.16,110.48 139.53,109.12 144.04,109.12 144.24,109.31 145.62,109.31 v1(146.04,108.89)
  BOTTOM w0.076: 134.97,108.81 134.55,109.23 134.55,109.71 134.29,109.97 130.4,109.97 UC1.AH1
  BOTTOM w0.089: v1(137.44,110.63) 137.36,110.63 137,110.27 v3(137,109.57) 137,109.31 136.49,108.81 134.97,108.81
  BOTTOM w0.102: v1(137.44,110.63) 137.63,110.83 137.63,112.15 138.02,112.54 RP40.2 ; QC1.3 v1(146.04,108.89)
MIC1-L: length 2.7
  TOP w0.203: CA74.1 27.38,25.92 26.88,25.41 26.88,25.08 26.7,24.9 26.7,24.39 26.88,24.21 UA1.19
MIC_CLK: length 354
  TOP w0.102: CA22.1 RA131.2 33.06,19.52 v1(33.43,19.89)
  IN1 w0.127: v1(33.43,19.89) 34.57,21.03 46.57,21.03 52.36,26.82 87.35,26.82 105.5,44.97 133.25,44.97 136.91,41.31 160.85,41.31 167.41,34.76 180.11,34.76 180.61,35.25 183.25,35.25 v1(184.05,34.45) ; v1(220.93,41.99) 220.48,42.45 220.48,79.81 213.52,86.77 213.52,91.07 216.24,93.8 216.24,97.63 219.12,100.51 219.5,100.51 221.26,102.27 221.26,110.08 219.81,111.53 219.81,116.44 217.5,118.74 217.5,138.76 217.11,139.15 217.11,144.91 217.44,145.24 217.44,161.23 221.34,165.13 221.34,171.89 220.49,172.74 218.92,172.74 v1(218.66,172.48)
  BOTTOM w0.102: v1(220.93,41.99) 220.8,41.87 214.58,41.87 213.85,42.59 202.5,42.59 201.8,41.89 201.27,41.89 200.17,40.8 195.92,40.8 194.39,39.26 194.39,36.91 192.86,35.39 v3(185.97,35.39) 184.99,35.39 v1(184.05,34.45) ; v1(218.66,172.48) 218.95,172.77 JLVDS.30
MIC_CLK_C: length 2.3
  TOP w0.102: UA1.3 30.58,19.25 30.77,19.05 v3(31.22,19.05) 31.95,19.05 RA131.1
MIC_DATA: length 355.9
  TOP w0.102: v1(38.45,19.37) 37.7,18.62 v3(36.75,18.62) 33.59,18.62 33.48,18.51 32.09,18.51 31.92,18.68 30.79,18.68 30.62,18.85 UA1.2
  IN1 w0.127: v1(38.45,19.37) 39.68,20.6 46.5,20.6 52.46,26.57 87.54,26.57 105.69,44.71 133.15,44.71 136.8,41.06 160.75,41.06 167.31,34.5 180.22,34.5 180.67,34.95 182.98,34.95 183.42,34.51 v1(183.42,34.43) ; v1(221.31,42.56) 220.91,42.97 220.91,79.74 213.77,86.88 213.77,90.8 216.58,93.61 216.58,97.61 219.23,100.26 219.61,100.26 221.52,102.17 221.52,110.18 220.06,111.64 220.06,116.54 217.75,118.85 217.75,138.86 217.36,139.25 217.36,144.81 217.69,145.14 217.69,161.12 221.63,165.06 221.63,172.04 219.61,174.06 v1(219.61,174.51)
  BOTTOM w0.102: v1(219.61,174.51) 219.61,174.45 219.95,174.11 JLVDS.32 ; v1(221.31,42.56) 214.21,42.56 213.95,42.82 202.4,42.82 201.7,42.12 201.14,42.12 200.04,41.03 195.79,41.03 194.13,39.37 194.13,37.02 192.93,35.82 184.81,35.82 v1(183.42,34.43)
MIC_IN: length 12.1
  IN1 w1.016: 15.59,23.76 22.93,23.76 23.37,24.2 24.3,24.2 24.61,24.51 26.05,24.51 26.38,24.84
  BOTTOM w0.102: v3(16.33,23.41) 15.84,22.92 v1(15.84,22.74)
  vias: v1(15.26,22.74) v1(27.33,25.09) v1(27.28,24.5)
MIC_IN_R: length 14.9
  TOP w0.102: LA7.1 v3(13.87,20.28)
  IN3 w1.016: 15.46,17.22 15.01,17.22 13.49,18.74 12.67,18.74 12.67,18.74 4.5,18.74 JHP.4
  vias: v1(16.32,17.54) v1(16.32,16.95)
MIIC_SCL: length 6.8
  TOP w0.102: UX4.48 202.12,173.93 202.19,174 202.19,174.13 202.05,174.27 201.06,174.27 200.71,174.61 200.71,174.77 v1(200.52,174.97)
  BOTTOM w0.102: v1(200.52,174.97) 200.75,175.19 200.75,175.4 200.66,175.49 200.28,175.49 200.14,175.35 199.16,175.35 199.06,175.25 199.06,175.13 198.96,175.03 RX171.1 RX169.2
MIIC_SDA: length 7.1
  TOP w0.102: v1(201.12,174.97) 200.94,174.79 200.94,174.7 201.15,174.5 v2(201.57,174.5) 202.15,174.5 202.42,174.22 202.42,174 202.52,173.9 UX4.47
  BOTTOM w0.102: v1(201.12,174.97) 200.98,175.11 200.98,175.49 200.76,175.72 200.18,175.72 200.04,175.58 199.16,175.58 199.06,175.68 199.06,175.79 198.96,175.89 RX170.1 RX168.2
MS_BS: length 16.8
  TOP w0.102: v1(178.21,31.19) 177.92,30.9 176.59,30.9 173.5,27.8 173.5,25.65 173.4,25.55 v3(172.94,25.55) 172.55,25.55 172.43,25.43 172.43,25.26 172.55,25.14 173.4,25.14 173.5,25.04 173.5,24.83 173.4,24.73 172.55,24.73 172.43,24.61 172.43,24.45 172.55,24.33 173.4,24.33 173.5,24.23 173.5,24.22 174.52,23.19 UR1.22
  BOTTOM w0.102: JREAD.15 178.56,30.84 v1(178.21,31.19)
MS_CLK_SD_WP: length 41.4
  TOP w0.102: v1(182.59,21.92) 182.5,21.83 CR5.1 RR3.2
  IN1 w0.127: v1(170.46,28.46) 171.07,29.07 184.19,29.07 v1(186.71,26.55)
  BOTTOM w0.102: v1(170.46,28.46) 170.19,28.73 JREAD.22 ; JREAD.5 187.68,27.44 186.79,26.55 v1(186.71,26.55) 186.71,22.94 186.58,22.81 182.65,22.81 182.53,22.69 182.53,22.52 182.65,22.4 186.58,22.4 186.71,22.28 186.71,22.05 186.58,21.92 v1(182.59,21.92)
MS_CLK_SD_WP_R: length 5.1
  TOP w0.102: UR1.8 179.53,22.69 179.76,22.46 179.76,22.06 RR3.1 181.36,20.46 182.58,20.46 v3(182.92,20.8)
MS_D0: length 23.6
  TOP w0.102: UR1.16 176.82,26.64 176.69,26.77 175.87,26.77 175.75,26.89 175.75,27.06 175.87,27.18 176.69,27.18 176.82,27.31 176.82,28.74 177.13,29.06 v3(178.49,29.06) 179.43,29.06 180.39,28.1 v1(180.39,27.72)
  BOTTOM w0.102: JREAD.12 181.6,23.58 181.47,23.45 181.22,23.45 181.09,23.58 181.09,28.78 180.97,28.9 180.52,28.9 180.39,28.78 v1(180.39,27.72)
MS_D1_SD_D3: length 27
  TOP w0.102: v1(179.52,31.19) 179.52,30.94 179.65,30.81 180.24,30.81 180.37,30.68 180.37,30.33 180.24,30.2 v3(179.91,30.2) 176.54,30.2 173.96,27.61 173.96,24.59 174.35,24.19 UR1.20
  BOTTOM w0.102: JREAD.3 189.96,31.38 189.77,31.57 179.91,31.57 v1(179.52,31.19) 179.52,31.15 180.08,30.59 JREAD.13
MS_D2_SD_CLK: length 24.1
  TOP w0.102: CR6.1 RR2.2 178.23,28.03 v1(178.79,28.59)
  IN1 w0.127: v1(178.79,28.59) 178.9,28.59 180.2,27.28 180.2,25.21 180.32,25.09 180.68,25.09 180.81,25.22 180.81,28.2 180.93,28.33 181.22,28.33 181.35,28.2 181.35,25.22 181.47,25.09 181.73,25.09 181.85,25.22 181.85,28.2 181.98,28.33 182.99,28.33 183.12,28.2 v1(183.12,26.81)
  BOTTOM w0.102: v1(178.79,28.59) 179.32,29.11 JREAD.14 ; v1(183.12,26.81) JREAD.10
MS_D2_SD_CLK_R: length 2
  TOP w0.102: UR1.15 177.32,25.88 178.21,26.77 RR2.1
MS_D3: length 24.6
  TOP w0.102: UR1.12 v3(181.93,24.69) 182.87,24.69 v1(183.96,23.6)
  BOTTOM w0.102: JREAD.7 186.16,28.41 186.05,28.3 185.17,28.3 185.07,28.2 185.07,28 185.17,27.9 186.05,27.9 186.16,27.8 186.16,25.9 186.05,25.8 183.9,25.8 183.8,25.7 183.8,25.5 183.9,25.4 186.05,25.4 186.16,25.29 186.16,25.09 186.05,24.99 183.9,24.99 183.8,24.89 183.8,24.68 183.9,24.58 186.05,24.58 186.16,24.48 186.16,23.73 186.03,23.6 v1(183.96,23.6)
MS_INS#: length 19.8
  TOP w0.102: v1(183.35,23.63) 183.29,23.57 v3(182.7,23.57) 181.8,23.57 CR10.1 181.35,23.19 UR1.9
  BOTTOM w0.102: v1(183.35,23.63) 183.35,26.09 183.48,26.22 185.65,26.22 185.77,26.34 185.77,26.5 185.65,26.62 183.77,26.62 183.67,26.72 183.67,26.93 183.77,27.03 185.65,27.03 185.77,27.15 185.77,27.32 185.65,27.44 183.77,27.44 183.67,27.54 183.67,27.74 183.77,27.84 184.53,27.84 184.64,27.94 JREAD.8
O-USR: length 5.5
  TOP w0.102: v3(85.55,142.11) 85.55,141.1 86.01,140.64 v1(86.01,140.6)
  TOP w0.254: PR506.2 86.01,140.04 v1(86.01,140.6)
  BOTTOM w0.203: PU501.9 87.46,139.81 86.97,139.81 86.19,140.6 v1(86.01,140.6)
  BOTTOM w0.254: v1(86.01,140.6) 85.94,140.66 PR502.1
OCP_CPU: length 3.7
  TOP w0.102: v1(88.61,140.6) 88.95,140.6 v3(89.42,141.07)
  TOP w0.254: v1(88.61,140.6) 88.48,140.47 PR503.2
  BOTTOM w0.203: v1(88.61,140.6) 89.02,140.19 PU501.12
  BOTTOM w0.254: v1(88.61,140.6) PR501.1
ODD_DA#: length 142.5
  TOP w0.089: RP54.1 131.87,114.13 131.73,113.99 131.73,113.55 v1(131.66,113.49) 131.47,113.29 130.49,113.29 129.91,113.87 128.6,113.87 128.42,114.05 128.42,114.58 128.24,114.77 128.24,115.39 v1(129.31,116.47)
  IN1 w0.127: v1(220.55,105.23) 220.34,105.23 218.64,103.53 218.64,101.85 215.3,98.52 214.17,98.52 213.01,97.36 210.53,97.36 210.24,97.65 201.2,97.65 196.51,92.96 192.91,92.96 191.38,94.49 190.04,94.49 189.3,93.74 173.71,93.74 v1(173.45,93.48)
  IN3 w0.084: v1(131.66,113.49) 131.56,113.49 129.42,111.34 128.88,111.34 128.2,110.67 128.2,109.96 127.92,109.68 126.65,109.68 126.36,109.39 126.36,108.61 126.5,108.47 126.5,107.15 126.81,106.84 137.82,106.84
  IN3 w0.127: 137.82,106.84 138.48,106.84 139.1,107.45 143.59,107.45 144.68,106.37 149.07,106.37 154.14,101.29 161.88,101.29 163.01,100.16 163.01,99.38 170.02,92.38 172.34,92.38 v1(173.45,93.48)
  BOTTOM w0.089: UC1.T3 128.98,116.81 v1(129.31,116.47)
  BOTTOM w0.102: v1(220.55,105.23) 221.44,106.12 222.28,106.12 CS17.1 223.84,105.47 228.06,109.68 228.06,114.04 JODD.11
ODD_DETECT#: length 128.8
  IN1 w0.127: v1(220.55,105.87) 220.48,105.87 218.39,103.77 218.39,101.96 215.2,98.77 214.06,98.77 212.9,97.61 210.64,97.61 210.34,97.9 201.09,97.9 196.41,93.22 193.01,93.22 191.49,94.74 189.94,94.74 189.2,94 175.52,94 175.39,94.13 v1(172.04,94.13)
  IN2 w0.089: 137.92,116.61 137.63,116.32 v1(137.57,116.32)
  IN2 w0.127: v1(152.07,105.74) 151.62,106.19 151.62,107.74 152.28,108.4 152.28,109.46 151.92,109.82 151.92,110.64 146.6,115.96 142.4,115.96 141.57,116.79 138.1,116.79 137.92,116.61
  IN3 w0.084: v1(127.26,115.9) 127.62,116.26 128,116.26 128.45,115.81 130.77,115.81 132.22,117.27 133.54,117.27 134.24,116.57 136.26,116.57 136.66,116.17 137.42,116.17 v1(137.57,116.32)
  IN3 w0.127: v1(152.07,105.74) 155.99,101.82 162.1,101.82 163.53,100.39 163.53,99.58 169.52,93.59 170.38,93.59 170.92,94.13 v1(172.04,94.13)
  BOTTOM w0.076: 137.92,115.23 137.57,115.58 v1(137.57,116.32)
  BOTTOM w0.089: UC1.V6 126.99,115.63 v1(127.26,115.9)
  BOTTOM w0.102: RP37.1 137.99,115.16 137.92,115.23 ; v1(220.55,105.87) 221.1,106.42 222.13,106.42 v3(223.03,107.31) 224.24,107.31 226.05,109.13 JODD.8
ODD_EN: length 8.8
  BOTTOM w0.102: QS2.3 222.85,121.91 222.48,122.27 222.24,122.27 CS16.1 222.87,123.72 222.87,124.93 222.67,125.13 RS6.1 ; v3(222.96,127.35) 222.96,126.59 RS6.1 ; QS3.1 221.96,126.3 RS6.1
ODD_EN#: length 137.7
  TOP w0.102: v3(170.73,92.59) 170.98,92.85 v1(171.22,92.85)
  IN1 w0.084: v1(134.33,114.96) 134.76,115.39 137.32,115.39 137.92,116
  IN1 w0.127: v1(152.05,107.58) 152.05,108.77 149.5,111.33 148.94,111.33 147.13,113.13 147.13,113.69 143.02,117.8 139.98,117.8 138.33,116.15 138.08,116.15 137.92,116 ; v1(216.91,122.03) 216.91,118.91 218.72,117.1 218.72,104.71 217.8,103.79 217.8,102.87 212.8,97.86 210.74,97.86 210.35,98.26 201.09,98.26 196.3,93.47 193.12,93.47 191.56,95.03 189.87,95.03 189.2,94.36 177.52,94.36 176.24,95.64 172.96,95.64 171.22,93.91 v1(171.22,92.85)
  IN3 w0.127: v1(171.22,92.85) 169.9,92.85 163.27,99.48 163.27,100.27 161.99,101.55 155.42,101.55 151.65,105.32 151.65,107.18 v1(152.05,107.58)
  BOTTOM w0.089: v1(134.33,114.96) 133.9,115.38 132.4,115.38 131.79,114.77 130.46,114.77 UC1.Y1
  BOTTOM w0.102: v1(216.91,122.03) 217.13,122.25 219.8,122.25 219.98,122.43 220.87,122.43 221.24,122.79 221.24,123.33 QS3.2
ON/OFFBTN#: length 238.7
  TOP w0.102: v1(43.46,93.99) 43.34,94.11 JPWR.3 ; v1(168.75,44.38) v4(168.75,42.68) 168.75,41.75 170.48,40.02 174.13,40.02 179.47,34.68 179.47,32.8 181.61,30.67 191.44,30.67 RE49.1 195.55,28.57 CE20.1 195.88,31.13 SW1.3 v1(199.86,31.13) SW1.4 ; UE1.114 180.08,42.91 179.67,43.32 178.65,43.32 177.36,44.61 v1(177.36,45.38)
  IN3 w0.127: v1(177.36,45.38) 176.6,45.38 176.33,45.11 171.44,45.11 170.71,44.38 v1(168.75,44.38) 168.51,44.61 54.74,44.61 47.72,51.64 47.72,78.56 45.56,80.72 45.56,89.74 43.46,91.83 v1(43.46,93.99)
  BOTTOM w0.102: SW2.3 199.74,39.48 199.74,36.65 199.22,36.13 SW2.4 199.22,31.78 v1(199.86,31.13)
PACIN#: length 3.3
  BOTTOM w0.102: v3(188.14,98.31) 188.19,98.37 RV74.2 189.13,98.44 QV14.5 189.13,99.58 188.94,99.77 188.57,99.77 188.48,99.68 QV14.6
PANEL_BKLEN: length 136.6
  TOP w0.102: UE1.76 191.19,50.55 193.03,48.71 v1(193.39,48.71)
  IN2 w0.127: v1(125.62,129.84) 125.62,129.98 127.93,132.29 136.1,132.29 136.62,131.77 136.62,127.28 143.26,120.64 143.26,118.08 144.37,116.98 148.43,116.98 151.07,114.33 151.07,112.1 152.17,110.99 152.17,109.93 152.53,109.57 152.53,108.39 152.66,108.27 152.66,105.7 157.92,100.44 160.49,100.44 182.32,78.61 182.32,77.78 186.26,73.84 186.26,66.53 185.5,65.76 185.5,54.36 186.24,53.62 v1(186.24,48.47)
  IN3 w0.127: v1(193.39,48.71) 193.39,48.72 193.32,48.65 189.52,48.65 189.33,48.84 186.6,48.84 v1(186.24,48.47)
  BOTTOM w0.076: UC1.A9 124.83,126.02 125.82,127.02 125.82,129.38 125.62,129.59 v1(125.62,129.84)
PBTN_OUT#: length 255.9
  TOP w0.102: UE1.106 180.73,46.11 180.37,46.47 178.26,46.47 172.34,52.38 v3(172.34,53.22) 172.34,55.75 v1(172.14,55.95)
  IN1 w0.084: v1(126.82,109.24) 127.22,109.64 127.62,109.64 127.7,109.56 129.63,109.56 129.82,109.37 132.85,109.37 133.83,108.39 135.19,108.39 135.59,107.99 137.75,107.99
  IN1 w0.127: 137.75,107.99 138.62,108.86 144.17,108.86 144.58,108.44 146.77,108.44 148.15,107.07 148.15,106.55 152.94,101.76 152.94,101.61 160.46,94.08 160.46,91.62 167.02,85.06 171.67,85.06 172.32,84.41 174.36,84.41 178.04,80.73 180.16,80.73 v1(182.89,78)
  IN3 w0.127: v1(65.73,88.7) 66,88.43 66,78.49 70.77,73.72 70.77,72.47 73.14,70.1 73.14,57.34 73.6,56.88 118.11,56.88 119.48,55.52 171.7,55.52 v1(172.14,55.95) 172.95,56.77 174.35,56.77 176.47,58.89 179.14,58.89 185.07,64.82 185.07,65.99 184,67.06 184,69.87 182.89,70.98 v1(182.89,78)
  BOTTOM w0.089: UC1.AL7 126.54,108.96 v1(126.82,109.24)
  BOTTOM w0.102: v1(65.73,88.7) 64.66,88.7 63.67,89.69 RC49.1
PC_BEEP: length 5.6
  TOP w0.102: RA79.2 35.73,24.52 RA19.1 36.83,23.42 v3(37.78,23.42) 37.99,23.42 38.13,23.57 DA8.1
PCH_AUDIO_EN: length 4.7
  BOTTOM w0.076: UC1.P1 131.4,117.59 131.54,117.73 132.92,117.73 RC116.1
  BOTTOM w0.089: v3(134.04,117.34) 133.49,117.88 RC116.1
PCH_AZ_BITCLK: length 7
  BOTTOM w0.076: 125.2,102.25 125.11,102.34 125.11,103.29 UC1.AW8
  BOTTOM w0.089: R2359.2 128.16,98.13 v3(127.43,98.86) 126.24,100.05 126.24,101.2 125.2,102.25
PCH_AZ_CODEC_BITCLK: length 233.8
  TOP w0.102: UA1.6 31.45,20.45 31.52,20.52 R2355.1 v1(32.78,19.89)
  IN1 w0.127: v1(131.45,93.19) 144.11,80.53 144.11,70.37 142.78,69.04 142.78,56.61 142.65,56.49 140.31,56.49 140.19,56.36 140.19,53.63 140.06,53.5 139.6,53.5 139.47,53.63 139.47,56.36 139.35,56.49 138.95,56.49 138.83,56.36 138.83,53.12 138.7,53 138.28,53 138.15,53.12 138.15,56.36 138.03,56.49 137.63,56.49 137.51,56.36 v1(137.51,51.19) ; v1(137.47,45.29) 137.28,45.48 105.25,45.48 104.65,44.88 104.47,44.88 104.19,45.16 104.01,45.16 103.83,44.98 103.83,44.8 104.11,44.52 104.11,44.34 103.93,44.16 103.75,44.16 103.47,44.44 103.29,44.44 103.11,44.26 103.11,44.08 103.39,43.8 103.39,43.62 103.21,43.44 103.03,43.44 102.75,43.72 102.57,43.72 102.39,43.54 102.39,43.36 102.67,43.08 102.67,42.9 102.49,42.72 102.31,42.72 102.03,43 101.85,43 101.67,42.82 101.67,42.65 101.95,42.36 101.95,42.18 101.77,42 101.59,42 101.31,42.29 101.13,42.29 100.95,42.11 100.95,41.93 101.23,41.64 101.23,41.46 101.05,41.28 100.88,41.28 100.59,41.57 100.41,41.57 100.23,41.39 100.23,41.21 100.52,40.92 100.52,40.74 100.34,40.56 100.16,40.56 99.87,40.85 99.69,40.85 99.51,40.67 99.51,40.49 99.8,40.2 99.8,40.03 99.62,39.85 99.44,39.85 99.15,40.13 98.97,40.13 98.79,39.95 98.79,39.77 99.08,39.49 99.08,39.31 98.87,39.1 98.69,39.1 98.4,39.38 98.22,39.38 98.04,39.2 98.04,39.02 98.33,38.74 98.33,38.56 98.15,38.38 97.97,38.38 97.69,38.66 97.51,38.66 97.33,38.48 97.33,38.3 97.61,38.02 97.61,37.84 97.43,37.66 97.25,37.66 96.97,37.94 96.79,37.94 96.61,37.76 96.61,37.58 96.89,37.3 96.89,37.12 96.71,36.94 96.53,36.94 96.25,37.22 96.07,37.22 95.89,37.04 95.89,36.86 96.17,36.58 96.17,36.4 95.99,36.22 95.81,36.22 95.53,36.5 95.35,36.5 95.17,36.32 95.17,36.15 95.45,35.86 95.45,35.68 95.27,35.5 95.09,35.5 94.81,35.79 94.63,35.79 94.45,35.61 94.45,35.43 94.73,35.14 94.73,34.96 94.55,34.78 94.38,34.78 94.09,35.07 93.91,35.07 93.73,34.89 93.73,34.71 94.02,34.42 94.02,34.24 93.84,34.06 93.66,34.06 93.37,34.35 93.19,34.35 93.01,34.17 93.01,33.99 93.3,33.7 93.3,33.53 93.12,33.35 92.94,33.35 92.65,33.63 92.47,33.63 92.29,33.45 92.29,33.27 92.58,32.99 92.58,32.81 92.4,32.63 92.22,32.63 91.93,32.91 91.76,32.91 91.58,32.73 91.58,32.55 91.86,32.27 91.86,32.09 91.68,31.91 91.5,31.91 91.22,32.19 91.04,32.19 90.86,32.01 90.86,31.83 91.14,31.55 91.14,31.37 90.96,31.19 90.78,31.19 90.5,31.47 90.32,31.47 90.14,31.29 90.14,31.11 90.42,30.83 90.42,30.65 90.24,30.47 90.06,30.47 89.78,30.75 89.6,30.75 89.42,30.57 89.42,30.39 89.7,30.11 89.7,29.93 87.1,27.33 52.15,27.33 46.42,21.6 45.7,21.6 45.57,21.73 45.57,22.49 45.44,22.62 45.19,22.62 45.06,22.49 45.06,21.73 44.93,21.6 44.68,21.6 44.55,21.73 44.55,22.49 44.43,22.62 44.17,22.62 44.05,22.49 44.05,21.73 43.92,21.6 43.66,21.6 43.54,21.73 43.54,22.49 43.41,22.62 43.16,22.62 43.03,22.49 43.03,21.73 42.9,21.6 42.65,21.6 42.52,21.73 42.52,22.49 42.39,22.62 42.14,22.62 42.01,22.49 42.01,21.73 41.89,21.6 41.63,21.6 41.51,21.73 41.51,22.49 41.38,22.62 41.12,22.62 41,22.49 41,21.73 40.87,21.6 40.62,21.6 40.49,21.73 40.49,22.49 40.36,22.62 40.11,22.62 39.98,22.49 39.98,21.73 39.85,21.6 39.6,21.6 39.47,21.73 39.47,22.49 39.35,22.62 39.09,22.62 38.97,22.49 38.97,21.73 38.84,21.6 38.58,21.6 38.46,21.73 38.46,22.49 38.33,22.62 38.08,22.62 37.95,22.49 37.95,21.73 37.82,21.6 37.57,21.6 37.44,21.73 37.44,22.49 37.31,22.62 37.06,22.62 36.93,22.49 36.93,21.73 36.81,21.6 34.38,21.6 32.78,20 v1(32.78,19.89)
  BOTTOM w0.089: 130.06,94.58 130.02,94.62 v3(129.63,94.62) 127.85,94.62 CC5.1 128.16,96.21 R2359.1
  BOTTOM w0.102: 130.06,94.58 131.45,93.19 v1(131.45,93.19) ; v1(137.47,45.29) 137.47,51.16 v1(137.51,51.19)
PCH_AZ_CODEC_RST#: length 252.5
  TOP w0.102: v1(30.93,22.45) UA1.11
  IN1 w0.084: v1(129.05,96.42) 129.05,96.31 130.42,94.94
  IN1 w0.127: v1(15.03,25.49) 15.68,24.84 19.47,24.84 21.69,27.06 22.19,27.06 24.29,29.16 30.7,29.16 31.72,28.14 31.72,25.22 30.25,23.76 30.25,22.68 30.48,22.45 v1(30.93,22.45) 30.93,22.55 33.98,25.6 46.83,25.6 51.1,29.87 84.94,29.87 103.72,48.65 111.85,48.65 114.65,51.45 116.55,51.45 117.31,50.68 137.93,50.68 138.05,50.81 138.05,52.35 138.18,52.47 138.55,52.47 138.67,52.35 138.67,50.81 138.8,50.68 139.16,50.68 139.28,50.81 139.28,52.77 139.41,52.89 139.73,52.89 139.86,52.77 139.86,50.81 139.98,50.68 140.59,50.68 140.72,50.81 140.72,55.85 140.85,55.98 141.29,55.98 141.42,55.85 141.42,50.81 141.54,50.68 142.05,50.68 142.18,50.81 142.18,55.83 142.31,55.95 142.85,55.95 142.98,55.83 142.98,53.91 143.11,53.78 143.86,53.78 143.98,53.91 143.98,56.25 144.07,56.33 145.15,56.33 145.28,56.46 145.28,56.71 145.15,56.84 143.54,56.84 143.41,56.97 143.41,57.22 143.54,57.35 145.08,57.35 145.2,57.48 145.2,57.73 145.08,57.86 143.54,57.86 143.41,57.98 143.41,58.24 143.54,58.37 145.15,58.37 145.28,58.49 145.28,58.75 145.15,58.87 143.54,58.87 143.41,59 143.41,59.25 143.54,59.38 145.09,59.38 145.22,59.51 145.22,59.76 145.09,59.89 143.54,59.89 143.41,60.02 143.41,60.27 143.54,60.4 145.15,60.4 145.28,60.52 145.28,60.78 145.15,60.91 143.54,60.91 143.41,61.03 143.41,61.29 143.54,61.41 145.02,61.41 145.15,61.54 145.15,61.79 145.02,61.92 143.54,61.92 143.41,62.05 143.41,62.3 143.54,62.43 145,62.43 145.13,62.56 145.13,62.81 145,62.94 143.54,62.94 143.41,63.06 143.41,63.32 143.54,63.45 144.76,63.45 144.88,63.57 144.88,63.83 144.76,63.95 144.11,63.95 143.98,64.08 143.98,69.42 144.62,70.05 144.62,80.74 130.42,94.94
  BOTTOM w0.089: R2358.1 v1(129.05,96.42)
  BOTTOM w0.102: RA6.1 v1(15.03,25.49)
PCH_AZ_CODEC_SDIN0: length 233.3
  TOP w0.102: RA130.1 33.44,21.85 33.62,21.85 v1(34.32,22.55)
  IN1 w0.084: v1(125.62,98.92) 127.21,97.33 130.1,97.33 130.65,96.78 131.57,96.78
  IN1 w0.127: v1(34.32,22.55) 35.65,23.89 47.27,23.89 51.73,28.34 85.7,28.34 104.42,47.06 168.75,47.06 171.12,49.44 171.12,61.22 171.69,61.8 171.69,62.18 171.29,62.58 171.29,70.12 169.33,72.08 160.43,72.08 156.4,76.11 152.12,76.11 133.63,94.6 133.63,95.19 133.25,95.58 133.01,95.58 131.81,96.78 131.57,96.78
  BOTTOM w0.089: UC1.AY10 124.65,102.29 125.89,101.06 125.89,99.55 125.62,99.28 v1(125.62,98.92)
PCH_AZ_CODEC_SDOUT: length 230.5
  TOP w0.102: UA1.5 31.08,20.05 31.24,19.89 v1(32.1,19.89)
  IN1 w0.084: 130.97,96.28 130.71,96.28 130.03,96.96 127.33,96.96 v1(126.77,96.4)
  IN1 w0.127: 130.97,96.28 131.6,96.28 132.29,95.59 132.29,95.22 152.15,75.36 155.36,75.36 159.17,71.55 169.14,71.55 170.78,69.91 170.78,63.87 170.4,63.48 170.4,50.45 167.52,47.57 104.17,47.57 85.45,28.85 51.52,28.85 47.19,24.52 34.51,24.52 32.1,22.11 v1(32.1,19.89)
  BOTTOM w0.089: v1(126.77,96.4) 127.24,96.87 R2356.1
PCH_AZ_CODEC_SYNC: length 223.2
  TOP w0.102: v1(31.52,22.43) 31.08,21.98 30.7,21.98 30.64,22.05 UA1.10
  IN1 w0.084: v1(129.87,96.49) 130.43,95.93 131.22,95.93 131.32,95.84
  IN1 w0.127: 131.32,95.84 131.78,95.38 131.78,95.01 152.11,74.69 154,74.69 157.75,70.94 167.99,70.94 169.57,69.36 169.57,63.35 169.89,63.04 169.89,50.66 167.37,48.14 103.98,48.14 85.2,29.36 51.31,29.36 47.04,25.09 34.19,25.09 v1(31.52,22.43)
  BOTTOM w0.089: v1(129.87,96.49) 130.87,97.48 R2357.1
PCH_AZ_RST#: length 8.6
  BOTTOM w0.076: 125.68,102.54 125.7,102.55 125.7,104.07 125.73,104.11 125.73,104.59 UC1.AU8
  BOTTOM w0.089: R2358.2 128.62,98.38 128.43,98.38 126.75,100.07 v3(126.75,100.49) 126.42,100.81 126.42,101.28 125.68,102.02 125.68,102.54
PCH_AZ_SDOUT: length 10.2
  BOTTOM w0.076: UC1.AU11 123.94,104.7 124.3,104.34 124.3,103.52 124.55,103.26 124.82,103.26 124.95,103.13 124.95,102.25
  BOTTOM w0.089: 124.95,102.25 126.07,101.13 126.07,99.38 v3(126.2,99.24) 127.24,98.2 R2356.2 RC8.2 RC3.2
PCH_AZ_SYNC: length 11.5
  TOP w0.089: v1(128.17,99.27) 128.43,99.53 128.43,101.36 127.76,102.02 125.73,102.02 v3(124.29,103.46) 123.82,103.93 v1(123.53,103.93)
  BOTTOM w0.076: v1(123.53,103.93) 123.83,104.23 UC1.AV11
  BOTTOM w0.089: v1(128.17,99.27) 128.81,98.64 129.19,98.64 129.48,98.35 129.48,97.94 129.94,97.48 R2357.2
PCH_BATLOW#: length 20.5
  TOP w0.089: v1(128.66,107.48) 129.09,107.9 129.57,107.9 130.28,107.19 135.52,107.19 137.57,109.24 137.92,109.24
  TOP w0.102: 137.92,109.24 144.12,109.24 144.3,109.42 v3(145.54,109.42) 146.32,109.42 RC31.2
  BOTTOM w0.089: UC1.AN4 128.33,107.14 v1(128.66,107.48)
PCH_DPWROK: length 9.5
  TOP w0.089: v1(129.73,101.2) v3(129.09,100.56) 128.74,100.21 128.74,99.08 RE37.1 RC33.1
  BOTTOM w0.076: UC1.AV5 127.36,103.98 127.36,102.8 127.64,102.52 127.64,102.14 128.2,101.58 129.35,101.58 v1(129.73,101.2)
PCH_GPIO9: length 23.9
  TOP w0.089: 137.92,108.94 137.53,108.94 135.59,107.01 129.74,107.01 v1(129.28,107.48)
  TOP w0.102: 137.92,108.94 143.89,108.94 144.68,108.15 144.99,108.15 146.04,107.11 146.37,107.11 146.91,107.64 v3(149,107.64) v1(149.92,107.64)
  BOTTOM w0.076: v1(129.28,107.48) 128.98,107.78 UC1.AM3
  BOTTOM w0.102: RC125.2 149.46,108.1 v1(149.92,107.64)
PCH_GPIO12: length 2.1
  TOP w0.089: v1(126.97,108.41) 126.84,108.41 126.18,109.07 T182.1
  BOTTOM w0.089: UC1.AM7 126.7,108.13 v1(126.97,108.41)
PCH_GPIO14: length 2.6
  TOP w0.089: T126.1 129.16,109.92 128.08,109.92 v1(127.83,110.17)
  BOTTOM w0.076: v1(127.83,110.17) 127.95,110.06 UC1.AH4
PCH_GPIO25: length 1.1
  TOP w0.089: T127.1 128.36,107.77 v1(128.04,107.45)
  BOTTOM w0.089: v1(128.04,107.45) 128.33,107.74 UC1.AM4
PCH_GPIO35: length 9.7
  IN3 w0.127: v1(132.23,116.75) 132.23,116.66 133.44,115.45 138.08,115.45 v1(138.29,115.66)
  BOTTOM w0.076: UC1.U1 131.66,116.09 132.23,116.67 v1(132.23,116.75)
  BOTTOM w0.102: RP37.2 v1(138.29,115.66)
PCH_GPIO37: length 13
  BOTTOM w0.076: 137.32,115.07 137.32,113.68 136.81,113.17 135.45,113.17 135.25,113.37 133.26,113.37 132.77,113.85 131.51,113.85 130.75,113.1 UC1.AC1
  BOTTOM w0.089: 137.32,115.07 137.32,115.26 137,115.58 v3(137,115.83) 137,116.33 137.39,116.72 137.92,116.72
  BOTTOM w0.102: RP37.3 138.68,116.16 138.12,116.72 137.92,116.72
PCH_GPIO44: length 15.8
  TOP w0.089: v1(134.13,109.23) 134.59,109.23 134.97,108.85 v3(135.37,108.85) 136.3,108.85 137,109.55 137.8,109.55 137.92,109.68
  TOP w0.102: v1(142.4,109.69) 142.35,109.74 137.99,109.74 137.92,109.68
  BOTTOM w0.076: UC1.AK4 128.62,109.68 129.1,109.68 129.14,109.64 129.92,109.64 130.09,109.81 133.55,109.81 v1(134.13,109.23)
  BOTTOM w0.102: v1(142.4,109.69) 142.15,109.94 RC104.1
PCH_GPIO46: length 27.3
  IN3 w0.084: 137.82,111.27 135.47,111.27 134.17,112.57 131.42,112.57 v1(129.32,110.47)
  IN3 w0.127: 137.82,111.27 138.95,111.27 139.84,110.38 143.15,110.38 143.83,109.7 149.39,109.7 149.4,109.7 149.75,109.7 149.75,109.7 150.06,109.7 v1(150.78,108.98)
  BOTTOM w0.076: v1(129.32,110.47) 128.98,110.82 UC1.AG3
  BOTTOM w0.102: RC124.2 150.35,107.21 150.62,107.49 v3(150.62,108.12) 150.62,108.82 v1(150.78,108.98)
PCH_GPIO47: length 1.2
  TOP w0.089: v1(126.62,113.07) 126.62,113.31 T174.1
  BOTTOM w0.089: UC1.AB6 126.99,113.45 v1(126.62,113.07)
PCH_GPIO48: length 3.2
  TOP w0.089: T124.1 128.54,117.52 128.17,117.9 v1(127.95,117.9)
  BOTTOM w0.076: v1(127.95,117.9) 128.02,117.82 128.02,116.39 128.33,116.08 UC1.U4
PCH_GPIO49: length 4.6
  BOTTOM w0.076: UC1.Y3 129.23,114.3 133.3,114.3 133.33,114.33
  BOTTOM w0.089: T125.1 133.33,114.33
PCH_GPIO66: length 9.1
  BOTTOM w0.076: UC1.D3 129.31,123.19 129.75,123.19 129.93,123.38 129.93,123.83 130.14,124.03 131.6,124.03
  BOTTOM w0.089: v3(135.22,126.89) 135.33,126.77 RC118.2 135.04,125.58 RC122.1 134.41,125.31 133.63,124.53 132.1,124.53 131.6,124.03
PCH_GPIO83: length 2.1
  TOP w0.089: v1(126.51,116.82) 127.02,117.33 127.57,117.33 T177.1
  BOTTOM w0.089: v1(126.51,116.82) 126.99,117.31 UC1.R6
PCH_GPIO84: length 1.6
  TOP w0.089: T176.1 126.28,119.25 126.65,118.88 v1(126.65,118.76)
  BOTTOM w0.089: v1(126.65,118.76) 126.99,119.1 UC1.L6
PCH_GPIO85: length 1.5
  TOP w0.089: v1(127.35,117.74) 126.94,118.15 T175.1
  BOTTOM w0.089: UC1.N6 126.99,118.1 v1(127.35,117.74)
PCH_GPIO89: length 2.1
  TOP w0.089: T178.1 125.36,118.25 126.14,118.25 v1(126.58,117.8)
  BOTTOM w0.089: UC1.N7 126.34,118.05 v1(126.58,117.8)
PCH_GPIO90: length 3
  BOTTOM w0.089: UC1.K2 130.01,119.45 130.94,119.45 131.82,120.33 T179.1
PCH_GPIO93: length 3.3
  BOTTOM w0.076: UC1.J2 129.92,120.88 130.47,120.88 130.73,121.15 130.73,121.32 130.83,121.41 131.16,121.41
  BOTTOM w0.089: T180.1 131.33,121.58 131.16,121.41
PCH_GPIO94: length 4.4
  BOTTOM w0.089: T181.1 134.39,122.06 131.19,122.06 130.88,121.75 130.69,121.75 UC1.G1
PCH_HOT#: length 108.2
  TOP w0.089: 135.96,101.45 135.95,101.45 135.95,101.89 135.76,102.09 v1(135.76,102.15)
  TOP w0.102: v1(191.41,54.92) 191.69,54.63 RE7.1 ; 135.96,101.45 135.96,101.4 138.62,98.74 139.05,98.74 139.27,98.52 139.69,98.1 139.71,98.08 v3(144.25,98.08) 152.72,98.08 157.25,93.55 163.74,93.55 168.1,89.19 168.1,85.26 174.84,78.51 174.84,71.82 175.29,71.37 175.29,57.36 176.4,56.25 176.4,52.24 v1(177.51,51.13)
  IN3 w0.127: v1(177.51,51.13) 177.59,51.05 190.65,51.05 191.41,51.81 v1(191.41,54.92)
  BOTTOM w0.076: 131.57,102.53 129.54,102.53 129.34,102.73 129.34,103.07 129.29,103.12 129.29,103.73 129.06,103.96 128.84,103.96 128.66,104.13 128.66,104.35 128.3,104.72 UC1.AU4
  BOTTOM w0.089: v1(135.76,102.15) 135.73,102.18 135.73,102.31 135.55,102.49 135.54,102.49 R2330.2 135.02,102.47
  BOTTOM w0.102: 131.57,102.53 132.12,101.98 134.52,101.98 135.02,102.47
PCH_INTVRMEN: length 12.6
  BOTTOM w0.076: 125.86,102.34 125.86,103.98 UC1.AV7
  BOTTOM w0.089: 125.86,102.34 125.86,102.09 126.6,101.35 126.6,101.13 127.96,99.77 128.33,99.77 129.46,98.64 v3(130.51,98.64) 131.35,97.8 131.35,97.08 131.57,96.85
  BOTTOM w0.102: 131.57,96.85 132.03,96.39 RC1.2 133.04,96.39 RC2.1
PCH_JTAG_JTAGX: length 9.7
  BOTTOM w0.076: UC1.AE63 90.27,111.64
  BOTTOM w0.102: 90.27,111.64 89.25,110.61 86.13,110.61 86.07,110.68 RC130.1 84.64,110.68 RC59.2 RC62.2 84.62,112.27 v3(84.19,112.7)
PCH_JTAG_RST#: length 68.2
  TOP w0.102: RC57.2 R2341.2 73.55,113.23 72.95,113.23 72.71,112.99 72.71,110.79 73.77,109.73 75.17,109.73 75.89,109 75.89,105.71 75.49,105.31 75.49,101.06 73.37,98.94 73.37,93.1 v4(69.85,89.58) v1(67.34,89.58)
  BOTTOM w0.076: UC1.AU62 92.11,104.9 91.79,105.22 91.16,105.22 90.64,104.7
  BOTTOM w0.089: 87.92,101.98 87.12,101.18
  BOTTOM w0.102: 90.64,104.7 87.92,101.98 ; 87.12,101.18 84.15,98.21 77.9,98.21 74.95,95.26 74.95,90.03 74.49,89.58 v1(67.34,89.58)
PCH_JTAG_TCK: length 58.6
  TOP w0.102: v1(66.62,88.89) v4(66.62,88.27)
  IN3 w0.127: v1(76.74,107.64) 75.15,106.06 75.15,101.99 71.53,98.37 71.53,89.99 70.25,88.71 66.79,88.71 v1(66.62,88.89)
  BOTTOM w0.076: UC1.AE62 92.08,111.42 91.87,111.42 91.74,111.35 91.71,111.34 91.46,111.34 91.35,111.45 90.39,111.45
  BOTTOM w0.102: RP46.4 59.1,86.36 60.54,84.91 64.74,84.91 66.78,86.95 66.78,88.73 v1(66.62,88.89) ; v1(76.74,107.64) 77.24,108.15 78.42,108.15 79.18,108.91 82.32,108.91 83.02,108.21 83.93,108.21 RC135.1 RC65.2 84.81,109.99 87.71,109.99 88.15,110.42 89.36,110.42 90.39,111.45
PCH_JTAG_TDI: length 26.9
  TOP w0.089: 88.45,111.3 88.64,111.3 v1(88.67,111.26) 89.06,110.88 90.14,110.88 90.83,111.58 92.87,111.58 93.3,112.01 v1(93.3,112.03)
  TOP w0.102: v1(80.31,110.56) 82.53,112.79 86.96,112.79 v4(87.36,112.38) 88.45,111.3
  BOTTOM w0.089: RP48.8 88.4,110.99 v1(88.67,111.26) ; UC1.AD61 92.95,112.38 v1(93.3,112.03)
  BOTTOM w0.102: RC44.1 75.21,104.21 75.49,104.49 75.49,105.52 75.75,105.77 75.75,108.23 76.15,108.63 78.22,108.63 79.52,109.94 79.68,109.94 v1(80.31,110.56)
PCH_JTAG_TDO: length 25.9
  TOP w0.089: 88.91,111.96 89.31,111.57 v1(89.31,111.26)
  TOP w0.102: v1(89.31,111.26) 90.07,111.26 90.82,112.01 v1(92.65,112.01) ; 88.91,111.96 RC63.2 87.77,113.1 82.24,113.1 v4(81.23,112.09) v1(79.72,110.59)
  BOTTOM w0.089: UC1.AE61 92.95,111.71 v1(92.65,112.01) ; 88.91,111.66 v1(89.31,111.26)
  BOTTOM w0.102: RP48.7 88.27,111.49 88.48,111.71 88.87,111.71 88.91,111.66 ; RC43.1 74.98,106.95 74.98,109.43 75.45,109.9 75.45,110.18 75.86,110.59 v1(79.72,110.59)
PCH_JTAG_TMS: length 36.8
  TOP w0.102: v1(76.32,113.04) v4(76.99,113.04)
  BOTTOM w0.089: UC1.AD62 91.9,111.99 88.91,111.99
  BOTTOM w0.102: RC46.1 65.94,105.42 65.15,106.21 65.15,110.19 65.59,110.63 69.94,110.63 72.36,113.04 v1(76.32,113.04) 85.88,113.04 86.13,112.79 88.48,112.79 88.74,112.54 88.74,111.99 ; 88.91,111.99 88.74,111.99 ; 88.74,111.99 RP48.6
PCH_OPI_COMP: length 7.7
  BOTTOM w0.076: 122.71,100.9 121.95,101.66 121.95,103.29 UC1.AW15
  BOTTOM w0.305: RC101.1 124.28,97.24 122.77,98.76 122.77,99.34 v3(122.93,99.51) 122.93,100.25 122.77,100.41 122.77,100.85 122.71,100.9
PCH_PCIE_RCOMP: length 5.2
  BOTTOM w0.089: v3(114.59,130.45) 114.66,130.38 RC91.2
  BOTTOM w0.305: UC1.A27 114.59,125.72 114.59,126.88 114.9,127.18 114.9,128.7 114.66,128.94 RC91.2
PCH_PLTRST#: length 29.4
  TOP w0.089: v1(126.71,110.18) 126.71,109.66 126.45,109.4 126.45,109.08 126.67,108.87 127.23,108.87 127.47,108.63 127.47,107.5 127.89,107.08 129.42,107.08 129.75,106.75 v4(136.28,106.75) 136.74,106.75 137.92,107.93
  TOP w0.102: 148.25,106.44 148.25,107.13 148.02,107.36 146.95,107.36 146.47,106.88 145.94,106.88 144.9,107.92 144.59,107.92 143.79,108.72 138.71,108.72 137.92,107.93 ; 148.25,106.44 UC3.1 ; 148.25,106.44 147.74,106.44 147.6,106.3 UC3.2
  BOTTOM w0.076: UC1.AG7 126.71,110.28 v1(126.71,110.18)
PCH_PWR_EN: length 70.5
  TOP w0.102: v1(162.46,36.71) 163.35,37.6 163.35,52.91 163.99,53.54 v3(167.12,53.54) 170.86,53.54 175.8,48.6 175.8,47.19 176.77,46.21 178.22,46.21 RE36.1
  IN1 w0.127: v1(162.46,36.71) 147.41,36.71 v1(142.33,31.63)
  BOTTOM w0.102: v1(142.33,31.63) 142.33,26.05 143.04,25.33 R416.1
PCH_PWROK: length 136.6
  TOP w0.089: RP50.2 132.68,111.84 132.81,111.96 v1(132.81,112.02) 132.81,112.21 132.68,112.34 RP50.3
  TOP w0.102: CE31.1 197.11,33.81 ; 197.11,33.81 RE18.1 195.93,34.32 v1(195.8,34.45) 195.59,34.66 UE1.32 ; 197.11,33.81 v4(198.1,33.81)
  IN1 w0.084: v1(132.81,112.02) 130.58,112.02 130.33,111.77 130.33,110.78 130.81,110.29 134.44,110.29 134.66,110.52 136.06,110.52 137.06,111.52 137.72,111.52
  IN1 w0.127: 137.72,111.52 141.8,111.52 143.48,113.19 144.26,113.19 144.37,113.3 144.8,113.3 145.9,112.2 145.9,111.92 146.4,111.43 146.94,111.43 148.87,109.5 150.88,109.5 151.63,108.75 151.63,105.59 151.95,105.27 152.76,105.27 153.95,104.07 153.95,102.25 165.01,91.19 165.01,88.5 167.43,86.09 174.12,86.09 178.46,81.75 182.49,81.75 188.79,75.45 188.79,65.41 189.83,64.37 189.83,57.33 190.73,56.43 190.73,54.64 191.47,53.9 191.47,50.64 191.91,50.2 191.91,47.76 191.58,47.43 191.58,44.26 191.75,44.09 v1(191.75,44.07)
  IN3 w0.127: v1(191.75,44.07) 191.75,43.65 192.65,42.75 195.48,42.75 196.85,41.38 196.85,36.37 195.8,35.32 v1(195.8,34.45)
PCH_PWROK_R: length 17.6
  TOP w0.089: v1(127,101.35) 127,101.39 v3(126.68,101.71) ; v1(127.85,111.14) 129.17,111.14 129.87,111.84 RP50.7
  IN3 w0.084: v1(127,101.35) 126.15,102.2 126.15,108.33 126.01,108.47 126.01,109.72 126.15,109.87 126.15,110.65 126.27,110.76 127.48,110.76 v1(127.85,111.14)
  BOTTOM w0.089: v1(127,101.35) 127,101.35 126.89,101.35 126.15,102.08 UC1.AY7
PCH_RSMRST#_R: length 8.6
  TOP w0.089: v1(127.74,101.17) v3(126.62,100.04) 126.06,99.49 RC33.2 126.06,98.08 RC41.2
  BOTTOM w0.076: UC1.AW6 126.84,103.52 126.61,103.29 126.61,102.1 126.78,101.93 126.87,101.93 126.88,101.93 127.35,101.93 127.74,101.53 v1(127.74,101.17)
PCH_RTCRST#: length 157.5
  TOP w0.089: 131.57,96.25 131.23,96.6 131.23,97.6 130.84,97.99 130.84,100.94 127.2,104.58 v1(126.53,104.58)
  TOP w0.102: v1(174.08,58) 174.58,58.49 174.58,70.81 174.02,71.37 v4(174.02,74.74) 174.02,78.19 166.78,85.43 166.78,89.36 164.53,91.6 163.34,91.6 162.7,90.97 155.08,90.97 152.26,93.79 133.71,93.79 133.05,94.45 CC4.2 132.31,95.51 RC6.2 131.57,96.25
  BOTTOM w0.076: v1(126.53,104.58) 126.23,104.88 UC1.AU7
  BOTTOM w0.102: v1(174.08,58) 174.08,57.99 166.24,57.99 161.41,53.15 131.5,53.15 126.92,48.57 114.71,48.57 113.66,47.52 CMOS1.2
PCH_RTCX1: length 26.4
  BOTTOM w0.076: 128.02,102.36 128.02,103.21 UC1.AW5
  BOTTOM w0.102: 128.02,102.36 128.4,101.98 129.79,101.98 130.61,101.16 136.51,101.16 139.43,98.25 v3(143.55,98.25) RC4.1 146.03,98.25 CC1.2 146.97,99.13 147.65,99.82 147.65,100.37 147.3,100.72 YC1.1 146.86,102.3 RG3.2
PCH_RTCX1_R: length 192.5
  TOP w0.102: v1(75.85,46.47) 75.85,43.89 75.59,43.64 v3(75.34,43.64) 73.18,43.64 73.03,43.49 UG1.9
  IN1 w0.127: v1(76.11,54.98) 75.26,54.13 75.26,47.05 v1(75.85,46.47)
  IN3 w0.127: v1(76.11,54.98) 81.4,54.98 82.67,56.25 117.57,56.25 118.96,54.85 172.63,54.85 173.84,56.07 174.55,56.07 176.73,58.25 179.57,58.25 186.64,65.33 186.64,69.21 184.42,71.44 184.42,77.08 160.9,100.59 151.91,100.59 150.35,102.16 148.86,102.16 v1(147.79,103.22)
  BOTTOM w0.102: RG3.1 v1(147.79,103.22)
PCH_RTCX2: length 25.4
  BOTTOM w0.102: YC1.2 149.36,100.71 148.77,100.12 CC2.2 147.78,99.11 RC4.2 146.42,97.75 v3(141.4,97.75) 139.09,97.75 136.17,100.67 130.82,100.67 129.71,101.79 128.32,101.79 127.83,102.28 127.83,102.79 UC1.AY5
PCH_SMB_ALERT#: length 21
  IN3 w0.084: 137.92,107.52 135.54,107.52 135.47,107.45 134.39,107.45 v1(134.01,107.83)
  IN3 w0.127: 137.92,107.52 138.4,107.52 138.84,107.96 144.29,107.96 145.17,107.08 v1(145.17,107.08)
  BOTTOM w0.076: v1(134.01,107.83) 133.51,107.33 130.97,107.33 130.85,107.45 130.58,107.45 130.47,107.56 130.08,107.56 UC1.AN2
  BOTTOM w0.102: v1(145.17,107.08) 145.17,107.08 v3(143.46,108.79) 143.19,109.06 R2329.2
PCH_SPI_CLK: length 14
  IN1 w0.084: v1(129.28,113.47) 130.04,113.47 131,114.43 137.73,114.43 137.92,114.62
  IN1 w0.127: v1(140.94,116.06) 139.36,116.06 137.92,114.62
  BOTTOM w0.076: v1(129.28,113.47) 128.98,113.77 UC1.AA3
  BOTTOM w0.102: v1(140.94,116.06) 141.28,116.06 141.48,115.86 R2333.2
PCH_SPI_CLK_R: length 44.3
  IN3 w0.127: v1(143.35,116.49) 143.66,116.49 144.06,116.89 144.99,116.89 145.12,117.02 150.98,117.02 v1(151.4,117.45)
  BOTTOM w0.102: R2333.1 142.55,115.85 ; 142.55,115.85 142.71,115.85 v1(143.35,116.49) ; 142.55,115.85 C2326.1 ; v1(151.4,117.45) 154.14,114.71 v3(154.14,112.79) 154.14,111.21 154.47,110.88 154.47,110.28 155.3,109.45 155.3,105.75 156.3,104.75 156.3,94 159.33,90.97 159.33,88.69 158.67,88.04 U2302.6
PCH_SPI_CS0#: length 68
  IN3 w0.084: 137.72,118.67 137.54,118.67 136.17,117.29 134.31,117.29 133.68,117.93 130.78,117.93 130.15,117.3 128.17,117.3 127.39,116.53 127.02,116.53 126.77,116.28 125.76,116.28 125.5,116.03 125.5,115.52 125.63,115.39 126.07,115.39 v1(126.52,114.94)
  IN3 w0.127: v1(149.28,119.18) 149.18,119.09 147.72,119.09 147.42,119.38 143.35,119.38 142.94,118.97 140.01,118.97 139.7,118.67 137.72,118.67
  BOTTOM w0.076: v1(126.52,114.94) 126.34,114.76 UC1.Y7
  BOTTOM w0.102: U2302.1 148.79,85.5 147.6,86.69 v3(147.6,87.41) 147.6,91.77 153.11,97.28 153.11,107.2 152.54,107.78 152.54,108.04 152.12,108.47 152.12,114 149.28,116.84 v1(149.28,119.18)
PCH_SPI_HOLD1#: length 48.9
  IN3 w0.127: v1(141.51,118.46) 141.51,118.31 142.3,117.52 143.23,117.52 143.63,117.92 144.56,117.92 144.7,118.06 149.74,118.06 150.26,118.58 150.86,118.58 v1(151.4,118.04)
  BOTTOM w0.102: v1(141.51,118.46) 141.01,117.96 RP39.4 ; U2302.7 158.79,86.77 159.81,87.78 159.81,91.17 156.78,94.2 v3(156.78,97.59) 156.78,104.95 155.78,105.95 155.78,109.65 154.96,110.48 154.96,111.08 154.63,111.41 154.63,114.91 151.5,118.04 v1(151.4,118.04)
PCH_SPI_HOLD#: length 18.3
  IN1 w0.127: v1(135.98,112.79) 136.05,112.85 136.05,113.68 136.44,114.07 138.09,114.07 139.46,115.44 141.18,115.44 141.57,115.83 141.57,116.66 v1(140.94,117.3)
  BOTTOM w0.076: v1(135.98,112.79) 134.84,111.64 v3(134.43,111.64) 130.32,111.64 UC1.AF1
  BOTTOM w0.102: R2335.2 141.3,117.3 v1(140.94,117.3) 140.86,117.3 140.68,117.48 139.92,117.48 139.44,117.96 RP39.5
PCH_SPI_MISO: length 14.1
  IN1 w0.084: v1(137.76,117.87) 136.43,117.87 133.94,115.38 131.66,115.38 130.26,113.98 v1(127.82,113.98)
  BOTTOM w0.089: v1(137.76,117.87) 137.76,118.37 137.92,118.54 ; v1(127.82,113.98) 127.92,113.88 UC1.AA4
  BOTTOM w0.102: 137.92,118.54 138.27,118.88 138.38,118.88 138.46,118.96 RP39.7
PCH_SPI_MISO_1: length 48.4
  IN3 w0.127: v1(149.76,118.8) 149.53,118.57 147.43,118.57 147.12,118.88 143.86,118.88 143.02,118.03 142.56,118.03 v1(142.14,118.46)
  BOTTOM w0.102: v1(149.76,118.8) 149.76,117.04 152.7,114.11 152.7,108.67 153.03,108.34 153.03,107.98 153.6,107.41 153.6,96.95 148.17,91.53 v3(148.17,90.43) 148.17,87.51 148.92,86.77 U2302.2 ; RP39.2 141.64,118.96 v1(142.14,118.46)
PCH_SPI_MOSI: length 13.8
  IN1 w0.084: 137.92,117.36 136.2,117.36 133.85,115.01 v1(133.75,115.01)
  IN1 w0.127: 137.92,117.36 138.16,117.36 138.84,118.04 138.84,118.76 v1(138.2,119.39)
  BOTTOM w0.076: v1(133.75,115.01) 133.75,114.23 133.65,114.14 130.16,114.14 129.86,113.84 UC1.AA2
  BOTTOM w0.102: RP39.8 138.27,119.46 v1(138.2,119.39)
PCH_SPI_MOSI_1: length 45.8
  IN3 w0.127: v1(140.87,119.84) 141.18,119.53 142.76,119.53 143.13,119.89 147.64,119.89 147.93,119.6 148.81,119.6 v1(148.87,119.67)
  BOTTOM w0.102: U2302.5 158.67,89.31 158.84,89.48 158.84,90.77 154.56,95.05 154.56,106.26 154.82,106.51 154.82,109.25 153.99,110.08 153.99,110.68 153.66,111.01 153.66,114.51 150.9,117.26 150.9,118.76 150,119.67 v1(148.87,119.67) ; v1(140.87,119.84) 140.87,119.64 140.69,119.46 RP39.1
PCH_SPI_WP1#: length 46.7
  IN3 w0.127: v1(140.87,118.46) 140.87,118.12 141.99,117 143.44,117 143.85,117.41 144.78,117.41 144.91,117.54 149.94,117.54 v1(150.43,118.03)
  BOTTOM w0.102: v1(150.43,118.03) 150.4,118 150.4,117.09 153.18,114.31 153.18,110.81 153.51,110.48 153.51,108.18 154.08,107.61 154.08,96.63 148.75,91.29 148.75,88.59 149.3,88.04 U2302.3 ; RP39.3 v1(140.87,118.46)
PCH_SPI_WP#: length 18.6
  IN1 w0.084: v1(127.17,114.94) 127.67,114.44 130.14,114.44 131.41,115.71 133.97,115.71 136.51,118.25 137.92,118.25
  IN1 w0.127: 137.92,118.25 v1(138.33,118.25)
  BOTTOM w0.076: v1(127.17,114.94) 126.99,114.76 UC1.Y6
  BOTTOM w0.102: RP39.6 138.67,118.46 138.46,118.25 v1(138.33,118.25) 138.33,117.55 138.91,116.97 140.45,116.97 140.67,116.75 R2334.2
PCH_X1_R: length 256.1
  TOP w0.089: 117.33,93.94 116.79,94.47 116.79,109.9 116.13,110.56 116.13,112.52 115.29,113.37 115.29,118.76 116.08,119.56 116.08,120.33 116.34,120.58 116.34,123.2 116.08,123.46 116.08,126.72 117.57,128.2 117.57,129.3 118.83,130.56 118.83,131.11
  TOP w0.102: UG1.5 72.23,40.11 72.36,39.99 72.36,37.73 v1(72.04,37.41) ; 118.83,131.11 118.83,132.17 119.82,133.16 119.82,135.98 RG6.1 ; 117.33,93.94 v3(121.14,90.13) 121.83,89.43 149.74,89.43 150.96,88.21 162.13,88.21 171.9,78.45 171.9,64.58 173.28,63.19 173.28,59.17 172.98,58.86 172.98,57.49 175.48,54.99 175.48,51.64 v1(174.77,50.93)
  IN1 w0.127: v1(174.77,50.93) 174.77,48.63 175.15,48.25 175.15,40.59 v1(175.53,40.21)
  IN3 w0.127: v1(175.53,40.21) 175.01,40.73 113.42,40.73 113.1,41.04 94.14,41.04 91.23,38.14 72.76,38.14 v1(72.04,37.41)
PCIE_B+: length 1.3
  BOTTOM w0.102: PC1301.1 196.12,60.72 v3(196.24,60.84)
PCIE_CRX_C_GTX_N0: length 11.8
  TOP w0.102: CV44.2 160.33,117.05 v2(162.8,117.05) 163.47,117.05 163.99,116.53 166.22,116.53 166.75,117.07 167.74,117.07 168.7,118.02 169.13,118.02
  TOP w0.109: v1(169.64,118.72) 169.57,118.72 169.44,118.59 169.44,118.34 169.13,118.02
  BOTTOM w0.102: UV1.Y32 169.26,118.99 169.54,118.72 v1(169.64,118.72)
PCIE_CRX_C_GTX_N1: length 10.8
  TOP w0.102: v1(169.62,119.78) 169.49,119.78 169.36,119.65 169.36,119.43 169.1,119.17 167.81,119.17 167.65,119.01 167.65,117.82 167.41,117.58 166.44,117.58 166.12,117.9 162.84,117.9 162.55,118.18 162.15,118.18 CV46.2
  BOTTOM w0.102: UV1.W32 169.62,120.14 v1(169.62,119.78)
PCIE_CRX_C_GTX_N2: length 12
  TOP w0.102: CV48.2 160.32,119.39 163.02,119.39 163.82,118.6 v2(165.48,118.6) 165.77,118.6 166.38,119.21 166.92,119.21 167.99,120.27 169.19,120.27 169.39,120.48 169.39,120.85 v1(169.56,121.02)
  BOTTOM w0.102: UV1.U32 169.26,121.32 v1(169.56,121.02)
PCIE_CRX_C_GTX_N3: length 11.9
  TOP w0.102: CV50.2 162.17,120.77 163.75,120.77 164.36,120.16 v2(165.72,120.16) 166.1,120.16 166.92,120.98 167.46,120.98 167.68,121.21 168.25,121.21 168.77,121.73 171.1,121.73 171.29,121.54 171.29,121.17 v1(171.42,121.03)
  BOTTOM w0.102: v1(171.42,121.03) 171.42,121.08 171.66,121.33 UV1.U29
PCIE_CRX_C_GTX_P0: length 11.8
  TOP w0.102: 169.04,118.23 169.03,118.23 168.61,118.23 167.65,117.27 v2(166.9,117.27) 166.65,117.27 166.14,116.76 165.38,116.76 165.37,116.75 165.05,116.75 165.04,116.76 164.09,116.76 163.57,117.28 160.32,117.28 CV43.2
  TOP w0.109: 169.04,118.23 169.23,118.43 169.23,118.75 169.11,118.88 168.97,118.88 v1(168.86,118.77)
  BOTTOM w0.102: UV1.Y33 168.46,119.17 v1(168.86,118.77)
PCIE_CRX_C_GTX_P1: length 10.7
  TOP w0.102: CV45.2 162.17,118.42 162.63,118.42 162.93,118.13 v2(163.74,118.13) 166.2,118.13 166.53,117.8 167.32,117.8 167.44,117.91 167.44,119.1 167.72,119.38 169.03,119.38 169.16,119.51 169.16,119.76 169.03,119.89 168.88,119.89 v1(168.76,119.78)
  BOTTOM w0.102: UV1.W33 168.76,120.19 v1(168.76,119.78)
PCIE_CRX_C_GTX_P2: length 12
  TOP w0.102: v1(168.95,121.02) 169.18,120.79 169.18,120.57 169.1,120.48 167.9,120.48 166.84,119.42 166.29,119.42 165.69,118.83 163.91,118.83 163.12,119.62 160.33,119.62 CV47.2
  BOTTOM w0.102: v1(168.95,121.02) 168.63,121.02 168.46,121.19 UV1.U33
PCIE_CRX_C_GTX_P3: length 12
  TOP w0.102: v1(170.64,121.09) 170.89,121.09 171.08,121.28 171.08,121.46 171.02,121.52 168.85,121.52 168.33,121 167.76,121 167.54,120.78 167.01,120.78 166.17,119.95 164.25,119.95 163.65,120.55 v2(163.44,120.55) 162.16,120.55 CV49.2
  BOTTOM w0.102: v1(170.64,121.09) 170.83,121.09 171.03,121.29 171.03,121.52 UV1.U30
PCIE_PRX_LANTX_N3: length 105.3
  IN1 w0.084: 88.91,112.19 89.37,112.19 90.01,111.56 91.85,111.56 92.49,110.91 94.23,110.91 94.42,110.72 95.71,110.72 97.24,112.25 113.6,112.25 113.79,112.44 116.86,112.44 117.35,112.93 117.35,114.51 118.81,115.97 118.81,118.11 120.75,120.05 123.49,120.05 123.82,120.38 123.82,122.19 123.71,122.3 123.57,122.3 123.44,122.17 v1(123.44,121.93)
  IN1 w0.127: v1(41.88,90.33) 42.12,90.08 42.5,90.08 47.75,95.34 47.75,97.96 57.78,107.99 64.51,107.99 65.77,109.25 72.87,109.25 74.7,111.08 77.89,111.08 78.53,111.72 87.42,111.72 87.89,112.19 88.91,112.19
  BOTTOM w0.089: UC1.G11 123.58,121.93 v1(123.44,121.93)
  BOTTOM w0.102: CL31.1 42.54,88.58 42.54,89.77 42.29,90.02 42.19,90.02 v1(41.88,90.33)
PCIE_PRX_LANTX_N3_C: length 4.1
  BOTTOM w0.102: UL1.18 40.27,85.28 40.35,85.35 40.55,85.35 41.03,85.84 41.03,85.84 v2(41.11,85.92) 41.11,85.92 41.63,86.43 42.45,86.43 42.73,86.71 42.73,87.02 CL31.2
PCIE_PRX_LANTX_P3: length 105.3
  IN1 w0.084: v1(123.41,122.63) 123.52,122.53 123.81,122.53 124.05,122.28 124.05,120.28 123.59,119.82 120.84,119.82 119.04,118.02 119.04,115.88 117.58,114.42 117.58,112.83 116.96,112.22 113.88,112.22 113.69,112.02 97.34,112.02 95.81,110.49 94.33,110.49 94.14,110.68 92.4,110.68 91.75,111.33 89.91,111.33 89.28,111.96 89.03,111.96 89.01,111.94 88.95,111.94 88.93,111.92 88.91,111.92
  IN1 w0.127: 88.91,111.92 88,111.92 87.53,111.45 78.64,111.45 78,110.81 74.81,110.81 72.98,108.98 65.88,108.98 64.62,107.72 57.89,107.72 48.02,97.85 48.02,95.22 42.61,89.81 41.95,89.81 v1(41.88,89.74)
  BOTTOM w0.089: UC1.F11 123.75,122.29 v1(123.41,122.63)
  BOTTOM w0.102: CL30.1 42.32,88.42 42.32,89.68 42.2,89.8 41.93,89.8 v1(41.88,89.74)
PCIE_PRX_LANTX_P3_C: length 4.2
  BOTTOM w0.102: CL30.2 42.14,87.32 42.45,87.32 42.5,87.27 42.5,86.81 42.35,86.66 41.53,86.66 41.11,86.24 41.11,86.24 40.79,85.92 40.79,85.92 40.45,85.58 40.35,85.58 40.26,85.68 UL1.17
PCIE_PRX_WLANTX_N4: length 55.6
  IN3 w0.084: 118.12,130.82 118.11,130.81 118.11,130.8 118.12,130.79 118.06,130.73 118.06,130.7 117.37,130.01 117.37,124.81 116.98,124.43 116.98,122.91 117.36,122.54 117.36,121.02 118.39,119.98 122.69,119.98 123.07,120.36 123.07,122.23 122.86,122.44 122.77,122.53 122.66,122.53 v1(122.52,122.67)
  IN3 w0.127: JMINI.23 105.3,149.87 105.44,149.73 105.44,149.19 106.02,148.62 113.7,148.62 114.54,147.78 119.28,147.78 122.08,144.98 122.08,137.87 118.49,134.29 118.49,131.2 118.12,130.82
  BOTTOM w0.076: UC1.F13 122.89,122.29 v1(122.52,122.67)
PCIE_PRX_WLANTX_P4: length 55.5
  IN3 w0.084: v1(122.52,121.92) 122.41,121.92 122.27,122.06 122.27,122.23 122.33,122.29 122.71,122.29 122.89,122.11 122.89,120.48 122.6,120.19 118.48,120.19 117.57,121.11 117.57,122.63 117.2,123 117.2,124.34 117.58,124.72 117.58,129.92 118.3,130.64
  IN3 w0.127: 118.3,130.64 118.75,131.09 118.75,134.19 122.33,137.77 122.33,145.08 119.38,148.03 114.65,148.03 113.8,148.87 106.12,148.87 105.69,149.3 105.69,149.62 105.76,149.68 106,149.68 106.1,149.78 JMINI.25
  BOTTOM w0.089: v1(122.52,121.92) 122.79,121.64 UC1.G13
PCIE_PTX_LANRX_N3: length 14.4
  BOTTOM w0.102: UL1.14 38.35,86.93 38.26,87.02 38.26,87.53 39.59,88.86 39.59,91.51 39.6,91.52 39.6,92.05 39.59,92.07 v2(39.59,94.76) 39.59,99.69 CC32.1
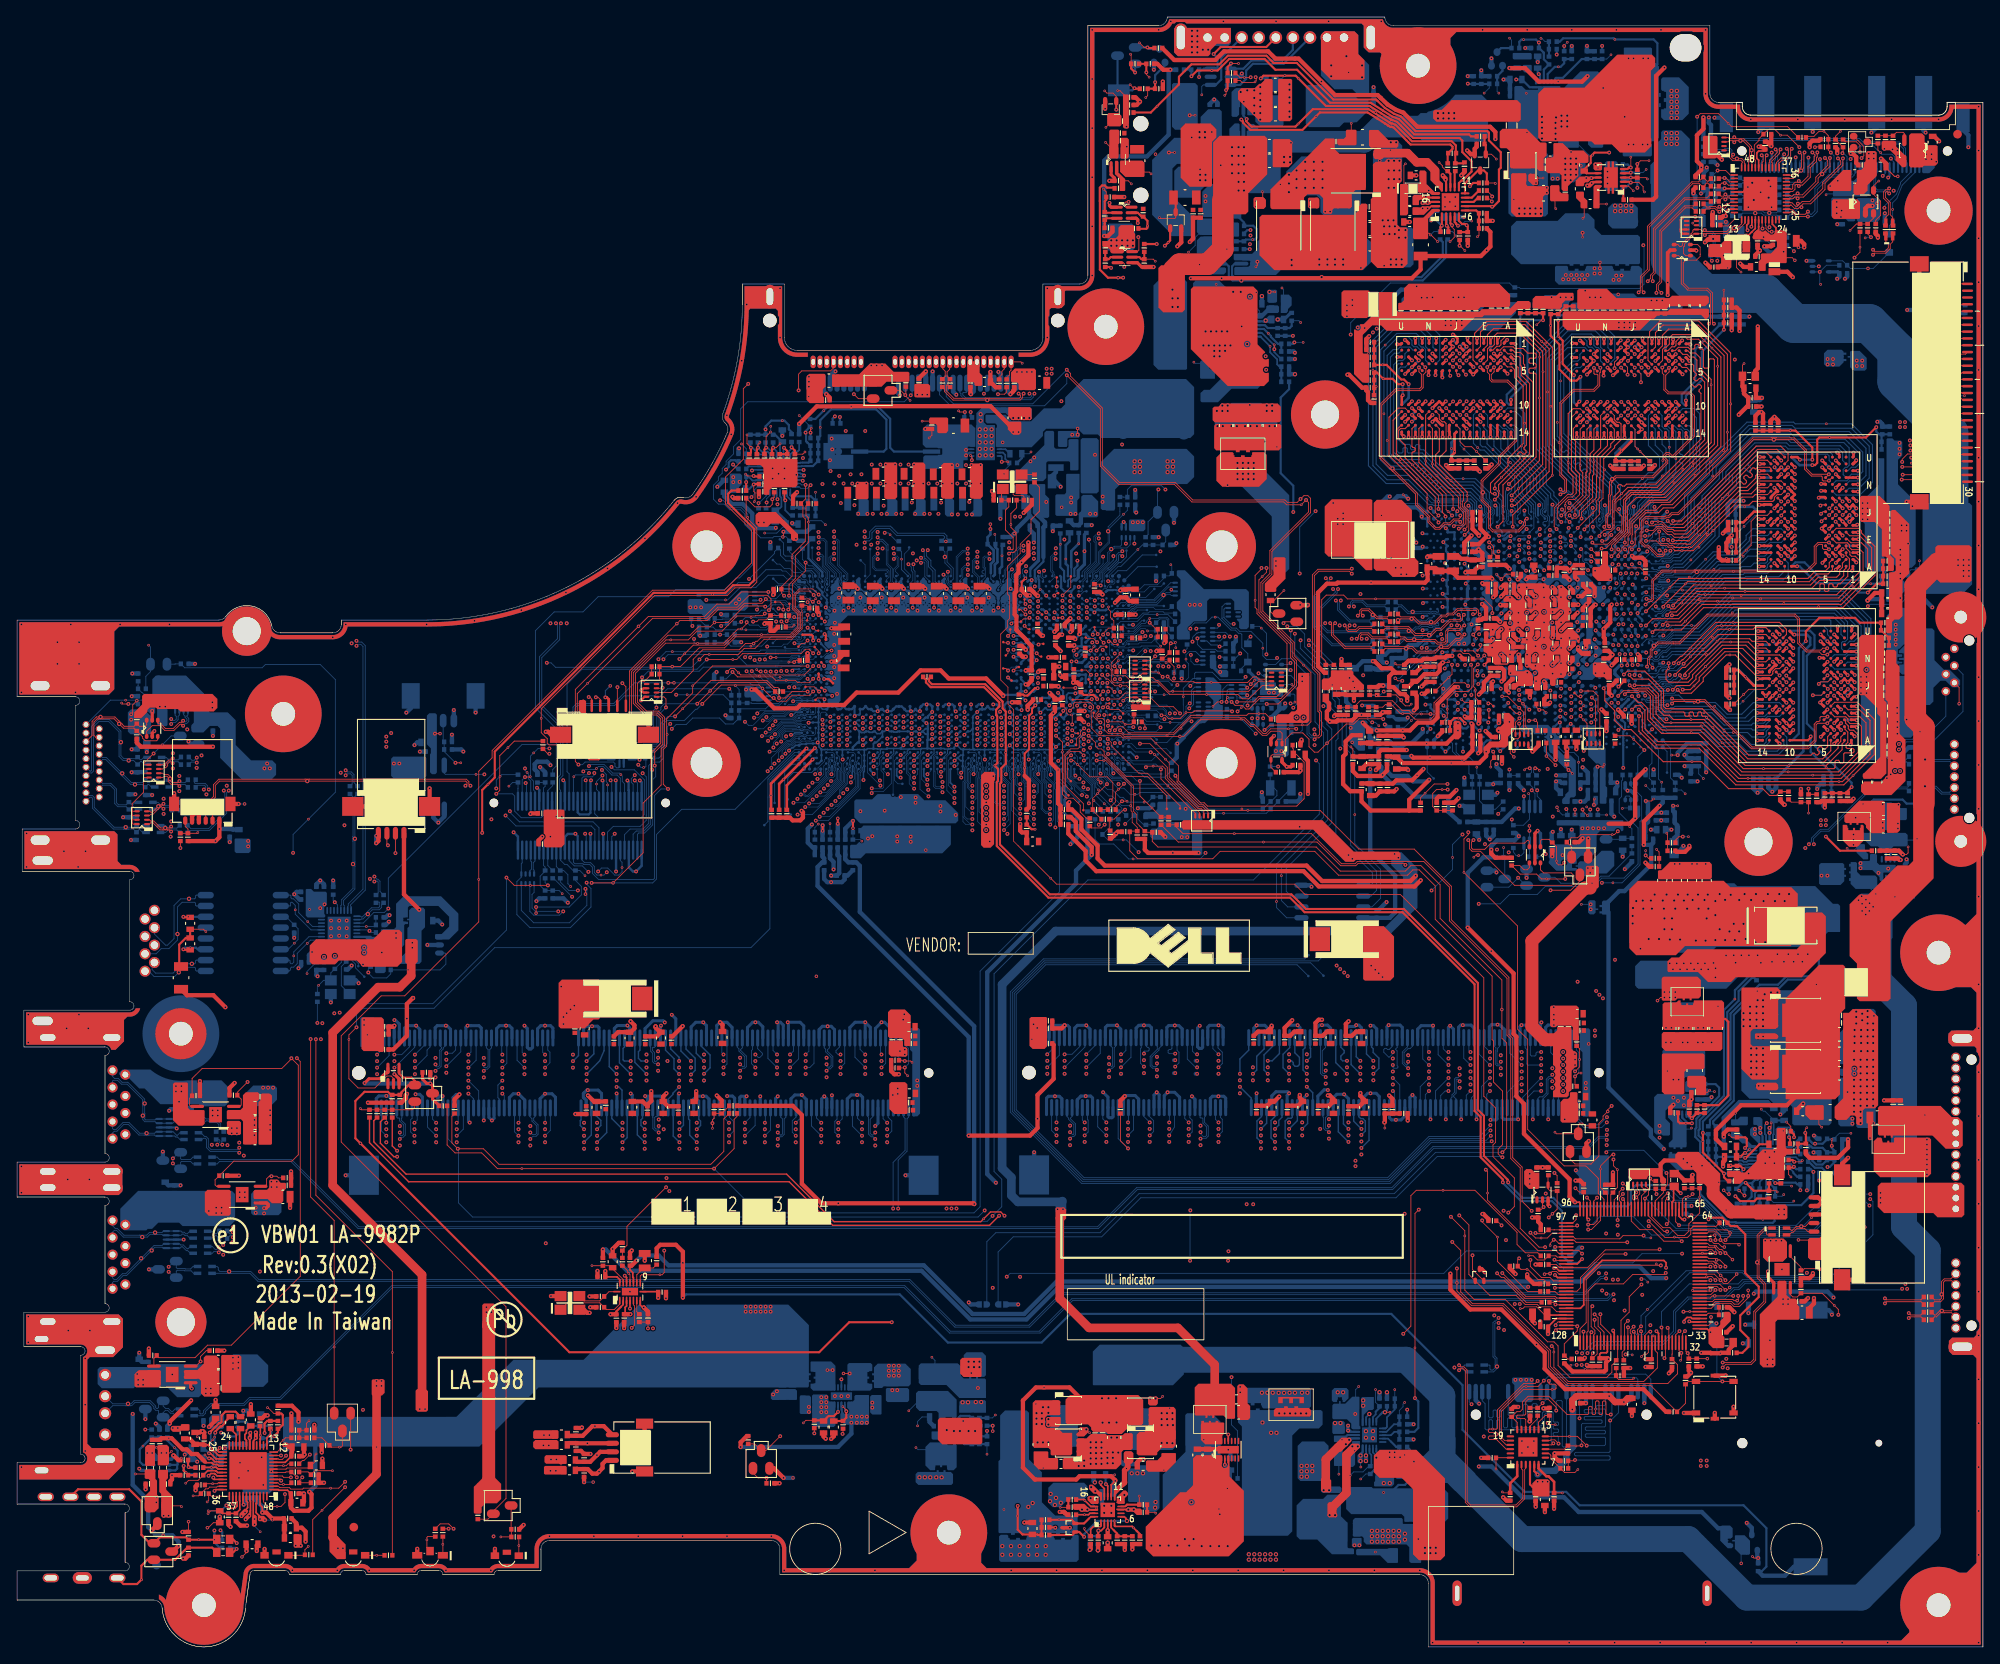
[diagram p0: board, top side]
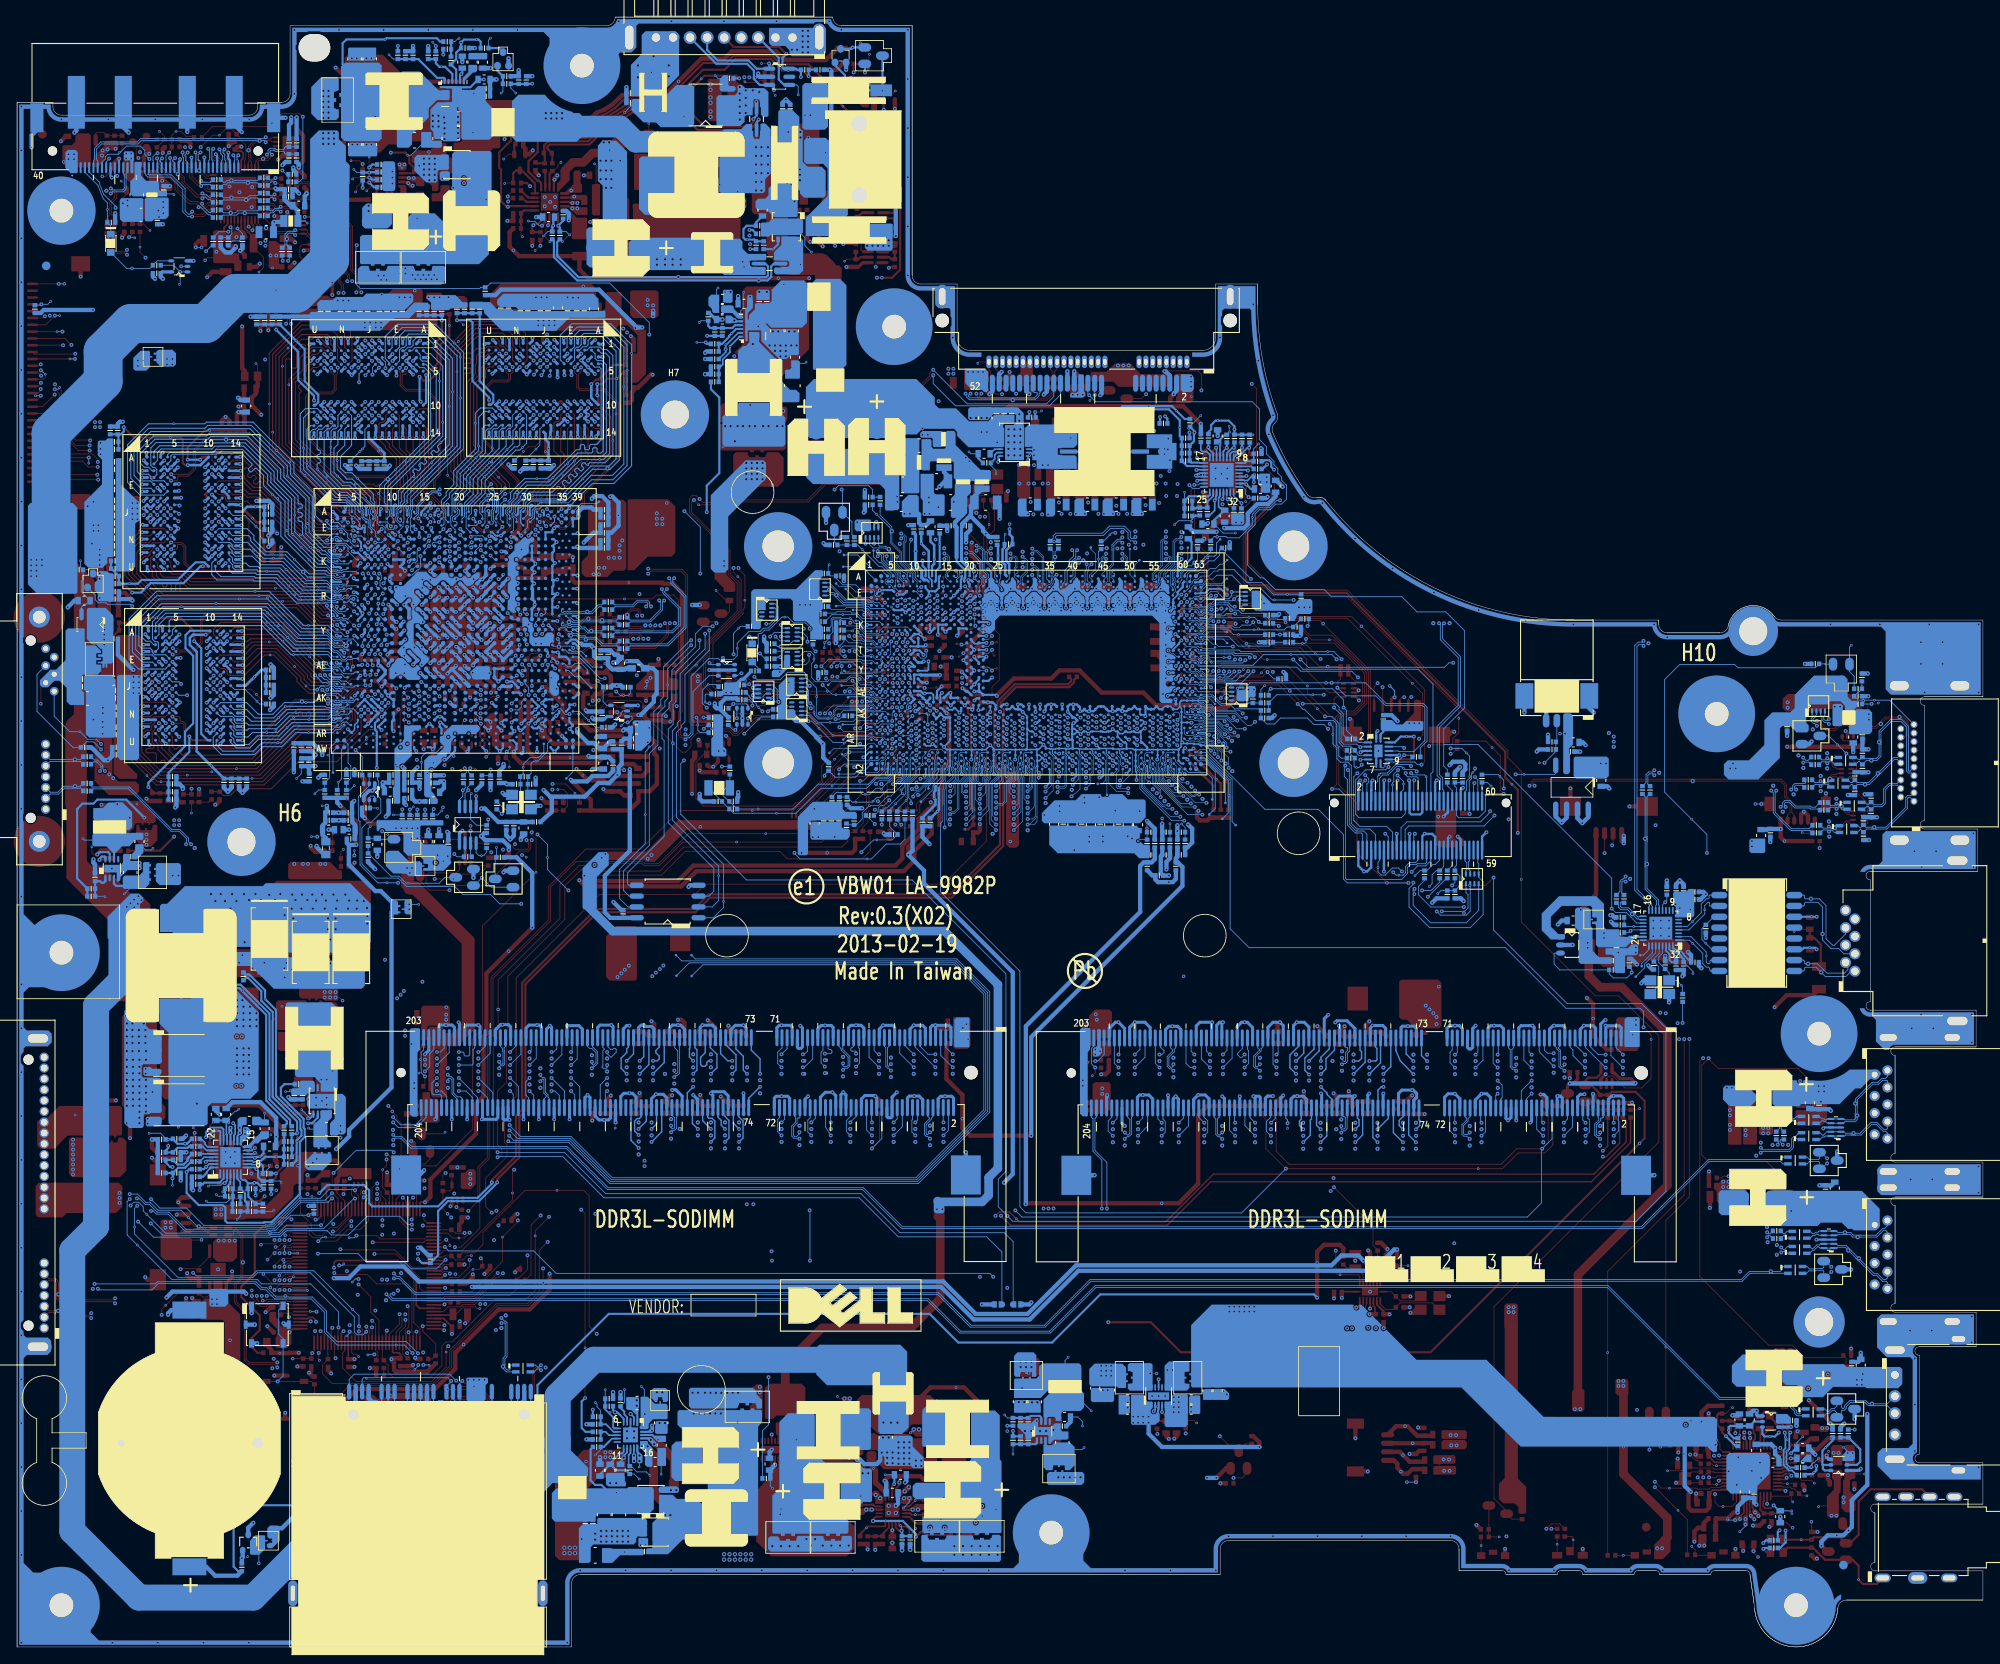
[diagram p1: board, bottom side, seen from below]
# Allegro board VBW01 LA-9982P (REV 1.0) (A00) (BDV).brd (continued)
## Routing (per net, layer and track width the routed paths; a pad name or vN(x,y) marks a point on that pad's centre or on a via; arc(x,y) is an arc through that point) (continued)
PCIE_PTX_LANRX_N3_C: length 95.9
  IN1 w0.084: v1(112.55,127.17) 112.55,127.25 112.77,127.48 112.94,127.48 113.11,127.31 113.11,125.19 111.58,123.65 95.64,123.65 94.13,122.14 94.13,121.56 94.39,121.3 94.39,120.88 93.67,120.16 92.21,120.16 90.79,118.73 87.05,118.73 87.03,118.76 86.76,118.76
  IN1 w0.127: v1(38.51,102.78) 38.71,102.58 39.41,102.58 39.76,102.93 39.76,104.81 47.58,112.62 64.22,112.62 64.63,113.03 69.88,113.03 74.59,117.74 83.4,117.74 84.42,118.76 86.76,118.76
  BOTTOM w0.076: UC1.C29 113.06,124.44 112.76,124.73 112.76,125.48 112.16,126.09 112.16,127.28 112.3,127.42 112.36,127.42 112.55,127.24 v1(112.55,127.17)
  BOTTOM w0.102: v1(38.51,102.78) 38.7,102.59 39.18,102.59 39.49,102.28 39.49,101.34 CC32.2
PCIE_PTX_LANRX_P3: length 14.4
  BOTTOM w0.102: UL1.13 37.95,86.93 38.04,87.02 38.04,87.62 39.37,88.95 v2(39.37,91.79) 39.37,94.44 39.35,94.47 39.35,95.01 39.37,95.04 39.37,99.65 CC40.1
PCIE_PTX_LANRX_P3_C: length 95.9
  IN1 w0.084: 86.76,118.48 86.77,118.48 86.79,118.51 90.88,118.51 92.31,119.93 93.77,119.93 94.62,120.78 94.62,121.39 94.36,121.65 94.36,122.05 95.74,123.42 111.67,123.42 113.34,125.09 113.34,127.4 113.04,127.71 112.66,127.71 v1(112.55,127.82)
  IN1 w0.127: 86.76,118.48 84.53,118.48 83.52,117.47 74.7,117.47 69.99,112.76 64.74,112.76 64.34,112.35 47.69,112.35 40.03,104.69 40.03,102.82 39.53,102.31 38.62,102.31 v1(38.51,102.2)
  BOTTOM w0.076: UC1.B30 112.57,124.67 112.57,125.4 111.96,126.01 111.96,127.36 112.22,127.61 112.34,127.61 v1(112.55,127.82)
  BOTTOM w0.102: v1(38.51,102.2) 38.68,102.37 39.09,102.37 39.27,102.19 39.27,101.18 CC40.2
PCIE_PTX_WLANRX_N4: length 38.8
  TOP w0.102: CM49.1 108.69,147.48 108.69,147.19 109.69,146.19 v2(113.71,146.19) 117.56,146.19 117.82,146.45 117.82,146.8 v1(117.97,146.95)
  IN3 w0.127: v1(113.97,127.56) 114.05,127.56 114.18,127.68 114.38,127.68 114.8,128.1 114.8,132.93 120.74,138.87 120.74,144.36 119.42,145.68 118.18,145.68 117.83,146.03 117.83,146.81 v1(117.97,146.95)
  BOTTOM w0.076: UC1.B29 113.06,125 113.51,125.45 113.51,126.51 113.4,126.63 113.4,127.63 113.47,127.71 113.81,127.71 v1(113.97,127.56)
PCIE_PTX_WLANRX_N4_C: length 2.3
  TOP w0.102: JMINI.31 108.5,149.86 108.78,149.58 108.78,148.98 CM49.2
PCIE_PTX_WLANRX_P4: length 38.8
  TOP w0.102: v1(117.38,146.95) 117.61,146.73 117.61,146.54 117.47,146.4 113.99,146.4 113.97,146.42 113.44,146.42 113.43,146.4 109.78,146.4 108.9,147.28 108.9,147.87 108.99,147.97 109.09,147.97 CM44.1
  IN3 w0.127: v1(113.97,128.21) 113.97,128.06 114.1,127.93 114.27,127.93 114.54,128.21 114.54,133.03 120.49,138.98 120.49,144.26 119.32,145.43 118.08,145.43 117.58,145.92 117.58,146.76 v1(117.38,146.95)
  BOTTOM w0.076: v1(113.97,128.21) 113.97,128.05 113.82,127.9 113.39,127.9 113.21,127.71 113.21,126.59 113.35,126.44 113.35,126.27 113.27,126.19 113.17,126.19 113.1,126.12 113.1,125.97 113.17,125.89 113.27,125.89 113.35,125.81 113.35,125.63 113.27,125.56 113.06,125.56 UC1.A29
PCIE_PTX_WLANRX_P4_C: length 2.3
  TOP w0.102: JMINI.33 109.3,149.81 109,149.5 109,148.98 CM44.2
PCIE_WAKE#: length 304.1
  TOP w0.089: RC97.2 132.18,108.09 v1(132.18,107.71)
  TOP w0.102: UE1.29 194.39,36.58 v1(194.84,37.03)
  IN1 w0.084: 137.89,107.4 132.49,107.4 v1(132.18,107.71)
  IN1 w0.127: v1(190.38,43.14) 190.01,43.51 190.01,49.77 187.51,52.27 187.51,54.61 188.05,55.15 188.05,63.59 186.83,64.81 186.83,73.04 179.65,80.23 177.83,80.23 174.39,83.67 169.85,83.67 168.96,84.55 166.81,84.55 159.96,91.41 159.96,93.87 152.43,101.4 152.43,101.55 148.12,105.86 147.19,105.86 145.34,107.71 144.5,107.71 143.87,108.34 138.88,108.34 137.93,107.4 137.89,107.4
  IN3 w0.127: v1(41.3,83.96) 47.25,78.02 47.25,51.73 54.5,44.47 54.51,44.47 56.01,42.97 183.4,42.97 185.09,44.66 188.82,44.66 190.35,43.14 v1(190.38,43.14) 191.72,43.14 192.37,42.49 195.37,42.49 196.59,41.27 196.59,37.92 196.4,37.73 195.53,37.73 v1(194.84,37.03)
  BOTTOM w0.102: UL1.21 41.19,84.07 v1(41.3,83.96) 41.49,83.77 RL34.2 ; v1(190.38,43.14) 190.76,43.14 v3(191.12,42.78)
PCIE_WAKE#_R: length 5.4
  TOP w0.089: v1(127.84,108.57) 127.94,108.47 129.57,108.47 v3(129.86,108.18) 130.6,108.18 RC97.1 130.89,108.98 130.9,108.99 RC34.2
  BOTTOM w0.076: v1(127.84,108.57) 127.84,109.5 UC1.AJ5
PECI_EC: length 214.1
  TOP w0.102: v1(171.71,50.01) 171.71,49.85 v3(173.51,48.05) 173.51,45.2 177.03,41.68 RE43.2
  IN3 w0.127: v1(171.71,50.01) 140.31,50.01 140.1,49.79 117.26,49.79 115.93,51.13 114.13,51.13 113.12,50.13 70.18,50.13 65.88,54.43 65.88,70.31 61.94,74.24 61.94,87.93 60.65,89.22 60.65,96.06 62.04,97.46 62.04,103.01 61.38,103.68 61.38,109.34 69.18,117.14 77.95,117.14 78.69,116.4 84.41,116.4 85.3,117.3 v1(87.91,117.3)
  BOTTOM w0.076: UC1.N62 92.3,118.21 92.01,117.92 91.46,117.92 91.43,117.95 91.28,118.1 90.81,118.1 90.29,117.58 89.87,117.58 89.59,117.3 v1(87.91,117.3)
PECI_KB9012: length 2.3
  TOP w0.102: UE1.118 180.61,41.31 180.24,41.68 RE43.1
PEG_CLKREQ#: length 96.8
  TOP w0.089: 137.92,113.17 135.45,113.17 v1(134.84,113.78)
  TOP w0.102: RP42.6 146.5,113.73 146.23,113.46 145.52,113.46 145.25,113.73 144.87,113.73 144.22,113.08 v3(139.95,113.08) 138.01,113.08 137.92,113.17 ; v1(179.72,88.72) 182.08,88.72 183.16,89.8 QV28.1
  IN3 w0.084: 137.82,113.07 137.67,113.07 136.49,114.25 135.31,114.25 v1(134.84,113.78) 134.24,114.37 125.44,114.37 125.12,114.69 125.12,116.03 125.55,116.45 126.69,116.45 127.15,116.91 v1(127.24,116.91)
  IN3 w0.127: v1(179.72,88.72) 176.11,88.72 174.37,90.46 174.37,94.23 172.66,95.94 168.6,95.94 164.68,99.86 164.68,101.8 163.16,103.33 162.2,103.33 159.26,106.26 155,106.26 151.63,109.64 151.63,115.24 151.03,115.84 148.37,115.84 147.69,115.16 144.33,115.16 144.05,114.88 143.07,114.88 141.26,113.07 137.82,113.07
  BOTTOM w0.089: UC1.U5 127.64,116.51 v1(127.24,116.91)
PEG_CRX_GTX_N0: length 40.5
  TOP w0.102: v1(153.89,120.03) 154.04,119.89 154.04,118.61 155.6,117.05 158.74,117.05 CV44.1
  IN3 w0.084: v1(125.37,121.91) 125.37,122.04 125.91,122.59 125.91,123 126.73,123.82 128.32,123.82 128.83,124.32 130.71,124.32 131.4,123.63 134.79,123.63 136.9,121.53 137.64,121.53 137.66,121.5 137.73,121.5 137.75,121.48 137.92,121.48
  IN3 w0.127: v1(153.89,120.03) 154.05,120.2 154.05,120.38 153.97,120.47 152.02,120.47 150.49,121.99 139.67,121.99 139.15,121.48 137.92,121.48
  BOTTOM w0.089: v1(125.37,121.91) 124.99,122.29 UC1.F10
PEG_CRX_GTX_N1: length 40.6
  TOP w0.102: CV46.1 160.59,118.21 158.76,118.21 158.29,118.68 157.58,118.68 157.43,118.52 157.43,118.37 v1(157.59,118.21)
  IN3 w0.084: v1(126.31,121.99) 126.42,122.1 126.53,122.1 126.64,121.99 126.64,121.82 126.98,121.47 134.13,121.47 135.69,119.92 137.55,119.92 137.58,119.9 137.64,119.9 137.66,119.87 137.67,119.87
  IN3 w0.127: v1(157.59,118.21) 157.38,118 157.38,117.66 157.08,117.36 155.78,117.36 155.53,117.61 155.53,117.9 155.42,118.01 154.45,118.01 154.32,117.88 154.32,117.5 154.04,117.22 153.42,117.22 153.14,117.5 153.14,117.88 153.01,118.01 152.3,118.01 149.85,120.46 148.27,120.46 148.21,120.4 140.68,120.4 140.15,119.87 137.67,119.87
  BOTTOM w0.089: UC1.F8 126.01,122.29 v1(126.31,121.99)
PEG_CRX_GTX_N2: length 41.1
  TOP w0.102: v1(155.59,119.77) 155.78,119.59 155.78,119.27 155.99,119.06 156.98,119.06 157.32,119.4 158.74,119.4 CV48.1
  IN3 w0.084: 137.92,122.77 136.45,122.77 134.9,124.33 131.78,124.33 131.34,124.77 128.64,124.77 128.23,124.36 127.64,124.36 127.15,124.85 126.69,124.85 125.33,123.49 125.33,123.25 124.98,122.9 124.98,122 124.77,121.79 124.77,121.65 124.43,121.31 v1(124.42,121.31)
  IN3 w0.127: 137.92,122.77 151.49,122.77 153.01,121.24 154.74,121.24 155.78,120.21 155.78,119.96 v1(155.59,119.77)
  BOTTOM w0.089: UC1.H10 124.74,120.99 v1(124.42,121.31)
PEG_CRX_GTX_N3: length 39.7
  TOP w0.102: CV50.1 160.59,120.77 159.42,120.77 159.23,120.96 159.23,120.98 158.86,121.35 158.84,121.35 158.48,121.71 157.56,121.71 157.37,121.52 157.37,121.14 v1(157.14,120.91)
  IN3 w0.084: v1(127.22,122.69) 127.44,122.47 127.7,122.47 128.31,123.07 133.99,123.07 136.16,120.91 137.82,120.91 137.85,120.94 137.92,120.94
  IN3 w0.127: v1(157.14,120.91) 157.3,120.75 157.3,119.34 157.17,119.2 152.54,119.2 150.26,121.49 140.32,121.49 139.77,120.94 137.92,120.94
  BOTTOM w0.089: UC1.E6 126.97,122.94 v1(127.22,122.69)
PEG_CRX_GTX_P0: length 40.3
  TOP w0.102: v1(154.48,120.03) 154.25,119.81 154.25,118.7 155.69,117.27 158.74,117.27 CV43.1
  IN3 w0.084: v1(125.37,122.67) 125.47,122.57 125.59,122.57 125.7,122.67 125.7,123.08 126.64,124.03 128.24,124.03 128.74,124.53 130.79,124.53 131.49,123.84 134.88,123.84 136.98,121.74 137.92,121.74
  IN3 w0.127: 137.92,121.74 139.05,121.74 139.56,122.25 150.6,122.25 152.12,120.72 154.07,120.72 154.31,120.49 154.31,120.2 v1(154.48,120.03)
  BOTTOM w0.089: v1(125.37,122.67) 125.04,122.67 124.82,122.89 UC1.E10
PEG_CRX_GTX_P1: length 40.7
  TOP w0.102: CV45.1 160.59,118.42 158.85,118.42 158.38,118.89 157.49,118.89 157.21,118.61 157.21,118.42 v1(157.01,118.21)
  IN3 w0.084: 137.67,120.13 135.78,120.13 134.22,121.69 127.07,121.69 126.85,121.9 126.85,122.08 126.61,122.31 126.52,122.31 126.31,122.52 v1(126.31,122.69)
  IN3 w0.127: v1(157.01,118.21) 157.13,118.08 157.13,117.77 156.97,117.61 155.89,117.61 155.78,117.71 155.78,118 155.53,118.26 154.34,118.26 154.07,117.98 154.07,117.61 153.93,117.48 153.53,117.48 153.39,117.61 153.39,117.98 153.12,118.26 152.4,118.26 149.95,120.71 148.16,120.71 148.11,120.65 140.57,120.65 140.04,120.13 137.67,120.13
  BOTTOM w0.089: UC1.E8 126.06,122.94 v1(126.31,122.69)
PEG_CRX_GTX_P2: length 40.9
  TOP w0.102: CV47.1 158.74,119.62 157.23,119.62 156.89,119.27 156.08,119.27 155.99,119.36 155.99,119.59 v1(156.18,119.77)
  IN3 w0.084: v1(124.42,121.93) 124.49,121.93 124.49,121.93 124.61,121.93 124.77,122.09 124.77,122.99 125.12,123.34 125.12,123.58 126.6,125.06 127.24,125.06 127.73,124.57 128.14,124.57 128.55,124.98 131.43,124.98 131.87,124.54 134.98,124.54 136.54,122.98 137.8,122.98 137.83,123 137.89,123 137.91,123.02 137.92,123.02
  IN3 w0.127: 137.92,123.02 151.59,123.02 153.11,121.5 154.85,121.5 156.03,120.32 156.03,119.92 v1(156.18,119.77)
  BOTTOM w0.089: UC1.G10 124.71,121.64 v1(124.42,121.93)
PEG_CRX_GTX_P3: length 39.7
  TOP w0.102: CV49.1 160.59,120.56 159.33,120.56 v2(158.88,121) 158.39,121.5 157.65,121.5 157.58,121.43 157.58,121.05 v1(157.72,120.91)
  IN3 w0.084: v1(127.22,122.06) 127.42,122.26 127.79,122.26 128.39,122.86 133.91,122.86 136.07,120.7 137.82,120.7 137.84,120.68 137.92,120.68
  IN3 w0.127: v1(157.72,120.91) 157.56,120.75 157.56,119.23 157.27,118.95 152.44,118.95 150.15,121.23 140.43,121.23 139.88,120.68 137.92,120.68
  BOTTOM w0.089: UC1.F6 126.98,122.29 v1(127.22,122.06)
PEG_CTX_GRX_C_N0: length 61.3
  IN3 w0.084: 130.67,127.49 130.64,127.46 125.11,127.46 124.41,126.76 121.82,126.76 119.93,128.64 119.39,128.64 v1(119.17,128.86)
  IN3 w0.127: 130.67,127.49 131.93,127.49 137.07,132.64 147.2,132.64 153.8,126.03 153.8,125.48 v1(153.97,125.31)
  BOTTOM w0.076: v1(119.17,128.86) 118.72,128.42 118.42,128.42 117.44,127.44 117.44,125.5 117.37,125.43 117.17,125.23 117.17,124.82 116.98,124.63 116.98,124.51 117.12,124.36 UC1.C23
  BOTTOM w0.102: v1(153.97,125.31) 153.77,125.11 153.77,124.7 152.2,123.13 152.2,119.58 154.18,117.6 158.54,117.6 CC18.1
PEG_CTX_GRX_C_N1: length 58.8
  IN3 w0.084: v1(117.95,129.12) 118.09,128.98 118.46,128.98 118.65,128.79 118.65,127.39 119.03,127.01 120.62,127.01 121.44,126.19 124.85,126.19 125.3,126.63 135.57,126.63 136.81,125.39 137.8,125.39 137.83,125.41 137.89,125.41 137.91,125.44 137.92,125.44
  IN3 w0.127: 137.92,125.44 152.53,125.44 153.23,124.74 154.45,124.74 154.71,124.47 154.71,124.14 v1(154.82,124.04)
  BOTTOM w0.089: UC1.B23 116.89,125.06 116.84,125.18 116.79,125.2 116.75,125.2 116.54,125.41 116.54,125.76 117.06,126.28 117.06,128.14 117.06,128.14 117.06,128.63 117.41,128.98 117.81,128.98 v1(117.95,129.12)
  BOTTOM w0.102: v1(154.82,124.04) 154.71,123.93 154.71,123.58 152.9,121.77 152.9,119.87 153.64,119.13 160.32,119.13 CC20.1
PEG_CTX_GRX_C_N2: length 47.2
  IN3 w0.084: 137.92,123.54 136.75,123.54 134.95,125.34 125.83,125.34 125.45,124.96 120.9,124.96 119.63,123.69 117.99,123.69 117.57,123.28 v1(117.57,123.26)
  IN3 w0.127: v1(155.15,122.69) 154.94,122.49 154.94,122.2 154.77,122.02 153.33,122.02 151.81,123.54 137.92,123.54
  BOTTOM w0.089: v1(117.57,123.26) 118.01,123.7 UC1.B21
  BOTTOM w0.102: v1(155.15,122.69) 154.96,122.51 154.96,121.68 156.24,120.4 158.54,120.4 CC22.1
PEG_CTX_GRX_C_N3: length 47.6
  IN3 w0.084: v1(118.25,126.09) 118.45,126.29 118.69,126.29 119.51,125.47 125.24,125.47 125.68,125.91 135.3,125.91 136.88,124.33 137.92,124.33
  IN3 w0.127: 137.92,124.33 152.2,124.33 153.28,123.25 155.59,123.25 156.23,122.61 156.23,122.13 v1(156.09,121.99)
  BOTTOM w0.089: UC1.B22 117.83,124.92 118.33,125.42 118.33,126.01 v1(118.25,126.09)
  BOTTOM w0.102: v1(156.09,121.99) 156.26,122.16 156.26,122.47 156.51,122.73 157.71,122.73 158.26,122.17 160.32,122.17 CC24.1
PEG_CTX_GRX_C_P0: length 61.2
  IN3 w0.084: v1(119.17,128.23) 119.18,128.23 119.39,128.43 119.85,128.43 121.73,126.55 124.5,126.55 125.19,127.25 130.74,127.25 130.75,127.24
  IN3 w0.127: 130.75,127.24 132.03,127.24 137.18,132.38 147.09,132.38 153.55,125.93 153.55,125.47 v1(153.39,125.31)
  BOTTOM w0.076: v1(119.17,128.23) 118.5,128.23 117.63,127.36 117.63,125.42 117.36,125.15 117.36,124.61 117.6,124.38 UC1.C22
  BOTTOM w0.102: v1(153.39,125.31) 153.56,125.14 153.56,124.79 151.99,123.22 151.99,119.49 154.09,117.39 158.54,117.39 CC19.1
PEG_CTX_GRX_C_P1: length 58.4
  IN3 w0.084: v1(117.95,128.53) 117.95,128.62 118.1,128.77 118.37,128.77 118.44,128.7 118.44,127.3 118.94,126.8 120.53,126.8 121.35,125.97 124.94,125.97 125.39,126.42 135.48,126.42 136.72,125.18 137.92,125.18
  IN3 w0.127: 137.92,125.18 152.43,125.18 153.12,124.48 154.34,124.48 154.46,124.37 154.46,124.26 v1(154.23,124.04)
  BOTTOM w0.089: UC1.A23 117.03,125.42 116.92,125.37 116.83,125.4 116.74,125.49 116.74,125.67 117.26,126.19 117.26,128.22 117.26,128.55 117.49,128.78 117.76,128.78 117.95,128.59 v1(117.95,128.53)
  BOTTOM w0.102: v1(154.23,124.04) 154.5,123.77 154.5,123.67 152.69,121.86 152.69,119.78 153.55,118.91 160.32,118.91 CC21.1
PEG_CTX_GRX_C_P2: length 47.2
  IN3 w0.084: 137.92,123.79 137.89,123.79 137.87,123.77 137.8,123.77 137.78,123.75 136.84,123.75 135.04,125.55 125.74,125.55 125.36,125.17 120.81,125.17 119.54,123.91 118.44,123.91 118.39,123.95 118.39,124.11 118.62,124.34 v1(119.28,124.34)
  IN3 w0.127: 137.92,123.79 151.91,123.79 153.43,122.27 154.66,122.27 154.69,122.3 154.69,122.56 v1(154.56,122.69)
  BOTTOM w0.089: v1(119.28,124.34) 118.71,123.78 UC1.C21
  BOTTOM w0.102: CC23.1 158.54,120.18 156.15,120.18 154.75,121.59 154.75,122.51 v1(154.56,122.69)
PEG_CTX_GRX_C_P3: length 47.6
  IN3 w0.084: v1(118.25,126.73) 118.47,126.51 118.77,126.51 119.6,125.68 125.15,125.68 125.6,126.12 135.39,126.12 136.97,124.54 137.8,124.54 137.83,124.56 137.89,124.56 137.91,124.58 137.92,124.58
  IN3 w0.127: 137.92,124.58 152.3,124.58 153.38,123.51 155.7,123.51 156.48,122.72 156.48,122.19 v1(156.68,121.99)
  BOTTOM w0.089: v1(118.25,126.73) 117.82,126.3 117.82,125.87 118.01,125.68 UC1.A21
  BOTTOM w0.102: v1(156.68,121.99) 156.48,122.19 156.48,122.38 156.6,122.51 157.62,122.51 158.17,121.96 160.32,121.96 CC25.1
PEG_CTX_GRX_N0: length 7.1
  BOTTOM w0.102: UV1.Y37 165.82,119.05 165.45,119.05 165.39,118.99 165.36,118.99 165.18,118.81 164.77,118.81 164.5,118.54 163.86,118.54 163.71,118.39 162.56,118.39 161.78,117.6 160.13,117.6 CC18.2
PEG_CTX_GRX_N1: length 6
  BOTTOM w0.102: CC20.2 161.91,119.13 v2(163.11,119.13) 163.41,119.13 163.87,119.59 164.27,119.59 164.55,119.87 165.36,119.87 165.36,119.87 165.45,119.87 165.58,119.74 165.75,119.74 165.79,119.79 165.79,119.79 165.83,119.82 166.27,119.82 166.38,119.72 166.54,119.72 166.62,119.8 166.62,119.93 UV1.W36
PEG_CTX_GRX_N2: length 6.7
  BOTTOM w0.102: CC22.2 160.13,120.4 v2(161.85,120.4) 164.56,120.4 164.64,120.32 165.14,120.32 165.47,120.65 165.82,120.65 165.82,120.65 UV1.V37
PEG_CTX_GRX_N3: length 6
  BOTTOM w0.102: CC24.2 161.91,122.17 162.29,122.17 163.09,121.37 v2(163.56,121.37) 164.45,121.37 164.51,121.42 165.5,121.42 165.54,121.39 165.56,121.39 165.6,121.35 165.78,121.35 165.85,121.42 166.27,121.42 166.38,121.31 166.53,121.31 166.59,121.37 166.59,121.57 UV1.U36
PEG_CTX_GRX_P0: length 7.1
  BOTTOM w0.102: CC19.2 160.13,117.39 161.87,117.39 162.65,118.17 163.8,118.17 163.95,118.32 164.59,118.32 164.86,118.59 165.27,118.59 165.45,118.77 165.48,118.77 165.54,118.83 165.76,118.83 165.82,118.77 165.82,118.64 165.67,118.49 UV1.AA38
PEG_CTX_GRX_P1: length 6
  BOTTOM w0.102: UV1.Y35 166.86,119.36 166.72,119.5 166.29,119.5 166.18,119.61 165.92,119.61 165.88,119.57 165.88,119.57 165.84,119.53 165.49,119.53 165.36,119.66 165.27,119.66 164.64,119.66 164.36,119.37 163.96,119.37 163.49,118.9 161.89,118.9 CC21.2
PEG_CTX_GRX_P2: length 6.7
  BOTTOM w0.102: UV1.W38 165.83,120.25 165.83,120.34 165.73,120.43 165.56,120.43 165.29,120.16 165.23,120.1 164.55,120.1 164.47,120.18 162.13,120.18 162.11,120.17 161.58,120.17 161.57,120.18 160.13,120.18 CC23.2
PEG_CTX_GRX_P3: length 6
  BOTTOM w0.102: UV1.V35 166.86,120.95 166.71,121.1 166.29,121.1 166.18,121.21 165.94,121.21 165.87,121.13 165.51,121.13 165.47,121.17 165.45,121.17 165.41,121.21 164.6,121.21 164.54,121.15 163.84,121.15 163.83,121.14 163.3,121.14 163.29,121.15 163.01,121.15 162.2,121.96 161.91,121.96 CC25.2
PLT_RST#: length 432.1
  TOP w0.102: UE1.13 187.99,38.3 188.94,39.25 188.94,41.06 v1(190.38,42.49) ; v1(160.11,108.79) 160.08,108.83 157.28,108.83 156.66,108.21 155.77,108.21 v4(153.53,105.96) 152.48,104.91 152.05,104.91 151.41,105.55 151.41,106.44 150.68,107.17 149.42,107.17 148.63,106.39 148.63,104.89 148.34,104.6 147.1,104.6 146.95,104.45 UC3.4 146.95,103.14 R159.1
  IN1 w0.127: v1(129.51,140.98) 125.5,144.98 115.48,144.98 114.07,146.39 105.05,146.39 104.74,146.7 v1(104.74,146.76)
  IN3 w0.127: v1(129.51,140.98) 130.18,140.31 130.18,135.1 131.6,133.68 146.93,133.68 153.76,126.85 156.62,126.85 159.22,124.25 159.22,118 155.47,114.25 155.47,112.87 156.19,112.14 157.5,112.14 159.48,110.17 159.48,109.43 v1(160.11,108.79) ; v1(43.51,86.57) 42.08,86.57 40.61,85.1 40.61,82.81 42.76,80.66 42.76,52.46 52.51,42.72 183.55,42.72 185.09,44.25 187.03,44.25 188.79,42.49 v1(190.38,42.49)
  BOTTOM w0.102: JMINI.22 104.9,146.92 v1(104.74,146.76) 103.98,146 85.63,146 84.8,145.17 84.8,141.56 83.98,140.74 83.98,139.89 83.1,139.01 83.1,138.63 82.64,138.17 82.64,137.62 82.2,137.17 82.2,136.79 81.63,136.22 81.63,134.57 82.2,134 82.86,134 83.52,133.34 83.52,133.34 84.78,133.34 85.3,132.82 85.3,131.58 86.2,130.67 86.2,126.87 84.67,125.35 84.29,125.35 82.93,123.99 77.21,123.99 76.36,123.14 68.1,123.14 66.32,121.36 62.96,121.36 60.75,119.15 60.75,110.1 63.2,107.65 63.2,105.8 ; UV13.2 159.41,109.74 159.6,109.55 159.6,109.3 v1(160.11,108.79) ; 63.2,105.8 59.18,105.8 43.51,90.14 v1(43.51,86.57) 43.05,86.12 41.81,86.12 40.57,84.87 UL1.19 ; 63.2,105.8 63.2,103.29 62.78,102.87 RC51.1
PM_APWROK_R: length 5.2
  TOP w0.089: v1(127.17,113.98) 127.67,113.49 127.87,113.49 128.66,112.7 v4(129.31,112.7) 130.03,112.7 130.39,112.34 RP50.6
  BOTTOM w0.089: v1(127.17,113.98) 127.64,113.51 UC1.AB5
PROC_OPI_RCOMP: length 6.5
  BOTTOM w0.076: UC1.AY15 121.74,102.85 121.74,101.64 122.2,101.18 122.2,100.99 122.37,100.82 122.37,100.69
  BOTTOM w0.305: RC134.1 123.35,97.15 v3(122.52,97.98) 122.37,98.13 122.37,100.69
PROJECT_ID: length 8.6
  TOP w0.089: v3(132.74,120.59) v1(132.74,120.09) 133.51,119.33 RC112.2 RC113.1
  IN1 w0.084: v1(127.85,118.76) 128.3,119.2 130.84,119.2 131.73,120.09 v1(132.74,120.09)
  BOTTOM w0.089: UC1.L5 127.64,118.97 v1(127.85,118.76)
PS_0: length 14.3
  TOP w0.102: v1(165.66,109.39) v3(164.58,109.39) 163.55,109.39 163.14,109.8 162.33,109.8 161.19,110.94 157.42,110.94 156.87,110.39 RV243.2 CV335.1 RV201.1
  BOTTOM w0.102: UV1.AM34 167.49,109.49 166.99,110 166.74,110 166.36,109.62 166.36,109.56 166.14,109.34 165.71,109.34 v1(165.66,109.39)
PS_1: length 28.8
  TOP w0.102: RV238.1 CV329.1 RV237.2 165.91,98.54 165.91,100.08 166.36,100.52 v3(167.02,100.52) v1(167.67,100.52)
  IN3 w0.102: v1(169.7,115.13) 169.7,114.94 168.78,114.02 166.69,114.02
  IN3 w0.127: 166.69,114.02 165.69,113.03 164.44,113.03 163.63,112.22 163.63,110.4 162.52,109.29 162.52,108.5 168.24,102.78 168.24,101.1 v1(167.67,100.52)
  BOTTOM w0.102: UV1.AD31 170.06,115.49 v1(169.7,115.13)
PS_2: length 16
  TOP w0.102: RV239.2 RV240.1 160.05,110.19 160.37,110.51 CV331.1 161.05,110.51 162.13,109.43 v3(162.4,109.43) 163.19,109.43 163.84,108.78 165.7,108.78 166.07,109.15 166.07,110.7 168.41,113.05 169.68,113.05 v1(170.06,112.67)
  BOTTOM w0.102: UV1.AG31 170.06,113.29 v1(170.06,112.67)
PS_3: length 16.1
  TOP w0.102: RV242.1 CV333.1 159.59,111.45 160.63,111.45 RV241.2 161.61,111.62 v1(162.22,111.01) 162.22,110.83 162.71,110.34 163.2,110.34 v3(163.4,110.54)
  IN3 w0.102: 164.11,114.12 165.11,114.12 166.79,115.8 168.15,115.8 v1(168.83,115.12)
  IN3 w0.127: 164.11,114.12 164.07,114.12 162.22,112.28 v1(162.22,111.01)
  BOTTOM w0.102: UV1.AD33 168.46,115.49 v1(168.83,115.12)
PS_ID: length 178.4
  TOP w0.102: UE1.16 189.19,36.68 189.07,36.8 189.07,37.15 v1(189.46,37.55) ; v1(132.35,184.62) 132.35,184.38 v3(132.68,184.05)
  TOP w0.254: v1(132.35,184.62) PR3.1 PR4.2
  IN2 w0.254: v1(132.35,184.62) 132.35,180.3 133.19,179.46 133.19,168.16 132.71,167.68 132.71,146.64 139.86,139.49 139.86,138.28 149.23,128.91 149.23,121.46 153.17,117.52 153.17,112.97 155.25,110.89 155.25,108.06 159.14,104.16 160.03,104.16 161.63,102.56 162.29,102.56 163.44,101.41 163.44,100.46 170.41,93.48 171.87,93.48 183.54,81.81 183.54,80.79 189.51,74.82 189.51,54.24 190.31,53.44 190.31,49.13 189.29,48.11 189.29,37.73 v1(189.46,37.55)
PSID: length 0.6
  TOP w0.102: v1(137.43,179.59) v3(138.07,179.59)
PSID-1: length 5.5
  TOP w0.102: PR6.1 132.5,181.88 v3(132.28,181.66)
  TOP w0.254: v1(133.38,183.46) 133.38,182.71 PR9.2 PR6.1
  BOTTOM w0.254: v1(133.38,183.46) 133.38,184.29 134.54,185.45 PQ5.2
PSID-2: length 4.9
  TOP w0.102: v3(131.55,188.08) 132.09,187.54 v1(132.48,187.54)
  TOP w0.254: PR8.2 132.55,187.46 v1(132.48,187.54)
  BOTTOM w0.254: PQ5.1 132.64,187.37 v1(132.48,187.54) PQ6.2
PSID-3: length 3.4
  TOP w0.102: PR4.1 130.57,186.67 v3(130.49,186.74)
  TOP w0.254: PR4.1 130.57,185.06 v1(131.03,184.61)
  BOTTOM w0.254: v1(131.03,184.61) 131.03,185.58 PQ6.3
PWM1: length 48.9
  TOP w0.102: v1(115.41,138.95) v3(116.12,138.95)
  IN1 w0.254: v1(115.41,138.95) 115.41,144.6 113.95,146.06 88.55,146.06 85.14,142.66 85.14,140.02 84.42,139.3 83.69,139.3 83.43,139.04 83.43,138.42 83.91,137.93 v1(86.13,137.93)
  BOTTOM w0.203: v1(115.41,138.95) 115.41,139.52 115.29,139.63 PU502.8 ; PU501.6 86.22,138.02 v1(86.13,137.93)
PWR_PWM_LED#: length 190.2
  TOP w0.102: RD14.1 34.65,14.93 v3(35.74,16.03) v1(38.45,18.73) ; UE1.92 184.79,52.28 v1(185.18,52.68)
  IN1 w0.127: v1(38.45,18.73) 40.06,20.34 46.6,20.34 52.57,26.31 87.7,26.31 105.85,44.46 133.04,44.46 136.72,40.78 160.52,40.78 167.22,34.07 182.35,34.07 v1(182.81,34.53)
  IN2 w0.127: v1(185.18,52.68) 185.07,52.57 185.07,49.16 182.15,46.24 182.15,35.19 v1(182.81,34.53)
PWR_SRC_ON: length 4.1
  TOP w0.102: QX2.3 221.19,177.44 221.05,177.58 220.26,177.58 CX4.2 RX2.2 RX3.1
PXS_PWREN: length 454.3
  TOP w0.089: RP54.4 132.86,115.63 v1(133.38,116.15)
  TOP w0.102: v3(191.27,174.25) 190.28,174.25 v1(189.89,173.87)
  TOP w0.254: v1(211.99,95.01) 213.64,93.36 PR601.2 ; PR1103.1 v1(189.89,173.87)
  IN1 w0.127: v1(156.3,153.87) 156.3,153.43 159.65,150.08 159.65,137.19 156.18,133.72 156.18,128.94 154.84,127.61 154.84,125.14 155.96,124.03 156.87,124.03 v1(157.45,123.45) ; v1(174.82,93.17) 175.14,93.49 189.59,93.49 190.7,92.39 196.3,92.39 201.3,97.39 209.6,97.39 v1(211.99,95.01)
  IN2 w0.254: v1(190.59,164.35) 193.76,164.35 198.82,159.29 208.87,159.29 222.73,145.43 222.73,125.37 221.33,123.96 221.33,104.85 214.72,98.25 214.72,96.61 213.12,95.01 v1(211.99,95.01)
  IN3 w0.084: 137.82,115.96 137.57,115.71 133.82,115.71 v1(133.38,116.15)
  IN3 w0.127: v1(175.92,90.18) 175.92,93.36 172.83,96.45 168.78,96.45 165.95,99.28 165.95,102.99 163.26,105.67 162.04,105.67 160.68,107.03 160.68,107.18 159.67,108.19 159.67,108.87 159.22,109.32 159.22,110.06 157.39,111.88 156.09,111.88 155.21,112.76 155.21,114.36 158.95,118.11 158.95,121.95 v1(157.45,123.45) ; 137.82,115.96 138.08,116.22 139.28,116.22 139.98,115.52 143.96,115.52 144.26,115.81 146.72,115.81 147.29,116.38 151.63,116.38 153.32,114.69 154.21,114.69 154.33,114.56 154.33,113.27 155.98,111.63 157.29,111.63 158.96,109.95 158.96,109.22 159.41,108.76 159.41,108.09 160.43,107.08 160.43,106.42 164.6,102.25 164.94,101.91 164.94,99.97 168.71,96.2 172.76,96.2 174.82,94.14 v1(174.82,93.17)
  IN3 w0.254: v1(211.99,95.01) 212.68,94.32 212.68,91.49 215.12,89.05 216.61,89.05 218.26,87.41 218.26,86.44 216.88,85.06 216.88,77.78 219.38,75.27 219.38,62.34 218.74,61.7 218.74,58.13 216.31,55.7 v1(210.53,55.7) ; v1(190.59,164.35) 190.97,164.73 190.97,172.79 v1(189.89,173.87) 185.77,178 v1(185.77,187.72)
  BOTTOM w0.076: 131.72,117.3 131.66,117.23 130.39,117.23 130.3,117.13 129.16,117.13 129.04,117.26 128.62,117.26 UC1.P4
  BOTTOM w0.089: 131.72,117.3 131.78,117.36 133.59,117.36 133.95,116.99 133.95,116.47 133.63,116.15 v1(133.38,116.15)
  BOTTOM w0.102: QV25.2 174.82,89.08 v1(175.92,90.18) 176.83,89.27 QV24.2 ; v1(190.59,164.35) 190.68,164.26 190.68,159.79 190.17,159.28 176.18,159.28 176.05,159.41 RV105.2 175.41,159.41 174.9,159.92 160.95,159.92 156.3,155.27 v1(156.3,153.87)
  BOTTOM w0.254: PR1300.1 199.06,65.99 199.48,65.57 199.48,64.59 196.82,61.92 196.82,60.87 196.69,60.75 196.69,59.8 197.26,59.23 197.26,53.09 200.56,49.79 201.43,49.79 201.49,49.73 205.78,49.73 205.98,49.94 205.98,51.52 206.27,51.8 209.11,51.8 210.53,53.22 v1(210.53,55.7) 210.21,56.02 PR803.1 ; PR1206.2 v1(185.77,187.72)
PXS_PWREN#: length 3.7
  BOTTOM w0.102: QV25.1 174.36,92.45 RV109.2 v3(174.22,93.73)
RASA0#: length 33.7
  TOP w0.102: UV5.L3 167.09,151.25 v1(167.48,151.64)
  IN3 w0.102: 175.4,135.39 175.4,135.31 175.59,135.12 175.59,131.66 175.83,131.42 175.83,130.65 176.43,130.05 176.43,127.58 v1(176.05,127.2) ; 175.36,141.35 175.49,141.48 175.49,146.62 174.15,147.97 169.32,147.97 168.37,148.92 168.37,149.32 167.87,149.83 167.87,151.26 v1(167.48,151.64)
  IN3 w0.157: 175.4,135.39 175.4,138.12 174.61,138.91 174.61,140.6 175.36,141.35
  BOTTOM w0.102: v1(176.05,127.2) 176.34,127.49 UV1.K23 ; v1(167.48,151.64) 167.09,151.25 UV5.L3
RASA1#: length 32.2
  TOP w0.102: v1(187.23,149.93) 187.23,150.65 187.6,151.01 UV3.L3
  IN3 w0.102: 182.13,148.26 182.34,148.47 184.29,148.47 185.32,149.5 186.8,149.5 v1(187.23,149.93) ; v1(179.69,127.86) 179.25,128.29 179.25,133.29 179.39,133.42 179.39,134.24 179.78,134.63 180.91,134.63 181.32,135.04 181.32,135.39
  IN3 w0.157: 182.13,148.26 180.82,146.96 180.82,136.54 181.32,136.04 181.32,135.39
  BOTTOM w0.102: v1(187.23,149.93) 187.23,150.65 187.6,151.01 UV3.L3 ; v1(179.69,127.86) 180.05,127.49 UV1.K19
RASB0#: length 36.7
  TOP w0.102: UV7.L3 213.56,134.7 v1(213.95,134.31)
  IN3 w0.102: 203.66,126.39 203.75,126.3 208.93,126.3 210.28,127.65 210.28,132.47 211.23,133.42 211.64,133.42 212.14,133.92 213.57,133.92 v1(213.95,134.31) ; v1(187.49,122.25) 187.49,122.51 187.93,122.95 187.93,123.49 188.62,124.18 189.51,124.18 189.98,124.65 191.42,124.65 192.39,125.61 194.39,125.61
  IN3 w0.157: 203.66,126.39 201.3,126.39 200.52,125.61 194.39,125.61
  BOTTOM w0.102: v1(187.49,122.25) 187.49,122.66 UV1.T10 ; UV7.L3 213.56,134.7 v1(213.95,134.31)
RASB1#: length 34.7
  TOP w0.102: UV9.L3 213.37,114.3 v1(213.76,113.91)
  IN3 w0.102: 194.39,120.81 194.35,120.81 194.12,120.57 193.25,120.57 193.23,120.6 193.23,120.6 193.06,120.76 191.55,120.76 191.34,120.56 188.36,120.56 v1(187.7,119.89) ; 211.94,119.78 212.56,119.15 212.56,115.11 v1(213.76,113.91)
  IN3 w0.157: 194.39,120.81 201.29,120.81 202.45,121.97 209.75,121.97 211.94,119.78
  BOTTOM w0.102: UV1.Y10 187.26,119.46 v1(187.7,119.89) ; v1(213.76,113.91) 213.37,114.3 UV9.L3
REGN: length 16.6
  TOP w0.102: v1(169.07,164.29) 169.12,164.29 v3(169.69,163.72)
  TOP w0.254: PR713.1 170.65,171.65 v1(170.27,171.27) ; v1(169.07,164.29) PR707.1
  IN1 w0.254: v1(169.07,164.29) 167.99,164.29 166.34,165.94 166.34,169.87 v1(165.45,170.76)
  IN3 w0.254: v1(170.27,171.27) 169.57,170.57 165.64,170.57 v1(165.45,170.76)
RF_+1.2VSP: length 3.3
  TOP w0.102: v1(189.13,173.45) v3(189.13,174.67)
  TOP w0.254: PU1100.5 188.73,173.29 188.9,173.45 v1(189.13,173.45)
  BOTTOM w0.254: v1(189.13,173.45) 188.78,173.81 PR1105.1
RING2: length 12.1
  TOP w0.102: v3(18.1,22.94) 17.9,22.74 v1(17.5,22.74)
  IN3 w1.016: 17.3,23.51 18.06,23.51 18.32,23.76 22.93,23.76 23.37,24.2 24.69,24.2 26.45,25.96 27.67,25.96
  vias: v1(16.92,22.74) v1(27.97,25.16) v1(27.97,24.5)
RING2_R: length 21.8
  TOP w0.102: 18.14,16.55 19.17,16.55 v3(19.27,16.44)
  IN3 w1.016: JHP.3 4.01,8.09 5.49,6.61 15.14,6.61 17.43,8.9 17.43,14.51 17.42,14.53
  vias: v1(17.17,15.39) v1(17.76,15.39)
RREF: length 4.6
  TOP w0.102: RR1.1 174.17,18.07 v3(174.07,18.17)
  TOP w0.305: RR1.1 175,19.19 175.82,20.01 UR1.1
RSVD_AL1: length 3.5
  BOTTOM w0.076: 132.3,108.15 131.85,108.6 UC1.AL1
  BOTTOM w0.089: T136.1 132.3,108.15
RSVD_AM11: length 1.4
  TOP w0.089: v1(123.66,107.48) 124.03,107.12 T137.1
  BOTTOM w0.076: UC1.AM11 123.73,107.48 v1(123.66,107.48)
RSVD_AP7: length 15
  TOP w0.089: 133.1,101.44 132.49,102.06 129.98,102.06 127.41,104.63 127.41,104.98 127.09,105.29 126.71,105.29 126.39,105.61 126.39,106.03 v1(125.59,106.83)
  TOP w0.102: 133.1,101.44 134.75,99.79 T139.1
  BOTTOM w0.089: UC1.AP7 v1(125.59,106.83)
RSVD_AT2: length 6.1
  BOTTOM w0.076: T128.1 134.69,105.33 131.21,105.33 130.65,105.89 129.91,105.89 129.63,105.61 UC1.AT2
RSVD_AU10: length 10.3
  TOP w0.089: T141.1 124.97,98.88 122.88,100.97 122.88,104.45 123.41,104.98 124.55,104.98 v1(125,104.53)
  BOTTOM w0.076: v1(125,104.53) 124.64,104.88 UC1.AU10
RSVD_AU15: length 6
  TOP w0.089: T142.1 123.09,101.92 123.09,104.11 v1(123.53,104.55)
  BOTTOM w0.076: UC1.AU15 121.68,104.88 122,105.2 123.33,105.2 123.53,105 v1(123.53,104.55)
RSVD_AU44: length 5.1
  BOTTOM w0.076: UC1.AU44 102.94,104.74 102.94,104.67 102.67,104.41 102.67,99.93 T132.1
RSVD_AV44: length 3.8
  BOTTOM w0.076: T134.1 103.23,101.2 102.84,101.59 102.84,103.94 UC1.AV44
RSVD_AW14: length 5.7
  BOTTOM w0.076: 122.36,101.66 122.11,101.9 122.11,103.29 UC1.AW14
  BOTTOM w0.089: 122.36,101.66 122.97,101.05 122.92,101.1 123.05,100.97 123.05,100.52 124.46,99.11 T144.1
RSVD_AY14: length 2.8
  BOTTOM w0.089: T145.1 123.6,100.91 122.61,101.9 122.61,102.39 122.41,102.59 UC1.AY14
RSVD_D15: length 1.6
  TOP w0.089: T135.1 v1(121.85,124.33)
  BOTTOM w0.076: v1(121.85,124.33) UC1.D15
RSVD_F22: length 1.3
  TOP w0.089: T138.1 118.08,122.4 v1(118.19,122.28)
  BOTTOM w0.089: UC1.F22 117.97,122.5 v1(118.19,122.28)
RSVD_H22: length 1.5
  TOP w0.089: v1(118.19,121.06) 117.64,121.61 T140.1
  BOTTOM w0.089: UC1.H22 118.11,120.98 v1(118.19,121.06)
RSVD_J21: length 1.6
  TOP w0.089: v1(118.09,119.72) 118.48,119.33 T143.1
  BOTTOM w0.076: UC1.J21 118.18,119.82 v1(118.09,119.72)
RSVD_N23: length 2.1
  TOP w0.089: T129.1 116.4,118.8 v1(116.14,118.54)
  BOTTOM w0.076: UC1.N23 116.55,118.14 v1(116.14,118.54)
RSVD_R23: length 1.8
  TOP w0.089: T130.1 115.67,117.73 v1(116.14,117.73)
  BOTTOM w0.076: UC1.R23 116.55,117.32 v1(116.14,117.73)
RSVD_T23: length 2
  TOP w0.089: T131.1 116.14,116.51 v1(116.14,116.92)
  BOTTOM w0.076: v1(116.14,116.92) 116.55,116.51 UC1.T23
RSVD_U10: length 2.6
  TOP w0.089: v1(123.84,116.82) 124.1,117.08 T133.1
  BOTTOM w0.089: v1(123.84,116.82) 123.78,116.76 123.78,116.12 123.97,115.93 124.47,115.93 124.8,116.26 UC1.U10
RTC_VOUT: length 4.8
  TOP w0.102: v3(67.38,44.7) RG2.2 69.56,44.7 CG6.1 69.8,44.32 71.03,43.09 UG1.14
RUNPWROK: length 229.9
  TOP w0.203: UE1.36 196.31,38.51 196.18,38.63 195.72,38.63 195.37,38.28 v1(195.37,38.11)
  TOP w0.254: v1(66.69,106.74) 66.69,104.48 67.1,104.07 68.14,104.07 68.42,104.35 v1(68.42,104.56)
  IN1 w0.254: v1(68.42,104.56) 72,104.56 72.34,104.9 v1(72.94,104.9) ; v1(192.5,59.71) 192.5,57.99 194.88,55.61 194.88,54.41 195.72,53.57 195.72,52.92 196.73,51.91 196.73,45.77 195.89,44.94 195.89,38.77 195.37,38.24 v1(195.37,38.11) ; v1(66.69,106.74) 70.31,106.74 v1(70.96,107.39)
  IN3 w0.254: v1(66.69,106.74) 66.57,106.62 66.57,106.11 64.95,104.49 64.95,102.85 65.56,102.24 65.56,100.59 66.58,99.58 66.58,96.47 65.92,95.81 65.92,91.81 65,90.89 65,88.74 65.68,88.06 65.68,78.36 70.45,73.59 70.45,72.34 72.82,69.97 72.82,55.49 75.4,52.91 103.92,52.91 105.14,54.12 113.73,54.12 114.52,54.91 116.26,54.91 117.77,53.41 174.74,53.41 176.47,55.14 176.47,55.35 177.82,56.7 180.24,56.7 186.13,62.6 189.61,62.6 v1(192.5,59.71)
  BOTTOM w0.254: UC4.1 71.1,107.24 v1(70.96,107.39) ; UC4.13 68.93,106.06 68.24,106.74 v3(67.55,106.74) v1(66.69,106.74) ; v1(72.94,104.9) 72.86,104.9 72.7,105.06 UC4.4 ; UC4.10 v1(68.42,104.56)
SATA_ACT#: length 195.9
  TOP w0.102: RD15.1 v3(43.98,34.52) 43.98,44 35.02,52.97 v1(35.02,71.26)
  IN2 w0.089: v1(132.87,116.77) 132.87,116 133.37,115.49 133.37,114.72 132.8,114.15 130.48,114.15 130.05,113.72 130.05,111.4 129.92,111.26 129.92,102.66 130.33,102.25 130.33,100.59 129.95,100.21 128.3,100.21 124.68,96.59 124.01,96.59 121.03,93.61
  IN2 w0.127: 121.03,93.61 112.71,85.29 58.26,85.29 44.79,71.83 35.59,71.83 v1(35.02,71.26)
  BOTTOM w0.076: UC1.U3 129.23,115.8 129.75,115.8 129.99,116.04 129.99,116.21 130.16,116.38 130.4,116.38 130.53,116.26 131.18,116.26 132.04,117.12 132.52,117.12 v1(132.87,116.77)
SATA_IREF: length 5.4
  BOTTOM w0.254: UC1.A12 123.16,126.75
  BOTTOM w0.305: RC126.1 123.35,129.62 122.91,129.19 v3(122.91,127.56) 122.91,127 123.16,126.75
SATA_PRX_DTX_N0: length 5.3
  TOP w0.102: CS109.1 224.72,40.48 225.45,40.48 225.77,40.8 225.77,41.06 225.78,41.08 225.78,41.61 225.77,41.62 225.77,42.76 225.95,42.94 226.76,42.94 JHDD.5
SATA_PRX_DTX_N0_C: length 147.5
  TOP w0.102: v1(218.91,40.29) 219.11,40.48 223.14,40.48 CS109.2
  IN1 w0.084: v1(127.19,120.04) 127.5,120.34 131.57,120.34 131.94,120.72 134.7,120.72 135.52,121.53 137.88,121.53 137.92,121.49
  IN1 w0.127: v1(218.91,40.29) 218.76,40.44 218.04,40.44 216.75,41.73 205.48,41.73 202.77,44.44 202.77,47.51 195.58,54.7 195.58,55.9 193.43,58.04 193.43,61.61 192.62,62.41 192.62,65.49 191.57,66.55 191.57,77.21 184.61,84.16 179.47,84.16 174.43,89.2 170.06,89.2 156.11,103.14 156.11,105.87 154.79,107.2 154.79,109.55 151.07,113.27 151.07,114.16 143.74,121.49 137.92,121.49
  BOTTOM w0.076: v1(127.19,120.04) 127.27,120.04 127.57,120.34 UC1.J5
SATA_PRX_DTX_N1: length 4.8
  BOTTOM w0.102: CS14.1 222.98,103.83 223.34,103.83 223.36,103.82 223.89,103.82 223.9,103.83 226.52,103.83 JODD.5
SATA_PRX_DTX_N1_C: length 124.2
  IN1 w0.084: 137.92,123.66 132.42,123.66 131.82,124.26 128.09,124.26 127.59,123.76 126.79,123.76 125.94,122.91 125.94,121.52 125.82,121.4 125.82,121.11 v1(125.37,120.66)
  IN1 w0.127: v1(220.69,102.7) 220.49,102.5 220.49,102.22 219.29,101.02 218.91,101.02 215.63,97.74 214.49,97.74 213.96,97.21 213.96,95.72 208.51,90.27 185.63,90.27 185.41,90.05 182.57,90.05 182.14,90.48 177.95,90.48 177.16,91.27 170.49,91.27 162.47,99.29 162.47,100.51 159.59,103.4 159.59,104.61 157.05,107.15 157.05,108.11 156.6,108.56 156.6,110.02 152.86,113.77 152.86,114.63 143.82,123.66 137.92,123.66
  BOTTOM w0.089: v1(125.37,120.66) 125.69,120.34 UC1.J8
  BOTTOM w0.102: v1(220.69,102.7) 220.56,102.82 220.56,103.26 221.07,103.77 221.46,103.77 CS14.2
SATA_PRX_DTX_P0: length 5.4
  TOP w0.102: JHDD.6 226.63,43.15 225.86,43.15 225.56,42.85 v2(225.56,41.34) 225.56,40.89 225.36,40.69 224.72,40.69 CS108.1
SATA_PRX_DTX_P0_C: length 147.4
  TOP w0.102: v1(218.91,40.87) 219.09,40.69 223.14,40.69 CS108.2
  IN1 w0.084: v1(127.22,120.69) 127.33,120.57 131.47,120.57 131.84,120.94 134.61,120.94 135.42,121.76 137.92,121.76
  IN1 w0.127: v1(218.91,40.87) 218.76,40.71 218.15,40.71 216.86,42 205.59,42 203.04,44.56 203.04,47.62 195.85,54.81 195.85,56.01 193.7,58.15 193.7,61.72 192.9,62.53 192.9,65.6 191.84,66.66 191.84,77.32 184.72,84.44 179.58,84.44 174.54,89.47 170.17,89.47 156.38,103.26 156.38,105.98 155.06,107.31 155.06,109.66 151.34,113.38 151.34,114.27 143.85,121.76 137.92,121.76
  BOTTOM w0.076: UC1.H5 127.59,120.99 127.28,120.69 v1(127.22,120.69)
SATA_PRX_DTX_P1: length 4.8
  BOTTOM w0.102: JODD.6 226.53,104.05 v2(223.62,104.05) 222.98,104.05 CS15.1
SATA_PRX_DTX_P1_C: length 123.9
  IN1 w0.084: 137.92,123.93 137.91,123.93 137.89,123.91 137.82,123.91 137.8,123.89 132.51,123.89 131.91,124.49 127.99,124.49 127.5,123.99 126.7,123.99 125.74,123.03 125.74,121.64 125.42,121.32 v1(125.37,121.32)
  IN1 w0.127: 137.92,123.93 143.94,123.93 153.13,114.74 153.13,113.88 156.87,110.13 156.87,108.67 157.32,108.23 157.32,107.27 159.87,104.72 159.87,103.51 162.75,100.63 162.75,99.4 170.61,91.54 177.28,91.54 178.06,90.75 182.25,90.75 182.68,90.32 185.29,90.32 185.51,90.54 208.4,90.54 213.69,95.83 213.69,97.32 214.38,98.01 215.51,98.01 218.8,101.29 219.18,101.29 220.22,102.33 220.22,102.58 v1(220.1,102.7)
  BOTTOM w0.089: UC1.H8 125.7,120.99 v1(125.37,121.32)
  BOTTOM w0.102: v1(220.1,102.7) 220.35,102.95 220.35,103.35 220.98,103.99 221.33,103.99 CS15.2
SATA_PTX_DRX_N0: length 3.4
  TOP w0.102: CS106.1 224.72,38.92 224.85,38.92 225.34,39.41 v2(225.58,39.41) 226.69,39.41 JHDD.3
SATA_PTX_DRX_N0_C: length 169.9
  TOP w0.102: v1(221.71,39.15) 221.94,38.92 223.14,38.92 CS106.2
  IN1 w0.084: v1(121.72,127.56) 121.52,127.75 120.32,127.75 119.31,126.74 119.31,125.56 119.87,125.01 124.61,125.01 124.97,124.65 124.97,120.45 125.17,120.25 125.85,120.25 127.25,121.65 133.63,121.65 134.89,122.91 137.89,122.91 137.91,122.94 137.92,122.94
  IN1 w0.127: v1(221.71,39.15) 221.59,39.03 221.14,39.03 220.44,39.73 220.44,41.39 219,42.83 207.6,42.83 203.82,46.61 203.82,48.19 197.16,54.85 197.16,56.63 194.52,59.27 194.52,62.46 193.68,63.29 193.68,65.93 192.65,66.97 192.65,79.03 186.47,85.21 179.9,85.21 174.87,90.25 170.58,90.25 157.16,103.67 157.16,106.31 155.86,107.61 155.86,110.03 152.16,113.73 152.16,114.56 143.78,122.94 137.92,122.94
  BOTTOM w0.076: UC1.B15 121.1,124.92 121.63,125.44 121.63,125.68 121.52,125.79 121.52,126.02 121.31,126.22 121.31,127.74 121.42,127.85 121.62,127.85 121.72,127.75 v1(121.72,127.56)
SATA_PTX_DRX_N1: length 5.1
  BOTTOM w0.102: CS9.1 222.98,100.91 v2(223.61,100.91) 224.92,100.91 225.62,100.22 226.51,100.22 JODD.3
SATA_PTX_DRX_N1_C: length 127.6
  IN1 w0.084: v1(120.36,126.19) 120.17,126 120.17,125.77 120.26,125.68 134.36,125.68 135.28,124.76 137.81,124.76 137.83,124.78 137.89,124.78 137.91,124.8 137.92,124.8
  IN1 w0.127: v1(210,94.12) 210.23,93.9 210.23,93.56 208.05,91.39 190.53,91.39 189.84,92.07 182.94,92.07 182.4,91.53 179.04,91.53 178.25,92.32 170.93,92.32 163.66,99.59 163.66,100.85 160.65,103.86 160.65,105.4 158.4,107.64 158.4,110.66 154.19,114.88 154.19,116.55 145.94,124.8 137.92,124.8
  BOTTOM w0.089: UC1.A17 120.5,125.41 120.38,125.37 120.3,125.41 120.2,125.51 120.2,126.03 v1(120.36,126.19)
  BOTTOM w0.102: v1(210,94.12) 210.32,94.43 210.32,94.84 211.33,95.86 212.27,95.86 217.23,100.82 221.6,100.82 221.73,100.95 CS9.2
SATA_PTX_DRX_P0: length 3.4
  TOP w0.102: CS105.1 224.72,38.7 224.94,38.7 225.42,39.18 225.87,39.18 225.89,39.19 226.69,39.19 JHDD.2
SATA_PTX_DRX_P0_C: length 169.6
  TOP w0.102: CS105.2 223.14,38.7 221.85,38.7 v1(221.71,38.56)
  IN1 w0.084: v1(121.72,128.21) 121.43,127.92 120.25,127.92 119.14,126.82 119.14,125.49 119.79,124.84 124.54,124.84 124.8,124.58 124.8,120.38 125.1,120.08 126.01,120.08 127.35,121.42 133.72,121.42 134.99,122.68 137.89,122.68 137.91,122.66 137.92,122.66
  IN1 w0.127: v1(221.71,38.56) 221.51,38.76 221.03,38.76 220.17,39.62 220.17,41.28 218.89,42.56 207.48,42.56 203.55,46.49 203.55,48.08 196.88,54.74 196.88,56.52 194.24,59.16 194.24,62.34 193.41,63.18 193.41,65.82 192.38,66.86 192.38,78.92 186.36,84.94 179.79,84.94 174.75,89.98 170.47,89.98 156.89,103.56 156.89,106.19 155.59,107.5 155.59,109.92 151.88,113.62 151.88,114.45 143.67,122.66 137.92,122.66
  BOTTOM w0.076: v1(121.72,128.21) 121.55,128.04 121.34,128.04 121.12,127.82 121.12,126.14 121.32,125.94 121.32,125.71 121.33,125.7 UC1.A15
SATA_PTX_DRX_P1: length 5.1
  BOTTOM w0.102: JODD.2 226.54,100 225.53,100 224.83,100.7 223.89,100.7 223.87,100.69 223.34,100.69 223.33,100.7 222.98,100.7 CS8.1
SATA_PTX_DRX_P1_C: length 127.6
  IN1 w0.084: v1(119.78,126.06) 119.94,125.9 119.94,125.67 120.17,125.45 134.26,125.45 135.18,124.53 137.92,124.53
  IN1 w0.127: v1(210.59,94.12) 210.5,94.03 210.5,93.45 208.17,91.12 190.42,91.12 189.73,91.8 183.05,91.8 182.51,91.26 178.93,91.26 178.14,92.05 170.82,92.05 163.38,99.48 163.38,100.74 160.37,103.75 160.37,105.29 158.13,107.53 158.13,110.55 153.91,114.77 153.91,116.44 145.83,124.53 137.92,124.53
  BOTTOM w0.089: UC1.B17 120.32,125.07 120.28,125.19 120.2,125.24 120.18,125.25 119.98,125.45 119.98,125.86 v1(119.78,126.06)
  BOTTOM w0.102: CS8.2 221.49,100.6 217.32,100.6 212.36,95.64 211.42,95.64 210.53,94.75 210.53,94.17 v1(210.59,94.12)
SATA_RCOMP: length 6.8
  BOTTOM w0.203: 123.56,126.59 123.56,125.42 123.18,125.05 123.18,124.39 UC1.C12
  BOTTOM w0.305: 124.43,129.36 RC131.1 ; 124.43,129.36 v3(124.43,129.35) ; 124.43,129.36 123.56,128.49 123.56,126.59
SD_CD#: length 21
  TOP w0.102: UR1.13 178.32,26.36 179.09,27.13 CR9.1 179.58,26.42 v1(179.4,26.24) 179.58,26.06 v3(180.28,26.06)
  BOTTOM w0.102: JREAD.20 171.72,28.86 172.05,28.52 172.05,25.59 172.18,25.46 172.37,25.46 172.49,25.59 172.49,26.52 172.62,26.64 172.8,26.64 172.93,26.52 172.93,25.59 173.05,25.46 173.26,25.46 173.38,25.59 173.38,26.5 173.51,26.63 173.66,26.63 173.79,26.5 173.79,25.59 173.92,25.46 179.27,25.46 179.4,25.59 v1(179.4,26.24)
SD_CMD: length 26
  TOP w0.102: UR1.18 175.82,26.33 CR11.1 175.77,27.59 176.16,27.59 176.42,27.86 176.42,28.72 177.09,29.39 179.53,29.39 181.67,27.25 184.08,27.25 184.19,27.35 184.19,28.1 184.29,28.2 184.49,28.2 184.59,28.1 184.59,27.35 184.69,27.25 184.9,27.25 185,27.35 v3(185,27.89) 185,28.73 185.12,28.85 185.29,28.85 185.4,28.73 185.4,27.35 185.51,27.25 185.71,27.25 185.81,27.35 185.81,28.72 185.93,28.84 186.1,28.84 186.22,28.72 186.22,27.35 186.32,27.25 v1(186.78,27.25)
  BOTTOM w0.102: v1(186.78,27.25) 186.92,27.38 JREAD.6
SD_D0: length 24.2
  TOP w0.102: v1(180.66,23.84) 180.22,24.28 179.76,24.28 179.67,24.19 UR1.11
  BOTTOM w0.102: JREAD.18 174.76,27.23 174.88,27.1 176.4,27.1 176.53,27.23 176.53,28.34 176.65,28.47 176.89,28.47 177.02,28.34 177.02,26.97 177.14,26.85 177.44,26.85 177.56,26.97 177.56,28.4 177.69,28.52 178.03,28.52 178.16,28.4 178.16,26.05 178.29,25.92 178.64,25.92 178.76,26.05 178.76,27.44 178.89,27.57 179.91,27.57 180.03,27.44 180.03,26.46 180.13,26.36 180.56,26.36 180.66,26.26 180.66,26.06 180.56,25.96 180.13,25.96 180.03,25.86 180.03,25.65 180.13,25.55 180.56,25.55 180.66,25.45 180.66,25.25 180.56,25.14 180.13,25.14 180.03,25.04 180.03,24.84 180.13,24.74 180.56,24.74 180.64,24.66 180.64,23.86 v1(180.66,23.84)
SD_D1: length 24.7
  TOP w0.102: UR1.10 179.87,23.69 v1(180.05,23.87)
  BOTTOM w0.102: v1(180.05,23.87) 179.8,24.12 179.8,27.21 179.68,27.34 179.12,27.34 178.99,27.21 178.99,25.82 178.86,25.69 176.36,25.69 176.23,25.82 176.23,26.74 176.1,26.87 175.82,26.87 175.7,26.74 175.7,25.82 175.57,25.69 175.31,25.69 175.19,25.82 175.19,26.74 175.06,26.87 174.82,26.87 174.69,26.74 174.69,25.82 174.56,25.69 174.34,25.69 174.21,25.82 174.21,27.67 174.11,27.77 173.91,27.77 173.8,27.67 173.8,27 173.68,26.87 173.53,26.87 173.4,27 173.4,27.67 173.3,27.77 173.09,27.77 172.99,27.67 172.99,27 172.87,26.87 172.6,26.87 172.48,27 JREAD.19
SD_D2: length 26.1
  TOP w0.102: UR1.21 174.53,23.69 173.73,24.49 173.73,27.71 176.57,30.55 v3(176.85,30.55) 178.27,30.55 v1(178.94,31.22)
  BOTTOM w0.102: v1(178.94,31.22) 179.7,31.98 190.88,31.98 191.48,31.39 JREAD.1
SERIRQ: length 138.2
  TOP w0.102: v1(193.22,43.85) 193.03,43.66 189.35,43.66 188.25,42.56 184.95,42.56 184.13,41.74 184.13,37.04 183.99,36.9 UE1.3
  IN1 w0.127: v1(193.22,43.85) 193.24,43.85 193.86,44.46 193.86,50.41 194.06,50.61 194.06,53.7 193.8,53.96 193.8,54.13 192.62,55.31 192.62,56.33 191.13,57.83 191.13,64.86 190.06,65.94 190.06,75.97 183.01,83.02 178.99,83.02 173.96,88.05 169.58,88.05 154.97,102.67 154.97,104.49 153.9,105.57 153.9,108.36 149.92,112.34 149.36,112.34 148.16,113.54 148.16,114.65 v1(146.43,116.38)
  IN3 w0.084: 137.63,117.12 134.24,117.12 133.69,117.68 130.77,117.68 130.19,117.1 129.28,117.1 v1(128.65,116.48)
  IN3 w0.127: 137.63,117.12 139.28,117.12 139.67,116.73 141.31,116.73 142.2,115.84 143.92,115.84 144.33,116.25 146.29,116.25 v1(146.43,116.38)
  BOTTOM w0.076: v1(128.65,116.48) 128.33,116.81 UC1.T4
  BOTTOM w0.102: v1(146.43,116.38) 146.43,118.85 v3(145.82,119.45) 145.62,119.66 RC102.2
SIO_EXT_SCI#: length 5
  TOP w0.089: v3(127.91,121.94) 127.91,121.67 128.16,121.43 128.16,120.69 128.54,120.31 RC98.1 127.92,119.45 127.28,118.82 v1(127.28,118.69)
  BOTTOM w0.089: v1(127.28,118.69) 127.64,118.33 UC1.N5
SIO_SLP_S0#: length 104.5
  TOP w0.102: UE1.89 185.99,52.5 185.32,53.16 185.32,54.94 183.86,56.4 181.32,56.4 177.04,60.68 177.04,71.25 175.85,72.44 175.85,84.54 v3(169.57,90.82) 169.57,94.73 170.08,95.24 v1(170.08,95.52)
  IN3 w0.084: v1(133.38,112.02) 133.38,108.79 133.82,108.34 135.66,108.34 136.24,107.77 137.82,107.77
  IN3 w0.127: v1(170.08,95.52) 169.92,95.68 168.51,95.68 164.29,99.9 164.29,100.86 159.15,106 154.9,106 152.49,108.41 149.63,108.41 149.44,108.21 138.65,108.21 138.2,107.77 137.82,107.77
  BOTTOM w0.076: UC1.AF3 129.23,111.3 129.75,111.3 129.99,111.54 129.99,111.72 130.16,111.89 130.47,111.89 130.62,112.04 132.12,112.04 132.54,112.46 132.95,112.46 133.28,112.12 133.28,112.12 v1(133.38,112.02)
SIO_SLP_S3#: length 126.1
  TOP w0.102: UE1.6 185.19,34.36 184.67,33.84 CE27.1 184.56,33.91 184.56,34.32 v1(184.69,34.45)
  IN1 w0.084: v1(128.66,105.98) 129.1,106.41 134.19,106.41 135.83,104.77 137.81,104.77 137.92,104.89
  IN1 w0.127: 137.92,104.89 139.89,106.85 142.54,106.85 144.4,104.99 144.4,99.04 148.48,94.96 151.67,94.96 156.61,90.03 160.61,90.03 166.6,84.05 168.75,84.05 169.64,83.16 174.18,83.16 177.62,79.72 179.44,79.72 186.28,72.88 186.28,64.65 187.54,63.38 187.54,55.36 187,54.82 187,49.4 187.42,48.98 187.55,48.98 188.1,48.44 188.1,45.12 188.1,45.12 188.1,40.63 187.83,40.36 187.83,34.99 v1(188.52,34.3)
  IN3 w0.127: v1(184.69,34.45) 184.69,34.43 185.89,33.22 187.44,33.22 v1(188.52,34.3)
  BOTTOM w0.089: v1(128.66,105.98) 128.33,105.64 UC1.AT4
  BOTTOM w0.102: v1(188.52,34.3) 189.24,34.3 v3(189.29,34.24)
SIO_SLP_S4#: length 103.3
  TOP w0.089: v1(127.27,110.16) 127.74,110.63 T104.1
  TOP w0.102: UE1.84 187.99,52.15 187.79,52.34 187.79,52.7 v1(188.2,53.11)
  IN1 w0.084: 137.92,108.93 137.89,108.96 136.97,108.96 136.86,108.85 135.18,108.85 134.43,109.6 129.82,109.6 129.62,109.8 127.68,109.8 127.61,109.87 127.57,109.87 v1(127.27,110.16)
  IN1 w0.127: v1(188.2,53.11) 188.32,53.11 188.79,53.58 188.79,56.57 188.56,56.8 188.56,63.81 187.4,64.96 187.4,73.57 184.33,76.65 184.33,77.16 180.49,80.99 178.15,80.99 174.47,84.67 172.42,84.67 171.78,85.32 167.12,85.32 160.73,91.71 160.73,94.18 153.19,101.72 153.19,101.87 148.76,106.3 148.76,107.81 147.2,109.37 144.32,109.37 144.23,109.27 141.91,109.27 141.74,109.11 138.51,109.11 138.33,108.93 137.92,108.93
  BOTTOM w0.089: UC1.AJ6 126.99,109.88 v1(127.27,110.16)
SIO_SLP_S5#: length 132.6
  TOP w0.089: 133.49,101.44 133.48,101.44 132.49,102.44 131.47,102.44 128.24,105.67 128.24,106.06 v1(127.83,106.46)
  TOP w0.102: T103.1 136.3,98.63 133.49,101.44 ; v1(188.79,38.24) 188.39,37.83 UE1.14 188.39,34.82 188.12,34.55 188.12,34.08 188.31,33.89 CE28.1
  IN1 w0.084: v1(127.83,106.46) 127.95,106.58 134.31,106.58 135.86,105.04 137.72,105.04
  IN1 w0.127: 137.72,105.04 139.78,107.1 142.64,107.1 144.66,105.09 144.66,99.15 148.59,95.21 151.83,95.21 156.68,90.36 160.64,90.36 166.7,84.3 168.86,84.3 169.75,83.41 174.29,83.41 177.73,79.97 179.55,79.97 186.53,72.98 186.53,64.75 187.8,63.49 187.8,55.26 187.25,54.71 187.25,52.16 189.75,49.66 189.75,39.2 v1(188.79,38.24)
  BOTTOM w0.076: UC1.AP5 127.46,106.83 v1(127.83,106.46)
SKIP#: length 1.8
  BOTTOM w0.203: PR535.1 85.74,138.42 PU501.7
SKIP#1: length 46.3
  TOP w0.102: v3(111.75,139.7) 111.9,139.55 v1(111.9,139.15)
  IN1 w0.254: v1(83.91,138.63) 84.29,138.63 85.53,139.86 85.53,142.5 88.71,145.68 113.79,145.68 115.03,144.44 115.03,139.41 114.77,139.15 v1(111.9,139.15)
  BOTTOM w0.203: PU502.1 v1(111.9,139.15)
  BOTTOM w0.254: v1(83.91,138.63) 84.42,138.12 PR535.2
SLATE_MODE_R: length 20.7
  IN3 w0.084: 137.82,111.01 135.35,111.01 133.96,112.4 131.81,112.4 128.63,109.22 v1(128.63,108.97)
  IN3 w0.127: v1(143.04,109.69) 142.61,110.13 139.72,110.13 138.84,111.01 137.82,111.01
  BOTTOM w0.076: UC1.AL4 128.33,108.67 v1(128.63,108.97)
  BOTTOM w0.102: RC110.1 144.58,111.51 144.58,111.41 144.49,111.32 144.49,111.3 143.76,110.57 143.76,110.42 v3(143.47,110.12) v1(143.04,109.69)
SLEWA_CPU: length 4.3
  TOP w0.102: v3(92.35,140.1) 92.09,139.85 PR513.2
  TOP w0.254: v1(90.77,140.66) 91.15,140.28 PR513.2
  BOTTOM w0.203: v1(90.77,140.66) 90.77,140.5 90.22,139.95 PU501.15
  BOTTOM w0.254: PR514.1 v1(90.77,140.66)
SM_RCOMP0: length 9.6
  TOP w0.305: v1(93.5,105.39) v3(89.85,101.74) 89.32,101.21 RC68.1
  BOTTOM w0.229: v1(93.5,105.39) 93.71,105.18 UC1.AU60
SM_RCOMP1: length 7.7
  TOP w0.305: RC69.1 90.21,101.02 v3(92.23,103.05) v1(93.24,104.05)
  BOTTOM w0.229: v1(93.24,104.05) 93.42,104.23 UC1.AV60
SM_RCOMP2: length 9.5
  TOP w0.305: RC70.1 88.36,98.22 v3(88.36,99.84) 88.36,101.22 92.5,105.35 v1(92.53,105.35)
  BOTTOM w0.229: v1(92.53,105.35) 92.72,105.16 UC1.AU61
SML0CLK: length 9.2
  BOTTOM w0.076: 131.47,106.88 130.71,106.88 130.49,107.1 UC1.AN1
  BOTTOM w0.089: 137.92,109.24 137.64,109.24 136.61,108.21 136.11,108.21 v3(134.78,106.88) 131.47,106.88
  BOTTOM w0.102: RP49.1 137.92,109.24
SML0DATA: length 9.1
  BOTTOM w0.076: 133.2,108.53 132.38,108.53 131.97,108.94 130.69,108.94 UC1.AK1
  BOTTOM w0.089: 137.92,109.74 137.87,109.74 136.54,108.41 v3(135.13,108.41) 134.01,108.41 133.89,108.53 133.2,108.53
  BOTTOM w0.102: RP49.2 137.92,109.74
SML1_SMBCLK: length 36
  IN3 w0.084: v1(127.88,105.35) 126.78,105.35 126.33,105.81 126.33,108.4 126.19,108.54 126.19,109.65 126.33,109.79 126.33,110.46 126.46,110.59 127.88,110.59 128.81,111.52 129.35,111.52 129.82,111.99 129.82,112.17 131.51,113.86 132.5,113.86 133.2,113.16 137.03,113.16 v1(137.51,112.68) 137.82,112.68
  IN3 w0.127: v1(149.25,115.37) 148.53,115.37 147.94,114.77 145.83,114.77 145.83,114.78 144.48,114.78 144.21,114.5 143.23,114.5 141.41,112.68 137.82,112.68
  BOTTOM w0.089: UC1.AU3 128.87,104.91 128.52,105.27 127.96,105.27 v1(127.88,105.35)
  BOTTOM w0.102: v1(137.51,112.68) 137.86,113.04 RP40.3 ; v1(149.25,115.37) 149.06,115.18 QH1.1
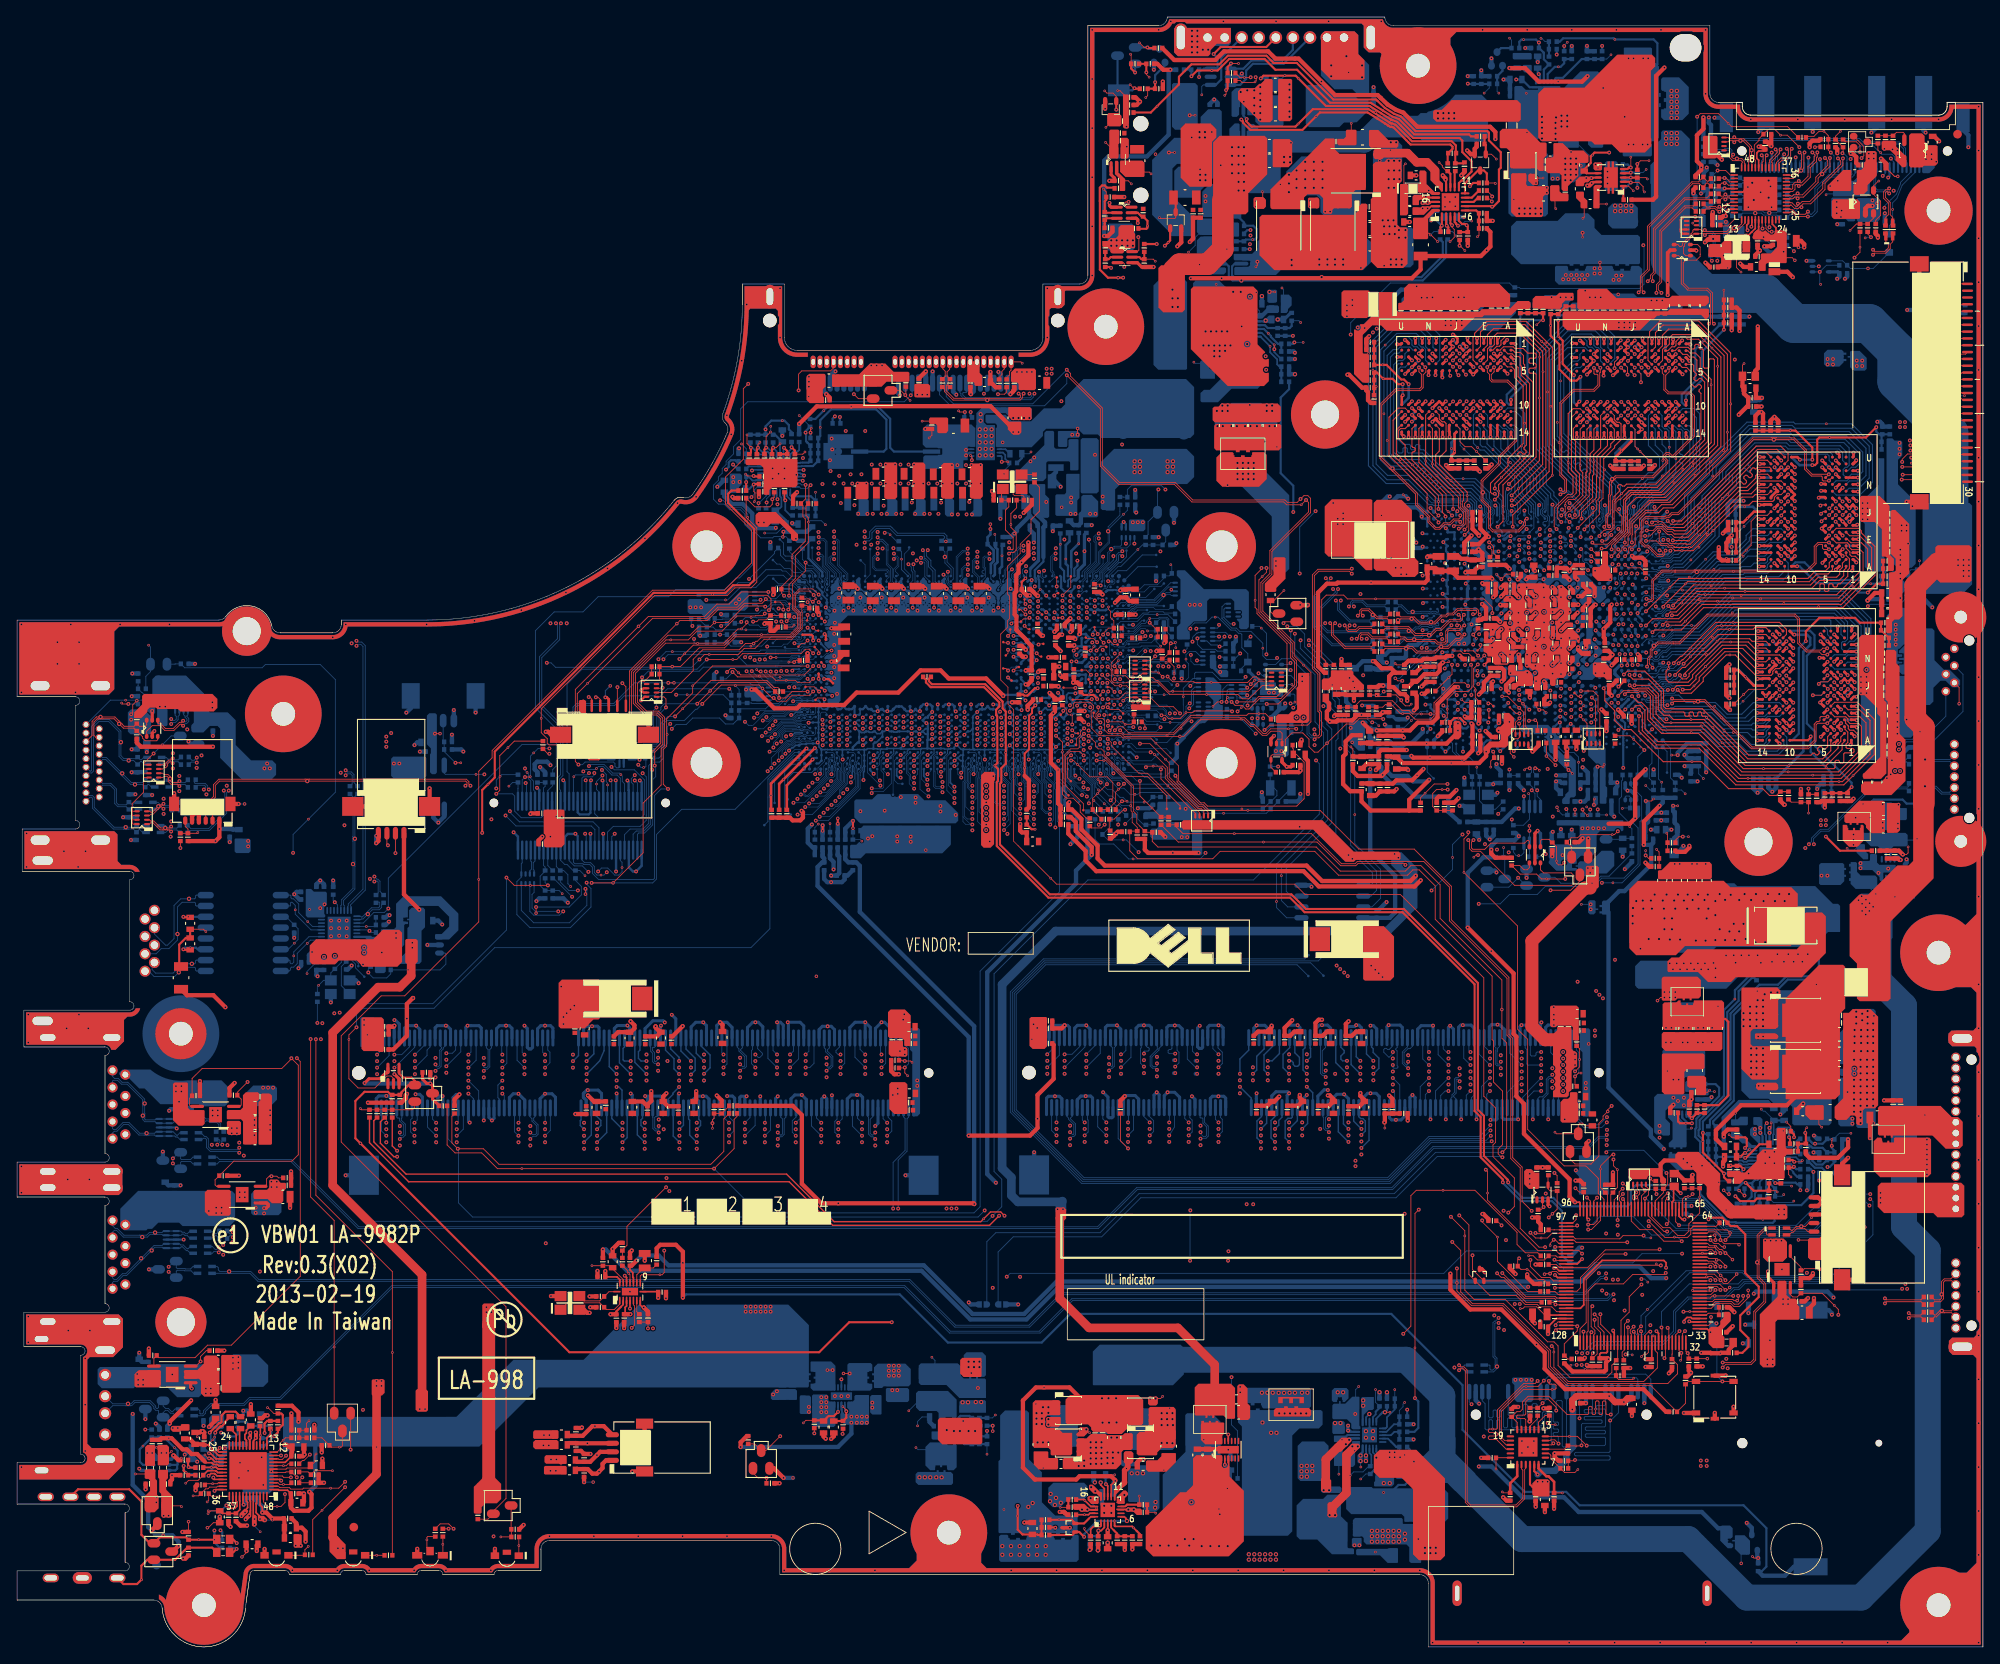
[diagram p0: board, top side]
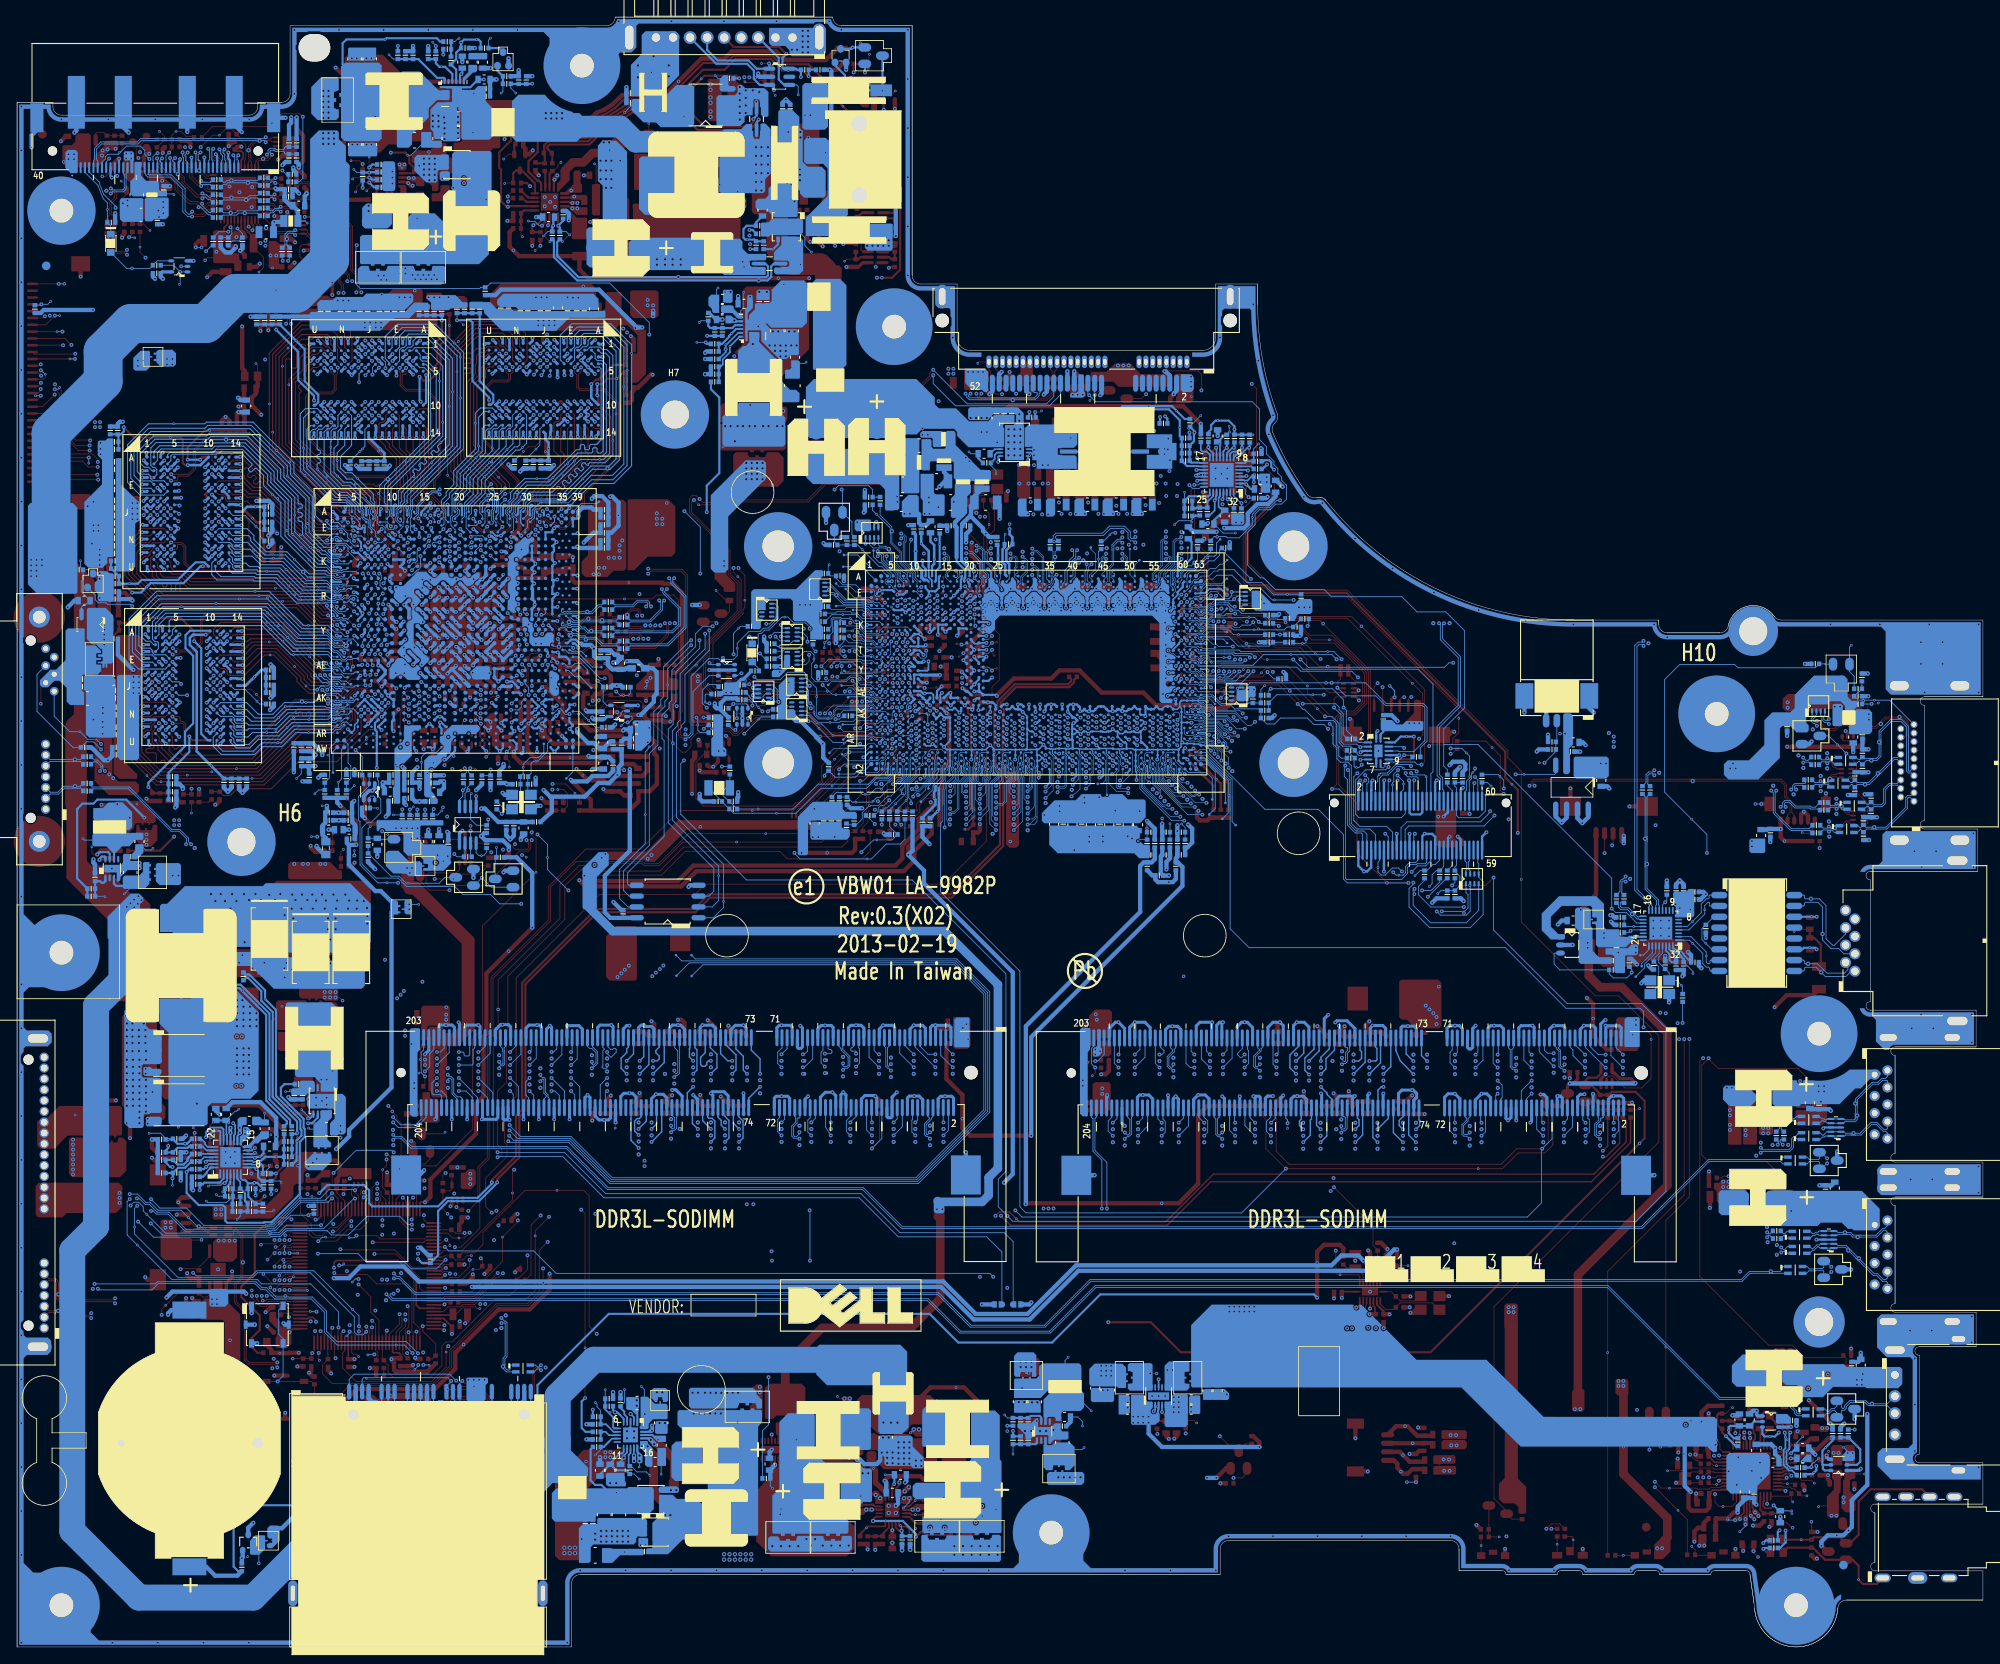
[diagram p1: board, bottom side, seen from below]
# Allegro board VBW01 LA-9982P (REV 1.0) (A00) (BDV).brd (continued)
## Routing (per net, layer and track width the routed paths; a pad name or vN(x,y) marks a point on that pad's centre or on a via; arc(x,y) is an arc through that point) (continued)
SML1_SMBDATA: length 24.3
  IN3 w0.127: v1(145.49,114.16) 144.74,114.16 144.3,113.72 144.12,113.72 144.09,113.74 v1(143.98,113.74)
  BOTTOM w0.076: UC1.AH3 129.23,109.81 129.75,109.81 129.99,110.04 129.99,110.22 130.16,110.39 130.4,110.39 130.53,110.26 134.23,110.26 134.72,109.77 134.72,109.32 135.02,109.02 136.47,109.02 136.68,109.24 136.68,110.44
  BOTTOM w0.102: 136.68,110.44 v3(136.68,111.43) 136.68,112.41 137.81,113.54 138.01,113.54 ; v1(145.49,114.16) 145.67,114.16 145.95,113.88 QH1.4 ; 138.01,113.54 RP40.4 ; 138.01,113.54 138.01,114.15 138.14,114.28 140.08,114.28 140.96,113.4 143.64,113.4 v1(143.98,113.74)
SNB_1.05V: length 2.9
  BOTTOM w0.102: PR1207.2 184.23,174.9 v3(184.64,174.9)
SNB_1.05V_17607668: length 1.4
  BOTTOM w0.102: v3(137.92,150.64) 138.06,150.5 PC301.1
SNUB_PCIE: length 1.3
  TOP w0.102: PC1304.1 198.11,65.03 v3(198.36,65.28)
SPK_L1-_CONN: length 5.4
  TOP w0.508: LA5.2 64.68,23.9 CA30.1 65.52,23.88 v4(66.84,23.88) JSPK.3
SPK_L2+_CONN: length 6.2
  TOP w0.508: LA6.2 64.62,24.76 CA29.1 66.3,24.76 67.42,25.89 v4(67.73,25.89) 68.76,25.89 JSPK.4
SPK_R1-_CONN: length 5.6
  TOP w0.508: v4(68.21,20.55) 68.21,20.57 ; 68.21,20.57 67.97,20.32 67.42,20.32 66.89,20.85 CA32.1 65.57,20.85 LA3.2 ; 68.21,20.57 68.62,20.97 68.62,21.47 69.03,21.88 JSPK.1
SPK_R2+_CONN: length 4.9
  TOP w0.508: JSPK.2 68.35,22.88 v4(67.96,22.49) 67.18,21.71 CA31.1 65.64,21.71 LA4.2
SRTCRST#: length 158.8
  TOP w0.089: 131.28,95.8 131.28,96.09 130.7,96.67 130.7,97.89 130.56,98.02 130.56,100.97 127.6,103.93 v3(127.38,103.93) v1(126.53,103.93)
  TOP w0.102: 131.28,95.8 RC5.2 130.48,95.65 CC3.2 130.41,93.34 131.33,92.42 140.14,92.42 141,93.28 152.09,93.28 154.88,90.49 162.97,90.49 163.59,91.11 164.33,91.11 166.21,89.23 166.21,85.32 172.88,78.65 172.88,71.21 173.04,71.04 173.04,66.23 174.09,65.17 174.09,58.89 173.59,58.38 173.59,57.81 173.98,57.41 v1(174.08,57.41)
  BOTTOM w0.076: v1(126.53,103.93) 126.83,104.23 UC1.AV6
  BOTTOM w0.102: v1(174.08,57.41) 173.99,57.5 166.44,57.5 161.61,52.66 131.7,52.66 127.12,48.09 116.75,48.09 114.98,46.31 ME1.2
SUS_STAT#/LPCPD#: length 25.4
  IN3 w0.084: 137.82,112.29 135.4,112.29 134.77,112.92 131.28,112.92 129.44,111.08 129.16,111.08 128.58,110.5 v1(128.58,110.47)
  IN3 w0.127: v1(149.25,110.63) 148.81,111.07 143.92,111.07 142.7,112.29 137.82,112.29
  BOTTOM w0.076: UC1.AG4 128.33,110.73 128.58,110.47 v1(128.58,110.47)
  BOTTOM w0.102: v1(149.25,110.63) 149.61,110.63 v3(149.76,110.78) 149.76,111.61 149.65,111.72 RC29.2
SUSACK#: length 143.9
  TOP w0.102: RC35.2 136.1,94.37 v3(146.08,94.37) 152.36,94.37 155.13,91.6 156.91,91.6 157.17,91.87 162.55,91.87 162.72,91.7 v1(162.72,91.69) ; v1(182.72,50.62) 182.72,50.11 182.31,49.71 UE1.97
  IN1 w0.127: v1(149.95,108.98) 151.37,107.55 151.37,105.48 151.84,105.01 152.65,105.01 153.7,103.97 153.7,101.93 163.1,92.53 163.1,92.09 162.72,91.7 v1(162.72,91.69) 162.73,91.69 163.1,91.32 163.1,90.06 167.33,85.82 171.99,85.82 172.63,85.18 174.68,85.18 178.36,81.5 182.38,81.5 188.54,75.34 188.54,65.31 189.58,64.26 189.58,57.23 190.48,56.32 190.48,54.53 191.21,53.8 191.21,50.53 191.65,50.09 191.65,49.76 v1(191.23,49.34)
  IN3 w0.084: 137.92,108.16 136.35,108.16 135.73,108.78 v1(134.47,108.78)
  IN3 w0.127: 137.92,108.16 138.01,108.16 138.32,108.47 146.28,108.47 146.79,108.98 v1(149.95,108.98) ; v1(191.23,49.34) 189.58,49.34 188.12,50.79 182.89,50.79 v1(182.72,50.62)
  BOTTOM w0.089: v1(134.47,108.78) 134.02,108.78 133.63,109.17 RC37.1
  BOTTOM w0.102: RC28.2 v1(149.95,108.98)
SUSACK#_R: length 3.2
  BOTTOM w0.076: UC1.AK2 129.86,109.35 130.16,109.64 130.9,109.64 131.28,109.25 131.78,109.25
  BOTTOM w0.089: 131.78,109.25 132.44,109.25 RC37.2
SUSCLK: length 1.2
  TOP w0.089: T102.1 126.95,111.7 v1(127.3,112.04)
  BOTTOM w0.076: v1(127.3,112.04) 126.99,111.74 UC1.AE6
SUSP: length 225.9
  TOP w0.102: v1(148.42,120.04) 148.59,120.2 Q2308.2 ; v1(186.88,63.43) 186.42,62.97 v4(186.42,62.78) 185.88,62.24 185.88,61.87 185.39,61.38 185.39,57.54 184.47,56.63 182.59,56.63 182.01,57.21 Q2307.2 ; v1(89.44,24.71) 87.75,23.02 Q8.1 86.43,23.81 R10.2
  IN2 w0.127: v1(188.4,39.44) 188.55,39.59 188.55,44.66 187.16,46.05 187.16,54.32 188.05,55.21 188.05,62.26 v1(186.88,63.43) 187.28,63.83 187.28,75.5 182.95,79.83 182.54,79.83 162.36,100.01 162.36,100.86 161.74,101.48 158.31,101.48 153.67,106.13 153.67,108.69 153.55,108.81 153.55,109.49 154.17,110.11 154.17,110.44 152.09,112.52 152.09,114.75 148.42,118.42 v1(148.42,120.04)
  IN3 w0.127: v1(89.44,24.71) 89.44,27.57 101.16,39.29 177.28,39.29 177.57,39 182.85,39 183.29,39.44 v1(188.4,39.44)
SUSP#: length 259.1
  TOP w0.102: UE1.116 180.24,42.11 v1(180.23,42.1) ; R2318.1 v1(93.44,25.04) ; v1(114.35,25.94) v4(114.35,25.3) ; R16.1 v1(87.84,19.82) 86.83,19.82 86.25,20.41 Q8.2 ; R2313.1 96.8,25.03 v1(96.75,24.98)
  IN1 w0.127: v1(96.75,24.98) 96.69,25.04 v1(93.44,25.04) 93.06,25.04 v1(87.84,19.82) ; v1(184.93,71.65) 184.93,70.01 184.24,69.33 184.24,66.59 185.01,65.83 185.01,64.24 186.83,62.42 186.83,58.63 186.61,58.42 186.09,58.42 185.84,58.17 185.84,57.82 186.36,57.3 186.36,54.32 186.49,54.2 186.49,49.19 186.96,48.73 186.96,48.18 187.74,47.4 187.74,43.18 v1(187.62,43.06)
  IN1 w0.254: v1(114.35,42.11) v1(114.35,25.94)
  IN3 w0.127: v1(149.57,133.07) 149.57,131.76 153.97,127.35 156.85,127.35 159.74,124.46 159.74,117.78 156.88,114.93 156.88,113.53 159.03,111.39 159.41,111.39 161.2,109.59 161.2,107.24 162.25,106.19 163.46,106.19 166.47,103.18 166.47,99.95 169.44,96.98 173.03,96.98 176.51,93.49 176.51,92.96 181.92,87.56 181.92,82.62 187.15,77.39 187.15,73.87 v1(184.93,71.65) ; v1(114.35,42.11) 114.66,41.79 178.91,41.79 178.97,41.86 179.99,41.86 v1(180.23,42.1) 180.47,41.86 184.82,41.86 185.46,42.49 187.06,42.49 187.62,43.05 v1(187.62,43.06)
  IN3 w0.254: v1(114.35,25.94) 106.6,25.94 105.64,24.98 v1(96.75,24.98)
  BOTTOM w0.254: v1(149.57,133.07) 149.57,136.15 148.1,137.62 148.1,146.49 149.08,147.47 PR300.2 ; PR401.2 v1(114.35,25.94)
SW_1.35V: length 7
  TOP w1.016: 154.21,16.46 155.8,18.05 155.8,22.5 155.99,22.69
  vias: v2(153.83,15.45) v2(154.47,15.45) v2(156.5,23.52) v2(157.13,23.52) v3(156.77,23)
SW_+1.2VSP: length 2.7
  IN1 w0.762: 180.62,170.64 182.21,170.64 182.97,171.4
  vias: v1(179.29,171.08) v1(179.29,170.5) v1(183.91,172.22) v1(184.5,172.22) v2(176.05,168.67) v2(176.05,168.03) v2(176.69,168.67) v2(176.69,168.03) v2(177.32,168.67) v2(177.32,168.03) v2(177.96,168.67) v2(177.96,168.03) v2(178.59,168.67) v2(178.59,168.03) v3(175.43,169.71)
SW_CPU2: length 2
  TOP w0.102: PC520.1 107.22,142.07 v3(106.9,141.76)
  TOP w0.508: v1(106.44,142.81) PC520.1
SW_VGA_CORE: length 35.5
  TOP w0.508: v2(209.32,63.7) 208.56,62.94 PC815.1
  IN1 w1.016: 205.64,67.51 205.64,63.4 204.89,62.65
  BOTTOM w0.254: PR829.1 198.78,61.36 198.78,61.64 201.2,64.05 201.2,74.1 204.36,77.26 206.54,77.26 207.51,78.24 210.34,78.24 211.17,77.42 PL802.1
  vias: v1(204.31,60.86) v1(204.31,60.27) v2(202.34,74.31) v2(202.34,73.54) v2(202.34,72.78) v2(203.1,75.07) v2(203.1,74.31) v2(203.1,73.54) v2(203.1,72.78) v2(203.23,70.18) v2(203.23,69.42) v2(203.23,68.65) v2(203.23,67.89) v2(203.23,67.13) v2(203.86,75.07) v2(203.86,74.31) v2(203.86,73.54) v2(203.86,72.78) v2(203.86,70.18) v2(203.86,69.42) v2(203.86,68.65) v2(203.86,67.89) v2(203.86,67.13) v2(203.99,75.83) v2(204.63,75.83) v2(204.63,75.07) v2(204.63,74.31) v2(204.63,73.54) v2(204.63,72.78) v2(204.63,70.18) v2(204.63,69.42) v2(204.63,68.65) v2(204.63,67.89) v2(204.63,67.13) v2(204.82,76.53) v2(205.55,76.74) v2(205.57,76.11) v2(206.32,76.74) v2(206.33,76.11) v3(203.95,76.9)
SYS_PWROK: length 321.8
  TOP w0.089: RP50.1 132.81,111.34 133.9,110.25 135.51,110.25 v1(136.3,109.46)
  TOP w0.102: v1(173.98,49.43) 173.44,49.97 CE32.1 ; v1(62.21,89.29) v3(60.16,89.29) 58.27,89.29 v1(57.36,90.21) ; v1(188.18,53.73) 188.14,53.73 187.76,53.35 187.76,52.99 187.19,52.42 UE1.86
  IN1 w0.084: v1(136.3,109.46) 136.41,109.34 137.65,109.34 137.74,109.44 137.92,109.44
  IN1 w0.127: 137.92,109.44 138.12,109.44 138.3,109.62 141.5,109.62 142.1,110.22 143.5,110.22 143.85,109.88 147.41,109.88 149.27,108.02 149.27,106.51 151.83,103.94 v1(152.24,103.94)
  IN3 w0.127: v1(114.33,50.54) 114.82,50.05 115.11,50.05 116.19,48.97 140.33,48.97 140.79,49.43 v1(173.98,49.43) 175.09,49.43 177.3,51.64 178.37,51.64 179.57,52.84 183.55,52.84 184.44,53.73 v1(188.18,53.73)
  BOTTOM w0.102: v1(152.24,103.94) 152.62,103.56 152.62,97.65 144.9,89.93 125.5,89.93 114.51,78.93 114.51,55.74 115.4,54.84 115.4,51.61 v1(114.33,50.54) 113.7,49.91 40.67,49.91 37.15,53.43 37.15,72.58 40,75.42 48.72,75.42 57.36,84.06 v1(57.36,90.21) ; v1(62.21,89.29) 61.89,89.62 RC52.1
SYS_PWROK_R: length 4.5
  TOP w0.089: v4(129.63,110.96) 130.01,111.34 RP50.8 131.33,111.34 131.41,111.26 131.41,110.89 v1(131.37,110.85)
  BOTTOM w0.076: UC1.AG2 129.86,110.85 130.16,111.14 130.47,111.14 130.61,111.28 130.93,111.28 v1(131.37,110.85)
SYS_PWROK_XDP: length 7.5
  BOTTOM w0.102: v3(63.89,88.32) 63.53,88.68 RC64.1 CC16.1 61.31,89.27 61.31,90.37 61.89,90.95 RC52.2 61.89,91.44 61.7,91.63 JXDP1.47
SYS_RESET#: length 73.3
  TOP w0.102: v1(62.39,104.72) 62.21,104.72 RC26.2
  IN1 w0.084: 87.33,110.81 88.35,110.81 88.72,110.45 93.74,110.45 93.94,110.25 96.23,110.25 97.63,111.64 114.27,111.64 114.57,111.95 116.69,111.95 117.12,111.52 119.39,111.52 119.6,111.3 124.52,111.3 125,111.78 125,113.04 125.57,113.61 128.52,113.61 v1(128.66,113.47)
  IN1 w0.127: 87.33,110.81 82.67,110.81 81.48,109.62 75.67,109.62 74.01,107.96 70.46,107.96 69.82,107.31 65.63,107.31 63.04,104.72 v1(62.39,104.72)
  BOTTOM w0.089: v1(128.66,113.47) 128.98,113.16 UC1.AC3
SYSON: length 50
  TOP w0.102: UE1.95 183.59,52.61 183.59,52.91 183.61,52.93 CE26.1 183.09,53.34 v1(182.64,53.78) ; v1(163.83,29.18) v3(163.83,35.06) 163.83,50.82 v1(164.28,51.27)
  IN3 w0.127: v1(164.28,51.27) 171.23,51.27 171.64,51.69 176.58,51.69 177.04,52.14 177.55,52.14 179.19,53.78 v1(182.64,53.78)
  BOTTOM w0.254: v1(163.83,29.18) 164.22,28.78 164.22,25.67 163.77,25.22 PR201.1
TDI_IREF: length 5.9
  BOTTOM w0.254: UC1.B12 122.71,125.02 122.71,126.15 122.27,126.59 v3(122.27,129.29) RC133.2
TDI_XDP: length 20.1
  IN1 w0.127: v1(59.61,101.29) 59.72,101.29 60.46,102.04 63.33,102.04 63.79,102.5 64.25,102.5 65.71,103.96 71.47,103.96 72,103.43 v1(72.81,103.43)
  BOTTOM w0.102: JXDP1.56 59.7,101.2 v1(59.61,101.29) ; RC45.1 73.63,104.21 RC44.2 73.7,104.14 73.7,103.24 73.57,103.12 v3(73.43,103.12) 73.13,103.12 v1(72.81,103.43)
TDI_XDP_R: length 23.3
  TOP w0.089: RC63.1 89.64,112.02 89.18,112.48 88.91,112.48
  TOP w0.102: 88.91,112.48 88.72,112.48 87.87,113.33 81.35,113.33 v3(78.01,110) v1(77.12,109.1)
  BOTTOM w0.102: UC4.5 72.59,104.56 72.65,104.49 73.11,104.49 73.35,104.73 73.35,104.89 73.58,105.12 RC45.2 74.11,105.61 75.02,105.61 75.47,106.06 75.47,108.28 76.29,109.1 v1(77.12,109.1)
TDO_XDP: length 54.1
  IN1 w0.114: v1(62.39,105.35) 62.96,105.35 65.42,107.81 69.61,107.81 70.26,108.46 73.25,108.46 v1(74.93,110.14)
  IN3 w0.127: v1(83.47,112.34) 83.77,112.34 85.1,113.67 86.15,113.67 86.67,114.19 86.67,114.59 86.9,114.82 87.95,114.82 88.78,115.64 88.78,117.43 87.04,119.17 87.04,120.31 86.72,120.62 v1(86.72,121.63)
  BOTTOM w0.102: v1(86.72,121.63) 86.86,121.77 86.86,122.03 86.69,122.2 RP44.4 ; v1(62.39,105.35) 61.07,105.35 v3(60.55,104.83) 60.16,104.44 60.16,101.88 60.53,101.51 60.53,100.48 60.7,100.31 JXDP1.52 ; RC62.1 83.71,112.1 v1(83.47,112.34) 76.23,112.34 74.93,111.05 v1(74.93,110.14) 74.6,109.81 74.6,107.49 RC43.2 73.17,106.06 UC4.2
TESTEN: length 5.2
  TOP w0.102: v1(171.96,116.24) 171.54,115.83 RV133.2 170.6,116.02 170.13,116.49 169.48,116.49 169.2,116.77 168.42,116.77 v3(168.29,116.89)
  BOTTOM w0.102: UV1.AD28 172.46,115.74 v1(171.96,116.24)
THERM_CPU: length 30
  TOP w0.102: v1(111.08,144.79) 110.48,144.79 v3(110.34,144.93)
  TOP w0.254: PR512.2 PC509.1 90.26,140.22 v1(89.88,140.6)
  IN3 w0.127: v1(89.88,140.6) 90.96,141.68 90.96,143.81 92.96,145.81 110.74,145.81 111.28,145.27 111.28,144.99 v1(111.08,144.79)
  BOTTOM w0.203: v1(89.88,140.6) 89.82,140.54 PU501.14
  BOTTOM w0.254: PH502.2 111.08,144.22 v1(111.08,144.79)
THM_ALERT#: length 25.7
  IN3 w0.102: v1(170.44,111.62) 170.44,111.16 172.82,108.78 172.82,107.05 173.99,105.88 174.6,105.88 175.01,105.48 175.01,104.86 175.36,104.51 175.36,103.69
  IN3 w0.127: v1(175.19,97.01) 174.19,98.01 174.19,101.53 175.36,102.7 175.36,103.69
  BOTTOM w0.102: v3(177.15,100.05) 177.25,99.96 UV14.6 177.25,97.05 176.54,96.35 RV96.1 175.19,96.52 v1(175.19,97.01) ; v1(170.44,111.62) 170.44,112.52 170.86,112.94 UV1.AG30
TL_BKOFF#: length 8.2
  BOTTOM w0.102: UX2.4 213.96,162.52 RX50.2 214.85,161.63 v4(216.93,161.63) 217.55,161.63 DX1.2
TL_BKOFF#_R: length 26.4
  TOP w0.102: UX4.44 203.72,174.32 203.61,174.43 203.61,176.1 204.15,176.64 204.15,176.84 RX33.1 205.25,177.94 206,177.94 v3(206.68,177.25) 207.47,177.25 v1(208.88,175.84)
  IN3 w0.127: v1(211.17,161.87) 211.17,164.25 207.64,167.78 207.64,174.6 v1(208.88,175.84)
  BOTTOM w0.102: v1(211.17,161.87) UX2.2
TL_ENVDD: length 17.9
  TOP w0.102: v1(205.64,165.94) 205.33,165.94 204.97,166.29 204.97,166.63 204.92,166.69 UX4.20 ; RX7.2 216.88,165.68 v1(217.28,165.29)
  IN1 w0.127: v1(217.28,165.29) 216.87,165.69 210.89,165.69 210.04,166.55 206.75,166.55 206.14,165.94 v1(205.64,165.94)
  BOTTOM w0.102: v3(216.6,165.21) 216.68,165.29 v1(217.28,165.29) ; v1(205.64,165.94) 206.73,165.94 RX51.2
TL_INVT_PWM: length 26.3
  TOP w0.102: v1(204.57,166.31) 204.52,166.35 UX4.19
  IN1 w0.127: v1(218.85,168.73) 218.72,168.73 215.99,166 211.04,166 210.15,166.89 205.15,166.89 v1(204.57,166.31)
  BOTTOM w0.102: RX49.2 205.13,164.84 204.4,164.84 RX26.1 203.99,165.73 v1(204.57,166.31) ; JLVDS.36 221.95,172.93 220.74,171.72 220.74,171.55 220.28,170.39 220.28,170.36 219.62,169.7 219.61,169.7 218.85,168.93 v1(218.85,168.73)
TMDS_L_TX0N: length 16.8
  BOTTOM w0.102: JHDMI.9 8.54,102.69 8.65,102.69 8.73,102.77 8.73,107.95 9.5,108.72 10.82,108.72 12.17,107.38 v2(12.17,106.08) 12.17,104.49 12.51,104.15 12.77,104.15 12.79,104.16 13.38,104.16 13.39,104.15 13.95,104.15 CX25.1 14.43,104.02 14.57,104.02 14.84,104.3 LX3.2
TMDS_L_TX0P: length 16.9
  BOTTOM w0.102: JHDMI.7 8.09,102.15 8.41,102.47 8.74,102.47 8.94,102.68 8.94,107.86 9.59,108.51 10.73,108.51 11.95,107.29 11.95,106.39 11.94,106.37 11.94,105.81 11.95,105.8 11.95,104.4 12.42,103.93 v2(13.08,103.93) 13.66,103.93 CX26.1 14.47,103.81 14.6,103.81 14.91,103.5 LX3.3
TMDS_L_TX1N: length 7.1
  BOTTOM w0.102: JHDMI.6 10.03,101.25 10.99,101.25 11.66,100.58 11.66,98.97 11.9,98.73 12.79,98.73 CX27.1 13.41,98.75 13.55,98.75 13.83,99.03 LX4.2
TMDS_L_TX1P: length 7.2
  BOTTOM w0.102: LX4.3 13.93,98.23 13.62,98.54 13.45,98.54 CX28.1 12.79,98.52 11.81,98.52 11.45,98.88 11.45,100.49 10.9,101.04 10.02,101.04 JHDMI.4
TMDS_L_TX2N: length 9.8
  BOTTOM w0.102: LX5.2 14.65,96.3 14.41,96.05 14.34,96.05 CX29.1 13.72,96.11 v2(12.74,96.11) 11.37,96.11 9.05,98.44 9.05,99.6 8.82,99.83 8.41,99.83 8.09,100.15 JHDMI.3
TMDS_L_TX2P: length 9.9
  BOTTOM w0.102: LX5.3 14.72,95.5 14.38,95.83 14.3,95.83 CX30.1 13.63,95.9 13.02,95.9 13,95.88 12.47,95.88 12.46,95.9 11.28,95.9 8.83,98.35 8.83,99.52 8.73,99.62 8.55,99.62 JHDMI.1
TMDS_L_TXCN: length 8.3
  BOTTOM w0.102: JHDMI.12 10,104.28 10.47,104.28 v2(12.32,102.42) 13.41,101.34 13.54,101.34 13.55,101.35 14.11,101.35 14.12,101.34 14.68,101.34 15.01,101.66 CX23.1 15.33,101.34 15.51,101.34 15.8,101.63 LX2.2
TMDS_L_TXCP: length 8.3
  BOTTOM w0.102: LX2.3 15.73,100.83 15.43,101.13 15.35,101.13 CX24.1 14.69,101.12 v2(13.82,101.12) 13.32,101.12 12.37,102.07 12.35,102.07 11.98,102.45 11.98,102.47 10.38,104.06 10.04,104.06 JHDMI.10
TMDS_TX0N: length 4.8
  TOP w0.102: RP59.4 17.08,103.44 17.23,103.3 17.33,103.3 17.43,103.4 17.43,103.63 17.78,103.99 18.04,103.99 v1(18.24,104.19)
  BOTTOM w0.102: CX14.1 18.87,104 18.42,104 v1(18.24,104.19) 18.14,104.09 17.68,104.09 17.47,104.3 LX3.1
TMDS_TX0P: length 4.9
  TOP w0.102: RP59.3 17.08,102.94 17.23,103.08 17.42,103.08 17.65,103.31 17.65,103.54 17.87,103.77 18.07,103.77 v1(18.24,103.6)
  BOTTOM w0.102: LX3.4 17.41,103.5 17.78,103.87 17.97,103.87 v1(18.24,103.6) 18.42,103.79 18.87,103.79 CX15.1
TMDS_TX1N: length 5.1
  TOP w0.102: RP58.4 15.57,97.98 15.71,97.84 15.83,97.84 v2(16.56,98.57) 16.7,98.71 16.84,98.71 16.84,98.72 16.93,98.72 17.02,98.72 v1(17.16,98.85)
  BOTTOM w0.102: LX4.1 16.52,99.03 16.81,98.73 17.04,98.73 v1(17.16,98.85) 17.34,98.67 17.84,98.67 CX16.1
TMDS_TX1P: length 5.2
  TOP w0.102: RP58.3 15.51,97.48 15.65,97.62 15.91,97.62 16.51,98.22 16.53,98.22 16.81,98.5 16.93,98.5 v1(17.16,98.27)
  BOTTOM w0.102: LX4.4 16.52,98.23 16.81,98.52 16.91,98.52 v1(17.16,98.27) 17.34,98.45 17.84,98.45 CX17.1
TMDS_TX2N: length 6
  TOP w0.102: RP58.2 15.51,96.98 15.65,96.84 16.02,96.84 16.84,96.02 v2(17.36,96.02) 17.89,96.02 v1(18.05,96.19)
  BOTTOM w0.102: LX5.1 17.41,96.3 17.7,96 17.87,96 v1(18.05,96.19) 18.24,96 18.73,96 CX18.1
TMDS_TX2P: length 6
  TOP w0.102: v1(18.05,95.6) 17.85,95.81 17.64,95.81 17.63,95.79 17.1,95.79 17.08,95.81 16.75,95.81 15.93,96.62 15.65,96.62 15.51,96.48 RP58.1
  BOTTOM w0.102: LX5.4 17.41,95.5 17.68,95.76 17.89,95.76 v1(18.05,95.6) 18.24,95.79 18.73,95.79 CX19.1
TMDS_TXCN: length 5.8
  TOP w0.102: v1(19.03,101.52) 18.86,101.36 18.16,101.36 17.94,101.59 v2(17.94,101.78) 17.94,102.04 17.68,102.3 17.23,102.3 17.08,102.44 RP59.2
  BOTTOM w0.102: LX2.1 18.08,101.38 18.89,101.38 v1(19.03,101.52) 19.21,101.34 19.68,101.34 CX12.1
TMDS_TXCP: length 5.9
  TOP w0.102: v1(19.03,100.94) 18.82,101.14 18.05,101.14 17.71,101.48 17.71,101.97 17.59,102.08 17.23,102.08 17.08,101.94 RP59.1
  BOTTOM w0.102: CX13.1 19.68,101.12 19.21,101.12 v1(19.03,100.94) 18.8,101.17 18.17,101.17 LX2.4
TMS_XDP: length 16
  TOP w0.102: v3(60.15,102.04) 60.1,101.99 v1(59.53,101.99)
  IN1 w0.114: v1(59.53,101.99) 59.82,102.28 63.23,102.28 63.69,102.75 64.15,102.75 65.96,104.56 v1(67.83,104.56)
  BOTTOM w0.102: JXDP1.58 59.2,101.66 v1(59.53,101.99) ; RC46.2 67.05,104.56 v1(67.83,104.56) 68.34,104.06 UC4.9
TON_1.35V: length 3.5
  BOTTOM w0.102: v3(162.62,22.51) 162,23.13 PR208.2
  BOTTOM w0.203: PU200.9 160.67,24.43 161.01,24.09
  BOTTOM w0.254: PR208.2 161.66,23.44 161.01,24.09
TOUCH_PANEL_INTR#: length 18.2
  IN1 w0.084: 137.92,120.34 137.5,120.34 135.69,118.53 v1(132.88,118.53)
  IN1 w0.127: 137.92,120.34 142.2,120.34 v1(142.59,119.95)
  BOTTOM w0.076: UC1.P3 129.23,117.3 129.75,117.3 129.99,117.54 129.99,117.71 130.16,117.88 131.26,117.88 131.4,118.03 132.38,118.03 v1(132.88,118.53)
  BOTTOM w0.102: RP43.7 141.58,121.82 141.44,121.68 141.44,120.72 141.45,120.72 141.45,120.69 142.19,119.95 v1(142.59,119.95)
TOUCH_RST: length 220
  TOP w0.102: UE1.38 v1(195.3,39.31) ; v1(19.14,93.67) RX1.1
  IN3 w0.127: v1(19.14,93.67) 19.46,93.36 28.67,93.36 31.65,90.37 31.65,61.54 50.78,42.41 112.63,42.41 113.5,41.54 176.71,41.54 177.18,41.07 180.59,41.07 180.94,41.41 184.75,41.41 185.57,42.23 187.36,42.23 187.84,41.75 192.86,41.75 v1(195.3,39.31)
  BOTTOM w0.102: v3(196.04,39.34) 196.01,39.31 v1(195.3,39.31)
TOUCH_RST_N_GYRO_INT1: length 6.9
  BOTTOM w0.089: UC1.L1 130.87,119.09 131.78,120 132.21,120 132.38,120.17 132.38,120.27 132.7,120.59 133.74,120.59 133.88,120.72 134.77,120.72 134.99,120.51 134.99,119.68 RC76.2
TOUCH_RST_R: length 3.7
  TOP w0.102: RX24.2 20.03,95.9 19.71,96.22 JTOUCH.6 ; RX24.2 RX1.2 ; RX24.2 21.09,95.4 v3(21.18,95.5)
TOUCHPAD_INTR#: length 2.1
  TOP w0.089: v3(126.18,117.28) 126.18,117.18 v1(125.83,116.83) 125.48,116.83 RC74.2
  BOTTOM w0.089: UC1.U7 126.29,116.37 v1(125.83,116.83)
TP_CLK: length 189
  TOP w0.102: v1(67,111.38) 67.11,111.38 67.35,111.14 JTP.2 ; UE1.87 186.79,53.02 RE9.2 187.04,53.35 187.56,53.87 v3(187.56,55.96) 187.1,56.42 v1(187.1,57.16)
  IN3 w0.127: v1(67,111.38) 67,110.58 63.7,107.28 63.7,102.53 64.43,101.8 64.43,98.99 65.13,98.29 65.13,96.72 64.16,95.75 64.16,92.13 63.57,91.54 63.57,87.28 64.85,86 64.85,78.02 69.61,73.26 69.61,57.46 74.99,52.08 104.27,52.08 105.48,53.3 116.71,53.3 117.43,52.58 176.34,52.58 176.66,52.91 177.24,52.91 179,54.66 180.59,54.66 183.08,57.16 v1(187.1,57.16)
TP_DATA: length 190.2
  TOP w0.102: UE1.88 186.39,53.04 RE10.2 186.15,53.29 185.58,53.86 v3(185.58,56.04) 185.58,56.38 186.93,57.74 v1(187.1,57.74) ; v1(67.83,111.35) 68.09,111.35 68.35,111.09 JTP.3
  IN3 w0.127: v1(187.1,57.74) 186.87,57.51 183.07,57.51 180.48,54.93 178.9,54.93 177.13,53.16 176.55,53.16 176.23,52.84 117.53,52.84 116.82,53.55 105.38,53.55 104.16,52.33 75.16,52.33 71.37,56.12 71.37,70.59 69.87,72.1 69.87,73.37 65.11,78.12 65.11,86.1 63.83,87.38 63.83,91.44 64.42,92.03 64.42,95.64 65.39,96.62 65.39,98.39 64.69,99.09 64.69,101.89 63.96,102.63 63.96,106.95 67.83,110.82 v1(67.83,111.35)
TP_DC_TEST_B2: length 4.5
  BOTTOM w0.102: UC1.B2 131.37,126.66 T167.1
TRIP_+1.2VSP: length 4.4
  TOP w0.102: v3(190.73,170.59) 190.58,170.74 190.58,171.21 190.09,171.7 v1(189.13,171.7)
  TOP w0.254: PU1100.2 189.05,171.79 v1(189.13,171.7)
  BOTTOM w0.254: PR1102.2 188.57,171.14 v1(189.13,171.7)
TRST#_XDP: length 15.7
  IN1 w0.114: v1(59.53,103.01) 60.01,102.53 63.13,102.53 63.59,102.99 64.05,102.99 65.86,104.8 67.24,104.8 v1(67.83,105.4)
  BOTTOM w0.102: v1(67.83,105.4) 67.99,105.56 UC4.12 ; v1(59.53,103.01) 59.53,102.78 v3(59.77,102.54) 59.93,102.38 59.93,101.78 60.2,101.52 JXDP1.54
TS_FDO: length 13.6
  IN3 w0.102: v1(169.7,111.57) 169.7,111.43 171.87,109.26 171.87,108.27 172.62,107.52 172.62,106.96 173.9,105.68 174.52,105.68 174.8,105.39 174.8,104.78 174.91,104.68 174.91,103.69
  IN3 w0.127: v1(174.91,102.87) 174.91,103.69
  BOTTOM w0.102: RV235.2 RV236.1 v1(174.91,102.87) ; UV1.AK32 169.26,111.14 v1(169.7,111.57)
UG_3V: length 12.1
  TOP w0.102: v3(134.26,29.38) 134.01,29.12 v2(133.44,29.12)
  IN1 w0.762: 130.39,18.36 131.38,19.34 132.17,19.34 133,20.17 133,27.98
  vias: v2(129.24,17.44) v2(129.77,17.82) v2(132.81,29.12)
UG_5V: length 11.3
  IN1 w0.762: 121.44,25.44 121.82,25.06 121.82,20.08 124.43,17.47 125.06,17.47
  BOTTOM w0.102: v2(125.82,17.44) 125.82,16.98 v3(126.52,16.28)
  vias: v2(120.87,26.71) v2(120.87,26.08) v2(126.46,17.44)
UG_+1.2VSP: length 7.3
  TOP w0.102: v1(178.02,172.22) v3(178.85,172.22)
  IN1 w0.762: 178.02,170.83 178.02,170.51 178.84,169.68 182.85,169.68 183.54,170.38
  vias: v1(178.02,171.64) v1(184.04,171.33) v1(184.55,171.63)
UG_VGA_CORE:
  vias: v1(203.67,60.72) v1(203.67,60.13) v1(204.05,71.58) v1(204.12,65.78) v1(204.64,71.58) v1(204.7,65.78)
USB3RN1_JUSB2: length 155.7
  IN1 w0.084: 88.91,113.59 88.93,113.59 88.95,113.61 91.33,113.61 92.06,112.88 96.31,112.88 96.68,113.26 114.36,113.26 115.07,113.96 115.07,119.32 116.18,120.43 117.98,120.43 118.35,120.06 118.92,120.06 119.22,120.36 119.22,120.85 119.28,120.91 119.28,121.68 119.09,121.88 118.77,121.88 v1(118.68,121.97)
  IN1 w0.127: v1(23.64,46.26) 23.78,46.4 25.21,46.4 26.89,48.08 26.89,51.2 25.45,52.63 25.45,59.25 24.22,60.48 24.22,68.04 33.71,77.53 33.71,85.51 38.1,89.89 38.1,91.93 56.71,110.54 70.96,110.54 73.32,112.9 75.52,112.9 76.21,113.59 88.91,113.59
  BOTTOM w0.076: v1(118.68,121.97) 119.01,121.64 UC1.G20
  BOTTOM w0.102: LI4.1 22.87,46.16 23.08,46.37 23.54,46.37 v1(23.64,46.26)
USB3RN1_JUSB2_R: length 12.3
  BOTTOM w0.102: 15.77,46.49 16.15,46.86 17.01,46.86 17.11,46.76 DI4.1 DI4.10 19.09,46.76 19.24,46.91 19.4,46.91 19.84,46.47 19.99,46.47 20.3,46.16 LI4.2 ; 15.77,46.49 v2(15.77,46.49) ; 15.77,46.49 14.91,45.63 14.91,45.6 14.48,45.17 14.45,45.17 12.83,43.55 12.44,43.55 11.76,42.87 11.33,42.87 11.19,42.73 JUSB2.5
USB3RN2_JUSB1: length 147.5
  IN1 w0.084: v1(119.66,122.62) 119.8,122.48 120.05,122.48 120.24,122.29 120.24,120.34 118.97,119.07 116.06,119.07 115.7,118.71 115.7,113.48 114.97,112.75 97.06,112.75 96.43,112.12 95.61,112.12 94.97,111.49 94.34,111.49 94.08,111.23 92.57,111.23 91.95,111.86 90.09,111.86 89.15,112.8 88.95,112.8 88.93,112.78 88.91,112.78
  IN1 w0.127: 88.91,112.78 77.53,112.78 76.5,111.74 74.61,111.74 74.31,111.44 72.98,111.44 71.3,109.76 65.26,109.76 64.09,108.58 57.4,108.58 39.8,90.98 39.8,88.44 37.82,86.47 36.64,86.47 35.37,85.19 35.37,80.87 34.64,80.14 34.64,77.29 25.04,67.68 25.04,64.04 26.88,62.2 26.88,58.38 26.57,58.07 26.17,58.07 v1(26.04,57.94)
  BOTTOM w0.076: UC1.E18 119.99,122.94 v1(119.66,122.62)
  BOTTOM w0.102: LI1.1 21.66,59.49 21.81,59.64 22.06,59.64 22.2,59.5 22.2,58.54 22.66,58.09 25.89,58.09 v1(26.04,57.94)
USB3RN2_JUSB1_R: length 10.2
  BOTTOM w0.102: LI1.2 19.1,59.49 18.81,59.78 18.61,59.78 18.48,59.91 DI1.10 DI1.1 16.22,59.91 16.11,60.02 15.46,60.02 15.44,60.01 14.91,60.01 14.9,60.02 14.29,60.02 13.05,61.26 12.5,61.26 11.7,60.46 11.4,60.46 11.19,60.26 JUSB1.5
USB3RP1_JUSB2: length 155.3
  IN1 w0.084: v1(118.71,121.32) 118.71,121.48 118.87,121.65 118.99,121.65 119.08,121.56 119.08,121 119.03,120.94 119.03,120.5 118.82,120.29 118.45,120.29 118.08,120.66 116.08,120.66 114.84,119.42 114.84,114.06 114.27,113.49 96.59,113.49 96.21,113.11 92.15,113.11 91.42,113.84 88.96,113.84 88.94,113.86 88.91,113.86
  IN1 w0.127: 88.91,113.86 76.1,113.86 75.4,113.17 73.2,113.17 70.84,110.81 56.59,110.81 37.82,92.04 37.82,90.01 33.44,85.62 33.44,77.64 23.95,68.15 23.95,60.37 25.18,59.13 25.18,52.52 26.62,51.08 26.62,48.19 25.1,46.68 23.81,46.68 v1(23.64,46.85)
  BOTTOM w0.076: UC1.H20 119.1,121.09 118.87,121.32 v1(118.71,121.32)
  BOTTOM w0.102: LI4.4 22.87,46.96 23.24,46.58 23.37,46.58 v1(23.64,46.85)
USB3RP1_JUSB2_R: length 12.4
  BOTTOM w0.102: JUSB2.6 11.19,43.27 11.37,43.09 11.67,43.09 12.35,43.76 12.74,43.76 v2(14.54,45.56) 15.39,46.41 15.39,46.44 15.8,46.84 15.82,46.84 16.06,47.08 17,47.08 17.18,47.26 DI4.2 DI4.9 19.04,47.26 19.18,47.13 19.49,47.13 19.93,46.68 20.03,46.68 20.3,46.96 LI4.3
USB3RP2_JUSB1: length 147
  IN1 w0.084: v1(119.66,121.97) 119.66,122.08 119.83,122.25 119.95,122.25 120.04,122.16 120.04,120.47 118.87,119.3 115.97,119.3 115.47,118.81 115.47,113.57 114.87,112.98 96.97,112.98 96.34,112.35 95.51,112.35 94.88,111.71 94.24,111.71 93.99,111.46 92.67,111.46 92.04,112.09 90.18,112.09 89.22,113.05 88.91,113.05
  IN1 w0.127: v1(26.04,58.53) 26.22,58.34 26.46,58.34 26.61,58.49 26.61,62.08 24.76,63.93 24.76,67.8 34.36,77.4 34.36,80.26 35.09,80.99 35.09,85.31 36.53,86.74 37.71,86.74 39.53,88.55 39.53,91.09 57.29,108.85 63.97,108.85 65.15,110.03 71.18,110.03 72.86,111.71 74.19,111.71 74.5,112.01 76.38,112.01 77.42,113.05 88.91,113.05
  BOTTOM w0.076: UC1.F18 119.98,122.29 v1(119.66,121.97)
  BOTTOM w0.102: LI1.4 21.54,60.29 21.97,59.85 22.15,59.85 22.42,59.59 22.42,58.63 22.75,58.3 25.82,58.3 v1(26.04,58.53)
USB3RP2_JUSB1_R: length 10.4
  BOTTOM w0.102: LI1.3 19.1,60.29 18.81,60 18.7,60 18.29,60.41 DI1.9 DI1.2 16.29,60.41 16.12,60.23 v2(15.18,60.23) 14.38,60.23 13.14,61.48 12.41,61.48 11.61,60.68 11.29,60.68 11.19,60.78 JUSB1.6
USB3TN1_JUSB2: length 156.1
  IN1 w0.084: 88.91,125.17 89.11,125.17 89.12,125.16 106.52,125.16 108.45,127.1 110.36,127.1 110.93,127.67 110.93,128.18 111.1,128.34 111.27,128.34 v1(111.41,128.2)
  IN1 w0.127: v1(25.29,48.04) 25.46,48.21 25.73,48.21 26.03,48.51 26.03,50.82 21.57,55.28 21.57,63.9 22.16,64.48 22.16,69.06 30.83,77.73 30.83,97.93 46.82,113.92 63.43,113.92 63.84,114.33 69.26,114.33 75.09,120.16 80.62,120.16 82.08,121.63 84.65,121.63 85.7,122.68 85.7,123.05 87.83,125.17 88.91,125.17
  BOTTOM w0.076: v1(111.41,128.2) 111.22,128.39 110.9,128.39 110.26,127.75 110.26,124.73 110.28,124.71 110.28,124.46 110.21,124.39 110.21,124.28 110.29,124.2 110.49,124.2 UC1.C33
  BOTTOM w0.102: v1(25.29,48.04) 25.12,48.21 24.94,48.21 CI10.2
USB3TN1_JUSB2_C: length 1.6
  BOTTOM w0.102: LI6.1 22.93,47.93 23.23,48.23 23.35,48.23 CI10.1
USB3TN1_JUSB2_R: length 10.9
  BOTTOM w0.102: JUSB2.8 11.19,48.64 11.4,48.84 11.66,48.84 12.45,48.05 v2(14.67,48.05) 15.27,48.05 15.59,48.37 15.89,48.37 15.91,48.35 16.45,48.35 16.47,48.37 16.98,48.37 17.09,48.26 DI4.4 DI4.7 19.21,48.26 19.35,48.4 19.51,48.4 19.69,48.23 19.95,48.23 20.24,47.93 LI6.2
USB3TN2_JUSB1: length 140.8
  IN1 w0.084: v1(111.43,126.3) 111.43,126.41 111.19,126.65 108.89,126.65 106.71,124.47 89.93,124.47 89.62,124.16 88.91,124.16
  IN1 w0.127: 88.91,124.16 87.92,124.16 86.51,122.75 86.51,122.37 84.89,120.74 83.68,120.74 83.35,120.41 82.2,120.41 80.8,119.01 75.09,119.01 69.62,113.54 64.26,113.54 63.85,113.13 47.37,113.13 31.84,97.6 31.84,76.85 22.98,67.99 22.98,64.15 22.39,63.56 22.39,58.45 22.62,58.23 23.49,58.23 23.71,58.45 23.71,58.64 v1(23.47,58.88)
  BOTTOM w0.076: UC1.B33 110.48,124.98 110.48,125.05 110.84,125.42 110.84,126.3 111.12,126.58 111.33,126.58 111.43,126.48 v1(111.43,126.3)
  BOTTOM w0.102: CI3.2 23.66,59.5 23.77,59.4 23.77,59.18 v1(23.47,58.88)
USB3TN2_JUSB1_C: length 3.7
  BOTTOM w0.102: CI3.1 23.65,60.73 23.65,61.24 23.39,61.5 22.58,61.5 22.39,61.69 22.15,61.69 21.85,61.4 LI3.1
USB3TN2_JUSB1_R: length 12.9
  BOTTOM w0.102: JUSB1.8 11.19,66.35 11.27,66.43 11.78,66.43 12.22,65.99 12.89,65.99 14.74,64.15 14.74,64.03 14.72,64.01 14.72,63.45 14.74,63.44 v2(14.74,62.3) 14.74,61.82 14.98,61.58 16.18,61.58 16.35,61.41 DI1.4 DI1.7 18.25,61.41 18.42,61.58 18.6,61.58 18.72,61.71 18.85,61.71 19.16,61.4 LI3.2
USB3TP1_JUSB2: length 155.7
  IN1 w0.084: v1(111.41,128.78) 111.21,128.57 111,128.57 110.7,128.27 110.7,127.76 110.26,127.33 108.36,127.33 106.42,125.39 89.21,125.39 89.21,125.4 89.04,125.4 89.02,125.42 88.95,125.42 88.93,125.44 88.91,125.44
  IN1 w0.127: 88.91,125.44 87.71,125.44 85.43,123.16 85.43,122.79 84.54,121.9 81.97,121.9 80.51,120.43 74.98,120.43 69.15,114.6 63.73,114.6 63.32,114.19 46.7,114.19 30.55,98.04 30.55,77.84 21.89,69.17 21.89,64.59 21.3,64.01 21.3,55.17 25.76,50.71 25.76,48.62 25.61,48.48 25.43,48.48 v1(25.29,48.62)
  BOTTOM w0.076: v1(111.41,128.78) 111.22,128.58 110.82,128.58 110.07,127.83 110.07,124.67 UC1.B34
  BOTTOM w0.102: CI11.2 24.97,48.43 25.1,48.43 25.16,48.48 v1(25.29,48.62)
USB3TP1_JUSB2_C: length 1.6
  BOTTOM w0.102: LI6.4 22.93,48.73 23.23,48.44 23.37,48.44 CI11.1
USB3TP1_JUSB2_R: length 11
  BOTTOM w0.102: LI6.3 20.24,48.73 19.95,48.44 19.78,48.44 19.6,48.62 19.35,48.62 19.21,48.76 DI4.6 DI4.5 17.16,48.76 16.98,48.59 v2(16.18,48.59) 15.5,48.59 15.19,48.28 14.39,48.28 14.38,48.27 12.54,48.27 11.75,49.06 11.52,49.06 11.19,49.39 JUSB2.9
USB3TP2_JUSB1: length 140.9
  IN1 w0.084: v1(111.43,126.93) 111.38,126.88 108.8,126.88 106.61,124.7 89.84,124.7 89.53,124.39 89.04,124.39 89.02,124.41 88.95,124.41 88.93,124.43 88.91,124.43
  IN1 w0.127: v1(24.05,58.88) 23.98,58.81 23.98,58.34 23.6,57.96 22.51,57.96 22.12,58.34 22.12,63.67 22.71,64.26 22.71,68.1 31.57,76.96 31.57,97.72 47.25,113.4 63.74,113.4 64.15,113.82 69.51,113.82 74.97,119.28 80.69,119.28 82.09,120.68 83.24,120.68 83.57,121.02 84.78,121.02 86.24,122.48 86.24,122.86 87.81,124.43 88.91,124.43
  BOTTOM w0.076: v1(111.43,126.93) 111.27,126.77 111.04,126.77 110.65,126.38 110.65,125.66 UC1.A33
  BOTTOM w0.102: v1(24.05,58.88) 23.98,58.95 23.98,59.26 CI4.2
USB3TP2_JUSB1_C: length 4
  BOTTOM w0.102: LI3.4 21.85,62.2 22.15,61.9 22.48,61.9 22.67,61.71 23.48,61.71 23.87,61.33 23.87,60.77 CI4.1
USB3TP2_JUSB1_R: length 12.8
  BOTTOM w0.102: JUSB1.9 11.19,66.89 11.43,66.65 11.87,66.65 12.31,66.2 12.98,66.2 14.95,64.24 v2(14.95,63.72) 14.95,62.59 14.97,62.57 14.97,62.03 14.95,62.01 14.95,61.91 15.07,61.8 16.17,61.8 16.28,61.91 DI1.5 DI1.6 18.25,61.91 18.36,61.8 18.51,61.8 18.63,61.92 18.89,61.92 19.16,62.2 LI3.3
USB20_CAM_N7: length 170.5
  TOP w0.102: RX21.1 219.02,165.69 LX6.1 219.02,164.75 219.31,164.46 219.31,164.04 218.91,163.63 217.7,163.63 v1(217.52,163.82)
  IN1 w0.127: v1(116.97,132.52) 117.14,132.68 117.14,133.28 117.54,133.68 128.11,133.68 129.21,132.58 136.96,132.58 138.28,133.89 152.88,133.89 158.87,139.88 158.87,149.52 155.46,152.93 155.46,154.41 157.46,156.41 165.35,156.41 165.96,157.01 212.76,157.01 216.25,160.5 216.25,163.21 216.69,163.65 217.35,163.65 v1(217.52,163.82)
  IN3 w0.084: v1(123.1,106.51) 123.1,106.63 122.76,106.97 122.58,106.97 122.46,106.85 122.46,105.91 122.9,105.48 123.64,105.48 124.06,105.9 124.06,109.65 124.61,110.2 124.61,110.67 124.28,111.01 123.41,111.01 122.88,111.54 122.88,115.14 121.14,116.88 120.93,116.88 119.03,118.79 119.03,118.8 118.82,119.01 117.96,119.01 117.42,119.55 117.42,120.4 116.87,120.95 116.87,122.12 115.85,123.14 115.85,126.5 116.68,127.33 116.68,130.2 117.15,130.67 117.15,131.01 117.15,131.01 117.15,131.08 117.12,131.1 117.12,131.11
  IN3 w0.127: 117.12,131.11 117.12,132.36 v1(116.97,132.52)
  BOTTOM w0.076: v1(123.1,106.51) 123.06,106.54 122.67,106.54 122.57,106.45 122.57,106.32 UC1.AR13
USB20_CAM_N7_R: length 9.4
  TOP w0.102: v1(219.41,171.01) 219.25,170.85 219,170.85 218.76,170.61 218.76,169.85 219.31,169.29 219.31,167.92 219.02,167.63 LX6.2 219.02,166.69 RX21.2
  BOTTOM w0.102: JLVDS.28 217.95,172.73 217.83,172.61 217.83,171.02 218.02,170.83 219.23,170.83 v1(219.41,171.01)
USB20_CAM_P7: length 170.8
  TOP w0.102: RX22.1 219.82,165.69 LX6.4 219.82,164.75 219.53,164.46 219.53,163.95 219,163.42 217.7,163.42 v1(217.52,163.23)
  IN1 w0.127: v1(217.52,163.23) 217.37,163.38 216.8,163.38 216.52,163.09 216.52,160.39 212.87,156.74 166.07,156.74 165.47,156.14 157.57,156.14 155.73,154.3 155.73,153.05 159.14,149.64 159.14,139.77 152.99,133.62 138.39,133.62 137.07,132.31 129.09,132.31 127.99,133.41 117.65,133.41 117.41,133.16 117.41,132.66 v1(117.55,132.52)
  IN3 w0.084: 117.38,131.11 117.38,131.1 117.36,131.08 117.36,130.59 116.89,130.12 116.89,127.24 116.06,126.42 116.06,123.22 117.08,122.21 117.08,121.04 117.63,120.49 117.63,119.63 118.05,119.22 118.91,119.22 119.24,118.89 119.24,118.88 121.02,117.09 121.22,117.09 123.09,115.22 123.09,111.63 123.5,111.22 124.37,111.22 124.81,110.78 124.81,110.09 124.27,109.56 124.27,105.81 123.73,105.26 122.81,105.26 122.25,105.82 122.25,106.94 122.47,107.16 v1(123.1,107.16)
  IN3 w0.127: 117.38,131.11 117.38,132.35 v1(117.55,132.52)
  BOTTOM w0.076: UC1.AP13 122.77,106.83 v1(123.1,107.16)
USB20_CAM_P7_R: length 9.4
  TOP w0.102: RX22.2 219.82,166.69 LX6.3 219.82,167.63 219.53,167.92 219.53,169.38 218.98,169.94 218.98,170.52 219.09,170.64 219.2,170.64 v1(219.41,170.43)
  BOTTOM w0.102: JLVDS.27 217.45,172.89 217.62,172.72 217.62,170.93 217.93,170.61 219.23,170.61 v1(219.41,170.43)
USB20_CR_N6: length 130.8
  IN1 w0.084: 131.57,100.4 131.56,100.4 131.54,100.42 131.47,100.42 131.35,100.54 126.78,100.54 123.93,103.4 123.93,106.17 123.85,106.25 123.63,106.25 v1(123.57,106.18)
  IN1 w0.127: 131.57,100.4 133.36,100.4 136.75,97.02 140.72,97.02 148.96,88.78 150.52,88.78 161.4,77.91 171.97,77.91 176.89,72.98 176.89,72.49 177.92,71.46 177.92,64.78 180.01,62.69 180.01,62.19 181.7,60.5 181.7,58.06 181.9,57.86 181.9,49.38 182.58,48.7 182.58,42.74 186.07,39.25 186.07,38.23 185.17,37.33 185.17,36.75 184.47,36.05 177.33,36.05 175.05,38.33 173.88,38.33 v1(173.64,38.57)
  BOTTOM w0.076: v1(123.57,106.18) 123.57,106.25 123.83,106.51 UC1.AP11
  BOTTOM w0.102: LR2.1 172.56,33.05 172.62,32.99 172.62,32.59 172.74,32.47 172.96,32.47 173.22,32.73 173.22,33.14 173.23,33.16 173.23,33.77 172.98,34.02 172.98,38.02 173.16,38.21 173.28,38.21 173.64,38.56 v1(173.64,38.57)
USB20_CR_N6_R: length 29.1
  TOP w0.102: v1(169,33.03) 169.19,32.84 169.57,32.84 169.95,32.46 169.95,17.03 170.34,16.65 175.67,16.65 176.47,17.45 176.47,20.72 176.32,20.88 UR1.2
  BOTTOM w0.102: v1(169,33.03) 169.23,32.8 169.41,32.8 169.66,33.05 LR2.2
USB20_CR_P6: length 131
  IN1 w0.084: 131.57,100.67 131.56,100.67 131.46,100.77 126.88,100.77 124.16,103.49 124.16,106.27 123.66,106.76 v1(123.66,106.83)
  IN1 w0.127: v1(173.64,37.99) 173.71,38.06 174.93,38.06 177.21,35.78 184.58,35.78 185.44,36.64 185.44,37.22 186.34,38.12 186.34,39.37 182.85,42.86 182.85,48.81 182.17,49.49 182.17,57.97 181.97,58.17 181.97,60.61 180.28,62.3 180.28,62.8 178.19,64.89 178.19,71.57 177.16,72.6 177.16,73.1 172.08,78.18 161.51,78.18 150.63,89.06 149.07,89.06 140.84,97.29 136.86,97.29 133.48,100.67 131.57,100.67
  BOTTOM w0.076: UC1.AN11 123.73,106.83 v1(123.66,106.83)
  BOTTOM w0.102: LR2.4 173.05,32.25 173.45,32.65 v2(173.45,32.88) 173.45,33.86 173.19,34.11 173.19,37.93 173.25,37.99 v1(173.64,37.99)
USB20_CR_P6_R: length 29.4
  TOP w0.102: v1(169,32.45) 169.18,32.62 169.48,32.62 169.74,32.37 169.74,16.94 170.25,16.43 175.76,16.43 176.69,17.36 176.69,20.81 176.82,20.94 UR1.3
  BOTTOM w0.102: LR2.3 169.78,32.25 169.45,32.59 169.14,32.59 v1(169,32.45)
USB20_JUSB1_N1: length 259.8
  IN1 w0.084: v1(126.93,106.46) 126.93,106.47 127.35,106.06 127.35,105.73 127.5,105.58 127.5,104.54 127.72,104.33 128.83,104.33 129.99,105.49 132.13,105.49 132.23,105.59 133.06,105.59 134.32,104.33 136.13,104.33 136.32,104.14
  IN1 w0.127: v1(186.31,60.04) 186.21,59.94 186.2,59.95 185.96,59.95 185.82,60.08 185.82,62.29 183.4,64.71 183.4,74.86 179.1,79.17 177.32,79.17 174.45,82.04 163.7,82.04 151.29,94.45 148.26,94.45 142.28,100.43 139.87,100.43 138.28,102.03 138.28,102.35 136.49,104.14 136.32,104.14
  BOTTOM w0.076: v1(126.93,106.46) 126.93,106.47 126.65,106.18 UC1.AR7
  BOTTOM w0.102: v1(186.31,60.04) 186.14,59.87 185.33,59.87 184.15,58.68 165.95,58.68 161.12,53.85 131.21,53.85 126.63,49.27 40.05,49.27 32.18,57.14 23.73,57.14 23.44,57.43 LI2.1
USB20_JUSB1_N1_R: length 15
  IN3 w0.127: v1(18.26,57.28) 18.09,57.11 16.91,57.11 14.95,59.07 14.95,62.69 13.94,63.7 13.59,63.7 JUSB1.2
  BOTTOM w0.102: LI2.2 20.62,57.43 20.33,57.14 19.27,57.14 19.17,57.24 DI2.2 18.98,58 v1(18.26,57.28)
USB20_JUSB1_P1: length 259.5
  IN1 w0.084: v1(126.93,105.81) 126.94,105.81 127.27,105.48 127.27,104.45 127.62,104.1 128.92,104.1 130.09,105.26 132.23,105.26 132.32,105.36 132.97,105.36 134.23,104.1 136.01,104.1 136.22,103.89 136.29,103.89 136.31,103.87 136.32,103.87
  IN1 w0.127: 136.32,103.87 136.38,103.87 138.01,102.24 138.01,101.92 139.76,100.16 142.16,100.16 148.15,94.18 151.18,94.18 163.59,81.77 174.33,81.77 177.21,78.9 178.99,78.9 183.13,74.75 183.13,64.59 185.55,62.18 185.55,59.97 185.84,59.68 186.09,59.68 v1(186.31,59.45)
  BOTTOM w0.076: v1(126.93,105.81) 126.66,105.53 UC1.AT7
  BOTTOM w0.102: v1(186.31,59.45) 186.12,59.65 185.42,59.65 184.24,58.47 166.04,58.47 161.21,53.63 131.3,53.63 126.72,49.05 39.96,49.05 32.09,56.93 23.73,56.93 23.44,56.63 LI2.4
USB20_JUSB1_P1_R: length 15.2
  IN3 w0.127: JUSB1.3 12.69,63.03 13.11,63.45 13.83,63.45 14.7,62.58 14.7,58.96 16.8,56.86 18.1,56.86 v1(18.26,56.7)
  BOTTOM w0.102: LI2.3 20.62,56.63 20.33,56.93 19.27,56.93 19.17,56.82 DI2.3 18.89,56.07 v1(18.26,56.7)
USB20_JUSB2_N0: length 276.3
  IN1 w0.084: 136.63,102.47 136.62,102.48 136.62,102.51 136.57,102.56 136.57,102.59 135.53,103.63 133.96,103.63 133.44,104.15 132.1,104.15 131.44,104.82 130.56,104.82 129.45,103.71 127.29,103.71 126.92,104.07 126.92,104.99 126.36,105.55 126.36,107.53 126.03,107.86 125.82,107.86 125.58,107.61 v1(125.58,107.45)
  IN1 w0.127: 136.63,102.47 137.06,102.04 137.06,101.69 139.37,99.37 141.82,99.37 148.13,93.06 150.78,93.06 162.98,80.87 174.1,80.87 177.06,77.91 178.76,77.91 181.9,74.76 181.9,64.72 184.77,61.85 184.77,59.02 185.03,58.76 185.03,57.47 185.46,57.04 185.46,53.98 185.71,53.73 185.71,49.08 185.53,48.9 185.53,46.18 186.72,44.99 186.72,43.78 186.58,43.64 186.39,43.64 v1(186.23,43.79)
  BOTTOM w0.089: UC1.AN8 125.68,107.45 v1(125.58,107.45)
  BOTTOM w0.102: LI5.1 23.44,44.61 23.59,44.46 23.59,44.21 23.77,44.02 v2(24.86,44.02) 27.38,44.02 28.31,43.09 104.63,43.09 110,37.72 118.58,37.72 122.39,41.53 183.66,41.53 185.56,43.43 185.87,43.43 v1(186.23,43.79)
USB20_JUSB2_N0_R: length 10.8
  IN3 w0.127: v1(17.77,44.56) 17.6,44.39 16.61,44.39 14.82,46.18 13.51,46.18 JUSB2.2
  BOTTOM w0.102: v1(17.77,44.56) 18.44,45.24 DI5.2 18.66,44.48 18.76,44.38 19.68,44.38 19.74,44.31 20.33,44.31 20.62,44.61 LI5.2
USB20_JUSB2_P0: length 276.5
  IN1 w0.084: 136.82,102.66 135.63,103.86 134.05,103.86 133.53,104.38 132.2,104.38 131.53,105.05 130.47,105.05 129.3,103.88 127.36,103.88 127.1,104.15 127.1,105.06 126.53,105.63 126.53,107.6 126.1,108.03 125.69,108.03 v1(125.57,108.15)
  IN1 w0.127: v1(186.23,43.21) 186.39,43.37 186.69,43.37 186.99,43.67 186.99,45.11 185.8,46.29 185.8,48.79 185.98,48.97 185.98,53.85 185.73,54.1 185.73,57.16 185.3,57.59 185.3,58.87 185.04,59.13 185.04,61.96 182.17,64.83 182.17,74.88 178.87,78.18 177.17,78.18 174.21,81.14 163.09,81.14 150.89,93.34 148.24,93.34 141.94,99.64 139.49,99.64 137.33,101.8 137.33,102.15 136.82,102.66
  BOTTOM w0.076: UC1.AM8 125.91,107.81 v1(125.57,108.15)
  BOTTOM w0.102: v1(186.23,43.21) 185.65,43.21 183.75,41.31 122.48,41.31 118.67,37.5 109.91,37.5 104.54,42.87 28.22,42.87 27.29,43.81 25.14,43.81 25.12,43.79 24.59,43.79 24.58,43.81 LI5.4
USB20_JUSB2_P0_R: length 10.9
  IN3 w0.127: v1(17.77,43.98) 17.61,44.14 16.5,44.14 14.72,45.92 13.61,45.92 JUSB2.3
  BOTTOM w0.102: LI5.3 20.69,43.81 20.39,44.1 19.65,44.1 19.59,44.16 18.76,44.16 18.66,44.06 DI5.3 18.44,43.3 v1(17.77,43.98)
USB20_JUSB3_N2: length 283.8
  IN1 w0.084: 136.27,101.49 136.29,101.51 136.27,101.52 136.27,101.55 136.29,101.56 136.29,102.19 135.94,102.54 135.38,102.54 135.12,102.28 133.82,102.28 132.97,103.13 132.97,103.13 132.54,103.57 130.55,103.57 130.26,103.27 126.34,103.27 125.9,103.71 125.9,105.39 125.86,105.43 v1(125.76,105.43)
  IN1 w0.127: v1(186.27,41.41) 186.62,41.41 186.71,41.51 186.71,41.8 186.23,42.28 185.91,42.28 184.68,43.51 184.68,52.01 184.49,52.2 184.49,56.91 184.02,57.38 184.02,58.22 183.43,58.81 183.43,61.72 180.43,64.72 180.43,71.35 180.76,71.68 180.76,74.37 178.05,77.09 176.03,77.09 173.12,80 162.7,80 150.76,91.94 148.14,91.94 141.49,98.59 139.05,98.59 136.27,101.37 136.27,101.49
  BOTTOM w0.076: v1(125.76,105.43) 125.76,105.64 UC1.AR8
  BOTTOM w0.102: LI7.1 21.22,27.91 21.43,27.7 21.43,27.38 21.49,27.32 21.7,27.32 21.85,27.47 21.85,27.69 22.71,28.55 26.53,28.55 27.23,29.25 30.8,29.25 31.38,29.82 33.5,31.94 43.92,42.37 104.03,42.37 109.38,37.02 119.81,37.02 123.62,40.83 186.34,40.83 186.68,41.17 186.68,41.33 186.59,41.41 v1(186.27,41.41)
USB20_JUSB3_N2_R: length 11.4
  BOTTOM w0.102: LI7.2 18.53,27.91 18.23,27.61 18.08,27.61 17.74,27.96 17.41,27.96 17.12,28.25 DI7.2 16.79,28.86 16.59,28.66 16.59,28.08 16.46,27.96 16.34,27.96 16.25,28.05 16.25,28.24 15.62,28.87 13.72,28.87 13.35,28.51 v2(13.01,28.51) 11.21,28.51 JUSB3.2
USB20_JUSB3_P2: length 284
  IN1 w0.084: 136.55,101.62 136.52,101.65 136.52,102.28 136.03,102.77 135.28,102.77 135.03,102.51 133.92,102.51 133.2,103.23 132.64,103.79 130.46,103.79 130.16,103.5 126.43,103.5 126.13,103.81 126.13,105.64 v1(125.58,106.18)
  IN1 w0.127: 136.55,101.62 136.55,101.48 139.16,98.86 141.61,98.86 148.25,92.21 150.87,92.21 162.81,80.27 173.23,80.27 176.15,77.36 178.16,77.36 181.03,74.48 181.03,71.56 180.7,71.23 180.7,64.83 183.7,61.83 183.7,58.92 184.29,58.33 184.29,57.49 184.76,57.02 184.76,52.31 184.95,52.12 184.95,43.62 186.02,42.56 186.34,42.56 186.98,41.91 186.98,41.47 v1(187.1,41.35)
  BOTTOM w0.076: v1(125.58,106.18) 125.9,106.51 UC1.AP8
  BOTTOM w0.102: v1(187.1,41.35) 186.91,41.16 186.91,41.1 186.43,40.61 123.71,40.61 119.9,36.8 109.29,36.8 103.94,42.15 44.01,42.15 33.65,31.79 31.53,29.67 30.89,29.03 27.32,29.03 26.62,28.33 22.79,28.33 22.27,27.81 22.07,27.6 22.07,27.38 21.79,27.11 LI7.4
USB20_JUSB3_P2_R: length 11.4
  BOTTOM w0.102: JUSB3.3 11.21,28.29 12.73,28.29 12.74,28.28 13.27,28.28 13.28,28.29 13.44,28.29 13.81,28.66 15.53,28.66 16.03,28.15 16.03,27.96 16.25,27.74 16.52,27.74 16.59,27.68 16.59,27.07 16.73,26.93 DI7.3 17.12,27.47 17.39,27.74 17.65,27.74 17.99,27.4 18.3,27.4 18.59,27.11 LI7.3
USB20_MINI1_N4: length 58.4
  IN3 w0.084: 116.21,130.68 116.18,130.65 116.18,130.33 115.6,129.74 115.6,127.26 115.28,126.95 115.28,123.12 116.49,121.92 116.49,120.87 117.19,120.17 117.19,119.41 118.97,117.63 118.97,115.66 119.55,115.08 120.16,115.08 121.63,113.61 121.63,110.18 122.53,109.29 122.53,108.01 122.13,107.61 121.89,107.61 v1(121.76,107.48)
  IN3 w0.127: 116.21,130.68 116.21,133.26 121.5,138.55 121.5,144.74 119.78,146.47 119.3,146.47 119.15,146.61 119.15,146.87 v1(119.24,146.95)
  BOTTOM w0.076: v1(121.76,107.48) 122.09,107.81 UC1.AM15
  BOTTOM w0.102: v1(119.24,146.95) 119.09,146.8 119.09,146.52 118.81,146.24 111.09,146.24 110.62,146.71 110.62,146.96 110.5,147.08 JMINI.36
USB20_MINI1_P4: length 58.1
  IN3 w0.084: 115.95,130.75 115.95,130.74 115.97,130.72 115.97,130.41 115.39,129.83 115.39,127.35 115.07,127.04 115.07,123.03 116.28,121.83 116.28,120.78 116.98,120.08 116.98,119.32 118.76,117.54 118.76,115.57 119.46,114.87 120.07,114.87 121.42,113.52 121.42,110.09 122.32,109.2 122.32,108.1 122.04,107.82 121.92,107.82 121.76,107.98 v1(121.76,108.13)
  IN3 w0.127: 115.95,130.75 115.95,133.36 121.25,138.66 121.25,144.64 119.67,146.21 119.19,146.21 118.9,146.51 118.9,146.7 118.65,146.95 v1(118.65,146.95)
  BOTTOM w0.076: v1(121.76,108.13) 122,108.13 122.14,108.28 UC1.AL15
  BOTTOM w0.102: JMINI.38 111.3,147.14 111.24,147.08 110.9,147.08 110.84,147.01 110.84,146.8 111.18,146.45 118.72,146.45 118.88,146.61 118.88,146.76 118.69,146.95 v1(118.65,146.95)
USB20_TOUCH_N5: length 113.6
  TOP w0.102: JTOUCH.2 22.91,97.53 22.62,97.82 22.62,99 23.23,99.62 23.23,101.01 23.74,101.52 v2(34.01,101.52) 52.58,101.52 52.73,101.37 52.73,101.16 v1(52.55,100.98)
  IN1 w0.084: v1(123.14,108.37) 122.95,108.18 122.66,108.18 122.42,108.42 122.42,109.4 122.11,109.71 122.11,110.4 121.47,111.05 118.9,111.05 118.44,110.59 117.44,110.59 117.13,110.28 116.26,110.28 115.24,111.3 97.62,111.3 96.35,110.03 90.65,110.03 90.46,110.22 88.49,110.22 88.49,110.22 86.18,110.22 86.16,110.24 86.08,110.24
  IN1 w0.127: 86.08,110.24 84.91,110.24 83.4,108.74 78.59,108.74 76.83,106.97 73.04,106.97 72.23,106.17 67.07,106.17 66.47,105.57 65.53,105.57 64.04,104.08 55.07,104.08 52.7,101.71 52.7,101.13 v1(52.55,100.98)
  BOTTOM w0.089: v1(123.14,108.37) 122.9,108.13 UC1.AM13
USB20_TOUCH_P5: length 113.9
  TOP w0.102: JTOUCH.3 22.11,97.53 22.4,97.82 22.4,99.09 23.02,99.71 23.02,101.1 23.65,101.74 33.74,101.74 33.75,101.75 34.28,101.75 34.29,101.74 52.67,101.74 52.95,101.46 52.95,101.16 v1(53.13,100.98)
  IN1 w0.084: 86.08,109.97 86.1,109.99 88.39,109.99 88.39,109.99 90.36,109.99 90.55,109.8 96.45,109.8 97.72,111.07 115.15,111.07 116.16,110.06 117.23,110.06 117.54,110.37 118.54,110.37 118.99,110.82 121.38,110.82 121.89,110.31 121.89,109.61 122.2,109.3 122.2,108.32 122.57,107.95 122.9,107.95 v1(123.13,107.72)
  IN1 w0.127: v1(53.13,100.98) 52.98,101.13 52.98,101.6 55.19,103.81 64.15,103.81 65.65,105.3 66.58,105.3 67.18,105.9 72.35,105.9 73.15,106.7 76.94,106.7 78.7,108.46 83.51,108.46 85.02,109.97 86.08,109.97
  BOTTOM w0.076: v1(123.13,107.72) 122.93,107.72 UC1.AN13
USB20_USBDB_N3: length 147.9
  TOP w0.102: v1(199.9,33.35) 203.17,33.35 203.55,33.73 203.55,39.33 204.73,40.51 204.73,42.48 203.94,43.27 v2(203.94,45.1) 203.94,48.28 204.77,49.12 LI10.1
  IN1 w0.084: v1(125.01,105.81) 125.01,105.68 125.38,105.32 125.38,105.12 125.66,104.83 125.66,103.61 126.24,103.03 129.86,103.03 130.14,102.75 132.87,102.75 133.63,102 134.33,102 134.64,101.69 134.67,101.69 134.72,101.64 134.75,101.64 134.86,101.53 134.91,101.48 134.91,101.45
  IN1 w0.127: v1(199.9,33.35) 199.81,33.26 198.75,33.26 198.38,33.63 193.81,33.63 192.41,32.23 188.47,32.23 187.49,33.21 187.49,34.07 186.63,34.93 186.63,37.28 187.14,37.79 187.14,39.75 184.15,42.74 184.15,48.32 183.63,48.83 183.63,52.17 183.49,52.31 183.49,57.92 182.92,58.49 182.92,61.43 179.48,64.87 179.48,71.43 177.97,72.93 177.97,73.4 172.23,79.14 162.67,79.14 151.21,90.6 148.76,90.6 141.28,98.08 138.77,98.08 135.92,100.92 135.44,100.92 134.91,101.45
  BOTTOM w0.076: 124.99,105.81 124.78,105.81 124.62,105.97 124.62,106.18 ; 124.99,105.81 v1(125.01,105.81) ; 124.99,105.81 124.62,106.18 ; 124.62,106.18 UC1.AR10
USB20_USBDB_N3_R: length 3.7
  TOP w0.102: LI10.2 207.65,49.12 207.95,48.82 208.04,48.82 208.52,49.31 v2(209.11,49.31) 209.59,49.31 209.99,49.7 JDB.5
USB20_USBDB_P3: length 147.6
  TOP w0.102: LI10.4 205.13,48.31 205.04,48.4 205.04,48.83 204.98,48.9 204.86,48.9 204.16,48.19 204.16,45.37 204.17,45.36 204.17,44.83 204.16,44.82 204.16,43.36 204.94,42.57 204.94,40.42 203.76,39.24 203.76,33.64 203.26,33.14 200.27,33.14 v1(199.9,32.77)
  IN1 w0.084: 134.57,101.44 134.24,101.77 133.53,101.77 132.78,102.52 130.05,102.52 129.77,102.8 126.15,102.8 125.43,103.52 125.43,104.74 v1(125.01,105.16)
  IN1 w0.127: 134.57,101.44 134.59,101.42 134.64,101.37 134.64,101.34 135.33,100.65 135.81,100.65 138.65,97.81 141.17,97.81 148.64,90.33 151.1,90.33 162.56,78.87 172.12,78.87 177.7,73.29 177.7,72.82 179.21,71.31 179.21,64.76 182.65,61.31 182.65,58.38 183.22,57.81 183.22,52.2 183.36,52.06 183.36,48.72 183.87,48.2 183.87,42.63 186.87,39.63 186.87,37.91 186.36,37.39 186.36,34.81 187.22,33.95 187.22,33.1 188.35,31.96 192.52,31.96 193.92,33.36 198.26,33.36 198.63,32.99 199.68,32.99 v1(199.9,32.77)
  BOTTOM w0.076: v1(125.01,105.16) 124.64,105.53 UC1.AT10
USB20_USBDB_P3_R: length 3.7
  TOP w0.102: JDB.4 209.88,48.7 209.51,49.08 208.61,49.08 208.14,48.61 207.97,48.61 207.67,48.31 LI10.3
USB_EN#: length 265
  TOP w0.102: UI5.4 207.82,41.33 208.12,41.03 208.64,41.03 CI25.1 211.56,41.46 v3(212.97,40.05) 213.45,39.57 v1(213.45,38.94) ; v1(193.07,33.86) 193.19,33.97 UE1.26 ; v1(27.02,66.24) 25.81,65.03 CI13.1 26.27,64.23 26.27,63.55 26.1,63.38 UI3.4 ; UI4.4 20.96,32.93 v1(21.51,33.48) 21.51,34.06 22.19,34.75 CI16.1 ; CI26.1 30.64,55 30.45,55.19 v1(29.81,55.19) 29.56,55.19 29.24,54.87 29.24,54.24 29.01,54.01 UI2.4
  IN1 w0.127: v1(187.58,49.41) 189.5,47.5 189.5,40.65 188.93,40.08 188.93,39.2 188.14,38.42 188.14,35.74 189.64,34.24 192.69,34.24 v1(193.07,33.86) ; v1(61.97,47.33) 58.65,44.02 v1(28.46,44.02)
  IN3 w0.127: v1(21.51,33.48) 22.32,33.48 28.46,39.62 v1(28.46,44.02) 28.46,53.85 v1(29.81,55.19) 29.81,57.61 28.98,58.43 28.98,64.27 v1(27.02,66.24) ; v1(213.45,38.94) 212.98,38.47 202.63,38.47 199.67,35.51 197.7,35.51 196.85,34.66 196.85,34.01 196.16,33.32 194.05,33.32 193.51,33.86 v1(193.07,33.86) ; v1(61.97,47.33) 62.16,47.14 114.78,47.14 115.24,46.68 141.47,46.68 141.6,46.81 168.61,46.81 168.82,47.03 177.83,47.03 179.01,48.21 185.18,48.21 186.38,49.41 v1(187.58,49.41)
USB_OC0#: length 178.6
  TOP w0.089: 135.59,101.44 135.03,102.01 135.03,103.64 v3(134.59,104.09) 132.77,105.9 v1(131.6,105.9)
  TOP w0.102: RP55.1 139.59,97.88 138.95,98.51 138.52,98.51 135.59,101.44 ; UI3.5 20.38,63.38 20.22,63.54 20.22,64.34 CI15.1 20.51,66.65 21.68,67.82 31.02,67.82 32.15,68.95 v1(32.15,69.02) 32.96,68.21 32.96,57.71 32.21,56.96 25.4,56.96 CI17.1 23.21,54.76 23.21,54.18 23.37,54.01 UI2.5
  IN2 w0.089: 132.01,101.56 132.01,102.73 131.82,102.91 131.82,105.01 131.6,105.23 v1(131.6,105.9) v1(131.6,107.72)
  IN2 w0.127: 132.01,101.56 132.01,97.91 130.11,96.01 127.02,96.01 126.9,95.89 124.39,95.89 113.03,84.53 59.46,84.53 45.49,70.56 33.68,70.56 v1(32.15,69.02)
  BOTTOM w0.076: UC1.AL3 129.19,108.56 129.44,108.31 131.01,108.31 v1(131.6,107.72)
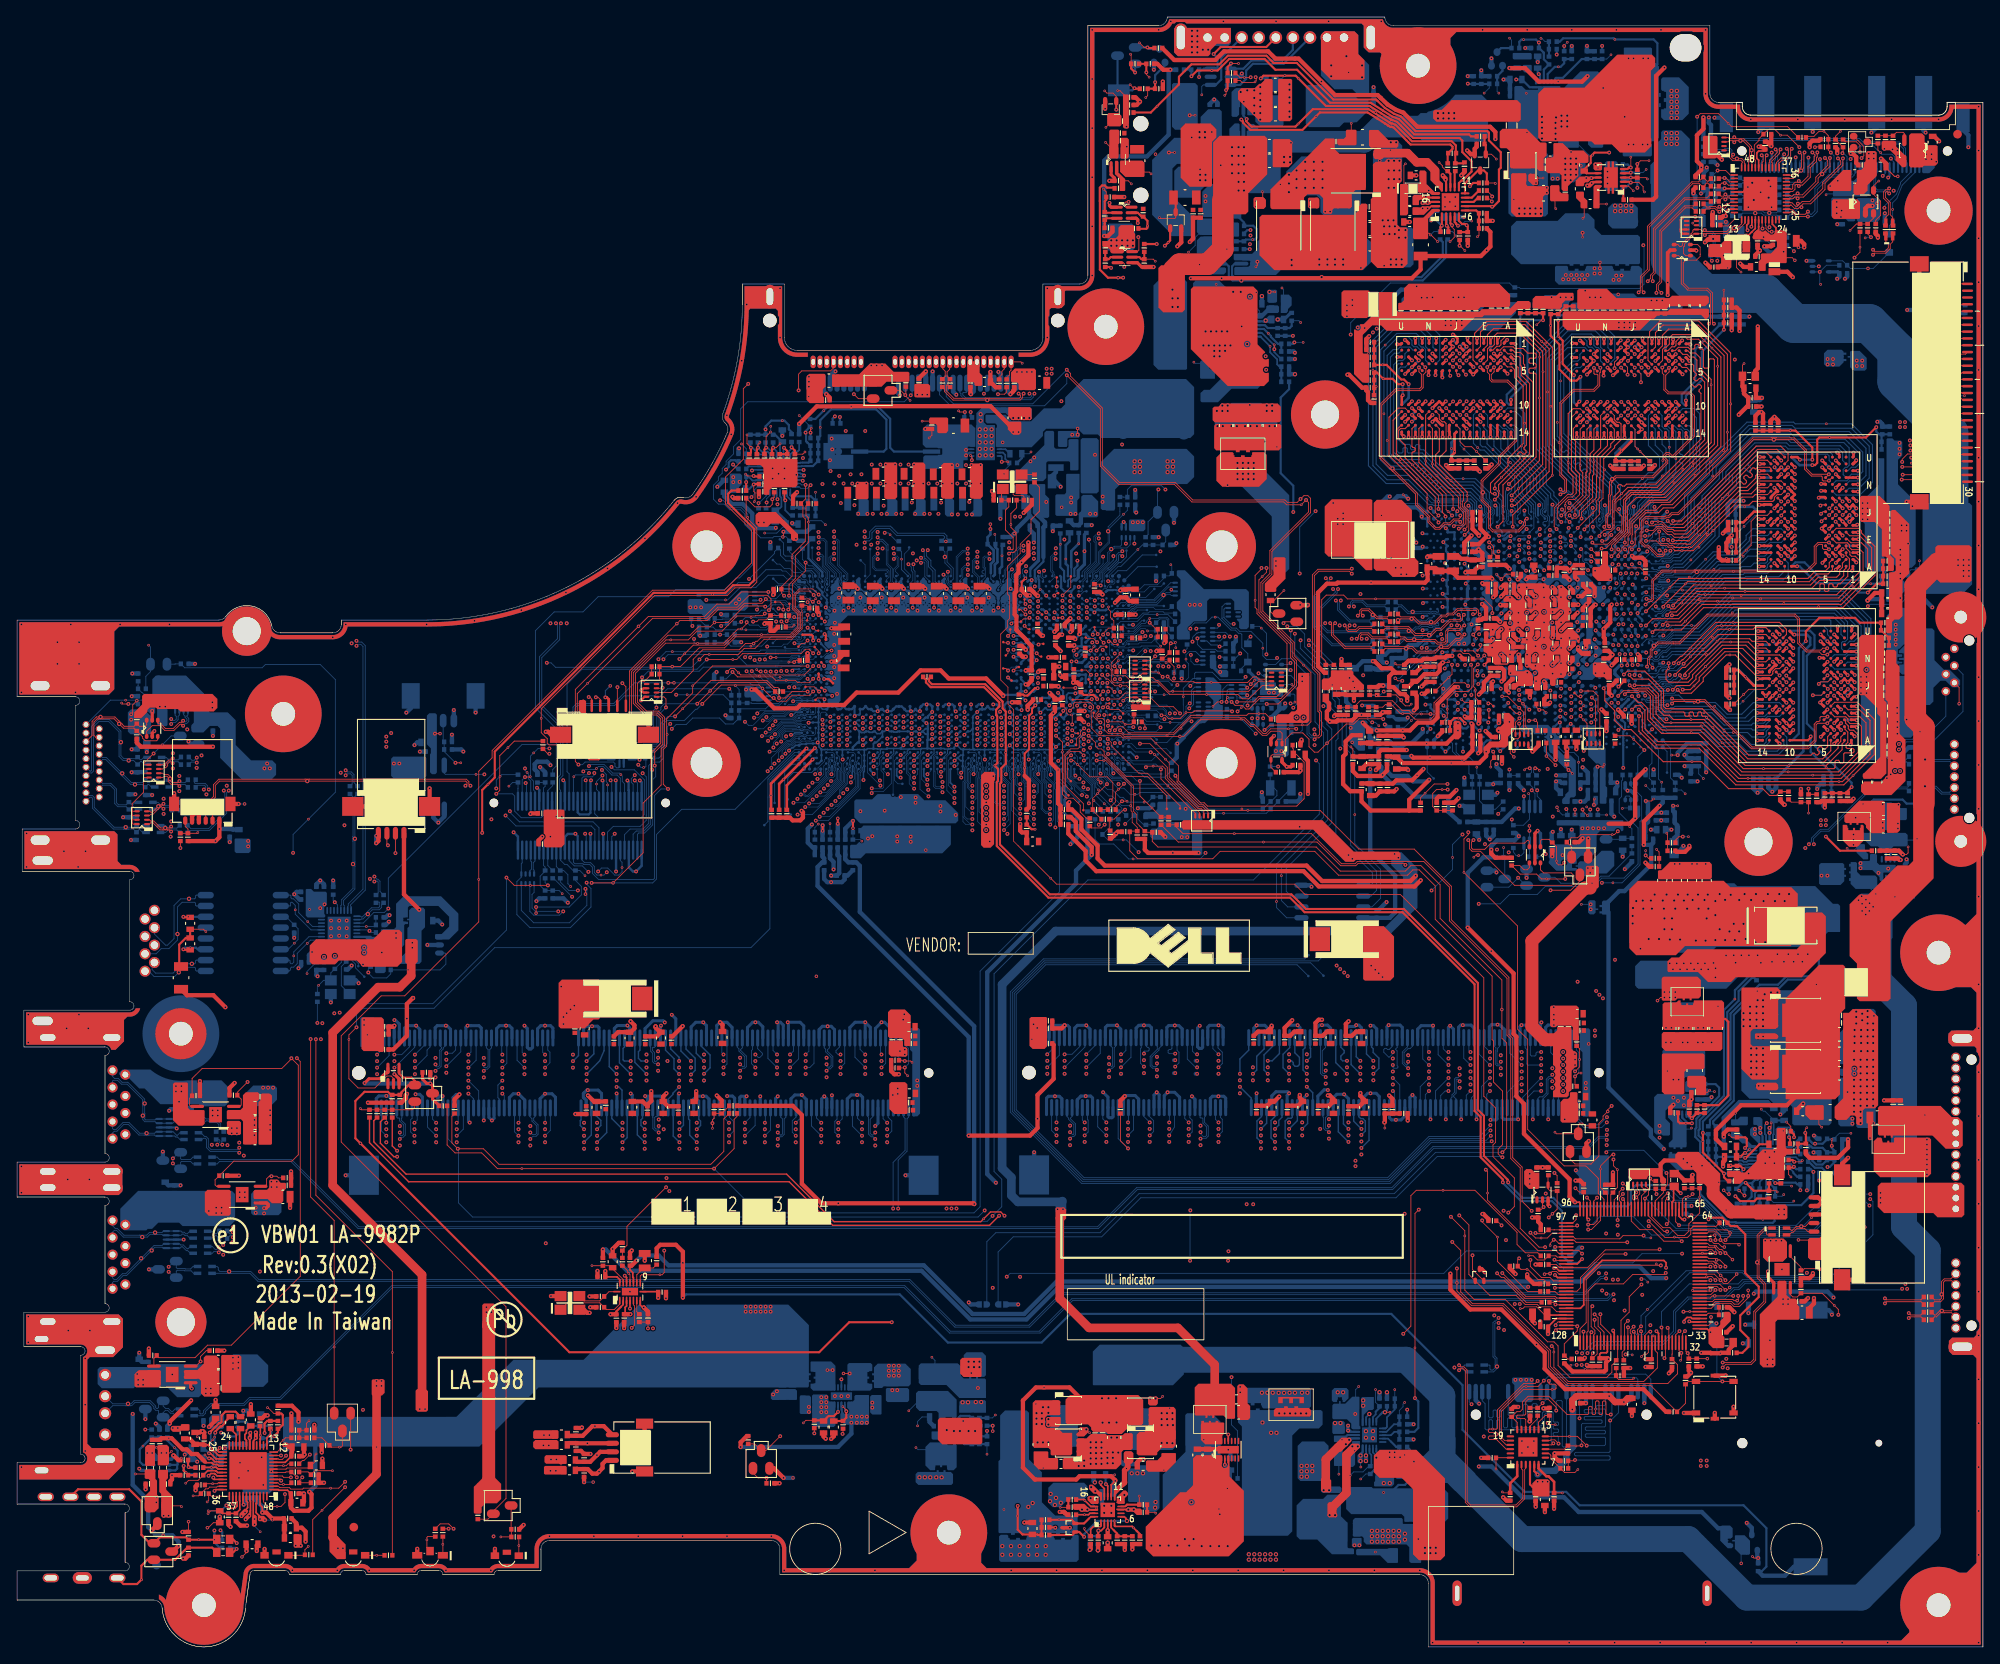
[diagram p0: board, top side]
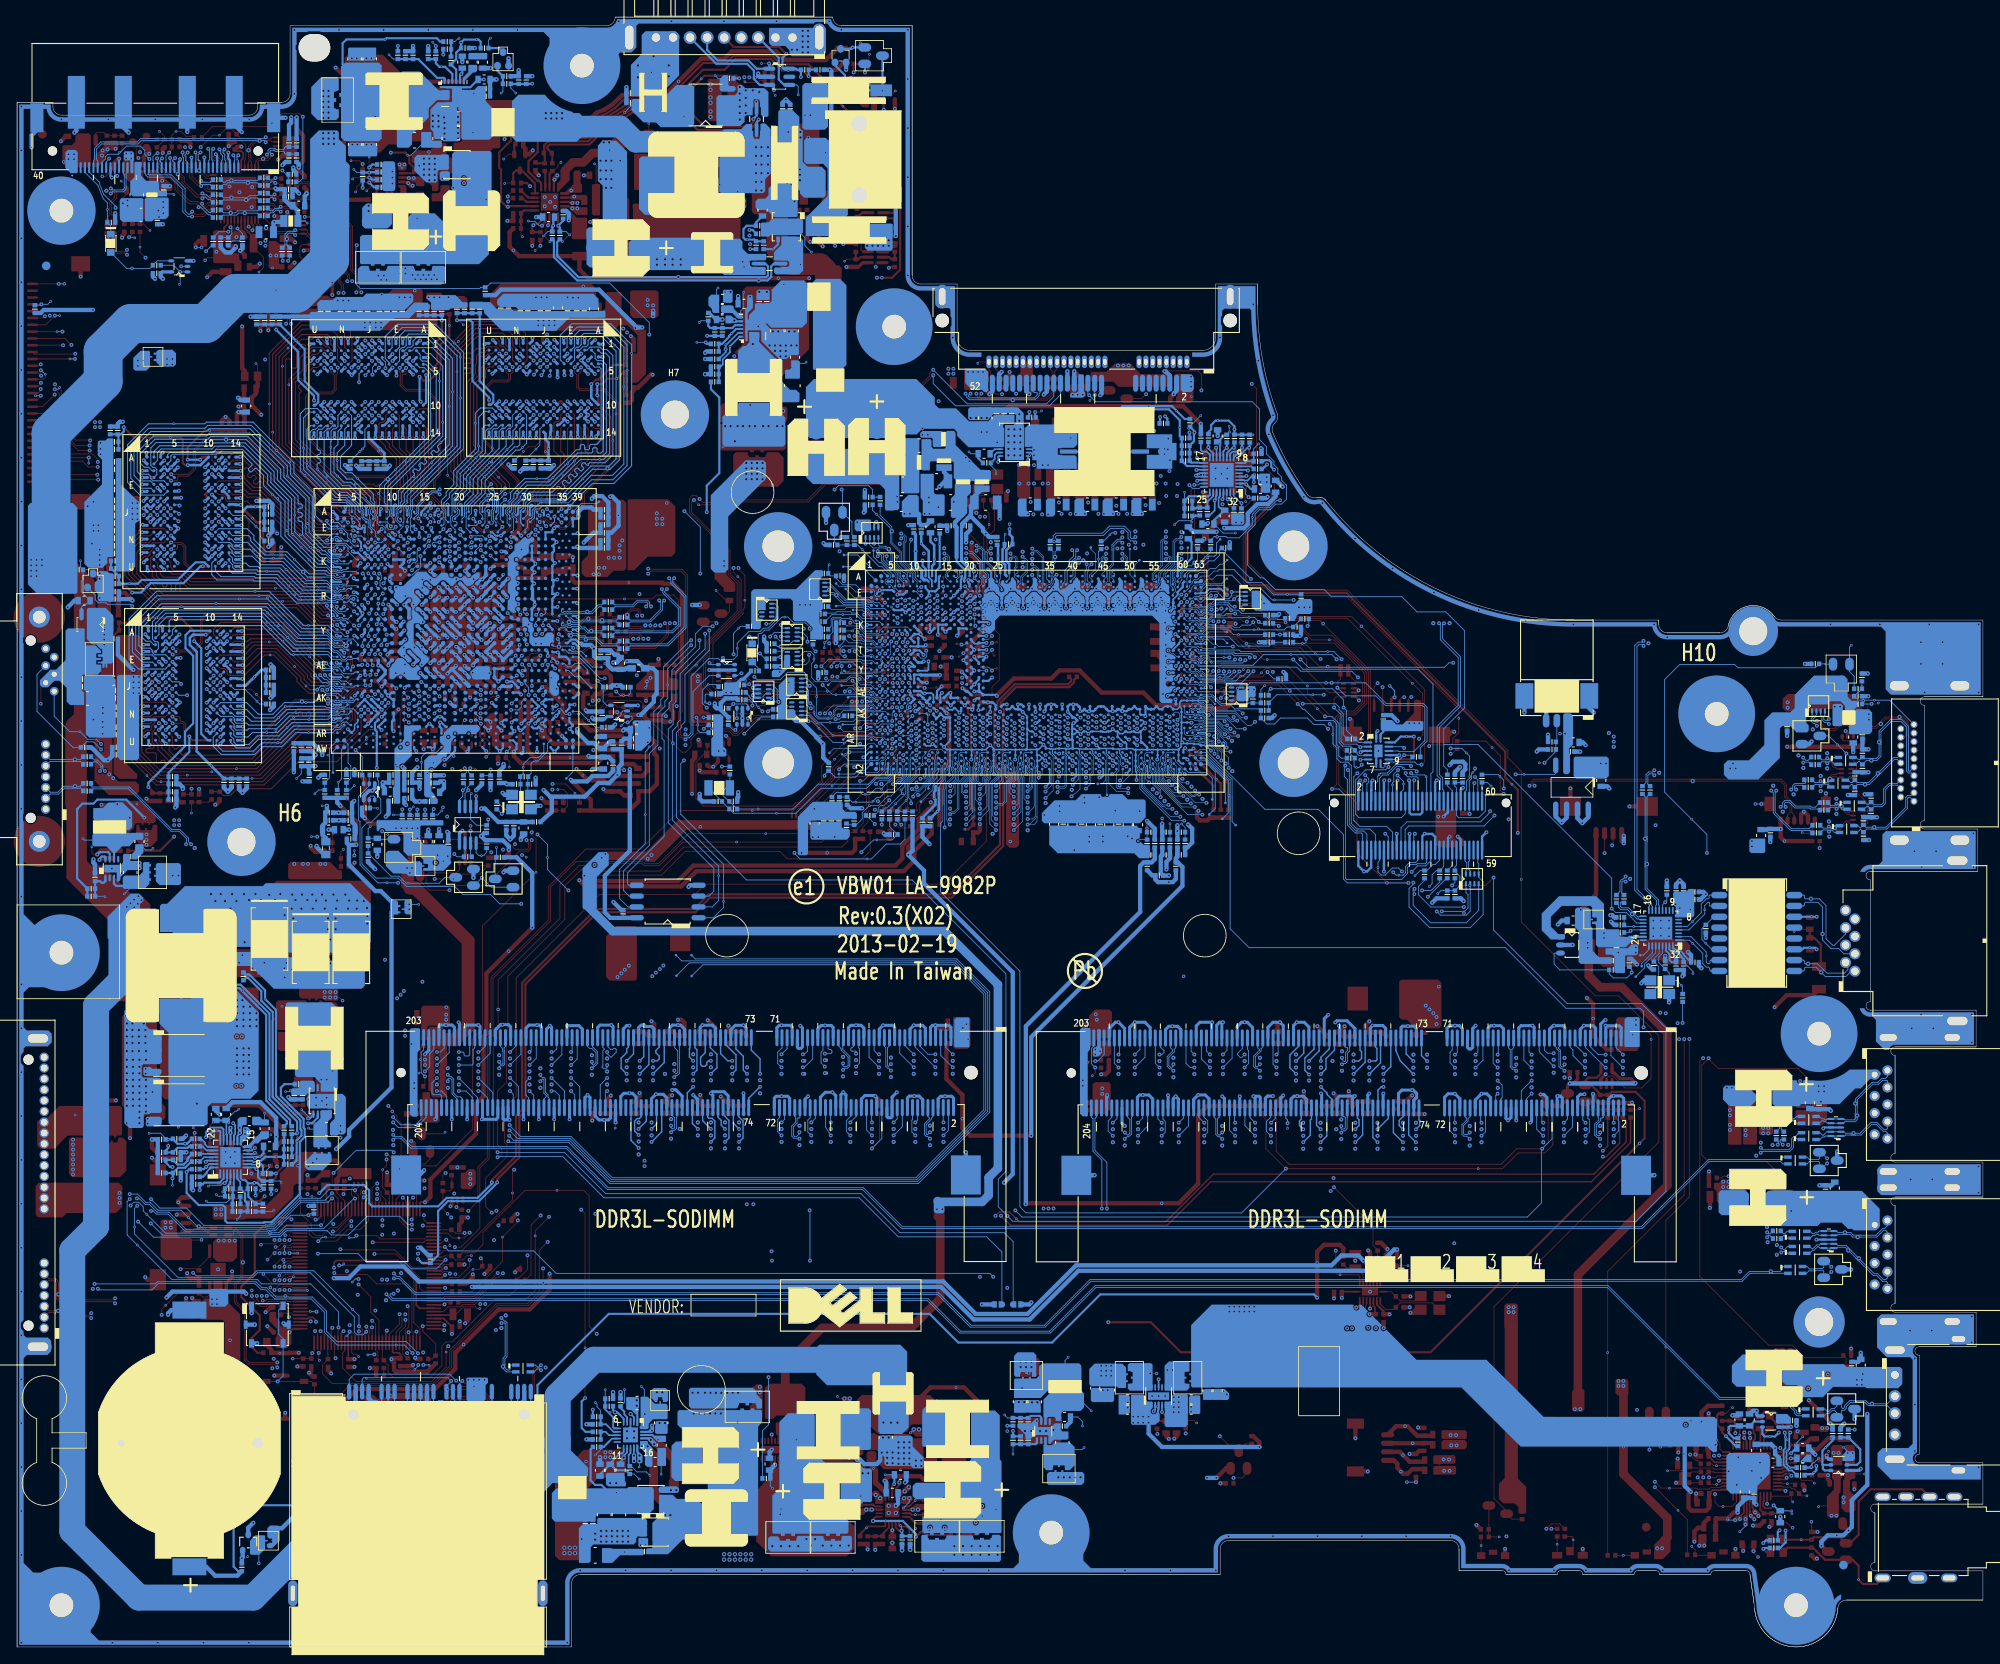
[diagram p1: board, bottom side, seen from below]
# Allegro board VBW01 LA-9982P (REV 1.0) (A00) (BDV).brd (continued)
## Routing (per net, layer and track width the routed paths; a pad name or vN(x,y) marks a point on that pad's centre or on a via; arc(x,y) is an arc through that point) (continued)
USB_OC1#: length 322
  TOP w0.089: 135.27,101.44 134.8,101.91 134.8,103.14 v3(133.3,104.64) 133.04,104.9 v1(132.86,104.9)
  TOP w0.102: 135.27,101.44 138.43,98.28 138.8,98.28 139.09,98 RP55.2 ; UI4.5 16.04,33.85 CI24.1 16.62,33.92 20.86,33.92 22.32,35.38 25.11,35.38 33.19,43.46 33.19,68.64 v1(32.79,69.04) ; UI5.5 207.82,45.77 209.07,44.52 CI32.1 209.3,44.16 209.5,44.36 211.17,44.36 v1(211.23,44.3)
  IN2 w0.089: v1(132.86,104.9) 132.76,104.8 132.76,102.82 132.26,102.32 132.26,101.44
  IN2 w0.127: 132.26,101.44 132.26,97 127.47,92.21 121.43,92.21 113.24,84.02 59.67,84.02 45.7,70.05 33.81,70.05 v1(32.79,69.04) ; v1(141.98,46.39) 142.21,46.62 142.21,73.12 140.17,75.15 140.17,96.78 134.51,102.45 134.51,103.9 133.45,104.95 132.91,104.95 v1(132.86,104.9)
  IN3 w0.127: v1(211.23,44.3) 211.07,44.45 207.62,44.45 207.02,43.85 206.67,43.85 206.07,44.45 205.02,44.45 204.53,43.96 198.32,43.96 197.12,45.16 194.35,45.16 193.42,46.1 190.68,46.1 190.01,46.76 188.23,46.76 186.97,45.5 184.85,45.5 184.28,44.93 182.89,44.93 180.5,47.32 179.93,47.32 179.66,47.58 178.76,47.58 177.77,46.59 168.87,46.59 168.49,46.21 142.16,46.21 v1(141.98,46.39)
  BOTTOM w0.076: v1(132.86,104.9) 132.83,104.93 131.06,104.93 130.43,105.56 UC1.AT1
USB_OC2#: length 24.1
  TOP w0.089: v1(132.3,103.15) 132.43,103.27 v3(133.15,103.27) 134.26,103.27 134.57,102.96 134.57,101.83 134.95,101.44
  TOP w0.102: 134.95,101.44 134.95,101.44 138.59,97.8 RP55.3
  IN2 w0.089: v1(132.3,103.15) 132.24,103.21 132.24,105.1 135.71,108.58 v1(135.71,109.46)
  BOTTOM w0.076: v1(135.71,109.46) 134.74,110.43 130.59,110.43 130.47,110.56 130.09,110.56 130.08,110.54 130.07,110.54 UC1.AH2
USB_OC3#: length 12.8
  TOP w0.089: 134.39,101.44 134.06,101.77 134.06,102.9 v1(134.06,102.9)
  TOP w0.102: RP55.4 138.09,97.74 v3(134.88,100.95) 134.39,101.44
  BOTTOM w0.076: UC1.AV3 129.15,104.25 129.48,103.92 130.13,103.92 130.14,103.91 130.44,103.91 130.84,103.52 133.19,103.52
  BOTTOM w0.089: v1(134.06,102.9) 134.06,102.9 134.06,102.91 133.46,103.52 133.19,103.52
USBRBIAS: length 5.1
  TOP w0.076: v1(123.66,108.15) 123.66,109.19 v3(123.57,109.28) 123.22,109.28 123.03,109.47 123.03,109.89 RC90.1
  BOTTOM w0.076: UC1.AJ11 UC1.AJ10
  BOTTOM w0.089: v1(123.66,108.15) 123.66,109.29 UC1.AJ11
VCIN0_PH: length 133.6
  TOP w0.203: UE1.109 182.85,44.91 v1(183.42,45.48)
  TOP w0.254: PH1.1 106.52,113.41 106.52,113.09 107.08,112.53 113.33,112.53 115.12,110.74 115.12,110.28 114.75,109.9 114.75,109.26 114.87,109.13 114.87,107.22 114.89,107.21 114.89,103.63 114.6,103.34 v3(114.6,103.31) 114.96,102.94 114.96,101.55 114.82,101.41 114.82,93.91 120.88,87.86 149.19,87.86 150.9,86.14 162.38,86.14 170.82,77.7 170.82,62.83 171.53,62.12 171.53,57.41 174.13,54.81 v1(174.13,54.48)
  BOTTOM w0.254: v1(174.13,54.48) 174.13,54.4 176.26,52.27 179.89,52.27 181.05,51.11 181.05,45.92 PR24.1 182.96,45.02 v1(183.42,45.48)
VCIN1_PH: length 165.8
  TOP w0.102: PR26.2 129.94,181.79 129.26,182.47 v3(128.99,182.47) ; v1(188.71,47.45) 182.72,47.45 182.46,47.71 UE1.102
  IN2 w0.254: v1(188.71,47.45) 188.71,48.97 189.13,49.38 189.13,65.31 187.98,66.46 187.98,75.82 183.14,80.66 182.7,80.66 163.06,100.3 163.06,101.15 162.03,102.18 161.47,102.18 159.87,103.78 158.98,103.78 154.86,107.9 154.86,110.73 152.78,112.81 152.78,117.36 148.85,121.3 148.85,128.75 139.47,138.12 139.47,139.33 132.32,146.48 132.32,166.69 129.2,169.81 129.2,177.43 v1(130.03,178.26)
VCOUT0_PH#: length 102.3
  TOP w0.102: v1(180.26,46.9) 181.55,46.9 UE1.104
  TOP w0.254: v1(117.28,16.53) v3(117.28,15.35) 117.28,13.75 117.83,13.19 PC100.1 119.6,13.19 119.66,13.13 PR100.2 PR102.2 PR101.2
  IN1 w0.102: v1(115.99,43.41) 115.71,43.13 115.71,18.1 v1(117.28,16.53)
  BOTTOM w0.102: v1(115.99,43.41) 116.39,43.8 167.21,43.8 169.84,46.43 179.8,46.43 v1(180.26,46.9)
VCOUT1_PH: length 175.3
  TOP w0.102: RE47.2 178.6,51.27 v1(178.91,51.57) 178.78,51.7 UE2.2 ; v3(179.68,47.06) 179.68,47.32 v1(180.1,47.74) 180.26,47.74 180.7,47.31 UE1.103
  TOP w0.254: v1(128.22,161.69) 128.11,161.8 PR30.1
  IN1 w0.127: v1(184.93,72.28) 185.45,71.76 185.45,69.64 184.5,68.69 184.5,66.98 185.53,65.95 185.53,64.09 187.08,62.53 187.08,58.53 186.68,58.12 186.68,57.43 186.62,57.36 186.62,54.43 186.74,54.3 186.74,49.3 187.61,48.44 v1(187.61,48.33) ; v1(180.1,47.74) 179.78,48.06 179.75,48.06 178.91,48.91 v1(178.91,51.57)
  IN3 w0.127: v1(180.1,47.74) 187.01,47.74 v1(187.61,48.33) ; v1(128.22,161.69) 128.22,160.42 130.44,158.2 130.44,135.21 131.71,133.94 147.03,133.94 153.87,127.1 156.73,127.1 159.48,124.35 159.48,117.89 155.73,114.14 155.73,112.98 156.3,112.41 157.61,112.41 158.89,111.12 159.3,111.12 160.94,109.48 160.94,107.13 162.14,105.93 163.37,105.93 166.21,103.09 166.21,99.84 169.33,96.71 172.93,96.71 176.26,93.39 176.26,92.86 181.6,87.52 181.6,82.56 186.85,77.31 186.85,74.2 v1(184.93,72.28)
VGA_CLKREQ#_R: length 23.2
  TOP w0.102: v1(187.61,95.63) 187.21,95.24 v3(186.96,95.24) 183.28,95.24 182.91,94.87 182.13,94.87 RV199.2 182.2,93.79 QV28.3
  IN3 w0.102: v1(184.49,108.4) 184.93,107.97 184.93,106.33 185.32,105.94 185.32,104.21 185.84,103.69
  IN3 w0.127: v1(187.61,95.63) 187.61,98.35 185.93,100.03 185.93,103.6 185.84,103.69
  BOTTOM w0.102: v1(184.49,108.4) 184.79,108.69 UV1.AN13
VGA_SMB_CK2: length 21.4
  TOP w0.102: v1(181.32,91.95) 181.07,91.7 180.63,91.7 180.43,91.9 v3(180.43,92.13) 180.43,93.81 RV90.2 179.55,94.68 178.71,94.68 178.54,94.51 QV15.1
  IN3 w0.127: v1(178.16,100.44) 178.02,100.3 178.02,98.17 179.41,96.78 179.41,95.32 180.62,94.11 180.62,91.36 181.08,90.9 181.38,90.9 181.51,91.03 181.51,91.76 v1(181.32,91.95)
  BOTTOM w0.102: UV14.8 178.55,99.36 178.16,99.75 v1(178.16,100.44) 177.86,100.74 177.86,101.06 RV252.1
VGA_SMB_CK2_R: length 12.1
  TOP w0.102: v3(178.41,102.79) 178.17,103.03 v1(177.92,103.03)
  IN3 w0.102: v1(176.06,111.61) 175.65,111.2 175.65,108.04 176.09,107.6
  IN3 w0.127: 176.09,107.6 176.12,107.6 177.19,106.53 177.19,104.76 177.71,104.24 177.71,103.24 v1(177.92,103.03)
  BOTTOM w0.102: v1(177.92,103.03) 177.72,102.82 177.72,102.55 RV252.2 ; v1(176.06,111.61) 176.34,111.89 UV1.AJ23
VGA_SMB_DA2: length 25.2
  TOP w0.102: v1(181.45,90.05) v3(179.27,90.05) 178.65,90.05 178.08,90.62 176.16,90.62 RV91.2 176.11,91.62 176.61,91.13 177,91.13 177.24,91.37 QV15.4
  IN3 w0.127: v1(181.45,90.05) 181.45,90.49 181.29,90.65 180.97,90.65 180.37,91.25 180.37,94.01 179.16,95.21 179.16,96.67 177.76,98.07 177.76,100.2 v1(177.52,100.44)
  BOTTOM w0.102: UV14.7 177.9,100.07 177.52,100.44 v1(177.52,100.44) 177.64,100.56 177.64,100.77 RV251.1
VGA_SMB_DA2_R: length 12.8
  TOP w0.102: v3(176.67,102.84) 176.86,103.03 v1(177.29,103.03)
  IN3 w0.102: v1(176.02,112.2) 175.42,111.6 175.42,107.94 175.99,107.37
  IN3 w0.127: 175.99,107.37 176.94,106.42 176.94,104.65 177.46,104.13 177.46,103.2 v1(177.29,103.03)
  BOTTOM w0.102: UV1.AH23 176.02,112.25 v1(176.02,112.2) ; v1(177.29,103.03) 177.49,102.82 177.49,102.55 RV251.2
VGA_X1_R: length 2.4
  TOP w0.102: UG1.12 71.83,43.65 v3(71.69,43.79) 71.57,43.91 71.57,44.08 RG4.1
VL: length 3.7
  TOP w0.203: PU100.13 127.83,18.87 v1(127.61,19.09)
  BOTTOM w0.102: v3(128.64,20.18) PC106.1
  BOTTOM w0.254: v1(127.61,19.09) 127.58,19.13 PC106.1
VR12.5_VR_ON_R: length 2.6
  TOP w0.089: v3(93.61,122.91) 93.26,122.57 v1(93.26,122.55) 93.13,122.55 92.81,122.88 92.12,122.88 R250.2
  BOTTOM w0.076: v1(93.26,122.55) 93.26,122.54 93.6,122.2 UC1.F60
VR_ENABLE: length 4.1
  BOTTOM w0.102: v3(84.9,141.05) 85.46,140.49 PC522.1
  BOTTOM w0.203: PC522.1 PR522.1 86.26,139.01 86.46,138.82 PU501.8
VR_HOT#: length 222.1
  TOP w0.102: PC506.2 88.74,134.79 v1(88.51,134.57) 88.51,133.97 88.22,133.68 86.47,133.68 PR533.1 85.45,132.45 86.69,131.2 86.69,124.85 86.02,124.18 84.13,124.18 83.24,123.29 74.73,123.29 61.43,109.99 v3(61.43,108.88) 61.43,107.2 62.13,106.5 62.13,105.98 62.35,105.76 64.76,105.76 v1(64.9,105.63) ; v1(180.18,55.57) 180.5,55.26 RE44.1
  IN3 w0.127: v1(64.9,105.63) 64.21,104.94 64.21,102.73 64.95,102 64.95,99.2 65.65,98.49 65.65,96.51 64.68,95.54 64.68,91.92 64.17,91.42 64.17,88.23 65.36,87.05 65.36,78.23 70.13,73.46 70.13,72.19 72.5,69.82 72.5,55.36 75.27,52.59 104.05,52.59 105.27,53.81 116.92,53.81 117.64,53.09 175.92,53.09 176.24,53.41 177.03,53.41 179.18,55.57 v1(180.18,55.57)
  BOTTOM w0.102: PU501.30 88.62,134.67 v1(88.51,134.57)
VR_ON: length 275.8
  TOP w0.089: RE1.2 92.55,122.11 R250.1 91.98,121.36 92.02,121.32 92.02,119.37 90.79,118.15 87.56,118.15 86.76,117.34
  TOP w0.102: v1(170.58,45.92) 170.58,44.25 DE1.3 174.35,42.92 176.86,40.41 RE12.2 ; 86.76,117.34 86.49,117.08 85.23,117.08 84.51,116.36 v3(81.12,116.36) 80.56,116.36 v1(79.98,115.78)
  IN3 w0.127: v1(170.58,45.92) 170.36,45.71 111.61,45.71 111.27,46.05 62.57,46.05 56.35,52.27 56.35,92.66 50.77,98.25 50.77,104.06 v1(62.09,115.39) 70.48,123.78 80.87,123.78 84.06,126.97 84.06,130.38 81.94,132.5 81.94,134.88 83.09,136.03 v1(83.09,138.04)
  BOTTOM w0.102: v1(79.98,115.78) 79.06,114.86 63.11,114.86 62.58,115.39 v1(62.09,115.39)
  BOTTOM w0.254: v1(83.09,138.04) 83.4,138.36 83.4,138.89 83.66,139.14 84.17,139.14 84.29,139.01 PR522.2
VR_ON_EC: length 2.1
  TOP w0.102: UE1.121 180.35,40.11 v1(180.3,40.16) 180.05,40.41 RE12.1
VR_READY_R: length 6.6
  BOTTOM w0.076: 92.44,126.43 93.32,126.43 93.88,125.87 93.88,125.14 94.09,124.93 94.09,124.79 94.25,124.63 94.25,124.39 UC1.C59
  BOTTOM w0.089: 92.44,126.43 91.57,127.3 91.57,127.37
  BOTTOM w0.102: R251.2 90.52,128.42 91.57,127.37
VR_SVID_ALRT#: length 22.6
  IN3 w0.127: v1(86.9,134.11) 86.9,133.55 85.88,132.54 85.88,129.22 86.97,128.13 86.97,124.75 86.24,124.01 85.07,124.01 83.11,122.05 83.11,119.41 v1(82.39,118.69)
  BOTTOM w0.102: R252.2 v1(82.39,118.69) R254.2 ; PU501.32 87.82,134.98 86.95,134.11 v1(86.9,134.11) PR528.2
VR_SVID_CLK: length 27
  IN3 w0.127: v1(79.34,118.18) 79.42,118.1 82.82,118.1 83.95,119.23 83.95,121.4 85.93,123.38 86.44,123.38 87.66,124.6 87.66,128.28 86.47,129.47 86.47,132.29 87.49,133.31 87.49,133.83 v1(87.85,134.19)
  BOTTOM w0.102: PR526.2 87.85,133.56 v1(87.85,134.19) 87.85,134.63 88.22,135 PU501.31 ; R248.1 80.71,117.66 v3(79.76,117.66) 79.49,117.66 79.34,117.81 v1(79.34,118.18)
VR_SVID_DAT: length 23.5
  IN3 w0.127: v1(79.15,119.71) 79.94,119.71 84.83,124.6 86,124.6 86.39,124.99 86.39,127.88 85.29,128.97 85.29,132.78 86.07,133.56 v1(86.07,134.82)
  BOTTOM w0.102: R257.2 79.01,119.85 v1(79.15,119.71) ; PU501.1 86.76,136.02 86.45,135.71 86.45,135.2 v1(86.07,134.82) 85.94,134.69 PR530.2
VRAM_ID0: length 7.8
  BOTTOM w0.102: UV1.AU1 193.78,105.37 193.78,101.89 RV68.2 RV67.2 195.06,100.47 v3(195.5,100.03)
VRAM_ID1: length 7.5
  BOTTOM w0.102: v3(190.88,100.99) 191.4,100.47 RV69.2 RV70.2 191.29,101.84 191.29,103.32 191.61,103.64 191.61,105.83 UV1.AU3
VRAM_ID2: length 5.4
  BOTTOM w0.102: RV71.2 192.75,100.6 v3(192.75,101.39) 192.37,101.77 192.37,105.18 UV1.AW3
VREF_CPU: length 54.9
  TOP w0.203: v1(90.03,134.44) 89.94,134.53 PC507.1
  IN3 w0.254: v1(90.03,134.44) 90.03,135.3 89.31,136.03 87.72,136.03 87.15,136.6 87.15,138.38 85.37,140.16 85.37,142.25 85.88,142.76 v1(87.72,142.76) 87.72,141.74 88.17,141.3 88.17,141.23 89.98,141.23 90.58,141.84 90.58,143.97 92.8,146.19 110.9,146.19 111.66,145.43 111.66,144.89 v1(111.76,144.79)
  BOTTOM w0.203: PR531.1 90.63,132.66 90.03,133.26 v1(90.03,134.44) 89.91,134.57 89.91,134.89 89.82,134.98 PU501.27
  BOTTOM w0.254: v1(111.76,144.79) 111.76,144.32 PH502.1 ; PR514.2 90.77,142.44 90.45,142.76 90.45,143.27 89.94,143.78 v3(89.69,143.78) 88.39,143.78 87.72,143.11 v1(87.72,142.76) PR507.2 PR504.2 PR502.2
VREFC1: length 6.3
  BOTTOM w0.305: UV4.J14 168.48,142.24 168.48,141.58 168.11,141.22 v3(168.11,140.5) CV397.1 RV29.1 RV37.2 CV388.2
VREFC2: length 6.3
  TOP w0.305: CV328.2 RV183.2 CV399.1 RV184.1 168.11,139.66 168.48,140.02 v3(168.48,140.14) 168.48,142.24 UV5.J14
VREFC3: length 6.8
  TOP w0.305: UV3.J14 189.2,141.37 v3(188.03,140.2) 187.35,139.53 RV194.1 CV349.1 RV193.2 CV350.2
VREFC4: length 6.8
  BOTTOM w0.305: UV6.J14 189.2,141.82 v3(187.85,140.47) 187.35,139.97 RV39.1 CV353.1 RV197.2 CV354.2
VREFC5: length 6.3
  BOTTOM w0.305: CV21.2 RV6.2 CV22.1 RV5.1 v3(202.46,133.68) 203.44,133.68 204.01,133.11 UV8.J14
VREFC6: length 7.4
  TOP w0.305: CV28.2 RV12.2 201.58,129.79 201.58,130.86 CV27.1 RV11.1 202.32,131.86 v3(202.79,132.34) 203.56,133.11 UV7.J14
VREFC7: length 6.8
  TOP w0.305: RV17.1 CV33.1 RV19.2 CV34.2 201.71,114.55 v3(202.67,113.59) 203.55,112.71 UV9.J14
VREFC8: length 6.8
  BOTTOM w0.305: UV10.J14 203.62,112.71 v3(202.56,113.78) 201.78,114.55 CV40.2 RV27.2 CV39.1 RV24.1
VREFD1_1: length 10.4
  TOP w0.254: CV387.1 RV34.1 CV393.2 RV28.2 v3(160.05,150.32) 160.51,150.32 162.22,148.6 162.55,148.6 v1(163.1,148.05)
  BOTTOM w0.305: v1(163.1,148.05) 163.1,146.46 UV4.A10
VREFD1_2: length 14.4
  BOTTOM w0.254: RV36.1 CV395.1 RV35.2 CV394.2 v3(176.18,154.69) 176.18,148.41 174.59,146.82 174.59,145.93 174.88,145.65 UV4.U10
VREFD2_1: length 16.8
  TOP w0.102: v3(178.11,155.02) 178.64,155.56 v1(178.84,155.56)
  TOP w0.254: v1(178.84,155.56) RV181.1 CV398.1 RV38.2 CV396.2
  TOP w0.305: v1(175.08,146.22) 175.09,146.21 UV5.A10
  BOTTOM w0.254: v1(178.84,155.56) 177.3,155.56 177.03,155.29 177.03,148.43 175.08,146.49 v1(175.08,146.22)
VREFD2_2: length 9.1
  TOP w0.254: v1(162.4,148.05) 161.83,148.05 161.2,148.69 160.12,148.69 v3(160.1,148.7) 160.1,148.69 159.37,149.43 RV185.2 CV330.2 RV186.1 159.05,146.78 CV400.1
  TOP w0.305: v1(162.4,146.76) 162.28,146.64 UV5.U10
  BOTTOM w0.102: 162.4,147.97 v1(162.4,148.05)
  BOTTOM w0.254: v1(162.4,146.76) 162.4,147.97
VREFD3_1: length 15.3
  TOP w0.102: v3(200.04,159.08) CV389.2
  TOP w0.254: v1(200.04,154.44) RV33.1 CV390.1 RV32.2 CV389.2
  TOP w0.305: v1(195.59,146.15) 195.6,146.15 UV3.A10
  BOTTOM w0.254: v1(200.04,154.44) 197.45,151.85 197.45,148.54 195.59,146.68 v1(195.59,146.15)
VREFD3_2: length 16.7
  TOP w0.254: 181.52,157.19 180.62,156.29 CV332.1 RV192.1 v3(179.73,154.94) 179.73,153.73 180.77,152.7 180.77,149.79 182.08,148.47 182.78,148.47 v1(183.23,148.92) ; 181.52,157.19 CV401.2 ; 181.52,157.19 RV191.2 ; UV3.U10 182.79,145.71 v1(183.1,146.02)
  BOTTOM w0.254: v1(183.23,148.92) 183.23,146.14 v1(183.1,146.02)
VREFD4_1: length 14.1
  TOP w0.254: v1(180.62,155.52) v3(180.62,153.68) 181.15,153.16 181.15,150.43 v1(182.46,149.11)
  BOTTOM w0.254: CV352.2 RV195.2 CV351.1 RV196.1 v1(180.62,155.52) ; UV6.A10 182.46,145.91 v1(182.46,149.11)
VREFD4_2: length 14.4
  BOTTOM w0.254: UV6.U10 195.45,145.58 195.1,145.93 195.1,146.82 196.69,148.41 196.69,152.14 v3(197.69,153.14) CV356.2 RV40.2 CV355.1 RV41.1
VREFD5_1: length 17.8
  TOP w0.254: v1(210.4,138.57) 210.72,138.57 210.98,138.82 210.98,141.55 211.23,141.81 v3(212.43,141.81) 216.69,141.81 v1(217.9,143.01)
  BOTTOM w0.254: RV1.2 CV18.2 ; RV1.2 218.23,142.17 217.9,142.5 v1(217.9,143.01) ; RV1.2 218.52,142.1 CV13.1 RV2.1
  BOTTOM w0.305: v1(210.4,138.57) 208.9,138.57 UV8.A10
VREFD5_2: length 14.8
  BOTTOM w0.254: UV8.U10 208.42,127.16 209.49,127.16 211.55,125.11 215.8,125.11 216.25,124.66 v3(217.25,124.66) RV4.1 CV20.1 218.48,125.55 219.24,126.31 219.24,126.31 RV3.2 CV19.2
VREFD6_1: length 15.1
  TOP w0.254: v1(216.91,123.62) 217.95,124.66 RV7.1 CV23.1 RV8.2 CV24.2
  TOP w0.305: v1(208.62,126.71) UV7.A10
  BOTTOM w0.254: v1(216.91,123.62) 215.87,123.62 v3(215.17,124.32) 214.76,124.72 210.89,124.72 208.91,126.71 v1(208.62,126.71)
VREFD6_2: length 11.5
  TOP w0.254: CV26.2 RV10.2 CV25.1 RV9.1 v3(207.82,142.62) 208.42,142.62 210.4,140.64 v1(210.4,139.2)
  TOP w0.305: v1(208.95,139.2) 208.65,139.51 UV7.U10
  BOTTOM w0.254: v1(208.95,139.2) v1(210.4,139.2)
VREFD7_1: length 11.1
  TOP w0.254: v1(210.21,106.75) 210.21,106.63 209.9,106.31 UV9.A10
  BOTTOM w0.254: CV30.2 RV14.2 CV29.1 RV13.1 212.64,102.5 v3(212.02,103.12) 210.21,104.93 v1(210.21,106.75)
VREFD7_2: length 23.5
  TOP w0.305: UV9.U10 208.19,118.69 v1(208.31,118.69)
  BOTTOM w0.305: CV32.2 RV16.2 CV31.1 RV15.1 v3(207.64,103.31) 209.35,105.01 209.35,116.69 210.15,117.49 210.15,118.31 209.78,118.68 208.32,118.68 v1(208.31,118.69)
VREFD8_1: length 27.1
  TOP w0.254: CV36.2 RV21.2 CV35.1 RV20.1 214.53,100.34 v1(215.01,100.82)
  BOTTOM w0.254: v1(215.01,100.82) 215.01,101.33 v3(214.47,101.86) 210.72,105.61 210.72,107.32 209.76,108.28 209.76,116.2 210.66,117.1 210.66,118.63 210.14,119.15 207.81,119.15 UV10.A10
VREFD8_2: length 26.5
  TOP w0.254: v1(209.64,117.93) 209.64,119.07 211.23,120.66 v3(214.03,120.66) 215.42,120.66 215.99,120.09 RV22.1 CV37.1 218.48,119.2 219.37,118.31 RV23.2 CV38.2
  BOTTOM w0.254: UV10.U10 208.05,106.31 208.82,107.07 208.82,117.1 v1(209.64,117.93)
VTTREF_1.35V: length 4.3
  BOTTOM w0.102: v3(159.21,30.17) 159.21,28.68 PC210.1
  BOTTOM w0.203: 159.23,27.58 159.23,27.26 158.91,26.94 PU200.4
  BOTTOM w0.254: 159.23,27.58 159.67,28.03 PC210.1
WCKA0_0: length 30.5
  TOP w0.102: UV5.P4 164.68,150.4 v1(165.05,150.04)
  TOP w0.109: v1(165.05,150.04) 165.12,149.97 165.12,149.48 164.8,149.16 164.8,147.65 164.45,147.31 161.64,147.31 159.94,145.61 159.94,139.43 v2(161.2,138.18) 164.11,135.26 164.11,133.99 165.57,132.53 165.57,131.96 166.27,131.26 166.67,131.26 167.2,131.79 167.9,131.79 168.36,132.25 168.99,132.25 169.14,132.41 v1(169.14,132.66)
  BOTTOM w0.102: v1(165.05,150.04) 164.68,150.4 UV5.P4 ; v1(169.14,132.66) 169.46,132.98 UV1.A32
WCKA0_1: length 30.7
  TOP w0.102: v1(172.31,150.06) 172.69,150.44 UV5.D4
  TOP w0.109: v1(172.31,150.06) 172.31,149.47 172.57,149.21 172.57,148.6 172.85,148.32 174.64,148.32 175.55,147.41 175.55,141.49 173.62,139.56 173.62,138.8 171.59,136.77 171.59,134.42 172.47,133.53 172.47,131.18 172.92,130.74 176.01,130.74 176.23,130.95 176.77,131.5 176.77,131.91 176.67,132.01 176.67,132.18 176.78,132.28 v1(176.94,132.28)
  BOTTOM w0.102: UV1.D23 176.66,132 v1(176.94,132.28) ; UV5.D4 172.69,150.44 v1(172.31,150.06)
WCKA0B_0: length 30.5
  TOP w0.102: v1(164.3,150.03) 164.31,150.03 UV5.P5
  TOP w0.109: v1(164.3,150.03) 164.3,149.51 164.59,149.23 164.59,147.74 164.36,147.52 161.56,147.52 159.73,145.69 159.73,139.35 160.84,138.24 160.84,138.21 161.23,137.81 161.26,137.81 163.9,135.18 163.9,133.91 165.36,132.45 165.36,131.88 166.18,131.05 166.76,131.05 167.29,131.58 167.99,131.58 168.44,132.04 169.01,132.04 v1(169.15,131.9)
  BOTTOM w0.102: v1(169.15,131.9) 169.46,132.22 UV1.C32 ; v1(164.3,150.03) 164.31,150.03 UV5.P5
WCKA0B_1: length 30.8
  TOP w0.102: UV5.D5 173.08,150.04 v1(173.1,150.04)
  TOP w0.109: v1(173.1,150.04) 173.11,150.03 173.11,149.51 172.78,149.18 172.78,148.69 172.94,148.53 174.73,148.53 175.76,147.5 175.76,141.4 173.83,139.47 173.83,138.72 171.8,136.69 v2(171.8,135.37) 171.8,134.5 172.69,133.61 172.69,131.27 173,130.95 175.92,130.95 176.08,131.1 176.56,131.59 176.56,131.82 176.43,131.95 176.23,131.95 v1(176.18,131.9)
  BOTTOM w0.102: UV1.E22 176.59,131.49 v1(176.18,131.9) ; v1(173.1,150.04) 172.71,149.65 UV5.D5
WCKA1_0: length 24.8
  TOP w0.102: UV3.P4 185.19,150.34 v1(185.56,149.98)
  TOP w0.109: v1(180.88,135.14) 180.99,135.25 181.36,135.25 181.6,135.49 181.6,136.89 181.03,137.47 181.03,145.79 182.48,147.24 184.85,147.24 185.49,147.88 185.49,149.37 185.56,149.44 v1(185.56,149.98)
  BOTTOM w0.102: v1(185.56,149.98) 185.19,150.34 UV3.P4
  BOTTOM w0.109: v1(180.88,135.14) 181.06,135.33 181.76,135.33 183.33,133.75 183.33,132.88 183.86,132.35 UV1.C14
WCKA1_1: length 32.3
  TOP w0.102: v1(192.82,150) 193.2,150.37 UV3.D4 ; 186.2,131.51 v1(186.02,131.33)
  TOP w0.109: v1(192.82,150) 192.82,149.36 193.01,149.17 193.01,147.39 193.48,146.92 196.03,146.92 196.38,146.58 196.38,142.02 194.09,139.72 193.93,139.72 193.61,140.05 193.28,140.05 192.92,139.69 192.92,139.36 193.25,139.04 193.25,138.88 191.67,137.3 187.32,137.3 v2(186.94,136.93) 186.64,136.62 186.64,135.19 186.51,135.06 186.51,132.97 186.2,132.67 186.2,131.51
  BOTTOM w0.102: v1(186.02,131.33) 186.35,131 186.8,131 187.06,131.26 187.06,131.32 187.06,131.32 UV1.E10 ; v1(192.82,150) 193.2,150.37 UV3.D4
WCKA1B_0: length 24.9
  TOP w0.102: v1(184.81,149.96) 184.82,149.96 UV3.P5
  TOP w0.109: v1(180.88,135.72) 180.88,135.72 181.13,135.46 181.27,135.46 181.39,135.58 181.39,136.81 180.82,137.38 180.82,145.88 182.39,147.45 184.76,147.45 185.28,147.96 185.28,149.13 185.19,149.22 184.9,149.22 184.81,149.3 v1(184.81,149.96)
  BOTTOM w0.102: v1(184.81,149.96) 184.82,149.96 UV3.P5
  BOTTOM w0.109: UV1.A14 183.86,132.93 183.77,132.84 183.67,132.84 183.54,132.96 183.54,133.84 181.84,135.54 181.06,135.54 v1(180.88,135.72)
WCKA1B_1: length 32.4
  TOP w0.102: UV3.D5 193.59,149.98 v1(193.61,149.98)
  TOP w0.109: v1(193.61,149.98) 193.62,149.96 193.62,149.51 193.22,149.1 193.22,147.48 193.56,147.13 196.12,147.13 196.59,146.66 196.59,141.93 194.18,139.51 193.85,139.51 193.52,139.84 193.37,139.84 193.13,139.6 193.13,139.45 193.46,139.13 193.46,138.8 191.76,137.09 187.42,137.09 187.29,136.96 187.29,136.95 186.92,136.57 186.9,136.57 186.85,136.52 186.85,135.1 186.72,134.97 186.72,132.88 186.41,132.58 186.41,131.56 v1(186.59,131.38)
  BOTTOM w0.102: UV3.D5 193.22,149.58 v1(193.61,149.98) ; v1(186.59,131.38) 186.59,131.46 187.03,131.89 UV1.D9
WCKB0_0: length 37.4
  TOP w0.102: v1(192.5,128.57) 192.65,128.57 192.9,128.31 192.9,128.17 192.81,128.08 192.31,128.08 191.21,129.17 190.82,129.17 190.42,129.57 190.42,130.61 190.57,130.76 190.57,131.98 190.93,132.34 193.23,132.34 193.29,132.41 193.61,132.41 193.88,132.68 ; UV7.P4 212.71,137.11 v1(212.35,136.74)
  TOP w0.109: v1(212.35,136.74) 212.32,136.71 211.69,136.71 211.57,136.83 211.57,137.17 211.46,137.28 210.3,137.28 209.49,138.09 209.49,140.27 208.21,141.55 v2(205.89,141.55) 203.52,141.55 194.73,132.77 193.97,132.77 193.88,132.68
  BOTTOM w0.102: v1(212.35,136.74) 212.71,137.11 UV7.P4 ; UV1.H3 192.06,128.7 192.27,128.5 192.42,128.5 v1(192.5,128.57)
WCKB0_1: length 29
  TOP w0.102: v1(190.97,122.88) 190.99,122.88 191.1,122.77 191.46,122.77 191.6,122.9 191.6,125.09 192.75,126.24 194.33,126.24 194.33,126.25 194.36,126.25 ; UV7.D4 212.74,129.11 v1(212.35,129.49)
  TOP w0.109: 194.36,126.25 196.56,126.25 196.58,126.27 197.14,126.27 197.16,126.25 209.76,126.25 210.63,127.11 210.63,129.06 211.05,129.48 212.34,129.48 v1(212.35,129.49)
  BOTTOM w0.102: UV7.D4 212.74,129.11 v1(212.35,129.49) ; v1(190.97,122.88) 191.3,122.88 191.69,122.49 UV1.T3
WCKB0B_0: length 37.4
  TOP w0.102: 193.73,132.83 193.71,132.81 193.71,132.81 193.67,132.76 193.67,132.76 193.58,132.66 193.52,132.61 193.21,132.61 193.15,132.55 190.85,132.55 190.36,132.07 190.36,130.84 190.22,130.69 190.22,129.48 190.73,128.97 191.13,128.97 192.22,127.87 192.89,127.87 193.11,128.09 193.11,128.45 193.2,128.55 v1(193.2,128.55) ; UV7.P5 212.34,137.48 v1(212.34,137.49)
  TOP w0.109: v1(212.34,137.49) 210.39,137.49 209.7,138.18 209.7,140.36 208.3,141.76 206.19,141.76 206.17,141.78 205.61,141.78 205.59,141.76 203.43,141.76 194.65,132.98 193.88,132.98 193.73,132.83
  BOTTOM w0.102: v1(212.34,137.49) 212.34,137.48 UV7.P5 ; v1(193.2,128.55) UV1.H1
WCKB0B_1: length 29
  TOP w0.102: v1(212.35,128.69) 212.35,128.72 UV7.D5 ; 194.36,126.04 194.34,126.04 194.33,126.04 194.27,126.04 194.27,126.04 192.83,126.04 191.8,125.01 191.8,122.82 191.54,122.57 191.21,122.57 v1(190.86,122.22)
  TOP w0.109: v1(212.35,128.69) 212.34,128.68 211.75,128.68 211.6,128.82 211.6,129.2 211.53,129.27 211.14,129.27 210.84,128.97 210.84,127.03 209.85,126.04 v2(196.86,126.04) 194.36,126.04
  BOTTOM w0.102: UV1.T5 191.14,122.49 v1(190.86,122.22) ; v1(212.35,128.69) 212.35,128.72 UV7.D5
WCKB1_0: length 29.8
  TOP w0.102: 194.17,117.62 194.14,117.62 194.14,117.62 192.36,117.62 191.61,116.87 191.61,116.14 191.29,115.82 191.29,115.28 191.68,114.89 v1(191.68,114.81) ; UV9.P4 212.52,116.71 v1(212.16,116.35)
  TOP w0.109: 194.17,117.62 194.89,117.62 198.17,120.89 208.29,120.89 208.7,120.48 208.7,117.67 209.71,116.67 211.22,116.67 211.54,116.35 v1(212.16,116.35)
  BOTTOM w0.102: UV1.AE4 191.75,115.2 191.75,114.88 v1(191.68,114.81) ; v1(212.16,116.35) 212.52,116.71 UV9.P4
WCKB1_1: length 28
  TOP w0.102: UV9.D4 212.57,108.71 v1(212.16,108.3)
  TOP w0.109: v1(212.16,108.3) 211.03,108.3 210.84,108.11 210.84,106.22 209.93,105.31 203.27,105.31 197.73,110.85 v2(197.01,110.85) 194.2,110.85 v1(193.96,110.62)
  BOTTOM w0.102: v1(193.96,110.62) 193.77,110.81 193.18,110.81 193.12,110.74 192.64,110.74 192.59,110.8 192.34,110.8 192.28,110.74 191.84,110.74 191.79,110.8 191.54,110.8 191.48,110.74 191,110.74 190.83,110.91 190.79,111.07 190.67,111.14 UV1.AK6 ; UV9.D4 212.57,108.71 v1(212.16,108.3)
WCKB1B_0: length 29.7
  TOP w0.102: 194.08,117.83 194.08,117.82 192.27,117.82 v2(191.85,117.39) 191.41,116.95 191.41,116.22 191.09,115.91 191.09,115 v1(191.04,114.95) ; UV9.P5 211.77,116.72 v1(212.15,117.1)
  TOP w0.109: 194.08,117.83 194.81,117.83 198.08,121.1 208.38,121.1 208.91,120.57 208.91,117.76 209.79,116.88 211.41,116.88 211.63,117.1 v1(212.15,117.1)
  BOTTOM w0.102: UV9.P5 211.77,116.72 v1(212.15,117.1) ; v1(191.04,114.95) 191.26,114.72 UV1.AF5
WCKB1B_1: length 28.1
  TOP w0.102: v1(212.19,109.08) 211.81,108.71 UV9.D5
  TOP w0.109: v1(193.96,111.2) 194.1,111.06 196.7,111.06 196.73,111.08 197.29,111.08 197.31,111.06 197.82,111.06 203.36,105.52 209.84,105.52 210.63,106.31 210.63,108.2 210.94,108.51 211.18,108.51 211.31,108.63 211.31,108.98 211.41,109.08 v1(212.19,109.08)
  BOTTOM w0.102: v1(212.19,109.08) 211.81,108.71 UV9.D5 ; UV1.AK5 191.06,111.24 190.99,111.12 191.01,111.02 191.08,110.95 191.4,110.95 191.45,111 191.87,111 191.93,110.95 192.2,110.95 192.25,111 192.67,111 192.73,110.95 193.03,110.95 193.09,111.01 193.77,111.01 v1(193.96,111.2)
WEA0#: length 32.1
  TOP w0.102: v1(169.86,144.45) 170.26,144.05 UV5.G12
  IN3 w0.102: 169.17,141.35 169.17,142.11 169.45,142.38 169.45,144.03 v1(169.86,144.45) ; 168.93,135.39 168.93,134.89 169.32,134.5 170.21,134.5 170.65,134.06 170.65,133.42 172.43,131.65 172.43,130.76 172.9,130.29 172.9,129.14 173.22,128.82 174.05,128.82 v1(174.91,127.96)
  IN3 w0.157: 169.17,141.35 169.17,141.03 168.49,140.35 166,140.35 165.87,140.22 165.87,135.22 166,135.09 166.41,135.09 166.53,135.22 166.53,136.07 166.66,136.2 167.04,136.2 167.16,136.07 167.16,135.16 167.29,135.03 167.67,135.03 167.79,135.16 167.79,136.07 167.92,136.2 168.8,136.2 168.93,136.07 168.93,135.39
  BOTTOM w0.102: UV5.G12 170.26,144.05 v1(169.86,144.45) ; UV1.K26 174.44,127.49 v1(174.91,127.96)
WEA1#: length 29.2
  TOP w0.102: v1(190.37,144.38) 190.77,143.98 UV3.G12
  IN3 w0.102: v1(190.37,144.38) 189.95,144.8 188.67,144.8 188.41,144.54 188.41,143.43 189.13,142.71 189.13,141.29 ; v1(184.12,126.25) 183.92,126.44 183.92,128.85 184.18,129.11 184.78,129.11 185,129.33 185,130.45 185.49,130.94 185.49,131.98 188.9,135.39
  IN3 w0.157: 189.13,141.29 189.13,140.73 189.6,140.26 191.61,140.26 191.74,140.13 191.74,139.72 191.61,139.6 191.23,139.6 191.1,139.47 191.1,138.07 190.97,137.95 190.59,137.95 190.47,137.82 190.47,136.95 188.9,135.39
  BOTTOM w0.102: UV1.L15 183.67,126.69 v1(184.12,126.25) ; UV3.G12 190.77,143.98 v1(190.37,144.38)
WEB0#: length 34.5
  TOP w0.102: v1(206.76,131.93) 206.36,131.53 UV7.G12
  IN3 w0.102: 194.39,129.36 194.32,129.3 192.31,129.3 191.67,128.66 191.67,128.22 191.15,127.7 191.04,127.7 190.92,127.58 190.09,127.58 189.77,127.26 189.77,126.84 189.43,126.5 188.05,126.5 187.45,125.9 v1(187.45,124.71) ; 203.66,132.62 204.42,132.62 204.69,132.34 204.69,131.53 204.82,131.41 205.45,131.41 205.57,131.52 205.57,132.27 205.66,132.36 206.33,132.36 v1(206.76,131.93)
  IN3 w0.157: 194.39,129.36 195.7,130.68 195.7,132.79 196.02,133.11 200.94,133.11 201.07,132.98 201.07,132.11 201.19,131.99 201.57,131.99 201.7,132.11 201.7,133.55 201.96,133.82 202.34,133.82 202.53,133.63 202.53,131.75 202.66,131.63 203.1,131.63 203.23,131.75 203.23,132.49 203.36,132.62 203.66,132.62
  BOTTOM w0.102: v1(206.76,131.93) 206.36,131.53 UV7.G12 ; UV1.N10 187.26,124.9 v1(187.45,124.71)
WEB1#: length 31.8
  TOP w0.102: UV9.G12 206.17,111.13 v1(206.57,111.53)
  IN3 w0.102: 203.47,112.85 204.97,112.85 205.61,113.49 206.73,113.49 206.99,113.23 206.99,111.95 v1(206.57,111.53) ; v1(187.07,117.47) 187.45,117.09 187.45,116.12 187.61,115.96 187.88,115.96 188.31,115.54 190.31,115.54 190.52,115.33 190.52,114.92 191.38,114.06 191.6,114.06 193.01,112.65 193.01,111.89 193.31,111.58 194.19,111.58 194.39,111.38
  IN3 w0.157: 203.47,112.85 203.41,112.85 202.25,111.68 201.51,111.68 201.32,111.49 201.32,109.55 200.43,108.66 197.23,108.66 194.5,111.38 194.39,111.38
  BOTTOM w0.102: UV9.G12 206.17,111.13 v1(206.57,111.53) ; UV1.AB11 186.85,117.69 v1(187.07,117.47)
WL_BT_LED#: length 201.5
  TOP w0.102: RD45.2 55.19,14.98 QD18.3 55.82,15.92 57.31,17.41 57.31,39.89 37.99,59.21 37.99,71.65 42.68,76.34 45.43,76.34 54.11,85.01 v3(54.11,89.98) 54.11,102.67 55.68,104.25 55.68,105.1 74.48,123.9 82.89,123.9 86.08,127.09 86.08,130.95 83.04,134 83.04,137.18 85.12,139.26 85.12,147.52 v1(85.69,148.09)
  IN3 w0.127: v1(113.31,146.93) 112.94,147.31 92.38,147.31 91.6,148.09 v1(85.69,148.09)
  BOTTOM w0.102: v1(113.31,146.93) 113.31,146.94 113.32,146.94 113.7,147.32 JMINI.44
WL_OFF#: length 81.8
  TOP w0.089: v1(127.87,104.7) v3(128.71,104.7) ; RP54.3 132.7,115.13 v1(132.82,115.01)
  TOP w0.102: v1(98.07,146.89) 98.59,146.37 QM30.3
  IN2 w0.089: 124.97,133.14 124.97,129.62 129.91,124.68 129.91,119.11 131.41,117.61 131.41,116.6 132.82,115.19 v1(132.82,115.01) 132.31,114.5 130.33,114.5 129.7,113.87 129.7,113.72 129.7,111.83 128.71,110.85 128.42,110.85 128.2,110.63 128.2,110.32 128.24,110.29 128.24,109.55 127.35,108.66 127.35,105.22 v1(127.87,104.7)
  IN2 w0.127: 124.97,133.14 125.63,133.8 125.63,144.79 122.52,147.9 116.55,147.9 116.49,147.97 99.15,147.97 v1(98.07,146.89)
  BOTTOM w0.089: UC1.AT5 127.38,105.19 v1(127.87,104.7)
WLAN_CLKREQ#: length 107.6
  TOP w0.089: v1(127.82,114.94) 128.25,114.51 128.25,113.36 128.56,113.05 130,113.05 130.07,113.11 131.51,113.11 131.51,113.11 131.82,113.11 132.04,113.33 132.04,113.42 132.3,113.68 133.12,113.68 133.5,113.3 133.73,113.3 134.98,112.05 v3(135.45,112.05) 137.92,112.05
  TOP w0.102: RP42.7 145.52,113.24 144.33,112.05 137.92,112.05 ; v1(91.6,147.33) 91.6,149.24 91.98,149.62 95.34,149.62 95.7,149.97 JMINI.7
  IN1 w0.084: v1(131.89,119) 131.28,118.39 131.28,116.34 130.46,115.52 128.4,115.52 v1(127.82,114.94)
  IN2 w0.089: v1(127.82,114.94) 127.38,114.5 125.62,114.5 125.11,115.01 125.11,119.85 125.76,120.5 125.76,128.58 124.9,129.44 124.72,129.62 124.72,133.04 124.72,133.14
  IN2 w0.127: 124.72,133.14 124.72,133.25 125.38,133.91 125.38,144.69 122.44,147.62 100.49,147.62 99.33,146.47 96.59,146.47 95.72,147.33 v1(91.6,147.33)
  BOTTOM w0.089: v1(131.89,119) 131.6,118.7 131.35,118.7 131,118.34 UC1.N1
WLAN_RADIO_DIS#_R: length 5.2
  TOP w0.102: QM30.1 103.55,147.33 v1(104.1,146.78) ; v1(104.1,146.78) 104.1,146.72 v3(104.66,146.16) ; v1(104.1,146.78) 104.17,146.85 RM110.2
  BOTTOM w0.102: JMINI.20 v1(104.1,146.78)
WLAN_WAKE#: length 168.4
  TOP w0.102: v1(193.31,55.57) 193.45,55.43 193.45,54.23 RE70.2 192.94,53.25 191.99,52.29 UE1.74
  IN2 w0.089: 137.05,127.21 137.92,126.34
  IN2 w0.127: 137.05,127.21 136.87,127.39 136.87,138.25 126.97,148.16 116.66,148.16 116.47,148.35 93.59,148.35 93.3,148.64 JMINI.1 ; v1(186.26,58) 185.75,58.51 185.75,65.66 186.52,66.43 186.52,73.94 183.31,77.15 183.31,78.17 182.66,78.82 182.46,78.82 160.59,100.69 158.03,100.69 152.91,105.81 152.91,108.37 152.78,108.5 152.78,109.68 152.43,110.03 152.43,111.1 151.32,112.2 151.32,114.44 148.53,117.23 144.47,117.23 143.51,118.19 143.51,120.75 137.92,126.34
  BOTTOM w0.102: v1(186.26,58) 186.49,58.23 190.66,58.23 v1(193.31,55.57)
WOL_EN: length 208.3
  TOP w0.102: v1(182.85,49.41) 182.74,49.31 UE1.98
  IN1 w0.127: v1(55.59,97.04) 53.37,97.04 42.41,86.08 42.41,84.16 41.38,83.13 41.38,80.18 41.16,79.96 v1(41.16,79.08)
  IN3 w0.127: v1(55.59,97.04) 55.59,95.82 59.04,92.38 59.04,74.63 61.18,72.49 61.18,56.99 69.58,48.59 114.78,48.59 115.66,47.7 140.86,47.7 141.31,48.16 176.67,48.16 176.75,48.08 178.15,48.08 178.84,48.77 182.2,48.77 v1(182.85,49.41)
  BOTTOM w0.102: RL38.1 41.16,79.49 v1(41.16,79.08) 41.16,79.01 41.73,78.44 43.32,78.44 43.79,78.92 RL27.2 v3(45.82,79.39) 49.58,79.39 50.25,80.06 50.25,81.25 50.15,81.36 UL2.3
XDP_DBRESET#: length 23.1
  TOP w0.102: v1(56.16,100.02) 56.57,100.43 56.57,104.49 v3(57.53,105.45) 58.29,106.21 RC26.1
  BOTTOM w0.102: v1(56.16,100.02) 58.07,100.02 58.32,99.77 58.32,97.99 59.08,97.23 61.43,97.23 61.7,97.5 JXDP1.48 61.7,100.72 61.89,100.91 CC17.1 61.44,101.36 61.42,101.34 RC362.2
XDP_OBS0_R: length 67.1
  IN3 w0.127: v1(84.88,120.19) 84.88,119.32 83.07,117.51 79.15,117.51 78.41,118.25 68.72,118.25 57.77,107.29 57.77,97.98 v1(57.76,97.99)
  BOTTOM w0.076: UC1.J60 93.31,120.3 92.83,120.3 92.79,120.34 92,120.34 91.84,120.17 91.34,120.17 91.34,120.17 90.86,120.17 90.56,120.47 90.56,120.47 90.37,120.67 88.37,120.67
  BOTTOM w0.102: JXDP1.21 68.2,96.05 67.51,96.74 58.88,96.74 57.76,97.86 v1(57.76,97.99) ; 88.37,120.67 86.69,120.67 86.65,120.7 v3(86.03,120.7) 85.35,120.7 84.88,120.23 v1(84.88,120.19) 84.71,120.03 RC141.1
XDP_OBS1_R: length 67.6
  IN1 w0.127: v1(82.52,119.71) 82.81,119.42 90.35,119.42 91.53,120.6 92.93,120.6 v1(93.31,120.98)
  IN3 w0.127: v1(82.52,119.71) 81.92,119.11 78.9,119.11 78.03,119.99 69.73,119.99 57.25,107.5 v1(57.25,97.48)
  BOTTOM w0.089: UC1.H60 93.6,121.27 v1(93.31,120.98)
  BOTTOM w0.102: JXDP1.23 67.72,93.45 67.72,95.83 67.3,96.26 58.48,96.26 v1(57.25,97.48) ; v1(82.52,119.71) 82.64,119.84 83.01,119.84 RC141.2
XDP_PRDY#: length 48.3
  TOP w0.102: v1(74.44,102.83) 74.27,103 74.27,104.77 75.43,105.93 75.43,108.81 74.98,109.27 73.58,109.27 72.23,110.62 72.23,114.23 76.07,118.08 v3(76.61,118.08) 78.66,118.08 79.68,119.1 82.61,119.1 84.39,120.88 86.52,120.88 86.55,120.91 87.39,120.91 v1(87.63,121.16)
  BOTTOM w0.076: UC1.J62 92.06,120.63 91.77,120.34 91.27,120.34 91.27,120.34 90.93,120.34 90.73,120.54 90.73,120.54 90.44,120.83 90.43,120.83 90.38,120.89 88.96,120.89
  BOTTOM w0.102: JXDP1.5 72.2,95.3 72.57,95.67 73.45,95.67 74.26,96.47 74.26,102.65 v1(74.44,102.83)
  BOTTOM w0.109: 88.96,120.89 88.69,121.15 87.73,121.15 87.72,121.16 v1(87.63,121.16)
XDP_PREQ#: length 52.2
  TOP w0.102: v1(85.51,120.15) 85.47,120.11 85.47,119.94 84.9,119.37 v3(84.9,119.36) 84.49,119.36 82.82,117.69 76.01,117.69 72.47,114.15 72.47,110.7 73.68,109.5 75.07,109.5 75.66,108.91 75.66,105.83 74.73,104.9 v1(74.73,103.34)
  IN3 w0.127: v1(87.14,122.77) 86.16,122.77 85.51,122.12 v1(85.51,120.15)
  BOTTOM w0.076: UC1.K62 91.85,119.43 91.85,119.43 91.84,119.42 91.35,119.42 91.09,119.67 90.66,119.67 90.62,119.71 87.95,119.71 87.75,119.51 87.16,119.51 86.86,119.81
  BOTTOM w0.102: v1(87.14,122.77) 87.06,122.7 RP44.3 ; v1(85.51,120.15) 85.86,119.81 86.86,119.81 ; v1(74.73,103.34) 74.84,103.22 74.84,102.06 74.49,101.7 74.49,96.38 73.55,95.44 72.86,95.44 72.7,95.28 JXDP1.3
XDP_RST#_R: length 2.4
  BOTTOM w0.102: JXDP1.46 62.2,100.41 62.78,100.99 RC51.2
XDP_TCK: length 28
  TOP w0.089: v1(93.37,123.34) 92.91,123.8 91.68,123.8 91.23,123.34 91.23,121.85 91.84,121.24 91.84,119.44 90.72,118.32 87.17,118.32 86.76,117.91
  TOP w0.102: RP45.2 76.68,111.9 79.24,114.47 79.24,115.8 80.36,116.92 84.63,116.92 85.36,117.64 v4(86.32,117.64) 86.59,117.91 86.76,117.91
  BOTTOM w0.076: UC1.E60 93.6,123.1 v1(93.37,123.34)
XDP_TCLK: length 56.7
  IN3 w0.127: v1(77.24,111.64) 76.64,111.64 76.48,111.49 75.33,111.49 73.5,109.66 73.34,109.66 71.75,108.07 71.75,107.12 71.6,106.98 71.6,103 70.85,102.25 70.85,99.89 67.88,96.93 67.88,93.14 66.51,91.77 66.51,89.85 v1(66.76,89.61)
  BOTTOM w0.102: JXDP1.57 59.2,91.94 59.1,91.83 RP46.5 59.1,90.26 58.58,89.74 58.58,85.86 60.1,84.34 64.85,84.34 67.26,86.75 67.26,88.93 66.76,89.43 v1(66.76,89.61) ; v1(77.24,111.64) v3(78.54,111.64) 82.76,111.64 RC59.1 RC65.1
XDP_TDI: length 37
  TOP w0.102: v1(87.76,122.86) 87.76,122.82 87.31,122.37 85.24,122.37 84.54,121.68 82.2,121.68 80.87,120.34 77.69,120.34 77.33,119.98 ; 77.33,119.98 71.77,114.42 71.77,105.2 v1(72.96,104.02) ; 77.33,119.98 v4(77.33,119.98)
  BOTTOM w0.076: 88.91,122.66 90.1,122.66 90.41,122.35 90.66,122.35 91.01,122 91.52,122 UC1.F63
  BOTTOM w0.102: v1(72.96,104.02) 72.92,104.06 UC4.6
  BOTTOM w0.109: 88.91,122.66 87.94,122.66 87.76,122.85 v1(87.76,122.86) 87.76,122.86 87.42,123.2 RP44.2
XDP_TDO: length 43.4
  TOP w0.102: v1(76.05,110.16) 76.05,111.15 75.8,111.4 RP45.1 ; v1(87.68,121.97) 87.6,122.05 85.24,122.05 83.31,120.11 v4(81.74,120.11) 81.24,119.61 79.87,119.61 78.88,118.62 76.29,118.62 72,114.33 72,106.44 v1(72.96,105.48)
  BOTTOM w0.076: UC1.F62 92.06,122.13 91.77,121.84 90.94,121.84 90.6,122.18 90.25,122.18 90.01,122.43 88.91,122.43
  BOTTOM w0.102: UC4.3 72.88,105.56 v1(72.96,105.48) 73.02,105.48 73.38,105.85 74.94,105.85 75.24,106.15 75.24,109.33 76.05,110.15 v1(76.05,110.16)
  BOTTOM w0.109: 88.91,122.43 88.45,122.43 87.99,121.97 v1(87.68,121.97)
XDP_TMS: length 49.9
  TOP w0.102: v1(88.05,123.7) 84.89,123.7 83.47,122.27 82.02,122.27 80.57,120.83 73.99,120.83 v4(72.83,119.67) 65.43,112.27 65.43,103.82 v1(65.79,103.45)
  BOTTOM w0.076: 89.41,123.36 89.79,123.74 90.55,123.74 91.03,123.25 91.79,123.25 91.85,123.19 92.4,123.19 92.67,122.91 UC1.E61
  BOTTOM w0.089: 88.91,122.9 88.94,122.9 89.41,123.36
  BOTTOM w0.102: RP44.1 v1(88.05,123.7) 88.05,123.25 88.41,122.9 88.91,122.9 ; v1(65.79,103.45) 66.27,103.45 66.57,103.75 69.9,103.75 70.07,103.58 70.07,103.26 70.26,103.07 70.45,103.07 70.6,103.22 UC4.8
XDP_TRST#: length 49.7
  TOP w0.089: 86.76,118.44 86.96,118.44 87.02,118.5 90.64,118.5 91.65,119.51 91.65,121.03 91.65,121.18 91.05,121.78 91.05,123.41 91.69,124.05 93.28,124.05 v1(93.95,123.38)
  TOP w0.102: 86.76,118.44 84.21,118.44 82.92,117.15 79.95,117.15 77.75,114.95 v4(76.78,114.95) RC57.1 R2341.1 75.29,113.49 75.66,113.12 v1(75.66,112.47) 75.59,112.4 RP45.3
  BOTTOM w0.076: UC1.E59 94.25,123.08 v1(93.95,123.38)
  BOTTOM w0.102: UC4.11 68.55,105.06 68.47,104.98 66.7,104.98 65.4,106.28 65.4,110.11 65.69,110.4 70.04,110.4 71.15,111.52 74.7,111.52 v1(75.66,112.47)
XTAL24_IN: length 18.1
  TOP w0.102: v1(116.26,128.19) 116.39,128.32 116.82,128.32 117.1,128.6 117.1,130.66 116.48,131.28 v3(116.48,131.61) 116.48,132.89 117.15,133.56 RC12.2 CC6.2 118.01,134.87 117.88,134.99 116.89,134.99 116.74,135.14 116.74,136.48 YC2.3 RG6.2
  BOTTOM w0.076: v1(116.26,128.19) 116.51,128.44 116.55,128.44 116.69,128.31 116.69,127.23 115.69,126.23 115.69,125.69 UC1.A25
XTAL24_OUT: length 13.9
  TOP w0.102: YC2.1 115.37,135.61 CC7.2 RC12.1 116.23,133.68 115.85,133.3 115.85,130.96 116.74,130.07 116.74,128.73 116.68,128.66 116.42,128.66 v1(116.26,128.83)
  BOTTOM w0.076: v1(116.26,128.83) 116.48,128.61 116.62,128.61 116.85,128.38 116.85,127.16 115.86,126.16 115.86,125.44 115.56,125.15 UC1.B25
XTALIN: length 12
  BOTTOM w0.102: RG7.2 173.26,98.21 YV1.1 171.4,99.2 CV95.1 171.43,101.18 RV97.1 171.08,102.39 v3(171.08,103.14) 171.08,103.46 170.27,104.27 169.28,104.27 168.66,104.89 UV1.AV33
XTALIN_R: length 167.3
  TOP w0.102: RG4.2 CG11.1 70.95,46.56 71.48,47.09 71.48,49.31 v1(76.06,53.9)
  IN3 w0.127: v1(76.06,53.9) 81.89,53.9 82.58,54.58 104.5,54.58 105.53,55.61 117.3,55.61 118.7,54.22 172.89,54.22 174.1,55.43 174.81,55.43 177,57.62 179.85,57.62 187.87,65.64 187.87,77.62 182.59,82.9 182.59,87.78 177.57,92.8 177.57,94.14 175.73,95.98 175.24,95.98 173.59,97.64 v1(173.59,97.67)
  BOTTOM w0.102: v1(173.59,97.67) 174.12,98.21 RG7.1
XTALOUT: length 7.9
  BOTTOM w0.102: UV1.AU34 168.24,105.92 168.24,104.99 169.38,103.85 v3(169.58,103.85) 169.89,103.85 170.16,103.58 170.16,102.4 RV97.2 170.54,102.02 CV94.1 170.54,100.26 YV1.3
XTLI: length 7.5
  BOTTOM w0.102: RG8.2 35.2,77.43 v3(35.34,77.58) 35.92,78.15 YL2.1 36.77,79.03 CL36.2 38,80.26 38,80.88 37.55,81.34 UL1.29
XTLI_R: length 69.7
  TOP w0.102: RG5.2 CG7.1 v1(73.94,37.35)
  IN1 w0.127: v1(35.2,73.16) 35.2,73.06 36.13,72.12 36.13,60.04 43.65,52.53 63.26,52.53 64.8,50.98 64.8,44.34 68.86,40.28 68.86,38.81 69.68,38 73.3,38 v1(73.94,37.35)
  BOTTOM w0.102: v1(35.2,73.16) RG8.1
XTLO: length 6.5
  BOTTOM w0.102: UL1.28 37.95,81.29 38.57,80.67 CL37.2 38,79.78 38,77.53 YL2.3
N197804: length 3.2
  BOTTOM w0.102: RV98.1 175.36,93.22 175.69,92.78 v3(175.98,92.78) 176.26,92.78 176.6,93.11 UV14.4
N14128350: length 3
  TOP w0.102: v3(189.42,170.73) 188.87,171.29 PU1100.1
  TOP w0.254: PU1100.1 188.26,169.72 PR1110.2
N16988653: length 4
  BOTTOM w0.102: PC605.1 217.14,88.99 v3(217.84,88.28)
  BOTTOM w0.254: PU600.3 219.04,89.49 218.79,89.23 217.83,89.23
N16988706: length 1.8
  BOTTOM w0.102: v3(214.48,93.64) 214.67,93.45 215.34,93.45 215.63,93.74 PR605.2
N17002462: length 8
  BOTTOM w0.102: PR1206.1 186.31,186.18 v3(186.81,186.68)
  BOTTOM w0.254: PU1200.1 180.29,183.89 180.37,183.97 181.17,183.97 183.38,186.18 PC1200.1 PR1201.1 PR1206.1
N17002482: length 8.6
  BOTTOM w0.254: PU1200.4 178.94,184.94 PR1209.1 178.94,186.15 178.94,186.89 178.92,186.91 178.92,186.94 178.39,187.47 PR1204.1 v1(178.36,188.12) 178.02,188.46 v3(176.56,188.46) 176.31,188.46 176.06,188.21 PR1211.1
N17002518: length 2.9
  BOTTOM w0.102: v3(178.6,188.6) 178.66,188.54 178.77,188.54 179.08,188.22 PR1208.2
  BOTTOM w0.254: PR1209.2 179.54,187.32 PR1210.1 PR1208.2
N17037681: length 4.9
  TOP w0.102: QD18.1 57.9,13.82 RD46.2 RD18.1 v3(56.7,12.9)
N17045846: length 1.1
  BOTTOM w0.102: PR802.2 v3(201.39,62.57)
N17045965: length 2.2
  BOTTOM w0.203: 208.18,55.57 208.18,55.7 207.67,56.21 PU800.28
  BOTTOM w0.254: PR842.1 208.63,55.13 208.18,55.57
N17045986: length 12.4
  TOP w0.102: PR820.1 206.15,53.49 v3(206.29,53.35)
  TOP w0.254: v1(202.59,54.42) 203.52,53.49 PR820.1 PC813.2
  BOTTOM w0.203: PU800.7 204.19,54.94 203.99,54.75 203.67,54.75
  BOTTOM w0.254: PC809.2 201.55,53.72 202.25,54.42 v1(202.59,54.42) 202.64,54.37 203.29,54.37 ; 203.67,54.75 203.29,54.37 ; 203.29,54.37 203.37,54.29 PR846.1 203.29,53.66 203.29,52.79 PR813.2 202.44,51.97 PC817.2
N17046050: length 4.5
  TOP w0.102: PR824.2 200.96,59.75 v3(200.65,60.06)
  TOP w0.254: PR824.2 202.55,59.75 202.72,59.58 202.72,58.71 v1(202.52,58.51)
  BOTTOM w0.203: PU800.13 202.87,58.21 202.58,58.51 v1(202.52,58.51)
N17046121: length 7.6
  TOP w0.102: v3(205.58,61.45) 205.58,61.05 v1(205.39,60.86)
  IN3 w1.016: 206.28,60.65 206.59,60.65 207.55,61.61 212.82,61.61
  vias: v1(205.39,60.27) v1(215.1,61.94) v1(215.1,61.35) v1(215.33,67.8) v1(215.33,67.22)
N17046167: length 7
  TOP w0.254: v1(202.34,56.02) 201.95,56.41 PC816.2 PR833.1
  BOTTOM w0.102: v3(199.44,54.47) 199.6,54.63 PR845.1
  BOTTOM w0.203: v1(202.34,56.02) 202.54,56.21 PU800.8
  BOTTOM w0.254: PR845.1 PC809.1 201.72,54.63 202.15,55.07 202.15,55.83 v1(202.34,56.02)
N17159315: length 12.7
  IN3 w0.102: 164.36,116.65 164.73,116.65 v1(165.21,117.13)
  IN3 w0.127: v1(160.17,112.02) 160.68,112.53 160.68,112.97 164.36,116.65
  BOTTOM w0.102: RV84.1 158.51,111.81 158.76,111.56 v3(159.32,111.56) 159.72,111.56 v1(160.17,112.02) ; UV1.AB34 167.52,117.34 165.43,117.34 v1(165.21,117.13)
N17216117: length 10.1
  TOP w0.102: RV89.2 181.64,103.01 v1(181.83,102.82) 181.88,102.82 v3(182.28,102.42)
  IN3 w0.102: 181.83,103.86 181.83,104.3 180.39,105.74 180.39,109.58 180.62,109.81 v1(180.87,109.81)
  IN3 w0.127: v1(181.83,102.82) 181.83,103.86
  BOTTOM w0.102: UV1.AM17 181.11,109.85 180.91,109.85 v1(180.87,109.81)
N17407779: length 3.3
  TOP w0.102: R2354.1 187.42,31.84 CE12.1 187.4,31.65 187.71,31.35 189.32,31.35 v3(189.48,31.51)
N17434554: length 4.9
  TOP w0.102: UE1.107 180.5,45.71 180.35,45.86 RE36.2 179.01,45.38 178.18,45.38 177.69,45.87 v3(177.16,45.87)
N17434555: length 90.9
  TOP w0.089: RE37.2 128.76,98.41 v1(129.51,99.16) v3(130.09,99.16)
  TOP w0.102: v1(188.19,54.34) 188.26,54.34 188.79,53.81 UE1.82
  IN1 w0.084: v1(129.51,99.16) 129.51,99.1 131,97.6 131.57,97.6
  IN1 w0.127: 131.57,97.6 132.54,97.6 136.02,94.12 139.38,94.12 147.62,85.87 149.64,85.87 159.86,75.66 169.49,75.66 174.32,70.82 174.32,64.42 174.87,63.88 174.87,60.74 177.41,58.2 177.41,56.87 177.87,56.41 177.87,54.46 v1(179.16,53.16)
  IN3 w0.127: v1(179.16,53.16) 179.36,53.36 183.34,53.36 184.32,54.34 v1(188.19,54.34)
N17434577: length 7.9
  TOP w0.102: v1(192.14,53.1) 192.05,53.18 RE7.2 ; v1(196.37,53.1) 196.1,52.82 v3(195.85,52.82) 195.5,52.82 195.19,52.51 UE1.66
  IN3 w0.127: v1(192.14,53.1) 192.67,53.63 195.84,53.63 v1(196.37,53.1)
N17438484: length 4.2
  TOP w0.102: R2355.2 34.12,20.52 CA21.1 34.89,20.66 v3(36.96,20.66)
N17494823: length 6.2
  BOTTOM w0.254: RA3.2 29.19,24.47 29.79,25.08 v3(29.79,25.42) 29.79,25.76 29.64,25.92 CA1.1 CA2.1 26.83,26.43 QA5.2
N17607640: length 6.6
  BOTTOM w0.203: PC300.1 147.95,150.12 147.68,150.38 147.68,150.97 146.85,151.8 v3(146.85,152.49) 145.72,153.63 PU300.1
  BOTTOM w0.254: PR300.1 PR301.1 PC300.1
N17607660: length 5.8
  BOTTOM w0.102: v3(150.44,155.29) 150.23,155.5 PR307.1
  BOTTOM w0.254: PU300.4 146.24,154.98 146.58,154.64 PC307.2 PR305.2 149.15,154.64 149.39,154.88 PR307.1
N17608587: length 1.4
  BOTTOM w0.102: v3(148.25,159.34) 148.43,159.15 PC302.1
N17777752: length 31.9
  TOP w0.102: RV244.1 RV245.1 153.38,115.58 152.9,116.06 152.9,122.79 153.44,123.33 155.48,123.33 155.92,122.88 v3(159.22,122.88) 171.92,122.88 172.91,121.9 v1(172.91,121.22)
  BOTTOM w0.102: v1(172.91,121.22) 172.46,120.78 UV1.V28 172.26,120.49 UV1.W29
N17839157: length 5.8
  TOP w0.102: v1(171.2,115.2) 170.71,114.71 170.71,112.59 170.91,112.4 v3(170.91,112.18) 170.91,111.32 171.36,110.86 RV246.1
  BOTTOM w0.102: UV1.AF30 170.86,114.86 v1(171.2,115.2)
N17841799: length 10
  TOP w0.102: RV247.1 167.62,109 v3(167.62,109.95) 167.62,111.1 168.54,112.03 170.07,112.03 170.51,112.47 170.51,115.05 v1(170.4,115.16)
  BOTTOM w0.102: v1(170.4,115.16) 170.06,114.82 UV1.AF31
N17860472: length 6.3
  BOTTOM w0.102: RV26.2 171.63,139.58 170.44,139.58 v3(169.58,140.45) 169.13,140.89 169.13,142.8 UV4.J13
N17945375: length 5.9
  TOP w0.102: v3(218.2,171.87) 218.15,171.87 217.58,171.3 UX1.4 217.58,170.32 218.13,169.77 218.13,169.77 218.37,169.53 218.37,169.53 218.41,169.49 218.41,167.84 217.83,167.27 CX9.1
N18009245: length 5
  TOP w0.254: PC717.2 166.83,166.49 v1(166.98,166.64) 166.99,166.64 PU701.1
  BOTTOM w0.102: v3(165.65,165.55) 166.05,165.95 PR704.1
  BOTTOM w0.254: PC708.1 166.4,167.21 v1(166.98,166.64) 166.78,166.44 PR704.1
N18009258: length 32.2
  TOP w0.254: PC719.1 169.52,173.95 PR710.2 168.56,175.05 PC722.2 168.62,175.17 168.62,176.06 168.14,176.54 163.48,176.54 163.29,176.73 161.54,178.48 161.13,178.64 161.05,178.62 160.84,178.75 160.83,178.76 160.7,178.84 159.65,179.5 159.65,179.5 158.93,179.96 158.4,180.3 151.87,180.3 v3(150.13,178.56) 149.83,178.26 144.68,178.26 144.05,178.89 144.05,179.08 v1(144.11,179.14)
  BOTTOM w0.254: PR716.3 143.73,179.53 v1(144.11,179.14)
N18009264: length 0.7
  TOP w0.102: v1(145.37,162.42) 145.37,162 v3(145.19,161.82)
N18009271: length 5
  TOP w0.254: PU701.2 167.49,166.71 v1(167.56,166.63) 167.75,166.45 PC717.1
  BOTTOM w0.102: v3(168.73,165.42) 168.21,165.95 PR717.1
  BOTTOM w0.254: PC707.1 167.56,167.5 v1(167.56,166.63) 167.67,166.52 PR717.1
N18009295: length 31.2
  TOP w0.254: PR708.2 167.67,175.08 PC722.1 168.24,175.65 168.24,175.9 167.98,176.16 163.32,176.16 162.83,176.65 161.33,178.15 161.1,178.24 160.98,178.21 160.79,178.33 160.73,178.36 160.69,178.36 160.6,178.45 160.34,178.61 159.43,179.19 158.29,179.92 152.7,179.92 v3(152.24,179.46) 150.65,177.87 144.52,177.87 143.67,178.73 143.67,178.89 v1(143.48,179.08)
  BOTTOM w0.254: v1(143.48,179.08) 143.48,179.02 143.73,178.76 PR716.2
N18009369: length 2
  TOP w0.254: PU701.9 170.5,169.93 171.34,170.76 PR714.2
N18009411: length 1.4
  BOTTOM w0.102: v3(148.58,184.24) 148.24,183.91 PR706.1
N18009417: length 2
  TOP w0.102: v3(156.37,178.64) PR722.1 156.37,176.6
N18009452: length 3.6
  TOP w0.102: PQ708.2 172.81,175.01 v3(173.37,174.45)
  TOP w0.254: PQ708.2 172.13,176.09 PR724.2 PC723.1
N18009461: length 1.8
  TOP w0.254: PR715.2 171.16,169.87 170.72,169.43 PU701.8
N18107051: length 4.2
  BOTTOM w0.102: UV1.AM39 164.47,109.69 v3(163.41,108.62) 162.61,107.83 RV127.1
N18262754: length 4.7
  TOP w0.102: RV207.1 v3(167.79,113.65) 168.17,114.04 v1(168.17,115.15)
  BOTTOM w0.102: UV1.AF33 168.17,114.78 v1(168.17,115.15)
N18284053: length 0.7
  TOP w0.102: v1(134.99,175.22) v3(135.65,175.22)
N18386761: length 5
  TOP w0.102: RV31.2 v3(190.21,140.18) 189.62,140.77 189.62,142.76 UV3.J13
N18923200: length 2.3
  TOP w0.102: v3(203.39,10.6) 203.56,10.42 v1(204.05,10.42)
  BOTTOM w0.508: RC10.1 v1(204.05,10.42) 203.96,10.52 DC1.2
N19505504: length 1.6
  TOP w0.089: T117.1 128.05,112.55 v1(128.63,111.97)
  BOTTOM w0.076: v1(128.63,111.97) 128.33,112.27 UC1.AD4
N19607621: length 5.4
  BOTTOM w0.102: v3(15.42,117.45) 15.64,117.23 QX5.2 15.64,114.35 15.09,113.8 RX15.1
N19636367: length 6
  BOTTOM w0.254: RA7.2 RA6.2 v3(14.76,23.55) 14.38,23.18 14.38,21.73 14.76,21.35 QA6.2
N19794620: length 6.1
  BOTTOM w0.254: QA6.6 18.56,20.7 18.76,20.9 18.76,21.35 ; RA5.2 17.62,24.2 v3(18.45,23.37) 18.81,23.01 18.81,21.4 18.76,21.35 ; 18.76,21.35 QA6.5
N21178712: length 1.7
  TOP w0.102: PR5.2 132.7,172.92 v3(132.91,172.71)
N21178859: length 4.5
  TOP w0.254: v1(196.29,61.4) v3(195.58,61.4) 194.89,61.4 194.67,61.62 PC1302.1
  BOTTOM w0.254: v1(196.29,61.4) 195.81,61.4 195.16,62.06 PU1300.7
N21219517: length 17.3
  TOP w0.102: RV64.2 v4(179.24,104.46) v1(180.31,103.39)
  IN3 w0.102: 180.01,103.69 179.93,103.77 179.93,104.38 179.71,104.6 179.71,110.13 179.22,110.62 179.22,112.21 180.14,113.13 v1(183.03,113.13)
  IN3 w0.127: 180.01,103.69 v1(180.31,103.39)
  BOTTOM w0.102: v1(183.03,113.13) 182.91,113.13 UV1.AH16
N21220354: length 31.7
  TOP w0.102: RV203.1 164.49,99.58 v3(165.02,100.1) 166.1,101.18 v1(167.64,101.18)
  IN3 w0.102: 164.11,113.35 164.3,113.54 165.44,113.54 166.21,114.3 168.59,114.3 169.25,114.97 169.25,115.51 169.55,115.8 170.05,115.8 171.03,116.78 171.48,116.78 171.92,117.22 171.92,118.17 v1(171.35,118.74)
  IN3 w0.127: v1(167.64,101.18) 167.64,103.02 162.27,108.39 162.27,109.39 163.38,110.5 163.38,112.62 164.11,113.35
  BOTTOM w0.102: v1(171.35,118.74) 171.66,119.05 UV1.Y29
N21246320: length 3.2
  BOTTOM w0.102: v3(174.92,188.62) 175.15,188.39 PR1211.2
  BOTTOM w0.254: PQ1201.1 173.92,187.46 PR1211.2
N21246524: length 3.6
  BOTTOM w0.102: v3(173.66,182.19) 173.46,182.39 PR1212.2
  BOTTOM w0.254: PQ1201.2 174.1,184.8 PC1214.1 PR1212.2
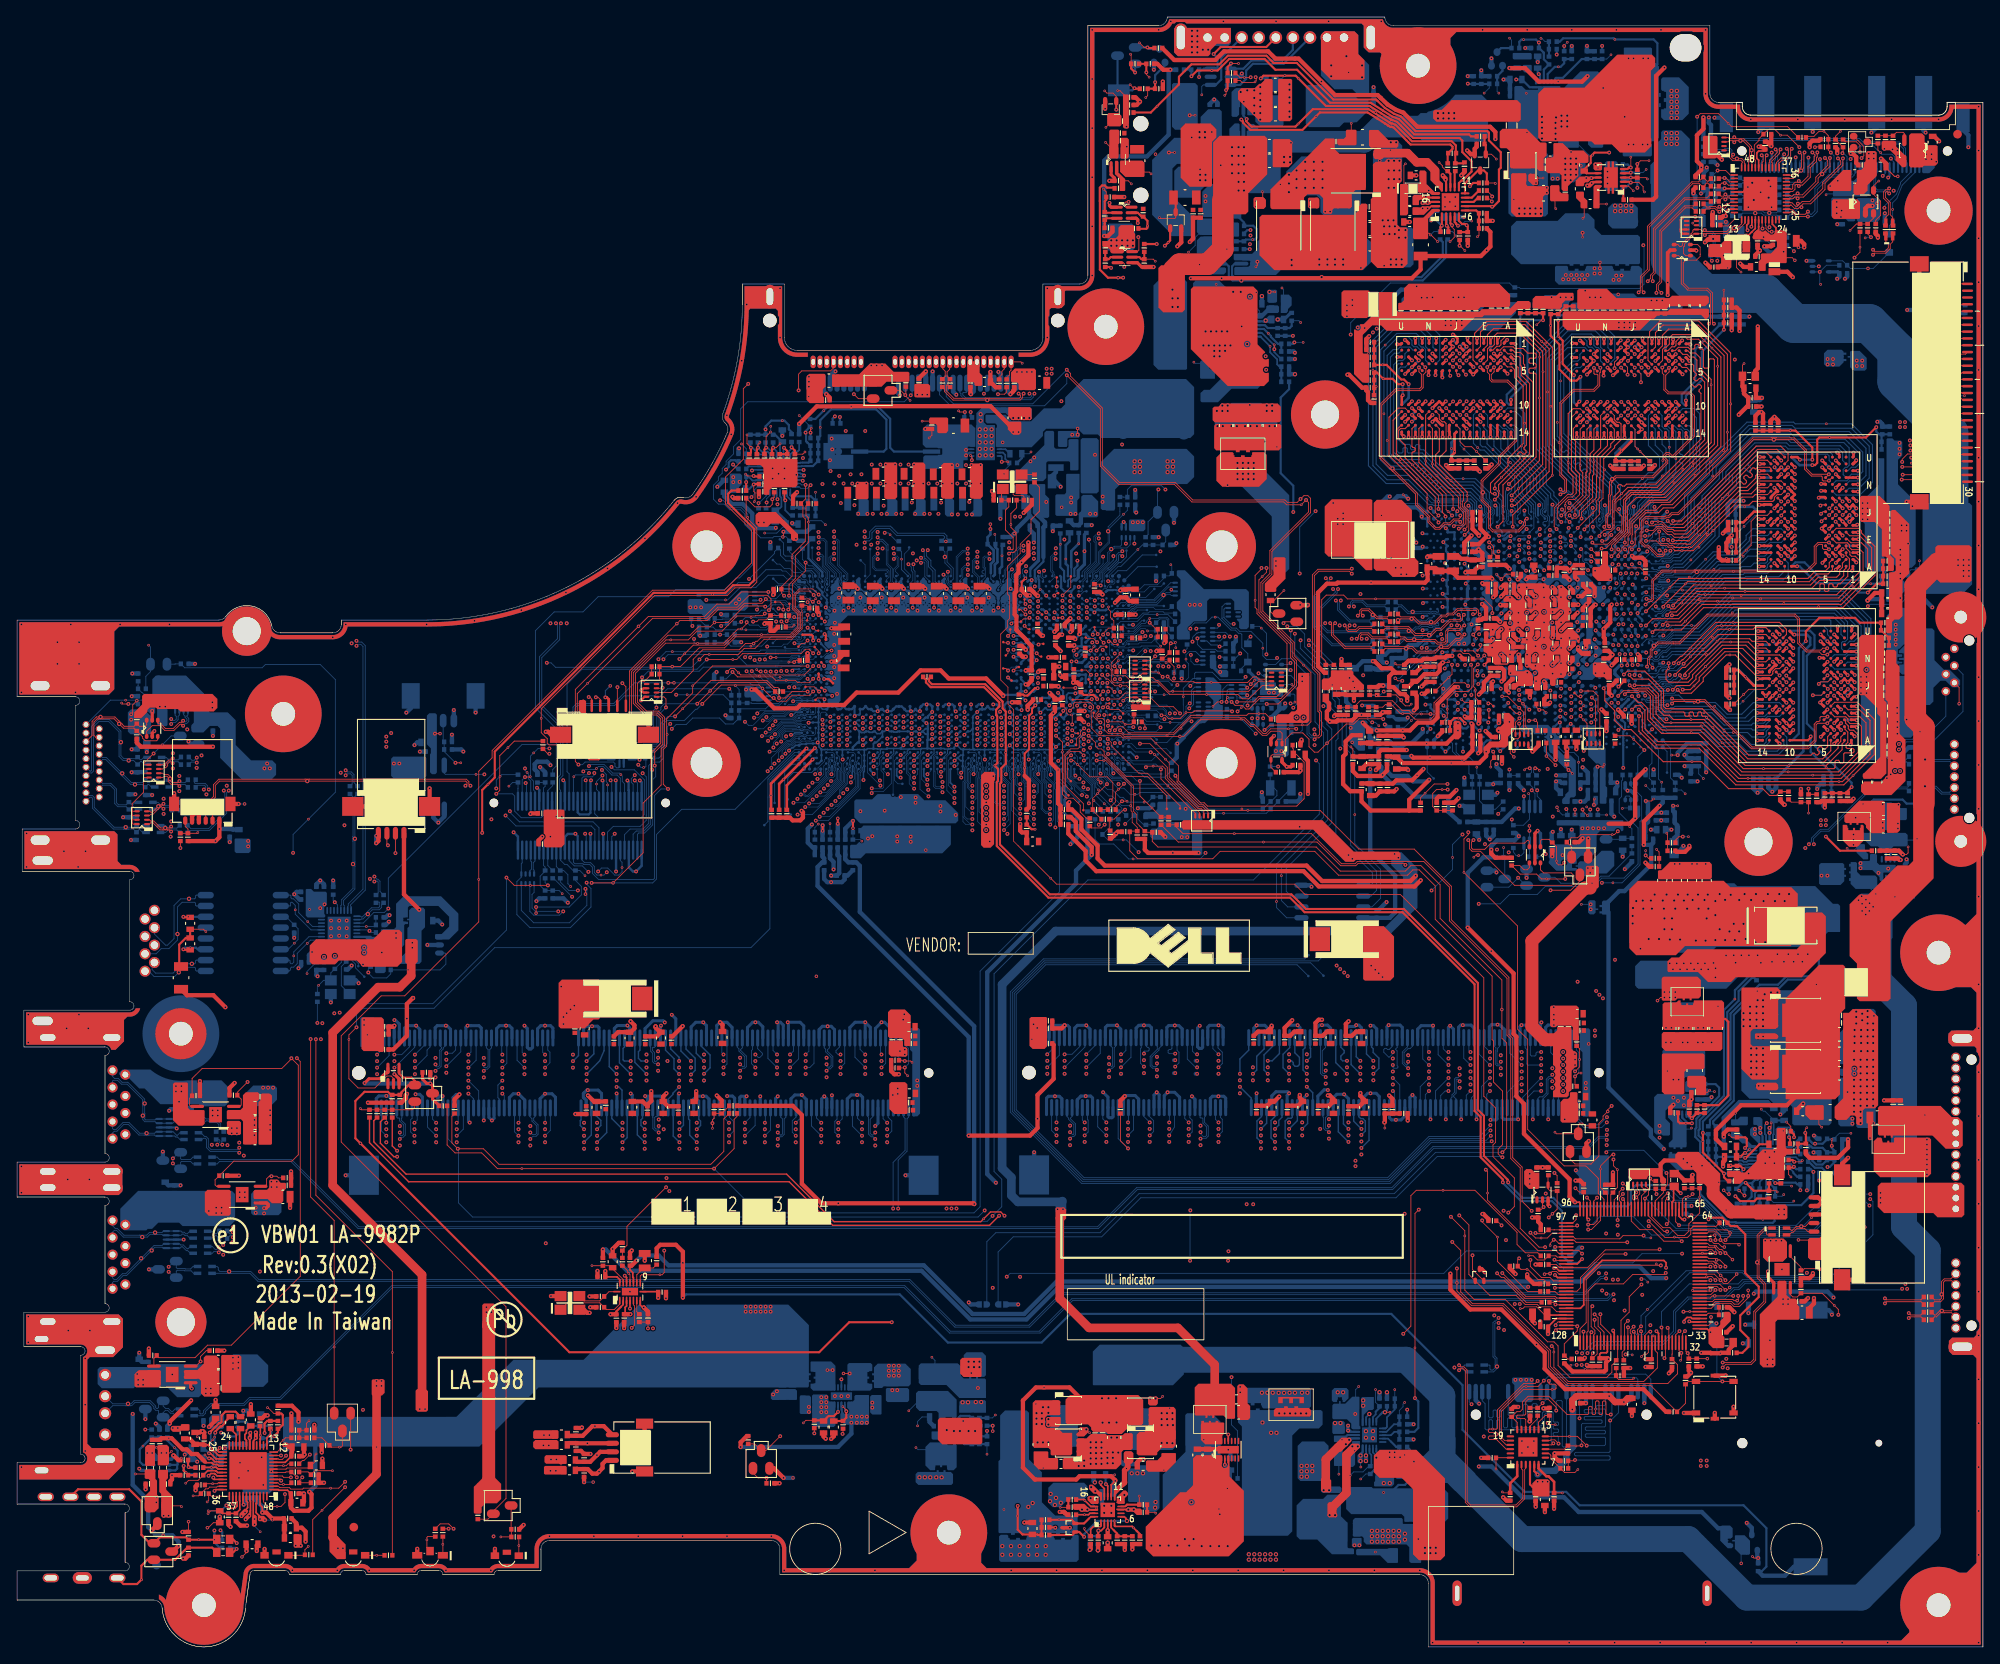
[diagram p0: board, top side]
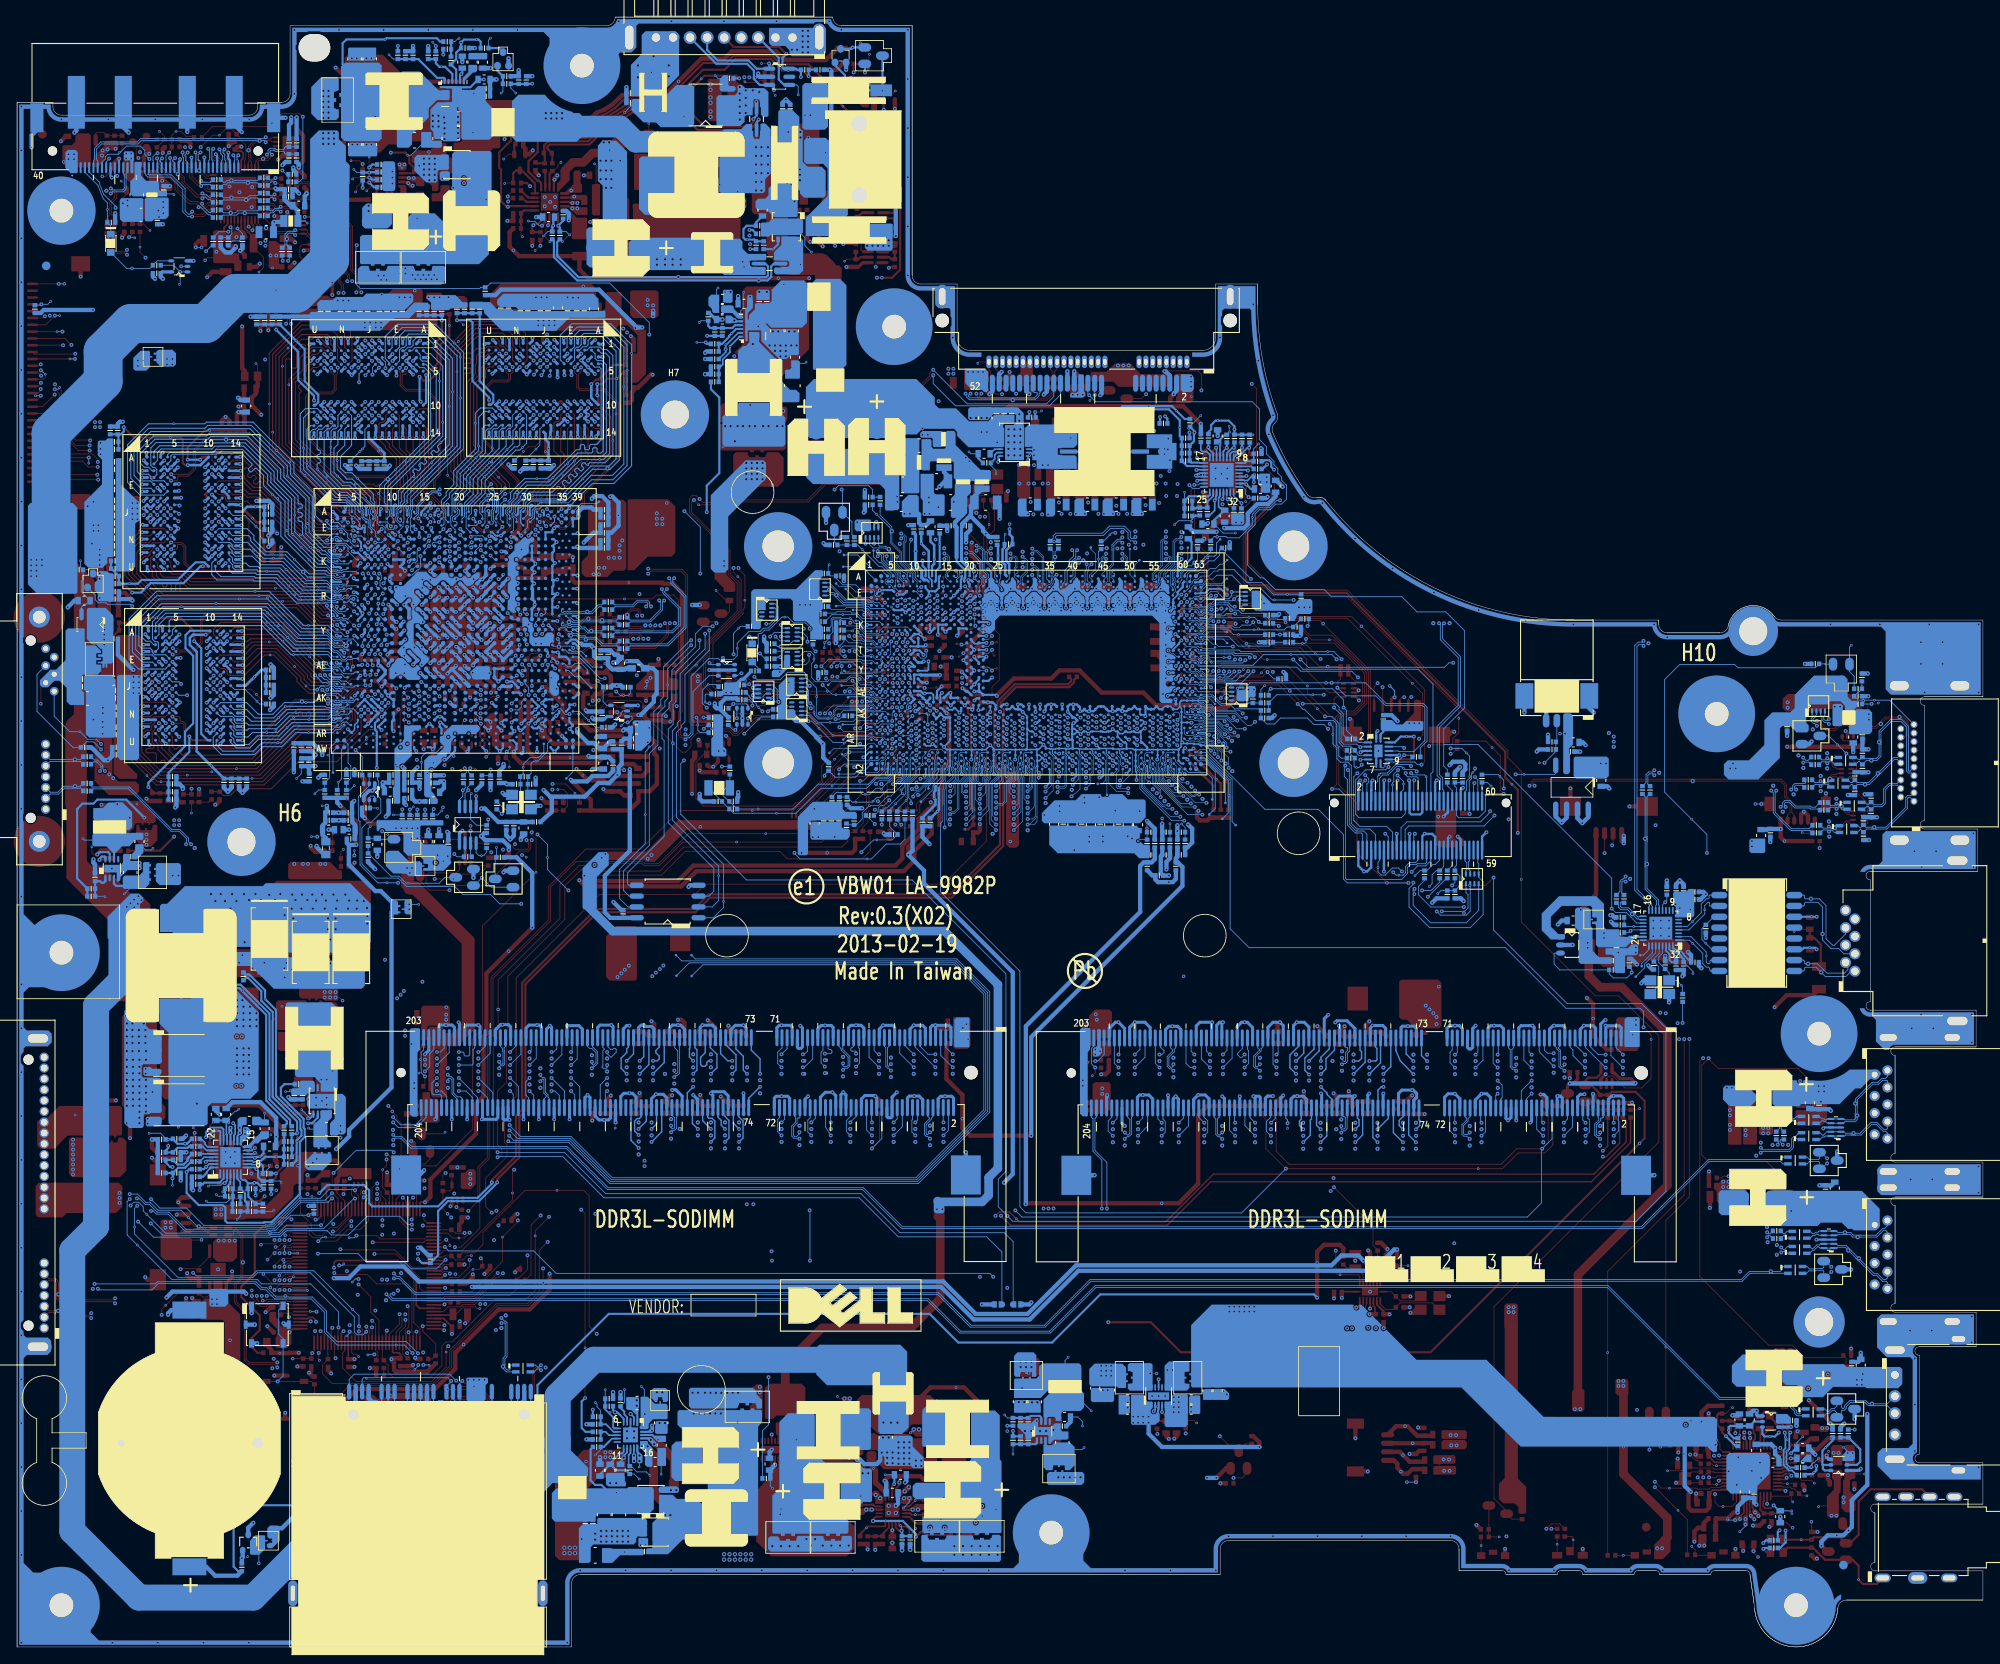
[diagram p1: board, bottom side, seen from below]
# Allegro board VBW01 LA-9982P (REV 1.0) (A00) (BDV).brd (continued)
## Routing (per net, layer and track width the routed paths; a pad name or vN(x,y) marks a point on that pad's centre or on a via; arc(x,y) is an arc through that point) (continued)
N24240984: length 2.3
  TOP w0.102: LED2.1 v3(42.14,10.74) RD15.2
N24318303: length 3.1
  TOP w0.102: v3(34.13,11.79) 33.73,11.4 RD14.2 33.67,10.74 LED1.1
N24321830: length 2.2
  TOP w0.102: RD18.2 58.81,12.87 v3(58.81,11.88) LED4.1
N24325354: length 2.2
  TOP w0.102: RD16.2 v3(49.9,12.04) 49.9,10.74 LED3.2
N24325373: length 2.8
  TOP w0.102: RD17.2 48.13,12.94 48.03,12.84 v3(48.03,12.55) 48.03,11.61 LED3.3
N25368131: length 6
  TOP w0.102: RV25.2 172.11,139.1 v3(171.05,140.16) 170.47,140.73 169.7,140.73 169.11,141.32 169.11,142.82 UV5.J13
N25669355: length 5
  BOTTOM w0.102: RV30.2 v3(189.93,140.46) 189.64,140.75 189.64,142.74 UV6.J13
N26889205: length 2.3
  TOP w0.102: v3(171.03,118.23) 170.66,118.6 v1(170.66,118.7) 171.22,119.26 RV198.1
  BOTTOM w0.102: v1(170.66,118.7) 170.86,118.9 UV1.Y30
N32320781:
  vias: v3(138.59,162.08)
N32936693: length 4.5
  TOP w0.102: v3(133.88,167.58) 133.99,167.48 135.7,167.48 135.79,167.57 PQ706.1
  TOP w0.254: PR720.2 135.79,169.68 PQ706.1
N39186606: length 2.5
  TOP w0.102: v3(179.21,109.54) 178.89,109.87 v1(178.4,109.87) 178.07,110.2 RV125.1
  BOTTOM w0.102: v1(178.4,109.87) 178.34,109.87 177.91,110.29 UV1.AL21
N39195318: length 2.7
  TOP w0.102: v1(173,104.97) 173.11,104.85 RV123.1 172.71,103.87 v3(172.71,103.16)
  BOTTOM w0.102: v1(173,104.97) 172.66,105.31 UV1.AW28
N39348342: length 5
  BOTTOM w0.102: RV122.1 183.01,102.47 v3(183.01,103.73) 183.01,104.34 182.47,104.88 181.28,104.88 UV1.AW18
N39890903: length 23
  TOP w0.102: CV218.1 194.35,94.58 194.77,95 v1(195.23,95)
  IN3 w0.102: v1(187.65,110.69) 187.2,110.24 187.2,107.43 189.47,105.16 189.47,103.69
  IN3 w0.127: v1(195.23,95) 193.13,95 190.06,98.07 190.06,101.04 189.47,101.63 189.47,103.69
  BOTTOM w0.102: v1(195.23,95) v3(195.88,95) ; v1(187.65,110.69) 187.26,111.08 UV1.AK10
N39890907: length 2.1
  TOP w0.102: v3(192.15,93.5) 192.44,93.21 CV219.2 RV137.1
N39890909: length 2.1
  TOP w0.102: RV136.1 CV218.2 193.43,95.32 v3(193.35,95.41)
N39890911: length 3.8
  TOP w0.102: v3(209.96,97.77) RV143.2 CV222.1 207.93,99.05 RV144.1
N39890927: length 22.1
  TOP w0.102: CV219.1 191.22,92.46 v1(190.87,92.81)
  IN3 w0.102: 189.19,103.69 189.19,105.15 187,107.35 187,110.58 v1(186.88,110.7)
  IN3 w0.127: v1(190.87,92.81) 191.67,93.61 191.67,95.01 191.03,95.64 191.03,96.74 189.8,97.97 189.8,100.85 189.19,101.46 189.19,103.69
  BOTTOM w0.102: v1(190.87,92.81) v3(190.87,93.36) ; UV1.AL10 187.26,110.32 186.89,110.7 v1(186.88,110.7)
N39986171: length 12.9
  BOTTOM w0.102: QV24.1 180.24,90.24 180.93,89.55 v3(184.59,89.55) 184.8,89.55 185.63,90.37 186.58,90.37 RV107.2 RV108.1
N39986181: length 4.5
  BOTTOM w0.102: v3(189,96.18) 189.26,95.93 RV108.2 189.24,94.81 CV103.1 188.06,94.69 QV22.2
N40812716: length 5.2
  TOP w0.102: CR3.2 v3(181.12,18.06)
  TOP w0.305: CR3.2 180.14,19.35 179.48,20.01 179.23,20.01 178.32,20.92 UR1.6
N45520480: length 3.2
  TOP w0.102: RV206.2 174.55,125.78 v1(173.96,125.19) 173.96,125.21 v3(173.39,125.77)
  BOTTOM w0.102: UV1.M27 173.46,125.51 173.78,125.19 v1(173.96,125.19)
N46608735: length 2.5
  BOTTOM w0.254: PR701.1 v3(141.79,163.89) 141.21,164.47 PQ701.2
N46608740: length 4.7
  BOTTOM w0.102: v3(137.3,163.54) 138.07,164.32 138.07,165.26 139.33,166.51 PQ701.4
N46608753: length 6.6
  BOTTOM w0.254: PC701.2 143.81,167 PC702.1 144.88,166.63 145.26,166.25 145.26,165.22 145.05,165.01 v3(144.82,165.01) 144,165.01 PR703.1 PR701.2
N46612327: length 3.5
  TOP w0.102: v3(166.66,174.06) 167.04,173.68 167.04,173.52 167.53,173.04 PR708.1
  TOP w0.254: PU701.13 167.99,172.72 PR708.1
N46612330: length 1.9
  TOP w0.254: PU701.12 168.49,172.96 PR710.1
N46660696: length 1.1
  TOP w0.102: PC520.2 v3(106.08,143.72)
N46662317: length 2.6
  TOP w0.102: v1(86.33,137.3) 85.59,137.3 v3(85.38,137.51)
  TOP w0.254: PR510.1 86.39,137.23 v1(86.33,137.3)
  BOTTOM w0.203: v1(86.33,137.3) 86.4,137.22 PU501.4
N46663656: length 4.8
  TOP w0.102: v1(86.34,136.3) 86.34,135.5 86.49,135.35 86.49,134.37 v3(86.4,134.28)
  TOP w0.254: PC504.1 86.38,136.35 v1(86.34,136.3)
  BOTTOM w0.203: PU501.2 86.45,136.42 v1(86.34,136.3)
  BOTTOM w0.254: PR516.2 85.81,135.77 v1(86.34,136.3)
N46665785: length 3.6
  BOTTOM w0.102: v3(94.74,131.58) 94.27,132.05 92.81,132.05 92.66,132.2 PR529.1
  BOTTOM w0.254: PR529.1 92.36,132.6 92.29,132.66 PC514.1
N46673636: length 6.6
  TOP w0.102: v3(93.08,142.88) 93,142.8 v1(93,142.38)
  IN1 w0.254: v1(96.43,144.21) 96.43,144.1 96.1,143.77 93.85,143.77 92.89,142.82 92.89,142.48 v1(93,142.38)
  BOTTOM w0.254: PR515.1 92.99,141.76 92.99,142.38 v1(93,142.38) ; PH501.2 96.43,143.52 v1(96.43,144.21)
N46674251: length 19.1
  BOTTOM w0.254: PL502.2 102.77,140.16 102.33,140.6 102.33,144 100.83,145.49 95.07,145.49 v3(94.53,144.95) 93.56,143.98 PR518.2
N46860163: length 6.6
  TOP w0.102: PR713.2 173.18,171.65 v3(173.25,171.58)
  TOP w0.254: PU701.10 169.7,170.44 169.7,171.59 170.02,171.91 170.02,171.91 171.23,173.11 PQ708.1 171.91,173.11 172.25,172.77 PR713.2
N46975913: length 2.5
  BOTTOM w0.102: v3(118.83,140.11) 118.62,139.9 PR536.2
  BOTTOM w0.254: PR536.2 117.76,139.38 PC501.1
N46975982: length 1.5
  BOTTOM w0.203: PU502.6 115.31,140.43 115.32,140.43 115.83,140.43 PR536.1
N46976065: length 3.5
  BOTTOM w0.102: PC501.2 116.28,138.53 115.67,137.92 v3(115.67,137.54)
  BOTTOM w0.203: PU502.7 115.54,140.03 115.81,139.76 115.81,139.29 PC501.2
N47007806: length 2.4
  TOP w0.254: PR28.2 127.46,166.88 127.47,166.89 PC16.1 127.66,167.51 PQ2.3
N47007810: length 4.3
  TOP w0.102: PR29.1 127.65,170.6 v3(127.33,170.92)
  TOP w0.254: PR29.1 127.65,169.67 127.47,169.49 PC16.2 127.55,168.16 PQ2.2
N47007850: length 4.2
  TOP w0.254: PR33.2 131.47,166.27 132.35,166.27 132.48,166.4 v3(132.48,166.62) 132.48,167.21 PR31.1 131.8,167.7 131.35,168.16 PQ2.5
N47007898: length 3.8
  TOP w0.102: PR32.1 133.17,162.71 v3(133.4,162.48)
  TOP w0.254: PQ3.5 131.54,162.95 131.78,162.71 PR32.1 PC14.2
N47008006: length 1.4
  TOP w0.102: v3(127.57,176.41) 128.22,175.76 PQ1.6
N47008041: length 1.2
  TOP w0.102: v3(130.59,171.54) 130.23,171.91 PC5.1
N47008110: length 2.4
  TOP w0.254: PQ3.2 128.17,162.95 127.93,162.71 PR30.2 PC15.1
N47008134: length 7.4
  TOP w0.102: v3(130.45,183.16) 130.85,182.76 v1(130.97,182.76)
  TOP w0.254: PR6.2 131.03,182.7 v1(130.97,182.76)
  BOTTOM w0.254: v1(130.97,182.76) 130.71,182.51 PL2.2 128.97,182.66 PQ6.1
N47008301: length 1.4
  TOP w0.102: v3(127.61,178.17) 128.17,178.73 PQ4.1
N47305899: length 1.9
  TOP w0.102: v3(211.51,60.94) 211.17,61.28 PR805.1
N47415217: length 1.9
  TOP w0.102: PC104.2 133.35,15.79 v3(133.45,15.68)
  TOP w0.254: PR103.1 PC104.2
N47415258:
  vias: v3(134.4,20.73)
N47415272:
  vias: v3(120.27,20.97)
N47415370: length 1.9
  TOP w0.102: PC110.1 123.18,16.37 v3(122.25,16.37)
  TOP w0.254: PR111.2 PC110.1
N47417471: length 2.6
  BOTTOM w0.102: v3(105.35,23.37) 105.59,23.13 PC405.1
N47417524: length 3.4
  BOTTOM w0.102: v3(105.54,25.92) 105.54,26.43 106.07,26.97 PR405.2
  BOTTOM w0.508: PC401.1 106.94,26.38 PR405.2
N47420895:
  vias: v3(159.2,11.13)
N47445410: length 2.2
  TOP w0.203: PR114.1 v3(125.1,15.5) 125.57,15.5 125.73,15.67 PU100.19
N47894294: length 2
  BOTTOM w0.089: v3(99.01,94.49) 98.84,94.65 RC23.1 97.97,94.67 CC8.2
N47894380: length 2
  BOTTOM w0.089: RC24.1 93.51,95.52 CC9.2 93.5,96.07 v3(93.91,96.48)
N47894401: length 1.9
  BOTTOM w0.089: RC25.1 95.28,94.67 CC10.2 v3(95.28,96.53)
N47938591: length 9.5
  TOP w0.089: v1(125.05,107.06) 125.04,107.06 124.49,106.5 124.49,105.46 124.32,105.3 123.48,105.3 122.7,104.53 122.7,100.37 T118.1
  BOTTOM w0.089: UC1.AN10 124.62,107.48 v1(125.05,107.06)
N47938593: length 3
  TOP w0.089: v1(125.06,107.71) 125,107.71 124.65,107.36 124.65,106.96 124.17,106.48 124.17,105.8 T119.1
  BOTTOM w0.076: v1(125.06,107.71) 124.63,108.13 UC1.AM10
N47938689: length 1.1
  TOP w0.089: v1(121.56,123.27) 121.85,123.55 T120.1
  BOTTOM w0.089: v1(121.56,123.27) 121.89,122.94 UC1.E15
N47938710: length 3.2
  TOP w0.089: T121.1 123.5,124.25 v1(122.53,123.29)
  BOTTOM w0.089: v1(122.53,123.29) 122.88,122.94 UC1.E13
N47964855: length 5.3
  BOTTOM w0.076: UC1.L60 93.3,118.79 92.83,118.79 92.78,118.84 92,118.84 91.84,118.67 91.06,118.67 90.73,119.01 T153.1
N47964866: length 2.3
  TOP w0.254: T154.1 93.1,118.67 93.26,118.52 93.26,118.05 v1(93.3,118.01)
  BOTTOM w0.254: v1(93.3,118.01) 93.6,118.31 UC1.N60
N47964871: length 1.8
  TOP w0.109: v1(116.14,114.48) 115.89,114.73 T155.1
  BOTTOM w0.076: v1(116.14,114.48) 116.55,114.88 UC1.W23
N47964873: length 1.7
  TOP w0.089: v1(116.79,114.48) 117.21,114.89 T156.1
  BOTTOM w0.076: UC1.Y22 v1(116.79,114.48)
N47964879: length 7.3
  BOTTOM w0.076: UC1.AV62 91.95,103.9 91,103.9
  BOTTOM w0.102: 91,103.9 88.79,101.69 T157.1
N47964884: length 6.6
  BOTTOM w0.076: T158.1 93.18,127.56 94.81,125.94 94.81,125.41 94.67,125.27 94.67,124.97 94.71,124.93 94.71,124.78 94.64,124.72 94.64,124.44 94.73,124.35 94.73,124.17 94.63,124.07 94.63,123.78 94.94,123.47 UC1.D58
N47965485: length 9.1
  BOTTOM w0.102: UC1.AV63 91.21,104.23 91.08,104.09 90.92,104.09 88.46,101.63 88.46,97.77 T146.1
N47965487: length 10.5
  BOTTOM w0.089: 88,99.65 88,101.74
  BOTTOM w0.102: UC1.AU63 91.14,104.89 88,101.74 ; 88,99.65 88,96.77 T147.1
N47965489: length 1.3
  TOP w0.089: v1(119.71,117.53) 119.8,117.61 T160.1
  BOTTOM w0.076: UC1.P20 119.3,117.53 v1(119.71,117.53)
N47965491: length 1.3
  TOP w0.089: T162.1 119.88,116.12 v1(119.49,116.51)
  BOTTOM w0.076: v1(119.49,116.51) 119.1,116.9 UC1.R20
N47965493: length 4.1
  BOTTOM w0.102: UC1.A5 127.72,125.72 129.14,127.14 129.35,127.14 130.03,127.81 T159.1
N47965495: length 3.4
  BOTTOM w0.102: T148.1 89.23,124.64 91.17,124.64 91.56,124.25 UC1.C63
N47965502: length 3.4
  BOTTOM w0.076: T161.1 132.28,123.04 UC1.E1
N47965509: length 4.3
  BOTTOM w0.076: 89.94,124.44 90.99,124.44 91.51,123.92 92.04,123.92 UC1.C62
  BOTTOM w0.089: 88.91,124.35 89,124.44 89.94,124.44
  BOTTOM w0.102: T149.1 88.91,124.35
N47965511: length 4.5
  BOTTOM w0.076: UC1.D1 132.1,123.7 132.76,124.36 134.08,124.36 T163.1
N47965522: length 4.7
  BOTTOM w0.076: UC1.B43 104.41,125.15 104.7,125.44 104.7,125.68 103.98,126.4 103.98,128.14 104.54,128.7
  BOTTOM w0.102: T150.1 104.54,128.9 104.54,128.7
N47965524: length 1.8
  TOP w0.089: T164.1 117.95,120.53 118.53,120.53 v1(118.66,120.66)
  BOTTOM w0.089: v1(118.66,120.66) 118.78,120.66 UC1.J20
N47965529: length 2.1
  BOTTOM w0.076: T151.1 99.39,126.88 UC1.A51
N47965534: length 4.1
  BOTTOM w0.076: UC1.B51 99.39,125.15 99.98,125.73 T152.1
N47965536: length 1.1
  TOP w0.089: v1(119.66,121.32) 119.87,121.32 T165.1
  BOTTOM w0.076: v1(119.66,121.32) 119.98,120.99 UC1.H18
N48037563: length 4.9
  TOP w0.102: RD6.2 103.96,68.78 v1(104.04,68.7) 104.74,68.7 v3(104.89,68.55)
  BOTTOM w0.102: JDIMM1.197 103,69.44 103.74,68.7 v1(104.04,68.7)
N48037565: length 5.6
  TOP w0.102: RD7.2 104,67.89 v1(104.04,67.94) 104.04,67.31 v3(104.38,66.97)
  BOTTOM w0.102: v1(104.04,67.94) 104.49,68.38 104.49,70.18 104.2,70.46 JDIMM1.201
N48039107: length 5.8
  TOP w0.102: v3(81.5,60.81) v1(81.5,61.42) 81.5,61.8 81.69,61.99 CD21.1 CD22.1 83.46,63.42 RD4.1
  BOTTOM w0.102: JDIMM1.126 81.7,62 81.5,61.8 v1(81.5,61.42)
N48039213: length 7.2
  TOP w0.102: QD2.3 46.61,63.29 46.3,62.98 R2349.1 R2348.1 R2350.1 R2352.1 40.37,62.98 v3(40.23,63.12)
N48051997: length 5.3
  TOP w0.102: 160.3,61.55 v3(160.3,60.84)
  TOP w0.508: RD10.1 162.06,62.55 CD53.1 CD52.1 160.3,61.55 v1(160.25,61.5)
  BOTTOM w0.356: v1(160.25,61.5) JDIMM2.126
N48052813: length 7.8
  TOP w0.102: RD13.1 183.13,70.13 v3(183.13,68.88) 183.13,68.02 v1(182.59,67.48)
  BOTTOM w0.102: JDIMM2.197 181.55,70.04 182.03,69.56 182.03,68.04 v1(182.59,67.48)
N48052822: length 7
  TOP w0.102: v3(183.3,67.29) 182.98,67.29 v1(182.59,66.9) 182.59,65.94 RD12.1
  BOTTOM w0.102: JDIMM2.201 182.75,70 183.04,69.71 183.04,67.34 v1(182.59,66.9)
N48120577: length 2.8
  TOP w0.102: RX5.2 199.74,166.61 200.5,166.61 201.27,167.38 UX4.12
N55155843: length 2.5
  TOP w0.102: QX1.1 217.04,176.27 RX3.2 218.09,175.53 v3(218.42,175.2)
N55200533: length 18
  TOP w0.102: 14.82,101.94 14.82,102.44 ; 14.82,101.94 14.82,100.21 13.5,98.88 13.5,97.98 ; 14.82,101.94 RP59.8 ; 14.82,102.44 RP59.7 ; 14.82,102.44 14.82,102.94 ; 13.5,97.98 13.5,97.48 ; 13.5,97.98 RP58.5 ; 13.5,97.48 13.5,96.98 ; 13.5,97.48 RP58.6 ; v1(16,104.75) 14.82,103.58 14.82,103.44 ; RP58.8 13.61,96.48 13.5,96.59 13.5,96.98 ; 14.82,102.94 RP59.6 ; 14.82,102.94 14.82,103.44 ; 14.82,103.44 RP59.5 ; RP58.7 13.5,96.98
  BOTTOM w0.102: v1(16,104.75) v3(17.02,105.77) 18.06,106.82 QX3.1
N55201771: length 11.3
  TOP w0.102: v1(13.05,110.56) 12.36,110.56 v3(12.26,110.67)
  IN3 w0.127: v1(13.05,110.56) 9.87,110.56 8.73,109.42 8.73,105.8 JHDMI.13
  BOTTOM w0.102: v1(13.05,110.56) 13.06,110.55 RX12.2
N56393123: length 4.8
  BOTTOM w0.102: RL31.2 35.07,80.29 33.98,79.2 v3(33.98,78.95)
  BOTTOM w0.203: 36.5,81.53 36.75,81.78 UL1.31
  BOTTOM w0.254: 36.5,81.53 36.39,81.42 35.76,81.42 35.46,81.12 35.46,81.03 35.08,80.65 RL31.2
N56393790: length 4.6
  BOTTOM w0.102: T94.1 39.67,79.61 39.67,80.06 38.35,81.38 UL1.27
N56393809: length 1.7
  BOTTOM w0.102: T95.1 39.8,81.11 39.15,81.76 UL1.25
N56393828: length 2.9
  BOTTOM w0.102: T96.1 40,80.12 38.75,81.37 UL1.26
N56394014: length 7.2
  TOP w0.102: RL19.2 21.85,84.15 v3(22.12,83.87)
  TOP w0.254: CL33.1 19,80 19,82.36 19.78,83.13 RL20.2 RL19.2
N56394031: length 6.4
  BOTTOM w0.102: TL1.3 31.54,85.61 CL41.2 32.93,84.21 32.93,82.95 v3(32.5,82.52) 31.78,81.8 TL1.6
N60531222: length 72.9
  TOP w0.102: v1(142.34,110.8) 142.75,110.4 143.58,110.4 144.01,109.97 144.38,109.97 145.61,111.2 148.11,111.2 149.72,112.81 149.72,115.52 149.23,116.02 149.23,117.58 145.55,121.26 145.55,125.11 v3(145.92,125.49) 146.43,126 v1(146.43,126.5)
  IN1 w0.084: 136.53,125.81 135.66,125.81 135.28,126.19 123.37,126.19 122.71,126.85 122.71,128.51 120.97,130.25 116.36,130.25 114.9,128.79 112.3,128.79 112.11,128.6 112.11,125.55 111.6,125.04 109.25,125.04 v1(108.57,125.72)
  IN1 w0.127: 136.53,125.81 137.89,125.81 138.17,125.54 145.47,125.54 146.43,126.49 v1(146.43,126.5)
  BOTTOM w0.076: 108.74,125.68 108.87,125.55 108.96,125.45 109.02,125.29 109.02,125.18 108.98,125.06 108.96,125.03 108.96,124.84 109.01,124.69 109.11,124.54 UC1.C35
  BOTTOM w0.089: 108.74,125.68 108.7,125.72 v1(108.57,125.72)
  BOTTOM w0.102: RP41.1 142.08,111.29 142.01,111.23 142.01,111.12 142.34,110.8 v1(142.34,110.8)
N60531228: length 70.6
  TOP w0.102: v1(145.84,126.5) 145.84,126.38 145.1,125.63 v3(145.1,122.72) 145.1,121.87 145.32,121.65 145.32,121.17 148.84,117.64 148.84,112.63 147.64,111.43 145.52,111.43 144.89,110.8 v1(142.97,110.8)
  IN1 w0.084: v1(109.09,126.06) 109.94,125.21 111.53,125.21 111.93,125.62 111.93,128.67 112.23,128.96 114.83,128.96 116.29,130.42 121.05,130.42 122.88,128.59 122.88,126.92 123.44,126.36 135.54,126.36 135.83,126.07 136.69,126.07
  IN1 w0.127: 136.69,126.07 138,126.07 138.27,125.79 145.13,125.79 v1(145.84,126.5)
  BOTTOM w0.076: UC1.C34 109.71,124.38 109.54,124.55 109.37,124.55 109.16,124.76 109.13,124.86 109.13,125 109.15,125.05 109.16,125.07 109.19,125.15 109.19,125.32 109.11,125.54 109.11,125.56
  BOTTOM w0.089: 109.11,125.56 109.11,126.04 v1(109.09,126.06)
  BOTTOM w0.102: v1(142.97,110.8) 142.97,111.45 142.63,111.79 RP41.2
N60531230: length 21.2
  TOP w0.102: v3(141.86,111.33) 141.76,111.23 v1(141.76,110.8)
  IN1 w0.084: v1(125.78,110.18) 126.3,110.69 128.17,110.69 128.51,111.03 129.34,111.03 130.6,109.78 134.65,109.78 134.88,110 136.41,110
  IN1 w0.127: v1(141.76,110.8) 141.76,110.79 141.09,110.13 138.01,110.13 137.54,109.66 136.75,109.66 136.41,110
  BOTTOM w0.089: UC1.AK8 125.99,109.12 125.99,109.95 125.78,110.16 v1(125.78,110.18)
  BOTTOM w0.102: v1(141.76,110.8) 141.76,111.71 141.82,111.78 141.82,112.15 141.96,112.29 RP41.3
N60531232: length 25.1
  TOP w0.102: v1(141.17,110.8) 140.67,110.8 v3(140.15,110.28)
  IN1 w0.084: v1(125.47,109.16) 125.07,109.16 124.74,109.48 124.74,109.55 124.74,109.56 124.74,110.1 124.78,110.15 124.78,110.92 125.45,111.59 129.03,111.59 130.67,109.95 134.58,109.95 134.81,110.17 136.3,110.17 137.14,111.01 137.61,111.01
  IN1 w0.127: v1(141.17,110.8) 140.96,111.01 137.61,111.01
  BOTTOM w0.089: UC1.AL8 125.97,108.65 v1(125.47,109.16)
  BOTTOM w0.102: RP41.4 141.83,112.79 141.32,112.28 141.32,110.95 v1(141.17,110.8)
N60754677: length 5.5
  TOP w0.089: 88.91,122.52 89.42,122.52 89.79,122.15 89.79,121.64 v1(89.8,121.63)
  TOP w0.102: T111.1 88.91,122.52
  BOTTOM w0.076: UC1.H61 92.7,121.67 92.18,121.67 91.94,121.43 91.94,121.26 91.77,121.09 91.53,121.09 91.38,121.23 91.3,121.31 90.8,121.31 90.72,121.23 90.19,121.23 v1(89.8,121.63)
N60754679: length 4.3
  BOTTOM w0.076: UC1.H62 91.85,120.93 91.85,120.93 91.84,120.92 91.46,120.92 91.31,121.07 91.24,121.14 90.91,121.14 90.83,121.07 89.28,121.07 89.05,121.29
  BOTTOM w0.089: 88.91,121.43 89.05,121.29
  BOTTOM w0.102: T112.1 88.61,121.73 88.91,121.43
N60754681: length 1.1
  TOP w0.089: v1(94.67,120.23) 94.65,120.23 T113.1
  BOTTOM w0.076: v1(94.67,120.23) 94.35,119.92 UC1.K59
N60754683: length 2.1
  TOP w0.089: v1(90.39,121.64) 90.52,121.76 T114.1
  BOTTOM w0.076: UC1.H63 91.55,121.48 90.55,121.48 v1(90.39,121.64)
N60754685: length 1.3
  TOP w0.089: T115.1 93.65,119.16 v1(93.3,119.5)
  BOTTOM w0.076: v1(93.3,119.5) 93.6,119.8 UC1.K60
N60754687: length 1.2
  TOP w0.089: T116.1 92.65,120.42 v1(92.65,121)
  BOTTOM w0.076: UC1.J61 92.95,120.7 v1(92.65,121)
N60931942: length 4.6
  BOTTOM w0.076: UC1.AF2 130.07,112.04 130.08,112.04 130.09,112.05 130.4,112.05 130.55,112.2 131.91,112.2 132.43,112.72 T97.1
N60931944: length 5
  BOTTOM w0.076: T99.1 132.91,111.45 130.54,111.45 130.4,111.3 130.09,111.3 129.92,111.14 129.14,111.14 129.04,111.23 128.65,111.23 UC1.AF4
N60931946: length 6.7
  BOTTOM w0.076: UC1.AD2 129.86,112.35 130.33,112.81 131.51,112.81 132.03,113.33 132.03,113.54 132.16,113.66 132.73,113.66 133.19,113.21 134.93,113.21 T98.1
N61580896: length 5.7
  TOP w0.102: v3(180.24,60.35) 180.42,60.17 Q2307.1 182.97,61.22 183.16,61.42 183.48,61.42 183.8,61.1 R2314.2
N61580898: length 4.4
  TOP w0.102: Q2308.1 147.13,121.17 146.9,121.4 R2315.2 147.3,122.69 v3(148.48,123.87)
N63469417: length 3.8
  TOP w0.102: RA79.1 CA65.2 CA69.1 RA81.2 33.93,26.23 v3(34.21,26.52)
N63469524: length 10.6
  TOP w0.254: CA68.2 25.61,27.58 24.41,27.58 23.97,27.14 23.97,26.38 23.82,26.24 23.67,26.24 22.71,25.27 22.71,25.26 v1(22.58,25.13)
  BOTTOM w0.203: RA82.1 22.61,21.03 23.03,21.45 23.03,22.87 v3(22.93,22.97) 22.7,23.2 22.7,25.02 v1(22.58,25.13)
N63469526: length 8.6
  TOP w0.254: CA67.2 24.97,27 24.35,26.38 24.35,26.23 23.98,25.86 23.83,25.86 23.23,25.26 v1(23.23,25.11)
  BOTTOM w0.203: v1(23.23,25.11) 23.15,25.03 v3(23.15,24.6) 23.15,23.29 23.36,23.09 23.36,21.31 22.75,20.7 22.38,20.7 RA80.1
N63469613: length 3.2
  TOP w0.102: CA65.1 31.46,24.52 v3(31.18,24.24) 30.83,23.89 30.83,23.2 30.47,22.85 UA1.12
N63469617: length 2.1
  TOP w0.203: RA51.1 29.68,24.9 29.28,24.5 UA1.13
N63469687: length 3.1
  TOP w0.102: v1(22.51,22.11) 22.42,22.11 v3(22.02,22.51)
  TOP w0.203: UA1.28 23.71,21.65 23.64,21.72 23.17,21.72 22.78,22.11 v1(22.51,22.11)
  BOTTOM w0.254: v1(22.51,22.11) CA23.2
N63469697: length 2.3
  TOP w0.203: UA1.15 28.48,24.36 28.51,24.38 v3(28.51,24.83) 28.51,25.88 RA153.2
N63469703: length 3.6
  TOP w0.102: v3(22.28,17) 22.46,17.18 CA24.1 22.77,17.67 UA1.37
N63469709: length 3.9
  TOP w0.102: UA1.35 23.5,18.85 23.4,18.74 22.57,18.74 22.37,18.54 22.1,18.54 CA24.2 21.28,17.71 v3(20.63,17.71)
N63469711: length 2.2
  TOP w0.102: UA1.34 23.58,19.25 23.47,19.14 v3(22.93,19.14) 22.15,19.14 CA25.2
N63469717: length 4.4
  TOP w0.203: UA1.27 23.32,22.05 22.66,22.71 v1(22.5,22.71)
  BOTTOM w0.102: CA62.2 21.81,23.97 v3(21.12,24.65)
  BOTTOM w0.254: CA62.2 21.89,23.32 v1(22.5,22.71)
N63469723: length 5.1
  TOP w0.203: UA1.39 25.68,17.09 25.78,17 25.78,16.51 25.52,16.26 24.86,16.26 v1(24.53,16.6)
  BOTTOM w0.102: CA63.2 v3(22.41,15.96)
  BOTTOM w0.203: CA63.2 23.89,15.96 v1(24.53,16.6)
N63469729: length 6.2
  TOP w0.102: UA1.7 31.52,20.85 31.65,20.98 34.08,20.98 CA64.2 34.47,21.28 34.91,21.72 34.91,22.51 v3(35.04,22.64)
N63469750: length 2.2
  TOP w0.102: UA1.8 v3(31.22,21.25) 31.55,21.25 31.78,21.47 RA130.2
N63642793: length 44
  TOP w0.089: 136.24,101.45 136.13,101.55 136.13,103.3 v3(133.47,105.97) 132.87,106.56 129.63,106.56 129.36,106.84 127.24,106.84 127.24,106.84 126.81,106.84 125.95,107.7 125.95,108.94 125.87,109.01 125.87,109.74 126.16,110.02 126.16,110.36 125.75,110.76 123.99,110.76 123.79,110.56 123.79,110.17 v1(123.39,109.77)
  TOP w0.102: 136.24,101.45 138.71,98.97 139.14,98.97 139.53,98.58 149.97,98.58 150.84,99.45 150.84,103.74 149.92,104.66 R264.2 149.57,105.29 149.5,105.37 C51.1
  BOTTOM w0.089: v1(123.39,109.77) 123.71,110.09 UC1.AH11
N63643467: length 1
  TOP w0.089: v1(122.52,120.67) 122.02,120.67 T53.1
  BOTTOM w0.089: v1(122.52,120.67) 122.59,120.67 UC1.J13
N63643476: length 1.1
  TOP w0.089: v1(122.62,109.76) 122.62,109.61 T55.1
  BOTTOM w0.254: v1(122.62,109.76) 122.94,110.09 UC1.AH13
N63643505: length 1.9
  TOP w0.089: v1(125.87,113.98) 125.31,114.54 T56.1
  BOTTOM w0.254: UC1.AB8 125.69,113.81 v1(125.87,113.98)
N63643514: length 2.2
  TOP w0.089: T58.1 122.68,112.44 v1(124.03,112.44)
  BOTTOM w0.089: UC1.AD10 124.15,112.56 v1(124.03,112.44)
N63643523: length 1.1
  TOP w0.089: T59.1 125.57,113.36 v1(125.89,113.04)
  BOTTOM w0.089: v1(125.89,113.04) 125.69,112.84 UC1.AD8
N63656577: length 1.8
  TOP w0.089: v1(116.14,113.67) 116.5,113.31 T38.1
  BOTTOM w0.254: v1(116.14,113.67) 116.14,113.67 116.55,113.26 UC1.AB23
N63657072: length 3.9
  BOTTOM w0.076: T39.1 90.15,117.05 91.4,117.05 91.53,117.17 91.84,117.17 92,117.34 92.79,117.34 92.83,117.3 93.31,117.3 UC1.P60
N63657081: length 1.9
  TOP w0.089: v1(92.65,118.01) 92.3,117.66 91.94,117.66 T40.1
  BOTTOM w0.089: UC1.P61 92.95,117.71 v1(92.65,118.01)
N63657090: length 1.2
  TOP w0.254: T41.1 94.78,118.62 v1(94.64,118.76)
  BOTTOM w0.254: UC1.N59 94.31,118.42 v1(94.64,118.76)
N63657099: length 5.2
  BOTTOM w0.076: T42.1 89.06,118.18 90.14,118.18 90.27,118.32 91.3,118.32 91.5,118.11 91.53,118.09 91.77,118.09 91.94,118.26 91.94,118.44 92.18,118.67 92.7,118.67 UC1.N61
N63657120: length 1.5
  TOP w0.089: v1(93.95,116.51) 93.95,116.76 T43.1
  BOTTOM w0.089: v1(93.95,116.51) 94.25,116.81 UC1.T59
N63657126: length 2.4
  TOP w0.089: T44.1 93.43,112.57 v1(93.99,112.02)
  BOTTOM w0.254: UC1.AD60 93.6,112.4 v1(93.99,112.02)
N63657135: length 1.1
  TOP w0.089: T45.1 94.33,112.47 v1(94.67,112.13)
  BOTTOM w0.254: UC1.AD59 94.37,112.42 v1(94.67,112.13)
N63657146: length 1.8
  TOP w0.254: v1(94.58,113.49) 95.13,113.49 T46.1
  BOTTOM w0.254: v1(94.58,113.49) 94.58,113.59 UC1.AA59
N63657155: length 4.1
  BOTTOM w0.076: UC1.AE60 93.25,111.25 91.91,111.25 91.8,111.2 91.75,111.18 91.39,111.18 91.3,111.26 90.71,111.26 T47.1
N63657164: length 1.1
  TOP w0.254: T48.1 93.95,114.11 v1(93.95,113.51)
  BOTTOM w0.254: v1(93.95,113.51) 93.95,113.4 UC1.AC59
N63657173: length 1.8
  TOP w0.089: T49.1 93.8,111.26 94.48,111.26 v1(94.64,111.11)
  BOTTOM w0.254: v1(94.64,111.11) 94.59,111.06 UC1.AG58
N63657182: length 2.1
  TOP w0.089: T50.1 94.96,116.83 v1(95.46,116.83)
  BOTTOM w0.076: UC1.U59 94.46,116.09 94.87,116.5 95.13,116.5 v1(95.46,116.83)
N63657191: length 1.1
  TOP w0.089: v1(94.58,115.01) 94.58,115.14 T51.1
  BOTTOM w0.089: v1(94.58,115.01) 94.25,115.34 UC1.V59
N64564173: length 1.7
  TOP w0.102: PR1101.2 183.67,167.66 v3(183.52,167.5)
N64564191: length 1.9
  TOP w0.102: v3(180.34,168.62) 180.24,168.72 PR1104.2
N64734520: length 3.8
  TOP w0.089: T107.1 123.75,111.09 125.92,111.09 v1(125.96,111.13)
  BOTTOM w0.089: UC1.AJ7 126.17,109.87 126.17,110.34 126,110.51 126,111.09 v1(125.96,111.13)
N64734538: length 1.2
  TOP w0.089: T105.1 128.06,109.27 v1(127.42,109.27)
  BOTTOM w0.089: UC1.AL5 127.42,108.83 v1(127.42,109.27)
N64734540: length 5.6
  BOTTOM w0.076: T106.1 133.25,106.71 130.65,106.71 130.55,106.81 130.09,106.81 129.92,106.64 129.14,106.64 129.1,106.68 128.86,106.68 128.56,106.39 UC1.AP4
N93761952: length 6
  BOTTOM w0.102: RV163.2 201.9,130.16 201.9,130.88 v3(202.4,131.39) 203.67,132.66 205.11,132.66 UV8.J13
N93762059: length 8.1
  TOP w0.102: UV7.J13 205.13,132.68 203.95,132.68 203.23,131.96 203.23,129.16 v3(202.67,128.59) RV162.2
N93819115: length 5
  BOTTOM w0.102: UV10.J13 204.92,112.27 203.66,112.27 v3(202.29,110.89) 201.95,110.55 RV171.2
N93820861: length 5
  TOP w0.102: UV9.J13 204.94,112.28 202.95,112.28 v3(202.35,111.68) RV169.2

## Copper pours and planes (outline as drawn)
1.35V_B+ on BOTTOM (solid shape): 158.91,18.6 167.18,18.6 167.73,18.04 167.73,15.06 167.35,14.68 162.65,14.68 162.59,14.74 162.59,15.25 162.27,15.57 156.37,15.57 155.79,16.14 155.79,18.55 156,18.76 158.75,18.76
3/5V_B+ on TOP (solid shape): 131.98,28.97 131.98,26.2 131.79,26.01 130.53,26.01 129.96,25.44 129.95,25.44 129.48,24.97 127.85,24.97 127.6,25.22 126.14,25.22 125.89,25.47 125.89,25.73 125.53,26.08 123.09,26.08 122.89,26.29 122.89,29.02 123.41,29.54 131.41,29.54
3/5V_B+ on BOTTOM (solid shape): 129.47,29.26 129.47,25.25 129.19,24.97 126.66,24.97 125.9,25.73 125.9,29.36 126.08,29.54 129.19,29.54
3VALW_PCH on TOP (solid shape): 141.48,26.24 141.48,25 141.25,24.78 141.25,23.82 141.19,23.76 139.25,23.76 138.74,24.27 138.74,26.13 138.94,26.32 141.4,26.32
3VS on BOTTOM (solid shape): 95.91,32.97 95.91,30.11 95.85,30.05 93.31,30.05 92.99,30.36 92.99,30.87 93.5,30.87 93.56,30.94 93.56,32.27 93.06,32.27 92.99,32.33 92.99,33.41 93.06,33.48 95.41,33.48
5VS on BOTTOM (solid shape): 100.23,33.09 100.23,32.4 100.17,32.33 99.72,32.33 99.66,32.27 99.66,30.94 99.72,30.87 100.17,30.87 100.23,30.81 100.23,30.3 99.98,30.05 97.44,30.05 97.31,30.17 97.31,33.09 97.5,33.28 100.04,33.28
+0.675VS on BOTTOM (solid shape): 184.38,72.34 184.38,62.49 184.06,62.17 183.54,62.17 183.46,62.26 183.46,69.72 183.16,70.03 183.16,72.42 183.27,72.53 184.2,72.53
+0.675VS on BOTTOM (solid shape): 105.83,72.38 105.83,62.53 105.51,62.21 104.99,62.21 104.91,62.29 104.91,69.76 104.66,70.01 104.66,70.25 104.61,70.31 104.61,72.46 104.72,72.57 105.65,72.57
+0.675VS on BOTTOM (solid shape): 156.05,30.11 156.05,29.16 155.6,28.71 155.35,28.71 155.35,29.22 155.29,29.28 154.78,29.28 154.71,29.22 154.71,28.78 154.65,28.71 154.27,28.71 154.09,28.9 154.09,30.06 154.39,30.36 155.79,30.36
+0.675VS on IN2 (solid shape): 155.84,32.38 155.84,29.62 155.51,29.3 154.5,29.3 154.19,29.61 154.19,32.27 154.47,32.55 155.68,32.55
+0.675VS on IN2 (solid shape): 157.36,57.09 157.36,54.33 157.03,54 156.02,54 155.71,54.31 155.71,56.97 155.98,57.25 157.19,57.25
+0.675VS on IN3 (solid shape): 106.11,66.56 106.11,64.31 106.02,64.22 105.07,64.22 104.9,64.38 104.9,66.45 105.15,66.7 105.97,66.7
+0.675VS on IN3 (solid shape): 184.56,66.05 184.56,64.63 183.89,63.96 183.1,63.96 182.97,64.08 182.97,66.18 183.16,66.37 184.24,66.37
+0.675VS on IN3 (solid shape): 158.05,57.01 158.05,56.17 157.91,56.03 155.59,56.03 155.5,56.12 155.5,57.12 155.63,57.25 157.8,57.25
+0.675VS on TOP: 184.23,62.11 183.38,62.11 183.21,62.28 183.21,67.85 183.21,67.85 183.21,70.3 183.21,70.31 183.21,74.67 183.23,74.69 184.12,74.69 184.48,74.32 184.48,64.65 185.26,63.87 185.26,62.3 185.08,62.12 184.24,62.12
+0.675VS on TOP: 104.83,62.15 104.66,62.32 104.66,70.32 104.75,70.32 104.87,70.44 104.87,73.22 105.82,73.22 105.93,73.12 105.93,62.4 105.68,62.15
+0.675VSP on BOTTOM (solid shape): 157.32,29.28 157.32,25.93 157.44,25.81 157.44,25.6 157.38,25.54 156.49,25.54 156.37,25.66 156.37,26.19 155.86,26.69 154.28,26.69 154.15,26.82 154.15,28.34 154.33,28.52 155.66,28.52 155.68,28.53 156.49,29.35 157.26,29.35
+1.2VSP_B+ on TOP (solid shape): 178.52,176.39 179.15,176.39 179.25,176.29 179.25,174.85 178.91,174.51 178.91,173.11 178.84,173.05 178.39,173.05 178.07,173.37 175.11,173.37 174.97,173.51 174.97,175.33 174.59,175.72 173.89,175.72 173.76,175.84 173.76,177.68 174.08,178 176.92,178
+1.5VS on TOP (solid shape): 113.03,33.82 113.03,31.75 112.93,31.65 110.93,31.65 110.52,32.05 110.52,33.65 110.78,33.9 112.95,33.9
+1.05VS on TOP (solid shape): 148.67,127.63 148.67,125.24 147.59,124.17 147.59,123.81 147.47,123.69 146.38,123.69 146.23,123.84 146.23,124.69 147.24,125.69 147.24,127.62 147.38,127.76 148.53,127.76
+1.05VS on TOP (solid shape): 91.53,130.46 91.53,129.87 91.34,129.68 90.92,129.68 90.7,129.9 90.7,130.44 89.44,131.71 88.35,131.71 87.96,131.32 86.93,131.32 86.54,131.71 86.54,132.71 86.9,133.07 88.93,133.07
+1.05VS on TOP (solid shape): 142.59,139.96 142.59,139.58 142.65,139.52 144.68,139.52 144.75,139.58 144.75,140.03 144.81,140.09 146.14,140.09 146.46,139.77 146.46,136.92 145.57,136.03 141.25,136.03 140.55,136.73 140.55,139.46 141.19,140.09 142.46,140.09
+1.05VS on TOP (solid shape): 64.16,98.05 64.16,94.12 63.79,93.74 61.95,93.74 61.72,93.97 61.72,94.63 61.83,94.74 61.94,95.07 61.72,95.35 61.72,98.09 61.81,98.18 64.04,98.18
+1.05VS on BOTTOM (solid shape): 88.1,132.85 88.1,131.71 87.98,131.58 86.77,131.58 86.58,131.77 86.58,132.85 86.64,132.92 88.04,132.92
+1.05VS on BOTTOM (solid shape): 149.1,135.03 149.1,126.4 148.68,125.98 147.43,125.98 147.05,126.36 147.05,132.55 142.62,136.98 142.62,138.83 142.92,139.13 145,139.13
+1.5VS on BOTTOM (solid shape): 113.55,34.13 113.55,31.86 113.36,31.67 112.85,31.67 112.85,32.24 111.45,32.24 111.45,31.67 111.07,31.67 110.94,31.79 110.94,34.22 111.27,34.55 113.13,34.55
+1.05VS on BOTTOM (solid shape): 86.05,112.62 86.29,112.62 86.37,112.53 86.37,112.37 86.56,112.19 87.42,112.19 87.47,112.13 87.47,111.01 87.35,110.89 86.11,110.89 86.04,110.96 86.04,111.23 85.93,111.34 85.41,111.34 85.25,111.51 85.25,112.55 85.37,112.68 85.99,112.68
+1.05VS on BOTTOM (solid shape): 85.72,123.78 85.72,121.91 85.29,121.48 81.79,121.48 81.26,120.96 81.26,120.38 81.18,120.29 80.85,120.29 80.46,120.68 80.46,120.86 80.21,121.11 78.83,121.11 78.58,121.35 78.58,122.66 78.8,122.87 80.1,122.87 80.64,122.33 83.33,122.33 84.84,123.85 85.65,123.85
+1.05VS on BOTTOM (solid shape): 121.54,142.46 121.54,140.68 121.73,140.49 123,140.49 123.22,140.71 123.22,141.48 123.36,141.62 124.34,141.62 124.41,141.54 124.41,138.07 124.29,137.96 123.47,137.96 123.42,138.01 123.42,138.89 123.29,139.01 120.79,139.01 120.62,138.84 120.62,137.06 120.26,136.69 116.37,136.69 116.26,136.8 116.26,137.83 116.42,138 117.47,138 120.4,140.92 120.4,142.36 120.62,142.58 121.42,142.58
+1.5VS on IN1 (solid shape): 113.06,34.39 113.06,32.39 112.93,32.25 109.86,32.25 109.53,32.58 109.53,34.68 109.69,34.84 112.61,34.84
+1.5VS on IN2 (solid shape): outline of 83 points within 95.01,148.67 115.49,149.86
+1.05VS on IN2 (solid shape): outline of 3078 points within 62.88,96.79 87.97,135.68
+1.05VS on TOP: outline of 82 points within 119.04,93.77 121.19,113.9
+1.05VS on VCC: 126.37,108.91 125.23,110.06 117.48,110.06 116.93,110.61 116.93,139.48 119.7,142.25 125.4,142.25 128.26,139.39 145.02,139.39 146.08,138.34 146.08,128.89 142.48,125.3 138.48,125.3 132.81,119.62 132.81,108.91
+1.05VS_APLLOPI on BOTTOM (solid shape): 126.78,141.5 126.78,135.49 126.54,135.25 124.79,135.25 124.65,135.39 124.65,141.54 124.83,141.73 126.55,141.73
+1.05VS_ASATA3PLL on BOTTOM (solid shape): 126.71,134.32 126.71,132.61 126.55,132.45 124.89,132.45 124.72,132.62 124.72,134.86 124.93,135.08 125.95,135.08
+1.05VS_ASATA3PLL on BOTTOM (solid shape): 124.55,142.31 124.55,141.92 124.4,141.77 123.22,141.77 123.09,141.64 123.09,140.83 122.97,140.7 122.08,140.7 121.98,140.8 121.98,142.5 122.05,142.57 124.3,142.57
+1.05VS_ASATA3PLL on IN3 (solid shape): 125.37,142.23 125.37,141.21 125.3,141.14 123.62,141.14 123.44,141.32 123.44,142.23 123.54,142.33 125.26,142.33
+1.05VS_ASATA3PLL on IN3 (solid shape): outline of 96 points within 124.64,128.1 126.66,135.93
+1.05VS_AUSB3PLL on BOTTOM (solid shape): 120.5,136.27 120.5,135.11 120.96,134.65 120.96,132.53 120.81,132.38 119.57,132.38 119.04,132.92 119.04,134.87 118.59,135.32 118.59,136.22 118.71,136.35 120.42,136.35
+1.05VS_AXCK_DCB on TOP: 118.75,119.69 118.69,119.75 118.69,120.23 119.45,120.98 119.53,120.98 119.54,120.98 119.96,121.13 119.91,121.57 119.88,121.64 120.02,121.97 119.88,122.29 119.91,122.36 120.02,122.62 119.9,122.88 119.88,122.91 119.87,122.96 119.97,123.08 120,123.24 120,124.66 119.78,124.89 119.78,125.71 119.98,125.77 120.11,125.94 120.71,126.26 120.03,126.31 119.91,126.39 119.78,126.42 119.78,131.65 121.37,133.25 121.37,136.26 121.66,136.55 122.72,136.55 123.19,136.08 123.19,134.87 123.18,134.77 123.19,134.67 123.19,134.28 123.18,134.19 123.19,134.09 123.19,133.05 122.29,132.14 122.29,126.19 121.37,125.28 121.37,123.54 121.23,123.27 121.37,123 121.37,121.55 121.27,121.31 121.37,121.06 121.37,120.92 121.2,120.63 121.37,120.34 121.37,119.97 121.09,119.69
+1.05VSP on TOP (solid shape): 148.17,143.2 148.17,140.6 147.86,140.28 140.55,140.28 140.3,140.54 140.3,143.2 140.49,143.39 147.98,143.39
+1.5VSP on BOTTOM (solid shape): 110.63,32.87 110.63,31.79 110.94,31.47 113.42,31.47 113.55,31.35 113.55,29.19 110.44,29.19 108.91,30.71 105.93,30.71 105.67,30.97 105.67,33 105.93,33.25 110.25,33.25
+1.05VSP on BOTTOM (solid shape): 145.89,145.73 145.89,144.66 146.08,144.47 147.49,144.47 147.73,144.24 147.73,141.01 147.44,140.73 140.62,140.73 140.36,140.98 140.36,144.16 140.68,144.47 142.08,144.47 142.27,144.66 142.27,145.8 142.33,145.86 145.76,145.86
+1.8VGS on BOTTOM (solid shape): 186.69,87.4 186.69,85.96 186.59,85.86 185.81,85.86 185.75,85.93 185.75,87.36 185.91,87.52 186.58,87.52
+1.8VS on TOP (solid shape): 214.53,96.28 214.53,95.9 214.66,95.77 215.99,95.77 216.06,95.83 216.06,96.4 216.31,96.4 216.44,96.28 216.44,94.56 215.68,93.81 214.72,93.81 213.96,94.56 213.96,96.34 214.02,96.4 214.4,96.4
+1.8VS on BOTTOM (solid shape): 185.01,87.4 185.01,86.11 184.79,85.89 184.34,85.89 184.12,86.12 184.12,87.36 184.31,87.55 184.86,87.55
+1.8VS on IN1 (solid shape): 185.86,87.13 185.86,86.78 185.32,86.24 184.18,86.24 184.12,86.31 184.12,87.2 184.24,87.32 185.67,87.32
+1.8VS on IN1 (solid shape): 215.55,95.32 215.55,93.95 215.21,93.61 214.21,93.61 213.96,93.86 213.96,94.53 214.91,95.48 215.39,95.48
+1.8VSP on TOP (solid shape): 218.91,99.01 218.91,95.6 218.72,95.41 217.34,95.41 216.69,96.06 216.69,96.34 216.44,96.59 214.34,96.59 214.15,96.78 214.15,97.48 215.88,99.21 218.71,99.21
+1.8VSP on BOTTOM (solid shape): 220.37,98.34 221.45,98.34 221.45,97.04 221.36,96.95 220.34,96.95 220.24,96.84 220.19,96.8 220.14,96.75 219.17,95.77 217.26,95.77 216.9,96.13 216.9,97.9 218.02,99.02 219.69,99.02
+1.35V on BOTTOM (solid shape): 151.66,30.17 151.66,28.21 151.41,27.96 146.07,27.96 145.89,28.14 145.89,28.53 145.84,28.59 143.86,28.59 143.74,28.46 143.74,28.02 143.67,27.95 143.22,27.95 143.09,28.08 143.09,28.96 143.74,29.6 143.74,29.95 144.17,30.39 151.44,30.39
+1.35V on BOTTOM (solid shape): 102.3,99.99 102.37,99.97 102.4,99.9 102.55,99.68 102.81,99.71 102.88,99.74 102.94,99.71 103.2,99.68 103.35,99.9 103.38,99.97 103.45,99.99 105.61,99.99 106.33,99.27 108.8,99.27 110.3,97.77 110.3,96.87 110,96.57 98.82,96.57 98.12,97.26 98.12,99.18 98.31,99.38 100.22,99.38 100.84,99.99
+1.35V on TOP: outline of 190 points within 64.44,28.2 169.17,111.24 ; 1 cut-out
+1.35V_MEM_GFX on TOP (solid shape): 198.29,156.72 198.29,155.98 198.02,155.71 197.83,155.71 197.37,156.17 192.3,156.17 191.84,155.71 191.54,155.71 190.21,154.38 181.64,154.38 181.13,154.89 181.13,156.41 181.32,156.6 193.45,156.6 193.77,156.92 198.09,156.92
+1.35V_MEM_GFX on TOP (solid shape): 186.46,128.41 186.46,126.76 186.72,126.5 186.72,125.99 186.97,125.74 186.97,125.11 186.85,124.98 185.26,124.98 184.62,125.61 184.62,126.5 184.75,126.63 185.45,126.63 185.77,126.95 185.77,128.41 185.83,128.47 186.4,128.47
+1.35V_MEM_GFX on TOP (solid shape): 219.45,133.8 219.45,128.1 219.97,127.58 219.97,126.26 219.85,126.14 219.34,126.14 219.27,126.21 219.27,127.57 219,127.83 218.64,127.83 218.55,127.93 218.55,131.07 217.71,131.9 216.15,131.9 215.97,132.09 215.97,134.77 216.15,134.96 218.29,134.96
+1.35V_MEM_GFX on TOP (solid shape): 218.84,118.46 218.84,110.99 219.09,110.74 219.09,102.43 218.47,101.8 216.5,101.8 216.31,101.99 216.31,102.3 218.36,104.35 218.36,109.06 218.01,109.41 218.01,110.09 216.51,111.58 216.07,111.58 215.89,111.76 215.89,112.2 215.88,112.21 215.88,114.59 216.4,114.59 216.4,114.54 216.41,114.49 216.42,114.43 216.45,114.39 216.48,114.34 216.51,114.3 216.55,114.27 216.6,114.24 216.65,114.22 216.7,114.21 216.75,114.21 216.81,114.21 216.86,114.22 216.91,114.24 216.96,114.27 217,114.3 217.03,114.34 217.06,114.39 217.09,114.43 217.1,114.49 217.11,114.54 217.11,114.59 217.1,114.64 217.09,114.69 217.06,114.74 217.03,114.79 217,114.83 216.96,114.86 216.91,114.89 216.86,114.91 216.81,114.92 216.75,114.92 216.7,114.92 216.65,114.91 216.6,114.89 216.55,114.86 216.51,114.83 216.48,114.79 216.45,114.74 216.42,114.69 216.41,114.64 216.4,114.59 215.88,114.59 215.88,118.35 216.2,118.67 218.63,118.67
+1.35V_MEM_GFX on TOP (solid shape): 161.45,158.63 161.45,156.98 161.89,156.54 171.35,156.54 171.67,156.86 174.91,156.86 175.86,157.81 177.19,157.81 177.38,157.62 177.38,156.98 177.26,156.86 175.86,156.86 175.13,156.12 171.93,156.12 171.71,155.9 170.84,155.9 169.26,154.32 160.49,154.32 159.86,154.95 158.84,154.95 157.71,153.82 157.71,151.71 157.78,151.65 158.21,151.65 158.47,151.39 158.47,148.33 158.36,148.23 157.7,148.23 156.69,149.24 156.69,154.4 156.75,154.49 156.87,154.46 157.36,154.44 157.4,154.93 157.39,155.04 157.48,155.1 157.85,155.1 159.54,156.79 159.54,158.76 159.64,158.86 161.22,158.86
+1.35V_MEM_GFX on BOTTOM (solid shape): 214.08,151.86 214.08,150.62 213.58,150.12 212.04,150.12 211.77,150.39 211.77,151.68 212.18,152.1 213.84,152.1
+1.35V_MEM_GFX on BOTTOM (solid shape): 218.69,113.79 218.69,104.38 218.27,103.97 216.33,103.97 216.09,104.21 216.09,111.56 215.9,111.75 215.9,113.9 215.96,113.96 216.45,113.96 216.46,113.97 218.5,113.97
+1.35V_MEM_GFX on BOTTOM (solid shape): 218.84,139.32 218.84,126.29 218.63,126.08 217.09,126.08 216.55,126.63 216.55,131.69 216.01,132.22 216.01,134.11 217.82,135.92 218.15,136.25 218.15,139.38 218.78,139.38
+1.35V_MEM_GFX on BOTTOM (solid shape): 184.94,156.54 195.93,156.54 196.12,156.35 196.12,154.63 195.8,154.32 187.86,154.32 186.66,155.52 186.37,155.52 186.12,155.78 184.43,155.78 183.7,156.51 183.7,156.53 183.68,156.53 183.54,156.67 182.21,156.67 182.02,156.86 182.02,157.36 182.27,157.62 183.86,157.62
+1.35V_MEM_GFX on BOTTOM (solid shape): 177.38,157.62 177.38,157.05 177.19,156.86 175.8,156.86 175.67,156.73 175.67,156.41 173.57,154.32 167.22,154.32 165.69,155.84 161.51,155.84 161.45,155.9 161.45,156.6 161.51,156.67 162.33,156.67 162.37,156.63 171.67,156.63 171.7,156.67 172.24,156.67 172.49,156.92 174.21,156.92 174.97,157.68 177.32,157.68
+1.35V_MEM_GFX on IN1: outline of 151 points within 162.02,98.18 218.13,155.78
+1.35VGPUP on BOTTOM (solid shape): 184.88,167.33 184.88,166.38 185.7,165.56 189.96,165.56 190.21,165.3 190.21,162.25 190.08,162.13 176.24,162.13 175.1,163.27 175.1,166.57 175.73,167.21 180.56,167.21 181.45,168.1 184.12,168.1
+1.35VP on TOP (solid shape): 151.67,27.76 151.67,27.19 151.48,27 147.41,27 147.29,27.13 147.29,27.76 147.54,28.01 151.41,28.01
+1.35VP on BOTTOM (solid shape): 156.18,26.11 156.18,25.6 156.43,25.35 157.32,25.35 157.38,25.28 157.38,25.16 157.33,25.11 155.97,25.11 155.74,25.34 155.74,26.05 155.86,26.17 156.11,26.17
+1.35VP on BOTTOM (solid shape): 153.01,27.58 153.01,26.06 152.56,25.61 150.28,25.61 149.45,24.79 149.45,13.55 148.94,13.04 143.67,13.04 143.55,13.17 143.55,25.86 143.09,26.31 143.09,27.63 143.23,27.77 152.82,27.77
+1.35VP on IN2 (solid shape): 148.81,25.66 148.81,24.97 148.68,24.84 146.84,24.84 146.65,25.03 146.65,25.41 146.97,25.73 148.75,25.73
+1.35VP on IN2 (solid shape): 156.24,26.05 156.24,25.28 155.92,24.97 154.52,24.97 154.27,25.22 154.27,25.66 154.4,25.79 155.54,25.79 155.92,26.17 156.11,26.17
+1.35VS_VGA on BOTTOM (solid shape): 216.78,151.13 216.78,149.86 216.56,149.64 215.24,149.64 214.82,150.05 214.82,151.86 214.92,151.96 215.95,151.96
+1.35VS_VGA on BOTTOM (solid shape): 181.77,161.81 181.77,161.43 181.83,161.36 183.73,161.36 183.86,161.49 183.86,161.81 183.99,161.94 186.91,161.94 187.04,161.81 187.04,161.43 187.1,161.36 189.07,161.36 189.13,161.43 189.13,161.81 189.26,161.94 190.08,161.94 190.47,161.55 190.47,159.97 190.21,159.71 180.69,159.71 180.24,160.16 180.24,161.81 180.37,161.94 181.64,161.94
+1.35VS_VGA on IN2 (solid shape): 198.71,159.04 208.62,159.04 216.95,150.72 216.95,149.97 216.22,149.24 215.2,149.24 207.91,156.54 197.58,156.54 193.48,160.64 189.64,160.64 188.97,159.97 180.88,159.97 180.56,160.28 180.56,162.06 181.21,162.71 195.04,162.71
+1.35VS_VGA on VCC: 193.43,101.17 189.51,105.08 189.51,108.89 186.21,112.19 186.21,124.77 185.05,125.93 183.97,125.93 182.82,127.07 173.11,127.07 162.02,138.16 162.02,154.34 167.58,159.9 179.73,159.9 181.83,162 196.14,162 217.26,140.88 217.26,106.22 212.2,101.17
+3V_WLAN on TOP (solid shape): 107.02,147.87 107.02,146.54 106.98,146.51 105.27,146.51 105.15,146.63 105.15,147.98 105.25,148.09 106.8,148.09
+3V_WLAN on TOP (solid shape): 94.75,149.15 94.75,147.76 94.44,147.46 94.44,146.66 94.59,146.52 94.59,145.9 94.52,145.84 92.89,145.84 92.52,146.21 92.52,148.95 92.84,149.27 94.63,149.27
+3V_WLAN on TOP (solid shape): 112.81,150.68 112.81,149.38 113.12,149.07 113.12,147.97 113.02,147.87 112.31,147.87 112.22,147.96 112.22,148.17 112.09,148.3 111.45,148.3 111.35,148.39 111.35,150.7 111.4,150.75 112.74,150.75
+3V_WLAN on TOP (solid shape): 119.22,149.9 119.41,149.71 119.41,147.52 119.23,147.34 118.16,147.34 118.15,147.34 117.97,147.38 117.79,147.34 117.78,147.34 117.57,147.34 117.49,147.37 117.38,147.48 117.38,148.09 117.2,148.28 116.61,148.28 116.48,148.41 116.48,149.04 116.48,149.04 116.48,149.44 116.68,149.64 116.68,149.64 116.94,149.9 118.86,149.9
+3V_WLAN on BOTTOM (solid shape): 94.01,149.15 94.01,147.39 93.76,147.14 92.8,147.14 92.48,147.46 92.48,148.86 92.83,149.2 93.96,149.2
+3V_WLAN on BOTTOM (solid shape): 119.28,149.68 119.28,148.19 118.49,147.4 117.32,147.4 117.08,147.16 116.72,147.16 116.58,147.3 116.58,149.52 116.85,149.78 119.18,149.78
+3V_WLAN on BOTTOM (solid shape): 106.01,149.15 106.01,147.25 106.2,147.06 106.38,147.06 106.38,147.06 106.51,147.04 106.63,147.06 106.64,147.06 106.8,147.06 106.94,146.92 106.94,146.54 106.89,146.48 105.46,146.48 105.22,146.72 105.22,147.05 105.36,147.19 105.36,149.09 105.47,149.2 105.96,149.2
+3V_WLAN on IN1 (solid shape): 112.83,150.69 112.83,149.96 112.83,149.96 112.83,149.47 113.25,149.05 115.22,149.05 115.93,149.76 119.38,149.76 119.76,149.38 119.76,147.68 119.47,147.39 117.19,147.39 117.06,147.27 113.44,147.27 113.31,147.29 113.19,147.27 108.25,147.27 107.75,146.76 107.59,146.6 105.3,146.6 105.09,146.81 105.03,146.97 104.9,147.08 104.58,147.39 92.49,147.39 92.17,147.71 92.17,149.59 92.35,149.77 95.47,149.77 95.55,149.73 95.57,149.64 95.91,149.2 96.26,149.64 96.28,149.73 96.36,149.77 105.76,149.77 106.25,149.27 106.28,149.27 106.57,149.2 106.81,149.38 106.9,149.43 106.99,149.38 107.43,149.22 107.65,149.64 107.66,149.73 107.74,149.77 111.15,149.77 111.35,149.96 111.35,150.71 111.39,150.75 112.76,150.75
+3VALW on TOP (solid shape): 46.96,82.81 46.96,80.34 46.64,80.02 45.75,80.02 45.49,80.27 45.49,82.88 45.62,83.01 46.76,83.01
+3VALW on TOP (solid shape): 48.16,29.98 48.16,27.76 47.97,27.57 46.96,27.57 46.7,27.82 46.7,30.05 46.89,30.24 47.91,30.24
+3VALW on TOP (solid shape): 207.48,51.64 207.48,50.3 207.29,50.11 203.74,50.11 203.36,50.49 203.36,51.51 203.74,51.89 207.23,51.89
+3VALW on TOP (solid shape): 199.61,55.51 199.61,54.18 199.23,53.8 198.21,53.8 197.7,54.3 197.01,54.3 196.82,54.49 196.82,55.57 196.43,55.95 195.29,55.95 194.34,56.91 194.34,57.73 194.66,58.05 197.07,58.05
+3VALW on TOP (solid shape): 200.85,39.11 200.85,38.22 199.92,37.29 199.92,36.5 200.1,36.32 200.1,35.18 199.95,35.04 198.76,35.04 198.23,35.57 198.23,37.24 198.53,37.54 199.36,37.54 199.61,37.79 199.61,38.21 200.04,38.64 200.04,39.21 200.12,39.29 200.67,39.29
+3VALW on TOP (solid shape): 192.88,55.8 192.88,55.26 193.26,54.87 193.26,54.43 193.13,54.3 192.75,54.3 192.56,54.49 192.56,55 192.43,55.13 191.69,55.13 191.31,55.26 191.05,54.96 191.05,54.94 190.94,54.83 188.98,54.83 188.85,54.96 188.85,56.06 188.94,56.14 192.53,56.14
+3VALW on TOP (solid shape): outline of 95 points within 132.28,10.62 143.78,22.49
+3VALW on BOTTOM (solid shape): 214.14,91.74 214.14,89.78 213.71,89.34 211.35,89.34 211.19,89.5 211.19,91.7 211.41,91.91 213.97,91.91
+3VALW on BOTTOM (solid shape): 109.69,20.27 109.69,19.19 109.5,19 105.63,19 105.31,19.31 105.31,20.27 105.57,20.52 109.44,20.52
+3VALW on BOTTOM (solid shape): 195.81,57.76 196.69,56.88 196.69,56.27 196.31,55.89 194.56,55.89 193.54,56.91 193.54,57.76 193.63,57.85 195.72,57.85
+3VALW on BOTTOM (solid shape): 144.83,158.43 144.83,157.1 145.07,156.86 145.07,155.23 144.79,155.23 144.79,156.36 144.18,156.97 144.18,158.45 144.29,158.56 144.7,158.56
+3VALW on BOTTOM (solid shape): 47.81,86.47 47.81,84.37 47.4,83.96 47.4,80.34 47.15,80.08 43.54,80.08 43.47,80.15 43.47,80.78 43.57,80.88 45.01,80.88 45.75,81.62 45.75,84.29 45.95,84.49 45.95,86.38 46.26,86.69 47.59,86.69
+3VALW on BOTTOM (solid shape): 133.76,12.96 133.76,12.46 135.79,12.46 135.86,12.52 135.86,12.9 135.98,13.03 138.9,13.03 139.03,12.9 139.03,12.46 141.06,12.46 141.06,12.77 141.25,12.96 142.14,12.96 142.4,12.71 142.4,11.5 142.08,11.19 132.87,11.19 132.55,11.5 132.55,12.9 132.68,13.03 133.7,13.03
+3VALW on BOTTOM (solid shape): 95.09,29.41 95.09,28.9 95.22,28.78 95.85,28.78 95.91,28.71 95.91,27.74 95.86,27.55 95.91,27.36 95.91,25.98 95.72,25.79 93.44,25.79 93.18,26.05 93.18,27.39 93.18,29.34 93.18,29.47 93.31,29.6 94.9,29.6
+3VALW on IN2 (solid shape): 208.82,51.51 208.82,49.79 208.31,49.29 204.44,49.29 203.67,50.05 203.67,51.26 204.18,51.76 208.56,51.76
+3VALW on IN2 (solid shape): 212.5,90.56 212.5,88.99 212.25,88.74 211.51,88.74 211.29,88.96 211.29,90.55 211.47,90.73 212.33,90.73
+3VALW on IN2 (solid shape): 198.55,24.44 198.55,20.85 198.28,20.58 196.56,20.58 196.18,20.97 196.18,24.27 196.69,24.78 198.21,24.78
+3VALW on VCC: 176.79,8.84 168.47,17.16 157.91,17.16 155.44,14.68 145.21,14.68 141.97,11.44 132.85,11.44 129.61,14.68 124.59,14.68 119.83,19.44 40.46,19.44 39.27,20.63 39.27,28.39 92.53,28.33 93.73,29.54 97.15,29.54 98.48,28.27 172.83,28.39 178.87,22.36 205.54,22.36 207.29,20.61 207.29,8.94 207.19,8.84
+3VALW_PCH on TOP (solid shape): 122.96,51.29 122.96,50.23 122.7,49.98 121.88,49.98 121.7,50.16 121.7,51.41 121.81,51.52 122.73,51.52
+3VALW_PCH on TOP (solid shape): 132.83,110.96 132.83,109.96 132.74,109.87 130.69,109.87 130.53,110.03 130.53,110.43 130.62,110.51 131.61,110.51 131.71,110.61 131.71,110.98 131.81,111.09 132.71,111.09
+3VALW_PCH on TOP (solid shape): 142.76,30.37 142.76,26.87 142.64,26.75 141.75,26.75 141.38,27.13 138.14,27.13 138.01,27.25 138.01,30.43 138.46,30.87 142.25,30.87
+3VALW_PCH on TOP (solid shape): 156.65,93.26 161.92,93.26 162.14,93.04 162.14,92.4 162.02,92.28 156.91,92.28 156.68,92.05 155.68,92.05 151.9,95.82 136.72,95.82 136.45,96.09 136.45,96.69 136.7,96.94 152.97,96.94
+3VALW_PCH on TOP (solid shape): outline of 107 points within 147.54,108.34 151.46,114.21
+3VALW_PCH on BOTTOM (solid shape): 122.97,52.15 122.97,51.1 122.72,50.84 121.89,50.84 121.71,51.03 121.71,52.27 121.82,52.38 122.74,52.38
+3VALW_PCH on BOTTOM (solid shape): 147.54,113.03 147.54,112.34 147.81,112.08 148.3,112.08 148.39,111.99 148.39,111.47 148.36,111.44 147.79,111.44 147.62,111.62 145.75,111.62 145.7,111.67 145.7,113 145.8,113.1 147.47,113.1
+3VALW_PCH on BOTTOM (solid shape): 148.81,109.29 148.81,106.74 149.04,106.51 149.04,104.6 148.85,104.4 147.55,104.4 147.55,104.41 147.37,104.41 147.27,104.51 147.27,105.24 147.67,105.64 147.67,106.75 147.67,106.82 147.67,106.9 147.67,109.06 147.96,109.36 148.75,109.36
+3VALW_PCH on BOTTOM (solid shape): 141.14,112.75 141.14,111.2 141.09,111.15 140.82,110.74 141.21,110.45 141.28,110.42 141.32,110.35 141.32,108.91 141.19,108.79 139.69,108.79 139.22,108.32 138.92,108.32 138.6,108.63 138.6,108.81 139.16,109.36 139.16,109.71 139.39,109.94 140.07,109.94 140.2,110.08 140.2,110.99 139.28,111.91 139.28,113.63 139.32,113.67 140.22,113.67
+3VALW_PCH on BOTTOM (solid shape): 164.13,91.31 164.13,86.64 163.99,86.5 162.59,86.5 162.44,86.64 162.44,90.27 161.05,91.67 161.05,91.69 162.36,91.69 162.36,91.64 162.38,91.59 162.39,91.54 162.42,91.49 162.45,91.45 162.49,91.41 162.54,91.38 162.59,91.36 162.64,91.34 162.69,91.34 162.74,91.34 162.8,91.34 162.85,91.36 162.89,91.38 162.94,91.41 162.98,91.45 163.01,91.49 163.04,91.54 163.06,91.59 163.07,91.64 163.07,91.69 163.07,91.74 163.06,91.8 163.04,91.85 163.01,91.89 162.98,91.93 162.94,91.97 162.89,92 162.85,92.02 162.8,92.04 162.74,92.05 162.69,92.05 162.64,92.04 162.59,92.02 162.54,92 162.49,91.97 162.45,91.93 162.42,91.89 162.39,91.85 162.38,91.8 162.36,91.74 162.36,91.69 161.05,91.69 161.05,92.92 161.32,93.19 162.25,93.19
+3VALW_PCH on IN1 (solid shape): outline of 177 points within 131.72,110.63 147.54,114.98
+3VALW_PCH on IN1 (solid shape): outline of 265 points within 135.35,91.13 157.21,108.13
+3VALW_PCH on IN2 (solid shape): 148.14,111.89 148.14,110.06 148.97,109.22 148.97,106.3 152.3,102.97 152.3,99.77 152.19,99.66 150.94,99.66 150.87,99.74 150.87,102.95 149.62,104.2 147.66,104.2 146.96,104.89 146.96,106.44 147.02,106.53 147.12,106.53 147.67,106.82 147.12,107.12 147.02,107.11 146.96,107.2 146.96,110.77 146.04,111.7 146.04,112.69 146.29,112.94 147.08,112.94
+3VALW_PCH on IN3 (solid shape): 151.29,114.26 151.29,112.51 150.24,111.47 146.54,111.47 146.38,111.63 146.38,112.9 146.84,113.36 147.73,113.36 149.15,114.78 150.77,114.78
+3VALWP on BOTTOM (solid shape): 141.06,26.39 141.06,18.55 141.89,17.73 141.89,13.41 141.76,13.28 133.12,13.28 132.97,13.44 132.97,14.77 134.27,16.08 134.27,20.2 136.93,22.87 136.93,27.22 137.13,27.41 140.05,27.41
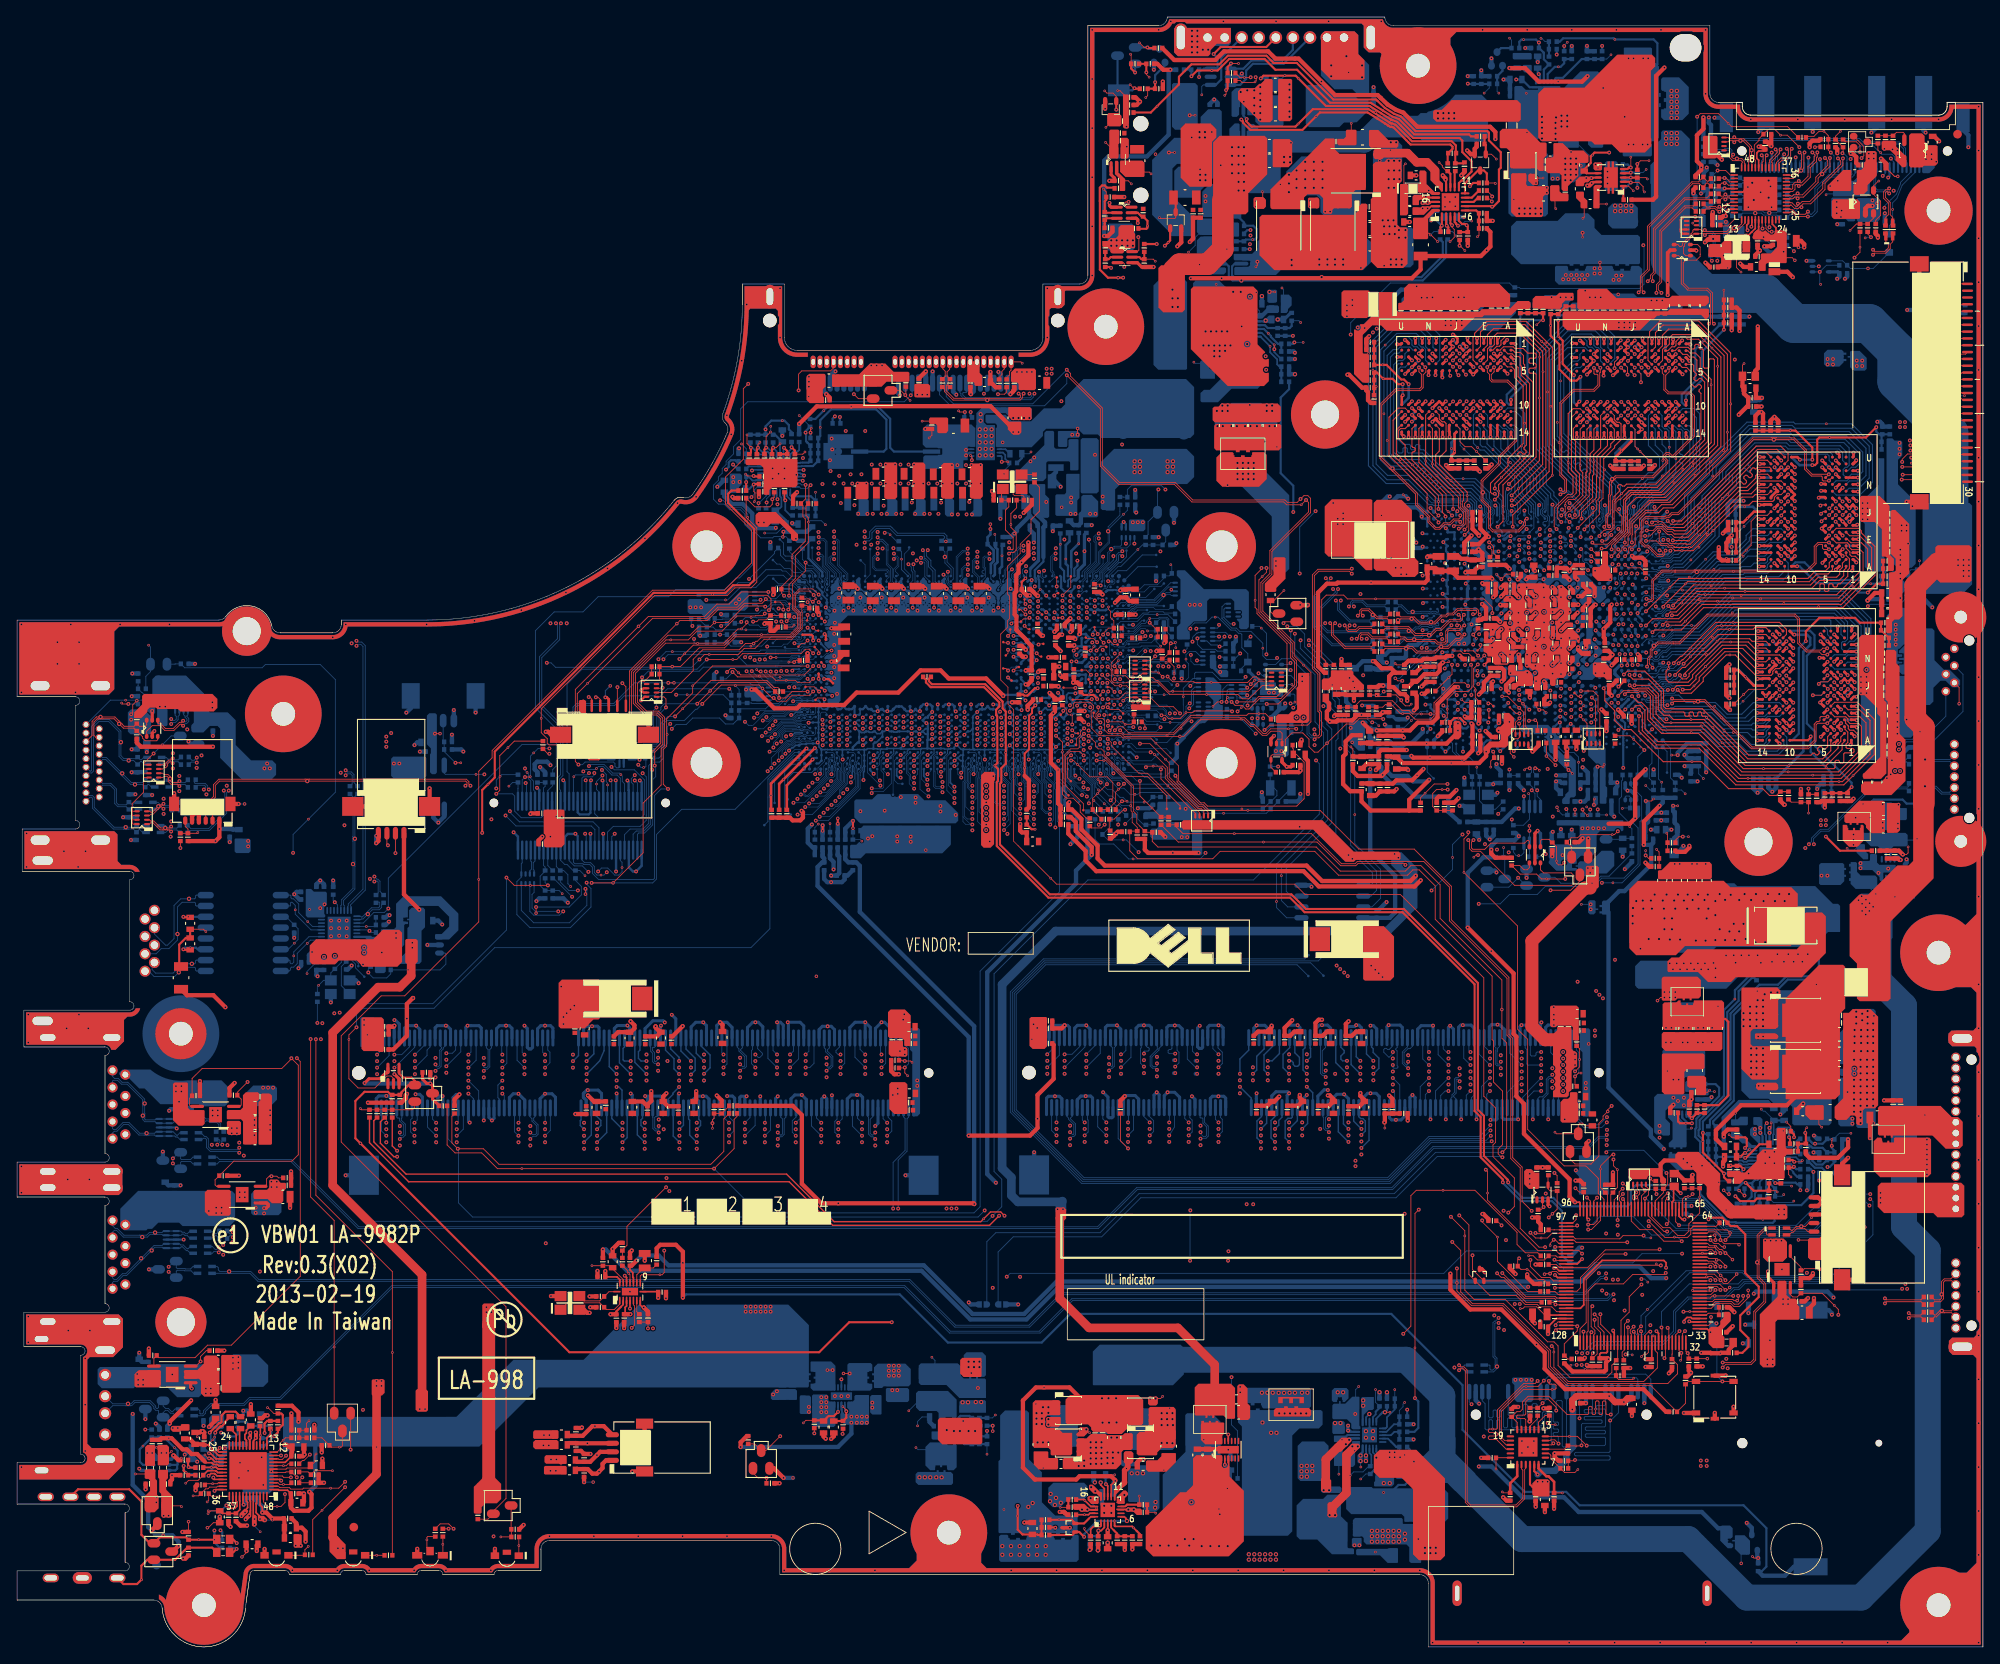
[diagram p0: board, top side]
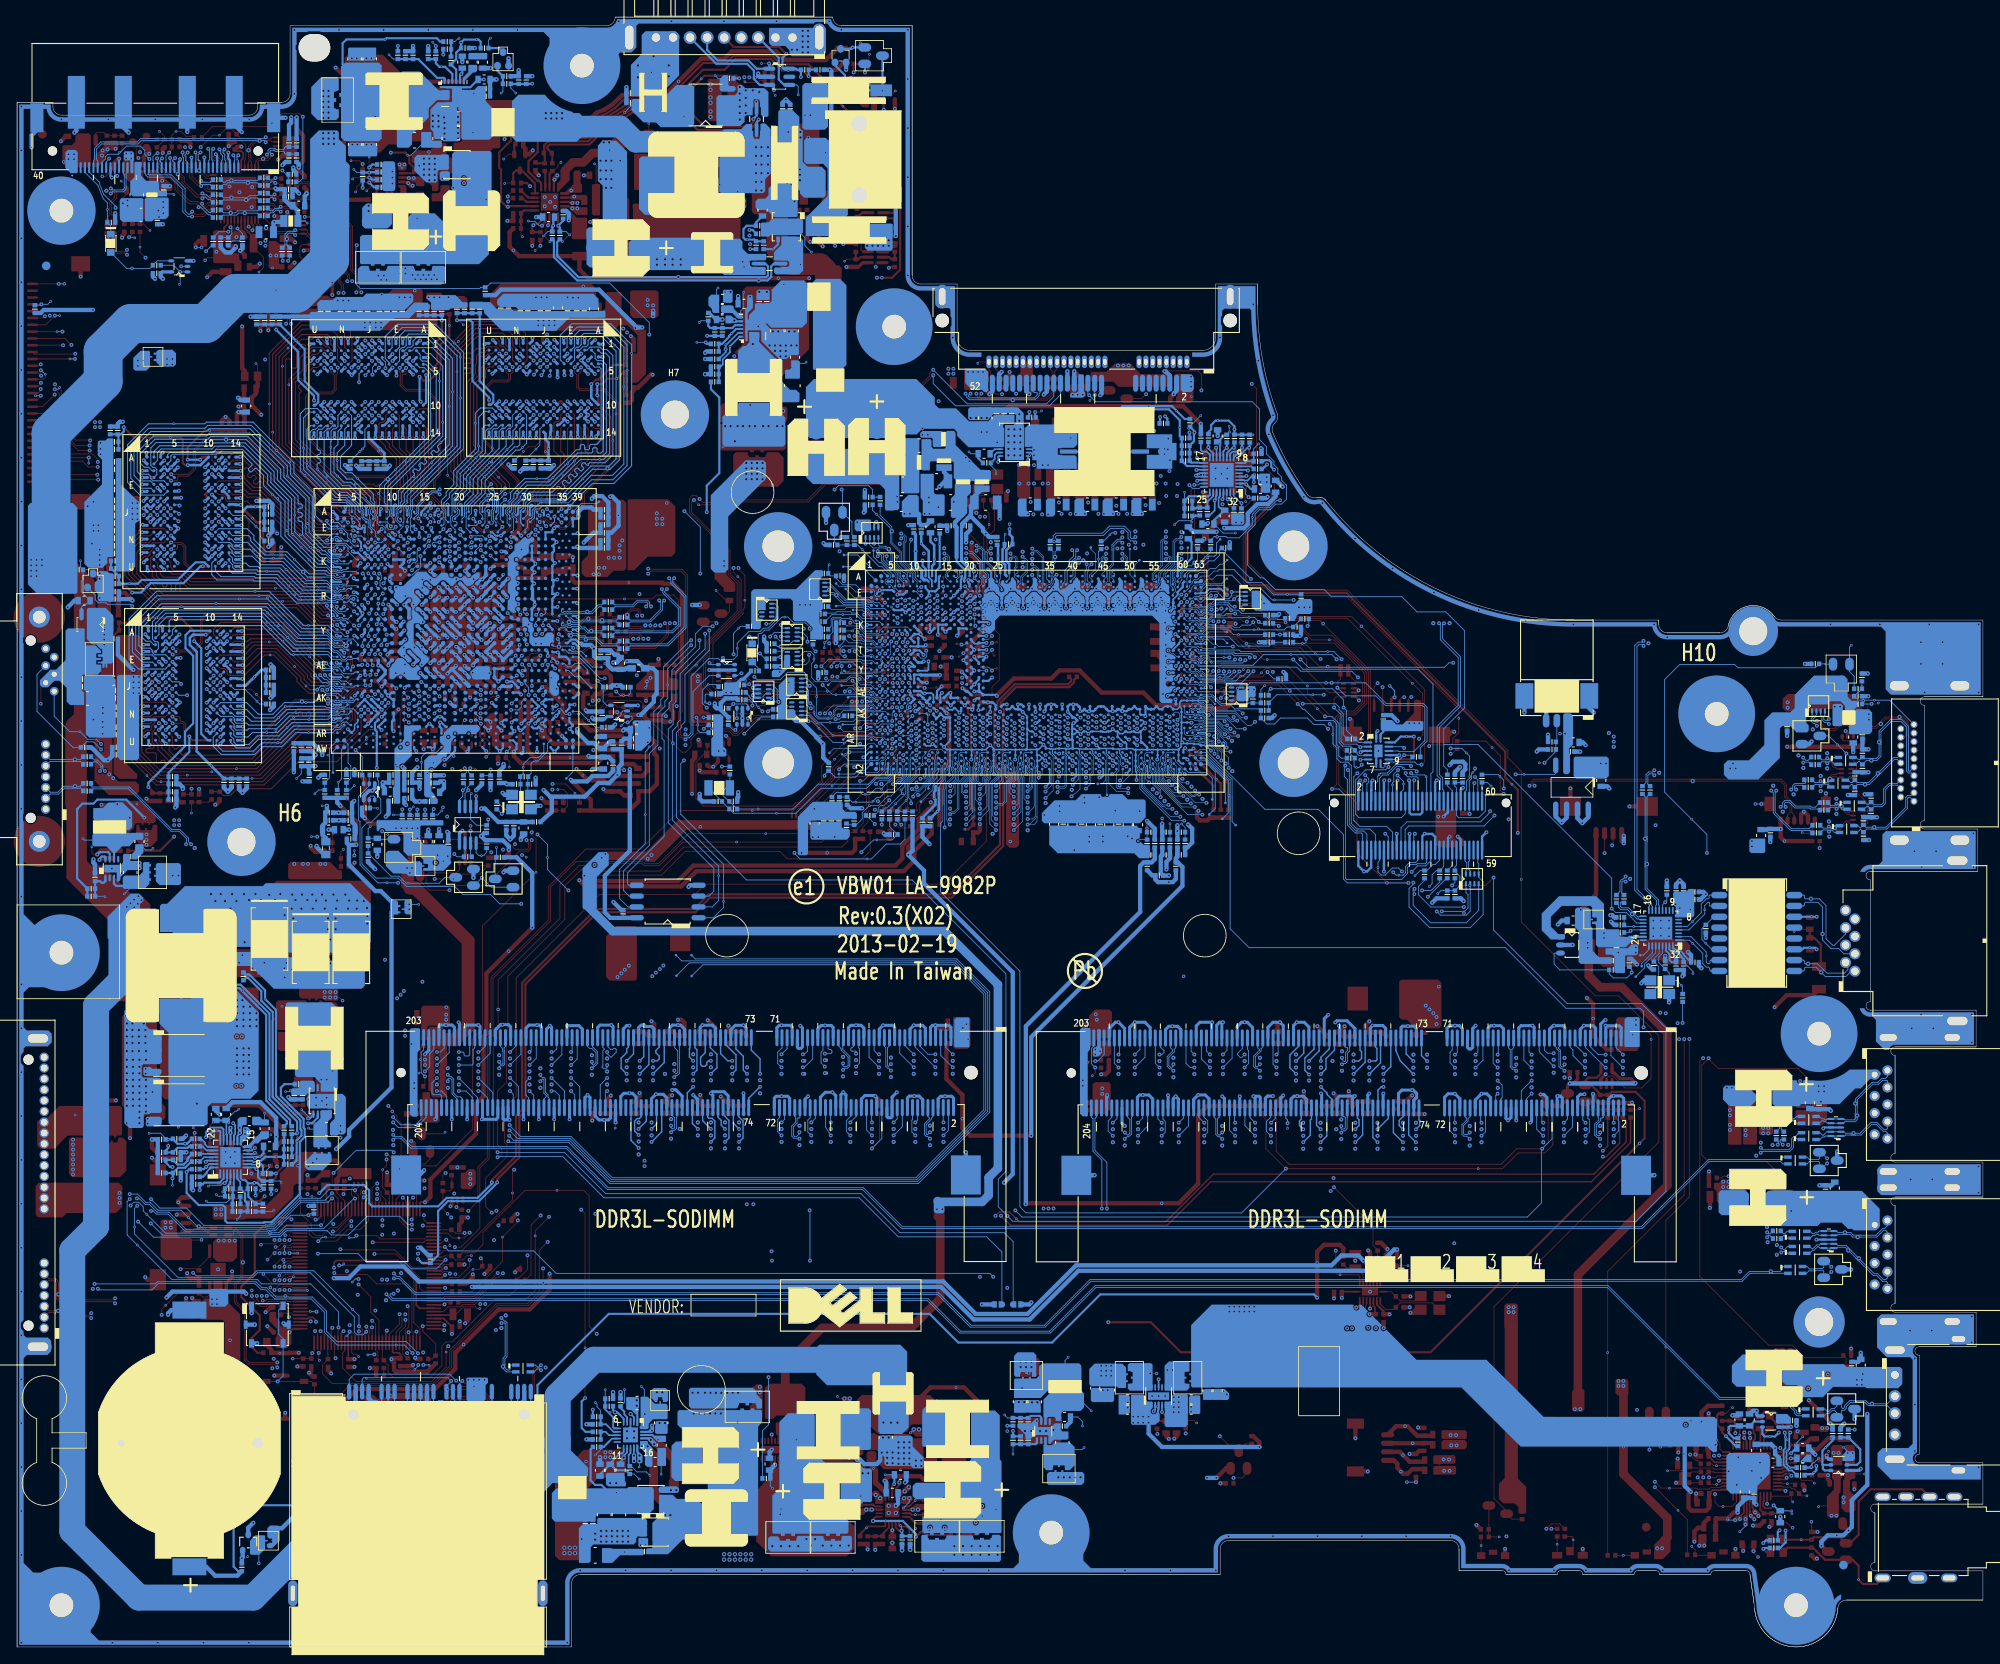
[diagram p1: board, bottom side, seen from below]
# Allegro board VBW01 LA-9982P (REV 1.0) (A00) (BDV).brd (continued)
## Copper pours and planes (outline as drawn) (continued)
+3VGS on TOP (solid shape): 175.62,115.08 175.62,114.52 175.73,114.4 176.64,114.4 176.76,114.52 177.18,114.52 177.52,114.19 177.52,114.17 177.56,114.02 177.65,113.9 177.65,113.32 177.64,113.22 177.67,113.11 177.67,112.84 177.48,112.66 175.99,112.66 175.87,112.53 175.73,112.42 175.66,112.26 175.64,112.23 175.61,112.22 175.2,112.22 175.13,112.3 175.13,112.84 175.31,113.03 175.64,113.03 175.9,113.29 175.9,113.8 175.81,113.89 174.88,113.89 174.74,114.02 174.74,114.95 174.95,115.16 175.54,115.16
+3VGS on BOTTOM (solid shape): 176.56,115 176.59,114.99 176.61,114.96 176.71,114.82 176.86,114.73 176.88,114.73 177.24,114.37 177.24,114.03 177.24,114.01 177.22,113.99 177.11,113.83 177.08,113.64 177.08,113.62 177.07,113.6 176.91,113.43 175.1,113.43 174.95,113.59 174.95,114.8 175.14,115
+3VGS on BOTTOM (solid shape): outline of 128 points within 179.51,91.01 188.27,96.94
+3VGS on TOP: 175.6,94.55 175.22,94.93 175.22,98.97 175.57,99.32 175.57,103.41 175.82,103.66 175.82,105.23 175.41,105.64 175.41,106.18 175.52,106.29 176.67,106.29 176.77,106.19 176.77,105.02 177.9,103.89 179.25,103.89 179.6,103.54 179.6,101.5 179.96,101.14 180.27,101.14 180.37,101.13 180.47,101.14 183.23,101.14 183.94,101.86 183.94,105 183.95,105.05 183.94,105.11 183.94,105.35 183.77,105.52 183.77,106.17 183.87,106.26 184.17,106.26 184.25,106.23 184.27,106.15 184.27,106.13 184.27,105.72 184.5,105.49 184.73,105.72 184.73,106.13 184.73,106.15 184.75,106.23 184.83,106.26 187.59,106.26 187.67,106.18 187.67,103.45 186.82,102.6 186.82,95.79 186.53,95.51 182.96,95.51 182.91,95.46 182.89,95.46 182.56,95.12 182.04,95.12 181.89,94.97 176.99,94.97 176.57,94.55
+3VLP on BOTTOM (solid shape): 201.07,13.92 201.07,12.9 200.94,12.77 200.56,12.77 200.5,12.71 200.5,12.2 200.56,12.14 201.01,12.14 201.13,12.01 201.13,11.76 200.94,11.57 200.5,11.57 199.61,12.46 199.61,14.04 199.8,14.23 200.75,14.23
+3VS on TOP (solid shape): 56.1,40.02 56.1,37.48 55.97,37.35 54.64,37.35 54.51,37.48 54.51,40.08 54.7,40.27 55.85,40.27
+3VS on TOP (solid shape): 185.39,91.39 185.39,89.1 185.19,88.91 184.12,88.91 183.86,89.16 183.86,91.45 183.99,91.58 185.19,91.58
+3VS on TOP (solid shape): 228.22,54.06 228.22,50.68 227.92,50.37 225.08,50.37 224.58,50.87 218.81,50.87 218.06,51.62 218.06,54.02 218.48,54.44 227.85,54.44
+3VS on TOP (solid shape): 179.61,19.44 179.61,17.75 179.51,17.65 177.82,17.65 177.58,17.88 177.58,19.18 178.06,19.66 179.39,19.66
+3VS on TOP (solid shape): 66.69,110.89 66.69,109.48 67.6,108.58 67.6,108.12 67.49,108.02 65.97,108.02 65.84,108.15 65.84,110.91 65.95,111.03 66.55,111.03
+3VS on TOP (solid shape): 103.82,70.99 103.82,70.39 103.9,70.32 104.18,70.32 104.36,70.13 104.36,69.4 104.18,69.22 102.44,69.22 102.15,69.51 102.15,70.97 102.28,71.1 103.71,71.1
+3VS on TOP (solid shape): 56.73,19.12 56.73,17.35 56.23,16.84 54.89,16.84 54.45,16.39 54.45,15.76 54.32,15.63 53.62,15.63 53.53,15.73 53.53,18.77 54.58,19.82 56.04,19.82
+3VS on TOP (solid shape): 177.89,55.62 178.37,55.62 178.41,55.58 178.41,53.84 178.26,53.69 178.05,53.69 178.04,53.7 177.18,53.7 176.63,54.24 176.63,55.79 176.87,56.03 177.48,56.03
+3VS on TOP (solid shape): 102.72,149.51 104.45,149.51 104.59,149.37 104.59,148.43 104.49,148.34 101.9,148.34 101.31,147.75 95.59,147.75 95.51,147.83 95.51,149.13 95.6,149.22 95.8,149.22 95.8,149.21 95.91,149.2 96.02,149.21 96.03,149.22 98.69,149.22 99.96,150.49 101.74,150.49
+3VS on TOP (solid shape): 217.96,175.21 217.96,172.48 216.88,171.4 216.88,170.76 216.37,170.25 215.42,170.25 215.23,170.44 215.23,171.4 215.61,171.78 215.61,173.08 215.71,173.18 216.13,173.18 216.44,173.49 216.44,174 216.65,174.21 216.65,174.59 216.66,174.6 216.66,175.18 216.88,175.4 217.77,175.4
+3VS on TOP (solid shape): outline of 392 points within 180.01,64.44 182.85,72.72
+3VS on BOTTOM (solid shape): 132.24,132 132.24,131.04 132,130.81 130.48,130.81 130.31,130.98 130.31,132.08 130.42,132.2 132.04,132.2
+3VS on BOTTOM (solid shape): 84.97,137.36 84.97,136.35 84.97,136.35 84.93,136.35 84.93,136.31 84.61,135.99 84.61,135.41 84.54,135.33 83.67,135.33 83.53,135.48 83.53,137.48 83.62,137.58 84.75,137.58
+3VS on BOTTOM (solid shape): 187.19,93.07 187.19,91.57 186.3,90.68 184.81,90.68 184.5,90.37 183.16,90.37 182.93,90.6 182.93,91.88 183.16,92.11 184.47,92.11 185.71,93.36 186.91,93.36
+3VS on BOTTOM (solid shape): 70.58,108.62 70.58,107.58 70.37,107.37 65.8,107.37 65.58,107.59 65.58,108.46 65.67,108.56 67.62,108.56 68.01,108.17 68.76,108.17 68.88,108.29 69.27,108.68 70.52,108.68
+3VS on BOTTOM (solid shape): 140.49,116.25 140.49,115.65 140.55,115.59 140.55,114.82 140.81,114.56 141.76,114.56 141.95,114.37 141.95,113.8 141.85,113.7 141.09,113.7 140.11,114.68 139.94,114.68 139.79,114.83 139.79,116.22 139.92,116.34 140.4,116.34
+3VS on BOTTOM (solid shape): 103.79,72.34 103.79,70.5 104,70.29 104.09,70.29 104.13,70.28 104.31,70.1 104.31,69.26 104.28,69.23 103.67,69.23 103.24,69.66 103.24,70.15 103.39,70.29 103.39,72.31 103.51,72.42 103.71,72.42
+3VS on BOTTOM (solid shape): 217.86,175.21 217.86,174.42 217.74,174.3 217.19,174.3 217.11,174.22 217.11,172.86 217.02,172.78 216.87,172.78 216.76,172.88 216.76,174.01 216.77,174.02 216.77,174.24 216.7,174.31 216.7,175.15 216.88,175.33 217.73,175.33
+3VS on BOTTOM (solid shape): 22.06,111.63 22.06,110.09 22.58,109.58 24.69,109.58 25.62,108.65 25.62,105.75 27.43,103.95 29.91,103.95 30.36,103.5 30.36,102.25 29.8,101.69 26.34,101.69 23.8,104.23 23.8,107.68 23.49,107.99 22.6,107.99 21.83,107.22 20.6,107.22 20.43,107.39 20.43,108.07 20.71,108.36 20.71,109.97 20.18,110.5 18.22,110.5 17.86,110.87 16.68,110.87 16.18,110.37 16.18,109.52 16.09,109.42 15.58,109.42 15.44,109.56 15.44,109.56 14.74,110.26 14.74,110.81 14.86,110.94 15.39,110.94 15.86,111.4 15.86,113.48 16.27,113.9 19.79,113.9
+3VS on BOTTOM (solid shape): 139.09,124.03 144.05,124.03 144.36,123.71 144.36,119.58 144.11,119.33 143.41,119.33 143.22,119.52 143.22,120.15 142.99,120.39 142.96,120.5 143.06,120.56 143.31,120.56 143.55,120.72 143.49,120.99 143.46,121.07 143.49,121.14 143.55,121.41 143.31,121.57 142.9,121.57 142.85,121.56 142.8,121.54 142.7,121.55 142.65,121.64 142.65,122.57 142.3,122.91 139.76,122.91 139.47,122.63 139.47,120.47 139.25,120.25 137.92,120.25 137.8,120.12 137.77,120.09 137.38,119.7 137.37,119.69 137.18,119.37 137.41,119.08 137.44,119.06 137.44,118.18 137.38,118.12 136.05,118.12 135.92,118.25 135.92,119.58 136.36,120.03 136.36,121.3 135.92,121.74 135.92,122.5 136.35,122.93 136.35,125.18 136.34,125.18 135.92,125.6 135.92,126.13 136.03,126.24 136.88,126.24
+3VS on BOTTOM (solid shape): outline of 326 points within 31.17,22.84 92.8,40.14
+3VS on IN2 (solid shape): 105.55,70.6 105.55,69.44 105.3,69.19 103.14,69.19 102.89,69.44 102.89,70.68 103.11,70.9 105.25,70.9
+3VS on IN2 (solid shape): 110.36,53.47 110.36,51.3 110.12,51.06 108.88,51.06 108.65,51.28 108.65,53.41 108.96,53.71 110.12,53.71
+3VS on IN2 (solid shape): 221.45,143.71 221.45,142 221.26,141.81 220.5,141.81 220.12,141.43 220.12,140.47 219.87,140.22 218.66,140.22 218.09,140.79 218.09,142.71 218.24,142.93 218.19,143.27 218.24,143.33 218.39,143.55 218.37,143.81 218.35,143.85 218.47,143.97 221.2,143.97
+3VS on IN2 (solid shape): 214.28,100.15 214.28,96.53 213.2,95.45 211.29,95.45 211.04,95.71 211.04,98.46 211.51,98.46 211.51,98.41 211.52,98.36 211.53,98.31 211.56,98.26 211.59,98.21 211.62,98.17 211.66,98.14 211.71,98.11 211.76,98.09 211.81,98.08 211.86,98.08 211.92,98.08 211.97,98.09 212.02,98.11 212.07,98.14 212.11,98.17 212.14,98.21 212.17,98.26 212.2,98.31 212.21,98.36 212.22,98.41 212.22,98.46 212.21,98.51 212.2,98.57 212.17,98.61 212.14,98.66 212.11,98.7 212.07,98.73 212.02,98.76 211.97,98.78 211.92,98.79 211.86,98.79 211.81,98.79 211.76,98.78 211.71,98.76 211.66,98.73 211.62,98.7 211.59,98.66 211.56,98.61 211.53,98.57 211.52,98.51 211.51,98.46 211.04,98.46 211.04,99.96 211.61,100.53 213.9,100.53
+3VS on IN2 (solid shape): outline of 557 points within 176.58,54.02 184.37,71.63
+3VS on IN3 (solid shape): outline of 87 points within 177.19,18.87 228.31,54.49
+3VS on TOP: outline of 249 points within 120.05,112.55 148.66,150.09
+3VS on BOTTOM: 202.19,164.05 201.14,164.05 201.06,164.13 201.06,164.93 201.28,165.14 201.37,165.14 201.48,165.26 201.48,166.46 201.65,166.63 202.41,166.63 202.46,166.58 202.46,164.32
+3VS on VCC: 48.01,38.94 36.35,50.6 36.35,63.04 32.99,66.41 32.99,96.45 27.91,101.53 27.91,114.03 26.49,115.45 22,115.45 22,119.13 23.65,119.13 24.69,119.39 25.5,120.1 27.27,120.79 28.61,119.45 29.4,118.14 30.84,117.63 37,117.63 38.31,118.04 39.14,119.13 48,119.13 64.58,122.91 77.89,133.5 79.18,133.61 80.2,134.41 82.5,138.03 84.4,141.87 84.55,143.16 83.97,144.32 85.69,150.76 86.27,157.4 86.27,158.53 88.66,158.53 88.66,153.52 89.47,151.56 91.43,150.75 118.73,150.75 120.69,151.56 121.5,153.52 121.5,158.53 124.5,158.53 126.11,159.19 126.77,160.8 126.77,188.83 133.8,188.83 134.87,189.09 135.68,189.83 159.42,189.83 160.23,189.09 161.3,188.83 197.13,188.83 197.13,182.1 197.79,180.49 199.4,179.83 201.06,179.83 201.89,178.74 203.2,178.33 225.2,178.33 226.5,178.74 227.34,179.83 229.13,179.83 229.13,121.42 220.33,121.42 219.36,120.45 219.36,114.9 221.77,112.49 221.77,89.14 219.74,87.11 219.74,43.04 216.14,39.44 194.93,39.44 194.42,38.94 186.66,38.94 185.64,37.92 184.81,37.92 183.8,38.94 176.11,38.94 175.35,39.7 172.49,39.7 171.73,38.94 ; 2 cut-outs
+3VS_RT on IN1: 193.14,158.92 193.14,160.93 195.73,163.52 195.73,173.03 196.68,173.97 197.8,173.97 199.72,172.05 199.72,167.97 200.5,167.19 200.5,166.77 199.44,165.71 199.44,162.97 199.41,162.9 199.33,162.87 199.16,162.86 199.01,162.77 198.94,162.75 198.88,162.78 198.28,162.52 198.88,162.26 198.94,162.29 199.01,162.27 199.16,162.18 199.33,162.17 199.41,162.14 199.44,162.07 199.44,161.87 199.92,161.39 210.83,161.39 210.9,161.36 210.93,161.27 211.28,160.87 211.63,161.27 211.65,161.36 211.73,161.39 213.08,161.39 213.78,160.69 213.78,159.01 212.89,158.11 193.42,158.11 193.14,158.39 193.14,158.61 193.14,158.62 193.16,158.76 193.14,158.9
+5V_HDD on TOP (solid shape): 226.75,62.13 227.22,62.12 227.49,62.13 228.03,61.58 228.03,58.79 227.66,58.42 226.03,58.42 224.49,59.95 218.25,59.95 218.09,60.12 218.09,63.22 218.3,63.43 225.44,63.43
+5V_USB_PWR1 on TOP (solid shape): 20.02,66.07 20.02,63.2 20.29,62.94 21.9,62.94 21.99,62.85 21.99,61.35 21.75,61.11 18.93,61.11 18.27,61.77 18.27,66.01 18.43,66.18 19.92,66.18
+5V_USB_PWR1 on BOTTOM (solid shape): 15.62,67.7 17.64,66.61 19.92,66.43 19.93,66.43 21.08,66.43 21.43,65.99 21.77,66.43 23.97,66.43 24.67,65.73 24.67,63.7 24.35,63.38 21.56,63.38 21.3,63.64 16.79,63.64 14.95,65.48 14.32,65.48 13.16,66.64 12.49,66.64 12.05,67.08 11.97,67.08 11.97,67.32 12.35,67.7
+5V_USB_PWR2 on TOP (solid shape): 25.05,53.41 25.05,50.75 24.86,50.56 22.44,50.56 22,51 22,53.29 22.32,53.6 24.86,53.6
+5V_USB_PWR2 on BOTTOM (solid shape): 25.56,53.1 25.56,49.99 24.92,49.35 19.38,49.35 18.99,49.75 16.56,49.75 15.83,49.02 15.32,49.02 15.14,48.84 12.54,48.84 12.09,49.29 12.09,51.38 14.19,53.48 25.17,53.48
+5V_USB_PWR3 on TOP (solid shape): 16.86,32.27 16.86,30.68 16.6,30.43 13.94,30.43 13.74,30.62 13.74,31.95 14.25,32.46 16.67,32.46
+5V_USB_PWR3 on BOTTOM (solid shape): outline of 116 points within 9.44,29.28 23.52,33.16
+5V_USB_PWR4 on TOP (solid shape): 213.58,49.99 213.58,45.79 213.13,45.35 210.21,45.35 209.9,45.67 209.9,47.76 210.09,47.95 211.23,47.95 211.67,48.4 211.67,49.99 211.8,50.11 213.45,50.11
+5V_USB_PWR4 on TOP (solid shape): 204.91,47.88 205.68,47.88 205.72,47.88 205.76,47.89 207.04,47.89 207.44,47.49 207.44,45.65 206.94,45.16 205.13,45.16 204.63,45.67 204.63,47.76 204.75,47.89 204.9,47.89
+5V_USB_PWR4 on IN2 (solid shape): 208.88,47.83 208.88,46.49 208.5,46.11 205.01,46.11 204.63,46.49 204.63,48.27 204.88,48.52 208.18,48.52
+5V_USB_PWR4 on IN2 (solid shape): 213.33,49.86 213.33,47.89 212.94,47.51 210.53,47.51 210.15,47.89 210.15,49.73 210.47,50.05 213.13,50.05
+5VALW on TOP (solid shape): 30.89,54.43 31.4,54.43 31.52,54.3 31.52,53.73 31.21,53.41 31.21,52.27 30.95,52.02 29.87,52.02 29.37,52.53 27.84,52.53 27.71,52.65 27.71,53.41 27.91,53.6 29.3,53.6 29.56,53.86 29.56,54.68 29.68,54.81 30.51,54.81
+5VALW on TOP (solid shape): 23.71,33.79 23.71,29.6 23.46,29.35 21.94,29.35 21.56,29.73 21.56,31.19 21.3,31.44 19.65,31.44 19.59,31.51 19.59,32.27 19.78,32.46 21.11,32.46 21.87,33.22 21.87,33.92 22.13,34.17 23.33,34.17
+5VALW on TOP (solid shape): 167.35,19.76 167.35,10.68 166.84,10.17 164.3,10.17 163.6,10.87 163.6,18.49 162.27,19.82 159.67,19.82 159.01,20.48 159.01,22.45 159.18,22.62 159.68,23.12 163.99,23.12
+5VALW on TOP (solid shape): 207.36,42.81 207.36,41.29 207.8,40.84 208.44,40.84 208.63,40.65 208.63,40.14 208.88,39.89 208.88,38.43 208.82,38.36 206.34,38.36 206.09,38.11 206.09,33.03 205.83,32.78 204.63,32.78 204.24,33.16 204.24,39 206.34,41.1 206.34,42.81 206.47,42.94 207.23,42.94
+5VALW on TOP (solid shape): 28.35,64.91 28.35,64.18 28.13,63.97 28.13,59.04 27.99,58.9 26.56,58.9 26.48,58.98 26.48,61.62 26.23,61.87 24.64,61.87 24.58,61.94 24.58,62.82 24.71,62.95 26.17,62.95 26.47,63.26 26.47,64.69 26.81,65.03 28.22,65.03
+5VALW on BOTTOM (solid shape): 207.86,41.73 207.86,40.08 207.67,39.89 206.02,39.89 205.64,40.27 205.64,41.73 205.9,41.98 207.61,41.98
+5VALW on BOTTOM (solid shape): 116.17,13.03 116.17,12.65 116.23,12.58 118.33,12.58 118.33,12.96 118.46,13.09 121.38,13.09 121.5,12.96 121.5,12.65 121.57,12.58 123.54,12.58 123.66,12.71 123.66,13.09 123.73,13.16 124.3,13.16 124.43,13.03 124.43,10.23 124.17,9.98 115.28,9.98 115.09,10.17 115.09,12.96 115.28,13.16 116.04,13.16
+5VALW on BOTTOM (solid shape): 99.85,29.47 99.85,26.24 99.66,26.05 96.99,26.05 96.49,26.55 96.49,27.32 96.57,27.55 96.49,27.78 96.49,28.71 96.55,28.78 96.68,28.78 96.74,28.71 96.74,28.01 96.78,27.97 96.78,27.71 96.8,27.69 96.8,27.57 96.84,27.53 96.85,27.52 97.36,27.33 97.45,27.87 97.44,27.89 97.31,28.01 97.31,28.65 97.44,28.78 97.95,28.78 98.14,28.97 98.14,29.41 98.26,29.54 99.79,29.54
+5VALW on IN1 (solid shape): 104.22,26.19 106.9,26.19 118.16,14.93 117.8,14.34 118.39,14.7 120.57,12.52 124.04,12.52 125.76,10.81 131.09,10.81 131.66,11.38 147.54,11.38 147.86,11.06 147.86,10 147.6,9.75 116.01,9.75 114.65,11.11 114.65,14.46 106.03,23.07 99.66,23.07 97.37,25.36 97.37,27.03 97.73,27.39 103.02,27.39
+5VALW on IN2 (solid shape): 125.63,10.93 131.28,10.93 131.73,11.38 147.54,11.38 147.86,11.06 147.86,10 147.6,9.75 115.38,9.75 114.65,10.49 114.65,11.76 115.41,12.52 124.04,12.52
+5VALW on IN3 (solid shape): outline of 380 points within 158.78,21.73 206.2,37.92
+5VALW on VCC: 166.67,1.27 166.67,7.48 166.01,9.09 164.4,9.75 90.67,9.75 90.67,11.48 90.01,13.09 88.4,13.75 62.4,13.75 60.79,13.09 60.13,11.48 60.13,10.25 56.4,10.25 55.73,10.12 55.17,9.75 50.63,9.75 50.07,10.12 49.4,10.25 47.4,10.25 46.73,10.12 46.17,9.75 41.63,9.75 41.07,10.12 40.4,10.25 38.4,10.25 37.73,10.12 37.17,9.75 32.63,9.75 32.07,10.12 31.4,10.25 27.84,10.25 27.84,12.56 27.31,13.09 26.3,13.09 25.68,13.7 25.68,15.27 26.57,16.16 26.57,18.4 26.3,18.68 25.2,18.68 24.86,18.34 24.86,17.39 24.75,17.28 20.64,17.28 20.48,17.45 20.48,19.02 20.64,19.19 24.71,19.19 25.05,19.53 25.05,22.68 29.47,22.68 29.79,23 31.52,23 31.52,28.27 23.55,28.27 21.7,26.43 21.05,26.43 21.05,63.57 29.71,63.57 30.32,62.96 30.32,55.09 30.76,54.64 30.76,42.01 38.76,34 38.76,20.42 40.25,18.93 119.62,18.93 124.38,14.17 129.4,14.17 132.64,10.93 142.18,10.93 145.42,14.17 155.65,14.17 158.12,16.65 168.26,16.65 176.58,8.33 207.19,8.33 208.82,6.7 208.82,1.27
+5VALWP on BOTTOM (solid shape): outline of 195 points within 115.02,13.35 124.3,27.73
+5VS on TOP (solid shape): 38.51,12.01 38.51,10.36 38.45,10.3 37.49,10.3 36.6,11.19 36.6,12.84 36.8,13.03 37.49,13.03
+5VS on TOP (solid shape): 43.08,31.25 43.08,29.79 42.76,29.47 41.68,29.47 41.56,29.6 41.56,31.25 41.68,31.38 42.95,31.38
+5VS on TOP (solid shape): 33.37,13.09 33.37,12.08 33.49,11.95 33.49,11.76 33.37,11.63 32.54,11.63 32.41,11.76 32.41,13.09 32.54,13.22 33.24,13.22
+5VS on TOP (solid shape): 20.22,26.05 20.22,25.47 20.09,25.35 19.98,25.35 19.27,25.35 19.21,25.35 19.08,25.22 18.25,25.22 18,25.47 18,25.73 18.19,25.92 19.14,25.92 19.33,26.11 20.16,26.11
+5VS on TOP (solid shape): 218.58,59.59 218.58,59.21 218.63,59.15 219.95,59.15 219.99,59.19 219.99,59.51 219.98,59.52 219.98,59.65 220.06,59.73 224.11,59.73 224.32,59.51 224.32,55.48 223.92,55.08 218.34,55.08 217.59,55.83 217.59,59.29 218.02,59.73 218.44,59.73
+5VS on TOP (solid shape): 23.49,111.15 23.49,110.1 23.05,109.67 19.15,109.67 18.85,109.97 16.44,109.97 16.28,110.12 15.52,110.12 15.28,109.88 15.28,109.62 14.56,108.9 13.76,108.9 13.73,108.93 13.73,109.58 14.65,110.5 14.65,111.51 14.88,111.74 22.9,111.74
+5VS on BOTTOM (solid shape): 17.61,110.47 17.61,108.07 17.5,107.97 16.62,107.97 16.41,108.17 16.41,110.37 16.62,110.57 17.51,110.57
+5VS on BOTTOM (solid shape): 27.38,94.59 27.38,93.29 27.16,93.08 25.68,93.08 25.5,93.26 25.5,94.71 25.57,94.78 27.19,94.78
+5VS on BOTTOM (solid shape): 47.97,104.21 47.97,102.12 47.65,101.8 44.16,101.8 43.84,102.12 43.84,104.15 44.08,104.39 47.79,104.39
+5VS on BOTTOM (solid shape): 104.74,32.59 104.74,30.81 104.49,30.55 101.57,30.55 101.37,30.36 100.49,30.36 100.42,30.43 100.42,32.78 100.87,33.22 104.11,33.22
+5VS on BOTTOM (solid shape): 222.22,121.68 222.22,118.18 221.58,117.55 221.14,117.55 220.64,117.04 220.54,117.04 220.43,116.93 220.43,116.48 220.43,116.38 220.91,116.38 220.95,116.34 220.95,116.15 220.89,116.09 220.51,116.09 220.51,116.09 220.44,116.09 220.43,116.08 220.37,116.03 220.37,115.58 220.44,115.52 220.95,115.52 220.95,115.39 220.88,115.33 220.44,115.33 220.41,115.3 220.41,115.21 220.41,114.84 220.4,114.82 220.21,114.82 220.14,114.9 220.14,115.23 220.07,115.3 219.3,115.3 219.11,115.49 219.11,118.4 219.12,118.42 219.12,120.93 220.02,121.84 222.06,121.84
+5VS on IN1 (solid shape): 33.43,11.95 33.43,10.81 33.3,10.68 32.54,10.68 32.41,10.81 32.41,12.08 32.48,12.14 33.24,12.14
+5VS on IN1 (solid shape): 38.45,11.63 38.45,10.74 38.26,10.55 36.92,10.55 36.73,10.74 36.73,11.44 37.05,11.76 38.32,11.76
+5VS on IN1 (solid shape): 19.59,26.66 19.59,25.83 19.09,25.33 18.16,25.33 18.02,25.47 18.02,25.78 18.48,26.24 18.48,26.83 18.52,26.87 19.37,26.87
+5VS on IN1 (solid shape): 43.02,31.32 43.02,30.55 42.86,30.4 42.29,30.4 42.26,30.36 40.8,30.36 40.73,30.43 40.73,31.19 40.99,31.44 42.89,31.44
+5VS on IN1 (solid shape): 222.47,156.47 222.47,154.44 219.99,151.97 219.99,122.49 220.83,121.66 220.83,117.14 220.63,116.94 220.09,116.94 218.09,118.95 218.09,133.26 218.09,133.27 218.09,133.58 218.09,133.59 218.09,137.33 218.09,137.34 218.09,137.64 218.09,137.65 218.09,142.71 218.25,142.94 218.19,143.21 218.18,143.29 218.22,143.35 218.38,143.7 218.12,143.99 218.09,144 218.09,152.92 220.31,155.14 220.31,156.22 221.07,156.98 221.96,156.98
+5VS on IN2 (solid shape): 27.79,96.29 27.79,93.74 27.54,93.49 26.82,93.49 26.5,93.8 26.5,96.19 26.83,96.52 27.55,96.52
+5VS on IN2 (solid shape): 45.34,103.99 45.34,103.26 45.11,103.03 42.55,103.03 42.3,103.28 42.3,104 42.62,104.32 45.01,104.32
+5VS on BOTTOM: 89.37,132.34 88.42,132.34 88.29,132.22 88.29,131.25 88.58,130.96 89.3,130.96 89.5,131.16 89.5,132.22
+5VS on VCC: 209.32,1.27 209.32,6.91 207.65,8.58 207.8,8.73 207.8,20.82 205.75,22.87 179.08,22.87 173.04,28.9 98.68,28.78 97.35,30.05 93.52,30.05 92.32,28.84 39.27,28.9 39.27,34.22 31.27,42.22 31.27,54.85 30.83,55.3 30.83,63.17 29.92,64.08 21.05,64.08 21.05,76.72 27.19,76.72 27.33,76.87 27.33,90.88 22,90.88 22,114.95 26.28,114.95 27.4,113.82 27.4,101.31 32.48,96.23 32.48,66.2 35.84,62.83 35.84,50.39 47.8,38.43 171.99,38.43 172.75,39.19 175.16,39.19 175.92,38.43 183.54,38.43 184.56,37.41 185.89,37.41 186.91,38.43 194.63,38.43 195.14,38.94 216.35,38.94 220.25,42.83 220.25,86.9 222.28,88.93 222.28,112.7 219.87,115.11 219.87,120.24 220.54,120.91 229.13,120.91 229.13,1.27
+5VS_ODD on BOTTOM (solid shape): 224.72,119.16 224.72,115.7 225.84,114.58 226.5,114.58 227.72,113.35 227.72,112.79 227.44,112.51 226.79,112.51 226.02,113.28 225.41,113.28 224.6,112.46 224.6,110.85 224.18,110.44 222.6,110.44 222.53,110.5 222.53,111.9 222.81,112.17 222.81,113.86 222.8,113.86 222.65,114.02 220.92,114.02 220.54,114.4 220.54,115.15 220.57,115.18 221.08,115.18 221.11,115.21 221.11,115.69 221.08,115.72 220.56,115.72 220.55,115.73 220.55,115.95 220.56,115.96 221.03,115.96 221.09,115.96 221.11,115.98 221.11,116.5 221.09,116.52 220.55,116.52 220.55,116.85 220.56,116.86 220.64,116.86 221.19,117.42 222.27,117.42 222.47,117.62 222.47,119.32 222.57,119.42 224.45,119.42
+DVCC33 on TOP (solid shape): 199.29,177.05 199.29,174.76 199.04,174.51 197.7,174.51 197.58,174.64 197.58,177.05 197.7,177.18 199.16,177.18
+DVCC33 on TOP (solid shape): 204.28,166.1 204.56,165.95 204.85,166.08 204.86,166.1 204.91,166.1 205.25,165.76 205.33,165.76 205.76,165.6 205.99,165.99 206.02,166.07 206.1,166.1 207.27,166.1 207.41,165.96 207.41,162.35 207.32,162.25 205.1,162.25 204.94,162.09 204.94,161.41 204.89,161.35 204.18,161.35 204.1,161.43 204.1,162.46 204.36,162.71 204.36,163.27 204.48,163.4 205.56,163.4 206.25,164.09 206.25,164.76 206.21,164.81 204.88,164.81 204.66,165.02 203.56,165.02 203.38,165.19 203.38,165.36 203.39,165.37 203.47,165.54 203.48,165.73 203.48,165.75 203.83,166.1
+DVCC33 on IN3: 201.63,163.27 201.4,163.5 199.27,163.5 198.16,164.6 198.07,164.94 197.73,165.04 196.37,166.39 196.37,167.63 196.38,167.64 196.38,170.84 196.88,171.33 198.97,171.33 199.8,172.16 199.8,173.94 199.55,174.19 199.55,174.51 199.67,174.64 200.05,174.64 200.88,173.81 200.88,169.3 201.93,168.25 206.83,168.25 207.8,167.28 207.8,163.62 207.48,163.3 206.32,163.3 206.15,163.47 206.15,166.67 205.97,166.85 204.4,166.85 204.12,166.57 204.12,166.06 204.44,165.75 204.82,165.75 204.97,165.59 204.97,165.16 204.73,164.92 204.21,164.92 202.56,163.27
+VCC_PWR_SRC on TOP (solid shape): 117.69,143.58 117.69,142.38 117.44,142.12 116.74,142.12 116.11,142.76 116.11,143.58 116.17,143.65 117.63,143.65
+VCC_PWR_SRC on BOTTOM (solid shape): 137.95,147.71 137.95,142.19 137.51,141.74 127.08,141.74 126.66,142.16 124.96,142.16 124.3,142.82 120.59,142.82 120.23,142.47 120.23,142 118.9,140.66 115.92,140.66 115.92,140.66 114.84,140.66 114.84,143.27 114.74,143.37 114.74,143.38 114.72,143.38 114.65,143.46 113.69,143.46 113.5,143.65 113.5,144.41 113.57,144.47 115.85,144.47 116.4,143.93 116.4,143.92 116.47,143.82 116.57,143.75 116.58,143.75 116.61,143.71 118.84,143.71 120.35,145.22 122.36,145.22 122.84,145.71 122.84,146.51 125,148.66 137,148.66
+VDD_MEM15_REFDA on IN3 (solid shape): outline of 342 points within 172.82,124.49 181.21,127.47
+VDD_MEM15_REFDB on IN3 (solid shape): outline of 750 points within 183.63,102.82 195.96,120.63
+VDDCI on BOTTOM (solid shape): 195.93,182.89 195.93,179.78 195.16,179.02 193.01,179.02 192.69,179.33 192.69,180.29 193.2,180.29 193.26,180.35 193.26,182.32 193.13,182.45 192.81,182.45 192.69,182.57 192.69,183.84 192.88,184.03 194.78,184.03
+VDDCI on BOTTOM (solid shape): outline of 300 points within 176.19,114.9 186.24,126.03
+VDDCI on IN1 (solid shape): outline of 592 points within 176.62,114.68 186.42,125.8
+VDDCI on TOP: outline of 258 points within 176.55,107.02 186.28,126.86
+VDDCI on VCC: 183.52,112.34 182.59,113.27 182.59,121.85 181.93,122.5 165.42,122.5 156.75,131.18 156.75,164.88 160.92,169.05 182.89,169.05 184.94,171.1 184.94,180.69 187.08,182.83 194.78,182.83 195.04,182.57 195.04,181.07 195.05,181.06 195.05,178.82 195.99,177.87 195.99,162.57 181.7,162.57 179.54,160.41 167.37,160.41 161.51,154.55 161.51,137.95 172.9,126.57 182.61,126.57 183.76,125.42 184.84,125.42 185.7,124.56 185.7,112.34
+VDDCIP on BOTTOM (solid shape): 192.43,185.3 192.43,176.99 191.99,176.54 187.99,176.54 187.67,176.86 187.67,185.43 187.99,185.75 191.99,185.75
+VDDR4 on TOP (solid shape): 186.55,114.96 186.55,114.95 186.63,114.83 186.75,114.75 186.84,114.72 186.91,114.66 186.91,113.48 186.84,113.41 186.27,113.41 186,113.69 185.07,113.69 184.68,114.08 184.68,115.27 184.85,115.44 186.07,115.44
+VDDR4 on BOTTOM (solid shape): 186.08,115.64 186.09,115.63 186.16,115.46 186.31,115.34 186.32,115.34 186.52,115.14 186.52,115.11 186.57,114.91 186.72,114.76 186.73,114.76 186.75,114.73 186.75,113.63 186.63,113.51 186.23,113.51 185.84,113.91 185.73,113.91 185.71,113.91 185.7,113.92 185.46,114.02 185.23,113.92 185.2,113.91 185.16,113.91 184.63,113.38 183.33,113.38 183.31,113.38 183.3,113.39 183.21,113.46 183.11,113.49 183.11,113.5 183.11,113.75 183.12,113.77 183.13,113.79 183.15,113.81 183.16,113.81 183.49,114.19 183.16,114.57 183.13,114.59 183.11,114.62 183.11,114.82 183.13,114.84 183.14,114.85 183.26,114.95 183.34,115.08 183.35,115.11 183.38,115.12 183.62,115.12 183.63,115.11 183.63,115.08 183.99,114.82 184.34,115.09 184.34,115.11 184.56,115.32 184.57,115.33 184.73,115.42 184.83,115.58 184.83,115.59 185.09,115.85 185.11,115.86 185.2,115.9 185.28,115.95 185.77,115.95
GND on TOP (solid shape): 26.24,61.49 26.24,60.16 26.11,60.03 24.78,60.03 24.59,60.22 24.59,61.55 24.72,61.68 26.05,61.68
GND on TOP (solid shape): 99.79,136.47 99.79,134.69 99.66,134.57 98.39,134.57 98.26,134.69 98.26,136.47 98.39,136.6 99.66,136.6
GND on TOP (solid shape): 103.15,138.76 103.15,134.82 102.9,134.57 101.82,134.57 101.63,134.76 101.63,138.82 101.69,138.89 103.03,138.89
GND on TOP (solid shape): 104.35,65.95 104.35,62.59 104.25,62.49 102.8,62.49 102.22,63.07 102.22,65.99 102.45,66.22 104.08,66.22
GND on TOP (solid shape): 106.45,138.63 106.45,134.76 106.26,134.57 105.12,134.57 104.93,134.76 104.93,138.76 105.06,138.89 106.2,138.89
GND on TOP (solid shape): 109.82,138.63 109.82,134.82 109.63,134.63 108.49,134.63 108.3,134.82 108.3,138.5 108.61,138.82 109.63,138.82
GND on TOP (solid shape): 113.12,26.55 113.12,23.95 112.93,23.76 108.42,23.76 107.92,24.27 107.92,26.62 108.17,26.87 112.8,26.87
GND on TOP (solid shape): 113.19,138.63 113.19,134.88 112.93,134.63 111.85,134.63 111.66,134.82 111.66,138.69 111.73,138.76 113.06,138.76
GND on TOP (solid shape): 118.9,145.17 118.9,144.03 118.71,143.84 116.61,143.84 116.17,144.28 116.17,145.3 116.23,145.36 118.71,145.36
GND on TOP (solid shape): 130.3,176.76 130.3,174.69 130.1,174.49 129.44,174.49 129.33,174.59 129.33,176.84 129.44,176.95 130.11,176.95
GND on TOP (solid shape): 149.44,183.72 149.44,179.14 149.19,178.89 147.98,178.89 147.79,179.08 147.79,183.78 147.86,183.84 149.32,183.84
GND on TOP (solid shape): 158.55,158.88 158.55,156.16 158.2,155.81 155.53,155.81 155.21,156.13 155.21,158.8 155.48,159.06 158.37,159.06
GND on TOP (solid shape): 214.98,173.11 214.98,170.83 214.85,170.7 212.37,170.7 212.18,170.89 212.18,171.33 214.02,173.18 214.91,173.18
GND on TOP (solid shape): 220.69,98.82 220.69,95.77 220.37,95.45 219.23,95.45 219.14,95.55 219.14,98.91 219.17,98.94 220.56,98.94
GND on TOP (solid shape): 26.29,34.01 26.29,30.01 26.08,29.81 24.07,29.81 23.91,29.97 23.91,34.12 24.03,34.24 26.06,34.24
GND on TOP (solid shape): 144.21,30.34 144.21,28.57 144.52,28.25 144.52,26.86 144.27,26.61 143.32,26.61 143.01,26.93 143.01,30.6 143.21,30.81 143.73,30.81
GND on TOP (solid shape): 158.84,134.43 158.84,126.31 158.78,126.24 158.08,126.24 156.49,127.83 153.7,127.83 153.25,128.27 153.25,133.73 154.08,134.56 158.71,134.56
GND on TOP (solid shape): 161.38,83.3 161.38,78.56 160.94,78.12 157.95,78.12 157.76,78.31 157.76,84.39 157.89,84.52 160.16,84.52
GND on TOP (solid shape): 198.63,91.76 198.63,90.2 198.43,90 192.42,90 192.31,90.11 192.31,90.97 192.4,91.06 192.73,91.06 193.71,92.04 198.35,92.04
GND on TOP (solid shape): 199.86,72.02 199.86,70.13 199.62,69.88 193.18,69.88 192.75,70.31 192.75,71.89 192.94,72.08 199.8,72.08
GND on TOP (solid shape): 148.11,145.43 148.11,143.77 147.92,143.58 140.36,143.58 140.11,143.84 140.11,145.24 140.3,145.43 140.81,145.43 141.19,145.81 147.73,145.81
GND on TOP (solid shape): 149.44,176.48 149.44,173.94 149,173.49 147.22,173.49 147.16,173.56 147.16,176.67 147.29,176.79 149.13,176.79
GND on TOP (solid shape): 29.87,64.63 29.87,58.98 29.77,58.88 28.34,58.88 28.31,58.92 28.31,63.89 28.55,64.14 28.55,64.77 28.67,64.88 29.62,64.88
GND on TOP (solid shape): 104.74,74.05 104.74,70.5 104.69,70.45 104.06,70.45 103.98,70.53 103.98,71.13 103.72,71.38 102.26,71.38 102.07,71.58 102.07,74.43 102.39,74.75 104.04,74.75
GND on TOP (solid shape): 160.72,176.67 161.76,176.67 161.89,176.54 161.89,175.97 161.7,175.78 158.67,175.78 158.44,176.01 158.44,177.77 158.54,177.86 159.53,177.86
GND on TOP (solid shape): 68.42,77.99 68.42,73.84 68.14,73.56 67.54,73.56 66.51,72.52 63.71,72.52 63.47,72.77 63.47,77.86 63.85,78.24 68.16,78.24
GND on TOP (solid shape): 142.27,188.22 142.01,187.97 140.62,187.97 139.86,187.21 139.86,186.76 139.6,186.51 136.05,186.51 135.6,186.95 135.6,189.72 135.64,189.77 135.68,189.83 142.27,189.83
GND on TOP (solid shape): 167.67,172.29 167.67,171.97 167.61,171.91 167.61,170.7 167.54,170.64 167.41,170.64 167.35,170.7 167.35,171.78 167.16,171.97 167.16,172.03 166.84,172.35 166.84,172.67 166.97,172.79 167.16,172.79
GND on TOP (solid shape): 174.99,158.56 174.99,157.27 174.82,157.1 171.52,157.1 171.17,156.76 161.93,156.76 161.87,156.82 161.87,157.51 161.97,157.6 162.23,157.6 162.55,157.92 162.55,159.29 163.08,159.83 173.73,159.83
GND on TOP (solid shape): 182.44,158.66 182.44,157.95 182.34,157.85 181.44,157.85 181.08,157.49 181.08,157.16 180.8,156.89 177.76,156.89 177.61,157.04 177.61,158.03 177.98,158.4 180.36,158.4 180.75,158.78 182.32,158.78
GND on TOP (solid shape): 182.89,64.93 182.89,63.83 182.98,63.73 182.98,61.78 182.68,61.47 181.08,61.47 180.88,61.67 180.88,63.89 181.27,64.28 181.79,64.28 181.99,64.49 181.99,64.98 182.06,65.04 182.78,65.04
GND on TOP (solid shape): 187.43,158.15 193.67,158.15 193.95,158.43 198.08,158.43 198.25,158.27 198.25,157.59 197.87,157.2 193.64,157.2 193.29,156.85 183.02,156.85 182.85,157.01 182.85,159.05 183.03,159.23 186.35,159.23
GND on TOP (solid shape): 91.47,139.2 91.47,136.22 91.21,135.96 88.48,135.96 88.17,135.65 88.17,135.14 88.1,135.08 87.6,135.08 87.47,135.2 87.47,138.25 87.15,138.57 85.5,138.57 85.37,138.69 85.37,139.14 85.56,139.33 91.34,139.33
GND on TOP (solid shape): 183.04,74.94 183.04,71.16 182.97,71.1 182.43,71.1 182.34,71.19 182.34,72.65 182.15,72.85 182.07,72.85 180.51,72.85 180.5,72.85 180.31,72.65 179.86,72.65 179.67,72.85 179.67,75.07 179.8,75.19 182.78,75.19
GND on TOP (solid shape): 191.99,186.32 191.99,185.3 191.48,184.8 191.48,176.92 191.54,176.86 191.54,175.97 190.78,175.21 187.86,175.21 186.91,176.16 184.88,176.16 184.51,176.53 178.71,176.53 178.27,176.97 178.27,182.13 178.97,182.83 183.67,182.83 187.54,186.7 191.61,186.7
GND on TOP (solid shape): 162.27,174.38 162.27,171.84 161.76,171.33 161.76,166.76 162.08,166.44 162.78,166.44 162.97,166.25 162.97,162.19 162.46,161.68 159.41,161.68 158.65,162.44 158.65,169.75 158.91,170 158.91,173.81 159.22,174.13 160.24,174.13 160.56,174.45 162.21,174.45
GND on TOP (solid shape): 12.35,56.06 12.35,53.41 11.91,52.98 10.49,52.98 10.4,53 10.3,53 0.3,53 0.27,53.02 0.25,53.05 0.25,56.55 0.27,56.58 0.3,56.6 11.81,56.6
GND on TOP (solid shape): 211.99,85.67 211.99,81.35 209.16,78.52 201.45,78.52 200.89,77.96 198.18,77.96 197.01,79.13 193.52,79.13 193.42,79.23 193.42,80.37 193.89,80.85 194.78,80.85 195.74,81.8 208.56,81.8 209.32,82.56 209.32,85.8 209.64,86.12 211.55,86.12
GND on TOP (solid shape): 130.91,166.62 130.91,165.8 131.05,165.66 131.05,164.14 130.92,164.01 129.86,164.01 129.74,163.89 129.74,163.54 129.59,163.39 128.3,163.39 128.12,163.57 128.12,163.8 127.93,163.99 127.42,163.99 127.18,164.23 127.18,164.81 127.22,164.85 127.83,164.85 128.17,165.19 128.76,165.19 129.08,165.5 129.08,166.42 129.37,166.71 130.81,166.71
GND on TOP (solid shape): 221.77,131.65 221.77,125.88 220.97,125.09 220.97,120.85 220.59,120.47 220.06,120.47 219.75,120.16 219.75,119 219.61,118.86 219.17,118.86 219.05,118.99 219.05,120.66 219.39,121.01 219.39,125.93 219.47,126.01 219.9,126.01 219.92,126.03 220.01,126.03 220.17,126.2 220.17,127.59 219.58,128.19 219.58,133.16 219.74,133.31 220.11,133.31
GND on TOP (solid shape): 182.02,175.46 183.59,175.46 184.18,174.87 184.18,174.87 184.18,174.13 184.05,174 183.23,174 182.97,173.75 182.97,172.48 181.77,171.27 181.77,170.76 181.7,170.7 181.19,170.7 181,170.89 181,172.54 180.75,172.79 179.42,172.79 179.16,173.05 179.16,174.45 179.35,174.64 179.92,174.64 180.05,174.76 180.05,176.22 180.15,176.32 181.16,176.32
GND on TOP (solid shape): 130.76,24.94 130.76,23.29 130.56,23.09 129.7,23.09 129.43,22.82 129.43,21.46 128.81,20.84 122.69,20.84 122.56,20.97 122.56,22.02 122.71,22.17 123.98,22.17 124.17,22.36 124.17,24.33 124.3,24.46 125.35,24.46 125.86,24.97 127.6,24.97 127.73,24.84 129.59,24.84 129.82,25.07 130.64,25.07
GND on TOP (solid shape): 207.29,60.78 207.29,58.56 207.42,58.43 208.05,58.43 208.12,58.37 208.12,57.8 208.05,57.73 207.42,57.73 207.17,57.48 207.17,55 206.98,54.81 202.47,54.81 201.96,54.3 201.26,54.3 201.2,54.37 201.2,55 201.13,55.07 200.56,55.07 200.43,55.19 200.43,55.76 200.5,55.83 201.9,55.83 202.09,55.64 202.53,55.64 203.87,56.98 203.87,57.62 204.58,58.33 205.9,58.33 206.22,58.65 206.22,60.72 206.34,60.84 207.23,60.84
GND on TOP (solid shape): 11.78,95.26 11.78,92.15 12.22,91.7 13.2,91.7 13.92,91.48 14.38,90.88 13.81,90.88 13.54,91.11 13.2,91.19 0.9,91.19 0.87,91.21 0.85,91.24 0.85,95.6 0.87,95.63 0.9,95.65 11.39,95.65
GND on TOP (solid shape): 14.43,74.88 13.99,74.17 13.2,73.9 12.92,73.9 12.54,73.52 12.54,71 11.55,70.02 11.04,70.02 10.77,70.44 10.3,70.6 1.1,70.6 1.07,70.62 1.05,70.65 1.05,74.36 1.07,74.39 1.1,74.41 13.2,74.41 13.62,74.54 13.9,74.88
GND on TOP (solid shape): outline of 91 points within 213.01,61.19 218.12,74.79
GND on TOP (solid shape): 12.41,38.49 12.41,35.13 11.27,33.98 8.52,33.98 8.48,33.94 8.36,33.81 8.23,33.69 8.23,23.82 8.74,23.32 11.78,23.32 12.35,22.74 12.35,21.22 10.76,19.63 0.25,19.63 0.25,21.3 0.27,21.33 0.3,21.35 7.47,21.35 8.21,21.95 7.76,22.8 7.73,22.82 7.72,22.85 7.72,33.96 7.73,33.98 7.76,34 8.21,34.85 7.47,35.45 1.1,35.45 1.07,35.47 1.05,35.5 1.05,38.95 1.07,38.98 1.1,39 11.91,39
GND on TOP (solid shape): outline of 162 points within 216.12,99.88 221.33,116.91
GND on TOP (solid shape): outline of 183 points within 137.57,147.84 146.71,159.52
GND on TOP (solid shape): outline of 265 points within 112.98,93.71 114.63,102.6
GND on TOP (solid shape): outline of 90 points within 0.25,111.65 92.68,159.55
GND on TOP (solid shape): outline of 249 points within 16.62,0.25 230.15,190.85
GND on BOTTOM (solid shape): 113.55,28.81 113.55,27.47 110.44,27.47 110.44,28.74 110.63,28.93 113.42,28.93
GND on BOTTOM (solid shape): 109.82,134.44 109.82,132.66 109.69,132.54 108.99,132.54 108.74,132.79 108.74,134.63 109.63,134.63
GND on BOTTOM (solid shape): 30.99,53.26 30.99,50.97 30.64,50.62 27.66,50.62 27.43,50.86 27.43,53.13 27.84,53.54 30.7,53.54
GND on BOTTOM (solid shape): 101.31,29.47 101.31,27.32 101.25,27.25 100.23,27.25 99.98,27.51 99.98,29.35 100.17,29.54 101.25,29.54
GND on BOTTOM (solid shape): 104.55,30.17 104.55,28.9 104.36,28.71 102.01,28.71 101.82,28.9 101.82,30.24 101.95,30.36 104.36,30.36
GND on BOTTOM (solid shape): 131.03,166.51 131.03,164.03 130.71,163.71 127.92,163.71 127.79,163.84 127.79,166.76 127.92,166.89 130.65,166.89
GND on BOTTOM (solid shape): 143.74,158.94 143.74,157.93 142.21,157.93 142.21,159.01 142.34,159.13 143.54,159.13
GND on BOTTOM (solid shape): 153.71,23.58 153.71,19.9 153.26,19.45 150.4,19.45 150.09,19.77 150.09,23.58 150.59,24.09 153.2,24.09
GND on BOTTOM (solid shape): 155.61,26.31 155.61,25.18 155.41,24.98 154.28,24.98 154.15,25.11 154.15,26.31 154.34,26.5 155.42,26.5
GND on BOTTOM (solid shape): 191.61,187.4 191.61,186.13 191.48,186 188.5,186 188.31,186.19 188.31,187.46 188.37,187.53 191.48,187.53
GND on BOTTOM (solid shape): 191.61,176.16 191.61,174.89 191.48,174.76 188.31,174.76 188.18,174.89 188.18,176.22 188.31,176.35 191.42,176.35
GND on BOTTOM (solid shape): 218.34,169.68 218.34,167.4 218.02,167.08 215.8,167.08 215.61,167.27 215.61,169.75 215.74,169.87 218.15,169.87
GND on BOTTOM (solid shape): 103.18,134.38 103.18,132.73 103.06,132.6 101.82,132.6 101.69,132.73 101.69,133.04 102.01,133.36 102.01,134.63 102.93,134.63
GND on BOTTOM (solid shape): 106.49,134.41 106.49,132.73 106.36,132.6 105.12,132.6 104.99,132.73 104.99,133.04 105.38,133.42 105.38,134.63 106.26,134.63
GND on BOTTOM (solid shape): 187.61,174 187.61,170.89 187.42,170.7 186.27,170.7 186.08,170.89 186.08,174 186.27,174.19 187.42,174.19
GND on BOTTOM (solid shape): 30.06,22.43 30.06,18.49 29.56,17.98 26.64,17.98 26.44,18.17 26.44,18.87 24.98,20.33 24.98,22.36 25.37,22.74 29.75,22.74
GND on BOTTOM (solid shape): 99.82,134.41 99.82,132.73 99.69,132.6 98.45,132.6 98.33,132.73 98.33,132.98 98.64,133.3 98.64,134.63 98.71,134.69 99.53,134.69
GND on BOTTOM (solid shape): 113.12,134.44 113.12,132.73 112.93,132.54 111.85,132.54 111.69,132.69 111.69,132.88 112.11,133.3 112.11,134.57 112.17,134.63 112.93,134.63
GND on BOTTOM (solid shape): 174.13,157.94 174.13,157.44 173.79,157.1 171.96,157.1 171.61,156.76 162.42,156.76 162.25,156.93 162.25,158.06 162.84,158.66 173.41,158.66
GND on BOTTOM (solid shape): 177.73,31.47 177.73,28.97 177.46,28.7 175.8,28.7 175.48,29.02 175.48,30.7 175.21,30.97 175.21,31.47 175.32,31.58 177.62,31.58
GND on BOTTOM (solid shape): 189.96,168.73 189.96,166.63 189.64,166.32 186.97,166.32 186.46,166.83 186.46,168.73 186.97,169.24 189.45,169.24
GND on BOTTOM (solid shape): 29.43,33.03 29.43,31.06 28.86,30.49 25.56,30.49 25.05,31 25.05,34.05 25.3,34.3 28.16,34.3
GND on BOTTOM (solid shape): 30.46,65.54 30.46,64.16 29.75,63.45 29.7,63.4 27.23,63.4 26.61,64.03 26.61,64.75 27.68,65.83 30.18,65.83
GND on BOTTOM (solid shape): 91.41,30.05 91.41,29.03 91.34,28.97 89.31,28.97 89.3,28.96 88.52,28.96 88.34,29.14 88.34,29.73 88.84,30.24 91.21,30.24
GND on BOTTOM (solid shape): 93.06,29.28 93.06,28.46 93.06,28.34 93.06,27.44 92.93,27.32 91.85,27.32 91.72,27.44 91.72,29.35 91.85,29.47 92.87,29.47
GND on BOTTOM (solid shape): 125.44,18.87 125.44,17.69 125.08,17.33 123.2,17.33 122.27,16.39 121.36,16.39 120.86,16.9 120.86,18.67 121.44,19.25 125.06,19.25
GND on BOTTOM (solid shape): 158.21,23.7 158.21,22.69 158.34,22.57 158.34,21.68 158.21,21.55 157.96,21.55 157.83,21.68 157.83,22.57 158.02,22.76 158.02,23.7 158.08,23.76 158.15,23.76
GND on BOTTOM (solid shape): 142.27,188.03 141.95,187.72 140.36,187.72 139.86,187.21 139.86,186.76 139.6,186.51 136.05,186.51 135.6,186.95 135.6,189.72 135.64,189.77 135.68,189.83 142.27,189.83
GND on BOTTOM (solid shape): 158.27,108.46 158.27,108.28 157.98,107.99 157.98,105.15 157.91,105.08 157.22,105.08 156.11,106.19 156.11,108.53 156.22,108.64 158.09,108.64
GND on BOTTOM (solid shape): 189.86,158.29 193.03,158.29 193.4,157.92 194.85,157.92 195.2,157.57 195.2,156.87 195.01,156.69 185.03,156.69 183.96,157.75 183.96,158.51 184.14,158.68 189.46,158.68
GND on BOTTOM (solid shape): 137.95,139.58 137.95,137.17 137.13,136.35 129.31,136.35 128.69,135.72 128.69,133.44 128.55,133.3 127.19,133.3 127,133.49 127,138.9 128.57,140.47 137.06,140.47
GND on BOTTOM (solid shape): 158.99,29.28 158.99,27.92 158.85,27.77 158.4,27.77 157.83,27.2 157.83,25.93 157.77,25.87 157.64,25.87 157.58,25.93 157.58,28.03 157.52,28.09 157.52,29.17 157.64,29.3 158.98,29.3
GND on BOTTOM (solid shape): 222.55,113.79 222.55,112.22 222.34,112.01 222.34,107.01 221.96,106.62 219.02,106.62 218.84,106.8 218.84,113.42 219.27,113.85 222.49,113.85
GND on BOTTOM (solid shape): 183.83,174.6 183.83,173.08 182.46,171.71 181.26,171.71 181.13,171.84 181.13,172.98 180.94,173.18 179.92,173.18 179.8,173.3 179.8,174.83 179.92,174.95 183.48,174.95
GND on BOTTOM (solid shape): 129.49,24.52 129.49,22.79 129.19,22.49 129,22.49 128.74,22.24 128.74,21.47 128.49,21.22 125.63,21.22 125.38,20.97 124.3,20.97 124.17,21.09 124.17,22.25 125.43,23.51 125.43,24.55 125.65,24.78 129.24,24.78
GND on BOTTOM (solid shape): 137.43,96.47 137.43,94.83 137.25,94.64 133.17,94.64 132.81,95.01 132.81,95.77 133,95.96 133.57,95.96 133.76,96.15 133.76,96.66 133.82,96.72 137.18,96.72
GND on BOTTOM (solid shape): 161.39,20.28 161.39,19.07 161.13,18.82 159.1,18.82 159.04,18.88 159.04,19.33 159.17,19.45 159.17,20.03 159.23,20.09 159.23,20.41 161.26,20.41
GND on BOTTOM (solid shape): 196.43,64.4 196.43,63.45 196.12,63.13 193.45,63.13 193.2,62.88 193.2,61.92 193.7,61.42 193.7,60.08 193.58,59.95 192.88,59.95 192.75,60.08 192.12,60.08 191.86,60.34 191.86,64.46 192.24,64.84 195.99,64.84
GND on BOTTOM (solid shape): 133.89,20.68 133.89,16.26 133.48,15.85 132.38,15.85 131.23,16.99 131.14,16.99 131.13,16.98 130.93,16.98 130.92,16.99 130.33,16.99 130.2,17.12 130.2,20.74 130.4,20.93 131.17,20.93 131.55,21.31 133.25,21.31
GND on BOTTOM (solid shape): 158.59,26.82 158.59,25.87 158.72,25.74 159.36,25.74 159.36,24.03 157.64,24.03 157.64,25.74 158.34,25.74 158.4,25.8 158.4,26.82 158.47,26.88 158.53,26.88
GND on BOTTOM (solid shape): 124.52,137.51 124.52,134.7 124.26,134.45 124.26,132.7 124.18,132.61 121.83,132.61 121.68,132.76 121.68,135 121.82,135.14 122.75,135.14 122.95,135.34 122.95,137.47 123.03,137.55 124.48,137.55
GND on BOTTOM (solid shape): 182.42,158.35 182.42,158.15 181.89,157.62 181.89,156.86 181.77,156.74 179.78,156.74 179.55,156.97 177.69,156.97 177.59,157.08 177.59,157.58 177.68,157.67 178.19,157.67 179.02,158.51 182.27,158.51
GND on BOTTOM (solid shape): 220.04,141.45 220.78,141.45 220.94,141.29 220.94,139.69 220.45,139.19 220.45,136.32 222.52,134.24 222.52,127 222.05,126.53 220.36,126.53 219.82,127.07 219.82,127.7 219.73,127.79 219.19,127.79 219.1,127.87 219.1,141.61 219.2,141.71 219.78,141.71
GND on BOTTOM (solid shape): 220.95,125.94 220.95,125.15 221.3,124.8 221.3,123.86 220.93,123.49 220.93,122.77 220.76,122.6 219.91,122.6 219.9,122.6 219.77,122.6 219.71,122.54 219.14,122.54 219.06,122.62 219.06,125.73 219.21,125.87 219.57,125.87 219.83,126.13 220.75,126.13
GND on BOTTOM (solid shape): 162.33,176.03 162.33,171.91 161.76,171.33 161.76,166.76 162.08,166.44 163.41,166.44 163.67,166.19 163.67,162.13 163.29,161.75 160.37,161.75 159.16,162.95 159.16,165.43 158.91,165.68 158.91,175.33 160.18,176.6 161.76,176.6
GND on BOTTOM (solid shape): 210.17,81.35 210.17,80.59 209.42,79.83 202.97,79.83 200.31,77.16 190.02,77.16 189.64,77.54 189.64,79.83 190.27,80.47 197.26,80.47 197.64,80.85 198.91,80.85 199.55,81.48 210.04,81.48
GND on BOTTOM (solid shape): 12.35,56.06 12.35,53.41 11.91,52.98 10.49,52.98 10.4,53 10.3,53 0.3,53 0.27,53.02 0.25,53.05 0.25,56.55 0.27,56.58 0.3,56.6 11.81,56.6
GND on BOTTOM (solid shape): 41.61,81.93 41.82,81.93 41.82,81.92 44.16,81.92 44.22,81.86 44.22,81.23 44.16,81.16 43.47,81.16 43.41,81.1 43.34,81.1 43.21,80.97 43.21,79.2 43.02,79 42.07,79 41.94,79.13 41.94,81.04 41.88,81.1 40.58,81.1 40.39,81.29 40.39,82.25 40.52,82.38 41.16,82.38
GND on BOTTOM (solid shape): 118.93,145.13 118.93,144.06 118.71,143.84 116.68,143.84 116.01,144.51 116.01,144.52 115.99,144.52 115.85,144.66 113.57,144.66 113.31,144.41 113.31,143.58 113.63,143.27 114.58,143.27 114.58,139.14 112.42,139.14 112.42,144.66 113.11,145.35 118.71,145.35
GND on BOTTOM (solid shape): 162.4,14.98 162.4,14.49 162.47,14.43 164.05,14.43 164.56,13.92 164.56,9.92 164.49,9.85 163.35,9.85 163.16,10.04 163.16,11.69 162.84,12.01 158.14,12.01 157.83,12.33 157.83,12.77 157.64,12.96 156.62,12.96 156.56,13.03 156.56,14.87 156.81,15.12 162.27,15.12
GND on BOTTOM (solid shape): 180.88,182.95 180.88,182.83 180.81,182.76 179.54,182.76 179.42,182.64 179.42,181.18 179.48,181.11 181.13,181.11 181.94,180.31 181.94,177.95 181.58,177.58 181.58,176.99 181.38,176.79 180.66,176.79 180.41,176.54 178.64,176.54 178.46,176.72 178.46,179.72 178.84,180.1 178.84,183.02 180.81,183.02
GND on BOTTOM (solid shape): 145.04,153.1 144.79,153.1 144.79,154.37 143.16,154.37 143.16,153.1 141.08,151.01 140.17,151.01 139.73,151.46 138.9,151.46 138.78,151.59 138.78,152.84 138.78,152.85 138.78,154.26 139.03,154.51 142.06,154.51 142.59,155.03 145.04,155.03
GND on BOTTOM (solid shape): 217.99,92.86 217.99,91.96 218.24,91.7 220.12,91.7 220.18,91.64 220.18,90.94 220.06,90.82 218.79,90.82 218.72,90.75 218.72,89.8 218.66,89.74 218.47,89.74 218.28,89.93 218.28,90.24 217.43,91.09 215.89,91.09 215.81,91.16 215.81,92.01 215.96,92.16 217.07,92.16 217.17,92.26 217.17,92.9 217.26,93 217.85,93
GND on BOTTOM (solid shape): 111.55,26.24 113.07,26.24 113.17,26.14 113.17,25.76 113.04,25.63 112.98,25.63 112.21,24.87 112.21,24.43 112.15,24.36 111.64,24.36 111.29,24.71 111.28,24.71 111.15,24.84 109.63,24.84 109.5,24.71 109.5,23.85 109.47,23.82 109.33,23.82 108.85,24.3 107.33,24.3 107.2,24.43 107.2,25.25 107.9,25.25 108.09,25.44 108.09,26.2 108.79,26.2 109.2,25.79 110.75,25.79 110.75,26.71 110.82,26.78 111.01,26.78
GND on BOTTOM (solid shape): 217.83,74.56 217.83,61.42 217.26,60.84 215.74,60.84 215.55,61.03 215.55,62.37 215.42,62.49 214.85,62.49 214.72,62.62 213.58,62.62 213.45,62.75 213.45,66.5 213.71,66.75 215.61,66.75 215.8,66.94 215.8,68.15 215.61,68.34 213.67,68.34 213.44,68.57 213.44,71.84 214,72.4 214.85,72.4 215.29,72.85 215.29,74.69 215.42,74.81 217.58,74.81
GND on BOTTOM (solid shape): 11.78,95.26 11.78,92.15 12.22,91.7 13.2,91.7 13.92,91.48 14.38,90.88 13.81,90.88 13.54,91.11 13.2,91.19 0.9,91.19 0.87,91.21 0.85,91.24 0.85,95.6 0.87,95.63 0.9,95.65 11.39,95.65
GND on BOTTOM (solid shape): 109.44,96.29 109.44,94.05 108.43,93.05 99.47,93.05 98.89,92.47 97.76,92.47 97.63,92.59 97.63,93.93 97.76,94.05 98.36,94.05 98.65,94.35 98.73,94.38 98.81,94.33 99.24,94.38 98.99,94.74 98.97,94.74 98.91,94.8 98.81,94.8 98.81,95.92 99.2,96.31 109.41,96.31
GND on BOTTOM (solid shape): 14.43,74.88 13.99,74.17 13.2,73.9 12.92,73.9 12.54,73.52 12.54,71 11.55,70.02 11.04,70.02 10.77,70.44 10.3,70.6 1.1,70.6 1.07,70.62 1.05,70.65 1.05,74.36 1.07,74.39 1.1,74.41 13.2,74.41 13.62,74.54 13.9,74.88
GND on BOTTOM (solid shape): 12.41,38.49 12.41,35.13 11.27,33.98 8.52,33.98 8.48,33.94 8.36,33.81 8.23,33.69 8.23,23.82 8.74,23.32 11.78,23.32 12.35,22.74 12.35,21.22 10.76,19.63 0.25,19.63 0.25,21.3 0.27,21.33 0.3,21.35 7.47,21.35 8.21,21.95 7.76,22.8 7.73,22.82 7.72,22.85 7.72,33.96 7.73,33.98 7.76,34 8.21,34.85 7.47,35.45 1.1,35.45 1.07,35.47 1.05,35.5 1.05,38.95 1.07,38.98 1.1,39 11.91,39
GND on BOTTOM (solid shape): outline of 90 points within 0.25,111.65 92.68,159.55
GND on BOTTOM (solid shape): outline of 249 points within 16.62,0.25 230.15,190.85
GND on BOTTOM (solid shape): outline of 441 points within 95.31,122.73 117.08,125.42
GND on IN1 (solid shape): 114.65,144.22 114.65,139.65 114.46,139.46 112.42,139.46 112.04,139.84 112.04,144.35 112.68,144.98 113.88,144.98
GND on IN1 (solid shape): 163.73,167.21 163.73,162.13 163.41,161.81 159.29,161.81 158.84,162.25 158.84,166.95 159.48,167.59 163.35,167.59
GND on IN1 (solid shape): 12.35,56.06 12.35,53.41 11.91,52.98 10.49,52.98 10.4,53 10.3,53 0.3,53 0.27,53.02 0.25,53.05 0.25,56.55 0.27,56.58 0.3,56.6 11.81,56.6
GND on IN1 (solid shape): 218.21,75.96 218.21,61.92 217.2,60.91 215.99,60.91 215.74,61.16 215.74,62.11 215.55,62.3 214.66,62.3 214.47,62.49 214.47,66.43 214.79,66.75 215.48,66.75 215.74,67 215.74,68.08 215.55,68.27 214.53,68.27 214.4,68.4 214.4,76.34 214.66,76.59 217.58,76.59
GND on IN1 (solid shape): 11.78,95.26 11.78,92.15 12.22,91.7 13.2,91.7 13.92,91.48 14.38,90.88 13.81,90.88 13.54,91.11 13.2,91.19 0.9,91.19 0.87,91.21 0.85,91.24 0.85,95.6 0.87,95.63 0.9,95.65 11.39,95.65
GND on IN1 (solid shape): 14.43,74.88 13.99,74.17 13.2,73.9 12.92,73.9 12.54,73.52 12.54,71 11.55,70.02 11.04,70.02 10.77,70.44 10.3,70.6 1.1,70.6 1.07,70.62 1.05,70.65 1.05,74.36 1.07,74.39 1.1,74.41 13.2,74.41 13.62,74.54 13.9,74.88
GND on IN1 (solid shape): 12.41,38.49 12.41,35.13 11.27,33.98 8.52,33.98 8.48,33.94 8.36,33.81 8.23,33.69 8.23,23.82 8.74,23.32 11.78,23.32 12.35,22.74 12.35,21.22 10.76,19.63 0.25,19.63 0.25,21.3 0.27,21.33 0.3,21.35 7.47,21.35 8.21,21.95 7.76,22.8 7.73,22.82 7.72,22.85 7.72,33.96 7.73,33.98 7.76,34 8.21,34.85 7.47,35.45 1.1,35.45 1.07,35.47 1.05,35.5 1.05,38.95 1.07,38.98 1.1,39 11.91,39
GND on IN1 (solid shape): outline of 151 points within 137.57,147.84 146.71,159.52
GND on IN1 (solid shape): outline of 90 points within 0.25,111.65 92.68,159.55
GND on IN1 (solid shape): outline of 822 points within 145.13,170.44 162.72,177.87
GND on IN1 (solid shape): outline of 241 points within 16.62,0.25 230.15,190.85
GND on IN2 (solid shape): 183.99,181.43 183.99,177.49 183.01,176.51 175.64,176.51 174.84,177.3 174.84,181.3 175.8,182.26 183.16,182.26
GND on IN2 (solid shape): 12.35,56.06 12.35,53.41 11.91,52.98 10.49,52.98 10.4,53 10.3,53 0.3,53 0.27,53.02 0.25,53.05 0.25,56.55 0.27,56.58 0.3,56.6 11.81,56.6
GND on IN2 (solid shape): 11.78,95.26 11.78,92.15 12.22,91.7 13.2,91.7 13.92,91.48 14.38,90.88 13.81,90.88 13.54,91.11 13.2,91.19 0.9,91.19 0.87,91.21 0.85,91.24 0.85,95.6 0.87,95.63 0.9,95.65 11.39,95.65
GND on IN2 (solid shape): 14.43,74.88 13.99,74.17 13.2,73.9 12.92,73.9 12.54,73.52 12.54,71 11.55,70.02 11.04,70.02 10.77,70.44 10.3,70.6 1.1,70.6 1.07,70.62 1.05,70.65 1.05,74.36 1.07,74.39 1.1,74.41 13.2,74.41 13.62,74.54 13.9,74.88
GND on IN2 (solid shape): outline of 85 points within 112.42,139.14 119.41,145.35
GND on IN2 (solid shape): 12.41,38.49 12.41,35.13 11.27,33.98 8.52,33.98 8.48,33.94 8.36,33.81 8.23,33.69 8.23,23.82 8.74,23.32 11.78,23.32 12.35,22.74 12.35,21.22 10.76,19.63 0.25,19.63 0.25,21.3 0.27,21.33 0.3,21.35 7.47,21.35 8.21,21.95 7.76,22.8 7.73,22.82 7.72,22.85 7.72,33.96 7.73,33.98 7.76,34 8.21,34.85 7.47,35.45 1.1,35.45 1.07,35.47 1.05,35.5 1.05,38.95 1.07,38.98 1.1,39 11.91,39
GND on IN2 (solid shape): outline of 109 points within 151.16,10.49 164.43,19.76
GND on IN2 (solid shape): outline of 183 points within 137.57,147.84 146.71,159.52
GND on IN2 (solid shape): outline of 217 points within 174.53,169.27 184.37,175.05
GND on IN2 (solid shape): outline of 90 points within 0.25,111.65 92.68,159.55
GND on IN2 (solid shape): outline of 752 points within 117.82,20.9 136.24,29.79
GND on IN2 (solid shape): outline of 243 points within 16.62,0.25 230.15,190.85
GND on IN2 (solid shape): outline of 1010 points within 145.19,161.68 162.97,178.13
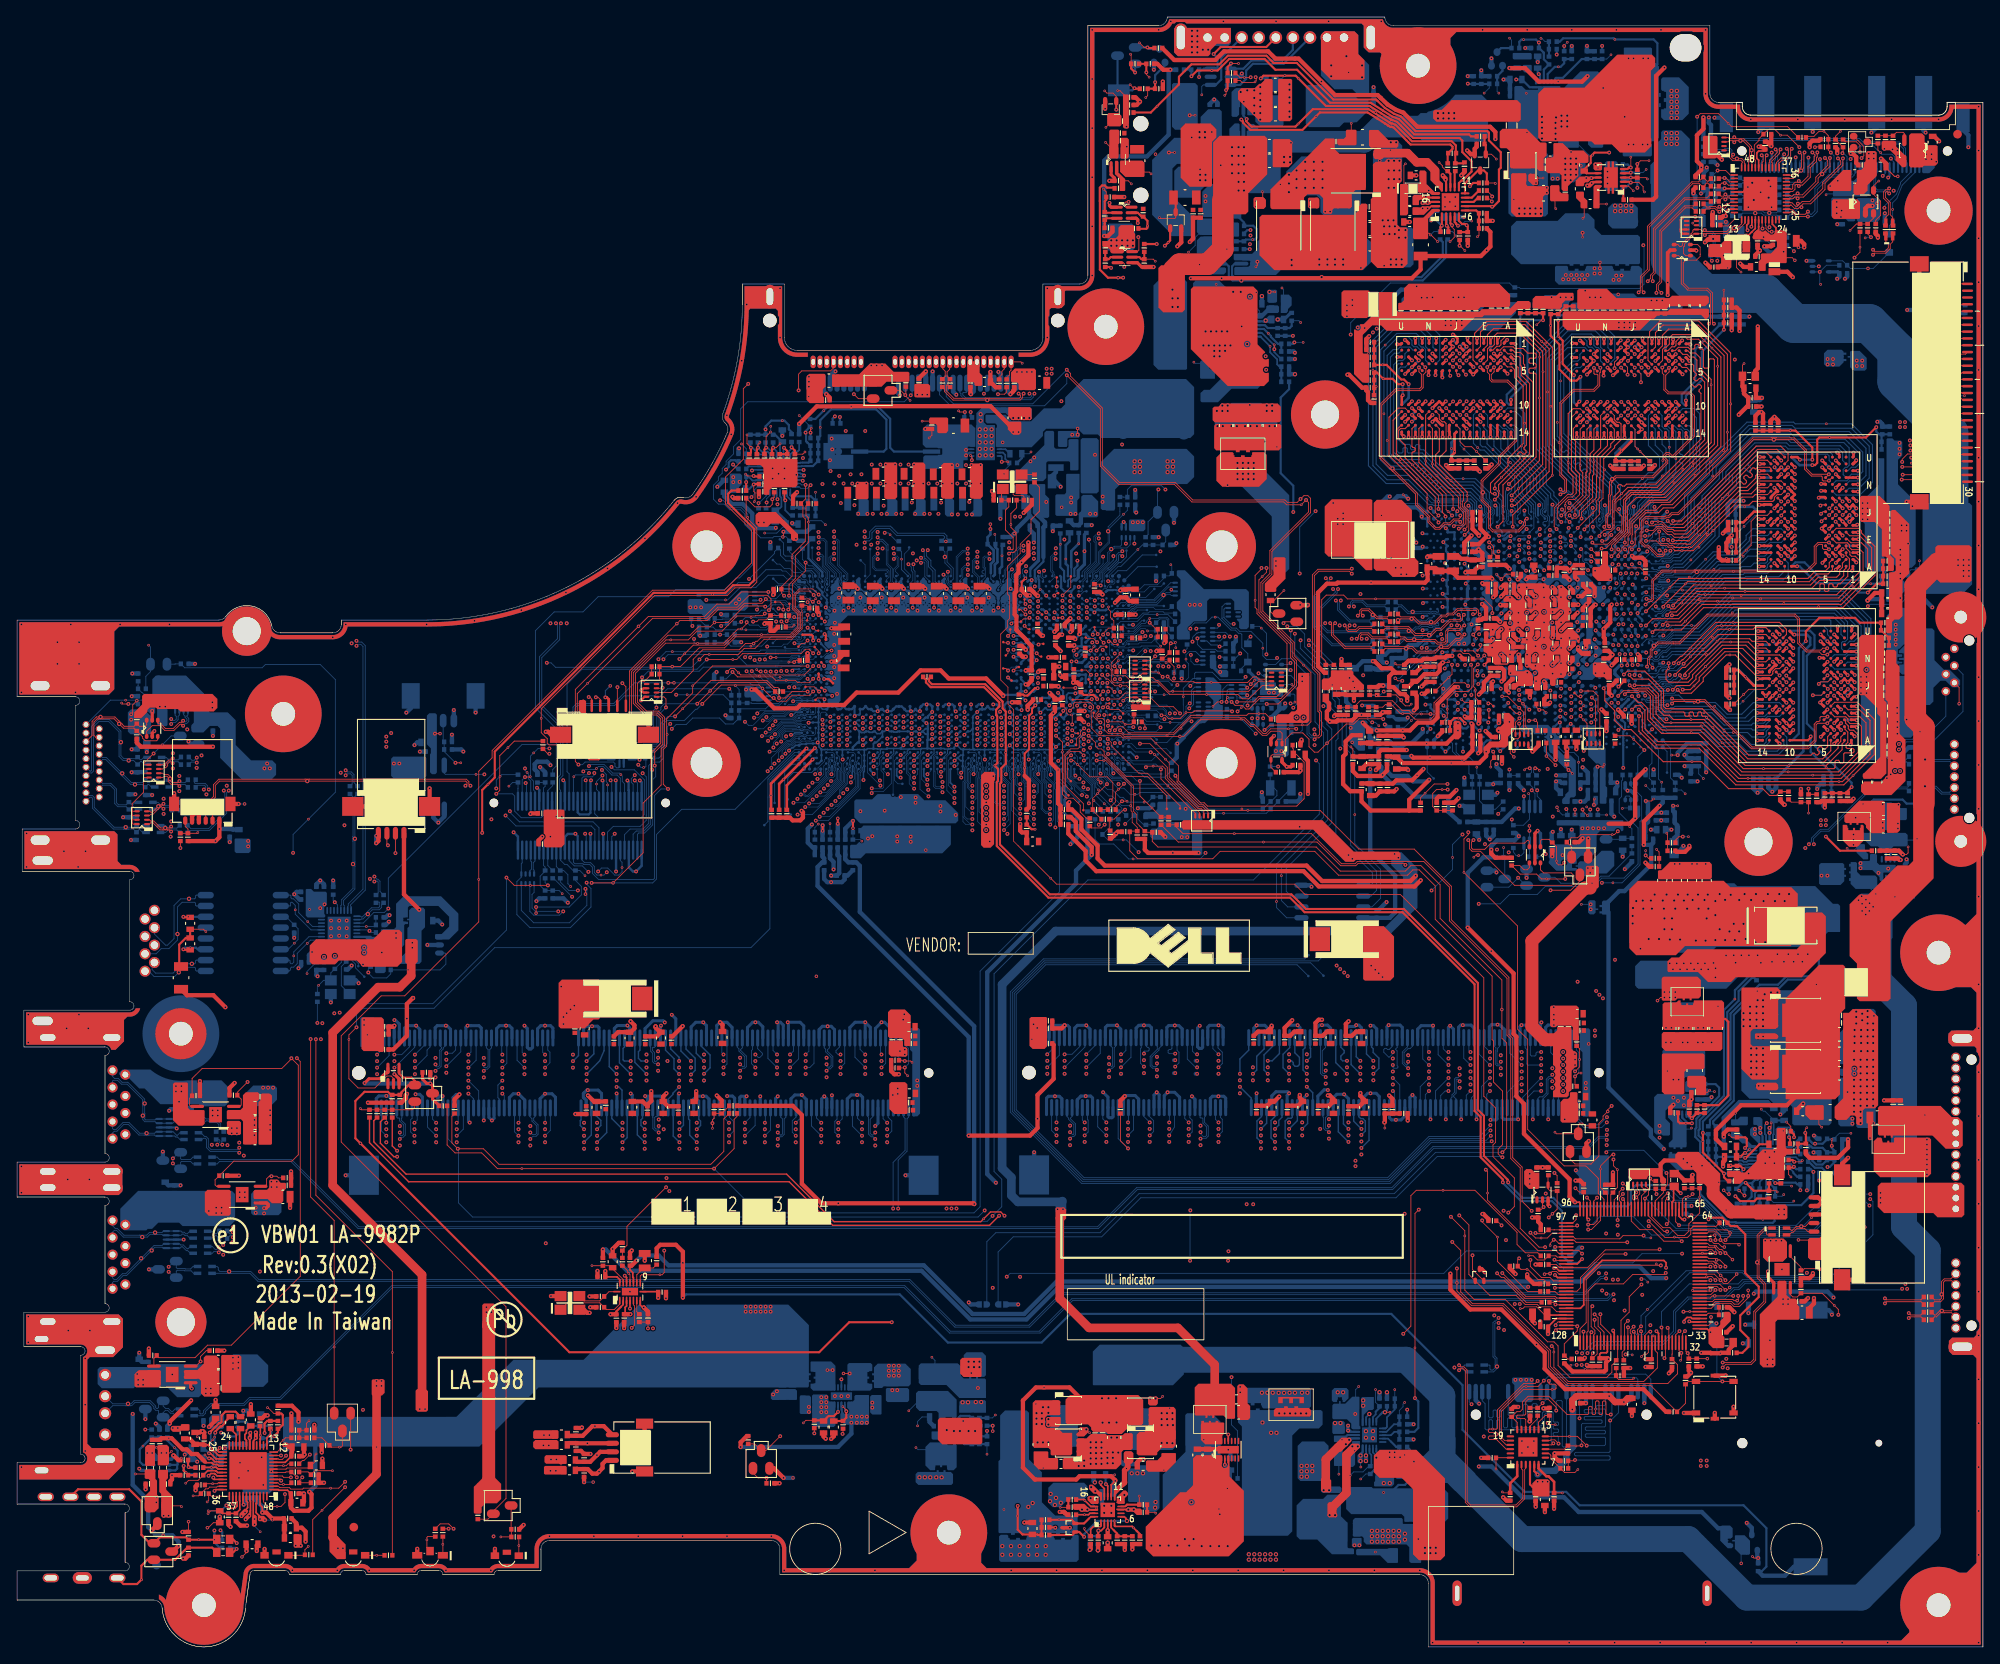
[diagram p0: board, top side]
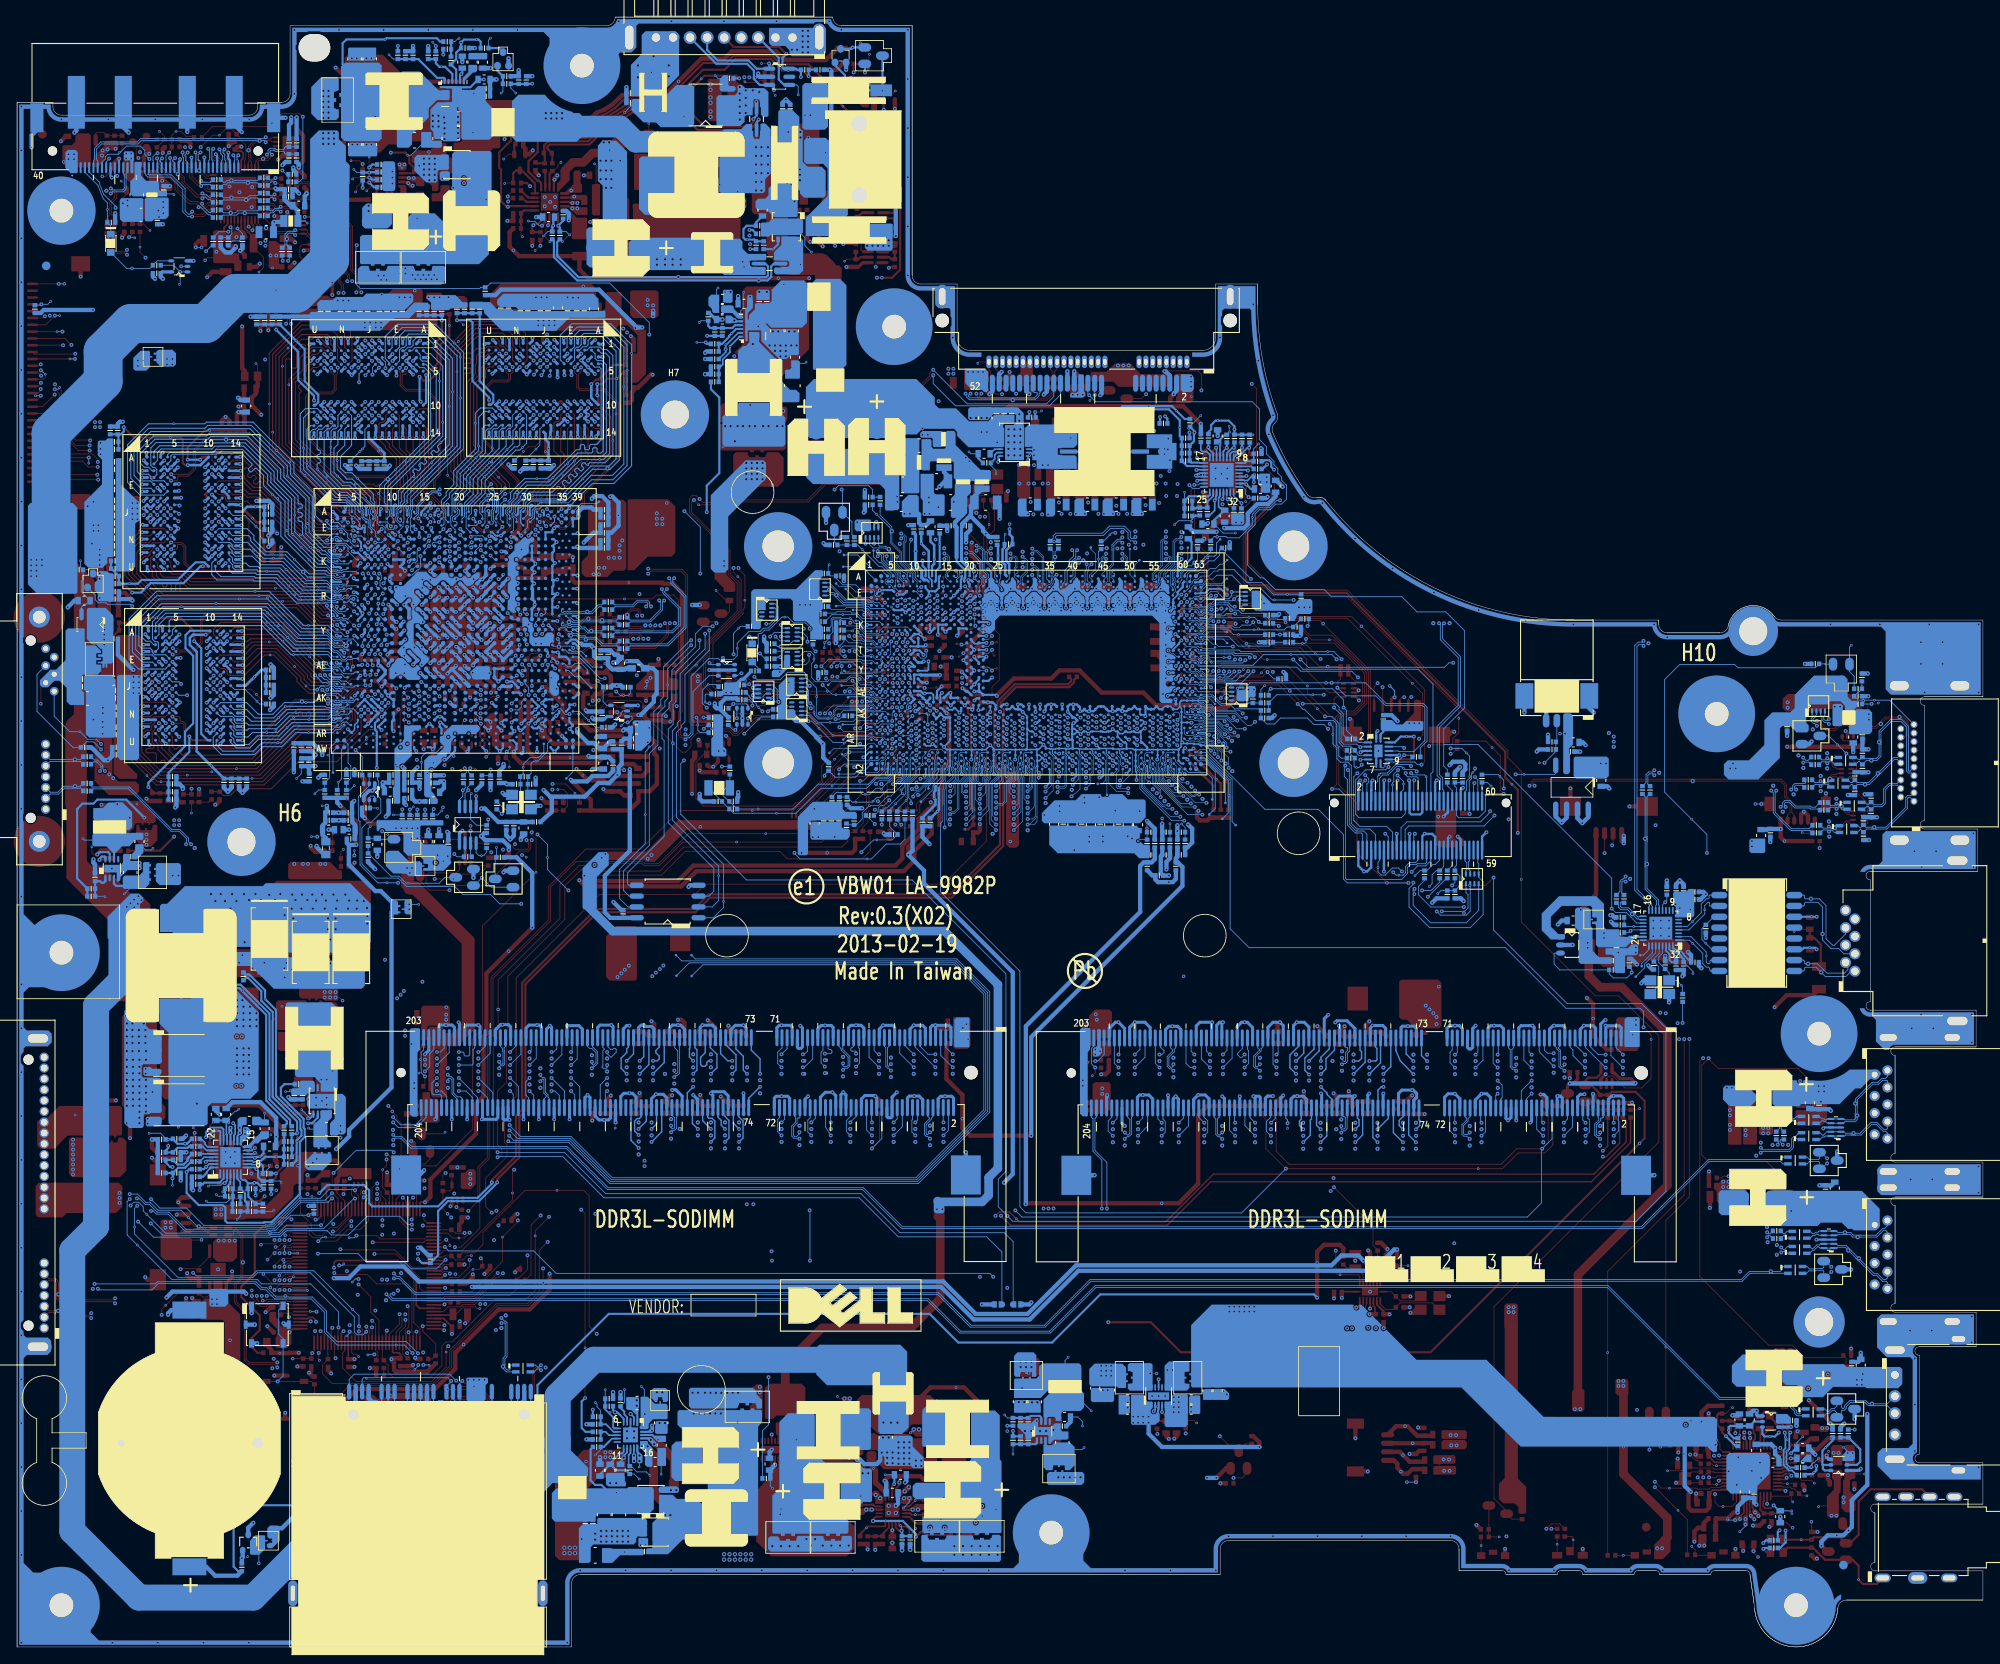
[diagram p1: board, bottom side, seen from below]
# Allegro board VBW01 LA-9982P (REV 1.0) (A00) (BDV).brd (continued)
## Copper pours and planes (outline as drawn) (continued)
GND on IN3 (solid shape): 12.35,56.06 12.35,53.41 11.91,52.98 10.49,52.98 10.4,53 10.3,53 0.3,53 0.27,53.02 0.25,53.05 0.25,56.55 0.27,56.58 0.3,56.6 11.81,56.6
GND on IN3 (solid shape): 217.77,75.58 217.77,61.99 216.69,60.91 215.93,60.91 215.74,61.1 215.74,62.11 215.55,62.3 215.23,62.3 215.04,62.49 215.04,66.62 215.17,66.75 215.61,66.75 215.8,66.94 215.8,68.34 215.61,68.53 214.85,68.53 214.4,68.97 214.4,76.34 214.66,76.59 216.75,76.59
GND on IN3 (solid shape): 11.78,95.26 11.78,92.15 12.22,91.7 13.2,91.7 13.92,91.48 14.38,90.88 13.81,90.88 13.54,91.11 13.2,91.19 0.9,91.19 0.87,91.21 0.85,91.24 0.85,95.6 0.87,95.63 0.9,95.65 11.39,95.65
GND on IN3 (solid shape): 14.43,74.88 13.99,74.17 13.2,73.9 12.92,73.9 12.54,73.52 12.54,71 11.55,70.02 11.04,70.02 10.77,70.44 10.3,70.6 1.1,70.6 1.07,70.62 1.05,70.65 1.05,74.36 1.07,74.39 1.1,74.41 13.2,74.41 13.62,74.54 13.9,74.88
GND on IN3 (solid shape): outline of 85 points within 112.42,139.33 118.87,144.79
GND on IN3 (solid shape): 12.41,38.49 12.41,35.13 11.27,33.98 8.52,33.98 8.48,33.94 8.36,33.81 8.23,33.69 8.23,23.82 8.74,23.32 11.78,23.32 12.35,22.74 12.35,21.22 10.76,19.63 0.25,19.63 0.25,21.3 0.27,21.33 0.3,21.35 7.47,21.35 8.21,21.95 7.76,22.8 7.73,22.82 7.72,22.85 7.72,33.96 7.73,33.98 7.76,34 8.21,34.85 7.47,35.45 1.1,35.45 1.07,35.47 1.05,35.5 1.05,38.95 1.07,38.98 1.1,39 11.91,39
GND on IN3 (solid shape): outline of 142 points within 137.57,147.84 146.71,159.27
GND on IN3 (solid shape): outline of 90 points within 0.25,111.65 92.68,159.55
GND on IN3 (solid shape): outline of 241 points within 16.62,0.25 230.15,190.85
GND on IN3 (solid shape): outline of 1027 points within 145.13,164.98 163.29,177.05
GND on TOP: 113.76,144.79 116.81,141.74 116.81,138.89 116.36,138.44 114.27,138.44 113.38,139.33 112.74,139.33 112.36,139.71 112.36,141.23 112.04,141.55 110.65,141.55 110.58,141.62 110.58,144.03 110.71,144.16 111.92,144.16 112.55,144.79
GND on GND1: outline of 167 points within 0.25,0.25 230.15,190.85 ; 3 cut-outs
GND on VCC: 14.92,90.88 14.29,91.84 13.2,92.21 1.87,92.21 1.87,94.63 6.85,94.63 8.48,95.71 8.12,97.63 8.12,109.67 8.48,111.59 6.85,112.67 1.27,112.67 1.27,119.13 21.49,119.13 21.49,90.88
GND on VCC: 45.41,55.64 42.32,58.73 42.32,62.11 40.75,63.68 40.75,65.5 40.73,65.52 40.73,81.95 47.25,88.47 48.71,88.47 56.12,95.87 56.12,97.97 58.37,100.23 59.97,100.23 60.73,100.99 61.38,100.99 64.14,103.71 70.85,103.71 71.49,103.07 74.31,103.07 79.01,107.77 84.08,107.77 86.05,109.74 88,109.74 88.13,109.61 111.64,109.61 112.28,110.25 116.57,110.25 117.27,109.55 125.02,109.55 126.16,108.41 132.96,108.41 140.2,101.17 171.29,101.23 171.29,90.12 171.29,90.01 183.86,77.44 183.86,71.72 184.18,71.41 184.18,66.98 183.86,66.66 183.86,59.36 180.14,55.64
GND on VCC: 1.27,19.63 1.27,20.33 7.47,20.33 9.1,21.41 8.74,23.33 8.74,33.47 9.1,35.39 7.47,36.47 2.07,36.47 2.07,37.98 10.3,37.98 11.93,39.06 11.57,40.98 11.57,51.02 11.93,52.94 10.3,54.02 1.27,54.02 1.27,55.58 10.3,55.58 11.93,56.66 11.57,58.58 11.57,68.62 11.93,70.54 10.3,71.62 2.07,71.62 2.07,73.39 13.2,73.39 14.35,73.81 14.95,74.88 16.71,74.88 18.55,76.72 20.54,76.72 20.54,26.34 19.42,25.22 13.58,25.22 12.54,24.18 12.54,21.26 10.91,19.63
GND on IN2: 215.93,60.91 215.58,61.26 215.58,62.11 215.42,62.27 215.22,62.27 215.21,62.27 215.1,62.29 214.99,62.27 214.99,62.27 212.98,62.27 211.8,63.45 209.78,63.45 209.7,63.49 209.69,63.58 209.32,64.08 208.96,63.58 208.95,63.49 208.87,63.45 201.96,63.45 200.63,64.78 200.63,78.08 201.69,79.14 217.02,79.14 218.21,77.95 218.21,61.92 217.2,60.91 ; 1 cut-out
GND on GND2: outline of 167 points within 0.25,0.25 230.15,190.85 ; 3 cut-outs
GNDA on GND1, GND2: 21.88,0.25 17.25,4.58 16.85,5.41 16,5.75 0.25,5.75 0.25,8.67 12.66,8.67 13.4,9.29 12.91,10.13 12.91,15.54 13.4,16.38 12.66,17 0.25,17 0.25,19.12 11.12,19.12 13.05,21.05 13.05,23.97 13.79,24.71 19.63,24.71 20.84,25.92 21.91,25.92 23.76,27.76 31.02,27.76 31.02,23.51 29.58,23.51 29.26,23.19 24.75,23.19 24.54,22.98 24.54,19.74 24.5,19.7 20.43,19.7 19.97,19.23 19.97,17.24 20.43,16.77 24.96,16.77 25.37,17.18 25.37,18.11 26.06,18.11 26.06,16.37 25.17,15.48 25.17,13.49 26.09,12.58 27.1,12.58 27.33,12.35 27.33,9.07 27.13,8.81 27.05,8.5 26.6,5.25 26.55,4.91 26.52,4.57
GNDA on VCC: 21.88,1.27 18.27,4.65 17.55,6.16 16,6.77 1.27,6.77 1.27,7.65 12.66,7.65 14.29,8.73 13.93,10.65 13.93,15.02 14.29,16.94 12.66,18.02 1.27,18.02 1.27,19.12 11.12,19.12 13.05,21.05 13.05,23.97 13.79,24.71 19.63,24.71 20.84,25.92 21.91,25.92 23.76,27.76 31.02,27.76 31.02,23.51 29.58,23.51 29.26,23.19 24.75,23.19 24.54,22.98 24.54,19.74 24.5,19.7 20.43,19.7 19.97,19.23 19.97,17.24 20.43,16.77 24.96,16.77 25.37,17.18 25.37,18.13 25.41,18.17 26.06,18.17 26.06,16.37 25.17,15.48 25.17,13.49 26.09,12.58 27.1,12.58 27.33,12.35 27.33,10.19 26.43,9.6 26.03,8.6 25.59,5.39 25.54,5.02 25.51,4.64
VCC on TOP (solid shape): 166.72,168.48 166.72,168.35 166.65,168.29 166.21,168.29 165.38,167.46 165.38,165.17 165.26,165.05 163.73,165.05 163.6,165.17 163.6,167.52 163.67,167.59 164.81,167.59 165.83,168.6 166.59,168.6
VIN on BOTTOM (solid shape): 142.33,171.02 142.33,170.19 142.71,169.81 143.54,169.81 143.86,169.49 143.86,168.73 143.6,168.48 142.52,168.48 141.7,167.65 139.09,167.65 138.9,167.84 138.9,170.64 139.79,171.52 141.82,171.52
VIN on TOP: 139.64,170.89 139.64,168.58 139.22,168.16 137.44,168.16 136.81,168.79 136.81,170.57 136.36,171.02 134.9,171.02 133.95,170.06 133.95,168.81 133.44,168.3 131.73,168.3 131.65,168.39 131.65,168.84 131.75,168.94 132.66,168.94 133.07,169.35 133.07,173.97 132.24,174.81 130.52,174.81 130.43,174.9 130.43,176.81 130.15,177.09 129.52,177.09 129.47,177.15 129.47,177.77 129.51,177.82 130.65,177.82 132.23,176.23 132.74,176.23 134.33,174.65 134.33,174.13 137.38,171.08 139.45,171.08
+CHGRTC on BOTTOM (solid shape): 203.1,12.46 203.1,10.93 202.97,10.81 202.02,10.81 201.32,11.5 201.32,13.03 201.39,13.09 202.47,13.09
+CPU_CORE on BOTTOM (solid shape): outline of 1962 points within 94.62,110.67 117.56,123.71
+CPU_CORE on IN1 (solid shape): outline of 295 points within 95.02,113.36 115.85,121.75
+CPU_CORE on IN1 (solid shape): outline of 535 points within 94.01,135.46 111.47,143.01
+CPU_CORE on TOP: outline of 146 points within 93.43,110.82 116.08,142.82
+CPU_CORE on BOTTOM: 100.41,131.84 99.91,131.34 99.71,131.14 99.42,131.14 99.34,131.15 99.25,131.14 95.98,131.14 94.14,132.98 94.14,137.87 94.58,138.31 94.58,142.31 95.09,142.82 99.66,142.82 100.04,142.44 100.04,140.85 99.85,140.66 97.56,140.66 97.44,140.54 97.44,139.84 97.63,139.65 105.25,139.65 105.76,139.14 105.76,138.19 106.14,137.81 109.31,137.81 109.38,137.87 109.38,138.12 109.41,138.2 109.49,138.22 109.63,138.22 109.75,138.26 109.88,138.4 109.92,138.59 109.92,138.64 109.9,138.69 109.92,138.78 110,138.82 111.28,138.82 111.47,138.63 111.47,138.25 111.66,138.06 113.38,138.06 113.88,137.55 113.88,131.96 113.06,131.14 103.25,131.14 102.46,131.93 100.51,131.93 100.42,131.84
+CPU_CORE on VCC: 88.36,110.12 88.36,111.6 89.12,112.36 89.12,114.86 88.93,115.05 88.93,133.83 89.5,134.4 89.5,135.1 94.26,139.86 94.26,141.83 95.38,142.95 112.95,142.95 116.42,139.48 116.42,110.75 112.06,110.75 111.43,110.12
+CPU_CORE on IN2: outline of 107 points within 90.52,111.39 115.99,143.33
+CPU_CORE on IN3: outline of 115 points within 90.52,111.39 115.99,143.33
+DIMM1_VREF_DQ on TOP (solid shape): 42.99,73.57 42.99,69.87 42.89,69.77 42.41,69.77 42.32,69.87 40.61,69.87 40.36,70.12 40.36,73.67 40.52,73.83 42.74,73.83
+DIMM1_VREF_DQ on BOTTOM (solid shape): 42,73.58 42,70.41 41.94,70.34 40.29,70.34 40.22,70.41 40.22,73.71 40.35,73.84 41.75,73.84
+DIMM2_VREF_DQ on TOP (solid shape): 120.71,73.77 120.71,70.4 120.42,70.11 119.03,70.11 118.65,70.5 118.65,73.67 118.84,73.86 120.62,73.86
+DIMM2_VREF_DQ on BOTTOM (solid shape): 120.55,73.54 120.55,70.37 120.49,70.31 118.84,70.31 118.77,70.37 118.77,73.67 118.9,73.8 120.3,73.8
+DPAB_VDD10 on TOP (solid shape): 169.27,108.32 169.27,106.74 168.93,106.4 168.55,106.4 168.34,106.61 168.34,108.43 168.51,108.59 169,108.59
+DPAB_VDD18 on TOP (solid shape): 175.47,108.91 175.47,107.43 174.75,106.72 174.75,105.73 174.47,105.45 172.8,105.45 172.62,105.27 172.62,105.03 172.62,104.97 172.62,104.88 172.43,104.68 171.98,104.68 171.86,104.81 171.86,105.46 172.57,106.17 173.68,106.17 173.9,106.4 173.9,106.94 173.69,107.14 173.53,107.14 173.31,107.36 173.31,107.64 173.58,107.91 173.87,107.91 174.23,108.27 174.23,109.46 174.28,109.51 174.86,109.51
+DPCD_VDD10 on BOTTOM (solid shape): outline of 159 points within 183.05,98.87 186.36,108.08
+DPCD_VDD18 on BOTTOM (solid shape): outline of 246 points within 176.17,98.83 182.69,108.11
+DPEF_VDD10 on IN1 (solid shape): 169.37,110.9 169.37,110.11 169.3,109.89 169.37,109.67 169.37,109.31 169.09,109.03 168.43,109.03 167.97,109.5 167.97,110.81 168.27,111.12 169.15,111.12
+DPEF_VDD18 on BOTTOM (solid shape): 168.03,114.31 168.03,112 167.54,111.51 167.12,111.51 166.89,111.73 166.89,112.51 167.08,112.69 167.08,112.71 167.09,112.72 167.14,112.9 167.08,113.07 167.08,113.2 166.86,113.41 166.86,113.92 167.24,114.29 167.46,114.29 167.52,114.36 167.58,114.4 167.63,114.45 167.65,114.46 167.67,114.46 167.87,114.46
+FAN_POWER on BOTTOM (solid shape): 49.2,109.31 49.2,102.51 49.01,102.33 48.62,102.33 48.4,102.55 48.4,104.67 48.5,104.77 48.5,105.35 48.03,105.81 48.03,109.19 48.32,109.47 49.03,109.47
+INV_PWR_SRC on TOP (solid shape): 223.57,177.16 223.57,176.49 223.99,176.07 224.97,176.07 225.1,175.94 225.1,173.93 224.83,173.67 223.49,173.67 223.29,173.47 221.92,173.47 221.75,173.64 221.75,177.24 221.97,177.47 223.26,177.47
+INV_PWR_SRC on BOTTOM (solid shape): 224.76,175.21 224.76,173.43 224.12,172.79 223.42,172.79 223.29,172.92 223.29,175.27 223.55,175.52 224.44,175.52
+LAN_IO on TOP (solid shape): outline of 182 points within 34.29,79.75 45.12,84.08
+LAN_IO on BOTTOM (solid shape): 51.72,85.99 51.72,84.02 50.64,82.94 49.11,82.94 48.99,83.07 48.99,83.51 49.05,83.58 49.75,83.58 50.64,84.47 50.64,85.61 49.37,86.88 45.98,86.88 45.8,86.7 45.8,85.54 45.3,85.54 45.29,85.55 45.26,85.52 45.26,85.08 45.3,85.04 45.81,85.04 45.82,85.02 45.82,84.78 45.79,84.76 45.49,84.76 45.37,84.63 45.37,82.31 45.11,82.05 41.88,82.05 40.8,83.13 39.46,83.13 39.4,83.2 39.4,83.32 39.46,83.39 41.49,83.39 41.62,83.26 42.45,83.26 42.64,83.45 42.64,84.08 42.7,84.15 44.16,84.15 44.42,84.41 44.42,87.13 45.3,88.02 49.69,88.02
+LAN_VDD on BOTTOM (solid shape): 34.78,88.55 36.15,88.55 36.3,88.4 36.3,87.05 36,86.75 36,85.94 36.12,85.82 36.12,85.64 36.01,85.53 34.05,85.53 33.83,85.75 33.83,88.8 33.91,88.88 34.46,88.88
+LAN_VDD on IN2 (solid shape): 36.29,87.13 36.29,85.99 36.16,85.86 35.46,85.86 35.27,86.05 35.27,87.01 35.53,87.26 36.16,87.26
+LAN_VDD on IN2 (solid shape): 36.35,81.86 36.35,80.85 36.16,80.66 35.72,80.66 35.27,81.1 35.27,81.93 35.46,82.12 36.1,82.12
+LCDVDD on TOP (solid shape): 215.99,169.43 215.99,167.52 215.9,167.43 212.91,167.43 212.69,167.65 212.69,169.56 212.88,169.75 215.67,169.75
+LCDVDD on BOTTOM (solid shape): 215.42,169.81 215.42,167.27 215.29,167.14 214.6,167.14 214.34,167.4 213.01,167.4 212.63,167.78 212.63,169.81 212.75,169.94 215.29,169.94
+LCDVDD_CONN on BOTTOM (solid shape): 216.63,174 216.63,172.35 217.14,171.84 217.14,170.38 216.82,170.06 212.88,170.06 212.82,170.13 212.82,170.64 212.88,170.7 213.58,170.7 213.77,170.89 213.77,171.71 213.96,171.9 215.27,171.9 215.36,172 215.88,172.52 215.88,173.45 215.86,173.58 215.8,173.7 215.8,174.06 215.87,174.13 216.5,174.13
+PCIE_VDDR on TOP (solid shape): 156.63,114.31 156.63,114.01 157.86,112.78 157.86,112.31 157.72,112.17 153.1,112.17 152.91,112.36 152.91,113.36 153.11,113.57 153.75,113.57 153.98,113.8 153.98,114.44 154.04,114.51 156.43,114.51
+PCIE_VDDR on BOTTOM (solid shape): 171.19,120.67 171.19,119.65 171.15,119.61 171.11,119.59 171.08,119.6 170.61,119.58 170.52,119.11 170.53,119.09 170.31,118.86 170.37,118.54 170.37,117.76 170.34,117.72 170.32,117.68 169.97,117.33 168.04,117.33 167.96,117.37 167.94,117.45 167.83,117.72 167.53,117.74 167.52,117.73 167.49,117.74 167.46,117.77 167.46,117.97 167.53,118.18 167.46,118.39 167.46,118.68 167.73,118.95 168.26,118.95 168.5,118.71 168.5,118.69 168.72,118.43 169.05,118.45 169.28,118.45 169.42,118.37 169.59,118.35 169.97,118.57 169.86,119.01 169.85,119.03 169.84,119.05 169.84,119.46 169.85,119.48 169.86,119.5 169.98,119.72 169.93,119.97 169.92,119.98 169.93,120.02 170.01,120.09 170.02,120.11 170.04,120.11 170.33,120.22 170.44,120.51 170.63,120.72 170.79,120.72 170.92,120.77 170.93,120.78 171.08,120.78
+PCIE_VDDR on IN2 (solid shape): outline of 524 points within 155.07,112.96 170.72,121.55
+RTCVCC on BOTTOM (solid shape): 138.9,97.32 138.9,92.97 138.75,92.82 137.89,92.82 137.7,93.01 137.7,96.53 137.32,96.91 133.76,96.91 133.57,97.1 131.98,97.1 131.98,97.74 132.17,97.93 133.32,97.93 133.63,98.25 133.63,98.98 133.76,99.1 137.12,99.1
+SWR_V12 on TOP (solid shape): 200.92,164.81 200.92,161.76 200.69,161.53 199.16,161.53 199.08,161.62 199.08,162.09 199.1,162.11 199.56,162.11 199.71,162.27 199.71,162.81 199.55,162.97 198.35,162.97 198.24,163.07 198.24,164 198.25,164.03 198.25,164.35 198.39,164.49 199.69,164.49 200.04,164.84 200.88,164.84
+SWR_V12 on IN1: 202.9,166.52 203.23,166.17 203.26,166.15 203.27,166.11 203.27,163.59 202.41,162.72 199.8,162.72 199.71,162.81 199.71,165.67 200.68,166.64 200.68,167.23 199.92,167.99 199.92,169.99 199.97,170.08 200.07,170.08 200.55,170.21 200.45,170.68 200.4,170.75 200.42,170.82 200.41,171.22 200.05,171.37 199.96,171.39 199.92,171.46 199.92,173.87 200.63,174.57 202.72,174.57 203.1,174.95 203.1,175.69 203.55,176.14 204.24,176.14 204.98,175.4 205.01,175.3 204.94,175.23 204.88,175.2 204.83,175.17 204.76,175.14 204.7,175.17 204.12,174.89 204.7,174.62 204.76,174.64 204.83,174.62 205.19,174.56 205.41,174.85 205.44,174.89 205.48,174.89 205.5,174.88 206.33,174.05 206.33,170.96 203.27,167.91 203.27,166.93 203.26,166.89 203.23,166.87
+VCHGR on TOP (solid shape): 147.16,183.72 147.16,179.08 146.84,178.76 145.76,178.76 143.09,181.43 143.09,182.38 143.48,182.76 145.06,182.76 145.57,183.27 145.76,183.27 146.33,183.84 147.03,183.84
+VCHGR on BOTTOM (solid shape): 145.95,182.95 145.95,182.26 146.27,181.94 148.17,181.94 148.43,181.68 148.43,178.45 148.3,178.32 145.63,178.32 145.13,178.83 145.13,179.46 145,179.59 144.24,179.59 144.17,179.65 144.17,181.3 143.98,181.49 143.54,181.49 143.22,181.18 143.22,179.65 142.97,179.4 142.46,179.4 142.33,179.53 142.33,182.32 142.74,182.73 145.03,182.73 145.44,183.14 145.76,183.14
+VCHGR on IN1 (solid shape): 147.16,183.72 147.16,179.08 146.84,178.76 145.76,178.76 143.09,181.43 143.09,182.38 143.48,182.76 145.06,182.76 145.57,183.27 145.76,183.27 146.33,183.84 147.03,183.84
+VCHGR on IN2 (solid shape): 147.16,183.72 147.16,179.08 146.84,178.76 145.76,178.76 143.09,181.43 143.09,182.38 143.48,182.76 145.06,182.76 145.57,183.27 145.76,183.27 146.33,183.84 147.03,183.84
+VCHGR on IN3 (solid shape): 147.16,183.72 147.16,179.08 146.84,178.76 145.76,178.76 143.09,181.43 143.09,182.38 143.48,182.76 145.06,182.76 145.57,183.27 145.76,183.27 146.33,183.84 147.03,183.84
+VDISPLAY_VCC on BOTTOM (solid shape): 15.71,109.1 15.71,107.14 15.59,107.01 13.3,107.01 12.98,107.33 12.98,109.57 13.34,109.93 14.89,109.93
+VDISPLAY_VCC on IN3 (solid shape): 13.62,109.48 13.62,107.89 12.97,107.24 9.39,107.24 9.17,107.45 9.17,108.98 9.87,109.68 13.43,109.68
+VGA_CORE on TOP (solid shape): 163.48,133.29 163.48,128.03 164.24,127.26 164.24,125.87 163.83,125.45 161.22,125.45 160.49,126.18 159.28,126.18 159,126.46 159,134.15 159.35,134.5 162.27,134.5
+VGA_CORE on TOP (solid shape): 200.78,89.08 207.93,89.08 208.67,88.34 208.69,88.34 208.69,83.01 207.86,82.18 195.48,82.18 194.4,81.1 189.77,81.1 188.94,81.93 188.94,88.82 189.96,89.83 200.02,89.83
+VGA_CORE on TOP (solid shape): outline of 1073 points within 171.87,112.12 183.13,124.72
+VGA_CORE on BOTTOM (solid shape): 201.59,89.21 210.74,89.21 212.82,87.13 213.41,87.13 213.66,86.89 213.66,83.83 212.25,83.83 210.5,82.08 199.16,82.08 198.47,81.4 190.17,81.4 188.94,82.62 188.94,87.13 191.35,89.55 201.26,89.55
+VGA_CORE on IN1 (solid shape): outline of 3192 points within 158.28,111.89 183.65,131.51
+VGA_CORE on IN2 (solid shape): outline of 11361 points within 174.72,82.02 210.86,125.74
+VGA_CORE on IN3 (solid shape): 201.26,89.23 209.77,89.23 211.1,87.89 211.1,82.75 210.16,81.81 190.09,81.81 189,82.89 189,88.21 191.23,90.43 200.05,90.43
+VGA_CORE on IN3 (solid shape): outline of 1021 points within 172.62,113.01 183.77,124.39
+VGA_CORE on VCC: 184.16,77.86 171.8,90.22 171.86,121.93 171.92,121.99 181.72,121.99 182.08,121.63 182.08,113.06 183.31,111.83 185.85,111.83 189,108.68 189,104.87 193.22,100.66 209.83,100.66 209.83,84.06 203.63,77.86
+VGA_PCIE on TOP (solid shape): 197.35,78.18 197.35,76.3 197.07,76.02 194.59,76.02 194.34,75.77 192.88,75.77 192.75,75.89 192.75,78.4 192.94,78.59 196.94,78.59
+VGA_PCIE on BOTTOM (solid shape): outline of 123 points within 169.81,121.28 172.91,130.12
+VGA_PCIE on IN2 (solid shape): outline of 3371 points within 169.83,75 195.16,129.04
+VGA_PCIE on IN3 (solid shape): outline of 373 points within 161.86,121.05 172.2,125.11
+VGA_PCIEP on TOP (solid shape): 194.97,75.32 195.04,75.26 196.43,75.26 196.5,75.32 196.5,75.75 196.56,75.82 199.8,75.82 200.06,75.55 200.06,72.6 199.8,72.34 193.07,72.34 192.85,72.56 192.85,75.36 193.07,75.58 194.48,75.58 194.72,75.82 194.97,75.82
+VGA_PCIEP on BOTTOM (solid shape): 198.91,75.39 198.91,73.1 198.91,73.1 198.91,72.46 198.78,72.34 193.2,72.34 193.01,72.53 193.01,75.07 193.51,75.58 198.72,75.58
ADPIN on TOP (solid shape): 140.55,177.96 140.55,176.98 140.05,176.47 140.05,171.33 139.92,171.21 137.43,171.21 136.36,172.28 136.36,178.06 136.93,178.64 139.88,178.64
ADPIN on BOTTOM (solid shape): 141.19,180.03 141.19,174.25 141.19,174.25 141.19,173.24 138.64,170.7 138.64,170.39 138.19,169.94 135.87,169.94 135.62,170.19 135.62,173.07 136.11,173.56 137.76,173.56 138.33,174.13 138.33,177.75 138.71,178.13 138.71,179.4 139.6,180.29 140.94,180.29
B+ on TOP (solid shape): 136.87,161.36 136.87,156.79 136.55,156.47 134.33,156.47 133.76,157.05 133.76,161.68 134.08,162 136.24,162
B+ on TOP (solid shape): 176.24,180.92 176.24,179.08 175.99,178.83 166.34,178.83 165.95,179.21 165.95,180.03 166.14,180.22 166.97,180.22 168.11,181.37 175.8,181.37
B+ on TOP (solid shape): 229.07,128.92 229.07,125.04 228.82,124.79 225.39,124.79 224.82,125.36 224.82,128.92 225.07,129.17 228.82,129.17
B+ on TOP (solid shape): 146.52,176.86 146.52,172.67 144.3,170.44 144.3,168.29 143.98,167.97 140.62,167.97 140.17,168.41 140.17,176.41 140.94,177.18 146.21,177.18
B+ on TOP (solid shape): 219.97,176.55 220.11,176.55 220.24,176.42 220.24,175.92 221.33,174.83 221.33,173.56 221.26,173.49 220.95,173.49 220.14,174.3 220.14,174.86 219.53,175.47 218.69,175.47 218.53,175.64 218.53,176.45 218.69,176.6 219.91,176.6
B+ on TOP (solid shape): 224.63,100.53 224.63,90.12 219.58,85.07 219.58,76.03 219.26,75.7 215.95,75.7 215.63,76.03 215.63,80.13 214.77,80.99 214.77,87.09 215.9,88.21 216.94,88.21 220.37,91.64 221.71,91.64 222.22,92.15 222.22,100.5 222.75,101.04 224.12,101.04
B+ on BOTTOM (solid shape): 136.74,35.06 136.74,31.95 135.47,30.68 126.14,30.68 126.08,30.74 126.08,34.63 126.88,35.44 136.37,35.44
B+ on BOTTOM (solid shape): 137.13,160.03 137.13,149.87 137,149.74 133.76,149.74 133.19,150.32 133.19,159.65 133.95,160.41 136.74,160.41
B+ on BOTTOM (solid shape): 196.05,176.79 196.05,171.14 195.74,170.83 192.18,170.83 191.42,171.59 191.42,173.75 191.86,174.19 191.86,175.97 192.69,176.79 192.69,177.62 192.88,177.81 195.04,177.81
B+ on BOTTOM (solid shape): 229.13,133.81 229.13,124.59 228.02,123.47 223.49,123.47 223.32,123.64 223.32,133.58 223.87,134.12 228.82,134.12
B+ on BOTTOM (solid shape): 219.8,85.61 219.8,83.13 219.1,82.43 217.2,82.43 216.48,83.15 216.48,85.56 215.99,86.05 215.99,87.07 215.61,87.45 215.61,87.83 216.12,88.34 217.07,88.34
B+ on BOTTOM (solid shape): 168.59,24.55 168.59,22.65 170.91,20.33 170.91,19.63 169.57,18.3 168.56,18.3 167.64,19.22 164.34,19.22 163.48,20.08 163.48,21.03 165.51,23.06 165.51,24.65 165.83,24.97 168.18,24.97
B+ on BOTTOM (solid shape): 143.28,178.51 143.28,176.99 143.48,176.79 143.92,176.79 144.24,177.11 144.24,178.57 144.94,178.57 145.57,177.94 147.54,177.94 148.05,177.43 148.05,170.64 147.86,170.44 142.97,170.44 142.71,170.7 142.71,172.1 142.08,172.73 142.08,178 142.71,178.64 143.16,178.64
B+ on BOTTOM (solid shape): 172.4,181.24 172.4,177.02 171.86,176.48 164.81,176.48 164.11,177.18 164.11,179.46 164.49,179.84 165.19,179.84 165.36,180.01 165.38,180.01 167.13,180.73 168.54,182 171.64,182
B+ on IN1 (solid shape): 144.33,176.64 144.33,170.48 143.73,169.87 141.32,169.87 140.68,170.51 140.68,176.48 141.38,177.18 143.79,177.18
B+ on IN1 (solid shape): 219.05,88.9 219.05,87.77 216.83,85.55 216.63,85.55 214.65,87.52 214.65,87.9 216.91,90.16 217.8,90.16
B+ on IN1 (solid shape): 228.95,128.98 228.95,125.42 227.89,124.37 225.81,124.37 224.82,125.36 224.82,125.37 224.22,125.98 224.22,126.36 227.02,129.17 228.76,129.17
B+ on IN1 (solid shape): outline of 443 points within 166.11,174.27 220.88,183.69
B+ on IN2 (solid shape): 144.33,176.64 144.33,170.48 143.73,169.87 141.32,169.87 140.68,170.51 140.68,176.48 141.38,177.18 143.79,177.18
B+ on IN3 (solid shape): 146.21,177.11 146.21,172.67 144.05,170.51 142.84,170.51 142.08,171.27 142.08,176.99 142.84,177.75 145.57,177.75
B+ on IN3 (solid shape): 168.88,179.84 168.88,178.26 168.3,177.68 163.6,177.68 163.03,178.26 163.03,179.97 163.48,180.41 168.3,180.41
B+_1.05V on BOTTOM (solid shape): 141.96,159.14 141.96,157.8 142.21,157.55 143.8,157.55 143.93,157.42 143.93,156.83 144.61,156.15 144.61,155.23 142.55,155.23 142.01,154.7 138.4,154.7 137.82,155.27 137.82,159.9 138.14,160.22 140.87,160.22
B+_VDDCI on BOTTOM (solid shape): 176.81,182.57 178.59,182.57 178.65,182.51 178.65,180.22 178.34,179.91 178.34,176.86 178.21,176.73 175.03,176.73 174.72,177.05 174.72,180.48 175.48,181.24 175.48,182.89 175.61,183.02 176.37,183.02
BATT+ on BOTTOM (solid shape): 154.4,181.87 156.75,181.87 157.13,181.49 158.21,181.49 158.4,181.3 158.4,180.16 157,178.76 155.54,178.76 154.97,178.19 151.41,178.19 151.03,178.57 151.03,182.89 151.29,183.14 153.13,183.14
BATT++ on TOP (solid shape): 157.19,188.99 157.19,186.76 157.92,186.03 157.92,183.87 157.79,183.75 153.98,183.75 152.81,184.92 152.81,188.99 153.25,189.43 156.75,189.43
BATT++ on BOTTOM (solid shape): 157.19,188.99 157.19,186.76 158.46,185.49 158.46,181.87 158.4,181.81 157.32,181.81 156.49,182.64 154.4,182.64 152.81,184.22 152.81,188.99 153.25,189.43 156.75,189.43
BATT++ on IN1 (solid shape): 157.19,188.99 157.19,186.76 157.92,186.03 157.92,183.87 157.79,183.75 153.98,183.75 152.81,184.92 152.81,188.99 153.25,189.43 156.75,189.43
BATT++ on IN2 (solid shape): 157.19,188.99 157.19,186.76 157.92,186.03 157.92,183.87 157.79,183.75 153.98,183.75 152.81,184.92 152.81,188.99 153.25,189.43 156.75,189.43
BATT++ on IN3 (solid shape): 157.19,188.99 157.19,186.76 157.92,186.03 157.92,183.87 157.79,183.75 153.98,183.75 152.81,184.92 152.81,188.99 153.25,189.43 156.75,189.43
BOOT_1.35V on BOTTOM (solid shape): 157.38,24.9 157.38,24.79 157.32,24.72 155.99,24.72 155.29,24.03 154.4,24.03 154.33,24.1 154.33,24.72 154.4,24.79 155.67,24.79 155.86,24.98 157.31,24.98
BST on TOP (solid shape): 165.64,170.06 166.72,170.06 166.78,170 166.78,169.87 166.72,169.81 165.57,169.81 165.45,169.68 164.43,169.68 164.3,169.56 164.3,169.11 164.24,169.05 163.6,169.05 163.54,169.11 163.54,170.06 163.73,170.25 165.45,170.25
BST_1.05V on BOTTOM (solid shape): 147.9,157.14 147.9,156.54 147.76,156.4 146.59,156.4 146.21,156.02 146.21,156.01 145.96,155.76 145.41,155.76 145.34,155.83 145.34,156.31 145.44,156.42 145.91,156.42 146.4,156.91 146.4,157.16 146.53,157.29 147.74,157.29
BST_1.35V on BOTTOM (solid shape): 155.36,23.26 155.36,21.29 155.29,21.22 154.4,21.22 154.34,21.28 154.34,23.26 154.4,23.33 155.29,23.33
BST_+1.2VSP on TOP (solid shape): 185.7,171.33 185.7,171.21 185.48,170.98 185.48,168.76 185.39,168.67 184.81,168.67 184.75,168.73 184.75,171.21 184.94,171.4 185.64,171.4
BST_CHGA on TOP (solid shape): 163.03,171.4 163.03,168.03 162.84,167.84 162.14,167.84 162.08,167.9 162.08,171.46 162.14,171.52 162.91,171.52
BST_VDDCI on BOTTOM (solid shape): 177.51,185.43 177.51,184.61 178.15,183.97 178.15,183.27 178.08,183.21 177.96,183.21 177.89,183.27 177.89,183.72 177,184.61 176.69,184.61 176.5,184.8 176.5,185.43 176.56,185.49 177.45,185.49
BST_VGA_CORE on BOTTOM (solid shape): 201.9,60.34 201.9,60.27 203.32,58.84 203.77,58.84 203.93,58.68 203.93,58.56 203.86,58.49 202.97,58.49 202.88,58.59 202.88,58.72 202.56,59.03 202.18,59.03 201.7,59.51 201.13,59.51 200.88,59.76 200.88,60.4 200.94,60.46 201.77,60.46
CHG_B+ on TOP (solid shape): 158.21,169.11 158.21,162 157.64,161.43 147.34,161.43 145.61,163.16 145.61,167.62 145.89,167.9 156.68,167.9 157.25,168.48 157.25,168.92 157.57,169.24 158.08,169.24
CHG_B+ on BOTTOM (solid shape): 158.72,164.67 158.72,162.38 157.76,161.43 149.44,161.43 148.81,162.06 148.81,164.86 149.19,165.24 158.14,165.24
DH_1.35V on TOP (solid shape): 154.02,19.52 154.02,18.31 153.83,18.12 153.07,18.12 152.82,18.37 152.82,19.71 152.94,19.84 153.71,19.84
DH_1.35V on TOP (solid shape): 156.37,24.34 156.37,24.09 155.17,22.88 154.85,22.88 154.34,23.39 154.34,23.65 155.23,24.53 156.18,24.53
DH_1.35V on BOTTOM (solid shape): 155.23,18.63 155.23,18.25 155.04,18.06 153.01,18.06 152.82,18.25 152.82,18.57 153.07,18.82 155.04,18.82
DH_1.35V on BOTTOM (solid shape): 156.61,24.6 157.32,24.6 157.39,24.53 157.39,24.39 157.34,24.34 156.56,24.34 155.99,23.77 155.99,23.65 155.86,23.52 155.61,23.52 155.48,23.65 155.48,23.96 156.12,24.6 156.6,24.6
DH_CHG on TOP (solid shape): 146.36,169.68 146.36,168.86 146.11,168.6 145.16,168.6 144.9,168.86 144.9,169.81 145.09,170 146.05,170
DH_CHG on TOP (solid shape): 152.62,169.75 152.62,168.79 152.49,168.67 151.48,168.67 151.29,168.86 151.29,169.81 151.41,169.94 152.43,169.94
DH_CHG on TOP (solid shape): 166.78,169.43 166.78,169.37 166.72,169.3 165.76,169.3 165.57,169.11 164.56,169.11 164.49,169.17 164.49,169.49 164.56,169.56 166.65,169.56
DH_CHG on IN1 (solid shape): 147.01,169.55 147.01,168.72 146.95,168.66 145.04,168.66 144.92,168.79 144.92,169.55 145.11,169.74 146.82,169.74
DH_CHG on IN1 (solid shape): 153.13,169.68 153.13,168.86 152.94,168.67 150.27,168.67 150.08,168.86 150.08,169.62 150.33,169.87 152.94,169.87
DH_CHG on IN1 (solid shape): 164.49,169.68 165.26,169.68 165.51,169.43 165.51,169.17 165.38,169.05 163.67,169.05 163.35,169.37 163.35,170 163.48,170.13 164.05,170.13
DL_1.35V on BOTTOM (solid shape): 157.58,12.72 157.58,11.83 157.45,11.71 156.56,11.71 156.44,11.83 156.44,12.66 156.56,12.79 157.52,12.79
DL_1.35V on BOTTOM (solid shape): 157.83,23.7 157.83,22.76 157.71,22.63 157.71,21.61 157.63,21.54 157.22,21.54 157.09,21.66 157.09,22.46 157.58,22.95 157.58,23.7 157.64,23.76 157.77,23.76
DL_1.35V on IN3 (solid shape): 157.58,12.98 157.58,11.77 157.48,11.67 156.53,11.67 156.44,11.77 156.44,13.04 156.63,13.23 157.32,13.23
DL_1.35V on IN3 (solid shape): 157.71,22.57 157.71,21.61 158.02,21.3 158.02,19.71 157.9,19.58 157.2,19.58 156.94,19.84 156.94,21.36 157.2,21.61 157.2,22.5 157.39,22.69 157.58,22.69
DL_CHG on TOP (solid shape): 161.83,175.52 161.83,174.89 161.57,174.64 160.18,174.64 159.99,174.45 159.16,174.45 158.97,174.64 158.97,175.46 159.16,175.65 161.7,175.65
DL_CHG on TOP (solid shape): 166.72,173.24 166.72,171.97 167.1,171.59 167.1,170.7 167.03,170.64 166.91,170.64 166.84,170.7 166.84,170.76 165.64,171.97 165.64,173.18 165.95,173.49 166.46,173.49
EN_PCIE on BOTTOM (solid shape): 197.23,66.3 197.23,65.75 197.48,65.5 198.16,65.5 198.26,65.4 198.26,64.76 198.17,64.67 196.55,64.67 196.16,65.07 195.57,65.07 195.51,65.13 195.51,66.23 195.67,66.39 197.15,66.39
GPU_B+ on TOP (solid shape): 214.26,79.73 214.26,74.86 213.64,74.24 213.64,64.78 213.07,64.21 207.62,64.21 207.62,64.22 207.35,64.22 207.27,64.3 207.27,76.05 211.2,79.98 214.02,79.98
INT-SPK-L+ on TOP (solid shape): 63.47,25.28 63.47,24.52 63.34,24.39 60.61,24.39 60.48,24.52 60.48,25.22 60.67,25.41 63.34,25.41
INT-SPK-L+ on TOP (solid shape): 27.08,16.01 27.08,15.82 26.38,15.12 26.19,15.12 26.06,15.25 26.06,15.63 26.64,16.2 26.89,16.2
INT-SPK-L+ on IN1 (solid shape): 62.7,25.03 62.7,24.39 62.45,24.14 60.42,24.14 60.23,24.33 60.23,25.16 60.29,25.22 62.51,25.22
INT-SPK-L+ on IN1 (solid shape): 27.97,17.54 27.97,16.65 26.44,15.12 26.25,15.12 26.06,15.31 26.06,15.63 26.83,16.39 26.83,16.44 26.84,16.45 26.92,16.69 26.83,16.92 26.83,17.28 27.14,17.6 27.91,17.6
INT-SPK-L- on TOP (solid shape): 63.47,24.08 63.47,23.25 63.4,23.19 60.73,23.19 60.48,23.44 60.48,24.01 60.73,24.27 63.27,24.27
INT-SPK-L- on TOP (solid shape): 27.45,15.96 27.45,15.3 26.89,14.74 26.7,14.74 26.57,14.87 26.57,15.11 26.61,15.16 26.94,15.5 26.97,15.52 27.14,15.7 27.14,15.71 27.21,15.77 27.21,15.95 27.27,16.01 27.4,16.01
INT-SPK-L- on IN1 (solid shape): 62.64,23.82 62.64,23.12 62.51,23 60.67,23 60.48,23.19 60.48,23.82 60.67,24.01 62.45,24.01
INT-SPK-L- on IN1 (solid shape): 29.49,16.77 29.49,16.2 29.21,15.92 29.13,15.89 29.05,15.94 28.7,16.11 28.41,15.86 28.4,15.82 28.35,15.82 27.88,15.35 27.86,15.35 27.58,15.25 27.48,14.97 27.48,14.95 27.14,14.62 26.76,14.62 26.57,14.81 26.57,15.06 28.67,17.15 29.11,17.15
INT-SPK-R+ on TOP (solid shape): 64.42,22.36 64.42,21.54 64.35,21.47 62,21.47 61.81,21.66 61.81,22.3 62,22.49 64.29,22.49
INT-SPK-R+ on IN1 (solid shape): 30.25,15.12 30.25,14.36 30.06,14.17 28.86,14.17 28.29,14.74 28.29,15.25 28.35,15.31 30.06,15.31
INT-SPK-R+ on IN1 (solid shape): 63.53,22.17 63.53,21.54 63.34,21.35 59.85,21.35 59.72,21.47 59.72,22.24 59.91,22.43 63.27,22.43
INT-SPK-R- on TOP (solid shape): 64.42,21.09 64.42,20.27 64.35,20.2 61.88,20.2 61.75,20.33 61.75,21.09 61.88,21.22 64.29,21.22
INT-SPK-R- on IN1 (solid shape): 63.53,21.16 63.53,20.33 63.4,20.2 59.91,20.2 59.72,20.39 59.72,20.97 59.97,21.22 63.47,21.22
INT-SPK-R- on IN1 (solid shape): 28.13,15.09 28.13,15.06 28.12,14.95 28.15,14.85 28.16,14.84 28.16,14.62 28.73,14.04 28.73,13.54 28.67,13.47 27.84,13.47 27.52,13.79 27.52,14.82 27.9,15.19 28.03,15.19
LDO_3V on BOTTOM (solid shape): 147.35,155.2 146.69,155.2 146.64,155.25 146.01,155.25 145.96,155.3 145.39,155.3 145.34,155.35 145.34,155.5 145.39,155.55 146,155.55 146.21,155.77 146.38,155.77 146.69,156.09 147.35,156.09
LG_3V on TOP (solid shape): 130.84,22.71 130.84,21.73 130.58,21.47 129.89,21.47 129.7,21.66 129.7,22.71 129.89,22.9 130.65,22.9
LG_3V on TOP (solid shape): 130,19.37 130,19.07 129.65,18.72 129.64,18.72 128.74,17.82 128.74,17.19 128.68,17.12 128.62,17.12 128.55,17.19 128.55,18.48 129.57,19.5 129.87,19.5
LG_5V on TOP (solid shape): 125.57,25.57 125.57,25.19 125.06,24.68 124.3,24.68 124.17,24.81 124.17,25 124.43,25.25 124.43,25.57 124.62,25.76 125.38,25.76
LG_5V on TOP (solid shape): 126.01,19.04 126.03,19.04 126.05,19.02 126.09,18.98 126.15,18.95 126.93,18.18 126.94,18.19 127.04,18.19 127.16,18.07 127.16,17.25 127.03,17.12 126.97,17.12 126.9,17.19 126.9,17.57 126.51,17.96 126.18,17.96 125.63,18.51 125.63,18.94 125.73,19.04
LG_5V on IN3 (solid shape): 126.63,18.39 126.63,17.99 126.49,17.85 126.2,17.85 124.99,19.06 124.99,19.27 125.37,19.65
LG_5V on IN3 (solid shape): 125.7,25.57 125.7,24.7 125.02,24.02 124.37,24.02 124.11,24.28 124.11,25.63 124.23,25.76 125.5,25.76
LG_+1.2VSP on BOTTOM (solid shape): 180.88,172.79 180.88,172.1 180.69,171.91 179.8,171.91 179.67,172.03 179.67,172.86 179.8,172.98 180.69,172.98
LG_+1.2VSP on IN3 (solid shape): 180.81,172.98 180.81,172.03 180.69,171.91 179.92,171.91 179.73,172.1 179.73,172.92 179.86,173.05 180.75,173.05
LG_+1.2VSP on IN3 (solid shape): 185.83,174.32 185.83,173.68 185.7,173.56 184.81,173.56 184.69,173.68 184.69,174.7 184.81,174.83 185.32,174.83
LX_1.05V on BOTTOM (solid shape): 147.67,159.01 147.67,157.74 147.55,157.61 146.66,157.61 146.53,157.74 146.53,159.01 146.66,159.13 147.55,159.13
LX_1.05V on BOTTOM (solid shape): 144.59,152.94 144.99,152.53 145.32,152.53 145.89,151.96 145.89,148.02 145.39,147.51 142.32,147.51 140.74,145.93 138.85,145.93 138.72,146.06 138.72,147.02 139.09,147.39 139.79,147.39 141.07,148.67 141.07,150.62 143.42,152.97 143.42,154.17 144.59,154.17
LX_1.5VSP on BOTTOM (solid shape): 110.12,29 110.12,26.97 109.99,26.84 109.99,26.08 109.93,26.01 109.8,26.01 109.74,26.08 109.74,26.78 109.55,26.97 108.85,26.97 108.66,26.78 108.66,26.52 108.02,26.52 108.02,27.41 107.77,27.66 105.77,27.66 105.35,28.08 105.35,29.76 105.61,30.01 109.1,30.01
LX_1.8VSP on BOTTOM (solid shape): 221.58,95.2 221.58,94.05 221.39,93.86 219.93,93.86 219.17,93.1 219.17,92.09 219.04,91.96 218.98,91.96 218.91,92.02 218.91,93.04 218.09,93.86 217.26,93.86 216.5,94.63 215.67,94.63 215.61,94.69 215.61,95.39 215.67,95.45 221.33,95.45
LX_3V on TOP (solid shape): 135.79,27.89 135.79,23.63 135.47,23.32 134.14,23.32 133.63,22.81 133.63,22.58 133.51,22.46 131.41,22.46 131.22,22.65 131.22,24.9 131.54,25.22 132.11,25.22 132.62,25.73 132.62,27.95 132.81,28.14 135.54,28.14
LX_3V on TOP (solid shape): 131.16,16.23 131.66,16.23 131.85,16.04 131.85,15.53 131.79,15.47 131.22,15.47 130.84,15.85 130.01,15.85 129.82,16.04 128.87,16.04 128.81,16.11 128.81,16.17 128.87,16.23 130.01,16.23 130.14,16.36 131.03,16.36
LX_3V on BOTTOM (solid shape): 135.79,27.73 135.79,23.47 135.41,23.09 130.52,23.09 130.33,23.28 130.33,27.73 130.58,27.98 135.54,27.98
LX_3V on IN1 (solid shape): 134.97,24.14 134.97,22.93 134.78,22.74 134.14,22.74 133.95,22.93 133.95,24.14 134.01,24.2 134.9,24.2
LX_3V on IN1 (solid shape): 131.92,16.71 131.92,16.42 131.35,15.85 130.14,15.85 130.01,15.98 130.01,16.33 130.36,16.68 131.09,16.68 131.38,16.97 131.66,16.97
LX_5V on TOP (solid shape): 125.66,16.2 126.58,16.2 126.65,16.14 126.65,16.03 126.58,15.96 125.55,15.96 125.44,15.85 124.65,15.85 124.43,16.08 123.89,16.08 123.77,16.2 123.77,16.69 123.85,16.77 125.09,16.77
LX_5V on TOP (solid shape): 122.27,28.74 122.27,27.25 122.2,27.19 120.78,27.19 120.49,26.9 120.49,25.88 120.68,25.69 121.95,25.69 122.54,25.11 123.58,25.11 123.66,25.03 123.66,22.65 123.47,22.46 121.25,22.46 121.12,22.58 121.12,23.09 120.87,23.34 119.22,23.34 119.03,23.54 119.03,28.62 119.35,28.93 122.08,28.93
LX_5V on BOTTOM (solid shape): outline of 85 points within 119.2,23.47 124.3,28.36
LX_5V on IN1 (solid shape): 125.7,16.61 125.7,15.79 125.5,15.6 123.41,15.6 123.16,15.85 123.16,16.74 123.28,16.87 125.44,16.87
LX_5V on IN1 (solid shape): 120.49,24.08 120.49,23.76 120.3,23.57 120.3,22.93 119.54,22.93 119.54,23.57 119.35,23.76 119.35,24.08 119.47,24.2 120.36,24.2
LX_CHG on TOP (solid shape): 166.78,168.98 166.78,168.86 166.72,168.79 165.76,168.79 164.87,167.9 163.6,167.9 163.54,167.97 163.54,168.73 163.6,168.79 164.56,168.79 164.68,168.92 165.57,168.92 165.7,169.05 166.72,169.05
LX_CHG on TOP (solid shape): 154.44,176.75 154.44,175.61 154.98,175.07 158.05,175.07 158.08,175.03 158.08,170.89 158.02,170.83 156.87,170.83 156.43,170.38 156.43,168.86 156.24,168.67 154.33,168.67 154.14,168.48 154.14,168.16 154.02,168.03 153.25,168.03 153.06,168.22 153.06,169.87 152.62,170.32 151.22,170.32 150.84,169.94 150.84,168.79 150.62,168.57 147.06,168.57 146.89,168.74 146.89,170.87 148.9,172.89 149.35,172.89 153.32,176.86 154.33,176.86
LX_CHG on BOTTOM (solid shape): 157.51,174.45 157.51,168.6 156.81,167.9 153.06,167.9 152.75,168.22 152.75,169.75 152.3,170.19 149.06,170.19 148.75,170.51 148.75,172.98 150.52,174.76 157.19,174.76
LX_CHG on IN1 (solid shape): 155.67,168.73 155.67,168.03 155.48,167.84 153.25,167.84 153.06,168.03 153.06,168.54 153.38,168.86 155.54,168.86
LX_CHG on IN1 (solid shape): 165.51,168.79 165.51,168.41 164.94,167.84 163.48,167.84 163.29,168.03 163.29,168.67 163.48,168.86 164.56,168.86 164.62,168.92 165.38,168.92
LX_PCIE on TOP (solid shape): 197.77,69.42 197.77,67.89 197.6,67.72 195.72,67.72 195.41,67.42 195.41,64.94 195.27,64.79 193.09,64.79 193.09,64.79 192.77,65.11 192.77,69.45 192.91,69.59 197.6,69.59
LX_PCIE on BOTTOM (solid shape): 197.85,69.83 197.85,67.06 197.6,66.81 195.53,66.81 194.81,66.08 194.81,65.19 194.72,65.11 193.08,65.11 192.84,65.35 192.84,69.88 193.24,70.29 197.39,70.29
LX_VDDCI on BOTTOM (solid shape): 185.89,184.1 185.89,175.91 185.77,175.78 184.5,175.78 184.12,176.16 184.12,177.37 182.16,179.32 182.16,180.4 181.19,181.37 179.86,181.37 179.73,181.49 179.73,182.45 179.8,182.51 181,182.51 183.23,184.73 185.26,184.73
MIC_IN on TOP (solid shape): 16.16,23.63 16.16,21.28 16.09,21.22 15.08,21.22 15.01,21.28 15.01,23.44 15.27,23.7 16.09,23.7
MIC_IN on TOP (solid shape): 27.52,25.28 27.52,24.46 27.4,24.33 27.4,23.19 27.33,23.12 27.21,23.12 27.14,23.19 27.14,24.27 27.02,24.39 27.02,24.65 27.14,24.78 27.14,25.22 27.27,25.35 27.46,25.35
MIC_IN on BOTTOM (solid shape): 16.48,22.49 16.48,21.85 16.41,21.79 15.27,21.79 15.01,22.05 15.01,22.87 15.08,22.93 16.03,22.93
MIC_IN on IN1 (solid shape): 16.03,24.14 16.03,22.68 15.9,22.55 15.14,22.55 15.01,22.68 15.01,24.08 15.21,24.27 15.9,24.27
MIC_IN on IN1 (solid shape): 27.52,25.22 27.52,24.46 27.33,24.27 26.06,24.27 25.94,24.39 25.94,25.22 26.13,25.41 27.33,25.41
MIC_IN_R on TOP (solid shape): 16.22,20.71 16.22,19.7 16.4,19.51 16.4,17.86 16.59,17.67 16.59,16.26 16.12,15.78 15.19,15.78 14.95,16.01 14.95,17.66 15.59,18.3 15.59,19.51 15.4,19.7 15.08,19.7 14.95,19.82 14.95,20.71 15.08,20.84 16.09,20.84
MIC_IN_R on IN3 (solid shape): 16.73,17.66 16.73,16.9 16.54,16.71 15.14,16.71 14.89,16.97 14.89,17.6 15.14,17.85 16.54,17.85
PCIE_B+ on BOTTOM (solid shape): 194.85,62.81 194.85,61.99 195.67,61.16 195.67,58.68 195.56,58.57 193.69,58.57 193.58,58.68 193.58,59.07 194.02,59.51 194.02,61.54 193.51,62.05 193.51,62.88 193.58,62.94 194.72,62.94
PSID on BOTTOM (solid shape): 138.38,183.06 138.38,178.15 138.11,177.89 135.72,177.89 135.36,178.24 135.36,183.19 135.53,183.36 138.08,183.36
REGN on TOP (solid shape): 165.19,172.92 165.19,171.52 166.14,170.57 166.65,170.57 166.78,170.44 166.78,170.38 166.65,170.25 165.76,170.25 165.51,170.51 164.3,170.51 164.18,170.64 164.18,171.46 164.37,171.65 164.37,173.05 164.43,173.11 165,173.11
RING2 on TOP (solid shape): 17.81,23.44 17.81,21.47 17.62,21.28 16.54,21.28 16.48,21.35 16.48,23.57 16.6,23.7 17.55,23.7
RING2 on TOP (solid shape): 28.22,25.28 28.22,24.39 28.16,24.33 28.03,24.33 27.84,24.14 27.84,23.19 27.78,23.12 27.65,23.12 27.59,23.19 27.59,24.2 27.78,24.39 27.78,25.28 27.84,25.35 28.16,25.35
RING2 on IN3 (solid shape): 17.68,23.76 17.68,22.62 17.55,22.49 16.86,22.49 16.6,22.74 16.6,23.82 16.79,24.01 17.43,24.01
RING2 on IN3 (solid shape): 28.29,26.24 28.29,24.33 28.16,24.2 27.84,24.2 27.71,24.33 27.71,25.35 27.59,25.47 26.89,25.47 26.83,25.54 26.83,26.17 27.08,26.43 28.1,26.43
RING2_R on TOP (solid shape): 17.68,20.71 17.68,19.77 17.48,19.57 17.48,18.43 18.28,17.64 18.28,15.4 18.04,15.16 17.06,15.16 16.89,15.34 16.89,17.95 16.66,18.17 16.66,19.7 16.54,19.82 16.54,20.71 16.6,20.78 17.61,20.78
RING2_R on IN3 (solid shape): 18.08,15.46 18.08,13.94 17.88,13.75 17.06,13.75 16.81,14 16.81,15.4 17.12,15.71 17.82,15.71
SNB_1.05V on BOTTOM (solid shape): 183.04,177.56 183.04,175.84 182.97,175.78 180.75,175.78 180.62,175.91 180.62,176.54 180.69,176.6 181.7,176.6 181.83,176.73 181.83,177.56 181.89,177.62 182.97,177.62
SNB_1.05V_17607668 on BOTTOM (solid shape): 139.67,149.99 139.93,149.74 140.37,149.74 140.37,148.72 138.72,148.72 138.65,148.79 138.65,150.68 138.78,150.81 139.67,150.81
SNUB_PCIE on TOP (solid shape): 197.96,66.74 197.96,64.81 197.85,64.7 196.86,64.7 196.78,64.79 196.78,65.5 196.71,65.57 195.96,65.57 195.75,65.77 195.75,66.83 195.87,66.96 197.74,66.96
SW_1.35V on TOP (solid shape): 154.66,16.85 154.66,15.64 154.72,15.58 154.72,15.33 154.59,15.2 153.77,15.2 153.58,15.39 153.58,16.79 153.77,16.98 154.53,16.98
SW_1.35V on TOP (solid shape): 157.39,23.65 157.39,23.39 156.37,22.38 156.05,22.38 155.74,22.69 155.74,23.14 156.44,23.84 157.2,23.84
SW_1.35V on BOTTOM (solid shape): 157.39,24.08 157.39,23.39 156.82,22.82 156.82,21.36 156.56,21.11 156.05,21.11 155.93,21.23 155.93,23.33 156.47,23.87 156.47,24.06 156.56,24.15 157.32,24.15
SW_1.35V on BOTTOM (solid shape): 155.16,17.73 155.16,15.32 155.93,14.55 155.93,11.69 156.05,11.57 156.56,11.57 156.68,11.44 156.68,10.93 156.62,10.87 154.1,10.87 152.37,12.6 150.34,12.6 149.96,12.98 149.96,16.6 150.72,17.36 153.07,17.36 153.5,17.79 153.51,17.79 153.57,17.85 155.03,17.85
SW_+1.2VSP on TOP (solid shape): 176.88,172.73 176.88,171.46 177.07,171.27 177.59,171.27 178.2,171.27 179.42,171.27 179.48,171.21 179.48,170.37 179.38,170.27 179.09,170.27 178.84,170.03 178.84,167.82 178.68,167.65 175.67,167.65 175.1,168.22 175.1,172.67 175.23,172.79 176.81,172.79
SW_+1.2VSP on TOP (solid shape): 185.7,172.35 185.7,172.22 185.64,172.16 184.81,172.16 184.69,172.03 184.44,172.03 184.38,171.97 184.37,171.97 184.12,171.72 183.87,171.72 183.8,171.71 183.67,171.59 183.67,171.4 183.54,171.27 182.72,171.27 182.65,171.33 182.65,171.91 183.16,172.41 185.64,172.41
SW_+1.2VSP on BOTTOM (solid shape): 179.42,175.02 179.42,168.03 179.1,167.71 175.16,167.71 174.78,168.1 174.78,172.22 177.66,172.22 177.67,172.16 177.68,172.11 177.7,172.06 177.73,172.02 177.77,171.96 177.77,171.93 177.77,171.9 177.73,171.84 177.7,171.8 177.68,171.75 177.67,171.7 177.66,171.64 177.67,171.59 177.68,171.54 177.7,171.49 177.72,171.44 177.76,171.4 177.8,171.36 177.84,171.33 177.89,171.31 177.94,171.29 177.99,171.28 178.05,171.28 178.1,171.29 178.15,171.31 178.2,171.33 178.24,171.36 178.28,171.4 178.32,171.44 178.34,171.49 178.36,171.54 178.37,171.59 178.38,171.64 178.37,171.7 178.36,171.75 178.34,171.8 178.31,171.84 178.27,171.9 178.27,171.93 178.27,171.96 178.31,172.02 178.34,172.06 178.36,172.11 178.37,172.16 178.38,172.22 178.37,172.27 178.36,172.32 178.34,172.37 178.32,172.42 178.28,172.46 178.24,172.5 178.2,172.53 178.15,172.55 178.1,172.57 178.05,172.58 177.99,172.58 177.94,172.57 177.89,172.55 177.84,172.53 177.8,172.5 177.76,172.46 177.72,172.42 177.7,172.37 177.68,172.32 177.67,172.27 177.66,172.22 174.78,172.22 174.78,175.21 174.97,175.4 179.04,175.4
SW_+1.2VSP on IN1 (solid shape): 179.73,171.02 180.56,171.02 180.69,170.89 180.69,170.44 180.5,170.25 179.23,170.25 179.04,170.44 179.04,171.14 179.23,171.33 179.42,171.33
SW_+1.2VSP on IN1 (solid shape): 184.75,172.35 184.75,172.1 184.63,171.97 184.6,171.98 184.53,171.98 184.45,171.97 184.13,171.97 183.99,171.97 183.35,171.33 182.91,171.33 182.78,171.46 182.78,171.84 183.42,172.48 184.62,172.48
SW_CPU2 on BOTTOM (solid shape): 112.23,142.95 112.23,140.79 112.17,140.73 110.96,140.73 110.65,140.41 110.65,139.2 110.46,139.01 109.38,139.01 109.19,138.82 109.19,138.19 109.12,138.12 106.26,138.12 106.2,138.19 106.2,139.52 106.39,139.71 108.3,139.71 108.42,139.84 108.42,140.54 108.36,140.6 106.52,140.6 106.14,140.98 106.14,142.82 106.65,143.33 111.85,143.33
SW_VGA_CORE on TOP (solid shape): 206.66,76.97 206.66,76.12 206.4,75.87 206.4,72.76 206.11,72.46 203.48,72.46 203.17,72.15 203.17,70.69 203.42,70.43 206.08,70.43 206.47,70.05 206.47,66.94 206.46,66.94 206.46,66.74 206.25,66.53 203.32,66.53 202.09,67.77 202.09,77.16 202.25,77.32 206.31,77.32
SW_VGA_CORE on BOTTOM (solid shape): 204.56,61.86 204.56,60.8 204.49,60.58 204.56,60.36 204.56,60.08 204.69,59.95 204.69,58.88 204.63,58.81 204.56,58.81 204.44,58.94 204.44,59.88 204.44,59.89 204.24,60.08 204.18,60.08 204.05,60.21 204.05,60.9 204.05,61.03 203.86,61.22 203.55,61.22 203.48,61.29 203.48,62.05 203.55,62.11 204.31,62.11
SW_VGA_CORE on BOTTOM (solid shape): outline of 156 points within 202.09,61.16 213.72,76.99
SW_VGA_CORE on IN1 (solid shape): 205.45,62.75 205.45,62.43 204.63,61.61 204.63,60.21 204.44,60.02 204.12,60.02 204.05,60.08 204.05,62.69 204.31,62.94 205.26,62.94
SW_VGA_CORE on IN1 (solid shape): 206.85,77.04 206.85,75.89 206.28,75.32 206.28,66.94 206.02,66.69 203.36,66.69 202.97,67.07 202.97,70.31 203.1,70.43 205.2,70.43 205.39,70.62 205.39,72.08 205.07,72.4 202.34,72.4 202.09,72.65 202.09,76.46 203.1,77.48 206.4,77.48
SW_VGA_CORE on IN2 (solid shape): 206.85,77.04 206.85,75.89 206.28,75.32 206.28,66.94 206.02,66.69 203.23,66.69 202.97,66.94 202.97,70.24 203.17,70.43 205.2,70.43 205.39,70.62 205.39,72.08 205.07,72.4 202.28,72.4 202.09,72.59 202.09,76.46 203.1,77.48 206.4,77.48
SW_VGA_CORE on IN3 (solid shape): 206.85,77.04 206.85,75.89 206.28,75.32 206.28,66.94 206.02,66.69 203.17,66.69 202.85,67 202.85,70.18 203.1,70.43 205.2,70.43 205.39,70.62 205.39,72.08 205.07,72.4 202.34,72.4 202.09,72.65 202.09,76.46 203.1,77.48 206.4,77.48
UG_3V on TOP (solid shape): 133.7,29.22 133.7,28.52 133.51,28.33 132.74,28.33 132.55,28.52 132.55,29.25 132.65,29.35 133.57,29.35
UG_3V on TOP (solid shape): 130.2,18.07 130.2,17.82 129.82,17.44 129.82,16.93 129.76,16.87 128.87,16.87 128.87,16.99 128.87,17.13 128.87,17.57 129.66,18.35 129.92,18.35
UG_3V on IN1 (solid shape): 131.09,18.66 131.09,18.54 129.68,17.12 129.07,17.12 128.93,17.26 128.93,17.53 130.5,19.09 130.66,19.09
UG_3V on IN1 (solid shape): 133.66,29.25 133.66,27.86 133.47,27.66 132.84,27.66 132.59,27.92 132.59,29.25 132.71,29.38 133.54,29.38
UG_5V on TOP (solid shape): 126.77,17.44 126.77,16.9 126.65,16.77 125.89,16.77 125.44,17.22 125.44,17.54 125.62,17.71 126.5,17.71
UG_5V on TOP (solid shape): 122.33,26.87 122.33,26.05 122.11,25.82 120.74,25.82 120.62,25.95 120.62,26.84 120.74,26.96 122.24,26.96
UG_5V on IN1 (solid shape): 125.76,17.69 126.65,17.69 126.71,17.63 126.71,17.31 126.46,17.06 124.81,17.06 124.64,17.22 124.64,17.66 124.88,17.9 125.55,17.9
UG_5V on IN1 (solid shape): 121.31,26.9 121.31,26.08 121.89,25.5 121.89,25.25 121.76,25.12 121.19,25.12 120.49,25.82 120.49,26.9 120.62,27.03 121.19,27.03
UG_+1.2VSP on TOP (solid shape): 178.27,172.35 178.27,171.52 178.15,171.4 177.64,171.4 177.13,171.91 177.13,172.6 177.26,172.73 177.89,172.73
UG_+1.2VSP on TOP (solid shape): 185.77,171.84 185.77,171.71 185.64,171.59 184.88,171.59 184.37,171.08 183.99,171.08 183.8,171.27 183.8,171.46 183.92,171.59 184.18,171.59 184.46,171.87 184.48,171.87 184.57,171.87 184.65,171.9 184.66,171.91 185.7,171.91
UG_+1.2VSP on IN1 (solid shape): 178.46,172.48 178.46,170.76 178.34,170.64 177.7,170.64 177.57,170.76 177.57,172.41 177.77,172.6 178.34,172.6
UG_+1.2VSP on IN1 (solid shape): 184.75,171.78 184.75,171.02 183.8,170.06 183.54,170.06 183.26,170.35 183.26,170.92 184.18,171.84 184.69,171.84
UG_VGA_CORE on TOP (solid shape): 206.4,71.64 206.4,71.45 206.21,71.26 203.8,71.26 203.67,71.38 203.67,71.83 203.8,71.96 206.09,71.96
UG_VGA_CORE on TOP (solid shape): 206.4,65.91 206.4,65.47 206.21,65.28 204.05,65.28 203.8,65.53 203.8,65.97 203.99,66.16 206.15,66.16
UG_VGA_CORE on BOTTOM (solid shape): 203.93,60.84 203.93,60.15 204.18,59.89 204.24,59.89 204.31,59.83 204.31,58.88 204.24,58.81 204.12,58.81 204.05,58.88 204.05,59.07 203.1,60.02 203.1,60.72 203.36,60.97 203.8,60.97
UG_VGA_CORE on IN1 (solid shape): 204.94,71.77 204.94,71.13 204.69,70.88 202.85,70.88 202.47,70.5 202.47,66.88 203.04,66.3 204.75,66.3 205.01,66.05 205.01,65.22 204.82,65.03 204.18,65.03 203.86,64.72 203.86,59.98 203.78,59.9 203.1,59.9 202.78,60.21 202.78,64.34 201.39,65.73 201.39,71.38 201.96,71.96 204.75,71.96
VCIN1_PH on TOP (solid shape): 130.31,181.93 130.31,178.13 130.21,178.03 129.77,178.03 129.61,178.19 129.61,181.97 129.66,182.01 130.22,182.01
N16988653 on BOTTOM (solid shape): 215.65,91.9 215.65,90.87 216.07,90.45 217.77,90.45 218.02,90.21 218.02,89.04 217.85,88.87 215.47,88.87 214.89,89.45 214.89,92 214.92,92.03 215.52,92.03
N16988706 on BOTTOM (solid shape): 216.56,94.05 216.56,93.36 216.94,92.97 216.94,92.4 216.88,92.34 216.37,92.34 215.6,93.12 215.6,94.05 215.66,94.12 216.5,94.12
N17002625 on BOTTOM (solid shape): 177.51,186.76 177.51,186.19 177.45,186.13 175.42,186.13 175.29,186.26 175.29,186.83 175.35,186.89 177.38,186.89
N17045846 on BOTTOM (solid shape): 202.85,62.11 202.85,61.29 202.72,61.16 200.94,61.16 200.88,61.22 200.88,61.8 200.94,61.86 201.64,61.86 201.96,62.18 202.78,62.18
N17046121 on BOTTOM (solid shape): 215.29,62.05 215.29,61.16 215.17,61.03 213.71,61.03 213.45,61.29 213.45,61.99 213.64,62.18 215.17,62.18
N17046121 on BOTTOM (solid shape): 215.61,67.89 215.61,67.13 215.42,66.94 213.77,66.94 213.52,67.19 213.52,67.64 213.67,67.8 214.56,67.8 214.79,68.02 215.48,68.02
N17046121 on BOTTOM (solid shape): 205.64,60.97 205.64,60.21 205.51,60.08 205.51,58.88 205.45,58.81 205.32,58.81 205.26,58.88 205.26,60.08 205.13,60.21 205.13,60.37 205.14,60.39 205.2,60.58 205.13,60.78 205.13,60.97 205.26,61.1 205.51,61.1
N17046121 on IN3 (solid shape): 207.04,61.1 207.04,60.46 206.66,60.08 205.26,60.08 205.13,60.21 205.13,60.37 205.14,60.39 205.2,60.58 205.14,60.77 205.13,60.78 205.13,60.91 205.32,61.1 206.4,61.1 206.66,61.35 206.78,61.35
N17046121 on IN3 (solid shape): 215.55,67.96 215.55,67.07 215.42,66.94 214.79,66.94 214.72,66.88 214.72,62.43 214.98,62.18 215.29,62.18 215.36,62.11 215.36,61.22 215.23,61.1 212.56,61.1 212.18,61.48 212.18,62.05 212.44,62.3 213.13,62.3 213.45,62.62 213.45,67.77 213.71,68.02 215.48,68.02
N17608587 on BOTTOM (solid shape): 149.38,158.22 149.38,157.29 148.95,156.86 148.95,156.6 148.75,156.4 148.12,156.4 148.12,158.56 149.04,158.56
N18009264 on BOTTOM (solid shape): 148.05,164.92 148.05,161.36 147.54,160.86 142.71,160.86 142.65,160.92 142.65,161.68 142.78,161.81 144.3,161.81 144.55,162.06 144.55,162.44 144.43,162.57 142.71,162.57 142.59,162.7 142.59,163.27 142.65,163.33 144.75,163.33 145.38,163.97 145.38,164.79 145.7,165.11 147.86,165.11
N18009411 on BOTTOM (solid shape): 148.05,183.83 148.05,182.63 147.79,182.37 146.41,182.37 146.21,182.57 146.21,182.83 146.4,183.02 146.9,183.02 147.03,183.14 147.03,184.16 147.16,184.29 147.6,184.29
N18009417 on TOP (solid shape): 157,177.77 157,176.18 156.87,176.06 154.91,176.06 154.71,176.25 154.71,176.76 154.78,176.82 155.48,176.82 155.73,177.07 155.73,177.77 155.86,177.9 156.87,177.9
N18284053 on BOTTOM (solid shape): 138.15,176.66 138.15,174.13 137.91,173.89 135.94,173.89 135.41,173.36 135.41,170.13 137.95,167.59 137.95,165.56 137.81,165.41 135.33,165.41 135.03,165.71 135.03,165.9 133.03,167.9 133.03,174.35 135.63,176.95 137.87,176.95
